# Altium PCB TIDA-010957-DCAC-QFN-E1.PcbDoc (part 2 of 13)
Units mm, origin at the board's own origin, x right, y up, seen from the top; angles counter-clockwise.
Board outline 300 x 300 mm, 4 copper layers (Top Layer, Layer 1, Layer 2, Bottom Layer), stack 1.787 mm thick; 1286 components, 677 nets, 4169 pads, 3428 vias.

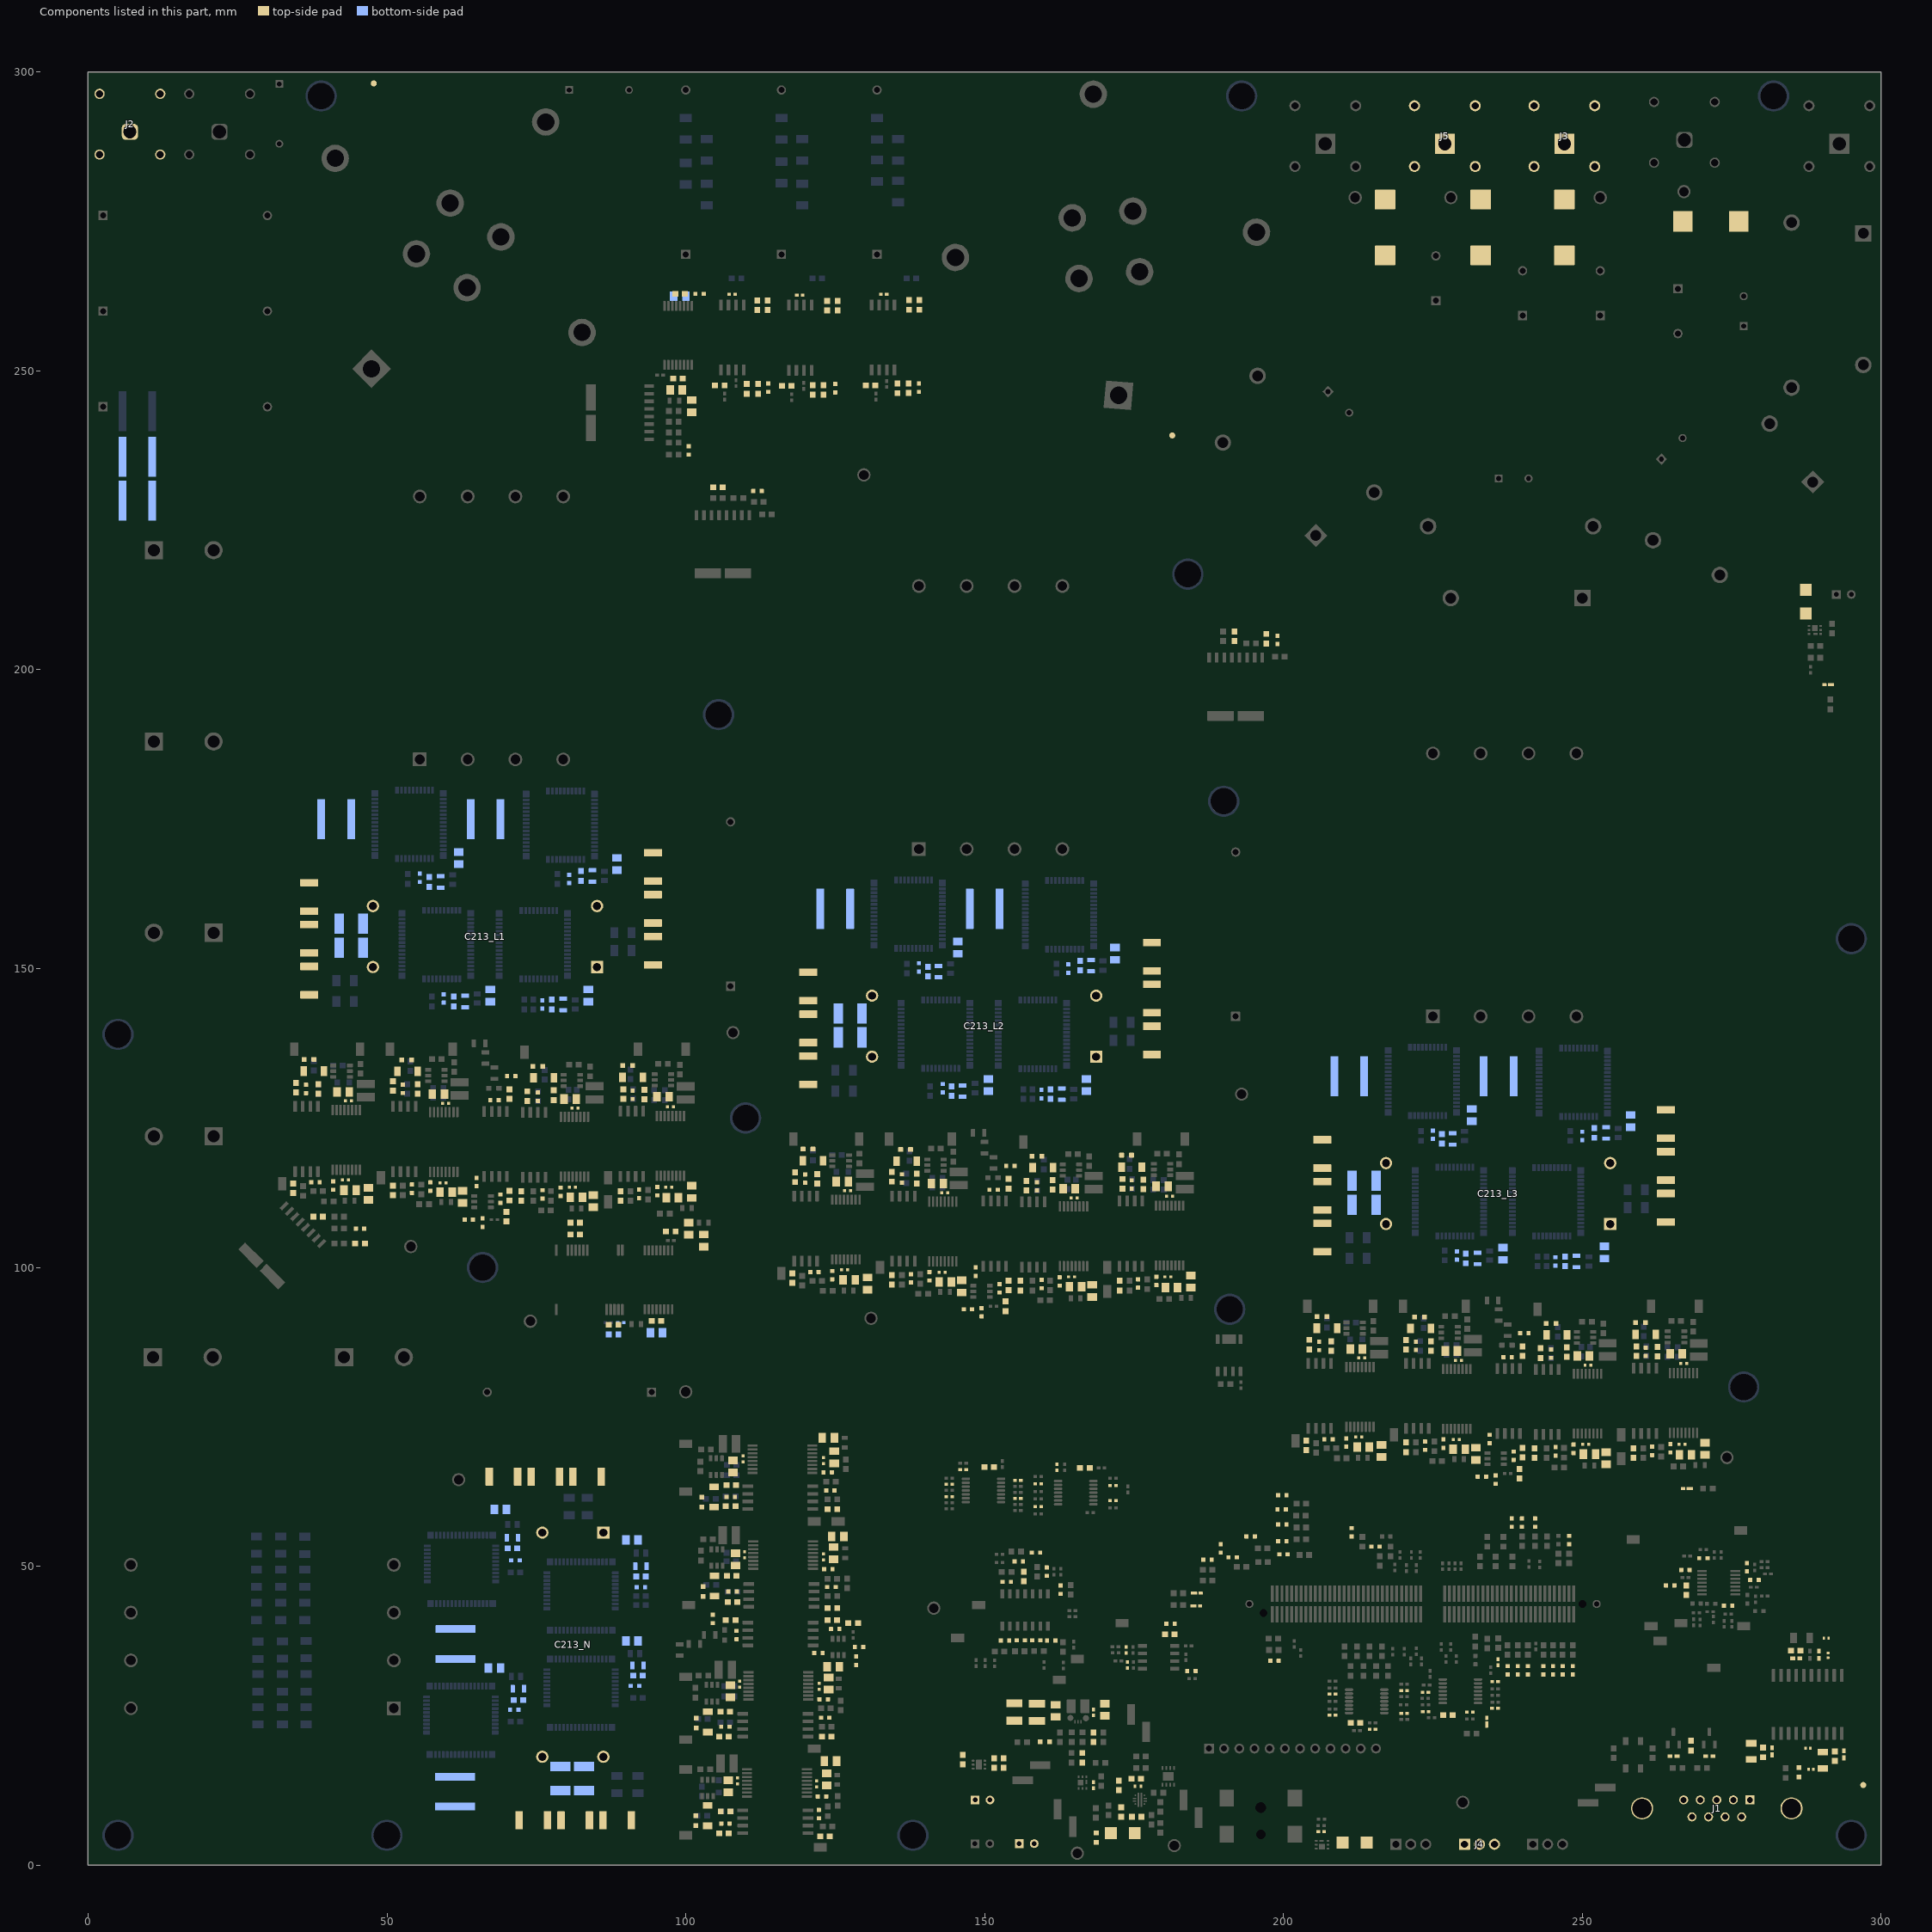
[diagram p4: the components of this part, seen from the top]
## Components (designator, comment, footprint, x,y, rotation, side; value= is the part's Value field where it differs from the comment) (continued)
C37 "CGA3E2C0G1H331J080AA" FP-CGA3E2C0G1H331J080AA_0603-MFG 240.9,32.6 r90 top value=330pF
C38 "CGA3E2C0G1H331J080AA" FP-CGA3E2C0G1H331J080AA_0603-MFG 274.389,43.409 r180 top value=330pF
C39 "CGA3E2C0G1H331J080AA" FP-CGA3E2C0G1H331J080AA_0603-MFG 215.4,53.3 r180 top value=330pF
C40 "06033C104JAT2A" 0603 105.4,230.5 r180 top value=0.1uF
C41 "CGA3E2C0G1H331J080AA" FP-CGA3E2C0G1H331J080AA_0603-MFG 278.8,47.719 r0 top value=330pF
C42 "06033C104JAT2A" 0603 197.1,205.2 r90 top value=0.1uF
C43 "CGA3E2C0G1H331J080AA" FP-CGA3E2C0G1H331J080AA_0603-MFG 247.8,54.4 r270 top value=330pF
C44 "CGA3E2C0G1H331J080AA" FP-CGA3E2C0G1H331J080AA_0603-MFG 277.537,49.85 r270 top value=330pF
C45 "CGA3E2C0G1H331J080AA" FP-CGA3E2C0G1H331J080AA_0603-MFG 211.4,55.7 r90 top value=330pF
C46 "06033C104JAT2A" 0603 191.8,205.6 r90 top value=0.1uF
C47 "06033C104JAT2A" 0603 267.4,46 r90 top value=0.1uF
C48 "CGA3E2C0G1H331J080AA" FP-CGA3E2C0G1H331J080AA_0603-MFG 267.25,49.4 r180 top value=330pF
C49 "06033C104JAT2A" 0603 45.5,104 r0 top value=0.1uF
C50 "CGA3E2C0G1H331J080AA" FP-CGA3E2C0G1H331J080AA_0603-MFG 242.1,57.3 r270 top value=330pF
C51 "CGA3E2C0G1H331J080AA" FP-CGA3E2C0G1H331J080AA_0603-MFG 270.25,51.346 r0 top value=330pF
C52 "CGA3E2C0G1H331J080AA" FP-CGA3E2C0G1H331J080AA_0603-MFG 187.3,51.1 r0 top value=330pF
C53 "06033C104JAT2A" 0603 38.5,108.5 r180 top value=0.1uF
C54 "EMK107BB7225KA-T" 0603 125.4,260.9 r270 top value=2.2uF
C55 "06033C104JAT2A" 0603 123.65,260.9 r90 top value=0.1uF
C56 "06033C104JAT2A" 0603 135.394,247.079 r90 top value=0.1uF
C57 "EMK107BB7225KA-T" 0603 137.3,247.1 r270 top value=2.2uF
C58 "CGA2B2C0G1H102J050BA" 0402L 133.12,262.85 r180 top value=1000pF
C59 "CGA3E2C0G1H331J080AA" FP-CGA3E2C0G1H331J080AA_0603-MFG 243.5,32.6 r90 top value=330pF
C60 "06033C104JAT2A" 0603 130.9,247.6 r180 top value=0.1uF
C61 "EMK107BB7225KA-T" 0603 113.7,261 r270 top value=2.2uF
C62 "06033C104JAT2A" 0603 111.95,261 r90 top value=0.1uF
C63 "06033C104JAT2A" 0603 121.221,246.802 r90 top value=0.1uF
C64 "EMK107BB7225KA-T" 0603 123.02,246.802 r270 top value=2.2uF
C65 "CGA2B2C0G1H102J050BA" 0402L 119.07,262.699 r180 top value=1000pF
C66 "CGA3E2C0G1H331J080AA" FP-CGA3E2C0G1H331J080AA_0603-MFG 238.2,57.3 r270 top value=330pF
C67 "06033C104JAT2A" 0603 116.9,247.5 r180 top value=0.1uF
C68 "EMK107BB7225KA-T" 0603 139.089,261.03 r270 top value=2.2uF
C69 "06033C104JAT2A" 0603 137.339,261.03 r90 top value=0.1uF
C70 "06033C104JAT2A" 0603 110.2,247 r90 top value=0.1uF
C71 "EMK107BB7225KA-T" 0603 112.1,247 r270 top value=2.2uF
C72 "CGA2B2C0G1H102J050BA" 0402L 107.77,262.799 r180 top value=1000pF
C73 "CGA3E2C0G1H331J080AA" FP-CGA3E2C0G1H331J080AA_0603-MFG 239.2,32.6 r90 top value=330pF
C74 "06033C104JAT2A" 0603 105.7,247.6 r180 top value=0.1uF
C75 "GRM21BZ71A226ME15L" 0805_HV 99,262.5 r180 bottom value=22uF
C76 "06033C104JAT2A" 0603 99.058,262.896 r180 top value=0.1uF
C77 "06033C104JAT2A" 0603 98.7,248.7 r0 top value=0.1uF
C78 "GRM21BZ71A226ME15L" 0805_HV 98.4,246.8 r0 top value=22uF
C79 "GRM21BZ71A226ME15L" 0805_HV 101,244.1 r270 top value=22uF
C80 "EMK107BB7225KA-T" 0603 81.5,107.5 r180 top value=2.2uF
C81 "06033C104JAT2A" 0603 81.5,105.5 r0 top value=0.1uF
C82 "06033C104JAT2A" 0603 181,38.6 r180 top value=0.1uF
C83 "CGA2B2C0G1H102J050BA" 0402L 173.9,33.5 r90 top value=1000pF
C84 "CGA3E2C0G1H331J080AA" FP-CGA3E2C0G1H331J080AA_0603-MFG 237.5,32.6 r270 top value=330pF
C85 "GRM155R71H102KA01D" 0402L 89.129,90.768 r180 bottom value=1000pF
C86 "CGA2B2C0G1H102J050BA" 0402L 173.705,36.013 r90 top value=1000pF
C87 "EMK107BB7225KA-T" 0603 87.929,88.798 r0 bottom value=2.2uF
C88 "06033C104JAT2A" 0603 87.929,90.418 r180 top value=0.1uF
C89 "GRM21BZ71A226ME15L" 0805_HV 95.1,89.1 r0 bottom value=22uF
C90 "06033C104JAT2A" 0603 95.113,91.033 r0 top value=0.1uF
C91 "06033C104JAT2A" 0603 97.5,106 r0 top value=0.1uF
C92 "GRM21BZ71A226ME15L" 0805_HV 100.5,106.5 r270 top value=22uF
C93 "GRM21BZ71A226ME15L" 0805_HV 103,104.5 r270 top value=22uF
C94 "06033C104JAT2A" 0603 156.535,48.304 r90 top value=0.1uF
C95 "CGA3E2C0G1H331J080AA" FP-CGA3E2C0G1H331J080AA_0603-MFG 160.384,49.1 r270 top value=330pF
C96 "CGA3E2C0G1H331J080AA" FP-CGA3E2C0G1H331J080AA_0603-MFG 239.9,57.3 r90 top value=330pF
C97 "CGA3E2C0G1H331J080AA" FP-CGA3E2C0G1H331J080AA_0603-MFG 162.703,46.084 r270 top value=330pF
C98 "CGA3E2C0G1H331J080AA" FP-CGA3E2C0G1H331J080AA_0603-MFG 155.716,50.829 r180 top value=330pF
C99 "CGA3E2C0G1H331J080AA" FP-CGA3E2C0G1H331J080AA_0603-MFG 248.4,32.6 r270 top value=330pF
C100 "CGA3E2C0G1H331J080AA" FP-CGA3E2C0G1H331J080AA_0603-MFG 153.699,47.401 r180 top value=330pF
C101 "CGA3E2C0G1H331J080AA" FP-CGA3E2C0G1H331J080AA_0603-MFG 156.06,37.625 r180 top value=330pF
C102 "CGA3E2C0G1H331J080AA" FP-CGA3E2C0G1H331J080AA_0603-MFG 245.1,32.6 r270 top value=330pF
C103 "CGA3E2C0G1H331J080AA" FP-CGA3E2C0G1H331J080AA_0603-MFG 153.404,37.583 r180 top value=330pF
C104 "CGA3E2C0G1H331J080AA" FP-CGA3E2C0G1H331J080AA_0603-MFG 158.641,37.625 r0 top value=330pF
C105 "CGA3E2C0G1H331J080AA" FP-CGA3E2C0G1H331J080AA_0603-MFG 246.7,32.6 r270 top value=330pF
C106 "CGA3E2C0G1H331J080AA" FP-CGA3E2C0G1H331J080AA_0603-MFG 161.145,37.583 r0 top value=330pF
C107 "06033C104JAT2A" 0603 166.768,66.466 r180 top value=0.1uF
C108 "GRM1555C1H101JA01D" 0402L 162.068,66.566 r90 top value=100pF
C109 "GRM1555C1H101JA01D" 0402L 158.968,63.766 r180 top value=100pF
C110 "GRM1555C1H101JA01D" 0402L 158.968,60.016 r180 top value=100pF
C111 "GRM1555C1H101JA01D" 0402L 171.468,61.016 r0 top value=100pF
C112 "GRM1555C1H101JA01D" 0402L 171.468,63.516 r0 top value=100pF
C113 "06033C104JAT2A" 0603 150.763,66.612 r180 top value=0.1uF
C114 "06033C104JAT2A" 0603 212.066,23.781 r0 top value=0.1uF
C115 "GRM1555C1H101JA01D" 0402L 146.411,66.187 r180 top value=100pF
C116 "GRM1555C1H101JA01D" 0402L 144.063,63.712 r180 top value=100pF
C117 "GRM1555C1H101JA01D" 0402L 144.063,61.612 r180 top value=100pF
C118 "GRM1555C1H101JA01D" 0402L 155.563,61.362 r0 top value=100pF
C119 "GRM1555C1H101JA01D" 0402L 155.563,64.362 r0 top value=100pF
C120 "GRM1555C1H101JA01D" 0402L 214.9,22.7 r180 top value=100pF
C121 "GRM1555C1H101JA01D" 0402L 220.2,25.4 r0 top value=100pF
C122 "GRM1555C1H101JA01D" 0402L 220.2,29.2 r0 top value=100pF
C123 "GRM1555C1H101JA01D" 0402L 208.2,28.6 r180 top value=100pF
C124 "GRM1555C1H101JA01D" 0402L 208.2,25.1 r180 top value=100pF
C125 "06033C104JAT2A" 0603 227.5,25.1 r0 top value=0.1uF
C126 "GRM1555C1H101JA01D" 0402L 231.2,25.6 r180 top value=100pF
C127 "GRM1555C1H101JA01D" 0402L 235.393,26.25 r0 top value=100pF
C128 "GRM1555C1H101JA01D" 0402L 235.4,30.7 r0 top value=100pF
C129 "GRM1555C1H101JA01D" 0402L 223.75,28.9 r180 top value=100pF
C130 "GRM1555C1H101JA01D" 0402L 223.8,25.7 r180 top value=100pF
C131 "C1608X7R1V105K080AC" 0603 175.379,14.45 r180 top value=1uF
C132 "GCM155R71H104KE02D" 0402S 175.651,13.186 r180 top value=0.1uF
C133 "C1608X7R1V105K080AC" 0603 175.427,8.094 r180 top value=1uF
C134 "GRM188R72A272KA01D" 0603 172.851,8.9 r270 top value=2700pF
C135 "C0603X332K5RACTU" 0603 172.479,13.325 r90 top value=3300pF
C136 "GRM155R71E104KE14D" 0402L 168.232,13.384 r90 top value=0.1uF
C137 "GRM1885C2A220JA01D" 0603 168.207,21.396 r90 top value=22pF
C138 "06033C104JAT2A" 0603 153.2,17.1 r270 top value=0.1uF
C139 "GRM32ER71A476KE15L" 1210_270 158.733,25.569 r270 top value=47uF
C140 "GRM32ER71A476KE15L" 1210_270 154.983,25.615 r270 top value=47uF
C141 "EMK212BB7106KG-T" 0805_HV 170.133,25.994 r90 top value=10uF
C142 "GCM155R71H104KE02D" 0402L 168.207,25.544 r270 top value=0.1uF
C143 "GRM21BZ71A226ME15L" 0805_HV 161.883,25.819 r270 top value=22uF
C144 "EMK107BB7225KA-T" 0603 151.6,17.1 r270 top value=2.2uF
C145 "EMK107BB7225KA-T" 0603 146.35,17.677 r270 top value=2.2uF
C146 "C0603C103K4RACTU" 0603 166.32,17.971 r90 top value=0.01uF
C147 "GCM188R71C105KA64J" 0603 285.7,35.9 r180 top value=1uF
C148 "GRM155R71H103KA88D" 0402 285.8,34.6 r180 top value=0.01uF
C149 "GRM155R71E104KE14D" 0402 293.75,18.55 r270 top value=0.1uF
C150 "GCM188R71C105KA64J" 0603 292.25,18.25 r270 top value=1uF
C151 "CL31B106KBHNNNE" 1206_180L 290.25,17.55 r270 top value=10uF
C152 "GRM155R71E104KE14D" 0402 289.6,35.2 r90 top value=0.1uF
C153 "GRM155R71H103KA88D" 0402 281.75,19.05 r90 top value=0.01uF
C154 "GCM188R71C105KA64J" 0603 280.243,18.855 r90 top value=1uF
C155 "CL31B106KBHNNNE" 1206_180L 278.25,19.05 r90 top value=10uF
C156 "C1005C0G1H680J050BA" 0402 265.25,18.25 r0 top value=68pF
C157 "C0603X472K5RACTU" 0603 268.2,20 r270 top value=4700pF
C158 "C1005C0G1H680J050BA" 0402 271.25,18.25 r180 top value=68pF
C159 "CGA3E2C0G1H331J080AA" FP-CGA3E2C0G1H331J080AA_0603-MFG 199.8,61.9 r0 top value=330pF
C160 "CGA3E2C0G1H331J080AA" FP-CGA3E2C0G1H331J080AA_0603-MFG 199.7,59.5 r0 top value=330pF
C161 "CGA3E2C0G1H331J080AA" FP-CGA3E2C0G1H331J080AA_0603-MFG 199.8,57 r0 top value=330pF
C162 "CGA3E2C0G1H331J080AA" FP-CGA3E2C0G1H331J080AA_0603-MFG 199.8,54.2 r0 top value=330pF
C163_L1 "GRM21BR61H106ME43L" FP-GRM21BR61H106ME43L_0805-MFG 59,164.5 r90 bottom value=10µF (schematic designator C163)
C163_L2 "GRM21BR61H106ME43L" FP-GRM21BR61H106ME43L_0805-MFG 142.3,149.5 r90 bottom value=10µF (schematic designator C163)
C163_L3 "GRM21BR61H106ME43L" FP-GRM21BR61H106ME43L_0805-MFG 228.3,121.5 r90 bottom value=10µF (schematic designator C163)
C163_N "GRM21BR61H106ME43L" FP-GRM21BR61H106ME43L_0805-MFG 72,29.5 r180 bottom value=10µF (schematic designator C163)
C164_L1 "GRM21BR71E225KA73L" 0805_HV 62,168.5 r270 bottom value=2.2uF (schematic designator C164)
C164_L2 "GRM21BR71E225KA73L" 0805_HV 145.5,153.5 r270 bottom value=2.2uF (schematic designator C164)
C164_L3 "GRM21BR71E225KA73L" 0805_HV 231.5,125.5 r270 bottom value=2.2uF (schematic designator C164)
C164_N "GRM21BR71E225KA73L" 0805_HV 68,33 r0 bottom value=2.2uF (schematic designator C164)
C165_L1 "GRM21BR61H106ME43L" FP-GRM21BR61H106ME43L_0805-MFG 63.1,144.5 r90 bottom value=10µF (schematic designator C165)
C165_L2 "GRM21BR61H106ME43L" FP-GRM21BR61H106ME43L_0805-MFG 146.3,129.5 r90 bottom value=10µF (schematic designator C165)
C165_L3 "GRM21BR61H106ME43L" FP-GRM21BR61H106ME43L_0805-MFG 232.5,101.5 r90 bottom value=10µF (schematic designator C165)
C165_N "GRM21BR61H106ME43L" FP-GRM21BR61H106ME43L_0805-MFG 92,33.4 r180 bottom value=10µF (schematic designator C165)
C166_L1 "GRM21BR71E225KA73L" 0805_HV 67.3,145.5 r270 bottom value=2.2uF (schematic designator C166)
C166_L2 "GRM21BR71E225KA73L" 0805_HV 150.6,130.5 r270 bottom value=2.2uF (schematic designator C166)
C166_L3 "GRM21BR71E225KA73L" 0805_HV 236.7,102.3 r270 bottom value=2.2uF (schematic designator C166)
C166_N "GRM21BR71E225KA73L" 0805_HV 91,37.5 r0 bottom value=2.2uF (schematic designator C166)
C167_L1 "GRM21BR71E225KA73L" 0805_HV 83.7,145.5 r270 bottom value=2.2uF (schematic designator C167)
C167_L2 "GRM21BR71E225KA73L" 0805_HV 167,130.5 r270 bottom value=2.2uF (schematic designator C167)
C167_L3 "GRM21BR71E225KA73L" 0805_HV 253.7,102.5 r270 bottom value=2.2uF (schematic designator C167)
C167_N "GRM21BR71E225KA73L" 0805_HV 91,54.4 r0 bottom value=2.2uF (schematic designator C167)
C168_L1 "06033C104JAT2A" 0603 77.6,144 r270 bottom value=0.1uF (schematic designator C168)
C168_L2 "06033C104JAT2A" 0603 161,129 r270 bottom value=0.1uF (schematic designator C168)
C168_L3 "06033C104JAT2A" 0603 247.1,101 r270 bottom value=0.1uF (schematic designator C168)
C168_N "06033C104JAT2A" 0603 92.5,48.3 r0 bottom value=0.1uF (schematic designator C168)
C169_L1 "GRM21BR61H106ME43L" FP-GRM21BR61H106ME43L_0805-MFG 79.5,144 r90 bottom value=10µF (schematic designator C169)
C169_L2 "GRM21BR61H106ME43L" FP-GRM21BR61H106ME43L_0805-MFG 162.9,129 r90 bottom value=10µF (schematic designator C169)
C169_L3 "GRM21BR61H106ME43L" FP-GRM21BR61H106ME43L_0805-MFG 249,101 r90 bottom value=10µF (schematic designator C169)
C169_N "GRM21BR61H106ME43L" FP-GRM21BR61H106ME43L_0805-MFG 92.5,50 r180 bottom value=10µF (schematic designator C169)
C170_L1 "GRM21BR71E225KA73L" 0805_HV 88.5,167.5 r270 bottom value=2.2uF (schematic designator C170)
C170_L2 "GRM21BR71E225KA73L" 0805_HV 171.8,152.5 r270 bottom value=2.2uF (schematic designator C170)
C170_L3 "GRM21BR71E225KA73L" 0805_HV 258.1,124.5 r270 bottom value=2.2uF (schematic designator C170)
C170_N "GRM21BR71E225KA73L" 0805_HV 69,59.5 r0 bottom value=2.2uF (schematic designator C170)
C171_L1 "GRM21BR61H106ME43L" FP-GRM21BR61H106ME43L_0805-MFG 84.4,165.5 r90 bottom value=10µF (schematic designator C171)
C171_L2 "GRM21BR61H106ME43L" FP-GRM21BR61H106ME43L_0805-MFG 167.8,150.5 r90 bottom value=10µF (schematic designator C171)
C171_L3 "GRM21BR61H106ME43L" FP-GRM21BR61H106ME43L_0805-MFG 254,122.5 r90 bottom value=10µF (schematic designator C171)
C171_N "GRM21BR61H106ME43L" FP-GRM21BR61H106ME43L_0805-MFG 71,54.8 r180 bottom value=10µF (schematic designator C171)
C172_L1 "C1812X104KBRACTU" 1812_254 44,157.5 r180 bottom value=0.1uF (schematic designator C172)
C172_L2 "C1812X104KBRACTU" 1812_254 127.5,142.5 r180 bottom value=0.1uF (schematic designator C172)
C172_L3 "C1812X104KBRACTU" 1812_254 213.5,114.5 r180 bottom value=0.1uF (schematic designator C172)
C172_N "C1812X104KBRACTU" 1812_254 79,14.5 r270 bottom value=0.1uF (schematic designator C172)
C173 "CGA3E2C0G1H331J080AA" FP-CGA3E2C0G1H331J080AA_0603-MFG 194.5,55 r0 top value=330pF
C174 "CGA3E2C0G1H331J080AA" FP-CGA3E2C0G1H331J080AA_0603-MFG 200,52 r0 top value=330pF
C175 "CGA3E2C0G1H331J080AA" FP-CGA3E2C0G1H331J080AA_0603-MFG 191.5,51.5 r0 top value=330pF
C176 "CGA3E2C0G1H331J080AA" FP-CGA3E2C0G1H331J080AA_0603-MFG 189.5,53 r270 top value=330pF
C186_L1 "06033C104JAT2A" 0603 34.325,113.23 r270 top value=0.1uF (schematic designator C186)
C186_L2 "06033C104JAT2A" 0603 117.825,98.23 r270 top value=0.1uF (schematic designator C186)
C186_L3 "06033C104JAT2A" 0603 203.825,70.23 r270 top value=0.1uF (schematic designator C186)
C186_N "06033C104JAT2A" 0603 123.27,4.825 r0 top value=0.1uF (schematic designator C186)
C187_L1 "06033C104JAT2A" 0603 34.8,130.094 r90 top value=0.1uF (schematic designator C187)
C187_L2 "06033C104JAT2A" 0603 118.3,115.094 r90 top value=0.1uF (schematic designator C187)
C187_L3 "06033C104JAT2A" 0603 204.3,87.094 r90 top value=0.1uF (schematic designator C187)
C187_N "06033C104JAT2A" 0603 106.406,5.3 r180 top value=0.1uF (schematic designator C187)
C188_L1 "CGA3E2C0G1H331J080AA" FP-CGA3E2C0G1H331J080AA_0603-MFG 55.5,165.2 r90 bottom value=330pF (schematic designator C188)
C188_L2 "CGA3E2C0G1H331J080AA" FP-CGA3E2C0G1H331J080AA_0603-MFG 139,150.2 r90 bottom value=330pF (schematic designator C188)
C188_L3 "CGA3E2C0G1H331J080AA" FP-CGA3E2C0G1H331J080AA_0603-MFG 225,122.2 r90 bottom value=330pF (schematic designator C188)
C188_N "CGA3E2C0G1H331J080AA" FP-CGA3E2C0G1H331J080AA_0603-MFG 71.3,26 r180 bottom value=330pF (schematic designator C188)
C189_L1 "CGA3E2C0G1H331J080AA" FP-CGA3E2C0G1H331J080AA_0603-MFG 36.467,129.866 r270 top value=330pF (schematic designator C189)
C189_L2 "CGA3E2C0G1H331J080AA" FP-CGA3E2C0G1H331J080AA_0603-MFG 119.967,114.866 r270 top value=330pF (schematic designator C189)
C189_L3 "CGA3E2C0G1H331J080AA" FP-CGA3E2C0G1H331J080AA_0603-MFG 205.967,86.866 r270 top value=330pF (schematic designator C189)
C189_N "CGA3E2C0G1H331J080AA" FP-CGA3E2C0G1H331J080AA_0603-MFG 106.634,6.967 r0 top value=330pF (schematic designator C189)
C190_L1 "06033C104JAT2A" 0603 57.1,164.5 r270 bottom value=0.1uF (schematic designator C190)
C190_L2 "06033C104JAT2A" 0603 140.5,149.5 r270 bottom value=0.1uF (schematic designator C190)
C190_L3 "06033C104JAT2A" 0603 226.5,121.5 r270 bottom value=0.1uF (schematic designator C190)
C190_N "06033C104JAT2A" 0603 72,27.6 r0 bottom value=0.1uF (schematic designator C190)
C191_L1 "CGA3E2C0G1H331J080AA" FP-CGA3E2C0G1H331J080AA_0603-MFG 38.038,114.238 r180 top value=330pF (schematic designator C191)
C191_L2 "CGA3E2C0G1H331J080AA" FP-CGA3E2C0G1H331J080AA_0603-MFG 121.538,99.238 r180 top value=330pF (schematic designator C191)
C191_L3 "CGA3E2C0G1H331J080AA" FP-CGA3E2C0G1H331J080AA_0603-MFG 207.538,71.238 r180 top value=330pF (schematic designator C191)
C191_N "CGA3E2C0G1H331J080AA" FP-CGA3E2C0G1H331J080AA_0603-MFG 122.262,8.538 r270 top value=330pF (schematic designator C191)
C192_L1 "GRT31CR61H106KE01L" 1206_180 37.775,132.845 r180 top value=10uF (schematic designator C192)
C192_L2 "GRT31CR61H106KE01L" 1206_180 121.275,117.845 r180 top value=10uF (schematic designator C192)
C192_L3 "GRT31CR61H106KE01L" 1206_180 207.275,89.845 r180 top value=10uF (schematic designator C192)
C192_N "GRT31CR61H106KE01L" 1206_180 103.655,8.275 r270 top value=10uF (schematic designator C192)
C193_L1 "885012205063" WCAP-CSGP_0402_L1W0.5H0.5 43.588,127.867 r0 top (schematic designator C193)
C193_L2 "885012205063" WCAP-CSGP_0402_L1W0.5H0.5 127.088,112.867 r0 top (schematic designator C193)
C193_L3 "885012205063" WCAP-CSGP_0402_L1W0.5H0.5 213.088,84.867 r0 top (schematic designator C193)
C193_N "885012205063" WCAP-CSGP_0402_L1W0.5H0.5 108.633,14.088 r90 top (schematic designator C193)
C194_L1 "GRM21BZ71A226ME15L" 0805_HV 42.688,129.369 r180 top value=22uF (schematic designator C194)
C194_L2 "GRM21BZ71A226ME15L" 0805_HV 126.188,114.369 r180 top value=22uF (schematic designator C194)
C194_L3 "GRM21BZ71A226ME15L" 0805_HV 212.188,86.369 r180 top value=22uF (schematic designator C194)
C194_N "GRM21BZ71A226ME15L" 0805_HV 107.131,13.188 r270 top value=22uF (schematic designator C194)
C195_L1 "06033C104JAT2A" 0603 38.5,129.848 r270 top value=0.1uF (schematic designator C195)
C195_L2 "06033C104JAT2A" 0603 122,114.848 r270 top value=0.1uF (schematic designator C195)
C195_L3 "06033C104JAT2A" 0603 208,86.848 r270 top value=0.1uF (schematic designator C195)
C195_N "06033C104JAT2A" 0603 106.652,9 r0 top value=0.1uF (schematic designator C195)
C196_L1 "CGA3E2C0G1H331J080AA" FP-CGA3E2C0G1H331J080AA_0603-MFG 40.997,113.705 r90 top value=330pF (schematic designator C196)
C196_L2 "CGA3E2C0G1H331J080AA" FP-CGA3E2C0G1H331J080AA_0603-MFG 124.497,98.705 r90 top value=330pF (schematic designator C196)
C196_L3 "CGA3E2C0G1H331J080AA" FP-CGA3E2C0G1H331J080AA_0603-MFG 210.497,70.705 r90 top value=330pF (schematic designator C196)
C196_N "CGA3E2C0G1H331J080AA" FP-CGA3E2C0G1H331J080AA_0603-MFG 122.795,11.497 r180 top value=330pF (schematic designator C196)
C197_L1 "GRM21BZ71A226ME15L" 0805_HV 46.9,112.3 r90 top value=22uF (schematic designator C197)
C197_L2 "GRM21BZ71A226ME15L" 0805_HV 130.4,97.3 r90 top value=22uF (schematic designator C197)
C197_L3 "GRM21BZ71A226ME15L" 0805_HV 216.4,69.3 r90 top value=22uF (schematic designator C197)
C197_N "GRM21BZ71A226ME15L" 0805_HV 124.2,17.4 r180 top value=22uF (schematic designator C197)
C198_L1 "GRM21BZ71A226ME15L" 0805_HV 43.838,112.93 r0 top value=22uF (schematic designator C198)
C198_L2 "GRM21BZ71A226ME15L" 0805_HV 127.338,97.93 r0 top value=22uF (schematic designator C198)
C198_L3 "GRM21BZ71A226ME15L" 0805_HV 213.338,69.93 r0 top value=22uF (schematic designator C198)
C198_N "GRM21BZ71A226ME15L" 0805_HV 123.57,14.338 r90 top value=22uF (schematic designator C198)
C199_L1 "885012205051" WCAP-CSGP_0402_L1W0.5H0.5 43.088,114.63 r180 top (schematic designator C199)
C199_L2 "885012205051" WCAP-CSGP_0402_L1W0.5H0.5 126.588,99.63 r180 top (schematic designator C199)
C199_L3 "885012205051" WCAP-CSGP_0402_L1W0.5H0.5 212.588,71.63 r180 top (schematic designator C199)
C199_N "885012205051" WCAP-CSGP_0402_L1W0.5H0.5 121.87,13.588 r270 top (schematic designator C199)
C200_L1 "06033C104JAT2A" 0603 51.005,112.908 r270 top value=0.1uF (schematic designator C200)
C200_L2 "06033C104JAT2A" 0603 134.505,97.908 r270 top value=0.1uF (schematic designator C200)
C200_L3 "06033C104JAT2A" 0603 220.505,69.908 r270 top value=0.1uF (schematic designator C200)
C200_N "06033C104JAT2A" 0603 123.592,21.505 r0 top value=0.1uF (schematic designator C200)
C201_L1 "06033C104JAT2A" 0603 51.005,130.366 r90 top value=0.1uF (schematic designator C201)
C201_L2 "06033C104JAT2A" 0603 134.505,115.166 r90 top value=0.1uF (schematic designator C201)
C201_L3 "06033C104JAT2A" 0603 220.505,87.066 r90 top value=0.1uF (schematic designator C201)
C201_N "06033C104JAT2A" 0603 106.4,21.5 r180 top value=0.1uF (schematic designator C201)
C202_L1 "CGA3E2C0G1H331J080AA" FP-CGA3E2C0G1H331J080AA_0603-MFG 59.5,145 r90 bottom value=330pF (schematic designator C202)
C202_L2 "CGA3E2C0G1H331J080AA" FP-CGA3E2C0G1H331J080AA_0603-MFG 143,130 r90 bottom value=330pF (schematic designator C202)
C202_L3 "CGA3E2C0G1H331J080AA" FP-CGA3E2C0G1H331J080AA_0603-MFG 229,102 r90 bottom value=330pF (schematic designator C202)
C202_N "CGA3E2C0G1H331J080AA" FP-CGA3E2C0G1H331J080AA_0603-MFG 91.5,30 r180 bottom value=330pF (schematic designator C202)
C203_L1 "CGA3E2C0G1H331J080AA" FP-CGA3E2C0G1H331J080AA_0603-MFG 52.66,129.882 r270 top value=330pF (schematic designator C203)
C203_L2 "CGA3E2C0G1H331J080AA" FP-CGA3E2C0G1H331J080AA_0603-MFG 136.16,114.882 r270 top value=330pF (schematic designator C203)
C203_L3 "CGA3E2C0G1H331J080AA" FP-CGA3E2C0G1H331J080AA_0603-MFG 222.16,86.882 r270 top value=330pF (schematic designator C203)
C203_N "CGA3E2C0G1H331J080AA" FP-CGA3E2C0G1H331J080AA_0603-MFG 106.618,23.16 r0 top value=330pF (schematic designator C203)
C204_L1 "06033C104JAT2A" 0603 61.2,144.5 r270 bottom value=0.1uF (schematic designator C204)
C204_L2 "06033C104JAT2A" 0603 144.5,129.5 r270 bottom value=0.1uF (schematic designator C204)
C204_L3 "06033C104JAT2A" 0603 230.5,101.5 r270 bottom value=0.1uF (schematic designator C204)
C204_N "06033C104JAT2A" 0603 92,31.7 r0 bottom value=0.1uF (schematic designator C204)
C205_L1 "CGA3E2C0G1H331J080AA" FP-CGA3E2C0G1H331J080AA_0603-MFG 54.18,113.18 r90 top value=330pF (schematic designator C205)
C205_L2 "CGA3E2C0G1H331J080AA" FP-CGA3E2C0G1H331J080AA_0603-MFG 137.68,98.18 r90 top value=330pF (schematic designator C205)
C205_L3 "CGA3E2C0G1H331J080AA" FP-CGA3E2C0G1H331J080AA_0603-MFG 223.68,70.18 r90 top value=330pF (schematic designator C205)
C205_N "CGA3E2C0G1H331J080AA" FP-CGA3E2C0G1H331J080AA_0603-MFG 123.32,24.68 r180 top value=330pF (schematic designator C205)
C206_L1 "CGA3E2C0G1H331J080AA" FP-CGA3E2C0G1H331J080AA_0603-MFG 66,107.5 r90 top value=330pF (schematic designator C206)
C206_L2 "CGA3E2C0G1H331J080AA" FP-CGA3E2C0G1H331J080AA_0603-MFG 149.5,92.5 r90 top value=330pF (schematic designator C206)
C206_L3 "CGA3E2C0G1H331J080AA" FP-CGA3E2C0G1H331J080AA_0603-MFG 235.5,64.5 r90 top value=330pF (schematic designator C206)
C206_N "CGA3E2C0G1H331J080AA" FP-CGA3E2C0G1H331J080AA_0603-MFG 129,36.5 r180 top value=330pF (schematic designator C206)
C207_L1 "CGA3E2C0G1H331J080AA" FP-CGA3E2C0G1H331J080AA_0603-MFG 63.7,108 r0 top value=330pF (schematic designator C207)
C207_L2 "CGA3E2C0G1H331J080AA" FP-CGA3E2C0G1H331J080AA_0603-MFG 147.2,93 r0 top value=330pF (schematic designator C207)
C207_L3 "CGA3E2C0G1H331J080AA" FP-CGA3E2C0G1H331J080AA_0603-MFG 233.2,65 r0 top value=330pF (schematic designator C207)
C207_N "CGA3E2C0G1H331J080AA" FP-CGA3E2C0G1H331J080AA_0603-MFG 128.5,34.2 r90 top value=330pF (schematic designator C207)
C208_L1 "GRT31CR61H106KE01L" 1206_180 53.455,132.8 r180 top value=10uF (schematic designator C208)
C208_L2 "GRT31CR61H106KE01L" 1206_180 136.955,117.8 r180 top value=10uF (schematic designator C208)
C208_L3 "GRT31CR61H106KE01L" 1206_180 222.955,89.8 r180 top value=10uF (schematic designator C208)
C208_N "GRT31CR61H106KE01L" 1206_180 103.7,23.955 r270 top value=10uF (schematic designator C208)
C209_L1 "CGA3E2C0G1H331J080AA" FP-CGA3E2C0G1H331J080AA_0603-MFG 65,114.3 r270 top value=330pF (schematic designator C209)
C209_L2 "CGA3E2C0G1H331J080AA" FP-CGA3E2C0G1H331J080AA_0603-MFG 148.5,99.3 r270 top value=330pF (schematic designator C209)
C209_L3 "CGA3E2C0G1H331J080AA" FP-CGA3E2C0G1H331J080AA_0603-MFG 234.5,71.3 r270 top value=330pF (schematic designator C209)
C209_N "CGA3E2C0G1H331J080AA" FP-CGA3E2C0G1H331J080AA_0603-MFG 122.2,35.5 r0 top value=330pF (schematic designator C209)
C210_L1 "885012205063" WCAP-CSGP_0402_L1W0.5H0.5 59.794,127.467 r0 top (schematic designator C210)
C210_L2 "885012205063" WCAP-CSGP_0402_L1W0.5H0.5 143.294,112.467 r0 top (schematic designator C210)
C210_L3 "885012205063" WCAP-CSGP_0402_L1W0.5H0.5 229.294,84.467 r0 top (schematic designator C210)
C210_N "885012205063" WCAP-CSGP_0402_L1W0.5H0.5 109.033,30.294 r90 top (schematic designator C210)
C211_L1 "GRM21BZ71A226ME15L" 0805_HV 58.6,129.023 r180 top value=22uF (schematic designator C211)
C211_L2 "GRM21BZ71A226ME15L" 0805_HV 142.1,114.023 r180 top value=22uF (schematic designator C211)
C211_L3 "GRM21BZ71A226ME15L" 0805_HV 228.1,86.023 r180 top value=22uF (schematic designator C211)
C211_N "GRM21BZ71A226ME15L" 0805_HV 107.477,29.1 r270 top value=22uF (schematic designator C211)
C212_L1 "06033C104JAT2A" 0603 55.155,129.871 r270 top value=0.1uF (schematic designator C212)
C212_L2 "06033C104JAT2A" 0603 138.655,114.871 r270 top value=0.1uF (schematic designator C212)
C212_L3 "06033C104JAT2A" 0603 224.655,86.871 r270 top value=0.1uF (schematic designator C212)
C212_N "06033C104JAT2A" 0603 106.629,25.655 r0 top value=0.1uF (schematic designator C212)
C213_L1 "B32676G6126K000" FP-B32676G6126K000_RADIAL-MFG 66.411,155.366 r180 top value=12µF (schematic designator C213)
C213_L2 "B32676G6126K000" FP-B32676G6126K000_RADIAL-MFG 149.911,140.366 r180 top value=12µF (schematic designator C213)
C213_L3 "B32676G6126K000" FP-B32676G6126K000_RADIAL-MFG 235.911,112.366 r180 top value=12µF (schematic designator C213)
C213_N "B32676G6126K000" FP-B32676G6126K000_RADIAL-MFG 81.109,36.886 r270 top locked value=12µF (schematic designator C213)
C215_L1 "C1812X104KBRACTU" 1812_254 44,153.5 r180 bottom value=0.1uF (schematic designator C215)
C215_L2 "C1812X104KBRACTU" 1812_254 127.5,138.5 r180 bottom value=0.1uF (schematic designator C215)
C215_L3 "C1812X104KBRACTU" 1812_254 213.5,110.5 r180 bottom value=0.1uF (schematic designator C215)
C215_N "C1812X104KBRACTU" 1812_254 83,14.5 r270 bottom value=0.1uF (schematic designator C215)
C216_L1 "C2225C224KBRACTU" FP-C2225C224KBRACTU_2225-MFG 66.5,175 r0 bottom value=220nF (schematic designator C216)
C216_L2 "C2225C224KBRACTU" FP-C2225C224KBRACTU_2225-MFG 150,160 r0 bottom value=220nF (schematic designator C216)
C216_L3 "C2225C224KBRACTU" FP-C2225C224KBRACTU_2225-MFG 236,132 r0 bottom value=220nF (schematic designator C216)
C216_N "C2225C224KBRACTU" FP-C2225C224KBRACTU_2225-MFG 61.5,37 r90 bottom value=220nF (schematic designator C216)
C217_L1 "C2225C563KFRACTU" FP-C2225C563KFRACTU_2225-MFG 41.5,175 r0 bottom value=56nF (schematic designator C217)
C217_L2 "C2225C563KFRACTU" FP-C2225C563KFRACTU_2225-MFG 125,160 r0 bottom value=56nF (schematic designator C217)
C217_L3 "C2225C563KFRACTU" FP-C2225C563KFRACTU_2225-MFG 211,132 r0 bottom value=56nF (schematic designator C217)
C217_N "C2225C563KFRACTU" FP-C2225C563KFRACTU_2225-MFG 61.4,12.3 r90 bottom value=56nF (schematic designator C217)
C219_L1 "CGA3E2C0G1H331J080AA" FP-CGA3E2C0G1H331J080AA_0603-MFG 57.25,113.53 r90 top value=330pF (schematic designator C219)
C219_L2 "CGA3E2C0G1H331J080AA" FP-CGA3E2C0G1H331J080AA_0603-MFG 140.75,98.53 r90 top value=330pF (schematic designator C219)
C219_L3 "CGA3E2C0G1H331J080AA" FP-CGA3E2C0G1H331J080AA_0603-MFG 226.75,70.53 r90 top value=330pF (schematic designator C219)
C219_N "CGA3E2C0G1H331J080AA" FP-CGA3E2C0G1H331J080AA_0603-MFG 123.07,27.75 r180 top value=330pF (schematic designator C219)
C220_L1 "GRM21BZ71A226ME15L" 0805_HV 62.675,111.817 r90 top value=22uF (schematic designator C220)
C220_L2 "GRM21BZ71A226ME15L" 0805_HV 146.175,96.817 r90 top value=22uF (schematic designator C220)
C220_L3 "GRM21BZ71A226ME15L" 0805_HV 232.175,68.817 r90 top value=22uF (schematic designator C220)
C220_N "GRM21BZ71A226ME15L" 0805_HV 124.683,33.175 r180 top value=22uF (schematic designator C220)
C221_L1 "GRM21BZ71A226ME15L" 0805_HV 59.9,112.588 r0 top value=22uF (schematic designator C221)
C221_L2 "GRM21BZ71A226ME15L" 0805_HV 143.4,97.588 r0 top value=22uF (schematic designator C221)
C221_L3 "GRM21BZ71A226ME15L" 0805_HV 229.4,69.588 r0 top value=22uF (schematic designator C221)
C221_N "GRM21BZ71A226ME15L" 0805_HV 123.912,30.4 r90 top value=22uF (schematic designator C221)
C222_L1 "885012205051" WCAP-CSGP_0402_L1W0.5H0.5 59.394,114.182 r180 top (schematic designator C222)
C222_L2 "885012205051" WCAP-CSGP_0402_L1W0.5H0.5 142.894,99.182 r180 top (schematic designator C222)
C222_L3 "885012205051" WCAP-CSGP_0402_L1W0.5H0.5 228.894,71.182 r180 top (schematic designator C222)
C222_N "885012205051" WCAP-CSGP_0402_L1W0.5H0.5 122.318,29.894 r270 top (schematic designator C222)
C223_L1 "06033C104JAT2A" 0603 70,108.5 r270 top value=0.1uF (schematic designator C223)
C223_L2 "06033C104JAT2A" 0603 153.5,93.5 r270 top value=0.1uF (schematic designator C223)
C223_L3 "06033C104JAT2A" 0603 239.5,65.5 r270 top value=0.1uF (schematic designator C223)
C223_N "06033C104JAT2A" 0603 128,40.5 r0 top value=0.1uF (schematic designator C223)
C224_L1 "06033C104JAT2A" 0603 72.5,111.955 r270 top value=0.1uF (schematic designator C224)
C224_L2 "06033C104JAT2A" 0603 156,96.955 r270 top value=0.1uF (schematic designator C224)
C224_L3 "06033C104JAT2A" 0603 242,68.955 r270 top value=0.1uF (schematic designator C224)
C224_N "06033C104JAT2A" 0603 124.545,43 r0 top value=0.1uF (schematic designator C224)
C225_L1 "06033C104JAT2A" 0603 73.508,128.666 r90 top value=0.1uF (schematic designator C225)
C225_L2 "06033C104JAT2A" 0603 157.008,113.666 r90 top value=0.1uF (schematic designator C225)
C225_L3 "06033C104JAT2A" 0603 243.008,85.666 r90 top value=0.1uF (schematic designator C225)
C225_N "06033C104JAT2A" 0603 107.834,44.008 r180 top value=0.1uF (schematic designator C225)
C226_L1 "CGA3E2C0G1H331J080AA" FP-CGA3E2C0G1H331J080AA_0603-MFG 76,144 r90 bottom value=330pF (schematic designator C226)
C226_L2 "CGA3E2C0G1H331J080AA" FP-CGA3E2C0G1H331J080AA_0603-MFG 159.5,129 r90 bottom value=330pF (schematic designator C226)
C226_L3 "CGA3E2C0G1H331J080AA" FP-CGA3E2C0G1H331J080AA_0603-MFG 245.5,101 r90 bottom value=330pF (schematic designator C226)
C226_N "CGA3E2C0G1H331J080AA" FP-CGA3E2C0G1H331J080AA_0603-MFG 92.5,46.5 r180 bottom value=330pF (schematic designator C226)
C227_L1 "CGA3E2C0G1H331J080AA" FP-CGA3E2C0G1H331J080AA_0603-MFG 75.264,128.566 r270 top value=330pF (schematic designator C227)
C227_L2 "CGA3E2C0G1H331J080AA" FP-CGA3E2C0G1H331J080AA_0603-MFG 158.764,113.566 r270 top value=330pF (schematic designator C227)
C227_L3 "CGA3E2C0G1H331J080AA" FP-CGA3E2C0G1H331J080AA_0603-MFG 244.764,85.566 r270 top value=330pF (schematic designator C227)
C227_N "CGA3E2C0G1H331J080AA" FP-CGA3E2C0G1H331J080AA_0603-MFG 107.834,45.764 r0 top value=330pF (schematic designator C227)
C231_L1 "CGA3E2C0G1H331J080AA" FP-CGA3E2C0G1H331J080AA_0603-MFG 76.028,112.234 r90 top value=330pF (schematic designator C231)
C231_L2 "CGA3E2C0G1H331J080AA" FP-CGA3E2C0G1H331J080AA_0603-MFG 159.528,97.234 r90 top value=330pF (schematic designator C231)
C231_L3 "CGA3E2C0G1H331J080AA" FP-CGA3E2C0G1H331J080AA_0603-MFG 245.528,69.234 r90 top value=330pF (schematic designator C231)
C231_N "CGA3E2C0G1H331J080AA" FP-CGA3E2C0G1H331J080AA_0603-MFG 124.366,46.528 r180 top value=330pF (schematic designator C231)
C232_L1 "GRT31CR61H106KE01L" 1206_180 76.229,131.708 r180 top value=10uF (schematic designator C232)
C232_L2 "GRT31CR61H106KE01L" 1206_180 159.729,116.708 r180 top value=10uF (schematic designator C232)
C232_L3 "GRT31CR61H106KE01L" 1206_180 245.729,88.708 r180 top value=10uF (schematic designator C232)
C232_N "GRT31CR61H106KE01L" 1206_180 104.792,46.729 r270 top value=10uF (schematic designator C232)
C233_L1 "885012205063" WCAP-CSGP_0402_L1W0.5H0.5 81.458,126.657 r0 top (schematic designator C233)
C233_L2 "885012205063" WCAP-CSGP_0402_L1W0.5H0.5 164.958,111.657 r0 top (schematic designator C233)
C233_L3 "885012205063" WCAP-CSGP_0402_L1W0.5H0.5 250.958,83.657 r0 top (schematic designator C233)
C233_N "885012205063" WCAP-CSGP_0402_L1W0.5H0.5 109.843,51.958 r90 top (schematic designator C233)
C234_L1 "GRM21BZ71A226ME15L" 0805_HV 80.658,128.182 r180 top value=22uF (schematic designator C234)
C234_L2 "GRM21BZ71A226ME15L" 0805_HV 164.158,113.182 r180 top value=22uF (schematic designator C234)
C234_L3 "GRM21BZ71A226ME15L" 0805_HV 250.158,85.182 r180 top value=22uF (schematic designator C234)
C234_N "GRM21BZ71A226ME15L" 0805_HV 108.318,51.158 r270 top value=22uF (schematic designator C234)
C235_L1 "06033C104JAT2A" 0603 77.904,128.823 r270 top value=0.1uF (schematic designator C235)
C235_L2 "06033C104JAT2A" 0603 161.404,113.823 r270 top value=0.1uF (schematic designator C235)
C235_L3 "06033C104JAT2A" 0603 247.404,85.823 r270 top value=0.1uF (schematic designator C235)
C235_N "06033C104JAT2A" 0603 107.677,48.404 r0 top value=0.1uF (schematic designator C235)
C236_L1 "CGA3E2C0G1H331J080AA" FP-CGA3E2C0G1H331J080AA_0603-MFG 79.041,112.655 r90 top value=330pF (schematic designator C236)
C236_L2 "CGA3E2C0G1H331J080AA" FP-CGA3E2C0G1H331J080AA_0603-MFG 162.541,97.655 r90 top value=330pF (schematic designator C236)
C236_L3 "CGA3E2C0G1H331J080AA" FP-CGA3E2C0G1H331J080AA_0603-MFG 248.541,69.655 r90 top value=330pF (schematic designator C236)
C236_N "CGA3E2C0G1H331J080AA" FP-CGA3E2C0G1H331J080AA_0603-MFG 123.845,49.541 r180 top value=330pF (schematic designator C236)
C237_L1 "GRM21BZ71A226ME15L" 0805_HV 84.5,111.08 r90 top value=22uF (schematic designator C237)
C237_L2 "GRM21BZ71A226ME15L" 0805_HV 168,96.08 r90 top value=22uF (schematic designator C237)
C237_L3 "GRM21BZ71A226ME15L" 0805_HV 254,68.08 r90 top value=22uF (schematic designator C237)
C237_N "GRM21BZ71A226ME15L" 0805_HV 125.42,55 r180 top value=22uF (schematic designator C237)
C238_L1 "GRM21BZ71A226ME15L" 0805_HV 81.698,111.755 r0 top value=22uF (schematic designator C238)
C238_L2 "GRM21BZ71A226ME15L" 0805_HV 165.198,96.755 r0 top value=22uF (schematic designator C238)
C238_L3 "GRM21BZ71A226ME15L" 0805_HV 251.198,68.755 r0 top value=22uF (schematic designator C238)
C238_N "GRM21BZ71A226ME15L" 0805_HV 124.745,52.198 r90 top value=22uF (schematic designator C238)
C239_L1 "885012205051" WCAP-CSGP_0402_L1W0.5H0.5 81.06,113.432 r180 top (schematic designator C239)
C239_L2 "885012205051" WCAP-CSGP_0402_L1W0.5H0.5 164.56,98.432 r180 top (schematic designator C239)
C239_L3 "885012205051" WCAP-CSGP_0402_L1W0.5H0.5 250.56,70.432 r180 top (schematic designator C239)
C239_N "885012205051" WCAP-CSGP_0402_L1W0.5H0.5 123.068,51.56 r270 top (schematic designator C239)
C240_L1 "06033C104JAT2A" 0603 70.5,112 r270 top value=0.1uF (schematic designator C240)
C240_L2 "06033C104JAT2A" 0603 154,97 r270 top value=0.1uF (schematic designator C240)
C240_L3 "06033C104JAT2A" 0603 240,69 r270 top value=0.1uF (schematic designator C240)
C240_N "06033C104JAT2A" 0603 124.5,41 r0 top value=0.1uF (schematic designator C240)
C241_L1 "06033C104JAT2A" 0603 70.5,129 r90 top value=0.1uF (schematic designator C241)
C241_L2 "06033C104JAT2A" 0603 154,114 r90 top value=0.1uF (schematic designator C241)
C241_L3 "06033C104JAT2A" 0603 240,86 r90 top value=0.1uF (schematic designator C241)
C241_N "06033C104JAT2A" 0603 107.5,41 r180 top value=0.1uF (schematic designator C241)
C242_L1 "CGA3E2C0G1H331J080AA" FP-CGA3E2C0G1H331J080AA_0603-MFG 68,128 r0 top value=330pF (schematic designator C242)
C242_L2 "CGA3E2C0G1H331J080AA" FP-CGA3E2C0G1H331J080AA_0603-MFG 151.5,113 r0 top value=330pF (schematic designator C242)
C242_L3 "CGA3E2C0G1H331J080AA" FP-CGA3E2C0G1H331J080AA_0603-MFG 237.5,85 r0 top value=330pF (schematic designator C242)
C242_N "CGA3E2C0G1H331J080AA" FP-CGA3E2C0G1H331J080AA_0603-MFG 108.5,38.5 r90 top value=330pF (schematic designator C242)
C243_L1 "06033C104JAT2A" 0603 89.073,111.955 r270 top value=0.1uF (schematic designator C243)
C243_L2 "06033C104JAT2A" 0603 172.573,96.955 r270 top value=0.1uF (schematic designator C243)
C243_L3 "06033C104JAT2A" 0603 258.573,68.955 r270 top value=0.1uF (schematic designator C243)
C243_N "06033C104JAT2A" 0603 124.545,59.573 r0 top value=0.1uF (schematic designator C243)
C244_L1 "06033C104JAT2A" 0603 93.076,128.907 r270 top value=0.1uF (schematic designator C244)
C244_L2 "06033C104JAT2A" 0603 176.576,113.907 r270 top value=0.1uF (schematic designator C244)
C244_L3 "06033C104JAT2A" 0603 262.576,85.907 r270 top value=0.1uF (schematic designator C244)
C244_N "06033C104JAT2A" 0603 107.593,63.576 r0 top value=0.1uF (schematic designator C244)
C245_L1 "CGA3E2C0G1H331J080AA" FP-CGA3E2C0G1H331J080AA_0603-MFG 80.5,165 r90 bottom value=330pF (schematic designator C245)
C245_L2 "CGA3E2C0G1H331J080AA" FP-CGA3E2C0G1H331J080AA_0603-MFG 164,150 r90 bottom value=330pF (schematic designator C245)
C245_L3 "CGA3E2C0G1H331J080AA" FP-CGA3E2C0G1H331J080AA_0603-MFG 250,122 r90 bottom value=330pF (schematic designator C245)
C245_N "CGA3E2C0G1H331J080AA" FP-CGA3E2C0G1H331J080AA_0603-MFG 71.5,51 r180 bottom value=330pF (schematic designator C245)
C246_L1 "CGA3E2C0G1H331J080AA" FP-CGA3E2C0G1H331J080AA_0603-MFG 91.111,128.882 r270 top value=330pF (schematic designator C246)
C246_L2 "CGA3E2C0G1H331J080AA" FP-CGA3E2C0G1H331J080AA_0603-MFG 174.611,113.882 r270 top value=330pF (schematic designator C246)
C246_L3 "CGA3E2C0G1H331J080AA" FP-CGA3E2C0G1H331J080AA_0603-MFG 260.611,85.882 r270 top value=330pF (schematic designator C246)
C246_N "CGA3E2C0G1H331J080AA" FP-CGA3E2C0G1H331J080AA_0603-MFG 107.518,61.611 r0 top value=330pF (schematic designator C246)
C247_L1 "06033C104JAT2A" 0603 82.5,165.5 r270 bottom value=0.1uF (schematic designator C247)
C247_L2 "06033C104JAT2A" 0603 166,150.5 r270 bottom value=0.1uF (schematic designator C247)
C247_L3 "06033C104JAT2A" 0603 252,122.5 r270 bottom value=0.1uF (schematic designator C247)
C247_N "06033C104JAT2A" 0603 71,53 r0 bottom value=0.1uF (schematic designator C247)
C248_L1 "CGA3E2C0G1H331J080AA" FP-CGA3E2C0G1H331J080AA_0603-MFG 92.175,112.309 r90 top value=330pF (schematic designator C248)
C248_L2 "CGA3E2C0G1H331J080AA" FP-CGA3E2C0G1H331J080AA_0603-MFG 175.675,97.309 r90 top value=330pF (schematic designator C248)
C248_L3 "CGA3E2C0G1H331J080AA" FP-CGA3E2C0G1H331J080AA_0603-MFG 261.675,69.309 r90 top value=330pF (schematic designator C248)
C248_N "CGA3E2C0G1H331J080AA" FP-CGA3E2C0G1H331J080AA_0603-MFG 124.191,62.675 r180 top value=330pF (schematic designator C248)
C249_L1 "GRT31CR61H106KE01L" 1206_180 91.111,131.783 r180 top value=10uF (schematic designator C249)
C249_L2 "GRT31CR61H106KE01L" 1206_180 174.611,116.783 r180 top value=10uF (schematic designator C249)
C249_L3 "GRT31CR61H106KE01L" 1206_180 260.611,88.783 r180 top value=10uF (schematic designator C249)
C249_N "GRT31CR61H106KE01L" 1206_180 104.717,61.611 r270 top value=10uF (schematic designator C249)
C250_L1 "885012205063" WCAP-CSGP_0402_L1W0.5H0.5 97.456,126.907 r0 top (schematic designator C250)
C250_L2 "885012205063" WCAP-CSGP_0402_L1W0.5H0.5 180.956,111.907 r0 top (schematic designator C250)
C250_L3 "885012205063" WCAP-CSGP_0402_L1W0.5H0.5 266.956,83.907 r0 top (schematic designator C250)
C250_N "885012205063" WCAP-CSGP_0402_L1W0.5H0.5 109.593,67.956 r90 top (schematic designator C250)
C251_L1 "GRM21BZ71A226ME15L" 0805_HV 96.203,128.573 r180 top value=22uF (schematic designator C251)
C251_L2 "GRM21BZ71A226ME15L" 0805_HV 179.703,113.573 r180 top value=22uF (schematic designator C251)
C251_L3 "GRM21BZ71A226ME15L" 0805_HV 265.703,85.573 r180 top value=22uF (schematic designator C251)
C251_N "GRM21BZ71A226ME15L" 0805_HV 107.927,66.703 r270 top value=22uF (schematic designator C251)
C252_L1 "06033C104JAT2A" 0603 89.561,128.998 r90 top value=0.1uF (schematic designator C252)
C252_L2 "06033C104JAT2A" 0603 173.061,113.998 r90 top value=0.1uF (schematic designator C252)
C252_L3 "06033C104JAT2A" 0603 259.061,85.998 r90 top value=0.1uF (schematic designator C252)
C252_N "06033C104JAT2A" 0603 107.502,60.061 r180 top value=0.1uF (schematic designator C252)
C253_L1 "CGA3E2C0G1H331J080AA" FP-CGA3E2C0G1H331J080AA_0603-MFG 95.228,112.755 r90 top value=330pF (schematic designator C253)
C253_L2 "CGA3E2C0G1H331J080AA" FP-CGA3E2C0G1H331J080AA_0603-MFG 178.728,97.755 r90 top value=330pF (schematic designator C253)
C253_L3 "CGA3E2C0G1H331J080AA" FP-CGA3E2C0G1H331J080AA_0603-MFG 264.728,69.755 r90 top value=330pF (schematic designator C253)
C253_N "CGA3E2C0G1H331J080AA" FP-CGA3E2C0G1H331J080AA_0603-MFG 123.745,65.728 r180 top value=330pF (schematic designator C253)
C254_L1 "GRM21BZ71A226ME15L" 0805_HV 101,112.655 r90 top value=22uF (schematic designator C254)
C254_L2 "GRM21BZ71A226ME15L" 0805_HV 184.5,97.655 r90 top value=22uF (schematic designator C254)
C254_L3 "GRM21BZ71A226ME15L" 0805_HV 270.5,69.655 r90 top value=22uF (schematic designator C254)
C254_N "GRM21BZ71A226ME15L" 0805_HV 123.845,71.5 r180 top value=22uF (schematic designator C254)
C255_L1 "GRM21BZ71A226ME15L" 0805_HV 97.754,111.659 r0 top value=22uF (schematic designator C255)
C255_L2 "GRM21BZ71A226ME15L" 0805_HV 181.254,96.659 r0 top value=22uF (schematic designator C255)
C255_L3 "GRM21BZ71A226ME15L" 0805_HV 267.254,68.659 r0 top value=22uF (schematic designator C255)
C255_N "GRM21BZ71A226ME15L" 0805_HV 124.841,68.254 r90 top value=22uF (schematic designator C255)
C256_L1 "885012205051" WCAP-CSGP_0402_L1W0.5H0.5 97.153,113.432 r180 top (schematic designator C256)
C256_L2 "885012205051" WCAP-CSGP_0402_L1W0.5H0.5 180.653,98.432 r180 top (schematic designator C256)
C256_L3 "885012205051" WCAP-CSGP_0402_L1W0.5H0.5 266.653,70.432 r180 top (schematic designator C256)
C256_N "885012205051" WCAP-CSGP_0402_L1W0.5H0.5 123.068,67.653 r270 top (schematic designator C256)
C257 "C2225C224KBRACTU" FP-C2225C224KBRACTU_2225-MFG 8.246,235.641 r0 bottom value=220nF
C258 "C2225C224KBRACTU" FP-C2225C224KBRACTU_2225-MFG 8.25,228.271 r0 bottom value=220nF
C259 "EEU-FM1E101" FM_630x1120 149.65,10.9 r0 top value=100uF
C260 "EEU-FM1E101" FM_630x1120 157.05,3.6 r0 top value=100uF
C261 "GRM155R71E104KE14D" 0402L 206.321,5.628 r180 top value=0.1uF
C262 "CGA3E2C0G1H331J080AA" FP-CGA3E2C0G1H331J080AA_0603-MFG 184.6,32.5 r0 top value=330pF
C263 "CGA2B2C0G1H102J050BA" 0402L 235.925,33.95 r90 top value=1000pF
D1 "KG DELLS1.22-JGKH-24" "FP-KG DELLS1.22-JGKH-24_0603-MFG" 185.5,45.5 r0 top
D2 "KG DELLS1.22-JGKH-24" "FP-KG DELLS1.22-JGKH-24_0603-MFG" 185.4,43.4 r0 top
D3 "B160-13-F" SMA 287.4,211.4 r270 top value=60V
D4 "150060VS75000" WL-SMCW_GREEN 168.682,4.596 r270 top value=Green
D5 "B330A-13-F" SMA 173.119,5.34 r180 top value=30V
D6 "150060VS75000" WL-SMCW_GREEN 160.083,20.625 r0 top value=Green
D7_L1 "ZGL41-180A-E3/96" FP-ZGL41-180A-E3/96_GL41-MFG 37,162 r270 top (schematic designator D7)
D7_L2 "ZGL41-180A-E3/96" FP-ZGL41-180A-E3/96_GL41-MFG 120.5,147 r270 top (schematic designator D7)
D7_L3 "ZGL41-180A-E3/96" FP-ZGL41-180A-E3/96_GL41-MFG 206.5,119 r270 top (schematic designator D7)
D7_N "ZGL41-180A-E3/96" FP-ZGL41-180A-E3/96_GL41-MFG 74.5,7.5 r0 top (schematic designator D7)
D8_L1 "ZGL41-180A-E3/96" FP-ZGL41-180A-E3/96_GL41-MFG 37,148 r270 top (schematic designator D8)
D8_L2 "ZGL41-180A-E3/96" FP-ZGL41-180A-E3/96_GL41-MFG 120.5,133 r270 top (schematic designator D8)
D8_L3 "ZGL41-180A-E3/96" FP-ZGL41-180A-E3/96_GL41-MFG 206.5,105 r270 top (schematic designator D8)
D8_N "ZGL41-180A-E3/96" FP-ZGL41-180A-E3/96_GL41-MFG 88.5,7.5 r0 top (schematic designator D8)
D9_L1 "ZGL41-180A-E3/96" FP-ZGL41-180A-E3/96_GL41-MFG 37,155 r270 top (schematic designator D9)
D9_L2 "ZGL41-180A-E3/96" FP-ZGL41-180A-E3/96_GL41-MFG 120.5,140 r270 top (schematic designator D9)
D9_L3 "ZGL41-180A-E3/96" FP-ZGL41-180A-E3/96_GL41-MFG 206.5,112 r270 top (schematic designator D9)
D9_N "ZGL41-180A-E3/96" FP-ZGL41-180A-E3/96_GL41-MFG 81.5,7.5 r0 top (schematic designator D9)
D10_L1 "APG1608SURKC/T" FP-APG1608SURKC_T_0603-MFG 36.95,134.803 r0 top (schematic designator D10)
D10_L2 "APG1608SURKC/T" FP-APG1608SURKC_T_0603-MFG 120.45,119.803 r0 top (schematic designator D10)
D10_L3 "APG1608SURKC/T" FP-APG1608SURKC_T_0603-MFG 206.45,91.803 r0 top (schematic designator D10)
D10_N "APG1608SURKC/T" FP-APG1608SURKC_T_0603-MFG 101.697,7.45 r90 top (schematic designator D10)
D11_L1 "APG1608SURKC/T" FP-APG1608SURKC_T_0603-MFG 53.28,134.732 r0 top (schematic designator D11)
D11_L2 "APG1608SURKC/T" FP-APG1608SURKC_T_0603-MFG 136.78,119.732 r0 top (schematic designator D11)
D11_L3 "APG1608SURKC/T" FP-APG1608SURKC_T_0603-MFG 222.78,91.732 r0 top (schematic designator D11)
D11_N "APG1608SURKC/T" FP-APG1608SURKC_T_0603-MFG 101.768,23.78 r90 top (schematic designator D11)
D12_L1 "APG1608SURKC/T" FP-APG1608SURKC_T_0603-MFG 75.264,133.624 r0 top (schematic designator D12)
D12_L2 "APG1608SURKC/T" FP-APG1608SURKC_T_0603-MFG 158.764,118.624 r0 top (schematic designator D12)
D12_L3 "APG1608SURKC/T" FP-APG1608SURKC_T_0603-MFG 244.764,90.624 r0 top (schematic designator D12)
D12_N "APG1608SURKC/T" FP-APG1608SURKC_T_0603-MFG 102.876,45.764 r90 top (schematic designator D12)
D13_L1 "ZGL41-180A-E3/96" FP-ZGL41-180A-E3/96_GL41-MFG 94.5,153 r90 top (schematic designator D13)
D13_L2 "ZGL41-180A-E3/96" FP-ZGL41-180A-E3/96_GL41-MFG 178,138 r90 top (schematic designator D13)
D13_L3 "ZGL41-180A-E3/96" FP-ZGL41-180A-E3/96_GL41-MFG 264,110 r90 top (schematic designator D13)
D13_N "ZGL41-180A-E3/96" FP-ZGL41-180A-E3/96_GL41-MFG 83.5,65 r180 top (schematic designator D13)
D14_L1 "ZGL41-180A-E3/96" FP-ZGL41-180A-E3/96_GL41-MFG 94.5,167 r90 top (schematic designator D14)
D14_L2 "ZGL41-180A-E3/96" FP-ZGL41-180A-E3/96_GL41-MFG 178,152 r90 top (schematic designator D14)
D14_L3 "ZGL41-180A-E3/96" FP-ZGL41-180A-E3/96_GL41-MFG 264,124 r90 top (schematic designator D14)
D14_N "ZGL41-180A-E3/96" FP-ZGL41-180A-E3/96_GL41-MFG 69.5,65 r180 top (schematic designator D14)
D15_L1 "ZGL41-180A-E3/96" FP-ZGL41-180A-E3/96_GL41-MFG 94.5,160 r90 top (schematic designator D15)
D15_L2 "ZGL41-180A-E3/96" FP-ZGL41-180A-E3/96_GL41-MFG 178,145 r90 top (schematic designator D15)
D15_L3 "ZGL41-180A-E3/96" FP-ZGL41-180A-E3/96_GL41-MFG 264,117 r90 top (schematic designator D15)
D15_N "ZGL41-180A-E3/96" FP-ZGL41-180A-E3/96_GL41-MFG 76.5,65 r180 top (schematic designator D15)
D16_L1 "APG1608SURKC/T" FP-APG1608SURKC_T_0603-MFG 90.25,133.784 r0 top (schematic designator D16)
D16_L2 "APG1608SURKC/T" FP-APG1608SURKC_T_0603-MFG 173.75,118.784 r0 top (schematic designator D16)
D16_L3 "APG1608SURKC/T" FP-APG1608SURKC_T_0603-MFG 259.75,90.784 r0 top (schematic designator D16)
D16_N "APG1608SURKC/T" FP-APG1608SURKC_T_0603-MFG 102.716,60.75 r90 top (schematic designator D16)
D17 "B160-13-F" SMA 211.9,3.8 r180 top value=60V
D18 "150060VS75000" WL-SMCW_GREEN 286.25,15.55 r90 top value=Green
D19 "KG DELLS1.22-JGKH-24" "FP-KG DELLS1.22-JGKH-24_0603-MFG" 267.5,63 r180 top
D20 "KG DELLS1.22-JGKH-24" "FP-KG DELLS1.22-JGKH-24_0603-MFG" 291.145,197.5 r180 top
D21 "KG DELLS1.22-JGKH-24" "FP-KG DELLS1.22-JGKH-24_0603-MFG" 234,24 r90 top
F1 "SF-3812F2500T-2" FP-SF-3812F2500T-2_SMD2-MFG 247,274 r90 top
F2 "SF-3812F2500T-2" FP-SF-3812F2500T-2_SMD2-MFG 233,274 r90 top
F3 "SF-3812F2500T-2" FP-SF-3812F2500T-2_SMD2-MFG 217,274 r90 top
F4 "SF-3812F2500T-2" FP-SF-3812F2500T-2_SMD2-MFG 271.5,275 r180 top
FB1 "MH1608-601Y" FP-MH1608-601Y_0603-MFG 198.5,34.2 r0 top
FB2 "MH1608-601Y" FP-MH1608-601Y_0603-MFG 100.5,236.7 r270 top
FB3 "MH1608-601Y" FP-MH1608-601Y_0603-MFG 112,229.9 r180 top
FB4 "MH1608-601Y" FP-MH1608-601Y_0603-MFG 199,205 r270 top
FB5 "MH1608-601Y" FP-MH1608-601Y_0603-MFG 264.7,46.8 r0 top
FB6 "MH1608-601Y" FP-MH1608-601Y_0603-MFG 45.5,106.5 r180 top
FB7 "MH1608-601Y" FP-MH1608-601Y_0603-MFG 139,247.2 r270 top
FB8 "MH1608-601Y" FP-MH1608-601Y_0603-MFG 125,247.1 r270 top
FB9 "MH1608-601Y" FP-MH1608-601Y_0603-MFG 113.8,247.2 r270 top
FB10 "MH1608-601Y" FP-MH1608-601Y_0603-MFG 102.3,262.896 r180 top
FB11 "MH1608-601Y" FP-MH1608-601Y_0603-MFG 158.584,52.3 r180 top
FB12 "BLM15EX331SN1D" FP-BLM15EX331SN1D_0402-MFG 290.8,38 r180 top
FB13 "BLM15EX331SN1D" FP-BLM15EX331SN1D_0402-MFG 291.1,35.1 r270 top
FB14_L1 "MH1608-601Y" FP-MH1608-601Y_0603-MFG 69,111.5 r90 top (schematic designator FB14)
FB14_L2 "MH1608-601Y" FP-MH1608-601Y_0603-MFG 152.5,96.5 r90 top (schematic designator FB14)
FB14_L3 "MH1608-601Y" FP-MH1608-601Y_0603-MFG 238.5,68.5 r90 top (schematic designator FB14)
FB14_N "MH1608-601Y" FP-MH1608-601Y_0603-MFG 125,39.5 r180 top (schematic designator FB14)
FB15_L1 "MH1608-601Y" FP-MH1608-601Y_0603-MFG 70.8,132 r0 top (schematic designator FB15)
FB15_L2 "MH1608-601Y" FP-MH1608-601Y_0603-MFG 154.3,117 r0 top (schematic designator FB15)
FB15_L3 "MH1608-601Y" FP-MH1608-601Y_0603-MFG 240.3,89 r0 top (schematic designator FB15)
FB15_N "MH1608-601Y" FP-MH1608-601Y_0603-MFG 104.5,41.2 r90 top (schematic designator FB15)
FB16 "MH1608-601Y" FP-MH1608-601Y_0603-MFG 181.1,40.4 r180 top
FB17 "BLM15EX331SN1D" FP-BLM15EX331SN1D_0402-MFG 287.75,19.55 r0 top
FB18 "BLM15EX331SN1D" FP-BLM15EX331SN1D_0402-MFG 288.25,16.05 r0 top
FID1 "Fiducial" Fiducial10-20 297,13.4 r0 top
FID2 "Fiducial" Fiducial10-20 47.8,298.1 r0 top
FID3 "Fiducial" Fiducial10-20 181.4,239.2 r0 top
J1 "618009231121" Wurth_618009231121 272.5,0 r270 top
J2 "FCR7350R" Cliff_FCR7350R 7,290 r180 top
J3 "FCR7350N" FP-FCR7350N_CONN_BANANA_JACK-MFG 247,299 r270 top
J4 "0022111031" FP-0022111031_HDR3-MFG 232.8,3.8 r180 top
J5 "FCR7350N" FP-FCR7350N_CONN_BANANA_JACK-MFG 227,299 r270 top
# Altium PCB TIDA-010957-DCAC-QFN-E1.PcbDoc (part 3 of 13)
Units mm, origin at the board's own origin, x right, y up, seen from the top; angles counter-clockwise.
Board outline 300 x 300 mm, 4 copper layers (Top Layer, Layer 1, Layer 2, Bottom Layer), stack 1.787 mm thick; 1286 components, 677 nets, 4169 pads, 3428 vias.

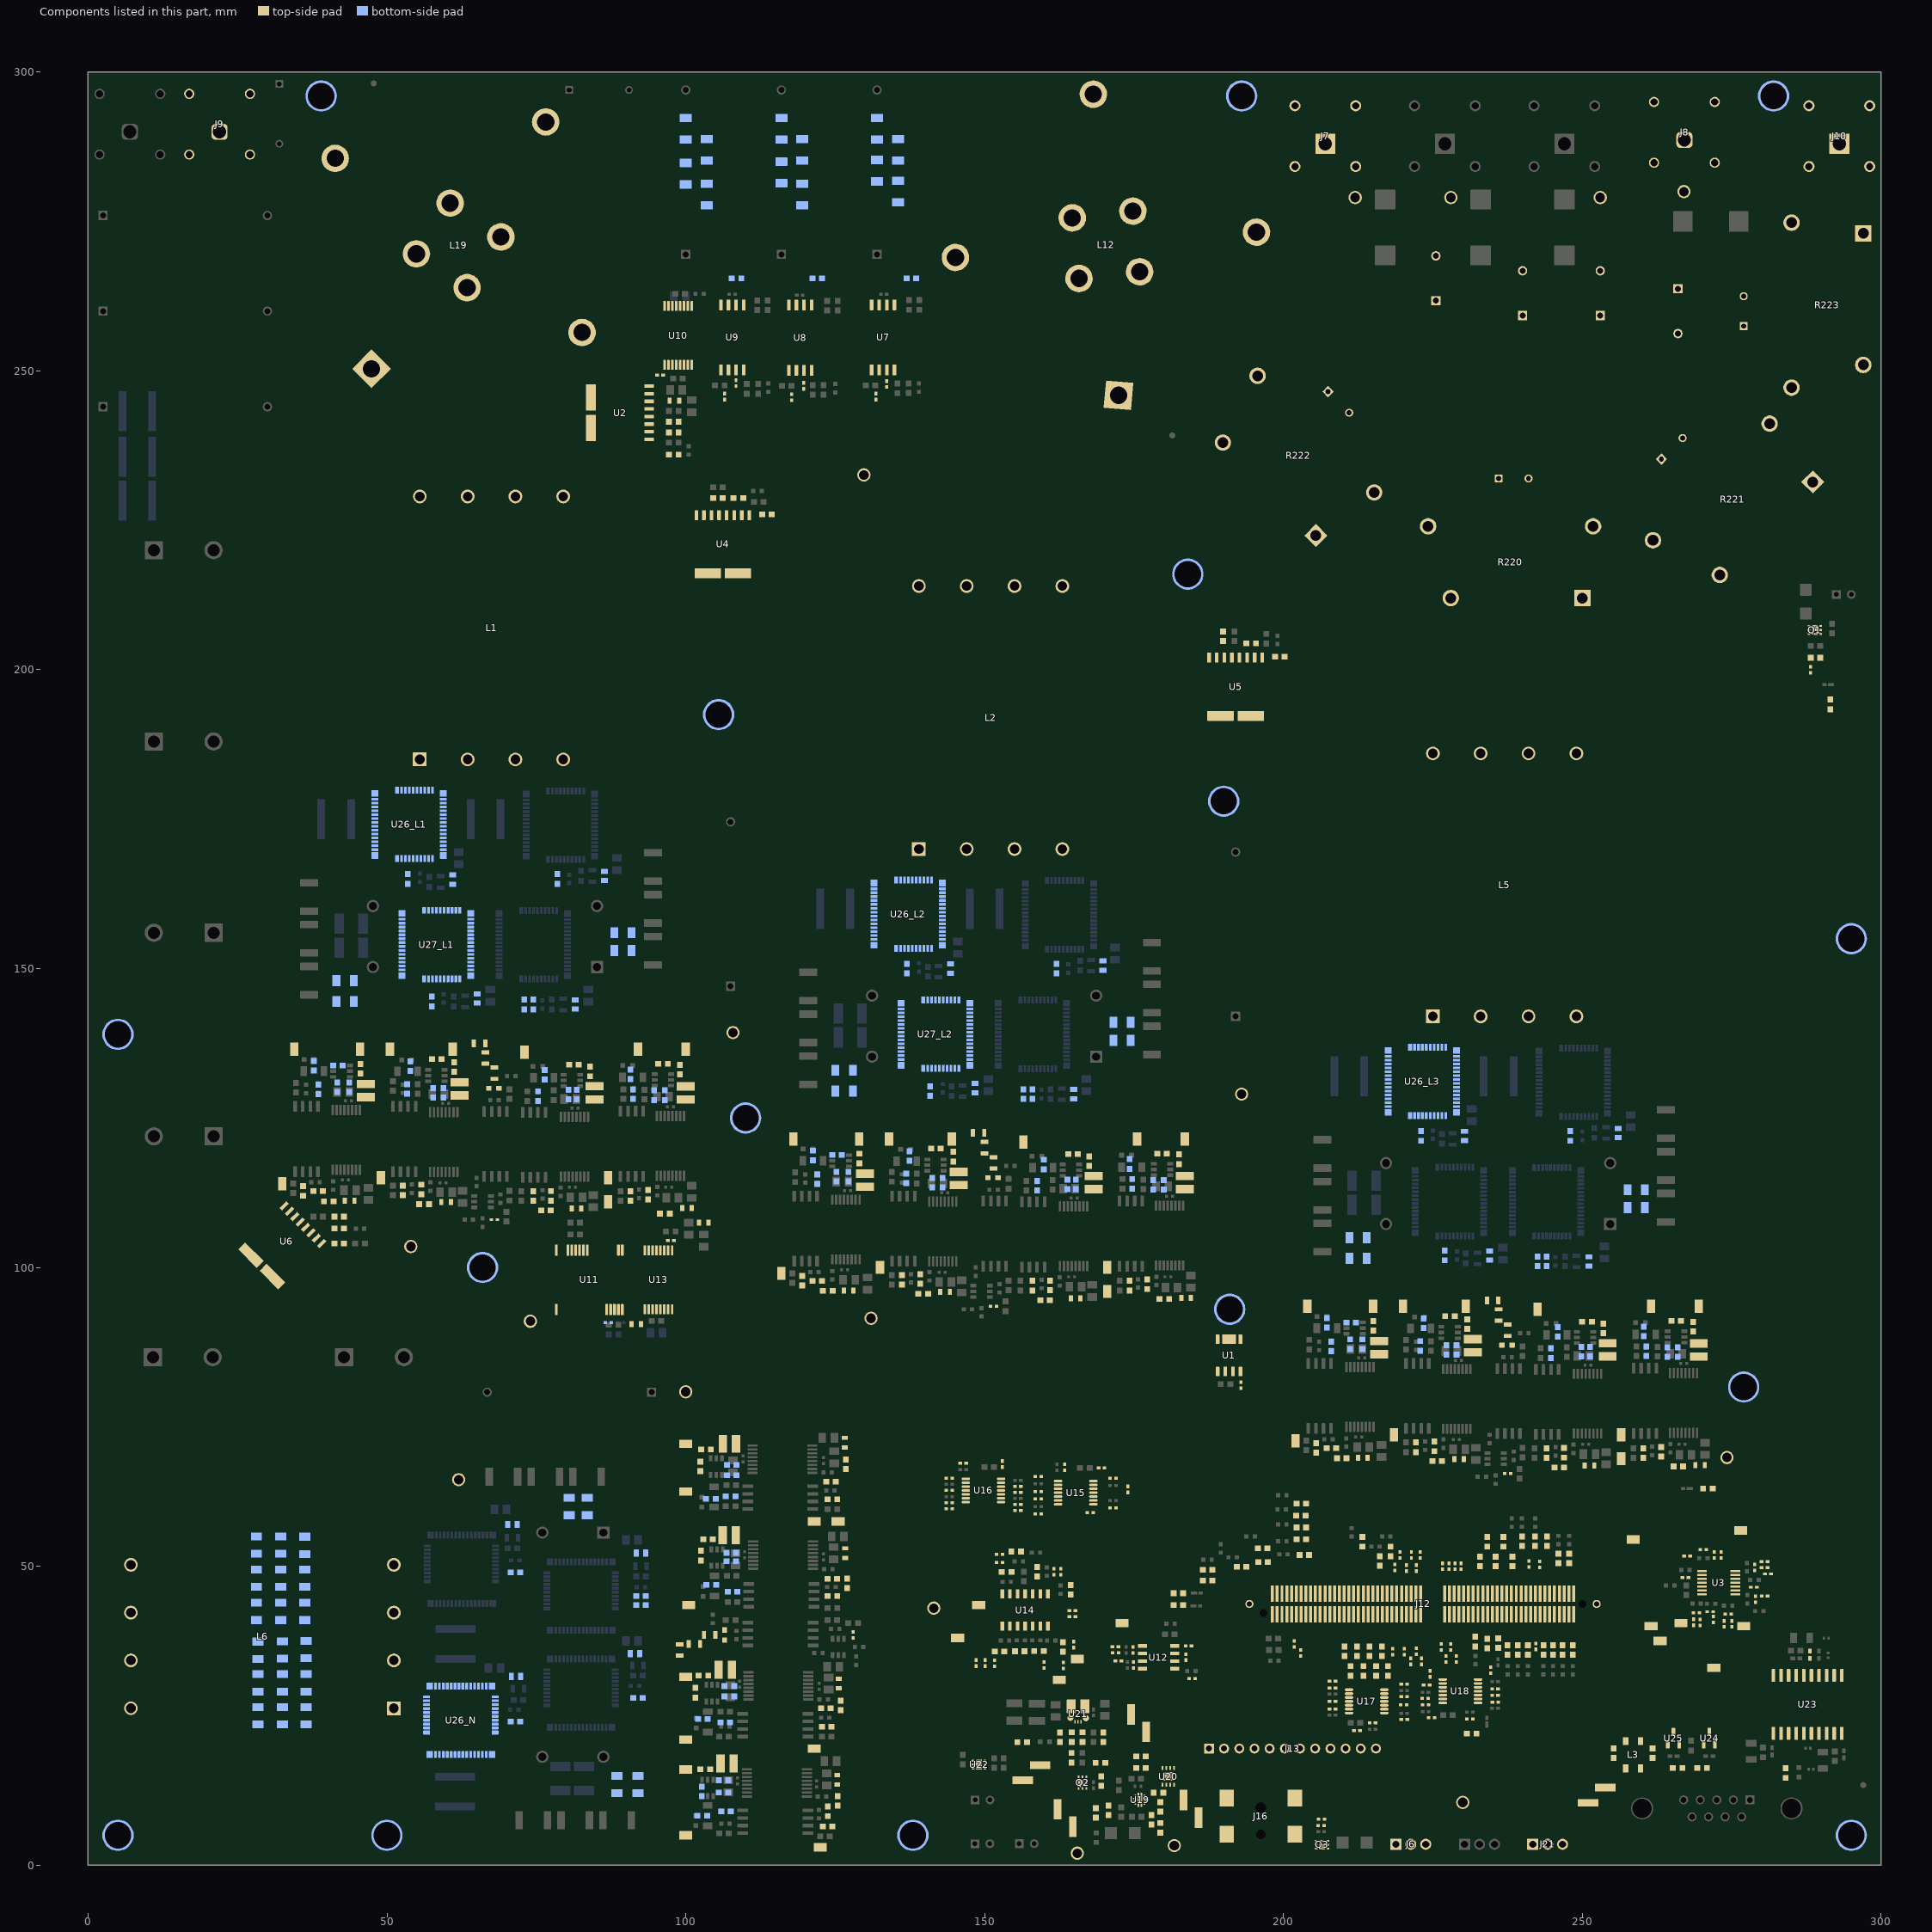
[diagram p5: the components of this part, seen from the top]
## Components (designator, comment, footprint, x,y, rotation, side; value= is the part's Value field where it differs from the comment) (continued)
J6 "0022111031" FP-0022111031_HDR3-MFG 221.3,3.8 r180 top
J7 "FCR7350N" FP-FCR7350N_CONN_BANANA_JACK-MFG 207,299 r270 top
J8 "FCR7350B" Cliff_FCR7350B 267.08,288.64 r180 top
J9 "FCR7350B" Cliff_FCR7350B 22,290 r180 top
J10 "FCR7350G" FP-FCR7350G_CONN_BANANA_JACK-MFG 293,299 r270 top
J11 "TSM-102-01-T-SV-P-TR" Samtec_TSM-102-01-T-SV-P-TR 252.4,11.7 r270 top
J12 "HSEC8-160-01-L-DV-A-BL" controlCARD-120HSEC 225.193,43.722 r180 top
J13 "TSW-112-07-G-S" TSW-112-07-G-S 201.5,19.5 r0 top
J14 "TSM-102-01-T-SV-P-TR" Samtec_TSM-102-01-T-SV-P-TR 184.538,9.425 r180 top
J15 "TSM-102-01-T-SV-P-TR" Samtec_TSM-102-01-T-SV-P-TR 163.479,7.898 r180 top
J16 "PJ-002AH-SMT-TR" CUI_PJ-002AH-SMT 196.2,8.2 r90 top
J17 "TSM-102-01-T-SV-P-TR" Samtec_TSM-102-01-T-SV-P-TR 175.751,23.754 r180 top
J18 "TSM-102-01-T-SV-P-TR" Samtec_TSM-102-01-T-SV-P-TR 157.833,15.475 r270 top
J21 "0022111031" FP-0022111031_HDR3-MFG 244.2,3.8 r180 top
L1 "MAG-3002584" FP-MAG-3002584_PTH8-MFG 67.5,207 r90 top value=87uH
L2 "MAG-3002584" FP-MAG-3002584_PTH8-MFG 151,192 r90 top value=87uH
L3 "ACT45B-101-2P-TL003" FP-ACT45B-101-2P-TL003_SMT_4MM5_3MM2-MFG 258.5,18.475 r270 top
L4_L1 "74404020100" WE-LQS_2010 61,164.9 r90 bottom value=10uH (schematic designator L4)
L4_L2 "74404020100" WE-LQS_2010 144.3,150 r90 bottom value=10uH (schematic designator L4)
L4_L3 "74404020100" WE-LQS_2010 230.3,122 r90 bottom value=10uH (schematic designator L4)
L4_N "74404020100" WE-LQS_2010 71.6,31.6 r180 bottom value=10uH (schematic designator L4)
L5 "MAG-3002584" FP-MAG-3002584_PTH8-MFG 237,164 r90 top value=87uH
L6 "MAG-3002584" FP-MAG-3002584_PTH8-MFG 29.165,38.25 r180 top value=87uH
L7 "74479763222" WE-PMI_0603_L1.6W0.8H0.8 98.1,245 r0 top
L8 "74479763222" WE-PMI_0603_L1.6W0.8H0.8 91.7,90.5 r180 top
L9 "74479763222" WE-PMI_0603_L1.6W0.8H0.8 103,107.5 r0 top
L10_L1 "SDR0302-150ML" SDR0302 46.5,129.582 r270 top value=15uH (schematic designator L10)
L10_L2 "SDR0302-150ML" SDR0302 130,114.582 r270 top value=15uH (schematic designator L10)
L10_L3 "SDR0302-150ML" SDR0302 216,86.582 r270 top value=15uH (schematic designator L10)
L10_N "SDR0302-150ML" SDR0302 106.918,17 r0 top value=15uH (schematic designator L10)
L11_L1 "74479763222" WE-PMI_0603_L1.6W0.8H0.8 43.763,111.158 r0 top (schematic designator L11)
L11_L2 "74479763222" WE-PMI_0603_L1.6W0.8H0.8 127.263,96.158 r0 top (schematic designator L11)
L11_L3 "74479763222" WE-PMI_0603_L1.6W0.8H0.8 213.263,68.158 r0 top (schematic designator L11)
L11_N "74479763222" WE-PMI_0603_L1.6W0.8H0.8 125.342,14.263 r90 top (schematic designator L11)
L12 "MAG-3002585" FP-MAG-3002585_PTH8-MFG 170.3,271.1 r175 top
L12_L1 "SDR0302-150ML" SDR0302 62.173,129.898 r270 top value=15uH (schematic designator L12)
L12_L2 "SDR0302-150ML" SDR0302 145.673,114.898 r270 top value=15uH (schematic designator L12)
L12_L3 "SDR0302-150ML" SDR0302 231.673,86.898 r270 top value=15uH (schematic designator L12)
L12_N "SDR0302-150ML" SDR0302 106.602,32.673 r0 top value=15uH (schematic designator L12)
L13_L1 "74479763222" WE-PMI_0603_L1.6W0.8H0.8 59.894,110.934 r0 top (schematic designator L13)
L13_L2 "74479763222" WE-PMI_0603_L1.6W0.8H0.8 143.394,95.934 r0 top (schematic designator L13)
L13_L3 "74479763222" WE-PMI_0603_L1.6W0.8H0.8 229.394,67.934 r0 top (schematic designator L13)
L13_N "74479763222" WE-PMI_0603_L1.6W0.8H0.8 125.566,30.394 r90 top (schematic designator L13)
L14_L1 "SDR0302-150ML" SDR0302 84.725,129.216 r270 top value=15uH (schematic designator L14)
L14_L2 "SDR0302-150ML" SDR0302 168.225,114.216 r270 top value=15uH (schematic designator L14)
L14_L3 "SDR0302-150ML" SDR0302 254.225,86.216 r270 top value=15uH (schematic designator L14)
L14_N "SDR0302-150ML" SDR0302 107.284,55.225 r0 top value=15uH (schematic designator L14)
L15_L1 "74479763222" WE-PMI_0603_L1.6W0.8H0.8 81.71,109.842 r0 top (schematic designator L15)
L15_L2 "74479763222" WE-PMI_0603_L1.6W0.8H0.8 165.21,94.842 r0 top (schematic designator L15)
L15_L3 "74479763222" WE-PMI_0603_L1.6W0.8H0.8 251.21,66.842 r0 top (schematic designator L15)
L15_N "74479763222" WE-PMI_0603_L1.6W0.8H0.8 126.658,52.21 r90 top (schematic designator L15)
L16_L1 "SDR0302-150ML" SDR0302 99.994,129.191 r270 top value=15uH (schematic designator L16)
L16_L2 "SDR0302-150ML" SDR0302 183.494,114.191 r270 top value=15uH (schematic designator L16)
L16_L3 "SDR0302-150ML" SDR0302 269.494,86.191 r270 top value=15uH (schematic designator L16)
L16_N "SDR0302-150ML" SDR0302 107.309,70.494 r0 top value=15uH (schematic designator L16)
L17_L1 "74479763222" WE-PMI_0603_L1.6W0.8H0.8 100.2,109.917 r0 top (schematic designator L17)
L17_L2 "74479763222" WE-PMI_0603_L1.6W0.8H0.8 183.7,94.917 r0 top (schematic designator L17)
L17_L3 "74479763222" WE-PMI_0603_L1.6W0.8H0.8 269.7,66.917 r0 top (schematic designator L17)
L17_N "74479763222" WE-PMI_0603_L1.6W0.8H0.8 126.583,70.7 r90 top (schematic designator L17)
L18_L1 "74404020100" WE-LQS_2010 65.1,145 r90 bottom value=10uH (schematic designator L18)
L18_L2 "74404020100" WE-LQS_2010 148.4,130 r90 bottom value=10uH (schematic designator L18)
L18_L3 "74404020100" WE-LQS_2010 234.5,102 r90 bottom value=10uH (schematic designator L18)
L18_N "74404020100" WE-LQS_2010 91.5,35.4 r180 bottom value=10uH (schematic designator L18)
L19 "MAG-3002585" FP-MAG-3002585_PTH8-MFG 62,271 r135 top
L20_L1 "74404020100" WE-LQS_2010 81.5,144 r90 bottom value=10uH (schematic designator L20)
L20_L2 "74404020100" WE-LQS_2010 164.9,129 r90 bottom value=10uH (schematic designator L20)
L20_L3 "74404020100" WE-LQS_2010 251.1,101 r90 bottom value=10uH (schematic designator L20)
L20_N "74404020100" WE-LQS_2010 92.5,52.2 r180 bottom value=10uH (schematic designator L20)
L21_L1 "74404020100" WE-LQS_2010 86.4,165.5 r90 bottom value=10uH (schematic designator L21)
L21_L2 "74404020100" WE-LQS_2010 169.8,150.5 r90 bottom value=10uH (schematic designator L21)
L21_L3 "74404020100" WE-LQS_2010 256,122.5 r90 bottom value=10uH (schematic designator L21)
L21_N "74404020100" WE-LQS_2010 71,57 r180 bottom value=10uH (schematic designator L21)
LBL1 "THT-14-423-10" Label_650x200 171.7,231.2 r0 top
Logo1 "CE Mark" CE_Mark_5mm 151.8,231.3 r0 top
Logo3 "FCC disclaimer" FCC_disclaimer 386.4,170.1 r180 top
Logo4 "WEEE logo" WEEE_Minimum 142.7,231.7 r0 top
LOGO5 "CAUTION HOT SURFACE" IEC_HotSurface_Small 270,197.8 r0 top
LOGO6 "DANGER HIGH VOLTAGE" IEC_HighVoltage_Small 262.6,197.7 r0 top
MP1 "9774025960R" FP-9774025960R_STAND_OFF-MFG 277,80 r180 bottom locked
MP2 "9774025960R" FP-9774025960R_STAND_OFF-MFG 105.5,192.5 r180 bottom
MP3 "9774025960R" FP-9774025960R_STAND_OFF-MFG 110,125 r180 bottom locked
MP4 "9774025960R" FP-9774025960R_STAND_OFF-MFG 39,296 r180 bottom
MP5 "9774025960R" FP-9774025960R_STAND_OFF-MFG 66,100 r180 bottom locked
MP6 "9774025960R" FP-9774025960R_STAND_OFF-MFG 282,296 r180 bottom
MP7 "9774025960R" FP-9774025960R_STAND_OFF-MFG 295,155 r180 bottom
MP8 "9774025960R" FP-9774025960R_STAND_OFF-MFG 50,5 r270 bottom locked
MP9 "9774025960R" FP-9774025960R_STAND_OFF-MFG 5,5 r180 bottom locked
MP10 "9774025960R" FP-9774025960R_STAND_OFF-MFG 295,5 r180 bottom
MP10 "9774025960R" FP-9774025960R_STAND_OFF-MFG 193,296 r180 bottom
MP11 "9774025960R" FP-9774025960R_STAND_OFF-MFG 190,178 r180 bottom
MP12 "9774025960R" FP-9774025960R_STAND_OFF-MFG 191,93 r90 bottom locked
MP13 "9774025960R" FP-9774025960R_STAND_OFF-MFG 184,216 r180 bottom
MP14 "9774025960R" FP-9774025960R_STAND_OFF-MFG 5,139 r180 bottom
MP15 "9774025960R" FP-9774025960R_STAND_OFF-MFG 138,5 r180 bottom locked
Q1 "CSD17571Q2" DQK0006C 288.905,206.65 r0 top value=30V
Q2 "CSD17571Q2" DQK0006C 166.382,13.809 r90 top value=30V
Q3 "CSD17571Q2" DQK0006C 206.45,3.443 r180 top value=30V
R1 "CRCW1206510KJNEA" 1206 28.426,25 r270 bottom value=510k
R2 "CRCW1206510KJNEA" 1206 32.5,25 r270 bottom value=510k
R3 "CRCW1206510KJNEA" 1206 36.5,25 r270 bottom value=510k
R4 "CRCW1206510KJNEA" 1206 28.426,30.504 r270 bottom value=510k
R5 "CRCW1206510KJNEA" 1206 32.5,30.504 r270 bottom value=510k
R6 "CRCW1206510KJNEA" 1206 36.5,30.504 r270 bottom value=510k
R7 "CRCW1206510KJNEA" 1206 28.426,35.95 r270 bottom value=510k
R8 "CRCW1206510KJNEA" 1206 32.5,36 r270 bottom value=510k
R9 "CRCW1206510KJNEA" 1206 36.5,36.05 r270 bottom value=510k
R10 "CRCW1206510KJNEA" 1206 28.177,42.45 r270 bottom value=510k
R11 "CRCW1206510KJNEA" 1206 32.252,42.45 r270 bottom value=510k
R12 "CRCW1206510KJNEA" 1206 36.252,42.45 r270 bottom value=510k
R13 "CRCW1206510KJNEA" 1206 28.177,48.004 r270 bottom value=510k
R14 "CRCW1206510KJNEA" 1206 32.252,48.004 r270 bottom value=510k
R15 "CRCW1206510KJNEA" 1206 36.252,48.004 r270 bottom value=510k
R16 "CRCW1206510KJNEA" 1206 28.177,53.554 r270 bottom value=510k
R17 "CRCW1206510KJNEA" 1206 32.252,53.554 r270 bottom value=510k
R18 "CRCW1206510KJNEA" 1206 36.252,53.5 r270 bottom value=510k
R19 "ERJ-2RKF33R0X" 0402L 192.9,80.3 r90 top value=33.0
R20 "RCS06030000Z0EA" 0603 247.8,51.3 r90 top value=0
R21 "RCS06030000Z0EA" 0603 246,51.3 r90 top value=0
R22 "RCS06030000Z0EA" 0603 248.4,36 r270 top value=0
R23 "RCS06030000Z0EA" 0603 244.1,54.2 r90 top value=0
R24 "RCS06030000Z0EA" 0603 246.7,36 r270 top value=0
R25 "ERJ-2RKF33R0X" 0402L 242.9,50.3 r270 top value=33.0
R26 "RCS06030000Z0EA" 0603 242.1,54.2 r90 top value=0
R27 "RCS06030000Z0EA" 0603 245.1,36 r270 top value=0
R28 "RCS06030000Z0EA" 0603 243.5,36 r270 top value=0
R29 "ERJ-2RKF33R0X" 0402L 241.1,50.4 r270 top value=33.0
R30 "ERJ-2RKF33R0X" 0402L 242.2,36.6 r270 top value=33.0
R31 "RCS06030000Z0EA" 0603 239.9,54.2 r90 top value=0
R32 "RCS06030000Z0EA" 0603 240.9,36 r90 top value=0
R33 "RCS06030000Z0EA" 0603 238.3,50.8 r90 top value=0
R34 "RCS06030000Z0EA" 0603 239.2,36 r90 top value=0
R35 "RCS06030000Z0EA" 0603 237.5,36 r90 top value=0
R36 "RCS06030000Z0EA" 0603 236.8,54.1 r90 top value=0
R37 "RCS06030000Z0EA" 0603 235.5,50.8 r90 top value=0
R38 "RCS06030000Z0EA" 0603 235.925,37.15 r90 top value=0
R39 "RCS06030000Z0EA" 0603 234.1,54.1 r90 top value=0
R40 "RCS06030000Z0EA" 0603 232.9,50.8 r90 top value=0
R41 "RCS06030000Z0EA" 0603 234.1,37.1 r90 top value=0
R42 "RCS06030000Z0EA" 0603 232.1,37.4 r90 top value=0
R43 "ERJ-2RKF33R0X" 0402L 229.7,50 r270 top value=33.0
R44 "ERJ-2RKF33R0X" 0402L 228.9,34.5 r90 top value=33.0
R45 "ERJ-2RKF33R0X" 0402L 228.7,50 r270 top value=33.0
R46 "ERJ-2RKF33R0X" 0402L 228,36.5 r90 top value=33.0
R47 "ERJ-2RKF33R0X" 0402L 227.7,50 r270 top value=33.0
R48 "ERJ-2RKF33R0X" 0402L 227.2,34.5 r90 top value=33.0
R49 "ERJ-2RKF33R0X" 0402L 226.6,50 r270 top value=33.0
R50 "ERJ-2RKF33R0X" 0402L 226.4,36.5 r90 top value=33.0
R51 "ERJ-2RKF33R0X" 0402L 222.9,51.9 r270 top value=33.0
R52 "ERJ-2RKF33R0X" 0402L 223.1,34.1 r90 top value=33.0
R53 "ERJ-2RKF33R0X" 0402L 222.2,49.7 r270 top value=33.0
R54 "ERJ-2RKF33R0X" 0402L 222.2,35.8 r90 top value=33.0
R55 "ERJ-2RKF33R0X" 0402L 221.4,51.9 r270 top value=33.0
R56 "ERJ-2RKF33R0X" 0402L 221.3,34.1 r90 top value=33.0
R57 "ERJ-2RKF33R0X" 0402L 220.6,49.7 r270 top value=33.0
R58 "ERJ-2RKF33R0X" 0402L 220.2,35.7 r90 top value=33.0
R59 "ERJ-2RKF33R0X" 0402L 219.5,51.9 r270 top value=33.0
R60 "ERJ-2RKF33R0X" 0402L 218.6,49.8 r270 top value=33.0
R61 "ERJ-2RKF33R0X" 0402L 218.3,35.7 r90 top value=33.0
R62 "RCS06030000Z0EA" 0603 217.9,52.5 r90 top value=0
R63 "RCS06030000Z0EA" 0603 217.5,32.5 r90 top value=0
R64 "RCS06030000Z0EA" 0603 216.1,50.9 r90 top value=0
R65 "RCS06030000Z0EA" 0603 216.5,35.8 r90 top value=0
R66 "RCS06030000Z0EA" 0603 213.2,54.1 r90 top value=0
R67 "RCS06030000Z0EA" 0603 215.5,32.5 r90 top value=0
R68 "RCS06030000Z0EA" 0603 203,60.5 r180 top value=0
R69 "RCS06030000Z0EA" 0603 214.4,35.8 r90 top value=0
R70 "RCS06030000Z0EA" 0603 202.936,58.464 r180 top value=0
R71 "RCS06030000Z0EA" 0603 213.4,32.5 r90 top value=0
R72 "RCS06030000Z0EA" 0603 203,56.5 r180 top value=0
R73 "RCS06030000Z0EA" 0603 203,54.5 r180 top value=0
R74 "RCS06030000Z0EA" 0603 196.5,53 r180 top value=0
R75 "RCS06030000Z0EA" 0603 203.5,51.9 r180 top value=0
R76 "RCS06030000Z0EA" 0603 196.6,50.7 r180 top value=0
R77 "RCS06030000Z0EA" 0603 193,49.9 r180 top value=0
R78 "RCS06030000Z0EA" 0603 187.3,49.4 r180 top value=0
R79 "ERJ-2RKF33R0X" 0402L 202.9,35.5 r90 top value=33.0
R80 "ERJ-2RKF33R0X" 0402L 201.8,37 r90 top value=33.0
R81 "RC0603JR-07680RL" 0603 182.4,45.5 r0 top value=680
R82 "RC0603JR-07680RL" 0603 182.4,43.5 r0 top value=680
R83 "PTCEL13R600LBE" FP-PTCEL13R600LBE_RADIAL-MFG 238.5,232 r0 top value=60Ω
R84 "RCS06030000Z0EA" 0603 212.3,35.8 r90 top value=0
R85 "PTCEL13R600LBE" FP-PTCEL13R600LBE_RADIAL-MFG 265,237 r45 top value=60Ω
R86 "RCS06030000Z0EA" 0603 211.2,32.5 r90 top value=0
R87 "PTCEL13R600LBE" FP-PTCEL13R600LBE_RADIAL-MFG 209.232,244.768 r315 top value=60Ω
R88 "RCS06030000Z0EA" 0603 210.2,35.8 r90 top value=0
R89 "IsoM5-275-B-L2" FP-IsoM5-275-B-L2_RADIAL-MFG 253,263 r90 top
R90 "IsoM5-275-B-L2" FP-IsoM5-275-B-L2_RADIAL-MFG 240,263 r90 top
R91 "IsoM5-275-B-L2" FP-IsoM5-275-B-L2_RADIAL-MFG 225.5,265.5 r90 top
R92 "PTCEL13R600LBE" FP-PTCEL13R600LBE_RADIAL-MFG 277,260 r90 top value=60Ω
R93 "CRCW0603499RFKEAC" 0603 284,15.4 r90 top value=499
R94 "IsoM5-275-B-L2" FP-IsoM5-275-B-L2_RADIAL-MFG 266,260 r270 top
R95_L1 "RC0603FR-0733KL" 0603 53.5,165 r270 bottom value=33.0k (schematic designator R95)
R95_L2 "RC0603FR-0733KL" 0603 137,150 r270 bottom value=33.0k (schematic designator R95)
R95_L3 "RC0603FR-0733KL" 0603 223,122 r270 bottom value=33.0k (schematic designator R95)
R95_N "RC0603FR-0733KL" 0603 71.5,24 r0 bottom value=33.0k (schematic designator R95)
R96 "ERJ-2RKF1000X" 0402L 288.2,200 r90 top value=100
R97 "CRCW060310K0FKEA" 0603 289,202 r180 top value=10.0k
R98 "MCS0402MD1002BE100" 0402L 271.4,42.4 r180 top value=10.0k
R99 "CRCW060310K0FKEA" 0603 98,236 r0 top value=10.0k
R100 "MCS0402MD1002BE100" 0402L 271.9,41.1 r270 top value=10.0k
R101 "CRCW0402309RFKED" 0402L 269.7,40.6 r270 top value=309
R102 "MCS0402MD1002BE100" 0402L 268.6,40.645 r270 top value=10.0k
R103 "MCS0402MD1002BE100" 0402L 269.1,42.2 r180 top value=10.0k
R104 "RC0603FR-0743K2L" 0603 98,239.7 r180 top value=43.2k
R105 "CRCW060310K0FKEA" 0603 98,241.5 r0 top value=10.0k
R106 "MCS0402MD1002BE100" 0402L 278.996,44.485 r270 top value=10.0k
R107 "MCS0402MD1002BE100" 0402L 280.5,45 r0 top value=10.0k
R108 "CRCW0402309RFKED" 0402L 275.05,40.363 r270 top value=309
R109 "CRCW060310K0FKEA" 0603 113.6,226 r0 top value=10.0k
R110 "MCS0402MD1002BE100" 0402L 273.75,40.363 r270 top value=10.0k
R111 "MCS0402MD1002BE100" 0402L 274.4,42 r180 top value=10.0k
R112 "RC0603FR-0743K2L" 0603 108.8,228.7 r0 top value=43.2k
R113 "CRCW060310K0FKEA" 0603 105.4,228.7 r0 top value=10.0k
R114 "MCS0402MD1002BE100" 0402L 278.685,46.5 r0 top value=10.0k
R115 "MCS0402MD1002BE100" 0402L 281.067,48.732 r0 top value=10.0k
R116 "CRCW0402309RFKED" 0402L 280.493,50.8 r0 top value=309
R117 "CRCW060310K0FKEA" 0603 199.4,202.2 r0 top value=10.0k
R118 "MCS0402MD1002BE100" 0402L 280.493,49.75 r0 top value=10.0k
R119 "MCS0402MD1002BE100" 0402L 278.8,49.8 r270 top value=10.0k
R120 "RC0603FR-0743K2L" 0603 194.6,204.4 r0 top value=43.2k
R121 "CRCW060310K0FKEA" 0603 189.9,205.6 r270 top value=10.0k
R122 "MCS0402MD1002BE100" 0402L 267.25,48.119 r180 top value=10.0k
R123 "CRCW060310K0FKEA" 0603 42,104 r0 top value=10.0k
R124 "MCS0402MD1002BE100" 0402L 273.2,51.9 r90 top value=10.0k
R125 "CRCW0402309RFKED" 0402L 267.55,51.684 r180 top value=309
R126 "MCS0402MD1002BE100" 0402L 272.1,51.9 r90 top value=10.0k
R127 "MCS0402MD1002BE100" 0402L 270.25,52.807 r0 top value=10.0k
R128 "RC0603FR-0743K2L" 0603 42,106.5 r0 top value=43.2k
R129 "CRCW060310K0FKEA" 0603 42,108.5 r180 top value=10.0k
R130 "ERJ-2RKF1000X" 0402L 133.6,247.8 r270 top value=100
R131 "ERJ-2RKF1000X" 0402L 131.8,245.7 r270 top value=100
R132 "ERJ-2RKF1000X" 0402L 119.705,247.494 r270 top value=100
R133 "ERJ-2RKF1000X" 0402L 117.7,245.6 r270 top value=100
R134 "ERJ-2RKF1000X" 0402L 108.405,247.945 r270 top value=100
R135 "ERJ-2RKF1000X" 0402L 106.5,245.7 r270 top value=100
R136 "CRCW040230K0FKED" 0402L 95.7,249.3 r0 top value=30.0k
R137 "ERA-2AEB153X" 0402L 174.9,33.5 r270 top value=15.0k
R138 "RC0402JR-070RL" 0402L 87.029,90.768 r180 bottom value=0
R139 "MCS0402MD1002BE100" 0402L 172.383,34.14 r180 top value=10.0k
R140 "CRCW0402309RFKED" 0402L 171.883,36.513 r180 top value=309
R141 "MCS0402MD1002BE100" 0402L 171.9,35.5 r180 top value=10.0k
R142 "ERA-2AEB153X" 0402L 174.85,36.013 r90 top value=15.0k
R143 "CRCW040230K0FKED" 0402L 97.5,104.5 r0 top value=30.0k
R144 "RT0603BRD0715K6L" 0603 158.784,49.1 r90 top value=15.6k
R145 "MCS0402MD1002BE100" 0402L 161.611,49.104 r90 top value=10.0k
R146 "ERJ-2RKF33R0X" 0402L 150.084,33.8 r270 top value=33.0
R147 "MCS0402MD1002BE100" 0402L 162.774,49.109 r90 top value=10.0k
R148 "RT0603BRD0715K6L" 0603 164.392,46.084 r90 top value=15.6k
R149 "RT0603BRD0715K6L" 0603 155.275,52.475 r0 top value=15.6k
R150 "MCS0402MD1002BE100" 0402L 152.504,52 r180 top value=10.0k
R151 "ERJ-2RKF33R0X" 0402L 148.584,33.8 r270 top value=33.0
R152 "MCS0402MD1002BE100" 0402L 152.504,50.663 r180 top value=10.0k
R153 "RT0603BRD0715K6L" 0603 153.679,49.051 r0 top value=15.6k
R154 "RT0603BRD0715K6L" 0603 155.857,35.784 r0 top value=15.6k
R155 "MCS0402MD1002BE100" 0402L 164.684,41.6 r0 top value=10.0k
R156 "ERJ-2RKF33R0X" 0402L 151.64,33.775 r270 top value=33.0
R157 "MCS0402MD1002BE100" 0402L 164.684,42.6 r0 top value=10.0k
R158 "RT0603BRD0715K6L" 0603 152.504,35.741 r0 top value=15.6k
R159 "RT0603BRD0715K6L" 0603 159.084,35.8 r180 top value=15.6k
R160 "MCS0402MD1002BE100" 0402L 159.949,33.475 r270 top value=10.0k
R161 "ERJ-2RKF33R0X" 0402L 164.884,36.9 r270 top value=33.0
R162 "MCS0402MD1002BE100" 0402L 163.184,33.4 r270 top value=10.0k
R163 "RT0603BRD0715K6L" 0603 163.124,36.509 r270 top value=15.6k
R164 "CRCW040210R0JNED" 0402L 169.568,66.466 r0 top value=10
R165 "ERJ-2RKF33R0X" 0402L 158.968,62.516 r180 top value=33.0
R166 "ERJ-2RKF33R0X" 0402L 158.968,58.766 r180 top value=33.0
R167 "ERJ-2RKF33R0X" 0402L 167.668,58.966 r180 top value=33.0
R168 "ERJ-2RKF33R0X" 0402L 173.968,62.866 r90 top value=33.0
R169 "CRCW040210K0FKED" 0402L 163.368,66.566 r270 top value=10.0k
R170 "CRCW040210K0FKED" 0402L 158.968,65.016 r0 top value=10.0k
R171 "CRCW040210K0FKED" 0402L 158.968,61.266 r0 top value=10.0k
R172 "CRCW040210K0FKED" 0402L 171.468,59.766 r180 top value=10.0k
R173 "CRCW040210K0FKED" 0402L 171.468,64.766 r180 top value=10.0k
R174 "CRCW040210R0JNED" 0402L 152.963,67.112 r90 top value=10
R175 "CRCW040210R0JNED" 0402L 212.3,22.5 r0 top value=10
R176 "ERJ-2RKF33R0X" 0402L 144.063,62.712 r180 top value=33.0
R177 "ERJ-2RKF33R0X" 0402L 220.1,26.8 r0 top value=33.0
R178 "ERJ-2RKF33R0X" 0402L 144.063,59.612 r180 top value=33.0
R179 "ERJ-2RKF33R0X" 0402L 220.2,30.3 r0 top value=33.0
R180 "ERJ-2RKF33R0X" 0402L 155.563,59.362 r0 top value=33.0
R181 "ERJ-2RKF33R0X" 0402L 208.2,30.8 r180 top value=33.0
R182 "ERJ-2RKF33R0X" 0402L 155.563,62.362 r0 top value=33.0
R183 "ERJ-2RKF33R0X" 0402L 208.2,27.4 r180 top value=33.0
R184 "CRCW040210K0FKED" 0402L 146.411,67.221 r0 top value=10.0k
R185 "CRCW040210K0FKED" 0402L 144.063,64.712 r0 top value=10.0k
R186 "CRCW040210K0FKED" 0402L 144.063,60.612 r0 top value=10.0k
R187 "CRCW040210K0FKED" 0402L 155.563,60.362 r180 top value=10.0k
R188 "CRCW040210K0FKED" 0402L 155.563,63.362 r180 top value=10.0k
R189 "CRCW040210K0FKED" 0402L 214.9,23.8 r0 top value=10.0k
R190 "CRCW040210K0FKED" 0402L 220.216,24.369 r180 top value=10.0k
R191 "CRCW040210K0FKED" 0402L 220.2,28.2 r180 top value=10.0k
R192 "CRCW040210K0FKED" 0402L 208.2,29.6 r0 top value=10.0k
R193 "CRCW040210K0FKED" 0402L 208.2,26.1 r0 top value=10.0k
R194 "CRCW040210R0JNED" 0402L 224.8,24.7 r180 top value=10
R195 "ERJ-2RKF33R0X" 0402L 235.4,28.4 r0 top value=33.0
R196 "ERJ-2RKF33R0X" 0402L 234.7,32.6 r90 top value=33.0
R197 "ERJ-2RKF33R0X" 0402L 224.5,32 r90 top value=33.0
R198 "ERJ-2RKF33R0X" 0402L 223.7,27.9 r180 top value=33.0
R199 "CRCW040210K0FKED" 0402L 231.183,24.472 r0 top value=10.0k
R200 "CRCW040210K0FKED" 0402L 235.45,27.25 r180 top value=10.0k
R201 "CRCW040210K0FKED" 0402L 235.4,29.5 r180 top value=10.0k
R202 "CRCW040210K0FKED" 0402L 223.95,30.15 r0 top value=10.0k
R203 "CRCW040210K0FKED" 0402L 223.794,26.83 r0 top value=10.0k
R204 "RC0603FR-07470KL" 0603 179.391,6.246 r270 top value=470k
R205 "RC0603FR-0747KL" 0603 176.139,18.175 r180 top value=47.0k
R206 "RC0603FR-071K1L" 0603 170.729,9.175 r90 top value=1.10k
R207 "RC0603FR-075K6L" 0603 176.179,16.25 r0 top value=5.60k
R208 "RC0603FR-0711KL" 0603 179.391,9.725 r270 top value=11.0k
R209 "RC0603FR-0747KL" 0603 179.079,12.125 r0 top value=47.0k
R210 "RC0603FR-072KL" 0603 168.612,8.761 r270 top value=2.00k
R211 "RC0603FR-0747KL" 0603 177.9,7.6 r90 top value=47.0k
R212 "RC0603FR-0715KL" 0603 169.482,14.05 r270 top value=15.0k
R213 "RC0603FR-0754K9L" 0603 169.371,17.096 r0 top value=54.9k
R214 "RC0603FR-07220KL" 0603 169.858,21.396 r270 top value=220k
R215 "RC0603FR-0730KL" 0603 166.383,21.425 r90 top value=30.0k
R216 "RG1608P-103-B-T5" 0603 164.538,17.971 r90 top value=10.0k
R217 "CRCW0603499RFKEAC" 0603 156.283,20.55 r0 top value=499
R218 "RC0603FR-0730KL" 0603 162.608,21.396 r270 top value=30.0k
R219 "RC0603FR-0747KL" 0603 164.583,21.425 r90 top value=47.0k
R220 "FTR-K3AB012W-WG" FP-FTR-K3AB012W-WG_PTH_RELAY_30MM1_15MM7-MFG 238,217.75 r180 top
R221 "FTR-K3AB012W-WG" FP-FTR-K3AB012W-WG_PTH_RELAY_30MM1_15MM7-MFG 276,227 r225 top
R222 "FTR-K3AB012W-WG" FP-FTR-K3AB012W-WG_PTH_RELAY_30MM1_15MM7-MFG 201,235 r135 top
R223 "FTR-K3AB012W-WG" FP-FTR-K3AB012W-WG_PTH_RELAY_30MM1_15MM7-MFG 291.25,261 r270 top
R224 "CRCW040210K0FKED" 0402 288.1,35.2 r90 top value=10.0k
R225 "RCS06030000Z0EA" 0603 261.75,18.75 r90 top value=0
R226 "RT0603DRE0759R7L" 0603 265.95,16.25 r180 top value=59.7
R227 "RT0603DRE0759R7L" 0603 270.05,16.25 r180 top value=59.7
R228 "RCS06030000Z0EA" 0603 255.25,18.75 r90 top value=0
R229_L1 "RC0603FR-0733KL" 0603 57.5,144.5 r270 bottom value=33.0k (schematic designator R229)
R229_L2 "RC0603FR-0733KL" 0603 140.9,129.5 r270 bottom value=33.0k (schematic designator R229)
R229_L3 "RC0603FR-0733KL" 0603 227,102 r270 bottom value=33.0k (schematic designator R229)
R229_N "RC0603FR-0733KL" 0603 92,28 r0 bottom value=33.0k (schematic designator R229)
R230_L1 "RC0603FR-0733KL" 0603 73,144 r270 bottom value=33.0k (schematic designator R230)
R230_L2 "RC0603FR-0733KL" 0603 156.5,129 r270 bottom value=33.0k (schematic designator R230)
R230_L3 "RC0603FR-0733KL" 0603 242.5,101 r270 bottom value=33.0k (schematic designator R230)
R230_N "RC0603FR-0733KL" 0603 92.5,43.5 r0 bottom value=33.0k (schematic designator R230)
R231_L1 "RC0603FR-0733KL" 0603 78.5,165 r270 bottom value=33.0k (schematic designator R231)
R231_L2 "RC0603FR-0733KL" 0603 162,150 r270 bottom value=33.0k (schematic designator R231)
R231_L3 "RC0603FR-0733KL" 0603 248,122 r270 bottom value=33.0k (schematic designator R231)
R231_N "RC0603FR-0733KL" 0603 71.5,49 r0 bottom value=33.0k (schematic designator R231)
R232_L1 "CRCW060333R0JNEA" 0603 74.5,144 r90 bottom value=33 (schematic designator R232)
R232_L2 "CRCW060333R0JNEA" 0603 158,129 r90 bottom value=33 (schematic designator R232)
R232_L3 "CRCW060333R0JNEA" 0603 244,101 r90 bottom value=33 (schematic designator R232)
R232_N "CRCW060333R0JNEA" 0603 92.5,45 r180 bottom value=33 (schematic designator R232)
R233 "RC0603JR-07680RL" 0603 271,63 r180 top value=680
R234 "RC0603JR-07680RL" 0603 291.5,194.2 r90 top value=680
R235 "RC0603JR-07680RL" 0603 231.5,22 r0 top value=680
R236 "RGV3216P-1004-B-T1" FP-RGV3216P-1004-B-T1_1206-MFG 132,290.5 r90 bottom value=1M
R237 "RGV3216P-1004-B-T1" FP-RGV3216P-1004-B-T1_1206-MFG 135.5,287 r90 bottom value=1M
R238 "RGV3216P-1004-B-T1" FP-RGV3216P-1004-B-T1_1206-MFG 132,283.5 r90 bottom value=1M
R239 "RGV3216P-1004-B-T1" FP-RGV3216P-1004-B-T1_1206-MFG 135.5,280 r90 bottom value=1M
R240 "RG1608P-103-B-T5" 0603 137.74,265.5 r180 bottom value=10.0k
R241 "RGV3216P-1004-B-T1" FP-RGV3216P-1004-B-T1_1206-MFG 116,290.5 r90 bottom value=1M
R242 "RGV3216P-1004-B-T1" FP-RGV3216P-1004-B-T1_1206-MFG 119.5,287 r90 bottom value=1M
R243 "RGV3216P-1004-B-T1" FP-RGV3216P-1004-B-T1_1206-MFG 116,283.2 r90 bottom value=1M
R244 "RGV3216P-1004-B-T1" FP-RGV3216P-1004-B-T1_1206-MFG 119.5,279.5 r90 bottom value=1M
R245 "RG1608P-103-B-T5" 0603 122,265.5 r0 bottom value=10.0k
R246 "RGV3216P-1004-B-T1" FP-RGV3216P-1004-B-T1_1206-MFG 100,290.5 r90 bottom value=1M
R247 "RGV3216P-1004-B-T1" FP-RGV3216P-1004-B-T1_1206-MFG 103.5,287 r90 bottom value=1M
R248 "RGV3216P-1004-B-T1" FP-RGV3216P-1004-B-T1_1206-MFG 100,283 r90 bottom value=1M
R249 "RGV3216P-1004-B-T1" FP-RGV3216P-1004-B-T1_1206-MFG 103.5,279.5 r90 bottom value=1M
R250 "RG1608P-103-B-T5" 0603 108.5,265.5 r0 bottom value=10.0k
R278_L1 "CRCW060333R0JNEA" 0603 35.98,112.792 r90 top value=33 (schematic designator R278)
R278_L2 "CRCW060333R0JNEA" 0603 119.48,97.792 r90 top value=33 (schematic designator R278)
R278_L3 "CRCW060333R0JNEA" 0603 205.48,69.792 r90 top value=33 (schematic designator R278)
R278_N "CRCW060333R0JNEA" 0603 123.708,6.48 r180 top value=33 (schematic designator R278)
R279_L1 "CRCW060333R0JNEA" 0603 38.5,129.773 r90 bottom value=33 (schematic designator R279)
R279_L2 "CRCW060333R0JNEA" 0603 122,114.773 r90 bottom value=33 (schematic designator R279)
R279_L3 "CRCW060333R0JNEA" 0603 208,86.773 r90 bottom value=33 (schematic designator R279)
R279_N "CRCW060333R0JNEA" 0603 106.727,9 r180 bottom value=33 (schematic designator R279)
R281_L1 "CRCW1206100RFKEAHP" 1206 43,148 r180 bottom value=100 (schematic designator R281)
R281_L2 "CRCW1206100RFKEAHP" 1206 126.5,133 r180 bottom value=100 (schematic designator R281)
R281_L3 "CRCW1206100RFKEAHP" 1206 212.5,105 r180 bottom value=100 (schematic designator R281)
R281_N "CRCW1206100RFKEAHP" 1206 88.5,13.5 r270 bottom value=100 (schematic designator R281)
R282_L1 "CRCW1206100RFKEAHP" 1206 43,144.5 r180 bottom value=100 (schematic designator R282)
R282_L2 "CRCW1206100RFKEAHP" 1206 126.5,129.5 r180 bottom value=100 (schematic designator R282)
R282_L3 "CRCW1206100RFKEAHP" 1206 212.5,101.5 r180 bottom value=100 (schematic designator R282)
R282_N "CRCW1206100RFKEAHP" 1206 92,13.5 r270 bottom value=100 (schematic designator R282)
R284_L1 "CRCW060310K0FKEA" 0603 38.5,112.755 r180 top value=10.0k (schematic designator R284)
R284_L2 "CRCW060310K0FKEA" 0603 122,97.755 r180 top value=10.0k (schematic designator R284)
R284_L3 "CRCW060310K0FKEA" 0603 208,69.755 r180 top value=10.0k (schematic designator R284)
R284_N "CRCW060310K0FKEA" 0603 123.745,9 r270 top value=10.0k (schematic designator R284)
R285_L1 "RC0603FR-0710KL" 0603 37.775,133.74 r270 bottom value=10.0k (schematic designator R285)
R285_L2 "RC0603FR-0710KL" 0603 121.275,118.74 r270 bottom value=10.0k (schematic designator R285)
R285_L3 "RC0603FR-0710KL" 0603 207.275,90.74 r270 bottom value=10.0k (schematic designator R285)
R285_N "RC0603FR-0710KL" 0603 102.76,8.275 r0 bottom value=10.0k (schematic designator R285)
R286_L1 "CRCW06032K70JNEA" 0603 43.704,130.169 r270 bottom value=2.7k (schematic designator R286)
R286_L2 "CRCW06032K70JNEA" 0603 127.204,115.169 r270 bottom value=2.7k (schematic designator R286)
R286_L3 "CRCW06032K70JNEA" 0603 213.204,87.169 r270 bottom value=2.7k (schematic designator R286)
R286_N "CRCW06032K70JNEA" 0603 106.331,14.204 r0 bottom value=2.7k (schematic designator R286)
R287_L1 "CRCW060310K0FKEA" 0603 40.263,111.083 r180 top value=10.0k (schematic designator R287)
R287_L2 "CRCW060310K0FKEA" 0603 123.763,96.083 r180 top value=10.0k (schematic designator R287)
R287_L3 "CRCW060310K0FKEA" 0603 209.763,68.083 r180 top value=10.0k (schematic designator R287)
R287_N "CRCW060310K0FKEA" 0603 125.417,10.763 r270 top value=10.0k (schematic designator R287)
R288_L1 "RT0603DRE071KL" 0603 41.672,130.169 r90 bottom value=1.00k (schematic designator R288)
R288_L2 "RT0603DRE071KL" 0603 125.172,115.169 r90 bottom value=1.00k (schematic designator R288)
R288_L3 "RT0603DRE071KL" 0603 211.172,87.169 r90 bottom value=1.00k (schematic designator R288)
R288_N "RT0603DRE071KL" 0603 106.331,12.172 r180 bottom value=1.00k (schematic designator R288)
R289_L1 "RC0603JR-078K2L" 0603 41.813,133.795 r180 bottom value=8.2k (schematic designator R289)
R289_L2 "RC0603JR-078K2L" 0603 125.313,118.795 r180 bottom value=8.2k (schematic designator R289)
R289_L3 "RC0603JR-078K2L" 0603 211.313,90.795 r180 bottom value=8.2k (schematic designator R289)
R289_N "RC0603JR-078K2L" 0603 102.705,12.313 r270 bottom value=8.2k (schematic designator R289)
R290_L1 "RC0603JR-07560RL" 0603 45.547,133.24 r90 top value=560 (schematic designator R290)
R290_L2 "RC0603JR-07560RL" 0603 129.047,118.24 r90 top value=560 (schematic designator R290)
R290_L3 "RC0603JR-07560RL" 0603 215.047,90.24 r90 top value=560 (schematic designator R290)
R290_N "RC0603JR-07560RL" 0603 103.26,16.047 r180 top value=560 (schematic designator R290)
R291_L1 "CRCW060333R0JNEA" 0603 52.66,112.911 r90 top value=33 (schematic designator R291)
R291_L2 "CRCW060333R0JNEA" 0603 136.16,97.911 r90 top value=33 (schematic designator R291)
R291_L3 "CRCW060333R0JNEA" 0603 222.16,69.911 r90 top value=33 (schematic designator R291)
R291_N "CRCW060333R0JNEA" 0603 123.589,23.16 r180 top value=33 (schematic designator R291)
R292_L1 "CRCW060333R0JNEA" 0603 53.385,129.882 r90 bottom value=33 (schematic designator R292)
R292_L2 "CRCW060333R0JNEA" 0603 136.885,114.882 r90 bottom value=33 (schematic designator R292)
R292_L3 "CRCW060333R0JNEA" 0603 222.885,86.882 r90 bottom value=33 (schematic designator R292)
R292_N "CRCW060333R0JNEA" 0603 106.618,23.885 r180 bottom value=33 (schematic designator R292)
R293_L1 "ERJ-2RKF33R0X" 0402L 68,108 r180 top value=33.0 (schematic designator R293)
R293_L2 "ERJ-2RKF33R0X" 0402L 151.5,93.5 r180 top value=33.0 (schematic designator R293)
R293_L3 "ERJ-2RKF33R0X" 0402L 237.5,65.5 r180 top value=33.0 (schematic designator R293)
R293_N "ERJ-2RKF33R0X" 0402L 128,38.5 r270 top value=33.0 (schematic designator R293)
R295_L1 "CRCW060310K0FKEA" 0603 55.75,113.063 r90 top value=10.0k (schematic designator R295)
R295_L2 "CRCW060310K0FKEA" 0603 139.25,98.063 r90 top value=10.0k (schematic designator R295)
R295_L3 "CRCW060310K0FKEA" 0603 225.25,70.063 r90 top value=10.0k (schematic designator R295)
R295_N "CRCW060310K0FKEA" 0603 123.437,26.25 r180 top value=10.0k (schematic designator R295)
R296_L1 "RC0603FR-0710KL" 0603 53.93,133.657 r270 bottom value=10.0k (schematic designator R296)
R296_L2 "RC0603FR-0710KL" 0603 137.43,118.657 r270 bottom value=10.0k (schematic designator R296)
R296_L3 "RC0603FR-0710KL" 0603 223.43,90.657 r270 bottom value=10.0k (schematic designator R296)
R296_N "RC0603FR-0710KL" 0603 102.843,24.43 r0 bottom value=10.0k (schematic designator R296)
R297_L1 "CRCW06032K70JNEA" 0603 59.456,129.207 r270 bottom value=2.7k (schematic designator R297)
R297_L2 "CRCW06032K70JNEA" 0603 142.956,114.207 r270 bottom value=2.7k (schematic designator R297)
R297_L3 "CRCW06032K70JNEA" 0603 228.956,86.207 r270 bottom value=2.7k (schematic designator R297)
R297_N "CRCW06032K70JNEA" 0603 107.293,29.956 r0 bottom value=2.7k (schematic designator R297)
R298_L1 "CRCW060310K0FKEA" 0603 56.225,110.583 r180 top value=10.0k (schematic designator R298)
R298_L2 "CRCW060310K0FKEA" 0603 139.725,95.583 r180 top value=10.0k (schematic designator R298)
R298_L3 "CRCW060310K0FKEA" 0603 225.725,67.583 r180 top value=10.0k (schematic designator R298)
R298_N "CRCW060310K0FKEA" 0603 125.917,26.725 r270 top value=10.0k (schematic designator R298)
R299_L1 "RT0603DRE071KL" 0603 57.736,129.207 r90 bottom value=1.00k (schematic designator R299)
R299_L2 "RT0603DRE071KL" 0603 141.236,114.207 r90 bottom value=1.00k (schematic designator R299)
R299_L3 "RT0603DRE071KL" 0603 227.236,86.207 r90 bottom value=1.00k (schematic designator R299)
R299_N "RT0603DRE071KL" 0603 107.293,28.236 r180 bottom value=1.00k (schematic designator R299)
R300_L1 "RC0603JR-078K2L" 0603 58.344,134.875 r180 top value=8.2k (schematic designator R300)
R300_L2 "RC0603JR-078K2L" 0603 141.844,119.875 r180 top value=8.2k (schematic designator R300)
R300_L3 "RC0603JR-078K2L" 0603 227.844,91.875 r180 top value=8.2k (schematic designator R300)
R300_N "RC0603JR-078K2L" 0603 101.625,28.844 r270 top value=8.2k (schematic designator R300)
R301_L1 "RC0603JR-07560RL" 0603 61.244,133.534 r90 top value=560 (schematic designator R301)
R301_L2 "RC0603JR-07560RL" 0603 144.744,118.534 r90 top value=560 (schematic designator R301)
R301_L3 "RC0603JR-07560RL" 0603 230.744,90.534 r90 top value=560 (schematic designator R301)
R301_N "RC0603JR-07560RL" 0603 102.966,31.744 r180 top value=560 (schematic designator R301)
R302_L1 "CRCW060333R0JNEA" 0603 74.5,111.955 r90 top value=33 (schematic designator R302)
R302_L2 "CRCW060333R0JNEA" 0603 158,96.955 r90 top value=33 (schematic designator R302)
R302_L3 "CRCW060333R0JNEA" 0603 244,68.955 r90 top value=33 (schematic designator R302)
R302_N "CRCW060333R0JNEA" 0603 124.545,45 r180 top value=33 (schematic designator R302)
R303_L1 "CRCW060333R0JNEA" 0603 75.264,128.666 r90 bottom value=33 (schematic designator R303)
R303_L2 "CRCW060333R0JNEA" 0603 158.764,113.666 r90 bottom value=33 (schematic designator R303)
R303_L3 "CRCW060333R0JNEA" 0603 244.764,85.666 r90 bottom value=33 (schematic designator R303)
R303_N "CRCW060333R0JNEA" 0603 107.834,45.764 r180 bottom value=33 (schematic designator R303)
R305_L1 "CRCW060310K0FKEA" 0603 77.429,111.984 r90 top value=10.0k (schematic designator R305)
R305_L2 "CRCW060310K0FKEA" 0603 160.929,96.984 r90 top value=10.0k (schematic designator R305)
R305_L3 "CRCW060310K0FKEA" 0603 246.929,68.984 r90 top value=10.0k (schematic designator R305)
R305_N "CRCW060310K0FKEA" 0603 124.516,47.929 r180 top value=10.0k (schematic designator R305)
R306_L1 "RC0603FR-0710KL" 0603 76.397,132.233 r270 bottom value=10.0k (schematic designator R306)
R306_L2 "RC0603FR-0710KL" 0603 159.897,117.233 r270 bottom value=10.0k (schematic designator R306)
R306_L3 "RC0603FR-0710KL" 0603 245.897,89.233 r270 bottom value=10.0k (schematic designator R306)
R306_N "RC0603FR-0710KL" 0603 104.267,46.897 r0 bottom value=10.0k (schematic designator R306)
R307_L1 "CRCW06032K70JNEA" 0603 81.758,128.907 r270 bottom value=2.7k (schematic designator R307)
R307_L2 "CRCW06032K70JNEA" 0603 165.258,113.907 r270 bottom value=2.7k (schematic designator R307)
R307_L3 "CRCW06032K70JNEA" 0603 251.258,85.907 r270 bottom value=2.7k (schematic designator R307)
R307_N "CRCW06032K70JNEA" 0603 107.593,52.258 r0 bottom value=2.7k (schematic designator R307)
R308_L1 "CRCW060310K0FKEA" 0603 76.63,109.517 r180 top value=10.0k (schematic designator R308)
R308_L2 "CRCW060310K0FKEA" 0603 160.13,94.517 r180 top value=10.0k (schematic designator R308)
R308_L3 "CRCW060310K0FKEA" 0603 246.13,66.517 r180 top value=10.0k (schematic designator R308)
R308_N "CRCW060310K0FKEA" 0603 126.983,47.13 r270 top value=10.0k (schematic designator R308)
R309_L1 "RT0603DRE071KL" 0603 80.36,128.907 r90 bottom value=1.00k (schematic designator R309)
R309_L2 "RT0603DRE071KL" 0603 163.86,113.907 r90 bottom value=1.00k (schematic designator R309)
R309_L3 "RT0603DRE071KL" 0603 249.86,85.907 r90 bottom value=1.00k (schematic designator R309)
R309_N "RT0603DRE071KL" 0603 107.593,50.86 r180 bottom value=1.00k (schematic designator R309)
R310_L1 "RC0603JR-078K2L" 0603 81.283,133.942 r180 top value=8.2k (schematic designator R310)
R310_L2 "RC0603JR-078K2L" 0603 164.783,118.942 r180 top value=8.2k (schematic designator R310)
R310_L3 "RC0603JR-078K2L" 0603 250.783,90.942 r180 top value=8.2k (schematic designator R310)
R310_N "RC0603JR-078K2L" 0603 102.558,51.783 r270 top value=8.2k (schematic designator R310)
R311_L1 "RC0603JR-07560RL" 0603 84,132.784 r90 top value=560 (schematic designator R311)
R311_L2 "RC0603JR-07560RL" 0603 167.5,117.784 r90 top value=560 (schematic designator R311)
R311_L3 "RC0603JR-07560RL" 0603 253.5,89.784 r90 top value=560 (schematic designator R311)
R311_N "RC0603JR-07560RL" 0603 103.716,54.5 r180 top value=560 (schematic designator R311)
R312_L1 "TNPV0805680KBEEA" FP-TNPV0805680KBEEA_0805-MFG 68,132.5 r90 top value=680k (schematic designator R312)
R312_L2 "TNPV0805680KBEEA" FP-TNPV0805680KBEEA_0805-MFG 151.5,117.5 r90 top value=680k (schematic designator R312)
R312_L3 "TNPV0805680KBEEA" FP-TNPV0805680KBEEA_0805-MFG 237.5,89.5 r90 top value=680k (schematic designator R312)
R312_N "TNPV0805680KBEEA" FP-TNPV0805680KBEEA_0805-MFG 104,38.5 r180 top value=680k (schematic designator R312)
R313_L1 "TNPV0805680KBEEA" FP-TNPV0805680KBEEA_0805-MFG 66.5,135.05 r90 top value=680k (schematic designator R313)
R313_L2 "TNPV0805680KBEEA" FP-TNPV0805680KBEEA_0805-MFG 150,120.05 r90 top value=680k (schematic designator R313)
R313_L3 "TNPV0805680KBEEA" FP-TNPV0805680KBEEA_0805-MFG 236,92.05 r90 top value=680k (schematic designator R313)
R313_N "TNPV0805680KBEEA" FP-TNPV0805680KBEEA_0805-MFG 101.45,37 r180 top value=680k (schematic designator R313)
R314_L1 "TNPV0805680KBEEA" FP-TNPV0805680KBEEA_0805-MFG 65.5,137.5 r180 top value=680k (schematic designator R314)
R314_L2 "TNPV0805680KBEEA" FP-TNPV0805680KBEEA_0805-MFG 149,122.5 r180 top value=680k (schematic designator R314)
R314_L3 "TNPV0805680KBEEA" FP-TNPV0805680KBEEA_0805-MFG 235,94.5 r180 top value=680k (schematic designator R314)
R314_N "TNPV0805680KBEEA" FP-TNPV0805680KBEEA_0805-MFG 99,36 r270 top value=680k (schematic designator R314)
R315_L1 "RT0603BRE078KL" FP-RT0603BRE078KL_0603-MFG 67.9,130 r0 top value=8k (schematic designator R315)
R315_L2 "RT0603BRE078KL" FP-RT0603BRE078KL_0603-MFG 151.4,115 r0 top value=8k (schematic designator R315)
R315_L3 "RT0603BRE078KL" FP-RT0603BRE078KL_0603-MFG 237.4,87 r0 top value=8k (schematic designator R315)
R315_N "RT0603BRE078KL" FP-RT0603BRE078KL_0603-MFG 106.5,38.5 r90 top value=8k (schematic designator R315)
R316_L1 "CRCW060333R0JNEA" 0603 90.725,111.955 r90 top value=33 (schematic designator R316)
R316_L2 "CRCW060333R0JNEA" 0603 174.225,96.955 r90 top value=33 (schematic designator R316)
R316_L3 "CRCW060333R0JNEA" 0603 260.225,68.955 r90 top value=33 (schematic designator R316)
R316_N "CRCW060333R0JNEA" 0603 124.545,61.225 r180 top value=33 (schematic designator R316)
R317_L1 "CRCW060333R0JNEA" 0603 91.2,128.998 r90 bottom value=33 (schematic designator R317)
R317_L2 "CRCW060333R0JNEA" 0603 174.7,113.998 r90 bottom value=33 (schematic designator R317)
R317_L3 "CRCW060333R0JNEA" 0603 260.7,85.998 r90 bottom value=33 (schematic designator R317)
R317_N "CRCW060333R0JNEA" 0603 107.502,61.7 r180 bottom value=33 (schematic designator R317)
R319_L1 "CRCW1206100RFKEAHP" 1206 89.5,156 r180 bottom value=100 (schematic designator R319)
R319_L2 "CRCW1206100RFKEAHP" 1206 173,141 r180 bottom value=100 (schematic designator R319)
R319_L3 "CRCW1206100RFKEAHP" 1206 259,113 r180 bottom value=100 (schematic designator R319)
R319_N "CRCW1206100RFKEAHP" 1206 80.5,60 r270 bottom value=100 (schematic designator R319)
R320_L1 "CRCW1206100RFKEAHP" 1206 89.5,153 r180 bottom value=100 (schematic designator R320)
R320_L2 "CRCW1206100RFKEAHP" 1206 173,138 r180 bottom value=100 (schematic designator R320)
R320_L3 "CRCW1206100RFKEAHP" 1206 259,110 r180 bottom value=100 (schematic designator R320)
R320_N "CRCW1206100RFKEAHP" 1206 83.5,60 r270 bottom value=100 (schematic designator R320)
R322_L1 "CRCW060310K0FKEA" 0603 93.685,112.18 r90 top value=10.0k (schematic designator R322)
R322_L2 "CRCW060310K0FKEA" 0603 177.185,97.18 r90 top value=10.0k (schematic designator R322)
R322_L3 "CRCW060310K0FKEA" 0603 263.185,69.18 r90 top value=10.0k (schematic designator R322)
R322_N "CRCW060310K0FKEA" 0603 124.32,64.185 r180 top value=10.0k (schematic designator R322)
R323_L1 "RC0603FR-0710KL" 0603 90.768,132.309 r270 bottom value=10.0k (schematic designator R323)
R323_L2 "RC0603FR-0710KL" 0603 174.268,117.309 r270 bottom value=10.0k (schematic designator R323)
R323_L3 "RC0603FR-0710KL" 0603 260.268,89.309 r270 bottom value=10.0k (schematic designator R323)
R323_N "RC0603FR-0710KL" 0603 104.191,61.268 r0 bottom value=10.0k (schematic designator R323)
R324_L1 "CRCW06032K70JNEA" 0603 96.476,128.823 r270 bottom value=2.7k (schematic designator R324)
R324_L2 "CRCW06032K70JNEA" 0603 179.976,113.823 r270 bottom value=2.7k (schematic designator R324)
R324_L3 "CRCW06032K70JNEA" 0603 265.976,85.823 r270 bottom value=2.7k (schematic designator R324)
R324_N "CRCW06032K70JNEA" 0603 107.677,66.976 r0 bottom value=2.7k (schematic designator R324)
R325_L1 "CRCW060310K0FKEA" 0603 96.5,109 r0 top value=10.0k (schematic designator R325)
R325_L2 "CRCW060310K0FKEA" 0603 180.069,94.709 r0 top value=10.0k (schematic designator R325)
R325_L3 "CRCW060310K0FKEA" 0603 266.069,66.709 r0 top value=10.0k (schematic designator R325)
R325_N "CRCW060310K0FKEA" 0603 126.791,67.069 r90 top value=10.0k (schematic designator R325)
R326_L1 "RT0603DRE071KL" 0603 94.726,128.823 r90 bottom value=1.00k (schematic designator R326)
R326_L2 "RT0603DRE071KL" 0603 178.226,113.823 r90 bottom value=1.00k (schematic designator R326)
R326_L3 "RT0603DRE071KL" 0603 264.226,85.823 r90 bottom value=1.00k (schematic designator R326)
R326_N "RT0603DRE071KL" 0603 107.677,65.226 r180 bottom value=1.00k (schematic designator R326)
R327_L1 "RC0603JR-078K2L" 0603 96.203,134.059 r180 top value=8.2k (schematic designator R327)
R327_L2 "RC0603JR-078K2L" 0603 179.703,119.059 r180 top value=8.2k (schematic designator R327)
R327_L3 "RC0603JR-078K2L" 0603 265.703,91.059 r180 top value=8.2k (schematic designator R327)
R327_N "RC0603JR-078K2L" 0603 102.441,66.703 r270 top value=8.2k (schematic designator R327)
R328_L1 "RC0603JR-07560RL" 0603 99.044,133.108 r90 top value=560 (schematic designator R328)
R328_L2 "RC0603JR-07560RL" 0603 182.544,118.108 r90 top value=560 (schematic designator R328)
R328_L3 "RC0603JR-07560RL" 0603 268.544,90.108 r90 top value=560 (schematic designator R328)
R328_N "RC0603JR-07560RL" 0603 103.392,69.544 r180 top value=560 (schematic designator R328)
R329 "CRCW0402200RJNED" 0402L 206.35,7.681 r0 top value=200
R330 "CRCW040210K0FKED" 0402L 206.304,6.626 r0 top value=10.0k
R331 "MCS0402MD1002BE100" 0402L 184.121,36.68 r0 top value=10.0k
R332 "CRCW040210R0JNED" 0402L 183.7,34.8 r90 top value=10
R333 "MCS0402MD1002BE100" 0402L 184.7,31.2 r0 top value=10.0k
R334 "RCS06030000Z0EA" 0603 187.3,47.6 r180 top value=0
TP1 "5011" Keystone5011 131,91.5 r90 top
TP2 "5011" Keystone5011 253,279 r0 top
TP3 "5011" Keystone5011 228,279 r0 top
TP4 "5011" Keystone5011 212,279 r0 top
TP5 "5010" Keystone5010 181.729,3.275 r180 top
TP6 "5011" Keystone5011 165.5,2 r180 top
TP7 "5011" Keystone5011 267,280 r0 top
TP8 "5011" Keystone5011 193,129 r0 top
TP9 "5011" Keystone5011 107.9,139.3 r0 top
TP10 "5011" Keystone5011 62,64.5 r180 top
TP11 "5011" Keystone5011 274.2,68.2 r0 top
TP12 "5011" Keystone5011 129.8,232.6 r0 top
TP13 "5011" Keystone5011 54,103.5 r0 top
TP14_L1 "S2751-46R" Harwin_S2751-46R 34.5,136.5 r90 top (schematic designator TP14)
TP14_L2 "S2751-46R" Harwin_S2751-46R 118,121.5 r90 top (schematic designator TP14)
TP14_L3 "S2751-46R" Harwin_S2751-46R 204,93.5 r90 top (schematic designator TP14)
TP14_N "S2751-46R" Harwin_S2751-46R 100,5 r180 top (schematic designator TP14)
TP15_L1 "S2751-46R" Harwin_S2751-46R 45.5,136.5 r90 top (schematic designator TP15)
TP15_L2 "S2751-46R" Harwin_S2751-46R 129,121.5 r90 top (schematic designator TP15)
TP15_L3 "S2751-46R" Harwin_S2751-46R 215,93.5 r90 top (schematic designator TP15)
TP15_N "S2751-46R" Harwin_S2751-46R 100,16 r180 top (schematic designator TP15)
TP16_L1 "S2751-46R" Harwin_S2751-46R 50.5,136.5 r90 top (schematic designator TP16)
TP16_L2 "S2751-46R" Harwin_S2751-46R 134,121.5 r90 top (schematic designator TP16)
TP16_L3 "S2751-46R" Harwin_S2751-46R 220,93.5 r90 top (schematic designator TP16)
TP16_N "S2751-46R" Harwin_S2751-46R 100,21 r180 top (schematic designator TP16)
TP17_L1 "S2751-46R" Harwin_S2751-46R 61,136.5 r90 top (schematic designator TP17)
TP17_L2 "S2751-46R" Harwin_S2751-46R 144.5,121.5 r90 top (schematic designator TP17)
TP17_L3 "S2751-46R" Harwin_S2751-46R 230.5,93.5 r90 top (schematic designator TP17)
TP17_N "S2751-46R" Harwin_S2751-46R 100,31.5 r180 top (schematic designator TP17)
TP18_L1 "S2751-46R" Harwin_S2751-46R 73,136 r90 top (schematic designator TP18)
TP18_L2 "S2751-46R" Harwin_S2751-46R 156.5,121 r90 top (schematic designator TP18)
TP18_L3 "S2751-46R" Harwin_S2751-46R 242.5,93 r90 top (schematic designator TP18)
TP18_N "S2751-46R" Harwin_S2751-46R 100.5,43.5 r180 top (schematic designator TP18)
TP19_L1 "S2751-46R" Harwin_S2751-46R 100,136.5 r90 top (schematic designator TP19)
TP19_L2 "S2751-46R" Harwin_S2751-46R 183.5,121.5 r90 top (schematic designator TP19)
TP19_L3 "S2751-46R" Harwin_S2751-46R 269.5,93.5 r90 top (schematic designator TP19)
TP19_N "S2751-46R" Harwin_S2751-46R 100,70.5 r180 top (schematic designator TP19)
TP20_L1 "S2751-46R" Harwin_S2751-46R 92,136.5 r90 top (schematic designator TP20)
TP20_L2 "S2751-46R" Harwin_S2751-46R 175.5,121.5 r90 top (schematic designator TP20)
TP20_L3 "S2751-46R" Harwin_S2751-46R 261.5,93.5 r90 top (schematic designator TP20)
TP20_N "S2751-46R" Harwin_S2751-46R 100,62.5 r180 top (schematic designator TP20)
TP21_L1 "S2751-46R" Harwin_S2751-46R 32.5,114 r90 top (schematic designator TP21)
TP21_L2 "S2751-46R" Harwin_S2751-46R 116,99 r90 top (schematic designator TP21)
TP21_L3 "S2751-46R" Harwin_S2751-46R 202,71 r90 top (schematic designator TP21)
TP21_N "S2751-46R" Harwin_S2751-46R 122.5,3 r180 top (schematic designator TP21)
TP22_L1 "S2751-46R" Harwin_S2751-46R 49,115 r90 top (schematic designator TP22)
TP22_L2 "S2751-46R" Harwin_S2751-46R 132.5,100 r90 top (schematic designator TP22)
TP22_L3 "S2751-46R" Harwin_S2751-46R 218.5,72 r90 top (schematic designator TP22)
TP22_N "S2751-46R" Harwin_S2751-46R 121.5,19.5 r180 top (schematic designator TP22)
TP23_L1 "S2751-46R" Harwin_S2751-46R 87,115 r90 top (schematic designator TP23)
TP23_L2 "S2751-46R" Harwin_S2751-46R 170.5,100 r90 top (schematic designator TP23)
TP23_L3 "S2751-46R" Harwin_S2751-46R 256.5,72 r90 top (schematic designator TP23)
TP23_N "S2751-46R" Harwin_S2751-46R 121.5,57.5 r180 top (schematic designator TP23)
TP24_L1 "S2751-46R" Harwin_S2751-46R 87,111 r90 top (schematic designator TP24)
TP24_L2 "S2751-46R" Harwin_S2751-46R 170.5,96 r90 top (schematic designator TP24)
TP24_L3 "S2751-46R" Harwin_S2751-46R 256.5,68 r90 top (schematic designator TP24)
TP24_N "S2751-46R" Harwin_S2751-46R 125.5,57.5 r180 top (schematic designator TP24)
TP25 "5011" Keystone5011 141.5,43 r0 top
TP26 "5011" Keystone5011 230,10.5 r0 top
TP27 "S2751-46R" Harwin_S2751-46R 266.5,40.5 r0 top
TP28 "S2751-46R" Harwin_S2751-46R 277,40 r0 top
TP29 "S2751-46R" Harwin_S2751-46R 276.5,56 r0 top
TP30 "S2751-46R" Harwin_S2751-46R 258.5,54.5 r0 top
TP31 "S2751-46R" Harwin_S2751-46R 173,40.5 r0 top
TP32 "S2751-46R" Harwin_S2751-46R 149,43.5 r180 top
TP33 "S2751-46R" Harwin_S2751-46R 145.5,38 r0 top
TP34 "S2751-46R" Harwin_S2751-46R 162.5,31 r180 top
TP35 "S2751-46R" Harwin_S2751-46R 165.5,34.5 r0 top
TP36 "S2751-46R" Harwin_S2751-46R 272,33 r180 top
TP37 "S2751-46R" Harwin_S2751-46R 261.5,40 r180 top
TP38 "S2751-46R" Harwin_S2751-46R 263,37.5 r180 top
TP39 "5010" Keystone5010 74,91 r0 top
TP40 "5011" Keystone5011 100,79.2 r0 top
U1 "ISOTMP35BEDFQRQ1" DFQ0007A-MFG 190.9,85.3 r90 top
U2 "TMCS1126B9AQDVGR" DVG0010A-MFG 89,243 r0 top
U3 "OPA4388IPWR" PW0014A-MFG 272.8,47.25 r0 top
U4 "TMCS1126B9AQDVGR" DVG0010A-MFG 106.209,221 r90 top
U5 "TMCS1126B9AQDVGR" DVG0010A-MFG 192,197.165 r90 top
U6 "TMCS1126B9AQDVGR" DVG0010A-MFG 32.5,103.706 r45 top
U7 "AMC0330RDWVR" DWV0008A-MFG 133.005,255.6 r270 top
U8 "AMC0330RDWVR" DWV0008A-MFG 119.135,255.55 r270 top
U9 "AMC0330RDWVR" DWV0008A-MFG 107.77,255.6 r270 top
U10 "UCC33421DHAR" DHA0016A-MFG 98.725,255.925 r90 top
U11 "AMC0381D" DFX0015A-MFG 83.854,97.929 r90 top
U12 "OPA2392DR" D0008A-MFG 179.1,34.775 r0 top
U13 "UCC33421DHAR" DHA0016A-MFG 95.438,97.929 r270 top
U14 "OPA4388IDR" D0014A-MFG 156.77,42.684 r270 top
U15 "SN74LVC126APWR" PW0014A_N 165.239,62.318 r0 top
U16 "SN74LVC126APWR" PW0014A_N 149.811,62.687 r0 top
U17 "SN74LVC126APWR" PW0014A_N 213.916,27.402 r180 top
U18 "SN74LVC126APWR" PW0014A_N 229.6,29.1 r180 top
U19 "TPS259474LRPWT" RPW0010A-MFG 175.979,10.925 r180 top
U20 "TVS1401DRBR" DRB0008A 180.729,14.85 r90 top
U21 "TPSM863252RDXR" RDX0007A-MFG 165.633,25.904 r180 top
U22 "TLV75533PDRVR" DRV0006A 149.05,16.826 r0 top
U23 "ISOW1044DFM" DFM0020A-MFG 287.695,26.9 r270 top
U24 "TSM24CADBZR" DBZ0003A-MFG 271.25,21.25 r90 top
U25 "TSM24CADBZR" DBZ0003A-MFG 265.25,21.25 r90 top
U26_L1 "LMG3522R030-Q1" RQS0052C-C01-MFG 53.725,174.125 r0 bottom (schematic designator U26)
U26_L2 "LMG3522R030-Q1" RQS0052C-C01-MFG 137.225,159.125 r0 bottom (schematic designator U26)
U26_L3 "LMG3522R030-Q1" RQS0052C-C01-MFG 223.225,131.125 r0 bottom (schematic designator U26)
U26_N "LMG3522R030-Q1" RQS0052C-C01-MFG 62.375,24.225 r90 bottom (schematic designator U26)
U27_L1 "LMG3522R030-Q1" RQS0052C-C01-MFG 58.275,154.025 r0 bottom (schematic designator U27)
U27_L2 "LMG3522R030-Q1" RQS0052C-C01-MFG 141.775,139.025 r0 bottom (schematic designator U27)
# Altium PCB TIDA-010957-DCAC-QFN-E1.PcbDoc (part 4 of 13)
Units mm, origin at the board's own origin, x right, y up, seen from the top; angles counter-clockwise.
Board outline 300 x 300 mm, 4 copper layers (Top Layer, Layer 1, Layer 2, Bottom Layer), stack 1.787 mm thick; 1286 components, 677 nets, 4169 pads, 3428 vias.

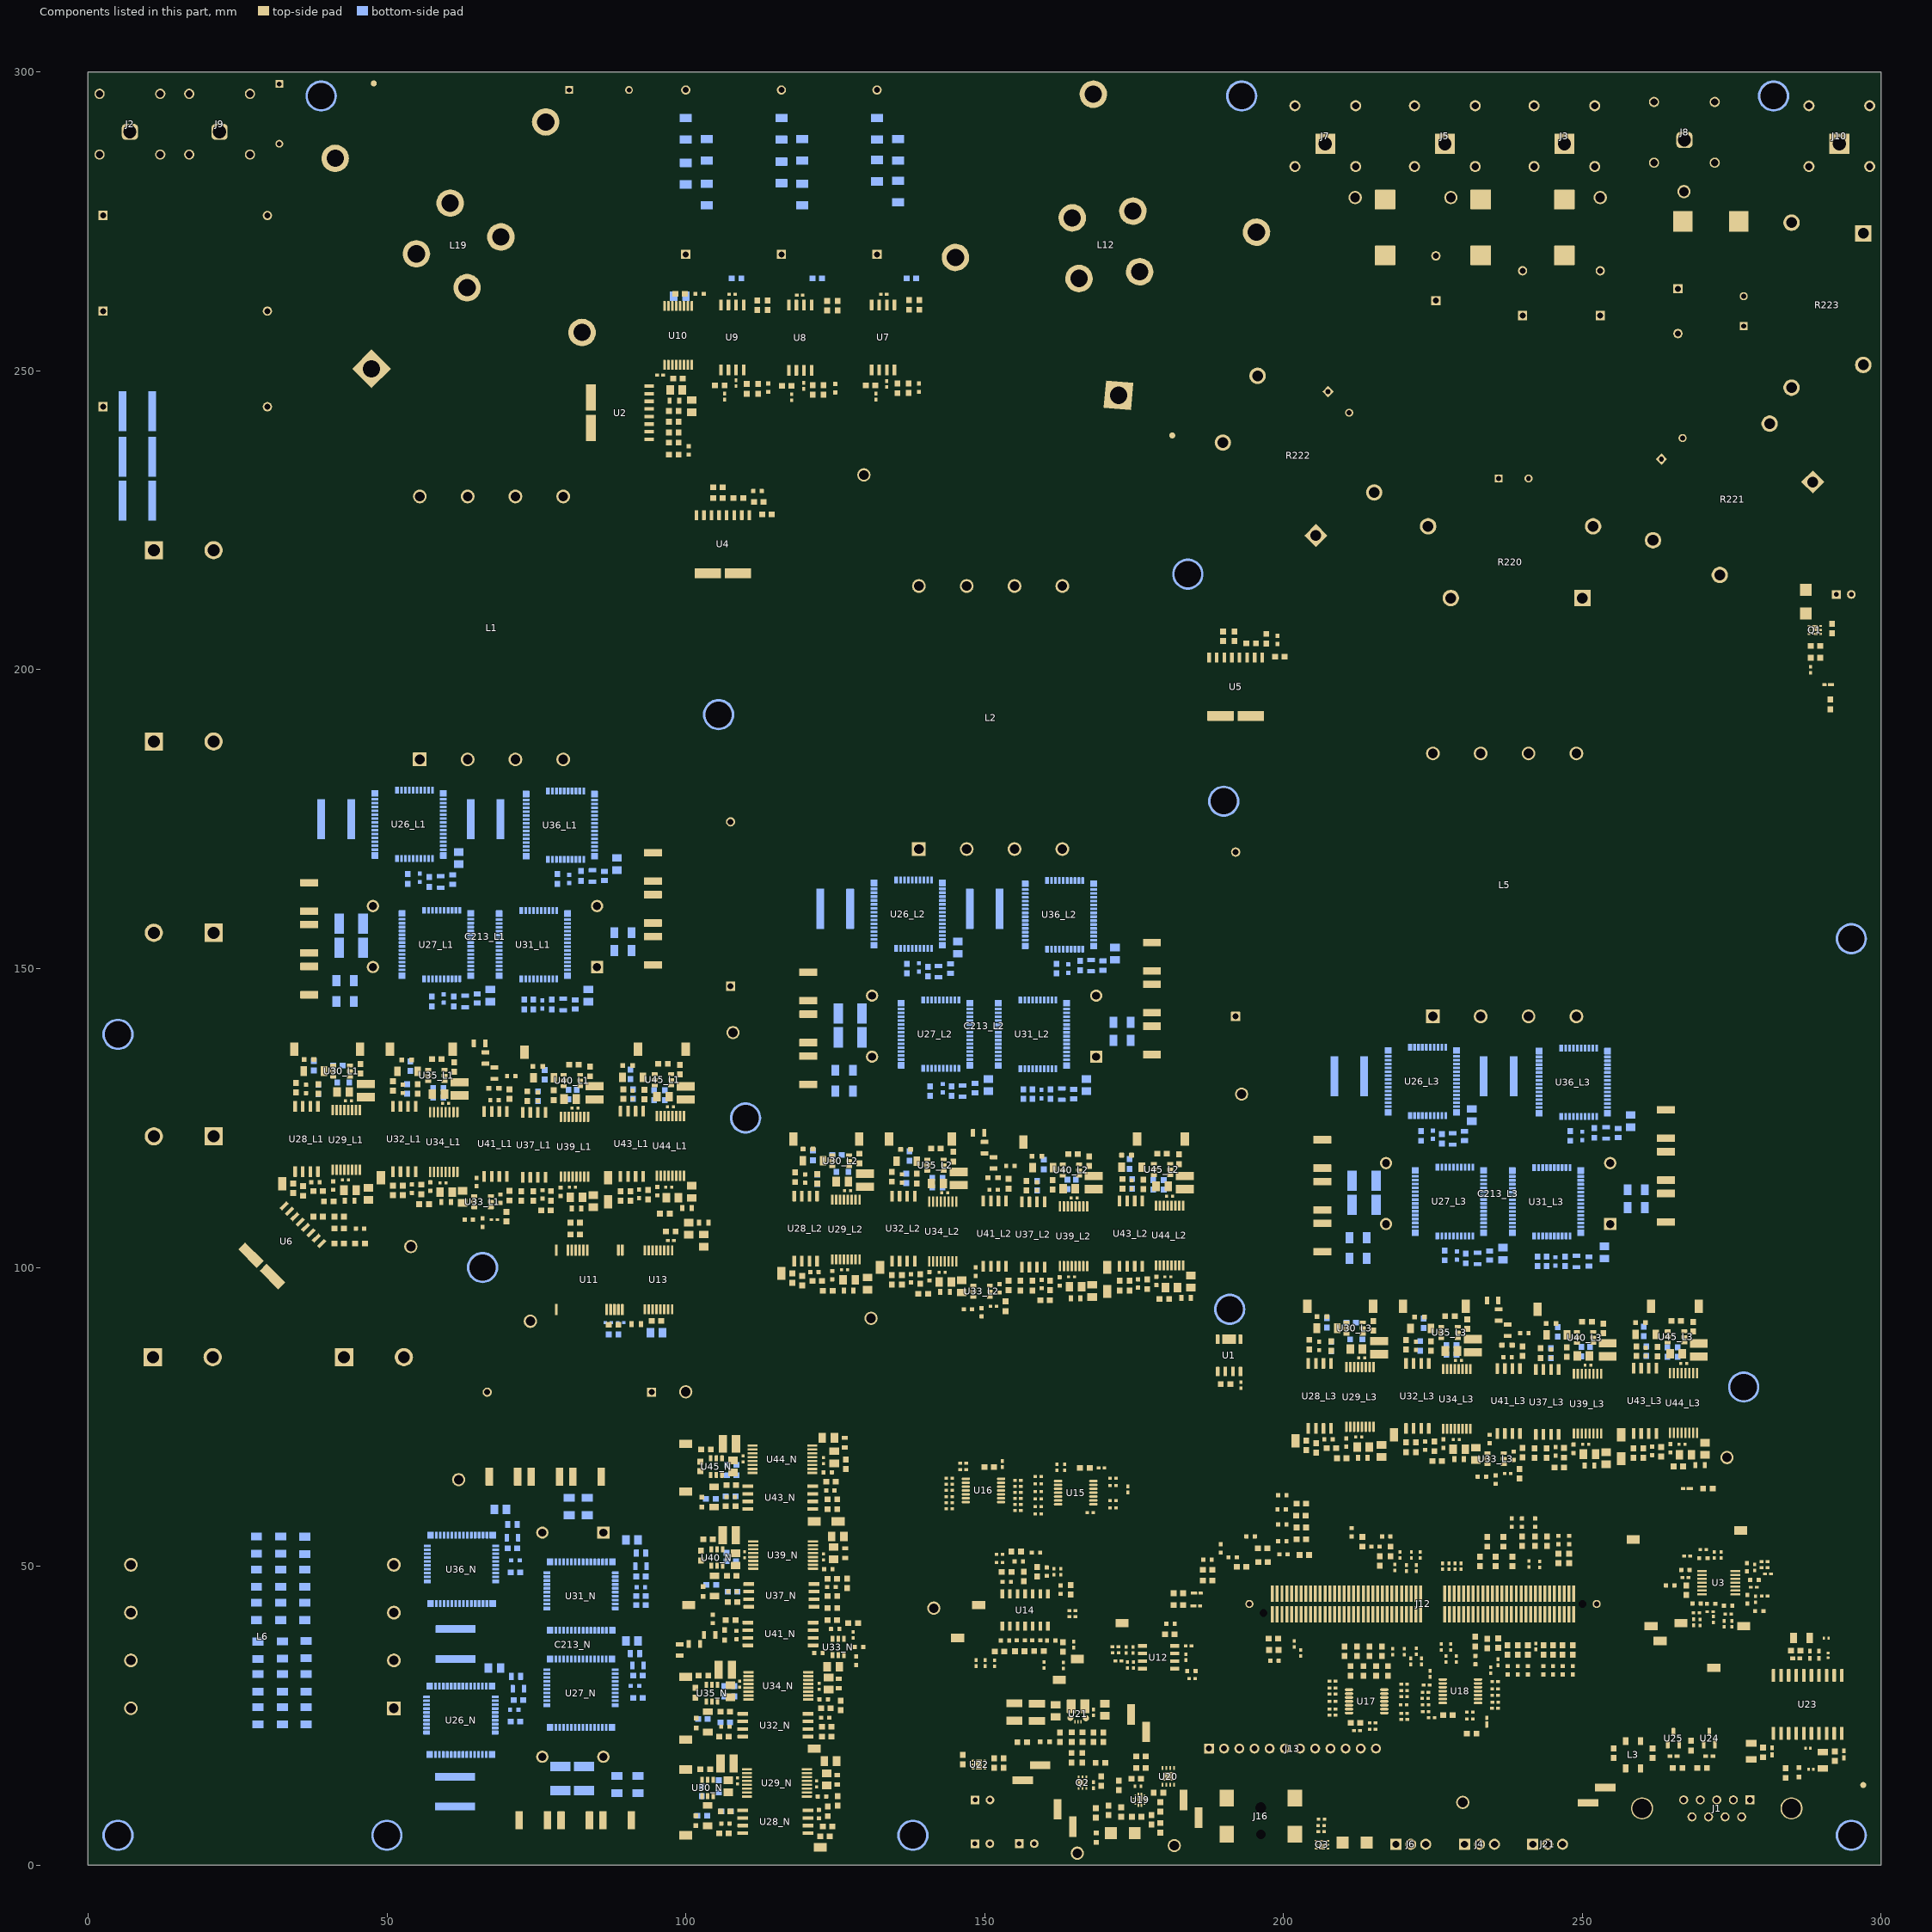
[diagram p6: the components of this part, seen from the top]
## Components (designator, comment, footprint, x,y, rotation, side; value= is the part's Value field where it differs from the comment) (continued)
U27_L3 "LMG3522R030-Q1" RQS0052C-C01-MFG 227.775,111.025 r0 bottom (schematic designator U27)
U27_N "LMG3522R030-Q1" RQS0052C-C01-MFG 82.475,28.775 r90 bottom (schematic designator U27)
U28_L1 "ISO7721FDWV" DWV0008A 36.55,121.5 r90 top (schematic designator U28)
U28_L2 "ISO7721FDWV" DWV0008A 120.05,106.5 r90 top (schematic designator U28)
U28_L3 "ISO7721FDWV" DWV0008A 206.05,78.5 r90 top (schematic designator U28)
U28_N "ISO7721FDWV" DWV0008A 115,7.25 r180 top (schematic designator U28)
U29_L1 "UCC33421-Q1" DWX0016A-MFG 43.197,121.35 r90 top (schematic designator U29)
U29_L2 "UCC33421-Q1" DWX0016A-MFG 126.797,106.35 r90 top (schematic designator U29)
U29_L3 "UCC33421-Q1" DWX0016A-MFG 212.797,78.35 r90 top (schematic designator U29)
U29_N "UCC33421-Q1" DWX0016A-MFG 115.25,13.772 r180 top (schematic designator U29)
U30_L1 "TLV61046ADBVR" DBV0006A_N 42.413,132.845 r180 top (schematic designator U30)
U30_L2 "TLV61046ADBVR" DBV0006A_N 125.913,117.845 r180 top (schematic designator U30)
U30_L3 "TLV61046ADBVR" DBV0006A_N 211.913,89.845 r180 top (schematic designator U30)
U30_N "TLV61046ADBVR" DBV0006A_N 103.655,12.913 r270 top (schematic designator U30)
U31_L1 "LMG3522R030-Q1" RQS0052C-C01-MFG 74.5,154 r0 bottom (schematic designator U31)
U31_L2 "LMG3522R030-Q1" RQS0052C-C01-MFG 158,139 r0 bottom (schematic designator U31)
U31_L3 "LMG3522R030-Q1" RQS0052C-C01-MFG 244,111 r0 bottom (schematic designator U31)
U31_N "LMG3522R030-Q1" RQS0052C-C01-MFG 82.5,45 r90 bottom (schematic designator U31)
U32_L1 "ISO7721FDWV" DWV0008A 52.91,121.5 r90 top (schematic designator U32)
U32_L2 "ISO7721FDWV" DWV0008A 136.41,106.5 r90 top (schematic designator U32)
U32_L3 "ISO7721FDWV" DWV0008A 222.41,78.5 r90 top (schematic designator U32)
U32_N "ISO7721FDWV" DWV0008A 115,23.41 r180 top (schematic designator U32)
U33_L1 "SN74LVC1G11DBVR" DBV0006A_N 66,111 r0 top (schematic designator U33)
U33_L2 "SN74LVC1G11DBVR" DBV0006A_N 149.5,96 r0 top (schematic designator U33)
U33_L3 "SN74LVC1G11DBVR" DBV0006A_N 235.5,68 r0 top (schematic designator U33)
U33_N "SN74LVC1G11DBVR" DBV0006A_N 125.5,36.5 r90 top (schematic designator U33)
U34_L1 "UCC33421-Q1" DWX0016A-MFG 59.5,121 r90 top (schematic designator U34)
U34_L2 "UCC33421-Q1" DWX0016A-MFG 143,106 r90 top (schematic designator U34)
U34_L3 "UCC33421-Q1" DWX0016A-MFG 229,78 r90 top (schematic designator U34)
U34_N "UCC33421-Q1" DWX0016A-MFG 115.5,30 r180 top (schematic designator U34)
U35_L1 "TLV61046ADBVR" DBV0006A_N 58.275,132.116 r180 top (schematic designator U35)
U35_L2 "TLV61046ADBVR" DBV0006A_N 141.775,117.116 r180 top (schematic designator U35)
U35_L3 "TLV61046ADBVR" DBV0006A_N 227.775,89.116 r180 top (schematic designator U35)
U35_N "TLV61046ADBVR" DBV0006A_N 104.384,28.775 r270 top (schematic designator U35)
U36_L1 "LMG3522R030-Q1" RQS0052C-C01-MFG 79,174 r0 bottom (schematic designator U36)
U36_L2 "LMG3522R030-Q1" RQS0052C-C01-MFG 162.5,159 r0 bottom (schematic designator U36)
U36_L3 "LMG3522R030-Q1" RQS0052C-C01-MFG 248.5,131 r0 bottom (schematic designator U36)
U36_N "LMG3522R030-Q1" RQS0052C-C01-MFG 62.5,49.5 r90 bottom (schematic designator U36)
U37_L1 "ISO7721FDWV" DWV0008A 74.629,120.5 r90 top (schematic designator U37)
U37_L2 "ISO7721FDWV" DWV0008A 158.129,105.5 r90 top (schematic designator U37)
U37_L3 "ISO7721FDWV" DWV0008A 244.129,77.5 r90 top (schematic designator U37)
U37_N "ISO7721FDWV" DWV0008A 116,45.129 r180 top (schematic designator U37)
U39_L1 "UCC33421-Q1" DWX0016A-MFG 81.385,120.208 r90 top (schematic designator U39)
U39_L2 "UCC33421-Q1" DWX0016A-MFG 164.885,105.208 r90 top (schematic designator U39)
U39_L3 "UCC33421-Q1" DWX0016A-MFG 250.885,77.208 r90 top (schematic designator U39)
U39_N "UCC33421-Q1" DWX0016A-MFG 116.292,51.885 r180 top (schematic designator U39)
U40_L1 "TLV61046ADBVR" DBV0006A_N 80.958,131.283 r180 top (schematic designator U40)
U40_L2 "TLV61046ADBVR" DBV0006A_N 164.458,116.283 r180 top (schematic designator U40)
U40_L3 "TLV61046ADBVR" DBV0006A_N 250.458,88.283 r180 top (schematic designator U40)
U40_N "TLV61046ADBVR" DBV0006A_N 105.217,51.458 r270 top (schematic designator U40)
U41_L1 "AMC0311DDWV" DWV0008A-MFG 68.169,120.658 r270 top (schematic designator U41)
U41_L2 "AMC0311DDWV" DWV0008A-MFG 151.669,105.658 r270 top (schematic designator U41)
U41_L3 "AMC0311DDWV" DWV0008A-MFG 237.669,77.658 r270 top (schematic designator U41)
U41_N "AMC0311DDWV" DWV0008A-MFG 115.842,38.669 r0 top (schematic designator U41)
U43_L1 "ISO7721FDWV" DWV0008A 90.978,120.676 r90 top (schematic designator U43)
U43_L2 "ISO7721FDWV" DWV0008A 174.478,105.676 r90 top (schematic designator U43)
U43_L3 "ISO7721FDWV" DWV0008A 260.478,77.676 r90 top (schematic designator U43)
U43_N "ISO7721FDWV" DWV0008A 115.824,61.478 r180 top (schematic designator U43)
U44_L1 "UCC33421-Q1" DWX0016A-MFG 97.429,120.338 r90 top (schematic designator U44)
U44_L2 "UCC33421-Q1" DWX0016A-MFG 180.929,105.338 r90 top (schematic designator U44)
U44_L3 "UCC33421-Q1" DWX0016A-MFG 266.929,77.338 r90 top (schematic designator U44)
U44_N "UCC33421-Q1" DWX0016A-MFG 116.162,67.929 r180 top (schematic designator U44)
U45_L1 "TLV61046ADBVR" DBV0006A_N 96.176,131.384 r180 top (schematic designator U45)
U45_L2 "TLV61046ADBVR" DBV0006A_N 179.676,116.384 r180 top (schematic designator U45)
U45_L3 "TLV61046ADBVR" DBV0006A_N 265.676,88.384 r180 top (schematic designator U45)
U45_N "TLV61046ADBVR" DBV0006A_N 105.116,66.676 r270 top (schematic designator U45)
ZZ1 "This Assembly Note is for PCB labels only" AssemblyNoteLabel 333.37,4.996 r90 top
ZZ2 "These assemblies are ESD sensitive, ESD precautions shall be observed." AssemblyNote 296.6,44.8 r90 top
ZZ3 "These assemblies must be clean and free from flux and all contaminants. Use of no clean flux is not acceptable." AssemblyNote 296.7,43.8 r90 top
ZZ4 "These assemblies must comply with workmanship standards IPC-A-610 Class 2, unless otherwise specified." AssemblyNote 322.12,36.496 r90 top

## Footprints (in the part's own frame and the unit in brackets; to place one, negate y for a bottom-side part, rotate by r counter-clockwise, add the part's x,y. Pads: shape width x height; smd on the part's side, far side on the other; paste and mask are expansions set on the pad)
0402 [mm] "0402 from SM-752 data"
  rect 0.8x0.6 smd: 1(-0.6,0) 2(0.6,0)
  silkscreen extent -1.22,-0.52 1.22,0.52, body extent -0.55,-0.3 0.55,0.3, height 0.6
0402L [mm] "0402 from SM-752 data"
  rect 0.6x0.5 smd: 1(-0.5,0) 2(0.5,0)
  body extent -0.55,-0.3 0.55,0.3, height 0.6
0402S [mil] "Based on C0402S footprint from PADS legacy"
  rect 15x24 smd: 1(-20,0) 2(20,0)
  body extent -22,-12 22,12, height 24
0603 [mm] "0603 from SM-752 data"
  rect 1x0.95 smd: 1(-0.8,0) 2(0.8,0)
  silkscreen extent -1.52,-0.69 1.52,0.69, body extent -0.87,-0.47 0.87,0.47, height 1
0805_HV [mil] "0805 with 30mil clearance between pads"
  rect 50x63 smd: 1(-40,0) 2(40,0)
  silkscreen extent -74,-40 74,40, body extent -43,-29 43,29, height 57
1206 [mm] "1206 from SM-752 data"
  rect 1.3x1.85 smd: 1(-1.45,0) 2(1.45,0)
  silkscreen extent -2.4,-1.21 2.4,1.21, body extent -1.7,-0.9 1.7,0.9, height 1.35
1206_180 [mm] "1206_180"
  rect 1.1x1.6 smd: 1(-1.7,0) 2(1.7,0)
  silkscreen extent -0.9,-1 0.9,1, body extent -1.75,-0.95 1.75,0.95, height 1.8
1206_180L [mm] "1206_180"
  rect 1.1x1.75 smd: 1(-1.35,0) 2(1.35,0)
  silkscreen extent -0.4,-0.77 0.4,0.77, body extent -1.75,-0.95 1.75,0.95, height 1.8
1210_270 [mm] "1210"
  rect 1.3x2.7 smd: 1(-1.45,0) 2(1.45,0)
  silkscreen extent -2.32,-1.57 2.32,1.57, body extent -1.7,-1.35 1.7,1.35, height 2.7
1812_254 [mm] "SMD, 2-Leads, Body 4.8x3.4mm"
  rect 1.6x3.4 smd: 1(-2,0) 2(2,0)
  silkscreen extent -0.8,-1.7 0.8,1.7, body extent -2.4,-1.7 2.4,1.7, height 2.54
AssemblyNote [mm] "Assembly Note"
AssemblyNoteLabel [mm] "Assembly Note for PCB Labels"
CE_Mark_5mm [mm] "Minimum text height for CE Mark"
  silkscreen extent -3.5,-2.5 3.5,2.5
Cliff_FCR7350B [mm] "Panel Socket, R/A, TH"
  rrect50% 2.7x2.7 hole 2.2: 1(0,0)
  round 1.7 hole 1.2: 2(-5.08,3.8) 3(5.08,3.8) 4(5.08,-6.36) 5(-5.08,-6.36)
  silkscreen extent -6.01,-13.5 6.01,5.5, body extent -6,-27.5 6,5.5, height 12.3
Cliff_FCR7350R [mm] "Panel Socket, R/A, TH"
  rrect50% 2.7x2.7 hole 2.2: 1(0,0)
  round 1.7 hole 1.2: 2(-5.08,3.8) 3(5.08,3.8) 4(5.08,-6.36) 5(-5.08,-6.36)
  silkscreen extent -6.01,-13.5 6.01,5.5, body extent -6,-27.5 6,5.5, height 12.3
controlCARD-120HSEC [mm] "Pads are not numbered according to Samtec datasheet."
  rect 0.5x2.724 smd: 1(-23.357,-1.678) 2(-23.357,1.722) 3(-22.557,-1.678) 4(-22.557,1.722) 5(-21.757,-1.678) 6(-21.757,1.722) 7(-20.957,-1.678) 8(-20.957,1.722) 9(-20.157,-1.678) 10(-20.157,1.722) 11(-19.357,-1.678) 12(-19.357,1.722) 13(-18.557,-1.678) 14(-18.557,1.722) 15(-17.757,-1.678) 16(-17.757,1.722) 17(-16.957,-1.678) 18(-16.957,1.722) 19(-16.157,-1.678) 20(-16.157,1.722) 21(-15.357,-1.678) 22(-15.357,1.722) 23(-14.557,-1.678) 24(-14.557,1.722) 25(-13.757,-1.678) 26(-13.757,1.722) 27(-12.957,-1.678) 28(-12.957,1.722) 29(-12.157,-1.678) 30(-12.157,1.722) 31(-11.357,-1.678) 32(-11.357,1.722) 33(-10.557,-1.678) 34(-10.557,1.722) 35(-9.757,-1.678) 36(-9.757,1.722) 37(-8.957,-1.678) 38(-8.957,1.722) 39(-8.157,-1.678) 40(-8.157,1.722) 41(-7.357,-1.678) 42(-7.357,1.722) 43(-6.557,-1.678) 44(-6.557,1.722) 45(-5.757,-1.678) 46(-5.757,1.722) 47(-4.957,-1.678) 48(-4.957,1.722) 49(-4.157,-1.678) 50(-4.157,1.722) 51(-3.357,-1.678) 52(-3.357,1.722) 53(-2.557,-1.678) 54(-2.557,1.722) 55(-1.757,-1.678) 56(-1.757,1.722) 57(2.243,-1.678) 58(2.243,1.722) 59(3.043,-1.678) 60(3.043,1.722) 61(3.843,-1.678) 62(3.843,1.722) 63(4.643,-1.678) 64(4.643,1.722) 65(5.443,-1.678) 66(5.443,1.722) 67(6.243,-1.678) 68(6.243,1.722) 69(7.043,-1.678) 70(7.043,1.722) 71(7.843,-1.678) 72(7.843,1.722) 73(8.643,-1.678) 74(8.643,1.722) 75(9.443,-1.678) 76(9.443,1.722) 77(10.243,-1.678) 78(10.243,1.722) 79(11.043,-1.678) 80(11.043,1.722) 81(11.843,-1.678) 82(11.843,1.722) 83(12.643,-1.678) 84(12.643,1.722) 85(13.443,-1.678) 86(13.443,1.722) 87(14.243,-1.678) 88(14.243,1.722) 89(15.043,-1.678) 90(15.043,1.722) 91(15.843,-1.678) 92(15.843,1.722) 93(16.643,-1.678) 94(16.643,1.722) 95(17.443,-1.678) 96(17.443,1.722) 97(18.243,-1.678) 98(18.243,1.722) 99(19.043,-1.678) 100(19.043,1.722) 101(19.843,-1.678) 102(19.843,1.722) 103(20.643,-1.678) 104(20.643,1.722) 105(21.443,-1.678) 106(21.443,1.722) 107(22.243,-1.678) 108(22.243,1.722) 109(23.043,-1.678) 110(23.043,1.722) 111(23.843,-1.678) 112(23.843,1.722) 113(24.643,-1.678) 114(24.643,1.722) 115(25.443,-1.678) 116(25.443,1.722) 117(26.243,-1.678) 118(26.243,1.722) 119(27.043,-1.678) 120(27.043,1.722)
  round 0.025 hole 1.27 unplated mask+0.876: 181(-24.857,0.022) 182(28.543,1.522)
  round 1.348 hole 0.84: 185(-27.207,0.022) 186(30.893,0.022)
  silkscreen extent -32.11,-3.86 35.8,3.9, body extent -31.75,-3.48 35.3,3.52, height 12.35
CUI_PJ-002AH-SMT [mm] "CUI"
  rect 2.8x2.4 smd: 1(-3.05,5.7) 1A(3.05,5.7) 2(-3.05,-5.7) 3(3.05,-5.7)
  round 1 hole 1.6 unplated: MH1(-3.05,0)
  round 1.524 hole 1.8 unplated: MH2(1.45,0)
  silkscreen extent -8.05,-4.5 6.75,5.45, body extent -8.05,-6.3 6.75,6.3, height 11.2
D0008A-MFG [mm]
  rrect17% 1.55x0.6 smd paste+0 mask+0: 1(-2.7,1.905) 2(-2.7,0.635) 3(-2.7,-0.635) 4(-2.7,-1.905) 5(2.7,-1.905) 6(2.7,-0.635) 7(2.7,0.635) 8(2.7,1.905)
  silkscreen extent -4.17,-2.5 1.5,2.5, body extent -3.57,-2.75 3.57,2.75, height 0.25
D0014A-MFG [mm]
  rrect17% 1.55x0.6 smd paste-1000 mask+0: 1(-2.7,3.81) 2(-2.7,2.54) 3(-2.7,1.27) 4(-2.7,0) 5(-2.7,-1.27) 6(-2.7,-2.54) 7(-2.7,-3.81) 8(2.7,-3.81) 9(2.7,-2.54) 10(2.7,-1.27) 11(2.7,0) 12(2.7,1.27) 13(2.7,2.54) 14(2.7,3.81)
  silkscreen extent -4.15,-4.38 1.55,4.38, body extent -3.57,-4.62 3.57,4.62, height 0.25
DBV0006A_N [mm] "SOT23, 6-Leads, Body 2.9x1.6mm, Pitch 0.95mm, Lead Span 2.8mm, IPC Medium Density"
  rrect17% 1x0.6 smd: 1(-1.375,0.95) 2(-1.375,0) 3(-1.375,-0.95) 4(1.375,-0.95) 5(1.375,0) 6(1.375,0.95)
  silkscreen extent -1.68,-1.55 0.5,1.55, body extent -1.42,-1.46 1.42,1.46, height 1.12
DBZ0003A-MFG [mm]
  rrect17% 1.3x0.6 smd paste+0 mask+0: 1(-1.05,0.95) 2(-1.05,-0.95) 3(1.05,0)
  silkscreen extent -0.7,-1.52 0.7,1.52, body extent -1.8,-1.62 1.8,1.62, height 0.25
DFM0020A-MFG [mm]
  rrect17% 2.1x0.6 smd paste+0 mask+0: 1(-4.85,5.715) 2(-4.85,4.445) 3(-4.85,3.175) 4(-4.85,1.905) 5(-4.85,0.635) 6(-4.85,-0.635) 7(-4.85,-1.905) 8(-4.85,-3.175) 9(-4.85,-4.445) 10(-4.85,-5.715) 11(4.85,-5.715) 12(4.85,-4.445) 13(4.85,-3.175) 14(4.85,-1.905) 15(4.85,-0.635) 16(4.85,0.635) 17(4.85,1.905) 18(4.85,3.175) 19(4.85,4.445) 20(4.85,5.715)
  silkscreen extent -6.57,-6.47 3.4,6.47, body extent -6,-6.72 6,6.72, height 0.25
DFQ0007A-MFG [mm]
  rrect17% 1.55x0.6 smd paste+0 mask+0: 1(-2.7,1.905) 2(-2.7,0.635) 3(-2.7,-0.635) 4(-2.7,-1.905) 5(2.7,-1.905) 7(2.7,1.905)
  rrect6% 1.55x2.36 smd paste+0 mask+0: 6(2.7,0)
  silkscreen extent -4.14,-2.5 1.55,2.5, body extent -3.57,-2.75 3.57,2.75, height 0.25
DFX0015A-MFG [mm]
  rrect22% 1.85x0.45 smd paste+0 mask+0: 1(-4.975,5.525) 2(-4.975,-2.925) 3(-4.975,-3.575) 4(-4.975,-4.225) 5(-4.975,-4.875) 6(-4.975,-5.525) 7(4.975,-5.525) 8(4.975,-4.875) 9(4.975,0.325) 10(4.975,0.975) 11(4.975,1.625) 12(4.975,2.275) 13(4.975,2.925) 14(4.975,3.575) 15(4.975,5.525)
  silkscreen extent -6.57,-6.47 3.5,6.47, body extent -6,-6.72 6,6.72, height 0.25
DHA0016A-MFG [mm]
  rrect24% 1.65x0.41 smd paste+0 mask+0: 1(-4.925,2.275) 2(-4.925,1.625) 3(-4.925,0.975) 4(-4.925,0.325) 5(-4.925,-0.325) 6(-4.925,-0.975) 7(-4.925,-1.625) 8(-4.925,-2.275) 9(4.925,-2.275) 10(4.925,-1.625) 11(4.925,-0.975) 12(4.925,-0.325) 13(4.925,0.325) 14(4.925,0.975) 15(4.925,1.625) 16(4.925,2.275)
  silkscreen extent -6.42,-2.98 3.5,2.98, body extent -5.85,-3.22 5.85,3.22, height 0.25
DQK0006C [mm] "WSON"
  rrect12% 0.9x0.86 on Top Paste: 0(0,0.325)
  rrect34% 0.7x0.29 on Top Paste: 0(0.095,-0.65)
  rrect33% 0.45x0.3 smd: 1(-0.975,0.65) 2(-0.975,0) 3(-0.975,-0.65) 4(0.975,-0.65) 5(0.975,0) 6(0.975,0.65)
  rrect33% 0.75x0.3 smd paste-0.15: 7(0.095,-0.65)
  rrect11% 1x0.95 smd paste-0.5: 8(0,0.325)
  silkscreen extent -1.15,-1.15 1.15,1.15, body extent -1,-1 1,1, height 0.82
DRB0008A [mm] "VSON-8"
  rrect32% 0.6x0.31 smd: 1(-1.4,0.975) 2(-1.4,0.325) 3(-1.4,-0.325) 4(-1.4,-0.975) 5(1.4,-0.975) 6(1.4,-0.325) 7(1.4,0.325) 8(1.4,0.975)
  rrect7% 1.5x1.75 smd paste-0.75: 9(0,0)
  Top Layer region: -0.7,-0.875 -0.49,-0.875 -0.471,-0.879 -0.455,-0.89 -0.444,-0.906 -0.44,-0.925 -0.44,-0.925 -0.44,-1.65 -0.436,-1.669 -0.425,-1.685 -0.409,-1.696 -0.39,-1.7 -0.39,-1.7 -0.26,-1.7 -0.241,-1.696 -0.225,-1.685 -0.214,-1.669 -0.21,-1.65 -0.21,-1.65 -0.21,-0.925 -0.206,-0.906 -0.195,-0.89 -0.179,-0.879 -0.16,-0.875 -0.16,-0.875 0.16,-0.875 0.179,-0.879 0.195,-0.89 0.206,-0.906 0.21,-0.925 0.21,-0.925 0.21,-1.65 0.21,-1.65 0.214,-1.669 0.225,-1.685 0.241,-1.696 0.26,-1.7 0.26,-1.7 0.39,-1.7 0.409,-1.696 0.425,-1.685 0.436,-1.669 0.44,-1.65 0.44,-1.65 0.44,-0.925 0.444,-0.906 0.455,-0.89 0.471,-0.879 0.49,-0.875 0.49,-0.875 0.7,-0.875 0.719,-0.871 0.735,-0.86 0.746,-0.844 0.75,-0.825 0.75,-0.825 0.75,0.825 0.746,0.844 0.735,0.86 0.719,0.871 0.7,0.875 0.7,0.875 0.49,0.875 0.471,0.879 0.455,0.89 0.444,0.906 0.44,0.925 0.44,0.925 0.44,1.65 0.436,1.669 0.425,1.685 0.409,1.696 0.39,1.7 0.39,1.7 0.26,1.7 0.241,1.696 0.225,1.685 0.214,1.669 0.21,1.65 0.21,1.65 0.21,1.65 0.21,0.925 0.206,0.906 0.195,0.89 0.179,0.879 0.16,0.875 0.16,0.875 -0.16,0.875 -0.179,0.879 -0.195,0.89 -0.206,0.906 -0.21,0.925 -0.21,0.925 -0.21,1.65 -0.214,1.669 -0.225,1.685 -0.241,1.696 -0.26,1.7 -0.26,1.7 -0.39,1.7 -0.409,1.696 -0.425,1.685 -0.436,1.669 -0.44,1.65 -0.44,1.65 -0.44,0.925 -0.444,0.906 -0.455,0.89 -0.471,0.879 -0.49,0.875 -0.49,0.875 -0.7,0.875 -0.719,0.871 -0.735,0.86 -0.746,0.844 -0.75,0.825 -0.75,0.825 -0.75,-0.825 -0.746,-0.844 -0.735,-0.86 -0.719,-0.871 -0.7,-0.875
  silkscreen extent -1.73,-1.73 1.73,1.73, body extent -1.5,-1.5 1.5,1.5, height 0.77
DRV0006A [mm] "SON, 6-Leads, Body 2x2mm, Pitch 0.65mm, Thermal Pad 1.6x1mm, TI Recommended"
  rrect33% 0.45x0.3 smd: 1(-0.975,0.65) 2(-0.975,0) 3(-0.975,-0.65) 4(0.975,-0.65) 5(0.975,0) 6(0.975,0.65)
  rrect14% 1x0.7 on Top Paste: 7(0,-0.45) 7(0,0.45)
  rrect10% 1x1.6 smd paste-0.5: 7(0,0)
  silkscreen extent -1.05,-1.2 1.05,1.2, body extent -1.05,-1.05 1.05,1.05, height 0.81
DVG0010A-MFG [mm] "Recommended Land Pattern"
  rrect6% 1.65x4.41 smd paste+0 mask+0: 1(-4.875,2.54) 2(-4.875,-2.54)
  rrect17% 1.65x0.6 smd paste+0 mask+0: 3(4.875,-4.445) 4(4.875,-3.175) 5(4.875,-1.905) 6(4.875,-0.635) 7(4.875,0.635) 8(4.875,1.905) 9(4.875,3.175) 10(4.875,4.445)
  silkscreen extent -6.37,-5.25 3.67,5.25, body extent -5.15,-5.15 5.15,5.15, height 2.65
DWV0008A [mm] "SOIC, 8-Leads, Body 5.95x7.6mm (max), Pitch 1.27mm"
  rrect17% 1.8x0.6 smd: 1(-5.45,1.905) 2(-5.45,0.635) 3(-5.45,-0.635) 4(-5.45,-1.905) 5(5.45,-1.905) 6(5.45,-0.635) 7(5.45,0.635) 8(5.45,1.905)
  silkscreen extent -6.25,-2.95 2.98,2.95, body extent -5.77,-2.92 5.77,2.93, height 2.67
DWV0008A-MFG [mm]
  rrect17% 1.8x0.6 smd paste+0 mask+0: 1(-5.45,1.905) 2(-5.45,0.635) 3(-5.45,-0.635) 4(-5.45,-1.905) 5(5.45,-1.905) 6(5.45,-0.635) 7(5.45,0.635) 8(5.45,1.905)
  silkscreen extent -7.1,-2.98 3.8,2.98, body extent -6.45,-3.22 6.45,3.22, height 0.25
DWX0016A-MFG [mm]
  rrect24% 1.7x0.41 smd paste+0 mask+0: 1(-5,2.275) 2(-5,1.625) 3(-5,0.975) 4(-5,0.325) 5(-5,-0.325) 6(-5,-0.975) 7(-5,-1.625) 8(-5,-2.275) 9(5,-2.275) 10(5,-1.625) 11(5,-0.975) 12(5,-0.325) 13(5,0.325) 14(5,0.975) 15(5,1.625) 16(5,2.275)
  silkscreen extent -6.52,-2.98 3.8,2.98, body extent -5.16,-2.93 5.16,2.93, height 2.6
FCC_disclaimer [mm]
Fiducial10-20 [mm]
  round 1 smd mask+0.5: 1(0,0)
  Top Layer keep-out circle w1.178: c0,0 r0.5
FM_630x1120 [mm] "PANASONIC"
  rect 1.45x1.45 hole 0.787: 1(-1.25,0)
  round 1.45 hole 0.787: 2(1.25,0)
  silkscreen extent -3.4,-3.4 3.4,3.4, body extent -3.37,-3.39 3.4,3.39, height 12.71
FP-0022111031_HDR3-MFG [mm]
  rrect5% 1.85x1.85 hole 1.2 paste-2539.97 mask+0: 1(2.5,0.3)
  round 1.85 hole 1.2 paste-2539.97 mask+0: 2(0,0.3) 3(-2.5,0.3)
  silkscreen extent -4.1,-3.1 4.7,3.1, body extent -4.2,-3.2 4.2,3.2, height 0.25
FP-9774025960R_STAND_OFF-MFG [mm] "Recommended Land Pattern"
  round 5.245 smd paste-1000 mask-1000: 1(0,0)
  round 4.4 hole 4.4 unplated paste-2539.97 mask+0: ""(0,0)
  Top Layer circle w1.5: c0,0 r2.95
  silkscreen extent -4.15,-4.15 4.15,4.15, body extent -3,-3 3,3, height 2.6
FP-ACT45B-101-2P-TL003_SMT_4MM5_3MM2-MFG [mm]
  rrect11% 1.35x0.9 smd paste+0 mask+0: 1(-2.275,1.25) 2(-2.275,-1.25) 3(2.275,-1.25) 4(2.275,1.25)
  silkscreen extent -3.62,-1.7 2.35,1.7, body extent -3.05,-1.8 3.05,1.8, height 0.25
FP-ALA7DA301CF550_RADIAL-MFG [mm] "Recommended Land Pattern"
  rrect3% 3.05x3.05 hole 2 paste-2539.97 mask+0: 1(-5,0)
  round 3.05 hole 2 paste-2539.97 mask+0: 2(5,0)
  silkscreen extent -15.5,-15.5 15.5,15.5, body extent -15.6,-15.6 15.6,15.6, height 0.25
FP-APG1608SURKC_T_0603-MFG [mm]
  rrect13% 0.8x0.8 smd paste-1000 mask+0: 1(-0.825,0) 2(0.825,0)
  silkscreen extent -1.92,-0.8 0.85,0.8, body extent -1.33,-0.55 1.33,0.55, height 0.25
FP-B32676G6126K000_RADIAL-MFG [mm] "Recommended Land Pattern"
  round 2.05 hole 1.35 paste-2539.97 mask+0: 1(-18.75,-5.1) 2(18.75,-5.1) 2(18.75,5.1)
  rrect5% 2.05x2.05 hole 1.35 paste-2539.97 mask+0: 1(-18.75,5.1)
  silkscreen extent -21,-14 21,14, body extent -21.1,-14.1 21.1,14.1, height 0.25
FP-B32774X1305K000_RADIAL-MFG [mm] "Recommended Land Pattern"
  rrect6% 1.55x1.55 hole 1 paste-2539.97 mask+0: 1(-13.75,0)
  round 1.55 hole 1 paste-2539.97 mask+0: 2(13.75,0)
  silkscreen extent -15.75,-9 15.75,9, body extent -15.85,-9.1 15.85,9.1, height 0.25
FP-BLM15EX331SN1D_0402-MFG [mm]
  rrect25% 0.4x0.5 smd paste+0 mask+0: 1(-0.4,0) 2(0.4,0)
  silkscreen extent -0.53,-0.63 0.52,0.63, body extent -0.7,-0.38 0.7,0.38, height 0.25
FP-C2225C224KBRACTU_2225-MFG [mm] "Recommended Land Pattern"
  rrect8% 1.3x6.7 smd paste+0 mask+0: 1(-2.5,0) 2(2.5,0)
  silkscreen extent -1.48,-3.4 1.48,3.4, body extent -2.8,-3.2 2.8,3.2, height 1.8
FP-C2225C563KFRACTU_2225-MFG [mm] "Recommended Land Pattern"
  rrect8% 1.3x6.7 smd paste+0 mask+0: 1(-2.5,0) 2(2.5,0)
  silkscreen extent -1.48,-3.4 1.48,3.4, body extent -2.8,-3.2 2.8,3.2, height 1.8
FP-CGA3E2C0G1H331J080AA_0603-MFG [mm]
  rrect14% 0.7x0.7 smd paste+0 mask+0: 1(-0.7,0) 2(0.7,0)
  silkscreen extent -0.95,-0.72 0.95,0.72, body extent -1.15,-0.65 1.15,0.65, height 0.25
FP-FCR7350G_CONN_BANANA_JACK-MFG [mm]
  rrect3% 3.35x3.35 hole 2.2 paste-2539.97 mask+0: 1(11,0)
  round 1.85 hole 1.2 paste-2539.97 mask+0: 2(4.64,5.08) 3(14.8,5.08) 4(4.64,-5.08) 5(14.8,-5.08)
  silkscreen extent -1.83,-6.05 17.2,6.05, body extent -16.7,-6.15 16.7,6.15, height 0.25
FP-FCR7350N_CONN_BANANA_JACK-MFG [mm]
  rrect3% 3.35x3.35 hole 2.2 paste-2539.97 mask+0: 1(11,0)
  round 1.85 hole 1.2 paste-2539.97 mask+0: 2(4.64,5.08) 3(14.8,5.08) 4(4.64,-5.08) 5(14.8,-5.08)
  silkscreen extent -1.83,-6.05 17.2,6.05, body extent -16.7,-6.15 16.7,6.15, height 0.25
FP-FTR-K3AB012W-WG_PTH_RELAY_30MM1_15MM7-MFG [mm] "Recommended Land Pattern"
  rrect4% 2.75x2.75 hole 1.8 paste-2539.97 mask+0: 1(-12,5.75)
  round 2.75 hole 1.8 paste-2539.97 mask+0: 2(10,5.75) 3(13.8,-6.25) 4(-13.8,-6.25)
  silkscreen extent -15.88,-8 15.2,8, body extent -15.3,-8.1 15.3,8.1, height 0.25
FP-GRM21BR61H106ME43L_0805-MFG [mm]
  rrect14% 0.7x1.3 smd paste+0 mask+0: 1(-0.95,0) 2(0.95,0)
  silkscreen extent -0.23,-0.72 0.23,0.72, body extent -1,-0.63 1,0.63, height 1.45
FP-IsoM5-275-B-L2_RADIAL-MFG [mm]
  rrect6% 1.55x1.55 hole 1 paste-2539.97 mask+0: 1(-3.75,0)
  round 1.55 hole 1 paste-2539.97 mask+0: 2(3.75,0)
  silkscreen extent -8.5,-3.15 8.5,3.15, body extent -8.6,-3.25 8.6,3.25, height 0.25
"FP-KG DELLS1.22-JGKH-24_0603-MFG" [mm]
  rrect20% 1.05x0.5 smd paste-1000 mask+0: 1(-0.47,0)
  rrect20% 0.7x0.5 smd paste-1000 mask+0: 2(0.645,0)
  silkscreen extent -1.67,-0.63 0.75,0.63, body extent -1.09,-0.55 1.09,0.55, height 0.25
FP-MAG-3002584_PTH8-MFG [mm] "Recommended Land Pattern"
  rrect4% 2.3x2.3 hole 1.6 paste-2539.97 mask+0: 1(-22,12)
  round 2.3 hole 1.6 paste-2539.97 mask+0: 2(-22,4) 3(-22,-4) 4(-22,-12) 5(22,-12) 6(22,-4) 7(22,4) 8(22,12)
  silkscreen extent -29.17,-29.75 28.45,29.75, body extent -28.2,-29.5 28.2,29.5, height 49.5
FP-MAG-3002585_PTH8-MFG [mm] "Recommended Land Pattern"
  rrect2% 4.6x4.6 hole 2.9 paste-2539.97 mask+0: 1(-4.3,24.9)
  round 4.6 hole 2.9 paste-2539.97 mask+0: 2(-6,4) 3(-24.9,-4.3) 4(-4,-6) 5(4.3,-24.9) 6(6,-4) 7(24.9,4.3) 8(4,6)
  silkscreen extent -28.37,-28.37 28.37,28.37, body extent -28,-28.06 28,27.94, height 30.27
FP-MH1608-601Y_0603-MFG [mm]
  rrect14% 0.7x0.7 smd paste+0 mask+0: 1(-0.7,0) 2(0.7,0)
  silkscreen extent -0.87,-0.8 0.87,0.8, body extent -0.8,-0.4 0.8,0.4, height 1
FP-PTCEL13R600LBE_RADIAL-MFG [mm]
  rrect7% 1.35x1.35 hole 0.85 paste-2539.97 mask+0: 1(-2.5,0)
  round 1.35 hole 0.85 paste-2539.97 mask+0: 2(2.5,0)
  silkscreen extent -6.75,-3.5 6.75,3.5, body extent -6.85,-3.6 6.85,3.6, height 0.25
FP-R413F147050T1K_RADIAL-MFG [mm]
  rrect8% 1.3x1.3 hole 0.8 paste-2539.97 mask+0: 1(-5,0)
  round 1.3 hole 0.8 paste-2539.97 mask+0: 2(5,0)
  silkscreen extent -6.65,-2.6 6.65,2.6, body extent -6.75,-2.7 6.75,2.7, height 0.25
FP-R523R447050P1M_RADIAL-MFG [mm]
  rrect6% 1.55x1.55 hole 1 paste-2539.97 mask+0: 1(-13.75,0)
  round 1.55 hole 1 paste-2539.97 mask+0: 2(13.75,0)
  silkscreen extent -16.15,-7.1 16.15,7.1, body extent -16.25,-7.2 16.25,7.2, height 0.25
FP-RGV3216P-1004-B-T1_1206-MFG [mm]
  rrect7% 1.4x2 smd paste+0 mask+0: 1(-1.8,0) 2(1.8,0)
  silkscreen extent -0.72,-0.92 0.72,0.92, body extent -1.6,-0.8 1.6,0.8, height 0.55
FP-RT0603BRE078KL_0603-MFG [mm]
  rrect13% 0.9x0.8 smd paste+0 mask+0: 1(-0.85,0) 2(0.85,0)
  silkscreen extent -0.85,-0.81 0.86,0.8, body extent -0.8,-0.4 0.8,0.4, height 0.55
FP-SF-3812F2500T-2_SMD2-MFG [mm]
  rrect3% 3.25x3.43 smd paste+0 mask+0: 1(-4.675,0) 2(4.675,0)
  silkscreen extent -2.68,-1.65 2.68,1.65, body extent -6.4,-1.82 6.4,1.82, height 0.25
FP-TNPV0805680KBEEA_0805-MFG [mm] "Recommended Land Pattern"
  rrect14% 0.7x1.3 smd paste+0 mask+0: 1(-0.95,0) 2(0.95,0)
  silkscreen extent -0.23,-0.7 0.23,0.7, body extent -1,-0.63 1,0.63, height 0.55
FP-ZGL41-180A-E3/96_GL41-MFG [mm]
  rrect8% 1.25x3 smd paste+0 mask+0: 1(-2.375,0) 2(2.375,0)
  silkscreen extent -3.67,-1.34 1.38,1.34, body extent -3.1,-1.6 3.1,1.6, height 0.25
Harwin_S2751-46R [mm] "Test Point, SMT"
  rect 2.2x1.4 smd: 1(0,0)
  body extent -1,-0.6 1,0.6, height 1.4
IEC_HighVoltage_Small [mm]
  silkscreen extent -2.72,-2.24 2.72,2.47
IEC_HotSurface_Small [mm]
  silkscreen extent -2.72,-2.36 2.72,2.35
Keystone5010 [mil] "Keystone Multipurpose loops"
  round 87 hole 63: 1(0,0)
  silkscreen extent -70,-70 70,70, body extent -63,-63 63,62, height 319
Keystone5011 [mil] "Keystone Multipurpose loops"
  round 87 hole 63: 1(0,0)
  silkscreen extent -70,-70 70,70, body extent -63,-63 63,62, height 319
Label_650x200 [mil] "Thermal Transfer Label"
  round 1 on Mech13: 0(0,0)
  silkscreen extent -325,-100 325,100, body extent -325,-100 325,100, height 1
PW0014A-MFG [mm]
  rrect29% 1.6x0.35 smd paste-1000 mask+0: 1(-2.8,1.95) 2(-2.8,1.3) 3(-2.8,0.65) 4(-2.8,0) 5(-2.8,-0.65) 6(-2.8,-1.3) 7(-2.8,-1.95) 8(2.8,-1.95) 9(2.8,-1.3) 10(2.8,-0.65) 11(2.8,0) 12(2.8,0.65) 13(2.8,1.3) 14(2.8,1.95)
  silkscreen extent -4.32,-2.55 2.25,2.55, body extent -3.7,-2.8 3.7,2.8, height 0.25
PW0014A_N [mm] "TSOP, 14-Leads, Body 5x4.4mm, Pitch 0.65mm, IPC Medium Density"
  oval 1.4x0.45 smd: 1(-2.95,1.95) 2(-2.95,1.3) 3(-2.95,0.65) 4(-2.95,0) 5(-2.95,-0.65) 6(-2.95,-1.3) 7(-2.95,-1.95) 8(2.95,-1.95) 9(2.95,-1.3) 10(2.95,-0.65) 11(2.95,0) 12(2.95,0.65) 13(2.95,1.3) 14(2.95,1.95)
  silkscreen extent -3.4,-2.55 1.85,2.55, body extent -3.21,-2.5 3.21,2.5, height 1
RDX0007A-MFG [mm]
  round 1.025 smd paste-1000 mask-1000: 1(-1.312,1.312)
  rrect13% 1.5x2.3 smd paste-1000 mask-1000: 2(-1.15,-0.675) 3(1.15,-0.675)
  round 0.991 smd paste-1000 mask-1000: 4(1.281,1.276)
  rrect45% 0.22x0.6 smd paste+0 mask-1000: 5(0.5,1.9) 6(0,1.9) 7(-0.5,1.9)
  Top Layer region: 1.9,1.8 1.892,1.838 1.871,1.871 1.838,1.892 1.8,1.9 1.8,1.9 0.925,1.9 0.887,1.892 0.854,1.871 0.833,1.838 0.825,1.8 0.825,1.8 0.825,1.634 0.818,1.596 0.796,1.563 0.796,1.563 0.507,1.274 0.474,1.252 0.436,1.245 0.436,1.245 0.39,1.245 0.352,1.237 0.319,1.216 0.298,1.183 0.29,1.145 0.29,1.145 0.29,0.825 0.298,0.787 0.319,0.754 0.352,0.733 0.39,0.725 0.39,0.725 1.8,0.725 1.838,0.733 1.871,0.754 1.892,0.787 1.9,0.825 1.9,0.825
  Top Layer region: -1.9,1.8 -1.887,1.85 -1.85,1.887 -1.8,1.9 -1.8,1.9 -0.925,1.9 -0.887,1.892 -0.854,1.871 -0.833,1.838 -0.825,1.8 -0.825,1.8 -0.825,1.634 -0.818,1.596 -0.796,1.563 -0.796,1.563 -0.507,1.274 -0.474,1.252 -0.436,1.245 -0.436,1.245 -0.39,1.245 -0.34,1.232 -0.303,1.195 -0.29,1.145 -0.29,1.145 -0.29,0.825 -0.298,0.787 -0.319,0.754 -0.352,0.733 -0.39,0.725 -0.39,0.725 -1.8,0.725 -1.838,0.733 -1.871,0.754 -1.892,0.787 -1.9,0.825 -1.9,0.825
  Top Layer keep-out region: -0.2,0.675 0.2,0.675 0.2,1.295 -0.2,1.295
  silkscreen extent -2.53,-2.17 2.07,2.37, body extent -2,-2.1 2,2.3, height 0.25
RPW0010A-MFG [mm]
  round 0.27 smd paste-1000 mask+0: 1(-0.75,0.7) 10(0.75,0.7)
  rrect40% 0.6x0.25 smd paste+0 mask+0: 2(-0.9,0.225) 3(-0.9,-0.225) 8(0.9,-0.225) 9(0.9,0.225)
  round 0.255 smd paste-1000 mask+0: 4(-0.75,-0.75) 7(0.75,-0.75)
  rrect33% 0.3x2.4 smd paste-1000 mask+0: 5(-0.25,0) 6(0.25,0)
  Top Layer region: 0.85,0.85 0.85,1.15 0.846,1.169 0.835,1.185 0.819,1.196 0.8,1.2 0.8,1.2 0.65,1.2 0.631,1.196 0.615,1.185 0.604,1.169 0.6,1.15 0.6,1.15 0.6,0.6 0.604,0.581 0.615,0.565 0.631,0.554 0.65,0.55 0.65,0.55 1.15,0.55 1.169,0.554 1.185,0.565 1.196,0.581 1.2,0.6 1.2,0.6 1.2,0.8 1.196,0.819 1.185,0.835 1.169,0.846 1.15,0.85 1.15,0.85
  Top Layer region: 0.85,-0.85 0.85,-1.15 0.846,-1.169 0.835,-1.185 0.819,-1.196 0.8,-1.2 0.8,-1.2 0.65,-1.2 0.631,-1.196 0.615,-1.185 0.604,-1.169 0.6,-1.15 0.6,-1.15 0.6,-0.6 0.604,-0.581 0.615,-0.565 0.631,-0.554 0.65,-0.55 0.65,-0.55 1.15,-0.55 1.169,-0.554 1.185,-0.565 1.196,-0.581 1.2,-0.6 1.2,-0.6 1.2,-0.8 1.196,-0.819 1.185,-0.835 1.169,-0.846 1.15,-0.85 1.15,-0.85
  Top Layer region: -0.85,-0.85 -0.85,-1.15 -0.846,-1.169 -0.835,-1.185 -0.819,-1.196 -0.8,-1.2 -0.8,-1.2 -0.65,-1.2 -0.631,-1.196 -0.615,-1.185 -0.604,-1.169 -0.6,-1.15 -0.6,-1.15 -0.6,-0.6 -0.604,-0.581 -0.615,-0.565 -0.631,-0.554 -0.65,-0.55 -0.65,-0.55 -1.15,-0.55 -1.169,-0.554 -1.185,-0.565 -1.196,-0.581 -1.2,-0.6 -1.2,-0.6 -1.2,-0.8 -1.196,-0.819 -1.185,-0.835 -1.169,-0.846 -1.15,-0.85 -1.15,-0.85
  Top Layer region: -0.85,0.85 -0.85,1.15 -0.843,1.175 -0.825,1.193 -0.8,1.2 -0.8,1.2 -0.65,1.2 -0.631,1.196 -0.615,1.185 -0.604,1.169 -0.6,1.15 -0.6,1.15 -0.6,0.6 -0.604,0.581 -0.615,0.565 -0.631,0.554 -0.65,0.55 -0.65,0.55 -1.15,0.55 -1.169,0.554 -1.185,0.565 -1.196,0.581 -1.2,0.6 -1.2,0.6 -1.2,0.8 -1.193,0.825 -1.175,0.843 -1.15,0.85 -1.15,0.85
  silkscreen extent -1.88,-1.58 1.05,1.58, body extent -1.3,-1.3 1.3,1.3, height 0.25
RQS0052C-C01-MFG [mm]
  rrect9% 1.15x1.1 smd paste+0 mask+0.05: 1(-5.725,5.2) 16(-5.725,-5.2) 27(5.725,-5.2) 42(5.725,5.2)
  rrect22% 1.15x0.45 smd paste+0 mask+0.05: 2(-5.725,4.225) 3(-5.725,3.575) 4(-5.725,2.925) 5(-5.725,2.275) 6(-5.725,1.625) 7(-5.725,0.975) 8(-5.725,0.325) 9(-5.725,-0.325) 10(-5.725,-0.975) 11(-5.725,-1.625) 12(-5.725,-2.275) 13(-5.725,-2.925) 14(-5.725,-3.575) 15(-5.725,-4.225) 28(5.725,-4.225) 29(5.725,-3.575) 30(5.725,-2.925) 31(5.725,-2.275) 32(5.725,-1.625) 33(5.725,-0.975) 34(5.725,-0.325) 35(5.725,0.325) 36(5.725,0.975) 37(5.725,1.625) 38(5.725,2.275) 39(5.725,2.925) 40(5.725,3.575) 41(5.725,4.225)
  rrect15% 0.665x1.15 smd paste+0 mask+0.05: 17(-2.043,-5.725) 52(-2.043,5.725)
  rrect22% 0.45x1.15 smd paste+0 mask+0.05: 18(-1.285,-5.725) 19(-0.635,-5.725) 20(0.015,-5.725) 21(0.665,-5.725) 22(1.315,-5.725) 23(1.965,-5.725) 24(2.615,-5.725) 25(3.265,-5.725) 26(3.915,-5.725) 43(3.915,5.725) 44(3.265,5.725) 45(2.615,5.725) 46(1.965,5.725) 47(1.315,5.725) 48(0.665,5.725) 49(0.015,5.725) 50(-0.635,5.725) 51(-1.285,5.725)
  silkscreen extent -7.02,-6.05 4.77,6.05, body extent -6,-6 6,6, height 1
Samtec_TSM-102-01-T-SV-P-TR [mil] "SMD, 2-Leads, Body 200x100mil"
  rect 50x135 smd: 1(-50,57.5) 2(50,-57.5)
  silkscreen extent -100,-50 100,92, body extent -100,-96 100,96, height 380
SDR0302 [mm] "BOURNS"
  rect 1.4x3 smd: 1(-1.1,0) 2(1.1,0)
  body extent -1.65,-1.65 1.65,1.65, height 2.8
SMA [mm] "Molded Diode, 2-Leads, Body 4.3x2.6mm, IPC Medium Density, based on OnSemi component dimensions and land pattern"
  rect 2x2 smd: 1(-2,0) 2(2,0)
  silkscreen extent -3.66,-1.57 2.79,1.57, body extent -2.6,-1.3 2.6,1.3, height 2.42
TSW-112-07-G-S [mm] "Samtec 100mil, 1x12, 230 mil above insulator"
  rrect6% 1.65x1.65 hole 1.016 mask+0: 1(-13.97,0)
  round 1.65 hole 1.016 mask+0: 2(-11.43,0) 3(-8.89,0) 4(-6.35,0) 5(-3.81,0) 6(-1.27,0) 7(1.27,0) 8(3.81,0) 9(6.35,0) 10(8.89,0) 11(11.43,0) 12(13.97,0)
  silkscreen extent -15.24,-1.27 15.24,1.65, body extent -15.24,-1.27 15.24,1.27, height 8.38
WCAP-CSGP_0402_L1W0.5H0.5 [mm] "Ceramic Capacitors, body 1x0.5mm"
  rect 0.5x0.5 smd: 1(-0.5,0) 2(0.5,0)
  body extent -0.5,-0.25 0.5,0.25, height 0.5
WE-LQS_2010 [mm] "SMD, 2-Leads, Body 2x1.6mm"
  rrect12% 0.85x1.2 smd: 1(-0.775,0) 2(0.775,0)
  body extent -1,-0.82 1,0.8, height 0.98
WE-PMI_0603_L1.6W0.8H0.8 [mm] "Power Multilayer Inductor, body 1.6x0.8mm"
  rect 0.7x1 smd: 1(-0.8,0) 2(0.8,0)
  body extent -0.8,-0.4 0.8,0.4, height 0.8
WEEE_Minimum [mm] "WEEElie bin"
  silkscreen extent -2.42,-4.38 2.52,2.65
WL-SMCW_GREEN [mm] "WURTH"
  rect 0.8x0.8 smd: 1(-0.8,0) 2(0.8,0)
  silkscreen extent -1.9,-0.8 1.2,0.8, body extent -0.85,-0.45 0.85,0.45, height 0.8
Wurth_618009231121 [mm] "Receptacle, D-Sub, 9 Position, R/A, TH"
  rect 1.5x1.5 hole 1: 1(-10.92,5.54)
  round 1.5 hole 1: 2(-10.92,2.77) 3(-10.92,0) 4(-10.92,-2.77) 5(-10.92,-5.54) 6(-8.08,4.155) 7(-8.08,1.385) 8(-8.08,-1.385) 9(-8.08,-4.155)
  round 3.7 hole 3.2: 10(-9.5,12.5) 11(-9.5,-12.5)
  silkscreen extent -12.78,-15.4 -0.53,15.4, body extent -12.5,-15.4 6,15.4, height 12.5

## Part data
C1 C2 C3 C7 C8 C9: library part CMP-0124364-1, "300 µF 550 V Aluminum Electrolytic Capacitors Radial, Can - Snap-In 567mOhm @ 100Hz 13000 Hrs @ 85°C", Digikey Part Number=399-ALA7DA301CF550-ND, Leakage Current=990uA, Manufacturer=KEMET, Mouser Part Number=80-ALA7DA301CF550, Operating Temperature Range="-40°C to +85°C", Tolerance_%=20%, ValueDisplayed=300uF
C4 C26 C259 C260: library part CMP-0010339-1, "CAP, AL, 100 uF, 25 V, +/- 20%, 0.13 ohm, TH", Cap_Case=6.3x11.2, Manufacturer=Panasonic, Supplier Part Number 1=P12924-ND, Tolerance_%=20%, Value1="0.13 ohm", Value2=25V, ValueDisplayed=100uF
C5 C14 C29 C31 C32 C33 C35 C37 C38 C39 C41 C43 C44 C45 C48 C50 C51 C52 C59 C66 C73 C84 C95 C96 C97 C98 C99 C100 C101 C102 C103 C104 C105 C106 C159 C160 C161 C162 C173 C174 C175 C176 C188_L1 C188_L2 C188_L3 C188_N C189_L1 C189_L2 C189_L3 C189_N C191_L1 C191_L2 C191_L3 C191_N C196_L1 C196_L2 C196_L3 C196_N C202_L1 C202_L2 C202_L3 C202_N C203_L1 C203_L2 C203_L3 C203_N C205_L1 C205_L2 C205_L3 C205_N C206_L1 C206_L2 C206_L3 C206_N C207_L1 C207_L2 C207_L3 C207_N C209_L1 C209_L2 C209_L3 C209_N C219_L1 C219_L2 C219_L3 C219_N C226_L1 C226_L2 C226_L3 C226_N C227_L1 C227_L2 C227_L3 C227_N C231_L1 C231_L2 C231_L3 C231_N C236_L1 C236_L2 C236_L3 C236_N C242_L1 C242_L2 C242_L3 C242_N C245_L1 C245_L2 C245_L3 C245_N C246_L1 C246_L2 C246_L3 C246_N C248_L1 C248_L2 C248_L3 C248_N C253_L1 C253_L2 C253_L3 C253_N C262: library part CMP-0095085-1, "Cap Ceramic 330pF 50V C0G 5% Pad SMD 0603 +125°C Automotive T/R", Manufacturer=TDK, Operating Temperature Range="-55°C to +125°C", TempCo=30ppm/°C, Temperature Characteristic=C0G, Tolerance_%=0.05%, ValueDisplayed=330pF
C6 C151 C155: library part CMP-0008802-2, "CAP, CERM, 10 uF, 50 V, +/- 10%, X7R, 1206", Cap_Case=1206, Manufacturer=Samsung, Supplier Part Number 1=1276-6767-1-ND, TempCo=X7R, Tolerance_%=10%, Value1=Unknown, Value2=50V, ValueDisplayed=10uF
C10 C11 C12: library part CMP-0124365-1, "3 µF Film Capacitor 1200V (1.2kV) Polypropylene (PP), Metallized Radial", Digikey Part Number=495-B32774X1305K000-ND, Manufacturer=TDK, Mouser Part Number=871-B32774X1305K000, Operating Temperature Range="-40°C to +105°C", Tolerance_%=10%, ValueDisplayed=3uF
C13 C16 C27 C28 C30 C34 C36 C40 C42 C46 C47 C49 C53 C55 C56 C60 C62 C63 C67 C69 C70 C74 C76 C77 C81 C82 C88 C90 C91 C94 C107 C113 C114 C125 C138 C168_L1 C168_L2 C168_L3 C168_N C186_L1 C186_L2 C186_L3 C186_N C187_L1 C187_L2 C187_L3 C187_N C190_L1 C190_L2 C190_L3 C190_N C195_L1 C195_L2 C195_L3 C195_N C200_L1 C200_L2 C200_L3 C200_N C201_L1 C201_L2 C201_L3 C201_N C204_L1 C204_L2 C204_L3 C204_N C212_L1 C212_L2 C212_L3 C212_N C223_L1 C223_L2 C223_L3 C223_N C224_L1 C224_L2 C224_L3 C224_N C225_L1 C225_L2 C225_L3 C225_N C235_L1 C235_L2 C235_L3 C235_N C240_L1 C240_L2 C240_L3 C240_N C241_L1 C241_L2 C241_L3 C241_N C243_L1 C243_L2 C243_L3 C243_N C244_L1 C244_L2 C244_L3 C244_N C247_L1 C247_L2 C247_L3 C247_N C252_L1 C252_L2 C252_L3 C252_N: library part CMP-0006752-5, "CAP, CERM, 0.1 uF, 25 V, +/- 5%, X7R, 0603", Cap_Case=0603, Manufacturer=AVX, Supplier Part Number 1=478-3713-1-ND, TempCo=X7R, Tolerance_%=5%, Value1="0.05 ohm", Value2=25V, ValueDisplayed=0.1uF
C15: library part CMP-0086152-1, "CAP, CERM, 1 µF, 25 V,+/- 10%, X5R, 0603", Cap_Case=0603, Manufacturer="Taiyo Yuden", TempCo=X5R, Tolerance_%=10%, Value2=25V, ValueDisplayed=1µF
C17 C18 C19 C20 C21 C22: library part CMP-0098409-1, "4.7 µF Film Capacitor 310V 630V Polypropylene (PP), Metallized Radial", Digikey Part Number=399-R523R447050P1M-ND, Manufacturer=KEMET, Mouser Part Number=80-R523R447050P1M, Operating Temperature Range="-40°C to +110°C", Tolerance_%=20%, ValueDisplayed=4.7uF, Voltage Ac Rating X=310V
C23 C216_L1 C216_L2 C216_L3 C216_N C257 C258: library part CMP-0126491-1, "Ceramic Capacitor, Multilayer, Ceramic, 630V, 10% +Tol, 10% -Tol, X7R, 15% TC, 0.22uF, Surface Mount, 2225", Digikey Part Number=399-C2225C224KBRACTUCT-ND, Manufacturer=KEMET, Mouser Part Number=80-C2225C224KBR, Operating Temperature Range="-55°C to +125°C", TempCo=15%, Temperature Characteristic=X7R, Tolerance_%=10%, ValueDisplayed=0.22uF
C24 C25: library part CMP-0098408-1, "Cap Film 0.0047uF 1500V PP 10% Dipped 10mm 125°C Bulk", Digikey Part Number=399-R413F147050T1K-ND, Manufacturer=KEMET, Mouser Part Number=80-R413F147050T1K, Operating Temperature Range="-40°C to +125°C", Tolerance_%=10%, ValueDisplayed=4700pF, Voltage Ac Rating Y=300V
C54 C57 C61 C64 C68 C71 C80 C87 C144 C145: library part CMP-0007121-4, "CAP, CERM, 2.2 uF, 16 V, +/- 10%, X7R, 0603", Cap_Case=0603, Manufacturer="Taiyo Yuden", Supplier Part Number 1=EMK107BB7225KA-T-ND, TempCo=X7R, Tolerance_%=10%, Value1=Unknown, Value2=16V, ValueDisplayed=2.2uF
C58 C65 C72 C83 C86 C263: library part CMP-0006309-2, "CAP, CERM, 1000 pF, 50 V, +/- 5%, C0G/NP0, AEC-Q200 Grade 1, 0402", Cap_Case=0402, Manufacturer=TDK, Supplier Part Number 1=445-6885-1-ND, TempCo=C0G/NP0, Tolerance_%=5%, Value1=Unknown, Value2=50V, ValueDisplayed=1000pF
C75 C78 C79 C89 C92 C93 C143 C194_L1 C194_L2 C194_L3 C194_N C197_L1 C197_L2 C197_L3 C197_N C198_L1 C198_L2 C198_L3 C198_N C211_L1 C211_L2 C211_L3 C211_N C220_L1 C220_L2 C220_L3 C220_N C221_L1 C221_L2 C221_L3 C221_N C234_L1 C234_L2 C234_L3 C234_N C237_L1 C237_L2 C237_L3 C237_N C238_L1 C238_L2 C238_L3 C238_N C251_L1 C251_L2 C251_L3 C251_N C254_L1 C254_L2 C254_L3 C254_N C255_L1 C255_L2 C255_L3 C255_N: library part CMP-0008377-2, "CAP, CERM, 22 uF, 10 V, +/- 20%, X7R, 0805", Cap_Case=0805, Manufacturer=MuRata, Supplier Part Number 1=81-GRM21BZ71A226ME5L, TempCo=X7R, Tolerance_%=20%, Value1=Unknown, Value2=10V, ValueDisplayed=22uF
C85: library part CMP-0006673-2, "CAP, CERM, 1000 pF, 50 V, +/- 10%, X7R, 0402", Cap_Case=0402, Manufacturer=MuRata, Supplier Part Number 1=490-1303-1-ND, TempCo=X7R, Tolerance_%=10%, Value1=Unknown, Value2=50V, ValueDisplayed=1000pF
C108 C109 C110 C111 C112 C115 C116 C117 C118 C119 C120 C121 C122 C123 C124 C126 C127 C128 C129 C130: library part CMP-0006410-2, "CAP, CERM, 100 pF, 50 V, +/- 5%, C0G/NP0, 0402", Cap_Case=0402, Manufacturer=MuRata, Supplier Part Number 1=81-GRM1555C1H101JA1D, TempCo=C0G/NP0, Tolerance_%=5%, Value1=Unknown, Value2=50V, ValueDisplayed=100pF
C131 C133: library part CMP-0007052-4, "CAP, CERM, 1 uF, 35 V, +/- 10%, X7R, 0603", Cap_Case=0603, Manufacturer=TDK, Supplier Part Number 1=445-7414-1-ND, TempCo=X7R, Tolerance_%=10%, Value1=Unknown, Value2=35V, ValueDisplayed=1uF
C132 C142: library part CMP-0006356-2, "CAP, CERM, 0.1 uF, 50 V, +/- 10%, X7R, AEC-Q200 Grade 1, 0402", Cap_Case=0402, Manufacturer=MuRata, Supplier Part Number 1=490-10672-1-ND, TempCo=X7R, Tolerance_%=10%, Value1=Unknown, Value2=50V, ValueDisplayed=0.1uF
C134: library part CMP-0007477-4, "CAP, CERM, 2700 pF, 100 V, +/- 10%, X7R, 0603", Cap_Case=0603, Manufacturer=MuRata, Supplier Part Number 1=490-1480-1-ND, TempCo=X7R, Tolerance_%=10%, Value1=Unknown, Value2=100V, ValueDisplayed=2700pF
C135: library part CMP-0006985-4, "CAP, CERM, 3300 pF, 50 V, +/- 10%, X7R, 0603", Cap_Case=0603, Manufacturer=Kemet, Supplier Part Number 1=399-5339-1-ND, TempCo=X7R, Tolerance_%=10%, Value1=Unknown, Value2=50V, ValueDisplayed=3300pF
C136 C149 C152 C261: library part CMP-0006659-2, "CAP, CERM, 0.1 uF, 25 V, +/- 10%, X7R, 0402", Cap_Case=0402, Manufacturer=MuRata, Supplier Part Number 1=490-10698-1-ND, TempCo=X7R, Tolerance_%=10%, Value1=Unknown, Value2=25V, ValueDisplayed=0.1uF
C137: library part CMP-0007255-4, "CAP, CERM, 22 pF, 100 V, +/- 5%, C0G/NP0, 0603", Cap_Case=0603, Manufacturer=MuRata, Supplier Part Number 1=490-1335-1-ND, TempCo=C0G/NP0, Tolerance_%=5%, Value1=Unknown, Value2=100V, ValueDisplayed=22pF
C139 C140: library part CMP-0009220-2, "CAP, CERM, 47 uF, 10 V, +/- 10%, X7R, 1210", Cap_Case=1210, Manufacturer=MuRata, Supplier Part Number 1=490-5312-1-ND, TempCo=X7R, Tolerance_%=10%, Value1=Unknown, Value2=10V, ValueDisplayed=47uF
C141: library part CMP-0085283-1, "CAP, CERM, 10 µF, 16 V,+/- 10%, X7R, 0805", Cap_Case=0805, Manufacturer="Taiyo Yuden", TempCo=X7R, Tolerance_%=10%, Value2=16V, ValueDisplayed=10µF
C146: library part CMP-0006853-4, "CAP, CERM, 0.01 uF, 16 V, +/- 10%, X7R, 0603", Cap_Case=0603, Manufacturer=Kemet, Supplier Part Number 1=399-7841-1-ND, TempCo=X7R, Tolerance_%=10%, Value1=Unknown, Value2=16V, ValueDisplayed=0.01uF
C147 C150 C154: library part CMP-0079154-1, "CAP, CERM, 1 µF, 16 V,+/- 10%, X7R, AEC-Q200 Grade 1, 0603", Cap_Case=0603, Manufacturer=MuRata, Supplier Part Number 1=490-12657-1-ND, TempCo=X7R, Tolerance_%=10%, Value2=16V, ValueDisplayed=1µF
C148 C153: library part CMP-0006674-2, "CAP, CERM, 0.01 uF, 50 V, +/- 10%, X7R, 0402", Cap_Case=0402, Manufacturer=MuRata, Supplier Part Number 1=490-4516-1-ND, TempCo=X7R, Tolerance_%=10%, Value1=Unknown, Value2=50V, ValueDisplayed=0.01uF
C156 C158: library part CMP-0006251-2, "CAP, CERM, 68 pF, 50 V, +/- 5%, C0G/NP0, 0402", Cap_Case=0402, Manufacturer=TDK, Supplier Part Number 1=445-1245-1-ND, TempCo=C0G/NP0, Tolerance_%=5%, Value1=Unknown, Value2=50V, ValueDisplayed=68pF
C157: library part CMP-0006987-4, "CAP, CERM, 4700 pF, 50 V, +/- 10%, X7R, 0603", Cap_Case=0603, Manufacturer=Kemet, Supplier Part Number 1=399-5337-1-ND, TempCo=X7R, Tolerance_%=10%, Value1=Unknown, Value2=50V, ValueDisplayed=4700pF
C163_L1 C163_L2 C163_L3 C163_N C165_L1 C165_L2 C165_L3 C165_N C169_L1 C169_L2 C169_L3 C169_N C171_L1 C171_L2 C171_L3 C171_N: library part CMP-0095280-1, "Chip Multilayer Ceramic Capacitors for General Purpose, 0805, 10uF, X5R, 15%, 20%, 50V", Manufacturer=Murata, Operating Temperature Range="-55°C to +85°C", TempCo=15%, Temperature Characteristic=X5R, Tolerance_%=20%, ValueDisplayed=10uF
C164_L1 C164_L2 C164_L3 C164_N C166_L1 C166_L2 C166_L3 C166_N C167_L1 C167_L2 C167_L3 C167_N C170_L1 C170_L2 C170_L3 C170_N: library part CMP-0008342-2, "CAP, CERM, 2.2 uF, 25 V, +/- 10%, X7R, 0805", Alternate Manufacturer=Murata, Alternate PartNumber=GRM219R61E225KA12D, Cap_Case=0805, Manufacturer=MuRata, Supplier Part Number 1=490-3331-1-ND, TempCo=X7R, Tolerance_%=10%, Value1="0.005 ohm", Value2=25V, ValueDisplayed=2.2uF
C172_L1 C172_L2 C172_L3 C172_N C215_L1 C215_L2 C215_L3 C215_N: library part CMP-0009327-2, "CAP, CERM, 0.1 uF, 630 V, +/- 10%, X7R, 1812", Cap_Case=1812, Manufacturer=Kemet, Supplier Part Number 1=399-6781-1-ND, TempCo=X7R, Tolerance_%=10%, Value1=Unknown, Value2=630V, ValueDisplayed=0.1uF
C192_L1 C192_L2 C192_L3 C192_N C208_L1 C208_L2 C208_L3 C208_N C232_L1 C232_L2 C232_L3 C232_N C249_L1 C249_L2 C249_L3 C249_N: library part CMP-0009015-2, "CAP, CERM, 10 uF, 50 V, +/- 10%, X5R, AEC-Q200 Grade 1, 1206", Cap_Case=1206, Manufacturer=MuRata, Supplier Part Number 1=490-12456-1-ND, TempCo=X5R, Tolerance_%=10%, Value1=Unknown, Value2=50V, ValueDisplayed=10uF
C193_L1 C193_L2 C193_L3 C193_N C210_L1 C210_L2 C210_L3 C210_N C233_L1 C233_L2 C233_L3 C233_N C250_L1 C250_L2 C250_L3 C250_N: library part CMP-0119293-1, "WCAP-CSGP Multilayer Ceramic Chip Capacitor, General Purpose, size 0402, X7R, 2.2nF, 50VDC", Capacitance Tolerance=+/-10%, Case/Size Code=0402, Insulation Resistance=10GOhm, Manufacturer="Wurth Elektronik", Operating Temperature Max=125°C, Operating Temperature Min=-55°C, Rated Voltage (DC)=50V
C199_L1 C199_L2 C199_L3 C199_N C222_L1 C222_L2 C222_L3 C222_N C239_L1 C239_L2 C239_L3 C239_N C256_L1 C256_L2 C256_L3 C256_N: library part CMP-0115362-1, "WCAP-CSGP Multilayer Ceramic Chip Capacitor, General Purpose, size 0402, X7R, 15nF, 25VDC", Capacitance Tolerance=+/-10%, Case/Size Code=0402, Insulation Resistance=10GOhm, Manufacturer="Wurth Elektronik", Operating Temperature Max=125°C, Operating Temperature Min=-55°C, Rated Voltage (DC)=25V
C213_L1 C213_L2 C213_L3 C213_N: library part CMP-0124359-1, "Cap Film 12uF 630V PP 10% (42 X 28 X 42.5mm) Radial 0.0055 Ohm 100°C Bulk", Digikey Part Number=495-B32676G6126K000-ND, Manufacturer=TDK, Mouser Part Number=871-B32676G6126K, Operating Temperature Range="-40°C to +105°C", Tolerance_%=10%, ValueDisplayed=12uF
C217_L1 C217_L2 C217_L3 C217_N: library part CMP-0126492-1, "0.056 µF ±10% 1500V (1.5kV) Ceramic Capacitor X7R 2225 (5763 Metric)", Digikey Part Number=399-C2225C563KFRACTUTR-ND, Manufacturer=KEMET, Mouser Part Number=80-C2225C563KFRACTU, Operating Temperature Range="-55°C to +125°C", TempCo=15%, Temperature Characteristic=X7R, Tolerance_%=10%, ValueDisplayed=0.056uF
D1 D2 D19 D20 D21: library part CMP-0093310-1, "Standard LEDs - SMD Green TOPLED E 1608", Color=Green, Forward Current=2mA, Manufacturer="Osram Opto", Mouser Part Number=720-KGDELLS122A4849, Operating Temperature Range="-40°C to +110°C"
D3 D17: library part CMP-0028389-2, "Diode, Schottky, 60 V, 1 A, SMA", Manufacturer="Diodes Inc.", Value1=1A, Value2=0.7V
D4 D6 D18: library part CMP-0002894-2, "LED, Green, SMD", Color=green, Manufacturer="Wurth Elektronik", Value1=W, Value2=2V
D5: library part CMP-0028350-2, "Diode, Schottky, 30 V, 3 A, SMA", Manufacturer="Diodes Inc.", Value1=3A, Value2=0.5V
D7_L1 D7_L2 D7_L3 D7_N D8_L1 D8_L2 D8_L3 D8_N D9_L1 D9_L2 D9_L3 D9_N D13_L1 D13_L2 D13_L3 D13_N D14_L1 D14_L2 D14_L3 D14_N D15_L1 D15_L2 D15_L3 D15_N: library part CMP-0122312-1, "Zener Diode 180 V 1 W ±5% Surface Mount DO-213AB (GL41)", Digikey Part Number=ZGL41-180A-E3/96GICT-ND, Manufacturer=Vishay, Max Reverse Leakage Current=1uA, Mouser Part Number=625-ZGL41-180A-E3, Operating Temperature Range="-55°C to +150°C", Power_W=1000mW
D10_L1 D10_L2 D10_L3 D10_N D11_L1 D11_L2 D11_L3 D11_N D12_L1 D12_L2 D12_L3 D12_N D16_L1 D16_L2 D16_L3 D16_N: library part CMP-0091305-2, "Red 630nm LED Indication - Discrete 2V 0603 (1608 Metric)", Color=Red, Digikey Part Number=754-1359-1-ND, Forward Current=20mA, Manufacturer=Kingbright, Mouser Part Number=604-APG1608SURKC/T, Operating Temperature Range="-40°C to +85°C", Power_TotalModule=75mW
F1 F2 F3 F4: library part CMP-0122960-1, "25 A 250 V AC 80 V DC Fuse Board Mount (Cartridge Style Excluded) Surface Mount 2-SMD, Square End Block", Digikey Part Number=SF-3812F2500T-2CT-ND, Fuse Current=25A, Fuse Interrupt Dc Current=130A, Manufacturer=Bourns, Mouser Part Number=652-SF-3812F2500T-2, Operating Temperature Range="-55°C to +125°C"
FB1 FB2 FB3 FB4 FB5 FB6 FB7 FB8 FB9 FB10 FB11 FB14_L1 FB14_L2 FB14_L3 FB14_N FB15_L1 FB15_L2 FB15_L3 FB15_N FB16: library part CMP-0037505-1, "600 Ohms @ 100 MHz 1 Power, Signal Line Ferrite Bead 0603 (1608 Metric) 1A 200mOhm", Digikey Part Number=MH1608-601YCT-ND, Impedance At Frequency="600Ω @ 100MHz", Manufacturer=Bourns, Mouser Part Number=652-MH1608-601Y, Operating Temperature Range="-55°C to +125°C", Test Frequency=100MHz, Tolerance_%=25%
FB12 FB13 FB17 FB18: library part CMP-0041881-1, "Chip Ferrite Bead, 0402, 330Ω @ 100MHz, 0.205Ω, 25%, 1.1A", Impedance At Frequency="330Ω @ 100MHz", Manufacturer=Murata, Operating Temperature Range="-55°C to +125°C", Test Frequency=100MHz, Tolerance_%=25%
FID1 FID2 FID3: library part CMP-0077181-1, "Fiducial mark.  There is nothing to buy or mount.", Manufacturer=N/A
J1: library part CMP-0054820-2, "Receptacle, D-Sub, 9 Position, R/A, TH", Color=Black, Current_A=3A, Manufacturer="Wurth Elektronik", Supplier Part Number 1=16T0655, Voltage_V=125V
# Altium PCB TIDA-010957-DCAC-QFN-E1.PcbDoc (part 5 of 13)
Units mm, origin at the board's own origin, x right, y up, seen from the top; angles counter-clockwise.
Board outline 300 x 300 mm, 4 copper layers (Top Layer, Layer 1, Layer 2, Bottom Layer), stack 1.787 mm thick; 1286 components, 677 nets, 4169 pads, 3428 vias.

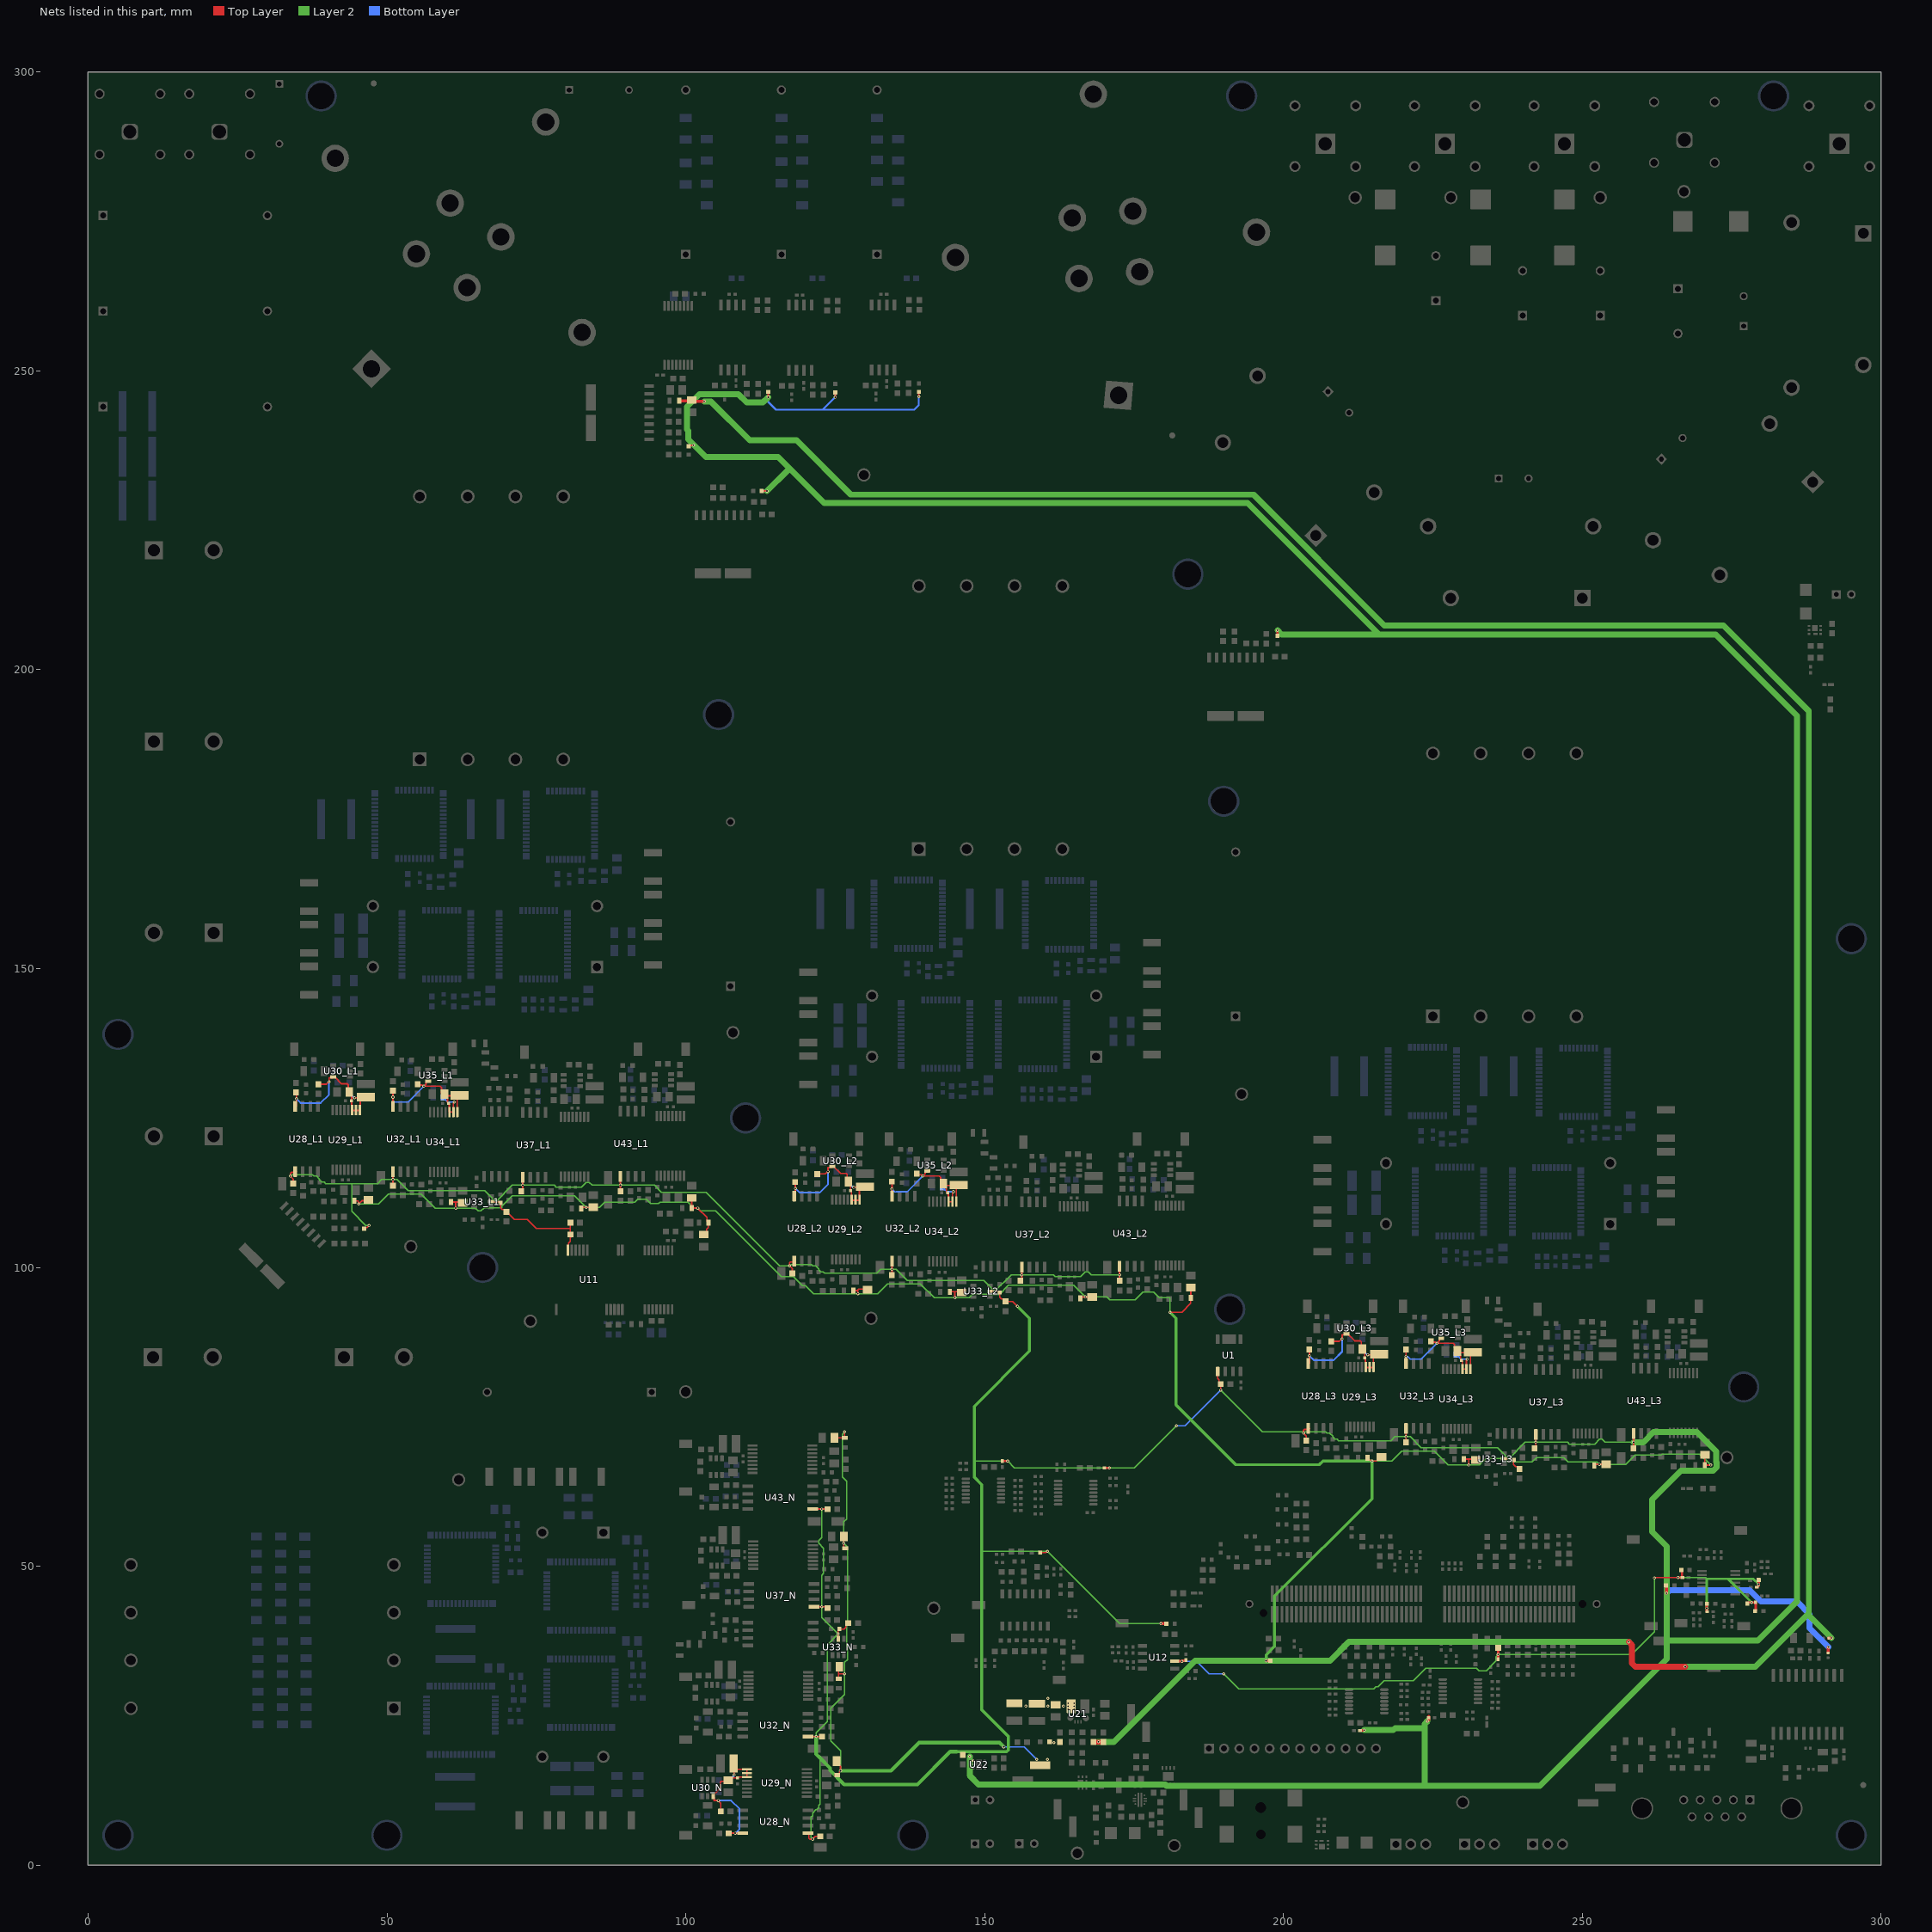
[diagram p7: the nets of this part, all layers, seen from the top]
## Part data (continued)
J2: library part CMP-0055799-1, "Panel Socket, 24A, R/A, Gold, TH", Color=Red, Current_A=24A, Manufacturer="Cliff Electronic Components", Supplier Part Number 1=20T2058, Voltage_V=1kV
J3 J5 J7: library part CMP-0098296-2, "Banana Test Connector, Socket, PCB Mount, 24 A, 1 kV, Gold Plated Contacts, Brown", Current_A=24A, Digikey Part Number=4654-FCR7350N-ND, Manufacturer="CLIFF Electronic Components", Operating Temperature Range="-40°C to +80°C", Voltage_V=1kV
J4 J6 J21: library part CMP-0122568-1, "Mini-Latch™ Wire-to-Board Header, Vertical, with Friction Ramp, 3 Circuits, Gold (Au) Plating", Current_A=3A, Digikey Part Number=23-0022111031-ND, Manufacturer=Molex, Mouser Part Number=538-22-11-1031, Operating Temperature Range="-40°C to +105°C", Voltage_V=250V
J8 J9: library part CMP-0055798-1, "Panel Socket, 24A, R/A, Gold, TH", Color=Black, Current_A=24A, Manufacturer="Cliff Electronic Components", Supplier Part Number 1=20T2055, Voltage_V=1kV
J10: library part CMP-0098294-2, "Banana Test Connector, Socket, PCB Mount, 24 A, 1 kV, Gold Plated Contacts, Green", Current_A=24A, Digikey Part Number=4654-FCR7350G-ND, Manufacturer="CLIFF Electronic Components", Operating Temperature Range="-40°C to +80°C", Voltage_V=1kV
J11 J14 J15 J17 J18: library part CMP-0075491-1, "Header, 100mil, 2x1, Tin, SMD", Color=Black, Current_A=5.4A, Manufacturer=Samtec, Supplier Part Number 1=77P4673, Voltage_V=475V
J12: library part CMP-0003814-2, "C2000 controlCARD-120HSEC connector, SMT", Manufacturer=Samtec
J13: library part CMP-0075424-1, "Header, 100mil, 12x1, Gold, TH", Color=Black, Current_A=6.3A, Manufacturer=Samtec, Supplier Part Number 1=SAM1029-12-ND, Voltage_V=550V
J16: library part CMP-0075012-1, "Power Jack, SMT", Manufacturer="CUI Inc.", Supplier Part Number 1=CP-002AHPJDKR-ND
L1 L2 L5 L6: library part CMP-0127626-1, "Boost Inductor TIDA-010957", Manufacturer=Bourns, Operating Temperature Range="-40°C to +125°C", Test Frequency=100kHz, Tolerance_%=10%
L3: library part CMP-0084086-1, "100µH @ 100kHz 2 Line Common Mode Choke Surface Mount 5.8 kOhms @ 10MHz 150mA DCR 2Ohm", Digikey Part Number=445-3959-1-ND, Impedance At Frequency="5800Ω @ 10MHz", Manufacturer=TDK, Mouser Part Number=810-ACT45B1012PTL003, Operating Temperature Range="-40°C to +150°C", Test Frequency=100kHz, Tolerance_%=+50/-30%
L4_L1 L4_L2 L4_L3 L4_N L18_L1 L18_L2 L18_L3 L18_N L20_L1 L20_L2 L20_L3 L20_N L21_L1 L21_L2 L21_L3 L21_N: library part CMP-0063789-1, "Inductor, 10 uH, 0.5 A, 0.85 ohm, SMD", Manufacturer="Wurth Elektronik", Value1="0.85 ohm", Value2=0.5A, ValueDisplayed=10uH
L7 L8 L9 L11_L1 L11_L2 L11_L3 L11_N L13_L1 L13_L2 L13_L3 L13_N L15_L1 L15_L2 L15_L3 L15_N L17_L1 L17_L2 L17_L3 L17_N: library part CMP-0100992-1, "WE-PMI SMT Power Multilayer Inductor, size 0603, 2.2uH, 0.8A, 375mOhm", Case/Size Code=0603, DC Resistance=375mOhm, Inductance=2.2uH, Inductance Tolerance=20%, Manufacturer="Wurth Elektronik", Operating Temperature Max=125°C, Operating Temperature Min=-40°C, Rated Current=0.8A, Saturation Current=0.28A, Self Resonant Frequency=80MHz
L10_L1 L10_L2 L10_L3 L10_N L12_L1 L12_L2 L12_L3 L12_N L14_L1 L14_L2 L14_L3 L14_N L16_L1 L16_L2 L16_L3 L16_N: library part CMP-0057419-2, "Inductor, Drum Core, Ferrite, 15 uH, 0.65 A, 0.4 ohm, SMD", Manufacturer=Bourns, Supplier Part Number 1=SDR0302-150MLCT-ND, Value1="0.4 ohm", Value2=0.65A, ValueDisplayed=15uH
L12 L19: library part CMP-0127627-2, "4-Phase CMC", Manufacturer=Bourns, Operating Temperature Range="-40°C to +125°C", Test Frequency=100kHz, Tolerance_%=+50/-35%
LBL1: library part CMP-0003625-1, "Thermal Transfer Printable Labels, 0.650\" W x 0.200\" H - 10,000 per roll", Manufacturer=Brady, Supplier Part Number 1=97C5133
Logo1: library part CMP-0074844-1
Logo3: library part CMP-0074847-1, "FCC_disclaimer"
Logo4: library part CMP-0074769-1
LOGO5: library part CMP-0074837-1, "IEC 61010-1 Hot Surface Warning"
LOGO6: library part CMP-0074835-1, "IEC 61010-1 High Voltage Warning"
MP1 MP2 MP3 MP4 MP5 MP6 MP7 MP8 MP9 MP10 MP10 MP11 MP12 MP13 MP14 MP15: library part CMP-0126499-1, "WA-SMST SMT Steel Spacer, Ø3.3 Internal non Stop", Digikey Part Number=732-7081-1-ND, Manufacturer=Wurth, Mouser Part Number=710-9774025960R, Operating Temperature Range="-55°C to +150°C"
Q1 Q2 Q3: library part CMP-0000585-1, "MOSFET, N-CH, 30 V, 22 A, DQK0006C (WSON-6)", Alternate Manufacturer=None, Manufacturer="Texas Instruments", Supplier Part Number 1=296-37193-1-ND, Value1=0.02, Value2="2.4 nC"
R1 R2 R3 R4 R5 R6 R7 R8 R9 R10 R11 R12 R13 R14 R15 R16 R17 R18: library part CMP-0018695-3, "RES, 510 k, 5%, 0.25 W, AEC-Q200 Grade 0, 1206", Manufacturer=Vishay-Dale, Power_W=250mW, Supplier Part Number 1=541-510KECT-ND, TempCo="200 ppm/C", Tolerance_%=5%, Value2=0.25W, Value_Code=510k
R19 R25 R29 R30 R43 R44 R45 R46 R47 R48 R49 R50 R51 R52 R53 R54 R55 R56 R57 R58 R59 R60 R61 R79 R80 R146 R151 R156 R161 R165 R166 R167 R168 R176 R177 R178 R179 R180 R181 R182 R183 R195 R196 R197 R198 R293_L1 R293_L2 R293_L3 R293_N: library part CMP-0026696-1, "RES, 33.0, 1%, 0.1 W, 0402", Manufacturer=Panasonic, Power_W=100mW, Supplier Part Number 1=P33.0LCT-ND, TempCo="100 ppm/C", Tolerance_%=1%, Value2=0.1W, Value_Code=33R0, ValueDisplayed=33.0
R20 R21 R22 R23 R24 R26 R27 R28 R31 R32 R33 R34 R35 R36 R37 R38 R39 R40 R41 R42 R62 R63 R64 R65 R66 R67 R68 R69 R70 R71 R72 R73 R74 R75 R76 R77 R78 R84 R86 R88 R225 R228 R334: library part CMP-0081973-1, "RES, 0, 0%, 0.25 W, AEC-Q200 Grade 0, 0603", Manufacturer=Vishay-Dale, Power_W=250mW, Supplier Part Number 1=541-2779-1-ND, Tolerance_%=0%, Value2=0.25W, Value_Code=0
R81 R82 R233 R234 R235: library part CMP-0025936-5, "RES, 680, 5%, 0.1 W, 0603", Manufacturer=Yageo, Power_W=100mW, Supplier Part Number 1=311-680GRCT-ND, TempCo="100 ppm/C", Tolerance_%=5%, Value2=0.1W, Value_Code=680R, ValueDisplayed=680
R83 R85 R87 R92: library part CMP-0097004-1, "PTCEL Series 500 V 60 Ohm ±30 % Radial Inrush Current Limiter PTC Thermistor", Digikey Part Number=BC3317-ND, Hold Current=120mA, Manufacturer="Vishay Bccomponents", Mouser Part Number=594-PTCEL13R600LBE, Operating Temperature Range="-40°C to +105°C", Tolerance_%=30%
R89 R90 R91 R94: library part CMP-0096768-1, "5 kA Varistor 1 Circuit Through Hole Disc 17mm", Clamping Voltage=730V, Digikey Part Number=118-ISOM5-275-B-L2-ND, Manufacturer=Bourns, Mouser Part Number=652-ISOM5-275-B-L2, Operating Temperature Range="-40°C to +125°C", ValueDisplayed=40pF
R93 R217: library part CMP-0082532-1, "RES, 499, 1%, 0.1 W, 0603", Manufacturer=Vishay-Dale, Power_W=100mW, Supplier Part Number 1=541-3986-1-ND, TempCo="100 ppm/C", Tolerance_%=1%, Value2=0.1W, Value_Code=499R, ValueDisplayed=499
R95_L1 R95_L2 R95_L3 R95_N R229_L1 R229_L2 R229_L3 R229_N R230_L1 R230_L2 R230_L3 R230_N R231_L1 R231_L2 R231_L3 R231_N: library part CMP-0023037-5, "RES, 33.0 k, 1%, 0.1 W, 0603", Manufacturer=Yageo, Power_W=100mW, Supplier Part Number 1=311-33.0KHRCT-ND, TempCo="100 ppm/C", Tolerance_%=1%, Value2=0.1W, Value_Code=33k0, ValueDisplayed=33.0k
R96 R130 R131 R132 R133 R134 R135: library part CMP-0026656-1, "RES, 100, 1%, 0.1 W, 0402", Manufacturer=Panasonic, Power_W=100mW, Supplier Part Number 1=P100LCT-ND, TempCo="100 ppm/C", Tolerance_%=1%, Value2=0.1W, Value_Code=100R, ValueDisplayed=100
R97 R99 R105 R109 R113 R117 R121 R123 R129 R284_L1 R284_L2 R284_L3 R284_N R287_L1 R287_L2 R287_L3 R287_N R295_L1 R295_L2 R295_L3 R295_N R298_L1 R298_L2 R298_L3 R298_N R305_L1 R305_L2 R305_L3 R305_N R308_L1 R308_L2 R308_L3 R308_N R322_L1 R322_L2 R322_L3 R322_N R325_L1 R325_L2 R325_L3 R325_N: library part CMP-0021998-4, "RES, 10.0 k, 1%, 0.1 W, AEC-Q200 Grade 0, 0603", Manufacturer=Vishay-Dale, Power_W=100mW, Supplier Part Number 1=541-10.0KHCT-ND, TempCo="100 ppm/C", Tolerance_%=1%, Value2=0.1W, Value_Code=10k0, ValueDisplayed=10.0k
R98 R100 R102 R103 R106 R107 R110 R111 R114 R115 R118 R119 R122 R124 R126 R127 R139 R141 R145 R147 R150 R152 R155 R157 R160 R162 R331 R333: library part CMP-0077124-1, "RES, 10.0 k, 0.1%, 0.1 W, AEC-Q200 Grade 0, 0402", Manufacturer=Vishay/Beyschlag, Power_W=100mW, Supplier Part Number 1=MCS0402-10.0K-MBCT-ND, TempCo="25 ppm/C", Tolerance_%=0.1%, Value2=0.1W, Value_Code=10k0, ValueDisplayed=10.0k
R101 R108 R116 R125 R140: library part CMP-0026283-2, "RES, 309, 1%, 0.063 W, AEC-Q200 Grade 0, 0402", Manufacturer=Vishay-Dale, Power_W=63mW, Supplier Part Number 1=541-309LCT-ND, TempCo="100 ppm/C", Tolerance_%=1%, Value2=0.063W, Value_Code=309R, ValueDisplayed=309
R104 R112 R120 R128: library part CMP-0023112-5, "RES, 43.2 k, 1%, 0.1 W, 0603", Manufacturer=Yageo, Power_W=100mW, Supplier Part Number 1=311-43.2KHRCT-ND, TempCo="100 ppm/C", Tolerance_%=1%, Value2=0.1W, Value_Code=43k2, ValueDisplayed=43.2k
R136 R143: library part CMP-0078244-2, "RES, 30.0 k, 1%, 0.063 W, AEC-Q200 Grade 0, 0402", Manufacturer=Vishay-Dale, Power_W=63mW, Supplier Part Number 1=541-30.0KLCT-ND, TempCo="100 ppm/C", Tolerance_%=1%, Value2=0.063W, Value_Code=30k0, ValueDisplayed=30.0k
R137 R142: library part CMP-0065359-1, "RES, 15.0 k, .1%, .063 W, AEC-Q200 Grade 0, 0402", Manufacturer=Panasonic, Power_W=63mW, Supplier Part Number 1=P15KDCCT-ND, TempCo="25 ppm/C", Tolerance_%=0.1%, Value1=.1%, Value2=.063W, Value_Code=15k0, ValueDisplayed=15.0k
R138: library part CMP-0027004-2, "RES, 0, 5%, 0.063 W, 0402", Manufacturer="Yageo America", Power_W=63mW, Supplier Part Number 1=311-0.0JRCT-ND, TempCo="200 ppm/C", Tolerance_%=5%, Value2=0.063W, Value_Code=0000, ValueDisplayed=0
R144 R148 R149 R153 R154 R158 R159 R163: library part CMP-0023778-2, "RES, 15.6 k, 0.1%, 0.1 W, 0603", Manufacturer="Yageo America", Power_W=100mW, TempCo="25 ppm/C", Tolerance_%=0.1%, Value2=0.1W, Value_Code=15k6, ValueDisplayed=15.6k
R164 R174 R175 R194 R332: library part CMP-0026827-3, "RES, 10, 5%, 0.063 W, AEC-Q200 Grade 0, 0402", Manufacturer=Vishay-Dale, Power_W=63mW, Supplier Part Number 1=541-10JCT-ND, TempCo="200 ppm/C", Tolerance_%=5%, Value2=0.063W, Value_Code=10R0, ValueDisplayed=10
R169 R170 R171 R172 R173 R184 R185 R186 R187 R188 R189 R190 R191 R192 R193 R199 R200 R201 R202 R203 R224 R330: library part CMP-0025958-3, "RES, 10.0 k, 1%, 0.063 W, AEC-Q200 Grade 0, 0402", Manufacturer=Vishay-Dale, Power_W=63mW, Supplier Part Number 1=541-10.0KLCT-ND, TempCo="100 ppm/C", Tolerance_%=1%, Value2=0.063W, Value_Code=10k0, ValueDisplayed=10.0k
R204: library part CMP-0023128-4, "RES, 470 k, 1%, 0.1 W, 0603", Manufacturer=Yageo, Power_W=100mW, Supplier Part Number 1=311-470KHRCT-ND, TempCo="100 ppm/C", Tolerance_%=1%, Value2=0.1W, Value_Code=470k
R205 R209 R211 R219: library part CMP-0023133-5, "RES, 47.0 k, 1%, 0.1 W, 0603", Manufacturer=Yageo, Power_W=100mW, Supplier Part Number 1=311-47.0KHRCT-ND, TempCo="100 ppm/C", Tolerance_%=1%, Value2=0.1W, Value_Code=47k0, ValueDisplayed=47.0k
R206: library part CMP-0022870-5, "RES, 1.10 k, 1%, 0.1 W, 0603", Manufacturer=Yageo, Power_W=100mW, Supplier Part Number 1=311-1.10KHRCT-ND, TempCo="100 ppm/C", Tolerance_%=1%, Value2=0.1W, Value_Code=1k10, ValueDisplayed=1.10k
R207: library part CMP-0023203-5, "RES, 5.60 k, 1%, 0.1 W, 0603", Manufacturer=Yageo, Power_W=100mW, Supplier Part Number 1=311-5.60KHRCT-ND, TempCo="100 ppm/C", Tolerance_%=1%, Value2=0.1W, Value_Code=5k60, ValueDisplayed=5.60k
R208: library part CMP-0022763-5, "RES, 11.0 k, 1%, 0.1 W, 0603", Manufacturer=Yageo, Power_W=100mW, Supplier Part Number 1=311-11.0KHRCT-ND, TempCo="100 ppm/C", Tolerance_%=1%, Value2=0.1W, Value_Code=11k0, ValueDisplayed=11.0k
R210: library part CMP-0023000-5, "RES, 2.00 k, 1%, 0.1 W, 0603", Manufacturer=Yageo, Power_W=100mW, Supplier Part Number 1=311-2.00KHRCT-ND, TempCo="100 ppm/C", Tolerance_%=1%, Value2=0.1W, Value_Code=2k00, ValueDisplayed=2.00k
R212: library part CMP-0022816-5, "RES, 15.0 k, 1%, 0.1 W, 0603", Manufacturer=Yageo, Power_W=100mW, Supplier Part Number 1=311-15.0KHRCT-ND, TempCo="100 ppm/C", Tolerance_%=1%, Value2=0.1W, Value_Code=15k0, ValueDisplayed=15.0k
R213: library part CMP-0023180-5, "RES, 54.9 k, 1%, 0.1 W, 0603", Manufacturer=Yageo, Power_W=100mW, Supplier Part Number 1=311-54.9KHRCT-ND, TempCo="100 ppm/C", Tolerance_%=1%, Value2=0.1W, Value_Code=54k9, ValueDisplayed=54.9k
R214: library part CMP-0022917-4, "RES, 220 k, 1%, 0.1 W, 0603", Manufacturer=Yageo, Power_W=100mW, Supplier Part Number 1=311-220KHRCT-ND, TempCo="100 ppm/C", Tolerance_%=1%, Value2=0.1W, Value_Code=220k
R215 R218: library part CMP-0023020-5, "RES, 30.0 k, 1%, 0.1 W, 0603", Manufacturer=Yageo, Power_W=100mW, Supplier Part Number 1=311-30.0KHRCT-ND, TempCo="100 ppm/C", Tolerance_%=1%, Value2=0.1W, Value_Code=30k0, ValueDisplayed=30.0k
R216 R240 R245 R250: library part CMP-0023404-3, "RES, 10.0 k, 0.1%, 0.1 W, 0603", Manufacturer="Susumu Co Ltd", Power_W=100mW, Supplier Part Number 1=RG16P10.0KBCT-ND, TempCo="25 ppm/C", Tolerance_%=0.1%, Value2=0.1W, Value_Code=10k0, ValueDisplayed=10.0k
R220 R221 R222 R223: library part CMP-0124381-1, "Power Relay 12VDC 25A SPST-NO(30.1x15.7x23.3)mm THT", Coil Power_W=780mW, Coil Resistance=185Ω, Coil Voltage_VDC=12V, Contact Rating_A=25A, Manufacturer="FCL Components", Mouser Part Number=817-FTR-K3AB012W-WG, Operating Temperature Range="-40°C to +85°C"
R226 R227: library part CMP-0025431-3, "RES, 59.7, 0.5%, 0.1 W, 0603", Manufacturer="Yageo America", Power_W=100mW, TempCo="50 ppm/C", Tolerance_%=0.5%, Value2=0.1W, Value_Code=59R7, ValueDisplayed=59.7
R232_L1 R232_L2 R232_L3 R232_N R278_L1 R278_L2 R278_L3 R278_N R279_L1 R279_L2 R279_L3 R279_N R291_L1 R291_L2 R291_L3 R291_N R292_L1 R292_L2 R292_L3 R292_N R302_L1 R302_L2 R302_L3 R302_N R303_L1 R303_L2 R303_L3 R303_N R316_L1 R316_L2 R316_L3 R316_N R317_L1 R317_L2 R317_L3 R317_N: library part CMP-0025787-4, "RES, 33, 5%, 0.1 W, AEC-Q200 Grade 0, 0603", Manufacturer=Vishay-Dale, Power_W=100mW, Supplier Part Number 1=541-33GCT-ND, TempCo="200 ppm/C", Tolerance_%=5%, Value2=0.1W, Value_Code=33R0, ValueDisplayed=33
R236 R237 R238 R239 R241 R242 R243 R244 R246 R247 R248 R249: library part CMP-0097198-1, "1 MOhms ±0.1% 0.25W, 1/4W Chip Resistor 1206 (3216 Metric) Anti-Sulfur, Automotive AEC-Q200, High Voltage Thin Film", Digikey Part Number=408-RGV3216P-1004-B-T1CT-ND, Manufacturer=Susumu, Mouser Part Number=754-RGV3216P-1004BT1, Operating Temperature Range="-55°C to +155°C", Power_W=250mW, TempCo=25ppm/°C, Tolerance_%=0.1%
R281_L1 R281_L2 R281_L3 R281_N R282_L1 R282_L2 R282_L3 R282_N R319_L1 R319_L2 R319_L3 R319_N R320_L1 R320_L2 R320_L3 R320_N: library part CMP-0016570-3, "RES, 100, 1%, 0.5 W, AEC-Q200 Grade 0, 1206", Manufacturer=Vishay-Dale, Power_W=500mW, Supplier Part Number 1=541-100UCT-ND, TempCo="100 ppm/C", Tolerance_%=1%, Value2=0.5W, Value_Code=100R, ValueDisplayed=100
R285_L1 R285_L2 R285_L3 R285_N R296_L1 R296_L2 R296_L3 R296_N R306_L1 R306_L2 R306_L3 R306_N R323_L1 R323_L2 R323_L3 R323_N: library part CMP-0022746-5, "RES, 10.0 k, 1%, 0.1 W, 0603", Manufacturer=Yageo, Power_W=100mW, Supplier Part Number 1=311-10.0KHRCT-ND, TempCo="100 ppm/C", Tolerance_%=1%, Value2=0.1W, Value_Code=10k0, ValueDisplayed=10.0k
R286_L1 R286_L2 R286_L3 R286_N R297_L1 R297_L2 R297_L3 R297_N R307_L1 R307_L2 R307_L3 R307_N R324_L1 R324_L2 R324_L3 R324_N: library part CMP-0025771-4, "RES, 2.7 k, 5%, 0.1 W, AEC-Q200 Grade 0, 0603", Manufacturer=Vishay-Dale, Power_W=100mW, Supplier Part Number 1=541-2.7KGCT-ND, TempCo="200 ppm/C", Tolerance_%=5%, Value2=0.1W, Value_Code=2k70, ValueDisplayed=2.7k
R288_L1 R288_L2 R288_L3 R288_N R299_L1 R299_L2 R299_L3 R299_N R309_L1 R309_L2 R309_L3 R309_N R326_L1 R326_L2 R326_L3 R326_N: library part CMP-0024852-2, "RES, 1.00 k, 0.5%, 0.1 W, 0603", Manufacturer="Yageo America", Power_W=100mW, TempCo="50 ppm/C", Tolerance_%=0.5%, Value2=0.1W, Value_Code=1k00, ValueDisplayed=1.00k
R289_L1 R289_L2 R289_L3 R289_N R300_L1 R300_L2 R300_L3 R300_N R310_L1 R310_L2 R310_L3 R310_N R327_L1 R327_L2 R327_L3 R327_N: library part CMP-0025942-5, "RES, 8.2 k, 5%, 0.1 W, 0603", Manufacturer=Yageo, Power_W=100mW, Supplier Part Number 1=311-8.2KGRCT-ND, TempCo="100 ppm/C", Tolerance_%=5%, Value2=0.1W, Value_Code=8k20, ValueDisplayed=8.2k
R290_L1 R290_L2 R290_L3 R290_N R301_L1 R301_L2 R301_L3 R301_N R311_L1 R311_L2 R311_L3 R311_N R328_L1 R328_L2 R328_L3 R328_N: library part CMP-0025930-5, "RES, 560, 5%, 0.1 W, 0603", Manufacturer=Yageo, Power_W=100mW, Supplier Part Number 1=311-560GRCT-ND, TempCo="100 ppm/C", Tolerance_%=5%, Value2=0.1W, Value_Code=560R, ValueDisplayed=560
R312_L1 R312_L2 R312_L3 R312_N R313_L1 R313_L2 R313_L3 R313_N R314_L1 R314_L2 R314_L3 R314_N: library part CMP-0124370-1, "680 kOhms ±0.1% 0.2W, 1/5W Chip Resistor 0805 (2012 Metric) Anti-Sulfur, Automotive AEC-Q200, High Voltage, Moisture Resistant Thin Film", Digikey Part Number=541-TNPV0805680KBEEACT-ND, Manufacturer=Vishay, Mouser Part Number=71-TNPV0805680KBEEA, Operating Temperature Range="-55°C to +125°C", Power_W=200mW, TempCo=25ppm/°C, Tolerance_%=0.1%
R315_L1 R315_L2 R315_L3 R315_N: library part CMP-0122747-1, "8 kOhms ±0.1% 0.1W, 1/10W Chip Resistor 0603 (1608 Metric) Thin Film", Digikey Part Number=13-RT0603BRE078KLCT-ND, Manufacturer=Yageo, Mouser Part Number=603-RT0603BRE078KL, Operating Temperature Range="-55°C to +155°C", Power_W=100mW, TempCo=50ppm/°C, Tolerance_%=0.1%
R329: library part CMP-0026874-3, "RES, 200, 5%, 0.063 W, AEC-Q200 Grade 0, 0402", Manufacturer=Vishay-Dale, Power_W=63mW, Supplier Part Number 1=541-200JCT-ND, TempCo="200 ppm/C", Tolerance_%=5%, Value2=0.063W, Value_Code=200R, ValueDisplayed=200
TP1 TP2 TP3 TP4 TP6 TP7 TP8 TP9 TP10 TP11 TP12 TP13 TP25 TP26 TP40: library part CMP-0055148-2, "Test Point, Multipurpose, Black, TH", Color=Black, Manufacturer="Keystone Electronics", Supplier Part Number 1=36-5011-ND
TP5 TP39: library part CMP-0055147-2, "Test Point, Multipurpose, Red, TH", Color=Red, Manufacturer="Keystone Electronics", Supplier Part Number 1=36-5010-ND
TP14_L1 TP14_L2 TP14_L3 TP14_N TP15_L1 TP15_L2 TP15_L3 TP15_N TP16_L1 TP16_L2 TP16_L3 TP16_N TP17_L1 TP17_L2 TP17_L3 TP17_N TP18_L1 TP18_L2 TP18_L3 TP18_N TP19_L1 TP19_L2 TP19_L3 TP19_N TP20_L1 TP20_L2 TP20_L3 TP20_N TP21_L1 TP21_L2 TP21_L3 TP21_N TP22_L1 TP22_L2 TP22_L3 TP22_N TP23_L1 TP23_L2 TP23_L3 TP23_N TP24_L1 TP24_L2 TP24_L3 TP24_N TP27 TP28 TP29 TP30 TP31 TP32 TP33 TP34 TP35 TP36 TP37 TP38: library part CMP-0003968-1, "Test Point, SMT", Manufacturer=Harwin, Supplier Part Number 1=952-2664-1-ND
U1: library part CMP-0122473-1, "Automotive ±1.5°C, 3-kVRMS Isolated Temperature Sensor With Analog Output With < 2 Seconds Response Time and 500VRMS Working Voltage", Manufacturer="Texas Instruments", Max Supply Voltage=5.5V, Min Supply Voltage=2.3V, Operating Supply Current=10uA, Operating Temperature Range="-40°C to +150°C"
U2 U4 U5 U6: library part CMP-0127485-1, "80ARMS 500kHz Hall-effect current sensor with AFR, reference and ALERT 10-SOIC -40 to 125", Coil Resistance=0.7mΩ, Current Sensitivity=33mV/A, Digikey Part Number=296-TMCS1126B9AQDVGRTR-ND, Manufacturer="Texas Instruments", Max Sensing Current=98.5A, Max Supply Voltage=5.5V, Min Supply Voltage=3V, Mouser Part Number=595-TMCS1126B9AQDVGR, Operating Supply Current=11mA, Operating Temperature Range="-40°C to +125°C"
U3: library part CMP-0121217-1, "Zero-Drift Amplifier 4 Circuit Rail-to-Rail 14-TSSOP", Digikey Part Number=296-OPA4388IPWRCT-ND, Input Bias Current=0.00003uA, Input Offset Voltage=0.00225mV, Manufacturer="Texas Instruments", Max Dual Supply Voltage=2.75V, Max Supply Voltage=5.5V, Min Dual Supply Voltage=1.25V, Min Supply Voltage=2.5V, Mouser Part Number=595-OPA4388IPWR, Nominal Supply Current=1.7-1.9mA, Operating Temperature Range="-40°C to +125°C", Output Current Per Channel=60mA, Voltage Gain=126dB
U7 U8 U9: library part CMP-0122725-1, "Automotive, Precision, ±1V Input Isolated Amplifiers With Single-Ended, Ratiometric Output", Input Bias Current=0.0035uA, Input Offset Voltage=0.4mV, Manufacturer="Texas Instruments", Max Supply Voltage=5.5V, Min Supply Voltage=3V, Operating Temperature Range="-40°C to +125°C", Output Current Per Channel=14mA
U10 U13: library part CMP-0123146-1, "Ultra-Small, 1.5W, 5.0V, 5kVRMS Isolation, Industrial DC/DC Module", Manufacturer="Texas Instruments", Max Supply Voltage=5.5V, Min Supply Voltage=4.5V, Nominal Supply Current=7-545mA, Operating Temperature Range="-40°C to +125°C", Output Voltage=5/5.5V, Switching Frequency=76MHz
U11: library part CMP-0044881-2, Manufacturer="Texas Instruments", Operating Temperature Range=to
U12: library part CMP-0121707-1, "Precision, Low-Offset-Voltage, Low-Noise, Low-Input-Bias-Current, Rail-to-Rail I/O, e-trim™ Operational Amplifiers", Digikey Part Number=296-OPA2392DRCT-ND, Input Bias Current=0.00000001uA, Input Offset Voltage=0.001mV, Manufacturer="Texas Instruments", Max Dual Supply Voltage=2.75V, Max Supply Voltage=5.5V, Min Dual Supply Voltage=850mV, Min Supply Voltage=1.7V, Mouser Part Number=595-OPA2392DR, Nominal Supply Current=1.22mA, Operating Temperature Range="-40°C to +125°C", Output Current Per Channel=65mA, Voltage Gain=132dB
U14: library part CMP-0097120-1, "Op Amp Quad Zero Drift Amplifier R-R I/O ±2.75V/5.5V 14-Pin SOIC T/R", Digikey Part Number=296-53511-1-ND, Input Bias Current=0.00003uA, Input Offset Voltage=0.00225mV, Manufacturer="Texas Instruments", Max Dual Supply Voltage=2.75V, Max Supply Voltage=5.5V, Min Dual Supply Voltage=1.25V, Min Supply Voltage=2.5V, Mouser Part Number=595-OPA4388IDR, Nominal Supply Current=1.7-1.9mA, Operating Temperature Range="-40°C to +125°C", Output Current Per Channel=60mA, Voltage Gain=148dB
U15 U16 U17 U18: library part CMP-0066280-1, "Quadruple Bus Buffer Gate with 3-State Outputs, PW0014A (TSSOP-14)", Alternate Manufacturer="Texas Instruments", Alternate PartNumber=SN74LVC126APW
U19: library part CMP-0088329-1, "2.7- 23V, 5.5 A, 28 mΩ Reverse Current Blocking eFuse with Input Reverse Polarity Protection", Manufacturer="Texas Instruments", Max Supply Voltage=23V, Min Supply Voltage=2.7V, Nominal Supply Current=0.5-6A, Operating Temperature Range="-40°C to +125°C", Output Voltage=42V, Threshold Voltage=1.2/1.1V
U20: library part CMP-0083940-3, "14 V Bidirectional Flat-Clamp Surge Protection Device, DRB0008A (VSON-8)", Alternate Manufacturer="Texas Instruments", Alternate PartNumber=TVS1401DRBT, Operating Temperature Range="-40 to 125 C"
U21: library part CMP-0034908-2, "3V to 16 V Input, 3-A Synchronous Step-Down Voltage Regulator Module, QFN-FCMOD7", Manufacturer="Texas Instruments", Max Supply Voltage=17V, Min Supply Voltage=3V, Nominal Supply Current=100-400uA, Operating Temperature Range="-40°C to +125°C", Output Voltage=0.6-10V, Switching Frequency=1.2MHz
U22: library part CMP-0013427-7, "500mA LDO, DRV0006A (WSON-6)", Alternate Manufacturer="Texas Instruments"
U23: library part CMP-0092023-2, "Reinforced 5-kVRMS Isolated CAN Transceiver with Integrated lowemissions DC-DC Converter", Manufacturer="Texas Instruments", Max Supply Voltage=5.5V, Min Supply Voltage=1.71V, Nominal Supply Current=0.3-124mA, Operating Temperature Range="-40°C to +105°C"
U24 U25: library part CMP-0120116-1, "±24 V Low Capacitance Surge Diode for Industrial Networks in SOT-23 Package", Breakdown Voltage=25.5V, Clamping Voltage=35V, Digikey Part Number=296-TSM24CADBZRCT-ND, Manufacturer="Texas Instruments", Mouser Part Number=595-TSM24CADBZR, Operating Temperature Range="-55°C to +150°C", ValueDisplayed=14pF
U26_L1 U26_L2 U26_L3 U26_N U27_L1 U27_L2 U27_L3 U27_N U31_L1 U31_L2 U31_L3 U31_N U36_L1 U36_L2 U36_L3 U36_N: library part CMP-0094891-2, "650-V 30-mΩ GaN FET with Integrated Driver, Protection, and Temperature Reporting", Manufacturer="Texas Instruments", Max Supply Voltage=18V, Min Supply Voltage=7.5V, Nominal Supply Current=16mA, Operating Temperature Range="-40°C to +150°C", Output Voltage=520V
U28_L1 U28_L2 U28_L3 U28_N U32_L1 U32_L2 U32_L3 U32_N U37_L1 U37_L2 U37_L3 U37_N U43_L1 U43_L2 U43_L3 U43_N: library part CMP-0085676-1, "High Speed, Robust EMC Reinforced Dual-Channel Digital Isolator, DWV0008A (SOIC-8)", Alternate Manufacturer="Texas Instruments", Alternate PartNumber=ISO7721FDWVR, Operating Temperature Range="-55 to 125 C", Rating=Catalog
U29_L1 U29_L2 U29_L3 U29_N U34_L1 U34_L2 U34_L3 U34_N U39_L1 U39_L2 U39_L3 U39_N U44_L1 U44_L2 U44_L3 U44_N: library part CMP-0120108-2, "1.5W, High-Density, >5 kVRMS Isolated DC-DC Converter", Manufacturer="Texas Instruments", Max Supply Voltage=5.5V, Min Supply Voltage=4.5V, Operating Temperature Range="-40°C to +125°C", Output Voltage=5/5.5V
U30_L1 U30_L2 U30_L3 U30_N U35_L1 U35_L2 U35_L3 U35_N U40_L1 U40_L2 U40_L3 U40_N U45_L1 U45_L2 U45_L3 U45_N: library part CMP-0013231-2, "28-V Output Voltage Boost Converter with Power Diode and Isolation Switch, DBV0006A (SOT-6)", Alternate Manufacturer="Texas Instruments", Alternate PartNumber=TLV61046ADBVT
U33_L1 U33_L2 U33_L3 U33_N: library part CMP-0051219-1, "Single 3-Input Positive-AND Gate, DBV0006A, LARGE T&R", F @ Nom Voltage(Max)(Mhz)=150, Generic Part Number=SN74LVC1G11, ICC @ Nom Voltage(Max)(mA)=0.01, Manufacturer="Texas Instruments", Operating Temperature Range(C)="-40 to 125,-40 to 85", Rating=Catalog, tpd @ Nom Voltage(Max)(ns)=20,7.8,6.2,4.6, Voltage(Nom)(V)=1.8,2.5,3.3,5
U41_L1 U41_L2 U41_L3 U41_N: library part CMP-0124047-1, "Precision, 2V Input, Basic and Reinforced Isolated Amplifiers With Fixed-Gain Differential Output", Input Bias Current=3.5nA, Input Offset Voltage=0.2mV, Manufacturer="Texas Instruments", Max Supply Voltage=5.5V, Min Supply Voltage=3V, Operating Temperature Range="-40°C to +125°C", Output Current Per Channel=11mA, Voltage Gain=1V/V
ZZ1: library part CMP-0003616-3
ZZ2: library part CMP-0077236-1
ZZ3: library part CMP-0077237-1
ZZ4: library part CMP-0077238-1

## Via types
v1: diameter 0.508, hole 0.254, Top Layer to Bottom Layer, tented both sides, 3428 vias

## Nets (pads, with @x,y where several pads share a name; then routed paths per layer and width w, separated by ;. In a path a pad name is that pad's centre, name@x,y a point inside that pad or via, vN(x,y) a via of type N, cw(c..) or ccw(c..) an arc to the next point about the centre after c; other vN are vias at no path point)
1V65: C5.1 C29.2 C35.2 C41.2 C48.2 C263.2 R38.1 R98.2 R106.2 R114.2 R122.2 R332.1 U12.6 | length 135.1
  Top Layer w0.2: v1@262,48 v1(262.055,48.055) 262.11,48.11 v1(266.01,48.11) ; R106.2@278.996,43.935 R106.2@278.996,43.985
  Top Layer w0.4: U12.6@181.8,34.14 v1@183,34.14 ; v1(183,34.1) 183.029,34.1 183.137,34.208 183.65,34.208 183.7,34.258 R332.1@183.7,34.3 ; C263.2@235.925,34.45 v1(235.925,35.25) R38.1@235.925,36.35 ; v1@266,48.1 v1(266.01,48.11) 266.019,48.119 266.725,48.119 266.675,48.169 266.675,49.275 C48.2@266.55,49.4 ; C29.2@270.849,43.726 270.826,43.576 270.826,42.45 270.876,42.4 R98.2@270.9,42.4 ; C35.2@277.617,43.782 277.767,43.932 277.998,43.932 278.001,43.935 v1(278.342,43.935) R106.2@278.996,43.935 ; C5.1@278.9,42.5 278.996,42.596 R106.2@278.996,43.985 ; R114.2@279.185,46.5 279.235,46.5 279.5,46.765 v1(279.5,46.994) C41.2@279.5,47.719
  Layer 2 w0.2: v1(190,32) 192.5,29.5 215.117,29.5 215.471,29.854 215.837,29.854 216.849,30.866 221.694,30.866 223.782,32.954 232.329,32.954 232.737,32.546 233.929,32.546 235.554,34.171 235.554,34.838 235.925,35.209 v1(235.925,35.25) 258.25,35.25 262.055,39.055 v1(262.055,48.055) ; v1(266.01,48.11) 270.626,48.11 270.826,47.91
  Layer 2 w0.4: v1(270.826,42.962) 270.826,47.91 274.367,47.91 ; v1(278.342,43.935) 274.367,47.91 ; v1(279.5,46.994) 278.584,47.91 274.367,47.91
  Bottom Layer w0.2: v1(183,34.1) 185.45,34.1 187.55,32 v1(190,32)
  Bottom Layer w0.4: v1(235.925,35.25) 235.925,35.279 v1@235.992,35.346
3V3: C13.1 C80.2 C81.1 C145.1 C186_L1.1 C186_L2.1 C186_L3.1 C186_N.1 C200_L1.1 C200_L2.1 C200_L3.1 C200_N.1 C223_L1.1 C223_L2.1 C223_L3.1 C223_N.1 C224_L1.1 C224_L2.1 C224_L3.1 C224_N.1 C243_L1.1 C243_L2.1 C243_L3.1 C243_N.1 FB2.1 FB3.1 FB4.1 FB5.1 FB6.1 FB7.2 FB8.2 FB9.2 FB11.1 FB13.1 FB14_L1.1 FB14_L2.1 FB14_L3.1 FB14_N.1 FB16.2 R164.2 R174.2 R175.2 R194.2 U1.1 U11.14 U22.1 U28_L1.1 U28_L2.1 U28_L3.1 U28_N.1 U32_L1.1 U32_L2.1 U32_L3.1 U32_N.1 U33_L1.5 U33_L2.5 U33_L3.5 U33_N.5 U37_L1.1 U37_L2.1 U37_L3.1 U37_N.1 U43_L1.1 U43_L2.1 U43_L3.1 U43_N.1 | length 1284.1
  Top Layer w0.2: FB6.1@46.2,106.5 46.383,106.683 46.683,106.683 v1(47,107) ; U33_L1.5@67.375,111 v1(68.2,111) 68.8,111 FB14_L1.1@69,110.8 69,110.003 69.309,109.694 69.625,109.694 70,109.319 C223_L1.1@70,109.3 71.3,108 73.5,108 75,106.5 80.633,106.5 80.7,106.433 ; U11.14@80.279,102.904 80.404,103.029 80.404,104.052 80.686,104.334 80.686,104.961 80.75,105.025 80.75,105.5 80.7,105.55 80.7,106.433 ; C80.2@80.7,107.5 80.7,106.433 ; U33_N.5@125.5,37.875 v1(125.5,38.7) 125.5,39.3 FB14_N.1@125.7,39.5 126.497,39.5 126.806,39.809 126.806,40.125 127.181,40.5 C223_N.1@127.2,40.5 ; C145.1@146.35,18.477 C145.1@146.464,18.363 ; U33_L2.5@150.875,96 v1(151.7,96) 152.3,96 FB14_L2.1@152.5,95.8 152.5,95.003 152.809,94.694 153.125,94.694 153.5,94.319 C223_L2.1@153.5,94.3 154.7,94.3 v1(155.5,93.5) ; FB11.1@159.284,52.3 160.217,52.3 160.417,52.5 v1(160.5,52.5) ; U1.1@188.995,82.6 188.995,81.405 189.2,81.2 189.2,80.8 C13.1@189.5,80.5 v1(189.5,79.5) ; R175.2@212.8,22.5 R175.2@212.85,22.55 ; v1@213.45,22.55 v1(213.5,22.6) ; U33_L3.5@236.875,68 v1(237.7,68) 238.3,68 FB14_L3.1@238.5,67.8 238.5,67.003 238.809,66.694 239.125,66.694 239.5,66.319 C223_L3.1@239.5,66.3 ; FB5.1@264,46.8 FB5.1@264.1,46.7 ; FB13.1@291.1,35.5 FB13.1@291.15,35.55 ; v1@291.15,36.45 v1(291.2,36.5)
  Top Layer w0.254: C186_L1.1@34.325,114.03 34.325,114.807 v1(33.85,115.282) 33.85,115.752 33.999,115.901 34.672,115.901 34.821,116.05 U28_L1.1@34.845,116.05 ; C200_L1.1@51.005,113.708 v1(51.005,114.692) U32_L1.1@51.005,116.05 ; C224_L1.1@72.5,112.755 72.724,112.979 v1(72.724,113.755) U37_L1.1@72.724,115.05 ; C243_L1.1@89.073,112.755 v1(89.073,113.755) U43_L1.1@89.073,115.226 ; C186_L2.1@117.825,99.03 117.825,99.807 v1(117.35,100.282) 117.35,100.752 117.499,100.901 118.172,100.901 118.321,101.05 U28_L2.1@118.345,101.05 ; U28_N.1@120.45,5.345 120.45,5.321 120.599,5.172 120.599,4.499 120.748,4.35 v1(121.218,4.35) 121.693,4.825 C186_N.1@122.47,4.825 ; U32_N.1@120.45,21.505 v1(121.808,21.505) C200_N.1@122.792,21.505 ; U43_N.1@121.274,59.573 v1(122.745,59.573) C243_N.1@123.745,59.573 ; U37_N.1@121.45,43.224 v1(122.745,43.224) 123.521,43.224 C224_N.1@123.745,43 ; C200_L2.1@134.505,98.708 v1(134.505,99.692) U32_L2.1@134.505,101.05 ; C224_L2.1@156,97.755 156.224,97.979 v1(156.224,98.755) U37_L2.1@156.224,100.05 ; C243_L2.1@172.573,97.755 v1(172.573,98.755) U43_L2.1@172.573,100.226 ; C186_L3.1@203.825,71.03 203.825,71.807 v1(203.35,72.282) 203.35,72.752 203.499,72.901 204.172,72.901 204.321,73.05 U28_L3.1@204.345,73.05 ; C200_L3.1@220.505,70.708 v1(220.505,71.692) U32_L3.1@220.505,73.05 ; C224_L3.1@242,69.755 242.224,69.979 v1(242.224,70.755) U37_L3.1@242.224,72.05 ; C243_L3.1@258.573,69.755 v1(258.573,70.755) U43_L3.1@258.573,72.226
  Top Layer w0.3: FB2.1@100.5,237.4 100.635,237.535 101.26,237.535 v1(101.3,237.575) ; FB3.1@112.7,229.9 v1(113.6,229.9) ; v1@113.7,245.6 113.8,245.7 FB9.2@113.8,246.5 ; FB8.2@125,246.4 v1(125,245.6) v1@125.1,245.5 ; v1(139,245.7) 139,246.4 FB7.2@139.1,246.5 ; FB4.1@199,205.7 v1(199,206.6)
  Top Layer w0.4: R174.2@152.963,67.612 v1(153.863,67.612) ; R164.2@170.168,66.466 v1(170.868,66.466)
  Top Layer w0.5: v1(179.5,40.4) FB16.2@180.4,40.4 ; R175.2@212.85,22.55 v1@213.45,22.55 ; v1(224.1,24.1) 224.1,24.102 224.292,24.294 224.292,24.9 R194.2@224.3,24.9 ; v1(264.1,45.5) FB5.1@264.1,46.7 ; FB13.1@291.15,35.55 v1@291.15,36.45
  Layer 2 w0.2: v1(33.85,115.282) 33.886,115.282 34.121,115.517 37.542,115.517 37.778,115.282 38.218,115.282 38.746,114.754 38.746,114.609 39.071,114.284 39.216,114.284 39.241,114.259 39.502,114.259 39.743,114.019 44.101,114.019 ; v1(47,107) 46.946,107.054 46.446,107.054 44.101,109.399 44.101,114.019 ; v1(121.218,4.35) 121.218,4.386 120.983,4.621 120.983,8.042 121.218,8.278 121.218,8.718 121.746,9.246 121.891,9.246 122.216,9.571 122.216,9.716 122.241,9.741 122.241,10.002 122.481,10.243 122.481,17.912 ; v1(121.808,21.505) 121.808,22.189 123.654,24.035 123.654,36.854 v1(125.5,38.7) 122.745,41.455 v1(122.745,43.224) 122.745,48.514 123.054,48.823 123.054,53.046 122.246,53.854 122.246,54.329 122.745,54.829 v1(122.745,59.573) ; 148.259,67.5 148.371,67.612 v1(153.863,67.612) 155.009,66.466 v1(170.868,66.466) 175.066,66.466 v1(182.1,73.5) ; 149.5,52.5 v1(160.5,52.5) 172.6,40.4 v1(179.5,40.4) ; v1(172.573,98.755) 167.829,98.755 167.329,99.254 166.854,99.254 166.046,98.446 161.823,98.446 161.514,98.755 v1(156.224,98.755) 154.455,98.755 v1(151.7,96) 149.854,97.846 137.035,97.846 135.189,99.692 v1(134.505,99.692) 132.633,99.692 131.96,99.019 123.243,99.019 123.002,99.259 122.741,99.259 122.716,99.284 122.571,99.284 122.246,99.609 122.246,99.754 121.718,100.282 121.278,100.282 121.042,100.517 117.621,100.517 117.386,100.282 v1(117.35,100.282) 115.718,100.282 103.414,112.586 95.934,112.586 94.765,113.755 84.329,113.755 83.829,114.254 83.354,114.254 82.546,113.446 78.323,113.446 78.014,113.755 v1(72.724,113.755) 70.955,113.755 v1(68.2,111) 66.354,112.846 53.535,112.846 51.689,114.692 v1(51.005,114.692) 49.133,114.692 48.46,114.019 44.101,114.019 ; v1(189.5,79.5) 196.5,72.5 203.079,72.5 203.297,72.282 203.386,72.282 203.621,72.517 207.042,72.517 207.278,72.282 207.718,72.282 208.246,71.754 208.246,71.609 208.571,71.284 208.716,71.284 208.741,71.259 209.002,71.259 209.243,71.019 217.96,71.019 218.633,71.692 v1(220.505,71.692) 221.189,71.692 223.035,69.846 235.854,69.846 v1(237.7,68) 240.455,70.755 v1(242.224,70.755) 247.514,70.755 247.823,70.446 252.046,70.446 252.854,71.254 253.329,71.254 253.829,70.755 v1(258.573,70.755)
  Layer 2 w0.5: 145.3,19 153.707,19 154,19.293 154,21.5 149.5,26 149.5,52.5 149.5,63.671 148.259,64.912 148.259,67.5 148.259,76.759 157.5,86 157.5,91.5 v1(155.5,93.5)
  Layer 2 w0.6: v1(121.808,21.505) 121.808,18.585 122.481,17.912 124.154,16.24 124.154,15.846 126.5,13.5 138.766,13.5 144.266,19 145.3,19
  Layer 2 w1: v1(113.6,229.9) 117.035,233.335 ; v1(113.8,245.6) 112.9,244.7 110.2,244.7 108.8,246.1 102.3,246.1 100.216,244.016 100.216,240.17 100.413,239.973 100.413,238.558 103.394,235.577 115.473,235.577 123.123,227.926 193.974,227.926 216,205.9 ; v1(147.5,18.2) 147.5,15 149,13.5 180.229,13.5 180.429,13.3 223.6,13.3 ; v1(199,206.6) 199.7,205.9 216,205.9 ; v1(213.5,22.6) 218.4,22.6 218.7,22.9 223.6,22.9 ; v1(224.1,24.1) 223.6,23.6 223.6,22.9 ; v1(258.573,70.755) 260.227,70.755 261.926,72.454 269.188,72.454 272.395,69.247 272.395,67.452 272.454,67.393 272.454,66.539 271.895,65.98 266.48,65.98 261.664,61.164 261.664,55.799 264.1,53.363 v1(264.1,45.5) 264.1,37.6 ; 216,205.9 272.3,205.9 285.9,192.3 285.9,44.1 279.4,37.6 264.1,37.6 ; 223.6,13.3 242.9,13.3 264.1,34.5 264.1,37.6 ; 223.6,13.3 223.6,22.9
  Bottom Layer w0.2: v1(182.1,73.5) 183.5,73.5 v1(189.5,79.5)
  Bottom Layer w0.3: v1(113.8,245.6) 113.8,244.8 115.1,243.5 122.9,243.5 ; v1(125,245.6) 122.9,243.5 ; v1(139,245.7) 139,244.3 138.2,243.5 122.9,243.5
  Bottom Layer w1: v1(264.1,45.5) 264.6,46 278,46 279.9,44.1 285.9,44.1 288.009,41.991 288.009,39.691 v1(291.2,36.5)
5V: C79.1 C93.1 C137.1 C139.1 C140.1 C143.1 C197_L1.1 C197_L2.1 C197_L3.1 C197_N.1 C220_L1.1 C220_L2.1 C220_L3.1 C220_N.1 C237_L1.1 C237_L2.1 C237_L3.1 C237_N.1 C254_L1.1 C254_L2.1 C254_L3.1 C254_N.1 D6.2 FB1.1 FB12.1 J18.1 L7.2 L9.2 L11_L1.2 L11_L2.2 L11_L3.2 L11_N.2 L13_L1.2 L13_L2.2 L13_L3.2 L13_N.2 L15_L1.2 L15_L2.2 L15_L3.2 L15_N.2 L17_L1.2 L17_L2.2 L17_L3.2 L17_N.2 R214.2 R218.2 U21.3 | length 959.8
  Top Layer w0.2: L11_L1.2@44.563,111.158 45.113,111.158 45.244,111.028 45.244,110.667 v1(45.302,110.608) ; v1(102,109.934) 103.55,108.384 103.55,107.75 L9.2@103.8,107.5 103.8,106.672 103.508,106.38 103.508,106.024 C93.1@103,105.516 ; L11_L2.2@128.063,96.158 128.613,96.158 128.744,96.028 ; v1(181,92.5) 183,92.5 184.5,94 L17_L2.2@184.5,94.917 ; 214.421,67.785 214.542,67.785 214.719,67.608 v1(214.802,67.608)
  Top Layer w0.254: v1(45.302,110.608) 45.868,111.174 46.913,111.174 C197_L1.1@46.94,111.2 ; L13_L1.2@60.694,110.934 61.531,110.934 ; v1(61.517,109.934) 61.517,110.919 61.531,110.934 ; C220_L1.1@62.675,110.801 62.542,110.934 61.531,110.934 ; L15_L1.2@82.51,110.142 82.588,110.064 v1(83.341,110.064) C237_L1.1@84.5,110.064 ; C254_L1.1@101,111.639 L17_L1.2@101,109.917 101.017,109.934 v1(102,109.934) ; C254_N.1@124.861,71.5 L17_N.2@126.583,71.5 126.566,71.517 v1(126.566,72.5) ; L11_N.2@124.942,15.063 124.974,15.095 125.524,15.095 125.715,15.286 125.715,15.557 125.892,15.734 v1(125.892,15.802) 125.892,16.563 125.743,16.712 C197_N.1@125.116,16.712 ; L13_N.2@125.566,31.194 125.566,32.031 ; C220_N.1@125.699,33.175 125.566,33.042 125.566,32.031 ; L15_N.2@126.358,53.01 126.436,53.088 v1(126.436,53.841) C237_N.1@126.436,55 ; v1(126.566,32.017) 125.581,32.017 125.566,32.031 ; v1(128.802,95.608) 128.802,96.236 128.951,96.384 C197_L2.1@129.712,96.384 ; L13_L2.2@144.194,95.934 145.031,95.934 ; v1(145.017,94.934) 145.017,95.919 145.031,95.934 ; C220_L2.1@146.175,95.801 146.042,95.934 145.031,95.934 ; L15_L2.2@166.01,95.142 166.088,95.064 v1(166.841,95.064) C237_L2.1@168,95.064 ; L17_L2.2@184.5,94.917 C254_L2.1@184.5,96.639 ; L11_L3.2@214.063,68.558 214.095,68.526 214.095,67.976 214.286,67.785 214.421,67.785 ; v1(214.802,67.608) 215.563,67.608 215.712,67.757 C197_L3.1@215.712,68.384 ; L13_L3.2@230.194,67.934 231.031,67.934 ; v1(231.017,66.934) 231.017,67.919 231.031,67.934 ; C220_L3.1@232.175,67.801 232.042,67.934 231.031,67.934 ; L15_L3.2@252.01,67.142 252.088,67.064 v1(252.841,67.064) C237_L3.1@254,67.064 ; C254_L3.1@270.5,68.639 L17_L3.2@270.5,66.917 270.517,66.934 v1(271.5,66.934)
  Top Layer w0.4: v1(197.1,34.2) FB1.1@197.8,34.2
  Top Layer w0.5: L7.2@98.9,245 C79.1@101,245 ; C79.1@101,245.116 101.216,244.9 v1(103.1,244.9) ; FB12.1@291.2,38 v1(291.7,38)
  Top Layer w0.8: C137.1@168.207,20.596 R214.2@169.858,20.596
  Top Layer w1: v1(257.772,37.357) 258.3,36.83 258.3,33.786 258.886,33.2 v1(267.2,33.2)
  Layer 2 w0.2: v1(45.302,110.608) 48.608,110.608 50.256,112.256 55.744,112.256 58.066,109.934 v1(61.517,109.934) 64.783,109.934 65.271,109.446 65.729,109.446 66.283,110 69.275,110 69.275,110.275 71,112 81.405,112 v1(83.341,110.064) 85.564,110.064 86.434,110.934 91.484,110.934 91.946,111.396 93.404,111.396 94.125,110.676 95.43,110.676 95.688,110.934 100.359,110.934 101.358,109.934 v1(102,109.934) 102.434,109.5 104.217,109.5 104.271,109.446 104.729,109.446 104.783,109.5 105,109.5 116,98.5 118,98.5 119.512,96.988 120.034,96.988 121.413,95.608 v1(128.802,95.608) 132.108,95.608 133.756,97.256 139.244,97.256 141.566,94.934 v1(145.017,94.934) 147.434,94.934 148,95.5 148.717,95.5 148.771,95.554 150.296,95.554 150.404,95.446 152.425,95.446 153.979,97 164.905,97 v1(166.841,95.064) 170.448,95.064 170.923,94.588 175.205,94.588 176.488,95.871 178.276,95.871 179.213,94.934 180.944,94.934 181,94.878 v1(181,92.5) ; v1(125.892,15.802) 125.892,19.108 124.244,20.756 124.244,26.244 126.566,28.566 v1(126.566,32.017) 126.566,33.921 127.054,34.409 127.054,36.663 126.946,36.771 126.946,40.496 127.054,40.604 127.054,53.223 v1(126.436,53.841) 126.436,57.448 126.912,57.923 126.912,64.254 126.237,64.929 126.237,72.088 126.566,72.417 v1(126.566,72.5) ; v1(214.802,67.608) 218.108,67.608 219.756,69.256 225.244,69.256 227.566,66.934 v1(231.017,66.934) 232.817,66.934 233.942,68.058 236.858,68.058 237.471,67.446 241.599,67.446 242.349,68.196 246.933,68.196 247.65,67.479 252.425,67.479 v1(252.841,67.064) 257.271,67.064 258.837,68.63 263.185,68.63 263.339,68.784 269.65,68.784 v1(271.5,66.934)
  Layer 2 w0.5: v1(181,92.5) 182,91.5 182,77 192,67 206,67 206.608,67.608 v1(214.802,67.608) 214.802,61.302 198.5,45 198.5,36.592 197.1,35.192 v1(197.1,34.2)
  Layer 2 w0.6: v1(125.892,15.802) 134.335,15.802 139.033,20.5 152.5,20.5 v1(153.2,19.8)
  Layer 2 w1: v1(103.1,244.9) 104.2,244.9 110.7,238.4 118.521,238.4 127.622,229.299 195.001,229.299 216.9,207.4 273.6,207.4 287.9,193.1 287.9,41.857 ; v1@168.932,20.596 171.596,20.596 185.2,34.2 v1(197.1,34.2) 207.775,34.2 210.932,37.357 v1(257.772,37.357) ; v1(267.2,33.2) 278.94,33.2 287.72,41.98 v1(291.7,38)
  Bottom Layer w0.2: v1(153.2,19.8) 156.6,19.8 v1(158.7,17.7)
  other v1: 160.5,17.7 161.6,20.5 169.047,20.633 163.983,26.069 164.983,26.069 163.983,26.569 164.983,26.569 156.9,26.6 160.6,26.6 163.2,26.6 163.983,27.069 164.983,27.069 160.6,27.9
5V_S1_GaN_L1: C187_L1.1 C193_L1.2 C194_L1.1 C195_L1.1 L10_L1.2 R286_L1.2 U28_L1.8 U29_L1.9 U29_L1.10 U29_L1.11 U30_L1.6 | length 28.7
  Top Layer w0.2: v1(44.6,128.4) 46.038,128.4 46.418,128.4 L10_L1.2@46.5,128.482
  Top Layer w0.254: C187_L1.1@34.8,129.294 34.845,129.249 v1(34.845,128.222) U28_L1.8@34.845,126.95 ; C195_L1.1@38.5,130.648 39.848,130.648 40.244,131.045 v1(40.313,131.045) 40.313,131.746 40.889,131.746 U30_L1.6@41.038,131.895 41.238,131.895 42.414,130.719 43.363,130.719 43.512,130.57 43.512,129.561 C194_L1.1@43.704,129.369 44.088,128.985 44.088,127.079 44.172,126.995 U29_L1.11@44.172,126.35 ; U29_L1.11@44.247,126.25 44.897,126.25 45.547,126.25 45.547,127.909 L10_L1.2@46.038,128.4
  Bottom Layer w0.3: v1(34.845,128.222) 35.567,127.5 38.9,127.5 40.313,128.913 v1(40.313,131.045) ; R286_L1.2@43.6,129.3 43.748,129.3 44.029,129.019 44.029,128.871 v1@44.437,128.463
5V_S1_GaN_L2: C187_L2.1 C193_L2.2 C194_L2.1 C195_L2.1 L10_L2.2 R286_L2.2 U28_L2.8 U29_L2.9 U29_L2.10 U29_L2.11 U30_L2.6 | length 28.7
  Top Layer w0.2: v1(128.1,113.4) 129.538,113.4 129.918,113.4 L10_L2.2@130,113.482
  Top Layer w0.254: C187_L2.1@118.3,114.294 118.345,114.249 v1(118.345,113.222) U28_L2.8@118.345,111.95 ; C195_L2.1@122,115.648 123.348,115.648 123.744,116.045 v1(123.813,116.045) 123.813,116.746 124.389,116.746 U30_L2.6@124.538,116.895 124.738,116.895 125.914,115.719 126.863,115.719 127.012,115.57 127.012,114.561 C194_L2.1@127.204,114.369 127.588,113.985 C193_L2.2@127.588,112.867 127.711,112.744 127.711,111.411 U29_L2.11@127.772,111.35 ; U29_L2.11@127.747,111.25 128.397,111.25 129.047,111.25 129.047,112.909 L10_L2.2@129.538,113.4
  Bottom Layer w0.3: v1(118.345,113.222) 119.067,112.5 122.4,112.5 123.813,113.913 v1(123.813,116.045) ; R286_L2.2@127.1,114.3 127.248,114.3 127.529,114.019 127.529,113.871 v1@127.937,113.463
5V_S1_GaN_L3: C187_L3.1 C193_L3.2 C194_L3.1 C195_L3.1 L10_L3.2 R286_L3.2 U28_L3.8 U29_L3.9 U29_L3.10 U29_L3.11 U30_L3.6 | length 28.7
  Top Layer w0.2: v1(214.1,85.4) 215.538,85.4 215.918,85.4 L10_L3.2@216,85.482
  Top Layer w0.254: C187_L3.1@204.3,86.294 204.345,86.249 v1(204.345,85.222) U28_L3.8@204.345,83.95 ; C195_L3.1@208,87.648 209.348,87.648 209.744,88.045 v1(209.813,88.045) 209.813,88.746 210.389,88.746 U30_L3.6@210.538,88.895 210.738,88.895 211.914,87.719 212.863,87.719 213.012,87.57 213.012,86.561 C194_L3.1@213.204,86.369 213.588,85.985 C193_L3.2@213.588,84.867 213.711,84.744 213.711,83.411 U29_L3.11@213.772,83.35 ; U29_L3.11@213.747,83.25 214.397,83.25 215.047,83.25 215.047,84.909 L10_L3.2@215.538,85.4
  Bottom Layer w0.3: v1(204.345,85.222) 205.067,84.5 208.4,84.5 209.813,85.913 v1(209.813,88.045) ; R286_L3.2@213.1,86.3 213.248,86.3 213.529,86.019 213.529,85.871 v1@213.937,85.463
5V_S1_GaN_N: C187_N.1 C193_N.2 C194_N.1 C195_N.1 L10_N.2 R286_N.2 U28_N.8 U29_N.9 U29_N.10 U29_N.11 U30_N.6 | length 28.8
  Top Layer w0.2: L10_N.2@108.018,17 108.1,16.918 108.1,16.538 v1(108.1,15.1)
  Top Layer w0.254: C195_N.1@105.852,9 105.852,10.348 105.455,10.744 v1(105.455,10.813) 104.754,10.813 104.754,11.389 U30_N.6@104.605,11.538 104.605,11.738 105.781,12.914 105.781,13.863 105.93,14.012 106.939,14.012 C194_N.1@107.131,14.204 107.515,14.588 C193_N.2@108.633,14.588 108.756,14.711 108.869,14.711 108.905,14.747 U29_N.11@110.25,14.747 U29_N.10@110.25,15.397 U29_N.9@110.25,16.047 108.591,16.047 L10_N.2@108.1,16.538 ; C187_N.1@107.206,5.3 107.251,5.345 v1(108.278,5.345) U28_N.8@109.55,5.345
  Bottom Layer w0.3: v1(105.455,10.813) 107.587,10.813 109,9.4 109,6.067 v1(108.278,5.345) ; R286_N.2@107.2,14.1 107.2,14.248 107.481,14.529 107.629,14.529 v1@108.037,14.937
5V_S2_GaN_L1: C201_L1.1 C210_L1.2 C211_L1.1 C212_L1.1 L12_L1.2 R297_L1.2 U32_L1.8 U34_L1.9 U34_L1.10 U34_L1.11 U35_L1.6 | length 29.6
  Top Layer w0.254: U32_L1.8@51.005,126.95 C201_L1.1@51.005,129.566 ; C212_L1.1@55.155,130.671 55.326,130.5 55.922,130.5 56.106,130.316 v1(56.175,130.316) ; 56.559,130.7 v1(56.175,130.316) ; 56.562,130.703 56.562,130.993 56.735,131.166 U35_L1.6@56.9,131.166 ; v1(61.244,127.672) 61.244,127.603 61.125,127.484 U34_L1.10@61.125,126 U34_L1.11@60.475,126 60.434,126.041 60.434,127.326 60.124,127.637 60.124,128.215 C211_L1.1@59.616,128.723 ; U34_L1.9@61.775,126 61.775,128.4 L12_L1.2@62.098,128.723 ; L12_L1.2@62.173,128.798 L12_L1.2@62.098,128.723 ; v1(56.175,130.316) 58.909,130.316 59.144,130.082 59.144,129.196 C211_L1.1@59.616,128.723 ; C211_L1.1@59.616,128.723 L12_L1.2@62.098,128.723
  Bottom Layer w0.254: v1@51,128.5 v1(51.004,128.496) 51.004,127.909 51.242,127.672 53.546,127.672 56.175,130.301 v1(56.175,130.316) ; R297_L1.2@59.456,128.407 59.456,128.382 59.804,128.034 59.829,128.034 60.191,127.672 v1(61.244,127.672)
5V_S2_GaN_L2: C201_L2.1 C210_L2.2 C211_L2.1 C212_L2.1 L12_L2.2 R297_L2.2 U32_L2.8 U34_L2.9 U34_L2.10 U34_L2.11 U35_L2.6 | length 28.4
  Top Layer w0.254: U32_L2.8@134.505,111.95 v1(134.505,113.116) C201_L2.1@134.505,113.866 ; C212_L2.1@138.655,115.671 138.826,115.5 139.422,115.5 139.606,115.316 v1(139.675,115.316) ; 140.059,115.7 v1(139.675,115.316) ; 140.062,115.703 140.062,115.993 140.235,116.166 U35_L2.6@140.4,116.166 ; v1(144.744,112.672) 144.744,112.603 144.625,112.484 U34_L2.10@144.625,111 U34_L2.11@143.975,111 143.934,111.041 143.934,112.326 143.624,112.637 143.624,113.215 C211_L2.1@143.116,113.723 ; U34_L2.9@145.275,111 145.275,113.4 L12_L2.2@145.598,113.723 ; L12_L2.2@145.673,113.798 L12_L2.2@145.598,113.723 ; v1(139.675,115.316) 142.409,115.316 142.644,115.082 142.644,114.196 C211_L2.1@143.116,113.723 ; C211_L2.1@143.116,113.723 L12_L2.2@145.598,113.723
  Bottom Layer w0.2: v1(134.505,113.116) 134.95,112.672 135.2,112.672
  Bottom Layer w0.254: 135.2,112.672 137.046,112.672 139.675,115.301 v1(139.675,115.316) ; R297_L2.2@142.956,113.407 142.956,113.382 143.304,113.034 143.329,113.034 143.691,112.672 v1(144.744,112.672)
5V_S2_GaN_L3: C201_L3.1 C210_L3.2 C211_L3.1 C212_L3.1 L12_L3.2 R297_L3.2 U32_L3.8 U34_L3.9 U34_L3.10 U34_L3.11 U35_L3.6 | length 28.4
  Top Layer w0.254: U32_L3.8@220.505,83.95 v1(220.505,85.116) C201_L3.1@220.505,85.866 ; C212_L3.1@224.655,87.671 224.826,87.5 225.422,87.5 225.606,87.316 v1(225.675,87.316) ; 226.059,87.7 v1(225.675,87.316) ; 226.062,87.703 226.062,87.993 226.235,88.166 U35_L3.6@226.4,88.166 ; v1(230.744,84.672) 230.744,84.603 230.625,84.484 U34_L3.10@230.625,83 U34_L3.11@229.975,83 229.934,83.041 229.934,84.326 229.894,84.367 229.624,84.637 229.624,85.215 C211_L3.1@229.116,85.723 ; U34_L3.9@231.275,83 231.275,85.4 L12_L3.2@231.598,85.723 ; L12_L3.2@231.673,85.798 L12_L3.2@231.598,85.723 ; v1(225.675,87.316) 228.409,87.316 228.644,87.082 228.644,86.196 C211_L3.1@229.116,85.723 ; C211_L3.1@229.116,85.723 L12_L3.2@231.598,85.723
  Bottom Layer w0.254: v1(220.505,85.116) 220.554,85.068 220.832,85.068 221.228,84.672 223.046,84.672 225.675,87.301 v1(225.675,87.316) ; R297_L3.2@228.956,85.407 228.956,85.382 229.304,85.034 229.329,85.034 229.691,84.672 v1(230.744,84.672)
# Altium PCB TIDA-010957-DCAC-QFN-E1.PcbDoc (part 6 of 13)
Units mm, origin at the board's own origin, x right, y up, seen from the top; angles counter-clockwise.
Board outline 300 x 300 mm, 4 copper layers (Top Layer, Layer 1, Layer 2, Bottom Layer), stack 1.787 mm thick; 1286 components, 677 nets, 4169 pads, 3428 vias.

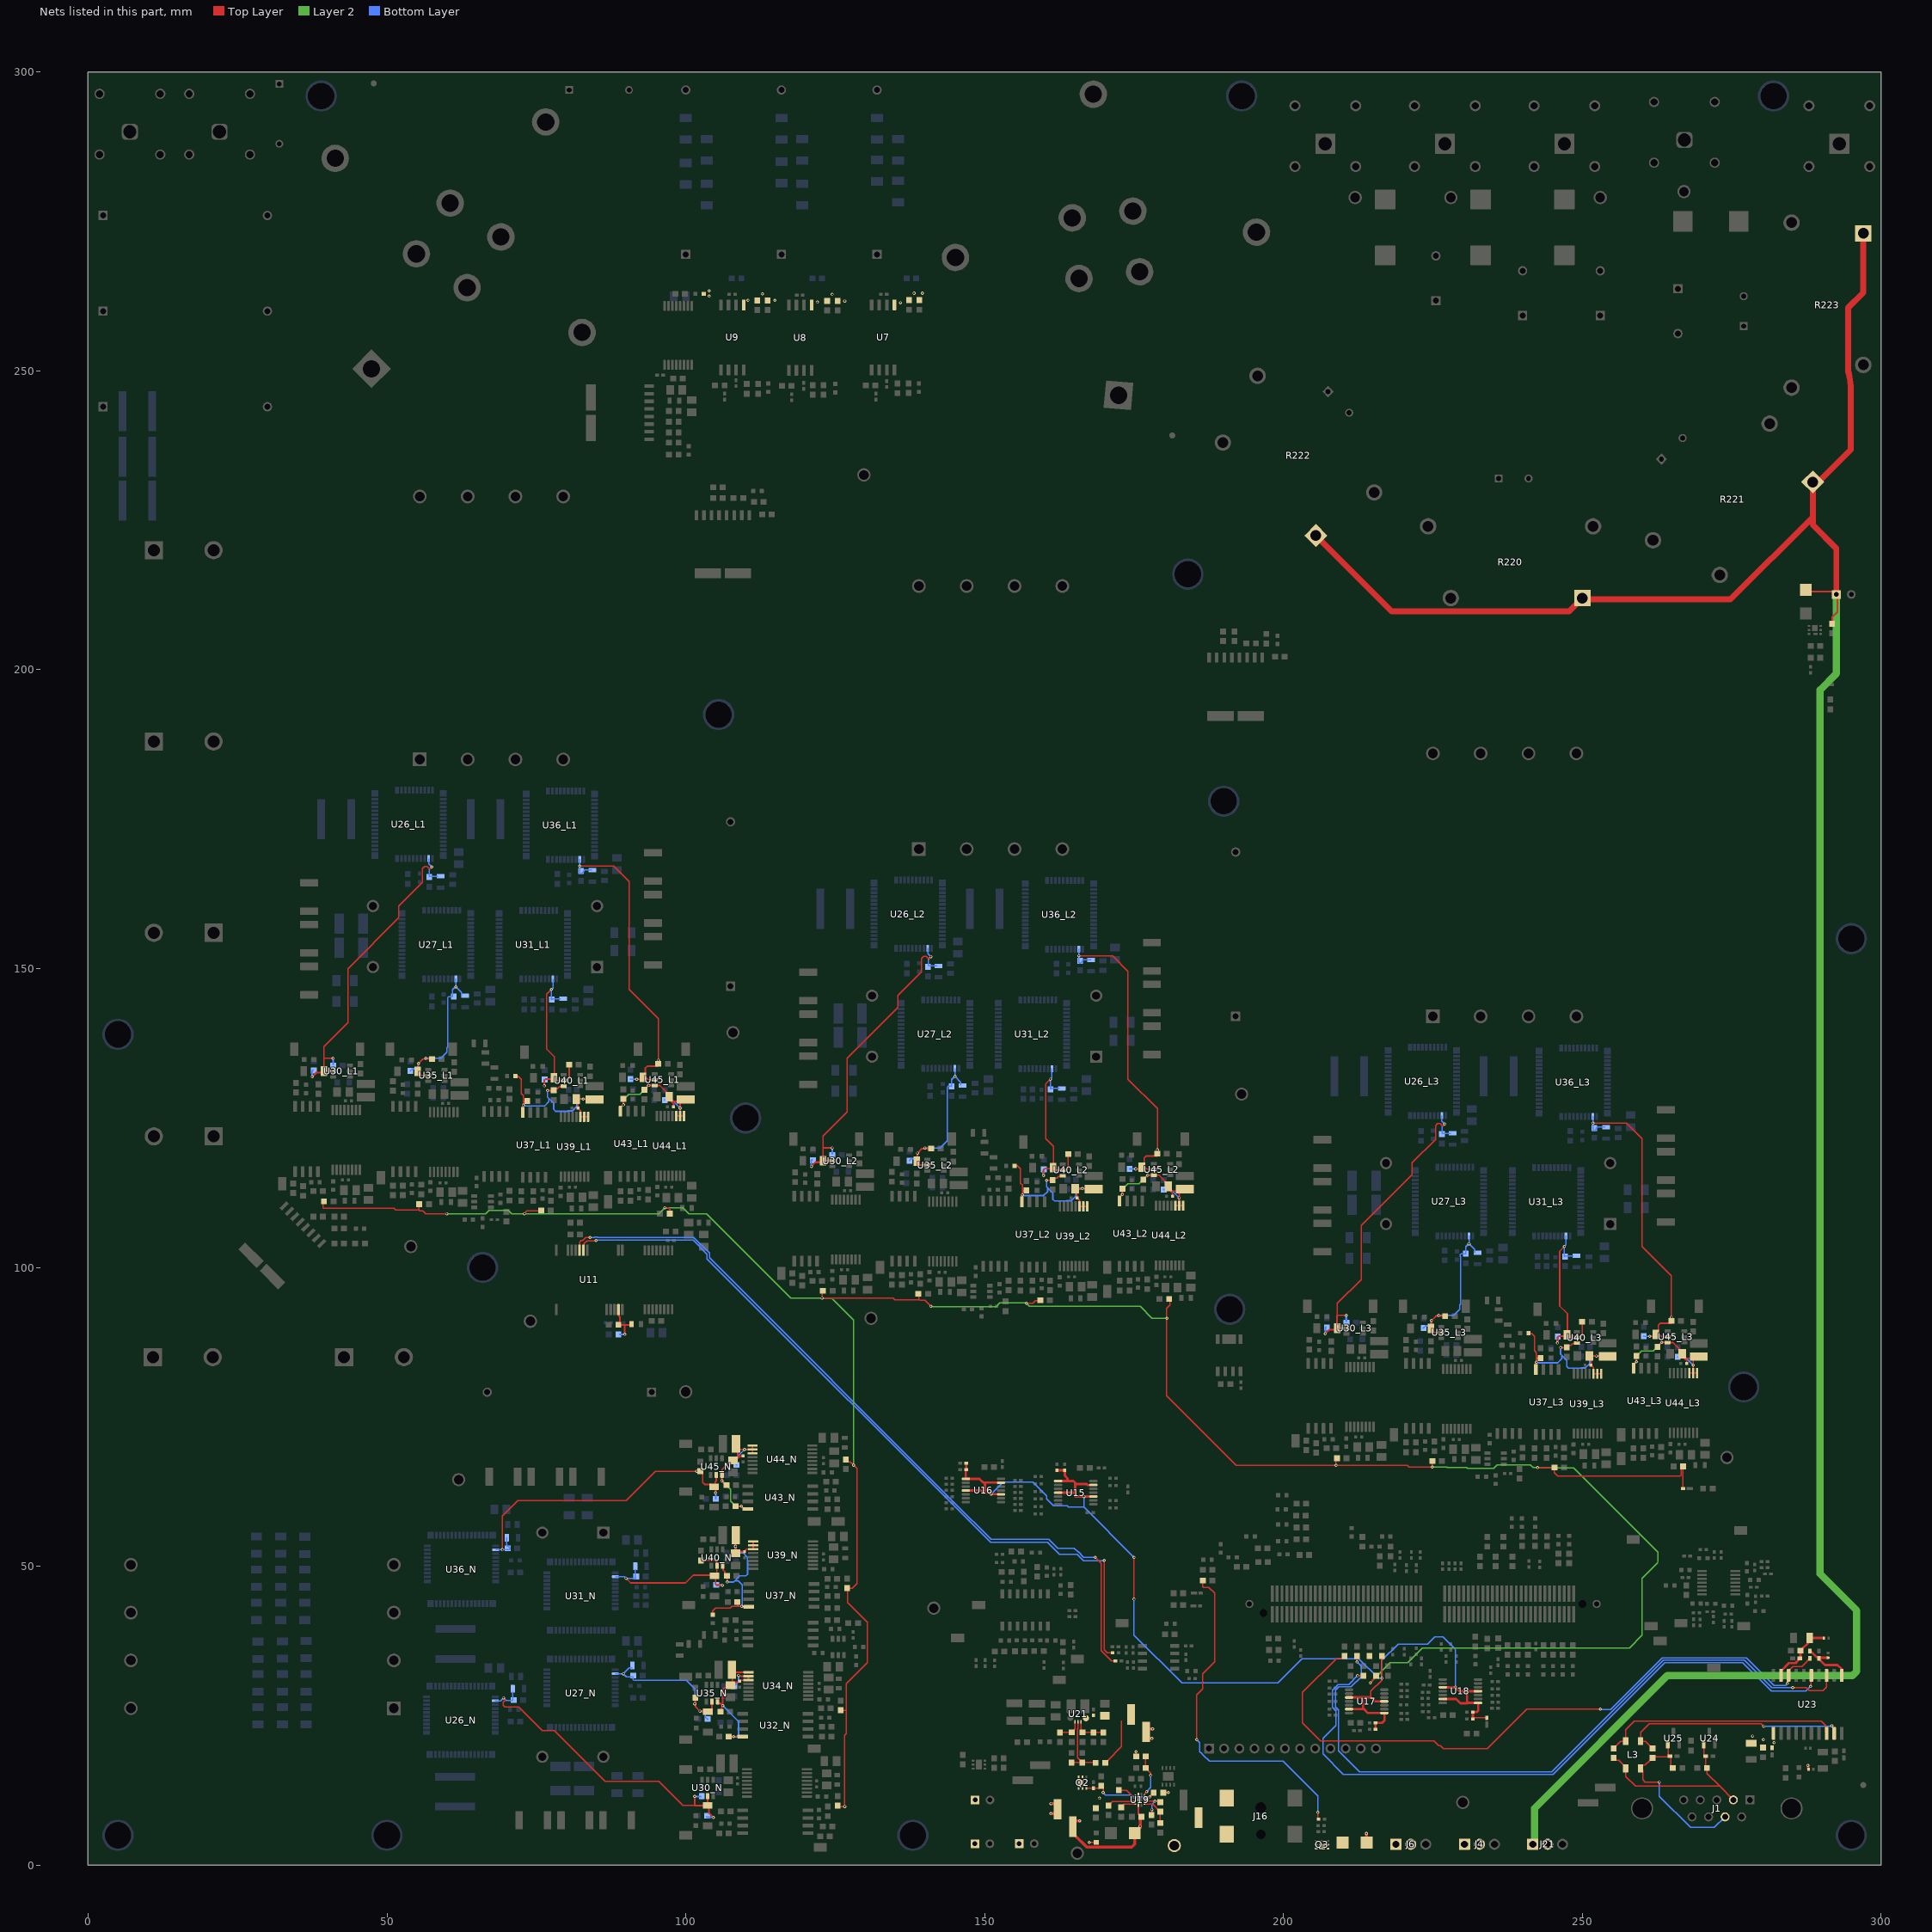
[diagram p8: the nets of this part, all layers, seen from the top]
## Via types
v1: diameter 0.508, hole 0.254, Top Layer to Bottom Layer, tented both sides, 3428 vias

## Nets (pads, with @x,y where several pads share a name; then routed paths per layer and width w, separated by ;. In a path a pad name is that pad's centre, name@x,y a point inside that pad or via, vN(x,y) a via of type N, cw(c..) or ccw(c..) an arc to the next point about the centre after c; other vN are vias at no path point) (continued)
5V_S2_GaN_N: C201_N.1 C210_N.2 C211_N.1 C212_N.1 L12_N.2 R297_N.2 U32_N.8 U34_N.9 U34_N.10 U34_N.11 U35_N.6 | length 28.9
  Top Layer w0.254: U35_N.6@105.334,27.4 105.334,27.235 105.507,27.062 105.797,27.062 ; 105.8,27.059 v1(106.184,26.675) ; C212_N.1@105.829,25.655 106,25.826 106,26.422 106.184,26.606 v1(106.184,26.675) ; C201_N.1@107.634,21.505 v1(108.009,21.505) U32_N.8@109.55,21.505 ; L12_N.2@107.702,32.673 L12_N.2@107.777,32.598 ; v1(108.828,31.744) 108.897,31.744 109.016,31.625 U34_N.10@110.5,31.625 U34_N.11@110.5,30.975 110.459,30.934 109.174,30.934 108.863,30.624 108.285,30.624 C211_N.1@107.777,30.116 ; U34_N.9@110.5,32.275 108.1,32.275 L12_N.2@107.777,32.598 ; v1(106.184,26.675) 106.184,29.409 106.418,29.644 107.304,29.644 C211_N.1@107.777,30.116 ; C211_N.1@107.777,30.116 L12_N.2@107.777,32.598
  Bottom Layer w0.254: v1(106.184,26.675) 106.199,26.675 108.828,24.046 108.828,21.84 108.446,21.457 108.056,21.457 v1(108.009,21.505) ; R297_N.2@108.093,29.956 108.118,29.956 108.466,30.304 108.466,30.329 108.828,30.691 v1(108.828,31.744)
5V_S3_GaN_L1: C225_L1.1 C233_L1.2 C234_L1.1 C235_L1.1 FB15_L1.2 L14_L1.2 R307_L1.2 U37_L1.8 U39_L1.9 U39_L1.10 U39_L1.11 U40_L1.6 | length 33.3
  Top Layer w0.2: FB15_L1.2@71.4,132 72,132 72.5,131.5 72.5,129.075 72.815,128.76 72.815,127.715 v1(72.815,127.143)
  Top Layer w0.254: v1(76.872,129.582) 77.863,129.582 C235_L1.1@77.904,129.623 78.229,129.948 78.585,129.948 78.876,130.238 79.489,130.238 U40_L1.6@79.583,130.333 ; U39_L1.9@83.66,125.208 U39_L1.10@83.01,125.208 U39_L1.11@82.36,125.208 82.36,126.254 C233_L1.2@81.958,126.657 81.958,127.898 C234_L1.1@81.674,128.182 v1(82.833,128.182) 84.659,128.182 L14_L1.2@84.725,128.116
  Top Layer w0.3: U37_L1.8@72.724,125.95 v1@72.724,127.143 ; 72.9,127.8 C225_L1.1@73.3,127.8
  Bottom Layer w0.254: v1@72.783,127.047 72.83,127.094 73.036,127.094 73.091,127.039 76.39,127.039 77.067,127.716 77.067,128.197 ; v1(76.872,129.582) 76.872,128.493 77.904,127.46 77.904,126.439 78.201,126.142 80.248,126.142 80.288,126.182 81.016,126.182 81.758,126.924 R307_L1.2@81.758,128.107 81.833,128.182 v1(82.833,128.182)
5V_S3_GaN_L2: C225_L2.1 C233_L2.2 C234_L2.1 C235_L2.1 FB15_L2.2 L14_L2.2 R307_L2.2 U37_L2.8 U39_L2.9 U39_L2.10 U39_L2.11 U40_L2.6 | length 33.3
  Top Layer w0.2: FB15_L2.2@154.9,117 155.5,117 156,116.5 156,114.075 156.315,113.76 156.315,112.715 v1(156.315,112.143)
  Top Layer w0.254: v1(160.372,114.582) 161.363,114.582 C235_L2.1@161.404,114.623 161.729,114.948 162.085,114.948 162.376,115.238 162.989,115.238 U40_L2.6@163.083,115.333 ; U39_L2.9@167.16,110.208 U39_L2.10@166.51,110.208 U39_L2.11@165.86,110.208 165.86,111.254 C233_L2.2@165.458,111.657 165.458,112.898 C234_L2.1@165.174,113.182 v1(166.333,113.182) 168.159,113.182 L14_L2.2@168.225,113.116
  Top Layer w0.3: U37_L2.8@156.224,110.95 v1@156.224,112.143 ; 156.4,112.8 C225_L2.1@156.8,112.8
  Bottom Layer w0.254: v1@156.283,112.047 156.33,112.094 156.536,112.094 156.591,112.039 159.89,112.039 160.567,112.716 160.567,113.197 ; v1(160.372,114.582) 160.372,113.493 161.404,112.46 161.404,111.439 161.701,111.142 163.748,111.142 163.788,111.182 164.516,111.182 165.258,111.924 R307_L2.2@165.258,113.107 165.333,113.182 v1(166.333,113.182)
5V_S3_GaN_L3: C225_L3.1 C233_L3.2 C234_L3.1 C235_L3.1 FB15_L3.2 L14_L3.2 R307_L3.2 U37_L3.8 U39_L3.9 U39_L3.10 U39_L3.11 U40_L3.6 | length 33.3
  Top Layer w0.2: FB15_L3.2@240.9,89 241.5,89 242,88.5 242,86.075 242.315,85.76 242.315,84.715 v1(242.315,84.143)
  Top Layer w0.254: v1(246.372,86.582) 247.363,86.582 C235_L3.1@247.404,86.623 247.729,86.948 248.085,86.948 248.376,87.238 248.989,87.238 U40_L3.6@249.083,87.333 ; U39_L3.9@253.16,82.208 U39_L3.10@252.51,82.208 U39_L3.11@251.86,82.208 251.86,83.254 C233_L3.2@251.458,83.657 251.458,84.898 C234_L3.1@251.174,85.182 v1(252.333,85.182) 254.159,85.182 L14_L3.2@254.225,85.116
  Top Layer w0.3: U37_L3.8@242.224,82.95 v1@242.224,84.143 ; 242.4,84.8 C225_L3.1@242.8,84.8
  Bottom Layer w0.254: v1@242.283,84.047 242.33,84.094 242.536,84.094 242.591,84.039 245.89,84.039 246.567,84.716 246.567,85.197 ; v1(246.372,86.582) 246.372,85.493 247.404,84.46 247.404,83.439 247.701,83.142 249.748,83.142 249.788,83.182 250.516,83.182 251.258,83.924 R307_L3.2@251.258,85.107 251.333,85.182 v1(252.333,85.182)
5V_S3_GaN_N: C225_N.1 C233_N.2 C234_N.1 C235_N.1 FB15_N.2 L14_N.2 R307_N.2 U37_N.8 U39_N.9 U39_N.10 U39_N.11 U40_N.6 | length 33.4
  Top Layer w0.2: FB15_N.2@104.5,41.9 104.5,42.5 105,43 107.425,43 107.74,43.315 108.785,43.315 v1(109.357,43.315)
  Top Layer w0.254: U40_N.6@106.167,50.083 106.262,49.989 106.262,49.376 106.552,49.085 106.552,48.729 C235_N.1@106.877,48.404 106.918,48.363 v1(106.918,47.372) ; L14_N.2@108.384,55.225 108.318,55.159 v1(108.318,53.333) C234_N.1@108.318,52.174 108.602,52.458 C233_N.2@109.843,52.458 109.966,52.581 109.966,52.686 110.14,52.86 U39_N.11@111.292,52.86 U39_N.10@111.292,53.51 U39_N.9@111.292,54.16
  Top Layer w0.3: 108.7,43.4 C225_N.1@108.7,43.8 ; v1@109.357,43.224 U37_N.8@110.55,43.224
  Bottom Layer w0.254: v1(106.918,47.372) 108.007,47.372 109.04,48.404 110.061,48.404 110.358,48.701 110.358,50.748 110.318,50.788 110.318,51.516 109.576,52.258 R307_N.2@108.393,52.258 108.318,52.333 v1(108.318,53.333) ; 108.303,47.567 108.784,47.567 109.461,46.89 109.461,43.591 109.406,43.536 109.406,43.33 v1@109.453,43.283
5V_S4_GaN_L1: C244_L1.1 C250_L1.2 C251_L1.1 C252_L1.1 L16_L1.2 R324_L1.2 U43_L1.8 U44_L1.9 U44_L1.10 U44_L1.11 U45_L1.6 | length 25.3
  Top Layer w0.2: U44_L1.11@98.404,125.338 U44_L1.10@99.054,125.338 U44_L1.9@99.704,125.338
  Top Layer w0.254: U43_L1.8@89.073,126.126 89.073,126.726 v1(89.561,127.214) C252_L1.1@89.561,128.198 C252_L1.1@89.513,128.246 ; C244_L1.1@93.076,129.707 93.424,130.055 93.424,130.182 93.651,130.409 93.752,130.409 v1(93.801,130.457) 94.377,130.457 94.462,130.373 U45_L1.6@94.726,130.373 ; U45_L1.6@94.801,130.434 95.677,130.434 96.738,129.373 96.738,128.755 C251_L1.1@97.219,128.273 ; C250_L1.2@97.956,126.907 97.956,127.451 97.807,127.6 97.727,127.6 97.219,128.108 C251_L1.1@97.219,128.273 ; U44_L1.10@99.054,125.338 99.054,127.572 99.273,127.791 99.343,127.791 97.701,127.791 C251_L1.1@97.219,128.273
  Layer 2 w0.2: v1(89.561,127.214) 89.561,128.123 90.438,129 92.343,129 v1(93.801,130.457)
  Bottom Layer w0.254: R324_L1.2@96.476,128.023 97.688,128.023 v1(99.054,126.657)
5V_S4_GaN_L2: C244_L2.1 C250_L2.2 C251_L2.1 C252_L2.1 L16_L2.2 R324_L2.2 U43_L2.8 U44_L2.9 U44_L2.10 U44_L2.11 U45_L2.6 | length 25.3
  Top Layer w0.2: U44_L2.11@181.904,110.338 U44_L2.10@182.554,110.338 U44_L2.9@183.204,110.338
  Top Layer w0.254: U43_L2.8@172.573,111.126 172.573,111.726 v1(173.061,112.214) C252_L2.1@173.061,113.198 C252_L2.1@173.013,113.246 ; C244_L2.1@176.576,114.707 176.924,115.055 176.924,115.182 177.151,115.409 177.252,115.409 v1(177.301,115.457) 177.877,115.457 177.962,115.373 U45_L2.6@178.226,115.373 ; U45_L2.6@178.301,115.434 179.177,115.434 180.238,114.373 180.238,113.755 C251_L2.1@180.719,113.273 ; C250_L2.2@181.456,111.907 181.456,112.451 181.307,112.6 181.227,112.6 180.719,113.108 C251_L2.1@180.719,113.273 ; U44_L2.10@182.554,110.338 182.554,112.518 182.827,112.791 182.843,112.791 181.201,112.791 C251_L2.1@180.719,113.273
  Layer 2 w0.2: v1(173.061,112.214) 173.061,113.123 173.938,114 175.843,114 v1(177.301,115.457)
  Bottom Layer w0.254: R324_L2.2@179.976,113.023 181.188,113.023 v1(182.554,111.657)
5V_S4_GaN_L3: C244_L3.1 C250_L3.2 C251_L3.1 C252_L3.1 L16_L3.2 R324_L3.2 U43_L3.8 U44_L3.9 U44_L3.10 U44_L3.11 U45_L3.6 | length 25.3
  Top Layer w0.2: U44_L3.11@267.904,82.338 U44_L3.10@268.554,82.338 U44_L3.9@269.204,82.338
  Top Layer w0.254: U43_L3.8@258.573,83.126 258.573,83.726 v1(259.061,84.214) C252_L3.1@259.061,85.198 C252_L3.1@259.013,85.246 ; C244_L3.1@262.576,86.707 262.924,87.055 262.924,87.182 263.151,87.409 263.252,87.409 v1(263.301,87.457) 263.877,87.457 263.962,87.373 U45_L3.6@264.226,87.373 ; U45_L3.6@264.301,87.434 265.177,87.434 266.238,86.373 266.238,85.755 C251_L3.1@266.719,85.273 ; C250_L3.2@267.456,83.907 267.456,84.451 267.307,84.6 267.227,84.6 266.719,85.108 C251_L3.1@266.719,85.273 ; U44_L3.10@268.554,82.338 268.554,84.518 268.827,84.791 268.843,84.791 267.201,84.791 C251_L3.1@266.719,85.273
  Layer 2 w0.2: v1(259.061,84.214) 259.061,85.123 259.938,86 261.843,86 v1(263.301,87.457)
  Bottom Layer w0.254: R324_L3.2@265.976,85.023 267.188,85.023 v1(268.554,83.657)
5V_S4_GaN_N: C244_N.1 C250_N.2 C251_N.1 C252_N.1 L16_N.2 R324_N.2 U43_N.8 U44_N.9 U44_N.10 U44_N.11 U45_N.6 | length 25.3
  Top Layer w0.2: U44_N.11@111.162,68.904 U44_N.10@111.162,69.554 U44_N.9@111.162,70.204
  Top Layer w0.254: U45_N.6@106.066,65.301 106.066,66.177 107.127,67.238 107.745,67.238 C251_N.1@108.227,67.719 ; U45_N.6@106.127,65.226 106.127,64.962 106.043,64.877 v1(106.043,64.301) 106.091,64.252 106.091,64.151 106.318,63.924 106.445,63.924 C244_N.1@106.793,63.576 ; C252_N.1@108.254,60.013 C252_N.1@108.302,60.061 v1(109.286,60.061) 109.774,59.573 U43_N.8@110.374,59.573 ; C250_N.2@109.593,68.456 109.049,68.456 108.9,68.307 108.9,68.227 108.392,67.719 C251_N.1@108.227,67.719 ; U44_N.10@111.162,69.554 108.982,69.554 108.709,69.827 108.709,69.843 108.709,68.201 C251_N.1@108.227,67.719
  Layer 2 w0.2: v1(106.043,64.301) 107.5,62.843 107.5,60.938 108.377,60.061 v1(109.286,60.061)
  Bottom Layer w0.254: R324_N.2@108.477,66.976 108.477,68.188 v1(109.843,69.554)
10V_S1_GaN_L1: C163_L1.2 C190_L1.1 C192_L1.1 R285_L1.2 R289_L1.2 U26_L1.44 U30_L1.5 | length 55
  Top Layer w0.2: 39.475,135 39.475,136.975 43.5,141 43.5,150 52,158.5 52,160.5 55.946,164.446 55.946,166.729 56.271,167.054 56.729,167.054 57.059,166.725 57.225,166.725 v1(57.5,167)
  Top Layer w0.25: 39.475,135 v1(41,135)
  Top Layer w0.254: 39.475,135 C192_L1.1@39.475,132.845 U30_L1.5@41.038,132.845
  Top Layer w0.3: v1(37.5,131.9) 38.2,132.6 39.4,132.6 C192_L1.1@39.5,132.5
  Bottom Layer w0.2: U26_L1.44@56.99,168.4 56.99,167.51 v1(57.5,167) 57.074,166.574 57.074,165.45 C163_L1.2@58.5,165.45
  Bottom Layer w0.3: v1(37.5,131.9) 37.5,132.9 R285_L1.2@37.6,133 ; R289_L1.2@41,134 v1(41,135)
10V_S1_GaN_L2: C163_L2.2 C190_L2.1 C192_L2.1 R285_L2.2 R289_L2.2 U26_L2.44 U30_L2.5 | length 55
  Top Layer w0.2: 122.975,120 122.975,121.975 127,126 127,135 135.5,143.5 135.5,145.5 139.446,149.446 139.446,151.729 139.771,152.054 140.229,152.054 140.559,151.725 140.725,151.725 v1(141,152)
  Top Layer w0.25: 122.975,120 v1(124.5,120)
  Top Layer w0.254: 122.975,120 C192_L2.1@122.975,117.845 U30_L2.5@124.538,117.845
  Top Layer w0.3: v1(121,116.9) 121.7,117.6 122.9,117.6 C192_L2.1@123,117.5
  Bottom Layer w0.2: U26_L2.44@140.49,153.4 140.49,152.51 v1(141,152) 140.574,151.574 140.574,150.45 C163_L2.2@142,150.45
  Bottom Layer w0.3: v1(121,116.9) 121,117.9 R285_L2.2@121.1,118 ; R289_L2.2@124.5,119 v1(124.5,120)
10V_S1_GaN_L3: C163_L3.2 C190_L3.1 C192_L3.1 R285_L3.2 R289_L3.2 U26_L3.44 U30_L3.5 | length 55
  Top Layer w0.2: 208.975,92 208.975,93.975 213,98 213,107 221.5,115.5 221.5,117.5 225.446,121.446 225.446,123.729 225.771,124.054 226.229,124.054 226.559,123.725 226.725,123.725 v1(227,124)
  Top Layer w0.25: 208.975,92 v1(210.5,92)
  Top Layer w0.254: 208.975,92 C192_L3.1@208.975,89.845 U30_L3.5@210.538,89.845
  Top Layer w0.3: v1(207,88.9) 207.7,89.6 208.9,89.6 C192_L3.1@209,89.5
  Bottom Layer w0.2: U26_L3.44@226.49,125.4 226.49,124.51 v1(227,124) 226.574,123.574 226.574,122.45 C163_L3.2@228,122.45
  Bottom Layer w0.3: v1(207,88.9) 207,89.9 R285_L3.2@207.1,90 ; R289_L3.2@210.5,91 v1(210.5,92)
10V_S1_GaN_N: C163_N.2 C190_N.1 C192_N.1 R285_N.2 R289_N.2 U26_N.44 U30_N.5 | length 55
  Top Layer w0.2: v1(69.5,28) 69.775,27.725 69.775,27.559 69.446,27.229 69.446,26.771 69.771,26.446 72.054,26.446 76,22.5 78,22.5 86.5,14 95.5,14 99.525,9.975 101.5,9.975
  Top Layer w0.25: 101.5,9.975 v1(101.5,11.5)
  Top Layer w0.254: 101.5,9.975 C192_N.1@103.655,9.975 U30_N.5@103.655,11.538
  Top Layer w0.3: C192_N.1@104,10 103.9,9.9 103.9,8.7 v1(104.6,8)
  Bottom Layer w0.2: U26_N.44@68.1,27.49 68.99,27.49 v1(69.5,28) 69.926,27.574 71.05,27.574 C163_N.2@71.05,29
  Bottom Layer w0.3: v1(101.5,11.5) R289_N.2@102.5,11.5 ; R285_N.2@103.5,8.1 103.6,8 v1(104.6,8)
10V_S2_GaN_L1: C165_L1.2 C204_L1.1 C208_L1.1 R296_L1.2 R300_L1.2 U27_L1.44 U35_L1.5 | length 28.2
  Top Layer w0.254: U35_L1.5@56.9,132.116 55.59,132.116 55.155,132.55 C208_L1.1@55.155,132.8 55.275,132.92 v1(55.275,134.132) 56.018,134.875 R300_L1.2@57.544,134.875
  Bottom Layer w0.2: v1(56.5,135) 59,135 60,136 60,136.717 60.15,136.867 60.15,145.183 60.267,145.3 61,145.3 61,146.42 v1(61.54,146.96) 62.5,146 C165_L1.2@62.5,145.45 ; 61,146.5 61.54,147.04 U27_L1.44@61.54,148.3
  Bottom Layer w0.254: R296_L1.2@53.93,132.857 53.93,132.882 54.278,133.23 54.875,133.23 55.226,133.581 55.226,134.084 v1(55.275,134.132)
10V_S2_GaN_L2: C165_L2.2 C204_L2.1 C208_L2.1 R296_L2.2 R300_L2.2 U27_L2.44 U35_L2.5 | length 28.1
  Top Layer w0.254: U35_L2.5@140.4,117.116 139.09,117.116 138.655,117.55 C208_L2.1@138.655,117.8 138.775,117.92 v1(138.775,119.132) 139.518,119.875 R300_L2.2@141.044,119.875
  Bottom Layer w0.2: v1(140,120) 142.5,120 143.725,121.225 143.725,130.183 143.842,130.3 C204_L2.1@144.5,130.3 144.5,131.42 v1(145.04,131.96) 146,131 C165_L2.2@146,130.45 ; 144.5,131.5 145.04,132.04 U27_L2.44@145.04,133.3
  Bottom Layer w0.254: R296_L2.2@137.43,117.857 137.43,117.882 137.778,118.23 138.375,118.23 138.726,118.581 138.726,119.084 v1(138.775,119.132)
10V_S2_GaN_L3: C165_L3.2 C204_L3.1 C208_L3.1 R296_L3.2 R300_L3.2 U27_L3.44 U35_L3.5 | length 28.3
  Top Layer w0.254: U35_L3.5@226.4,89.116 225.09,89.116 224.655,89.55 C208_L3.1@224.655,89.8 224.775,89.92 v1(224.775,91.132) 225.518,91.875 R300_L3.2@227.044,91.875
  Bottom Layer w0.2: v1(226,92) 228.5,92 229.5,93 229.5,93.717 229.65,93.867 229.65,101.746 229.578,101.817 229.578,102.183 229.696,102.3 C204_L3.1@230.5,102.3 230.5,103.42 v1(231.04,103.96) 232,103 C165_L3.2@232,102.45 ; 230.5,103.5 231.04,104.04 U27_L3.44@231.04,105.3
  Bottom Layer w0.254: R296_L3.2@223.43,89.857 223.43,89.882 223.778,90.23 224.375,90.23 224.726,90.581 224.726,91.084 v1(224.775,91.132)
10V_S2_GaN_N: C165_N.2 C204_N.1 C208_N.1 R296_N.2 R300_N.2 U27_N.44 U35_N.5 | length 28
  Top Layer w0.254: R300_N.2@101.625,28.044 101.625,26.518 v1(102.368,25.775) 103.58,25.775 C208_N.1@103.7,25.655 103.95,25.655 104.384,26.09 U35_N.5@104.384,27.4
  Bottom Layer w0.2: U27_N.44@88.2,32.04 89.46,32.04 90,31.5 ; C165_N.2@91.05,33 90.5,33 v1(89.54,32.04) 90.08,31.5 91.2,31.5 91.2,31.017 91.317,30.9 100.1,30.9 101.5,29.5 v1(101.5,27)
  Bottom Layer w0.254: v1(102.368,25.775) 102.416,25.726 102.919,25.726 103.27,25.375 103.27,24.778 103.618,24.43 R296_N.2@103.643,24.43
10V_S3_GaN_L1: C168_L1.1 C169_L1.2 C232_L1.1 R306_L1.2 R310_L1.2 U31_L1.44 U40_L1.5 | length 29.7
  Top Layer w0.254: v1(76.342,130.373) 76.342,131.303 76.547,131.508 C232_L1.1@77.929,131.508 ; v1(77.5,146.5) 76.722,145.722 76.722,136.546 78.01,135.257 78.01,131.427 78.154,131.283 U40_L1.5@79.583,131.283 79.603,131.303 80.11,131.303 80.483,131.676 R310_L1.2@80.483,133.942
  Bottom Layer w0.2: U31_L1.44@77.765,148.275 77.765,146.765 v1(77.5,146.5) 77.5,144.8 77.65,144.95 C169_L1.2@79,144.95
  Bottom Layer w0.254: v1(76.342,130.373) 76.342,131.378 R306_L1.2@76.397,131.433
10V_S3_GaN_L2: C168_L2.1 C169_L2.2 C232_L2.1 R306_L2.2 R310_L2.2 U31_L2.44 U40_L2.5 | length 29.7
  Top Layer w0.254: v1(159.842,115.373) 159.842,116.303 160.047,116.508 C232_L2.1@161.429,116.508 ; v1(161,131.5) 160.222,130.722 160.222,121.546 161.51,120.257 161.51,116.427 161.654,116.283 U40_L2.5@163.083,116.283 163.103,116.303 163.61,116.303 163.983,116.676 R310_L2.2@163.983,118.942
  Bottom Layer w0.2: U31_L2.44@161.265,133.275 161.265,131.765 v1(161,131.5) C168_L2.1@161,129.8 161.15,129.95 C169_L2.2@162.5,129.95
  Bottom Layer w0.254: v1(159.842,115.373) 159.842,116.378 R306_L2.2@159.897,116.433
10V_S3_GaN_L3: C168_L3.1 C169_L3.2 C232_L3.1 R306_L3.2 R310_L3.2 U31_L3.44 U40_L3.5 | length 29.7
  Top Layer w0.254: v1(245.842,87.373) 245.842,88.303 246.047,88.508 C232_L3.1@247.429,88.508 ; v1(247,103.5) 246.222,102.722 246.222,93.546 247.51,92.257 247.51,88.427 247.654,88.283 U40_L3.5@249.083,88.283 249.103,88.303 249.61,88.303 249.983,88.676 R310_L3.2@249.983,90.942
  Bottom Layer w0.2: U31_L3.44@247.265,105.275 247.265,103.765 v1(247,103.5) 247,101.8 247.15,101.95 C169_L3.2@248.5,101.95
  Bottom Layer w0.254: v1(245.842,87.373) 245.842,88.378 R306_L3.2@245.897,88.433
10V_S3_GaN_N: C168_N.1 C169_N.2 C232_N.1 R306_N.2 R310_N.2 U31_N.44 U40_N.5 | length 29.7
  Top Layer w0.254: v1(90,48) 90.778,47.222 99.954,47.222 101.243,48.51 105.073,48.51 105.217,48.654 U40_N.5@105.217,50.083 105.197,50.103 105.197,50.61 104.824,50.983 R310_N.2@102.558,50.983 ; C232_N.1@104.992,48.429 104.992,47.047 105.197,46.842 v1(106.127,46.842)
  Bottom Layer w0.2: U31_N.44@88.225,48.265 89.735,48.265 v1(90,48) 91.7,48 91.55,48.15 C169_N.2@91.55,49.5
  Bottom Layer w0.254: R306_N.2@105.067,46.897 105.122,46.842 v1(106.127,46.842)
10V_S4_GaN_L1: C171_L1.2 C247_L1.1 C249_L1.1 R323_L1.2 R327_L1.2 U36_L1.44 U45_L1.5 | length 55.3
  Top Layer w0.2: v1(82.265,167.155) 87.913,167.155 90.5,164.568 90.5,146.5 95.403,141.597 v1(95.403,134.667)
  Top Layer w0.254: v1(91.786,131.484) 92.513,131.484 C249_L1.1@92.811,131.783 ; U45_L1.5@94.783,131.4 93.783,131.4 93.594,131.59 93.004,131.59 C249_L1.1@92.811,131.783 ; v1(95.403,134.667) R327_L1.2@95.403,134.059 95.403,133.659 93.535,133.659 93.21,133.334 93.21,132.181 C249_L1.1@92.811,131.783
  Bottom Layer w0.2: U36_L1.44@82.265,168.275 v1(82.265,167.155) 82.265,166.035 82.425,165.875 82.55,165.875 82.875,166.2 82.875,166.325 83.05,166.5 C171_L1.2@84.282,166.5
  Bottom Layer w0.254: R323_L1.2@90.768,131.509 90.793,131.484 v1(91.786,131.484)
10V_S4_GaN_L2: C171_L2.2 C247_L2.1 C249_L2.1 R323_L2.2 R327_L2.2 U36_L2.44 U45_L2.5 | length 55.3
  Top Layer w0.2: v1(165.765,152.155) 171.413,152.155 174,149.568 174,131.5 178.903,126.597 v1(178.903,119.667)
  Top Layer w0.254: v1(175.286,116.484) 176.013,116.484 C249_L2.1@176.311,116.783 ; U45_L2.5@178.283,116.4 177.283,116.4 177.094,116.59 176.504,116.59 C249_L2.1@176.311,116.783 ; v1(178.903,119.667) R327_L2.2@178.903,119.059 178.903,118.659 177.035,118.659 176.71,118.334 176.71,117.181 C249_L2.1@176.311,116.783
  Bottom Layer w0.2: U36_L2.44@165.765,153.275 v1(165.765,152.155) 165.765,151.035 165.925,150.875 166.05,150.875 166.375,151.2 166.375,151.325 166.55,151.5 C171_L2.2@167.782,151.5
  Bottom Layer w0.254: R323_L2.2@174.268,116.509 174.293,116.484 v1(175.286,116.484)
10V_S4_GaN_L3: C171_L3.2 C247_L3.1 C249_L3.1 R323_L3.2 R327_L3.2 U36_L3.44 U45_L3.5 | length 55.3
  Top Layer w0.2: v1(251.765,124.155) 257.413,124.155 260,121.568 260,103.5 264.903,98.597 v1(264.903,91.667)
  Top Layer w0.254: v1(261.286,88.484) 262.013,88.484 C249_L3.1@262.311,88.783 ; U45_L3.5@264.283,88.4 263.283,88.4 263.094,88.59 262.504,88.59 C249_L3.1@262.311,88.783 ; v1(264.903,91.667) R327_L3.2@264.903,91.059 264.903,90.659 263.035,90.659 262.71,90.334 262.71,89.181 C249_L3.1@262.311,88.783
  Bottom Layer w0.2: U36_L3.44@251.765,125.275 v1(251.765,124.155) 251.765,123.035 251.925,122.875 252.05,122.875 252.375,123.2 252.375,123.325 252.55,123.5 C171_L3.2@253.782,123.5
  Bottom Layer w0.254: R323_L3.2@260.268,88.509 260.293,88.484 v1(261.286,88.484)
10V_S4_GaN_N: C171_N.2 C247_N.1 C249_N.1 R323_N.2 R327_N.2 U36_N.44 U45_N.5 | length 55.3
  Top Layer w0.2: v1(69.345,52.765) 69.345,58.413 71.932,61 90,61 94.903,65.903 v1(101.833,65.903)
  Top Layer w0.254: v1(101.833,65.903) R327_N.2@102.441,65.903 102.841,65.903 102.841,64.035 103.166,63.71 104.319,63.71 C249_N.1@104.717,63.311 ; v1(105.016,62.286) 105.016,63.013 C249_N.1@104.717,63.311 ; U45_N.5@105.1,65.283 105.1,64.283 104.91,64.094 104.91,63.504 C249_N.1@104.717,63.311
  Bottom Layer w0.2: U36_N.44@68.225,52.765 v1(69.345,52.765) 70.465,52.765 70.625,52.925 70.625,53.05 70.3,53.375 70.175,53.375 70,53.55 C171_N.2@70,54.782
  Bottom Layer w0.254: R323_N.2@104.991,61.268 105.016,61.293 v1(105.016,62.286)
12V: C4.1 C26.1 C27.1 C259.1 C260.1 D3.1 D17.1 J4.1 J6.1 J15.2 J21.1 R220.1 R221.1 R222.1 R223.1 | length 429.7
  Top Layer w0.2: J15.2@161.674,8.6 162.209,9.135 J15.2@162.209,9.358 162.209,9.765 J15.2@161.674,10.3
  Top Layer w0.3: D3.1@287.3,213.1 292,213.1 C26.1@292.5,212.6 ; C27.1@292,207.5 C27.1@291.8,207.7 291.8,208.8 292.7,209.7 C26.1@292.7,212.5
  Top Layer w0.5: v1(161.102,8.611) v1(161.102,8.611) 161.664,8.609 J15.2@161.674,8.6 ; v1(161.113,10.308) 161.115,10.306 161.667,10.306 J15.2@161.674,10.3 ; D17.1@213.9,3.8 v1(213.9,5.286) v1@213.9,5.312
  Top Layer w1: R222.1@205.668,222.2 218.068,209.8 247.8,209.8 R220.1@250,212 ; R220.1@250.214,211.786 274.786,211.786 288.551,225.551 ; C26.1@292.5,212.6 292.5,220.3 288.551,224.249 288.551,225.551 ; R223.1@297,273 297,263.1 294.492,260.592 294.492,249.922 cw(c284.326,247.007) 294.902,247.007 294.902,236.802 289.519,231.419 R221.1@288.551,231.419 288.551,225.551
  Layer 2 w1.2: J21.1@241.7,3.5 242.025,3.825 242.025,9.525 264.218,31.718 295.197,31.718 295.9,32.42 295.9,42.6 289.777,48.723 289.777,48.8 289.777,196.641 292.5,199.364 C26.1@292.5,212.6
12V_FET_DRAIN: Q2.1 Q2.2 Q2.5 Q2.6 Q2.8 R210.1
+5VISO_DC-: C87.2 C88.1 L8.2 U11.5 | length 7.2
  Top Layer w0.3: C88.1@88.729,90.418 89,90.689 89,91.717 88.804,91.913 88.804,92.879 U11.5@88.729,92.954 ; C88.1@88.8,90.4 89.8,90.4 ; v1(89.8,88.8) 89.8,90.4 ; L8.2@90.853,90.4 89.8,90.4
  Bottom Layer w0.3: C87.2@89,88.8 v1(89.8,88.8)
+5VISO_PCC: C54.1 C55.2 C61.1 C62.2 C68.1 C69.2 FB10.1 U7.1 U8.1 U9.1
  other v1: 135.9,261.4 122,261.5 126.6,261.7 110.4,261.8 114.9,261.8 103.9,262.5 124.5,262.8 112.8,262.9 138.2,263 139.6,263 103.9,263.4
+12V_OUT: C133.1 D4.2 D5.1 J15.1 J17.1 R205.2 R209.2 TP5.1 U19.6 | length 28.4
  Top Layer w0.2: J15.1@164.749,6.437 164.749,6.865 J15.1@165.284,7.4 ; v1(167.5,3.8) 167.504,3.796 D4.2@168.682,3.796 ; D5.1@175.1,5.321 D5.1@175.119,5.34 ; v1(175.334,18.976) 175.334,18.18 R205.2@175.339,18.175 ; C133.1@175.841,8.469 C133.1@176.216,8.094 ; J17.1@177.527,22.8 J17.1@177.021,22.294 177.021,21.735 J17.1@177.556,21.2 ; R209.2@179.879,12.125 179.913,12.16 v1(180.72,12.16)
  Top Layer w0.3: U19.6@175.729,10.925 175.729,8.581 C133.1@175.841,8.469
  Top Layer w0.5: J15.1@164.749,6.437 165.134,6.052 165.134,4.964 167.102,2.995 174.595,2.995 175.1,3.5 D5.1@175.1,5.321 ; J15.1@165.284,7.4 v1(165.9,7.4) ; D5.1@175.119,5.34 176.027,6.248 176.027,7.894 C133.1@176.227,8.094 ; J17.1@177.527,22.8 v1(178.1,22.8) ; J17.1@177.556,21.2 v1(178,21.2)
  other v1: 176,6.5 169.2,11.2
AUX_IN_PWR: J14.1 J16.1 J16.1A
BUFF_EN: C108.1 C115.1 C120.1 C126.1 D21.2 R65.1 R169.2 R184.2 R189.2 R199.2 U15.1 U15.4 U15.10 U15.13 U16.1 U16.4 U16.10 U16.13 U17.1 U17.4 U17.10 U17.13 U18.1 U18.4 U18.10 U18.13 | length 195.9
  Top Layer w0.2: v1(175,44.5) v1(175,51.5) ; 214.623,28.077 214.623,29.123 216.458,30.958 216.458,31.258 v1(216.5,31.3) R65.1@216.5,35 ; R199.2@231.683,24.472 231.733,24.472 231.906,24.645 D21.2@234,24.645
  Top Layer w0.4: U16.4@146.861,62.687 149.388,62.687 149.763,62.312 150.063,62.312 ; C115.1@146.863,66.112 146.863,64.639 U16.1@146.861,64.637 149.138,64.637 149.763,64.012 150.063,64.012 ; R184.2@146.863,67.212 146.869,67.212 146.911,67.171 C115.1@146.911,66.187 ; U16.10@152.163,62.062 v1(151.088,62.062) 150.838,62.312 150.063,62.312 ; U16.13@152.663,64.012 150.063,64.012 ; C108.1@162.068,66.066 R169.2@163.368,66.066 163.418,66.016 163.418,65.166 163.868,64.716 163.868,64.308 ; U15.4@162.289,62.318 165.166,62.318 ; U15.1@162.289,64.268 163.433,64.268 ; 163.473,64.268 164.863,64.268 165.166,63.965 ; U15.13@167.568,63.593 167.238,63.593 167.065,63.766 165.368,63.766 165.166,63.968 165.166,63.965 ; U15.10@168.066,61.668 v1(166.616,61.668) 165.166,61.668 165.166,62.318 ; U17.10@210.8,28.077 213.3,28.077 ; U17.13@210.966,26.102 213.3,26.102 ; 213.3,28.1 213.3,28.077 ; C120.1@215.4,22.7 R189.2@215.4,23.8 216.5,23.8 216.9,24.2 U17.1@216.9,25.4 ; U17.1@216.866,25.452 214.148,25.452 213.498,26.102 213.3,26.102 ; U17.4@216.866,27.402 215.298,27.402 214.623,28.077 213.3,28.077 ; U18.13@226.65,27.8 228.9,27.8 229.6,27.1 230.7,27.1 230.7,27.15 ; U18.10@226.65,29.75 226.658,29.758 228.766,29.758 v1(228.773,29.765) 229.438,29.1 230.7,29.1 ; R199.2@231.7,24.689 C126.1@231.7,25.6 232.3,25.6 232.6,25.9 U18.1@232.6,27.1 ; U18.1@232.55,27.15 230.7,27.15 ; U18.4@232.6,29.1 U18.4@232.55,29.1 230.7,29.1 ; 150.063,62.312 150.063,64.012 ; 165.166,62.318 165.166,63.965 ; 213.3,26.102 213.3,28.077 ; 230.7,27.15 230.7,29.1
  Bottom Layer w0.2: v1(151.088,62.062) 151.088,62.088 153.116,64.116 158.068,64.116 160.368,61.816 160.368,61.266 161.514,60.12 163.813,60.12 164.05,59.884 166.616,59.884 ; v1(166.616,61.668) 166.616,59.884 ; v1(175,44.5) 175,38.5 183,30.5 199.031,30.5 203.085,34.554 212.617,34.554 215.871,31.3 v1(216.5,31.3) 216.5,34.3 219.2,37 224.1,37 225.3,38.2 226.7,38.2 228.773,36.127 v1(228.773,29.765) ; v1(175,51.5) 166.616,59.884
CAN_EN: R88.1 R224.1 U23.8 | length 112.6
  Top Layer w0.2: R88.1@210.2,35 210.2,34.975 209.825,34.6 208.907,34.6 203.2,28.893 203.2,23.8 206.2,20.8 225.2,20.8 226,20 226.279,20 226.779,19.5 234.1,19.5 240.7,26.1 v1(253,26.1) ; v1(284.3,30.4) 284.378,30.478 284.378,31.608 U23.8@284.52,31.75 284.52,32.5 285.248,33.228 286.728,33.228 287.6,34.1 287.6,34.15 R224.1@288.1,34.65
  Bottom Layer w0.2: v1(253,26.1) 253.056,26.044 254.744,26.044 263.4,34.7 277.5,34.7 282.1,30.1 284,30.1 v1(284.3,30.4)
CAN_GND2: C153.2 C154.2 C155.2 FB18.1 U23.11 | length 0.8
  Top Layer w0.2: v1(287.725,16.675) v1@287.787,16.612 ; FB18.1@287.787,16.113 FB18.1@287.85,16.05
  Top Layer w0.4: FB18.1@287.787,16.113 v1@287.787,16.612
  Bottom Layer w0.2: v1(287.725,16.675) v1@287.725,16.775
  other v1: 282.1,20.5 280.3,21 278.5,21.6
CAN_RX: R71.1 U23.5 | length 113
  Top Layer w0.2: v1(212.4,31.7) R71.1@213.4,31.7 ; v1(288.2,29.9) 288.265,29.965 288.265,31.685 U23.5@288.33,31.75
  Bottom Layer w0.2: v1(212.4,31.7) 210.922,30.222 209.122,30.222 208.2,29.3 208.2,26.419 208.8,25.819 208.8,23.383 206.6,21.183 206.6,18.6 210,15.2 245.066,15.2 263.766,33.9 276.8,33.9 281.605,29.095 287.395,29.095 v1(288.2,29.9)
CAN_TX: R84.1 U23.3 | length 114.5
  Top Layer w0.2: v1(212.3,34) R84.1@212.3,35 ; v1(285.2,29.7) 287.5,29.7 288,29.2 290.3,29.2 290.87,29.77 U23.3@290.87,31.75
  Bottom Layer w0.2: v1(212.3,34) 213,33.3 213,31.5 211.322,29.822 209.288,29.822 208.733,29.267 208.733,26.451 209.2,25.984 209.2,19.099 212.699,15.6 244.9,15.6 263.6,34.3 277.1,34.3 281.7,29.7 v1(285.2,29.7)
CAN_VDD: C6.1 C147.1 C148.1 FB12.2 U23.9 | length 11.2
  Top Layer w0.2: C148.1@286.4,34.6 C148.1@286.5,34.7
  Top Layer w0.4: U23.9@283.25,31.75 283.25,32.5 284.55,33.8 285.666,33.8 286.2,34.334 286.2,34.5 C148.1@286.267,34.567 ; C148.1@286.5,34.7 C147.1@286.5,35.9 286.525,35.9 286.8,36.175 286.8,36.2 287.7,37.1 287.7,37.666 288.05,38.016 FB12.2@290.4,38.016
CAN_VIO: C152.1 FB13.2 R224.2 U23.1 | length 9.2
  Top Layer w0.2: C152.1@289.6,34.5 C152.1@289.6,34.6
  Top Layer w0.4: R224.2@288.1,35.734 288.266,35.734 289.2,34.8 289.5,34.8 289.6,34.7 C152.1@289.6,34.6 289.7,34.7 FB13.2@291.1,34.7 ; C152.1@289.6,34.5 290.6,33.5 292.7,33.5 293.31,32.89 293.31,31.85 U23.1@293.41,31.75
CANH: L3.1 R225.2 U23.19 | length 38.2
  Top Layer w0.2: R225.2@261.75,19.55 261.75,19.575 260.575,20.75 L3.1@259.75,20.75 259.75,22.25 261.2,23.7 279.899,23.7 280.347,23.252 v1(280.377,23.252) ; v1(291.746,23.3) 291.805,23.241 291.805,23.135 292.14,22.8 U23.19@292.14,22.05
  Bottom Layer w0.2: v1(280.377,23.252) 291.698,23.252 v1(291.746,23.3)
CANHI: C156.1 J1.7 L3.4 R225.1 R226.2 U25.1 | length 31.4
  Top Layer w0.2: v1(262.9,13.9) 260.5,13.9 260.1,14.3 260.1,15.85 L3.4@259.75,16.2 259.75,16.375 260.1,16.725 260.526,16.725 261.35,17.55 261.375,17.55 261.75,17.925 R225.1@261.75,17.95 261.9,18.1 264.4,18.1 C156.1@264.55,18.25 ; U25.1@264.3,20.2 264.37,20.13 264.37,18.43 C156.1@264.55,18.25 ; R226.2@265.15,16.25 264.808,16.592 264.808,18.092 C156.1@264.65,18.25 C156.1@264.55,18.25
  Bottom Layer w0.2: v1(262.9,13.9) 262.9,11.528 268.128,6.3 272.105,6.3 J1.7@273.885,8.08
CANL: L3.2 R228.2 U23.18 | length 40.2
  Top Layer w0.2: R228.2@255.25,19.55 255.25,19.575 256.425,20.75 L3.2@257.25,20.75 257.25,22.65 258.7,24.1 290,24.1 290.7,23.4 290.7,22.22 U23.18@290.87,22.05
CANLO: C158.2 J1.2 L3.3 R227.1 R228.1 U24.1 | length 32
  Top Layer w0.2: R228.1@255.25,17.95 255.25,17.925 255.625,17.55 256.125,17.55 257.25,16.425 L3.3@257.25,16.2 257.25,14.85 258.9,13.2 272.99,13.2 ; U24.1@270.3,20.2 270.369,20.131 270.369,18.45 270.569,18.25 C158.2@270.65,18.25 270.65,16.45 R227.1@270.85,16.25 270.85,15.34 272.99,13.2 ; J1.2@275.27,10.92 272.99,13.2
DC_VSEN+: R139.2 U11.11 | length 129.7
  Top Layer w0.2: U11.11@82.229,102.904 82.229,104.229 82.5,104.5 82.775,104.5 83.275,105 v1(84,105) ; v1(168.5,51.5) 169.5,50.5 169.5,35.881 171.241,34.14 R139.2@171.883,34.14
  Bottom Layer w0.2: v1(84,105) 84.717,105 84.771,105.054 85.229,105.054 85.283,105 101.349,105 103.954,102.395 103.954,101.612 144.999,60.566 151.066,54.5 160.717,54.5 162.217,53 165,53 165.6,52.4 165.666,52.4 166.566,51.5 v1(168.5,51.5)
DC_VSEN-: R141.2 U11.10 | length 127.6
  Top Layer w0.2: U11.10@82.879,102.904 83.004,103.029 83.004,104.004 83.446,104.446 84.946,104.446 v1(85,104.5) ; v1(170,51) 170,36 170.5,35.5 R141.2@171.35,35.5
  Bottom Layer w0.2: v1(85,104.5) 85.054,104.554 101.229,104.554 103.554,102.229 103.554,101.446 151,54 160.5,54 162.5,52 165.5,52 166.554,50.946 169.946,50.946 v1(170,51)
DCDC_EN: C146.1 R213.1 R216.1 U21.6 | length 11.3
  Top Layer w0.2: R216.1@164.538,17.171 C146.1@166.32,17.171 ; U21.6@165.633,24.004 165.633,22.874 165.545,22.786 165.545,17.971 166.32,17.196 C146.1@166.32,17.171 ; R213.1@168.571,17.096 168.496,17.171 C146.1@166.32,17.171
DCDC_FB: C137.2 R214.1 R215.2 U21.7 | length 5.4
  Top Layer w0.2: U21.7@166.133,24.004 166.133,22.475 R215.2@166.383,22.225 168.177,22.225 C137.2@168.207,22.196 R214.1@169.858,22.196
DCDC_PG: R218.1 R219.2 U21.5 | length 4
  Top Layer w0.2: R218.1@162.608,22.196 164.554,22.196 R219.2@164.583,22.225 164.583,22.25 165.133,22.8 U21.5@165.133,24.004
DCDC_VIN: C141.1 C142.2 J17.2 R213.2 U21.1 | length 8.2
  Top Layer w0.2: R213.2@170.171,17.096 170.196,17.096 170.571,17.471 170.571,17.496 172.9,19.825 172.9,24.2
EF_dVdt: C135.1 U19.7 | length 2.8
  Top Layer w0.2: C135.1@172.479,12.525 173.775,12.525 174.708,11.592 174.912,11.592 174.929,11.575
EF_EN: R204.1 R208.2 U19.1 | length 5.1
  Top Layer w0.2: U19.1@176.729,10.225 178.116,10.225 179.391,8.95 R208.2@179.391,8.925 R204.1@179.391,7.046
EF_ILIM: R206.2 U19.9 | length 4.7
  Top Layer w0.2: R206.2@170.729,9.975 170.729,10 171.386,10.658 172.85,10.658 172.874,10.634 174.338,10.634 174.404,10.7 U19.9@175.079,10.7
EF_ITIMER: C134.1 U19.10 | length 2.6
  Top Layer w0.2: C134.1@172.851,9.7 172.851,9.725 173.351,10.225 U19.10@175.229,10.225
EF_OVLO: R208.1 R211.2 U19.2 | length 5.1
  Top Layer w0.2: U19.2@176.879,10.7 179.216,10.7 R208.1@179.391,10.525 ; R211.2@177.9,8.4 177.965,8.465 v1(177.965,9.298)
  Bottom Layer w0.2: v1(177.965,9.298) 177.965,10.165 v1(178.5,10.7)
EF_PG: C136.1 Q2.3 R209.1 R212.2 U19.3 | length 13.8
  Top Layer w0.2: Q2.3@167.032,12.834 167.082,12.884 169.115,12.884 R212.2@169.482,13.25 169.831,12.901 v1(169.831,12.16) ; U19.3@176.879,11.15 176.904,11.175 177.294,11.175 177.539,11.42 v1(177.622,11.42) ; v1@177.555,11.434 177.563,11.434 178.254,12.125 R209.1@178.279,12.125
  Bottom Layer w0.2: v1(169.831,12.16) 170.249,11.742 174.338,11.742 174.614,11.466 177.576,11.466 v1(177.622,11.42)
EF_PGTH: R205.1 R207.2 U19.4 | length 7.1
  Top Layer w0.2: 176.7,11.9 v1(177.1,12.3) ; R205.1@176.939,18.175 176.939,16.29 R207.2@176.979,16.25 177.004,16.25 177.379,15.875 177.379,15.85 177.8,15.429 v1(177.8,15)
  Bottom Layer w0.2: v1(177.1,12.3) 177.8,13 v1(177.8,15)
EN_AUX_ISO_DCAC: D19.2 R67.1 R287_L1.2 R287_L2.2 R287_L3.2 R287_N.2 R298_L1.2 R298_L2.2 R298_L3.2 R298_N.2 R308_L1.2 R308_L2.2 R308_L3.2 R308_N.2 R325_L1.2 R325_L2.2 R325_L3.2 R325_N.2 | length 468
  Top Layer w0.2: R287_L1.2@39.463,111.083 39.3,110.92 39.3,109.9 51.2,109.9 51.483,109.617 55.383,109.617 ; R298_L1.2@55.425,110.583 55.383,110.541 55.383,109.617 ; v1(60,109) 56.5,109 56,109.5 55.5,109.5 55.383,109.617 ; v1(73,109) 73.442,109.442 R308_L1.2@75.755,109.442 ; v1(96.5,110) 97.056,110 97.364,109.693 97.364,108.936 R325_L1.2@97.609,108.691 ; R287_L2.2@122.963,96.083 122.8,95.92 v1(122.8,94.9) 134.7,94.9 134.983,94.617 139,94.617 ; R287_N.2@125.417,9.963 125.58,9.8 v1(126.6,9.8) 126.6,21.7 126.883,21.983 126.883,25.883 ; R298_N.2@125.917,25.925 126.675,25.925 126.717,25.883 126.883,25.883 ; R308_N.2@126.983,46.33 127.83,46.33 128.643,47.143 128.643,66.357 v1(128.071,66.929) 127.5,67.5 127.16,67.5 R325_N.2@126.791,67.869 R325_N.2@127.1,68.178 ; R308_N.2@127.058,46.255 127.058,43.942 130.35,40.65 130.35,33.85 126.883,30.383 126.883,25.883 ; R298_L2.2@138.925,95.583 139,95.508 139,94.617 ; v1(141,93.5) 140,94.5 139.117,94.5 139,94.617 ; v1(157,94) 158.058,94 158.5,94.442 R308_L2.2@159.255,94.442 ; R325_L2.2@180.5,94.34 R325_L2.2@180.869,94.709 181,94.578 181,93.689 180.446,93.135 180.446,91.5 180.446,78.554 192.1,66.9 v1(208.8,66.9) ; R287_L3.2@208.963,68.083 208.8,67.92 v1(208.8,66.9) ; v1(214.5,30.5) 215.125,31.125 215.125,31.325 R67.1@215.5,31.7 ; R298_L3.2@224.925,67.583 224.883,67.541 v1(224.883,66.617) 220.983,66.617 220.7,66.9 v1(208.8,66.9) ; v1(242.5,66.5) 242.558,66.442 R308_L3.2@245.255,66.442 ; R308_L3.2@245.33,66.517 245.33,65.67 245.917,65.083 266.383,65.083 266.5,65.2 266.5,66.34 266.855,66.695 D19.2@266.855,63
  Layer 2 w0.2: v1(60,109) 66.5,109 67.054,109.554 70.317,109.554 70.871,109 v1(73,109) 95.5,109 v1(96.5,110) 99.542,110 100.542,109 103.5,109 117.6,94.9 v1(122.8,94.9) 124.383,94.9 128.071,91.212 v1(128.071,66.929) ; v1(141,93.5) 141.054,93.446 151.946,93.446 152.554,94.054 156.946,94.054 v1(157,94) 157.529,93.471 176.029,93.471 178,91.5 v1(180.5,91.5) ; v1(214.5,30.5) 217.846,33.846 220.763,33.846 223.271,36.354 257.9,36.354 260,38.454 260,48 262.55,50.55 262.55,50.667 262.654,50.771 262.654,52.346 248.558,66.442 242.558,66.442 v1(242.5,66.5) 242.49,66.51 241.771,66.51 241.28,67 235.783,67 235.163,66.38 230.787,66.38 230.667,66.5 227.434,66.5 227.317,66.617 v1(224.883,66.617)
EN_BUFF_PWM_DCDC: R69.1
FAN_CTRL: R329.1 R334.2 | length 58.2
  Top Layer w0.2: v1(185.5,21) 185.5,28.5 186.5,29.5 186.5,32.017 188.5,34.017 188.5,45.5 187.5,46.5 186.617,46.5 186.5,46.617 R334.2@186.5,47.6 ; v1(205.752,8.822) 205.752,7.779 R329.1@205.85,7.681
  Bottom Layer w0.2: v1(185.5,21) 186,20.5 186,19 186.405,18.595 186.405,18.58 186.61,18.375 186.625,18.375 187.6,17.4 199.9,17.4 205.752,11.548 v1(205.752,8.822)
FAN_SN: D17.2 J4.2 J6.2 J21.2 Q3.1 Q3.2 Q3.5 Q3.6 Q3.8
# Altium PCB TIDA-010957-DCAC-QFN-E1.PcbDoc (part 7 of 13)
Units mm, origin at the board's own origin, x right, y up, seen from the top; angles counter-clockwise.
Board outline 300 x 300 mm, 4 copper layers (Top Layer, Layer 1, Layer 2, Bottom Layer), stack 1.787 mm thick; 1286 components, 677 nets, 4169 pads, 3428 vias.

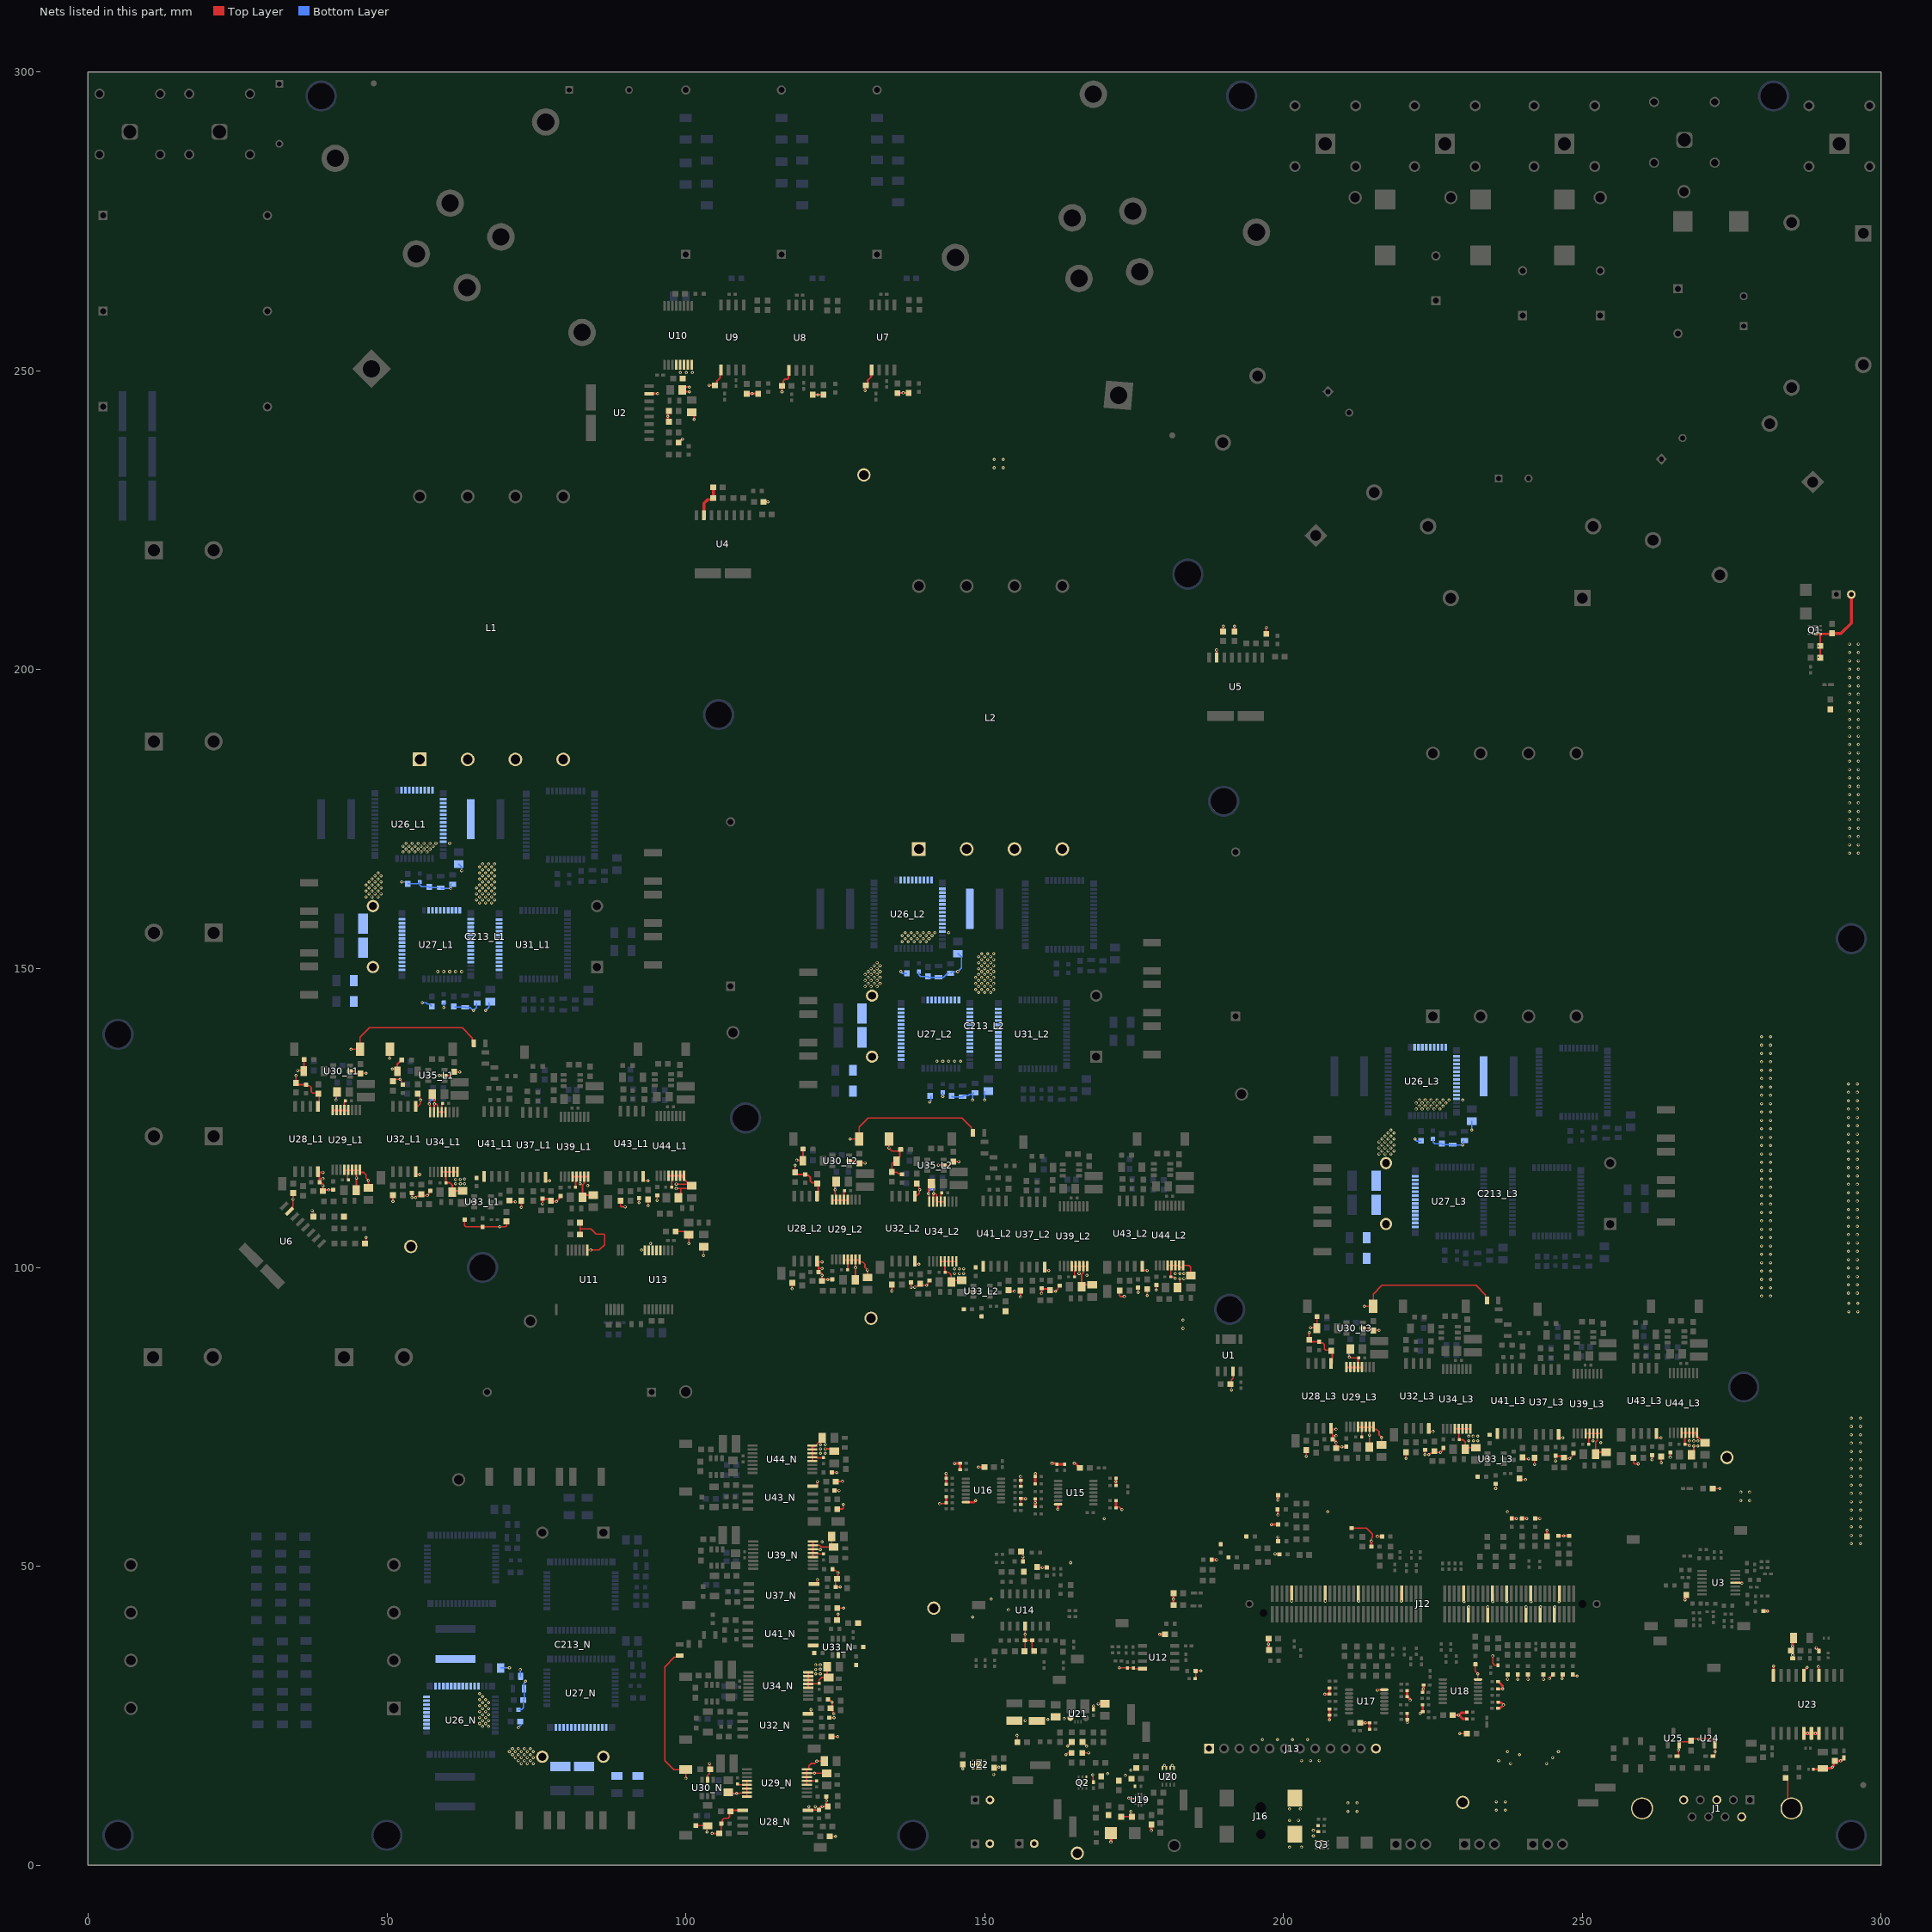
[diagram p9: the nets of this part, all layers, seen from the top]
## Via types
v1: diameter 0.508, hole 0.254, Top Layer to Bottom Layer, tented both sides, 3428 vias

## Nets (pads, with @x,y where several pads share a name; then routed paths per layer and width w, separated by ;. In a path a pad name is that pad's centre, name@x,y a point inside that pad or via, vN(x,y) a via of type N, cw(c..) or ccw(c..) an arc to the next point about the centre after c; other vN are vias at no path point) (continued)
GND: C4.2 C5.2 C6.2 C13.2 C14.2 C15.1 C16.2 C26.2 C27.2 C28.2 C30.2 C31.1 C33.2 C34.2 C36.2 C37.1 C39.2 C40.2 C42.2 C43.1 C45.2 C46.2 C47.1 C49.2 C50.1 C52.2 C53.2 C56.1 C57.2 C59.1 C60.2 C63.1 C64.2 C66.1 C67.2 C70.1 C71.2 C73.1 C74.2 C77.2 C78.2 C79.2 C80.1 C81.2 C82.2 C83.1 C84.2 C91.2 C92.2 C93.2 C95.1 C96.2 C98.1 C99.2 C101.1 C102.2 C104.1 C105.2 C107.2 C108.2 C109.2 C110.2 C111.2 C112.2 C113.2 C114.2 C115.2 C116.2 C117.2 C118.2 C119.2 C120.2 C121.2 C122.2 C123.2 C124.2 C125.2 C126.2 C127.2 C128.2 C129.2 C130.2 C131.2 C132.2 C133.2 C134.2 C135.2 C136.2 C138.2 C139.2 C140.2 C141.2 C142.1 C143.2 C144.2 C145.2 C146.2 C147.2 C148.2 C152.2 C159.1 C160.1 C161.1 C162.1 C173.1 C174.1 C175.1 C176.1 C186_L1.2 C186_L2.2 C186_L3.2 C186_N.2 C191_L1.1 C191_L2.1 C191_L3.1 C191_N.1 C196_L1.1 C196_L2.1 C196_L3.1 C196_N.1 C197_L1.2 C197_L2.2 C197_L3.2 C197_N.2 C198_L1.2 C198_L2.2 C198_L3.2 C198_N.2 C199_L1.1 C199_L2.1 C199_L3.1 C199_N.1 C200_L1.2 C200_L2.2 C200_L3.2 C200_N.2 C205_L1.1 C205_L2.1 C205_L3.1 C205_N.1 C206_L1.1 C206_L2.1 C206_L3.1 C206_N.1 C207_L1.1 C207_L2.1 C207_L3.1 C207_N.1 C209_L1.1 C209_L2.1 C209_L3.1 C209_N.1 C219_L1.1 C219_L2.1 C219_L3.1 C219_N.1 C220_L1.2 C220_L2.2 C220_L3.2 C220_N.2 C221_L1.2 C221_L2.2 C221_L3.2 C221_N.2 C222_L1.1 C222_L2.1 C222_L3.1 C222_N.1 C223_L1.2 C223_L2.2 C223_L3.2 C223_N.2 C224_L1.2 C224_L2.2 C224_L3.2 C224_N.2 C231_L1.1 C231_L2.1 C231_L3.1 C231_N.1 C236_L1.1 C236_L2.1 C236_L3.1 C236_N.1 C237_L1.2 C237_L2.2 C237_L3.2 C237_N.2 C238_L1.2 C238_L2.2 C238_L3.2 C238_N.2 C239_L1.1 C239_L2.1 C239_L3.1 C239_N.1 C240_L1.2 C240_L2.2 C240_L3.2 C240_N.2 C243_L1.2 C243_L2.2 C243_L3.2 C243_N.2 C248_L1.1 C248_L2.1 C248_L3.1 C248_N.1 C253_L1.1 C253_L2.1 C253_L3.1 C253_N.1 C254_L1.2 C254_L2.2 C254_L3.2 C254_N.2 C255_L1.2 C255_L2.2 C255_L3.2 C255_N.2 C256_L1.1 C256_L2.1 C256_L3.1 C256_N.1 C259.2 C260.2 C261.2 C262.2 C263.1 D5.2 J12.7 J12.10 J12.16 J12.19 J12.22 J12.29 J12.35 J12.38 J12.46 J12.47 J12.65 J12.83 J12.97 J12.111 J13.1 J13.12 J16.2 J16.3 Q1.4 Q1.7 Q2.4 Q2.7 Q3.4 Q3.7 R23.2 R81.1 R82.1 R97.1 R105.1 R113.1 R121.1 R129.1 R137.2 R144.2 R149.2 R154.2 R159.2 R169.1 R170.1 R171.1 R172.1 R173.1 R184.1 R185.1 R186.1 R187.1 R188.1 R189.1 R190.1 R191.1 R192.1 R193.1 R199.1 R200.1 R201.1 R202.1 R203.1 R206.1 R207.1 R211.1 R212.1 R215.1 R216.2 R217.1 R219.1 R233.1 R234.1 R235.1 R284_L1.1 R284_L2.1 R284_L3.1 R284_N.1 R295_L1.1 R295_L2.1 R295_L3.1 R295_N.1 R305_L1.1 R305_L2.1 R305_L3.1 R305_N.1 R322_L1.1 R322_L2.1 R322_L3.1 R322_N.1 R330.1 R333.2 TP1.1 TP6.1 TP11.1 TP12.1 TP13.1 TP25.1 TP26.1 U1.3 U2.9 U3.11 U4.9 U5.9 U6.9 U7.5 U8.5 U9.5 U10.4 U10.5 U10.6 U10.7 U10.8 U11.9 U12.4 U13.4 U13.5 U13.6 U13.7 U13.8 U14.11 U15.7 U16.7 U17.7 U18.7 U19.8 U20.5 U20.6 U20.7 U20.8 U21.4 U22.2 U22.3 U22.5 U22.7@149.05,16.826 U23.4 U23.6 U23.10 U28_L1.4 U28_L2.4 U28_L3.4 U28_N.4 U29_L1.4 U29_L1.5 U29_L1.6 U29_L1.7 U29_L1.8 U29_L2.4 U29_L2.5 U29_L2.6 U29_L2.7 U29_L2.8 U29_L3.4 U29_L3.5 U29_L3.6 U29_L3.7 U29_L3.8 U29_N.4 U29_N.5 U29_N.6 U29_N.7 U29_N.8 U32_L1.4 U32_L2.4 U32_L3.4 U32_N.4 U33_L1.2 U33_L2.2 U33_L3.2 U33_N.2 U34_L1.4 U34_L1.5 U34_L1.6 U34_L1.7 U34_L1.8 U34_L2.4 U34_L2.5 U34_L2.6 U34_L2.7 U34_L2.8 U34_L3.4 U34_L3.5 U34_L3.6 U34_L3.7 U34_L3.8 U34_N.4 U34_N.5 U34_N.6 U34_N.7 U34_N.8 U37_L1.4 U37_L2.4 U37_L3.4 U37_N.4 U39_L1.4 U39_L1.5 U39_L1.6 U39_L1.7 U39_L1.8 U39_L2.4 U39_L2.5 U39_L2.6 U39_L2.7 U39_L2.8 U39_L3.4 U39_L3.5 U39_L3.6 U39_L3.7 U39_L3.8 U39_N.4 U39_N.5 U39_N.6 U39_N.7 U39_N.8 U41_L1.5 U41_L2.5 U41_L3.5 U41_N.5 U43_L1.4 U43_L2.4 U43_L3.4 U43_N.4 U44_L1.4 U44_L1.5 U44_L1.6 U44_L1.7 U44_L1.8 U44_L2.4 U44_L2.5 U44_L2.6 U44_L2.7 U44_L2.8 U44_L3.4 U44_L3.5 U44_L3.6 U44_L3.7 U44_L3.8 U44_N.4 U44_N.5 U44_N.6 U44_N.7 U44_N.8 | length 497.4
  Top Layer w0.2: U6.9@33.702,109.399 33.702,109.589 34.303,110.19 v1(34.303,111.434) ; v1(37.5,109.5) 37.5,109.441 37.7,109.241 C53.2@37.7,108.5 ; C49.2@46.3,104 46.5,104.2 v1(46.5,105) ; C207_L1.1@63,108 63,107 63.2,106.8 69.883,106.8 70,106.917 C223_L1.2@70,107.7 ; C240_L1.2@70.5,111.2 70.7,111 v1(71.5,111) ; C80.1@82.3,107.5 82.325,107.5 82.35,107.475 82.35,106.488 ; C81.2@82.35,105.5 82.35,106.488 ; U11.9@83.529,102.904 v1(84.104,102.904) 85.504,102.904 86.4,103.8 86.4,105.483 86.283,105.6 85,105.6 84.112,106.488 82.35,106.488 ; C91.2@98.3,106 99.984,106 C92.2@100.5,105.484 v1(100.5,104) ; v1(98.406,113.182) 100.511,113.182 C254_L1.2@101,113.671 100.712,113.959 100.547,113.959 v1(98.406,113.959) ; v1(103,102) C93.2@103,103.484 ; C36.2@113,228.1 C36.2@113.026,228.074 ; C240_N.2@125.3,41 125.5,41.2 v1(125.5,42) ; v1@142.488,60.488 R186.1@143.563,60.488 ; C240_L2.2@154,96.2 154.2,96 v1(155,96) ; v1(155.4,21.7) 155.483,21.617 R217.1@155.483,20.55 ; v1(156,65) 156,64.425 C119.2@156.063,64.362 R188.1@156.063,63.362 ; R187.1@156.063,60.362 C118.2@156.063,61.362 ; v1@156.063,64.937 v1@156.125,65 ; R149.2@156.075,52.475 156.384,52.166 v1(156.384,51.6) 156.384,50.861 C98.1@156.416,50.829 ; R154.2@156.657,35.784 156.76,35.886 C101.1@156.76,37.625 ; U14.11@156.77,39.984 156.777,39.977 156.777,38.607 v1(156.784,38.6) 156.784,37.649 C101.1@156.76,37.625 ; R159.2@158.284,35.8 157.941,36.143 C104.1@157.941,37.625 C101.1@156.76,37.625 ; C109.2@158.443,63.741 C109.2@158.468,63.766 ; R144.2@158.784,49.9 158.884,49.8 v1(159.684,49.8) C95.1@160.384,49.8 ; v1(163.6,18.5) 163.871,18.771 R216.2@164.538,18.771 ; v1@163.858,19.875 v1(163.89,19.907) 164.583,20.6 R219.1@164.583,20.625 ; C146.2@166.32,18.771 167.371,18.771 v1(167.4,18.8) ; R215.1@166.383,20.625 166.383,20.6 167.074,19.909 v1(167.074,19.901) ; v1(168.1,15.1) 168.159,15.041 168.159,13.956 C136.2@168.232,13.884 ; C141.2@170.126,27.003 C141.2@170.133,27.01 ; D5.2@171.119,5.34 D5.2@171.126,5.334 ; R172.1@171.968,59.766 172.098,59.896 172.562,59.896 v1(172.988,59.471) ; v1(172.5,33) R137.2@174.9,33 175.03,32.87 U12.4@176.4,32.87 ; C134.2@172.851,8.1 172.856,8.094 C133.2@174.627,8.094 174.5,8.221 v1(174.5,9) ; C256_L2.1@181.153,98.432 181.603,98.432 181.854,98.182 v1(181.906,98.182) ; R333.2@185.2,31.2 185.25,31.2 185.3,31.25 C262.2@185.3,32.5 v1(186.2,32.5) ; v1(191.3,79.5) 191.3,80.3 C13.2@191.1,80.5 191.3,80.7 191.3,81.2 191.6,81.5 191.6,82.535 U1.3@191.535,82.6 ; v1(198.6,52.1) 199.2,52.1 C174.1@199.3,52 ; C162.1@199.1,54.2 v1(199.1,54.9) ; C45.2@211.4,56.4 213.9,56.4 214.9,55.4 214.9,54.942 214.712,54.754 214.712,54.212 v1(214.7,54.2) ; v1(229.5,22) R235.1@230.7,22 ; C14.2@232.1,33.6 232.1,32.455 232.5,32.055 v1(232.5,32) 232.5,31.1 U18.7@232.55,31.05 ; v1(235,35) 235.006,34.994 235.006,33.794 235.35,33.45 C263.1@235.925,33.45 ; v1(235.5,63) C206_L3.1@235.5,63.8 ; v1(237.5,31.1) C84.2@237.5,31.9 ; v1(239.2,31.1) C73.1@239.2,31.9 ; C223_L3.2@239.5,64.7 239.7,64.5 v1(240.5,64.5) ; C240_L3.2@240,68.2 240.2,68 v1(241,68) ; v1(240.9,31.1) C37.1@240.9,31.9 ; v1(243.5,31.1) C59.1@243.5,31.9 ; v1(244.5,31.183) 244.559,31.242 244.559,31.359 C102.2@245.1,31.9 ; v1(246.6,31.2) 246.7,31.3 C105.2@246.7,31.9 ; C99.2@248.4,31.9 248.65,31.65 v1(249.125,31.65) ; C256_L3.1@267.153,70.432 267.603,70.432 267.854,70.182 v1(267.906,70.182) ; R233.1@271.8,63 v1(273,63) ; U23.10@281.98,31.75 U23.10@281.99,31.76 ; v1@281.99,33.29 v1(282,33.3) ; C147.2@284.786,36.014 C147.2@284.9,35.9 C147.2@285.2,35.6 ; U23.6@287.06,31.75 U23.6@287.06,32.5 ; v1@287.6,33.04 v1(287.6,33.1) ; v1(289.5,33.2) v1@289.55,33.15 ; U23.4@289.55,31.8 U23.4@289.6,31.75 ; C152.2@289.6,35.8 C152.2@289.6,35.9
  Top Layer w0.25: v1(174.109,11.188) 174.146,11.15 U19.8@175.079,11.15
  Top Layer w0.254: v1(34.303,111.434) 34.303,112.408 C186_L1.2@34.325,112.43 ; v1(39.3,114.838) 38.697,114.838 ; v1(39.3,115.901) 38.804,115.901 38.697,116.008 38.697,114.838 ; C196_L1.1@40.997,113.005 40.985,112.992 40.276,112.992 v1(40.263,112.98) 39.525,112.98 R284_L1.1@39.3,112.755 v1(39.3,113.678) 39.3,113.964 39.151,114.113 38.863,114.113 C191_L1.1@38.738,114.238 38.697,114.28 38.697,114.838 ; U29_L1.4@42.947,116.25 U29_L1.5@43.422,116.25 ; C199_L1.1@43.588,114.63 43.465,114.753 43.465,114.859 43.422,114.902 U29_L1.5@43.422,116.25 ; C198_L1.2@44.854,113.23 44.897,113.273 v1(44.897,114.961) U29_L1.7@44.897,116.25 ; C197_L1.2@46.9,113.316 v1(46.9,114.573) 46.5,114.973 46.5,115.521 46.12,115.901 45.625,115.901 45.547,115.979 45.547,116.25 U29_L1.7@44.897,116.25 ; v1(51.005,111.058) C200_L1.2@51.005,112.108 ; v1(54.18,111.698) C205_L1.1@54.18,112.48 ; v1(54.815,111.702) 54.877,111.702 55.091,111.917 55.403,111.917 R295_L1.1@55.75,112.263 55.98,112.033 v1(56.775,112.033) 56.844,112.033 57.027,112.217 57.027,112.507 C219_L1.1@57.25,112.73 ; U32_L1.4@54.815,116.05 54.815,115.723 54.988,115.55 v1(55.503,115.55) ; U34_L1.4@59.175,116 U34_L1.5@59.825,116 ; U34_L1.8@61.775,116 U34_L1.7@61.125,116 U34_L1.6@60.475,116 U34_L1.5@59.825,116 ; C220_L1.2@62.675,112.833 61.063,112.833 60.916,112.98 60.916,113.774 60.508,114.182 C222_L1.1@59.894,114.182 59.859,114.216 59.859,115.966 U34_L1.5@59.825,116 ; v1(72.5,110.064) C224_L1.2@72.5,111.155 ; v1(76.028,110.642) C231_L1.1@76.028,111.184 ; C231_L1.1@76.028,111.434 77.179,111.434 R305_L1.1@77.429,111.184 77.58,111.033 v1(78.379,111.033) 78.828,111.482 78.828,111.742 C236_L1.1@79.041,111.955 ; U37_L1.4@76.534,115.05 76.534,114.673 76.707,114.5 v1(77.233,114.5) ; U39_L1.4@81.06,115.208 U39_L1.5@81.71,115.208 ; C239_L1.1@81.56,113.432 81.56,114.413 81.71,114.563 U39_L1.5@81.71,115.208 ; U39_L1.8@83.66,115.208 U39_L1.7@83.01,115.208 ; C237_L1.2@84.5,112.096 82.855,112.096 82.714,111.955 82.714,113.791 83.01,114.087 U39_L1.7@83.01,115.208 ; C243_L1.2@89.073,111.155 89.075,111.153 89.075,110.291 89.224,110.142 v1(89.855,110.142) ; v1(92.175,110.842) C248_L1.1@92.175,111.609 ; U43_L1.4@92.883,115.226 92.883,114.675 93.056,114.502 93.683,114.502 v1(93.685,114.5) ; R322_L1.1@93.685,111.38 93.7,111.365 v1(93.7,110.317) ; v1(95.201,111.23) 95.215,111.244 95.215,112.041 C253_L1.1@95.228,112.055 ; U44_L1.4@97.104,115.338 U44_L1.5@97.754,115.338 ; C256_L1.1@97.653,113.432 97.653,114.592 97.754,114.693 U44_L1.5@97.754,115.338 ; C255_L1.2@98.77,111.659 99.155,112.044 99.155,113.14 ; 99.497,115.5 99.497,115.338 ; C254_L1.2@100.547,113.959 99.497,115.009 99.497,115.338 ; v1(117.803,96.434) 117.803,97.408 C186_L2.2@117.825,97.43 ; U29_N.4@120.25,13.447 U29_N.5@120.25,14.097 ; U32_N.4@120.45,25.315 120.777,25.315 120.95,25.488 v1(120.95,26.003) ; U34_N.4@120.5,29.675 U34_N.5@120.5,30.325 ; U34_N.8@120.5,32.275 U34_N.7@120.5,31.625 U34_N.6@120.5,30.975 U34_N.5@120.5,30.325 ; v1(120.599,9.8) 120.599,9.304 120.492,9.197 121.662,9.197 ; 121,69.997 121.162,69.997 ; U44_N.4@121.162,67.604 U44_N.5@121.162,68.254 ; U43_N.4@121.274,63.383 121.825,63.383 121.998,63.556 121.998,64.183 v1(122,64.185) ; U39_N.4@121.292,51.56 U39_N.5@121.292,52.21 ; U39_N.8@121.292,54.16 U39_N.7@121.292,53.51 ; U37_N.4@121.45,47.034 121.827,47.034 122,47.207 v1(122,47.733) ; v1(121.662,9.8) 121.662,9.197 ; C199_N.1@121.87,14.088 121.866,14.093 120.255,14.093 U29_N.5@120.25,14.097 ; v1(122.8,99.838) 122.197,99.838 ; v1(122.8,100.901) 122.304,100.901 122.197,101.008 122.197,99.838 ; C254_N.2@122.829,71.5 122.829,71.335 121.491,69.997 121.162,69.997 ; C239_N.1@123.068,52.06 122.087,52.06 121.937,52.21 U39_N.5@121.292,52.21 ; C256_N.1@123.068,68.153 121.908,68.153 121.807,68.254 U44_N.5@121.162,68.254 ; C197_N.2@123.184,17.4 v1(121.927,17.4) 121.527,17 120.979,17 120.599,16.62 120.599,16.125 120.521,16.047 U29_N.8@120.25,16.047 U29_N.7@120.25,15.397 ; C198_N.2@123.27,15.354 123.227,15.397 v1(121.539,15.397) U29_N.7@120.25,15.397 ; v1(123.36,69.655) 124.456,69.655 C255_N.2@124.841,69.27 ; C196_N.1@123.495,11.497 123.508,11.485 123.508,10.776 v1(123.52,10.763) 123.52,10.025 R284_N.1@123.745,9.8 v1(122.822,9.8) 122.536,9.8 122.387,9.651 122.387,9.363 C191_N.1@122.262,9.238 122.22,9.197 121.662,9.197 ; C220_N.2@123.667,33.175 123.667,31.563 123.52,31.416 122.726,31.416 122.318,31.008 C222_N.1@122.318,30.394 122.284,30.359 120.534,30.359 U34_N.5@120.5,30.325 ; C219_N.1@123.77,27.75 123.993,27.527 124.283,27.527 124.467,27.344 v1(124.467,27.275) 124.467,26.48 R295_N.1@124.237,26.25 124.583,25.903 124.583,25.591 124.798,25.377 v1(124.798,25.315) ; C205_N.1@124.02,24.68 v1(124.802,24.68) ; C186_N.2@124.07,4.825 124.092,4.803 v1(125.066,4.803) ; C200_N.2@124.392,21.505 v1(125.442,21.505) ; C237_N.2@124.404,55 124.404,53.355 124.545,53.214 122.709,53.214 122.413,53.51 U39_N.7@121.292,53.51 ; C253_N.1@124.445,65.728 124.459,65.715 125.256,65.715 v1(125.27,65.701) ; C196_L2.1@124.497,98.005 124.485,97.992 123.776,97.992 v1(123.763,97.98) 123.025,97.98 R284_L2.1@122.8,97.755 v1(122.8,98.678) 122.8,98.964 122.651,99.113 122.363,99.113 C191_L2.1@122.238,99.238 122.197,99.28 122.197,99.838 ; C236_N.1@124.545,49.541 124.758,49.328 125.018,49.328 v1(125.467,48.879) 125.467,48.08 R305_N.1@125.316,47.929 125.066,47.679 C231_N.1@125.066,46.528 ; C248_N.1@124.891,62.675 v1(125.658,62.675) ; R322_N.1@125.12,64.185 125.135,64.2 v1(126.183,64.2) ; C231_N.1@125.316,46.528 v1(125.858,46.528) ; C224_N.2@125.345,43 v1(126.436,43) ; C243_N.2@125.345,59.573 125.347,59.575 126.209,59.575 126.358,59.724 v1(126.358,60.355) ; U29_L2.4@126.447,101.25 U29_L2.5@127.097,101.25 ; C199_L2.1@127.088,99.63 127.093,99.634 127.093,101.245 U29_L2.5@127.097,101.25 ; C198_L2.2@128.354,98.23 128.397,98.273 v1(128.397,99.961) U29_L2.7@128.397,101.25 ; C197_L2.2@130.4,98.316 v1(130.4,99.573) 130,99.973 130,100.521 129.62,100.901 129.125,100.901 129.047,100.979 129.047,101.25 U29_L2.7@128.397,101.25 ; v1(134.505,96.058) C200_L2.2@134.505,97.108 ; v1(137.68,96.698) C205_L2.1@137.68,97.48 ; v1(138.315,96.702) 138.377,96.702 138.591,96.917 138.903,96.917 R295_L2.1@139.25,97.263 139.48,97.033 v1(140.275,97.033) 140.344,97.033 140.527,97.217 140.527,97.507 C219_L2.1@140.75,97.73 ; U32_L2.4@138.315,101.05 138.315,100.723 138.488,100.55 v1(139.003,100.55) ; U34_L2.4@142.675,101 U34_L2.5@143.325,101 ; U34_L2.8@145.275,101 U34_L2.7@144.625,101 U34_L2.6@143.975,101 U34_L2.5@143.325,101 ; C220_L2.2@146.175,97.833 144.563,97.833 144.416,97.98 144.416,98.774 144.008,99.182 C222_L2.1@143.394,99.182 143.359,99.216 143.359,100.966 U34_L2.5@143.325,101 ; v1(156,95.064) C224_L2.2@156,96.155 ; v1(159.528,95.642) C231_L2.1@159.528,96.184 ; C231_L2.1@159.528,96.434 160.679,96.434 R305_L2.1@160.929,96.184 161.08,96.033 v1(161.879,96.033) 162.328,96.482 162.328,96.742 C236_L2.1@162.541,96.955 ; U37_L2.4@160.034,100.05 160.034,99.673 160.207,99.5 v1(160.733,99.5) ; U39_L2.4@164.56,100.208 U39_L2.5@165.21,100.208 ; C239_L2.1@165.06,98.432 165.06,99.413 165.21,99.563 U39_L2.5@165.21,100.208 ; U39_L2.8@167.16,100.208 U39_L2.7@166.51,100.208 ; C237_L2.2@168,97.096 166.355,97.096 166.214,96.955 166.214,98.791 166.51,99.087 U39_L2.7@166.51,100.208 ; C243_L2.2@172.573,96.155 172.575,96.153 172.575,95.291 172.724,95.142 v1(173.355,95.142) ; v1(175.675,95.842) C248_L2.1@175.675,96.609 ; U43_L2.4@176.383,100.226 176.383,99.675 176.556,99.502 v1(177.185,99.5) v1(177.185,99.5) ; R322_L2.1@177.185,96.38 177.2,96.365 v1(177.2,95.317) ; v1(178.701,96.23) 178.715,96.244 178.715,97.041 C253_L2.1@178.728,97.055 ; U44_L2.4@180.604,100.338 U44_L2.5@181.254,100.338 ; C256_L2.1@181.153,98.432 181.153,99.592 181.254,99.693 U44_L2.5@181.254,100.338 ; C255_L2.2@182.27,96.659 182.655,97.044 v1(182.655,98.14) ; U44_L2.8@183.204,99.967 U44_L2.8@183.204,100.338 184.162,100.338 184.462,100.038 184.462,98.709 C254_L2.2@184.5,98.671 ; U44_L2.8@183.228,99.884 183.098,100.015 182.632,100.015 182.554,100.093 U44_L2.7@182.554,100.338 U44_L2.6@181.904,100.338 U44_L2.5@181.254,100.338 ; v1(203.803,68.434) 203.803,69.408 C186_L3.2@203.825,69.43 ; v1(208.8,71.838) 208.197,71.838 ; v1(208.8,72.901) 208.304,72.901 208.197,73.008 208.197,71.838 ; C196_L3.1@210.497,70.005 210.485,69.992 209.776,69.992 v1(209.763,69.98) 209.025,69.98 R284_L3.1@208.8,69.755 v1(208.8,70.678) 208.8,70.964 208.651,71.113 208.363,71.113 C191_L3.1@208.238,71.238 208.197,71.28 208.197,71.838 ; U29_L3.4@212.447,73.25 U29_L3.5@213.097,73.25 ; C199_L3.1@213.088,71.63 213.093,71.634 213.093,73.245 U29_L3.5@213.097,73.25 ; C198_L3.2@214.354,70.23 214.397,70.273 v1(214.397,71.961) U29_L3.7@214.397,73.25 ; C197_L3.2@216.4,70.316 v1(216.4,71.573) 216,71.973 216,72.521 215.62,72.901 215.125,72.901 215.047,72.979 215.047,73.25 U29_L3.7@214.397,73.25 ; v1(220.505,68.058) C200_L3.2@220.505,69.108 ; v1(223.68,68.698) C205_L3.1@223.68,69.48 ; v1(224.315,68.702) 224.377,68.702 224.591,68.917 224.903,68.917 R295_L3.1@225.25,69.263 225.48,69.033 v1(226.275,69.033) 226.344,69.033 226.527,69.217 226.527,69.507 C219_L3.1@226.75,69.73 ; U32_L3.4@224.315,73.05 224.315,72.723 224.488,72.55 v1(225.003,72.55) ; U34_L3.4@228.675,73 U34_L3.5@229.325,73 ; U34_L3.8@231.275,73 U34_L3.7@230.625,73 U34_L3.6@229.975,73 U34_L3.5@229.325,73 ; C220_L3.2@232.175,69.833 230.563,69.833 230.416,69.98 230.416,70.774 230.008,71.182 C222_L3.1@229.394,71.182 229.359,71.216 229.359,72.966 U34_L3.5@229.325,73 ; v1(242,67.064) C224_L3.2@242,68.155 ; v1(245.528,67.642) C231_L3.1@245.528,68.184 ; C231_L3.1@245.528,68.434 246.679,68.434 R305_L3.1@246.929,68.184 247.08,68.033 v1(247.879,68.033) 248.328,68.482 248.328,68.742 C236_L3.1@248.541,68.955 ; U37_L3.4@246.034,72.05 246.034,71.673 246.207,71.5 v1(246.733,71.5) ; U39_L3.4@250.56,72.208 U39_L3.5@251.21,72.208 ; C239_L3.1@251.06,70.432 251.06,71.413 251.21,71.563 U39_L3.5@251.21,72.208 ; U39_L3.8@253.16,72.208 U39_L3.7@252.51,72.208 ; C237_L3.2@254,69.096 252.355,69.096 252.214,68.955 252.214,70.791 252.51,71.087 U39_L3.7@252.51,72.208 ; C243_L3.2@258.573,68.155 258.575,68.153 258.575,67.291 258.724,67.142 v1(259.355,67.142) ; v1(261.675,67.842) C248_L3.1@261.675,68.609 ; U43_L3.4@262.383,72.226 262.383,71.675 262.556,71.502 263.183,71.502 v1(263.185,71.5) ; R322_L3.1@263.185,68.38 263.2,68.365 v1(263.2,67.317) ; v1(264.701,68.23) 264.715,68.244 264.715,69.041 C253_L3.1@264.728,69.055 ; U44_L3.4@266.604,72.338 U44_L3.5@267.254,72.338 ; C256_L3.1@267.153,70.432 267.153,71.592 267.254,71.693 U44_L3.5@267.254,72.338 ; C255_L3.2@268.27,68.659 268.655,69.044 v1(268.655,70.14) ; 268.997,72.5 268.997,72.338 ; C254_L3.2@270.5,70.671 270.335,70.671 268.997,72.009 268.997,72.338 ; U29_L1.5@43.422,116.25 U29_L1.7@44.897,116.25 ; U39_L1.5@81.71,115.208 U39_L1.6@82.36,115.208 U39_L1.7@83.01,115.208 ; U44_L1.5@97.754,115.338 U44_L1.6@98.404,115.338 U44_L1.7@99.054,115.338 99.497,115.338 ; U29_N.5@120.25,14.097 U29_N.6@120.25,14.747 U29_N.7@120.25,15.397 ; U44_N.5@121.162,68.254 U44_N.6@121.162,68.904 U44_N.7@121.162,69.554 121.162,69.997 ; U39_N.5@121.292,52.21 U39_N.6@121.292,52.86 U39_N.7@121.292,53.51 ; U29_L2.5@127.097,101.25 U29_L2.7@128.397,101.25 ; U39_L2.5@165.21,100.208 U39_L2.6@165.86,100.208 U39_L2.7@166.51,100.208 ; U29_L3.5@213.097,73.25 U29_L3.7@214.397,73.25 ; U39_L3.5@251.21,72.208 U39_L3.6@251.86,72.208 U39_L3.7@252.51,72.208 ; U44_L3.5@267.254,72.338 U44_L3.6@267.904,72.338 U44_L3.7@268.554,72.338 268.997,72.338
  Top Layer w0.3: U2.9@94.6,246.2 v1(95.3,246.2) ; C34.2@97,243.4 v1(97,242.4) 97,241.7 R105.1@97.2,241.5 ; C30.2@98.8,238 C30.2@98.825,238 ; C78.2@99.2,247.3 v1(100.6,247.3) ; v1@99.43,238.605 v1(99.459,238.605) ; C78.2@99.7,246.5 v1(100.6,246.5) ; C79.2@100.5,243 C79.2@100.6,242.9 ; v1(101.4,241.9) C79.2@101.4,242.9 ; v1(103.9,247.6) C74.2@104.8,247.6 ; C40.2@104.5,230.4 C40.2@104.6,230.5 ; C74.2@104.9,247.6 105.206,247.906 105.206,248.306 105.715,248.815 105.715,249.4 105.915,249.6 U9.5@106,249.6 ; C70.1@110.4,246.2 v1(111.1,246.2) C71.2@112.1,246.2 ; v1(116.1,246.5) C67.2@116.1,247.5 116.3,247.7 116.3,248.3 116.6,248.6 117.024,248.6 117.2,248.776 U8.5@117.2,249.5 ; C63.1@121.3,246 v1(122.1,246) C64.2@123.1,246 ; v1(130,246.7) 130,247.4 C60.2@130.1,247.5 ; C60.2@130.113,247.587 130.45,247.925 130.45,248.45 131.022,249.022 131.022,250.072 U7.5@131.1,250.15 ; C56.1@135.3,246.3 135.321,246.321 v1(136.385,246.321) 137.079,246.321 C57.2@137.1,246.3 ; v1(188.8,203.3) 188.813,203.288 188.813,202.387 U5.9@188.9,202.3 ; R121.1@189.9,206.4 v1(189.9,207.3) ; C46.2@191.7,206.5 191.8,206.6 v1(191.8,207.3) ; C42.2@197.1,206 v1(197.1,207.1) ; Q1.7@289,206 289.8,206 C28.2@289.8,204 R97.1@289.8,202 ; Q1.4@289.88,206 C27.2@291.8,206
  Top Layer w0.35: U3.11@275.6,47.25 276.65,47.25 v1(276.7,47.2)
  Top Layer w0.4: C30.2@98.825,238 v1@99.43,238.605 ; C36.2@113.026,228.074 v1(113.733,228.074) ; R186.1@143.563,60.488 C117.2@143.563,61.612 ; C116.2@143.563,63.712 R185.1@143.563,64.712 ; R185.1@143.563,64.812 v1(143.563,65.512) ; v1(144.963,67.212) 144.967,67.217 145.858,67.217 R184.1@145.863,67.212 ; C115.2@145.849,66.126 C115.2@145.863,66.112 ; R184.1@145.863,67.112 145.863,66.236 C115.2@145.911,66.187 ; U16.7@146.861,60.737 U16.7@147.322,60.737 ; U16.7@147.054,60.712 148.183,60.712 148.471,61 v1(148.5,61) ; v1(148.963,66.612) C113.2@149.963,66.612 C113.2@150.163,66.612 ; C118.2@156.063,61.362 156.088,61.337 156.838,61.337 v1(156.863,61.312) ; R170.1@158.368,65.066 158.479,65.178 158.479,65.479 v1(158.5,65.5) ; C110.2@158.468,60.016 R171.1@158.468,61.266 ; C109.2@158.468,63.766 R170.1@158.468,65.016 ; v1(161.268,67.22) 161.289,67.2 161.835,67.2 C108.2@161.968,67.066 ; C108.2@162.068,67.066 R169.1@163.368,67.066 ; v1(162.268,59.566) 162.279,59.577 162.279,60.345 162.3,60.366 U15.7@162.368,60.366 ; v1(164.968,67.22) 164.989,67.2 165.21,67.2 165.668,66.741 165.668,66.566 C107.2@165.868,66.366 ; C142.1@168.207,26.044 v1@168.207,26.637 ; v1(169.027,27.003) C141.2@170.126,27.003 ; R172.1@171.968,59.766 171.968,60.966 C111.2@171.993,60.991 ; C112.2@171.968,63.516 R173.1@171.968,64.866 ; v1(177.9,5.8) R211.1@177.9,6.8 ; R82.1@181.5,43.5 181.6,43.6 v1(181.6,44.5) R81.1@181.6,45.5 ; C52.2@188,51.1 v1(188.8,51.1) ; C15.1@197.4,38.1 197.5,38 C15.1@197.5,37.9 v1(197.5,37) 197.54,36.96 197.54,35.94 C16.2@197.5,35.9 ; v1(198,57) C161.1@199.1,57 ; v1(199.1,58.6) 199.06,58.64 199.06,59.46 C160.1@199.1,59.5 ; v1(199.1,61.1) C159.1@199.1,61.8 ; J12.111@201.3,46 201.4,45.9 v1(201.4,44.2) ; v1(206.9,28.6) C123.2@207.7,28.6 ; v1(207,44.2) 206.975,44.225 206.975,45.775 J12.97@207,45.8 ; v1(207.7,24.3) C124.2@207.7,25.1 R193.1@207.7,26 ; C123.2@207.7,28.7 R192.1@207.7,29.6 ; v1(212.6,44.2) 212.575,44.225 212.575,45.775 J12.83@212.6,45.8 ; C114.2@212.9,23.7 212.991,23.791 213.691,23.791 v1(213.7,23.8) R189.1@214.4,23.8 C120.2@214.4,22.7 ; C39.2@214.7,53.4 v1(214.7,54.2) ; v1(215.7,29.3) 215.757,29.3 215.799,29.343 216.857,29.343 U17.7@216.866,29.352 ; v1(215.7,55) C33.2@216.5,55 ; v1(219.7,44.2) J12.65@219.7,45.8 ; v1(220.7,23.854) 220.708,23.862 220.708,24.361 R190.1@220.716,24.369 220.708,24.377 220.708,25.392 C121.2@220.7,25.4 ; C122.2@220.8,29.2 220.75,29.2 220.7,29.15 R191.1@220.7,28.2 220.75,28.2 221.16,27.79 221.16,27.64 v1(221.2,27.6) ; v1(222.845,25.401) 222.874,25.401 223.123,25.65 223.25,25.65 C130.2@223.3,25.7 ; C129.2@223.25,28.9 223.3,28.9 223.35,28.95 223.35,29.393 223.4,29.443 v1(223.4,29.5) ; C130.2@223.294,25.906 R203.1@223.294,26.83 ; v1@223.45,29.5 R202.1@223.45,30.15 R202.1@223.5,30.2 ; C125.2@228.3,25.1 v1(229.3,25.1) v1@229.357,25.1 ; v1(230.2,44.1) 230.175,44.125 230.175,45.875 J12.47@230.2,45.9 ; R199.1@230.683,24.472 229.985,24.472 v1@229.357,25.1 ; C126.2@230.8,25.5 229.757,25.5 v1@229.357,25.1 ; J12.46@231,42 230.975,42.025 230.975,43.175 v1(231,43.2) ; J12.38@234.2,42.1 234.175,42.125 234.175,43.175 v1(234.2,43.2) ; v1(235,44.1) 234.975,44.125 234.975,45.275 J12.35@235,45.3 ; R200.1@235.8,27.3 235.9,27.2 236.4,27.2 v1(236.8,26.8) 236.3,26.3 236.21,26.3 C127.2@235.9,26.3 ; C128.2@235.9,30.7 235.95,30.65 236,30.65 236.66,29.99 236.66,29.54 v1(236.7,29.5) R201.1@236.1,29.5 ; v1(237.4,44.1) 237.375,44.125 237.375,45.375 J12.29@237.4,45.4 ; C66.1@238.4,58 v1(239,58) ; C96.2@239.9,58 v1(240.7,58) ; J12.22@240.5,41.8 240.6,41.9 v1(240.6,43.2) ; v1(241.4,44.1) 241.375,44.125 241.375,45.475 J12.19@241.4,45.5 ; C50.1@242.2,58 v1(242.9,58) ; J12.16@243,42 v1(243,43.2) ; R23.2@244,55 244.1,55.1 v1(244.1,56) ; J12.10@245.4,42 245.375,42.025 245.375,43.175 v1(245.4,43.2) ; C31.1@246,55.1 v1(246.9,55.1) 247.7,55.1 C43.1@247.8,55 ; v1(246.1,44.1) J12.7@246.1,45.7 ; U23.10@281.99,31.76 v1@281.99,33.29 ; U23.6@287.06,32.5 v1@287.6,33.04 ; U23.4@289.55,31.8 v1@289.55,33.15
  Top Layer w0.5: U2.9@93.875,246.175 U2.9@94.4,246.175 ; U4.9@103.034,225.875 103.072,225.913 103.072,227.872 103.675,228.475 104.475,228.475 104.6,228.6 C40.2@104.6,230.5 ; v1(171.126,3.854) D5.2@171.126,5.334 ; v1(179.298,38.593) 179.299,38.594 180.194,38.594 C82.2@180.2,38.6 ; v1(267.189,44.407) 267.19,44.408 267.19,44.99 C47.1@267.4,45.2 ; C5.2@280.3,42.5 v1(281,42.5) ; C147.2@284.786,36.014 285.024,36.014 285.135,36.125 285.135,36.595 285.172,36.631 v1(285.172,36.634) 285.173,36.635 285.173,38.081 C6.2@285.4,38.308 ; C148.2@285.2,34.6 v1(285.2,35.15) C147.2@285.2,35.6 ; v1(289.152,36.347) C152.2@289.6,35.9 ; C27.2@291.9,206 292,206.1 293.3,206.1 295,207.8 C26.2@295,212.6
  other v1: 201,3 203,3 205,4.9 205,5.8 201,7.5 202.5,7.5 210.8,9 212.3,9 235.6,9.2 237.1,9.2 201,9.4 202.8,9.4 210.8,10.4 212.3,10.4 235.6,10.6 237.1,10.6 173.5,15 151.5,15.2 170.6,15.3 174.5,15.9 146.35,16.127 149.05,16.276 152.4,16.4 180.1,16.7 181.4,16.7 238,17 244,17 149.05,17.376 203,17.5 204.5,17.5 206,17.5 236,17.5 245,18 239.5,18.5 237.5,19 246,19 196.5,21 199,21 201.5,21 204,21 156.8,24.2 160.6,24.4 163.3,24.5 168.207,26.638 121.75,32 122.5,32 121.75,32.75 122.5,32.8 121.718,33.5 122.499,33.5 148,41.5 154,42.7 151.1,44.5 164.4,50.6 122.5,52.8 295,53.8 296.5,53.8 122.8,54.1 295,55.2 296.5,55.2 295,56.6 296.5,56.6 170,58 295,58 296.5,58 207.4,59.1 237.5,59.1 295,59.4 296.5,59.4 142.488,60.471 158.468,60.641 295,60.8 296.5,60.8 276.5,61 278,61 295,62.2 296.5,62.2 276.5,62.4 278,62.4 295,63.6 296.5,63.6 171.956,64.162 295,65 296.5,65 295,66.4 296.5,66.4 295,67.8 296.5,67.8 122.541,68.906 123.318,68.906 295,69.2 296.5,69.2 122.541,69.655 269.334,70.14 122.541,70.334 123.36,70.334 295,70.6 296.5,70.6 253.1,70.7 267.906,70.959 268.655,70.959 269.334,70.959 231,71 231.8,71 232.5,71.001 251.8,71 231,71.75 231.75,71.75 232.5,71.782 295,72 296.5,72 295,73.4 296.5,73.4 295,74.8 296.5,74.8 183.2,89.8 183.2,91.2 294.6,92.6 296.1,92.6 294.6,94 296.1,94 280,95.2 281.5,95.2 294.5,95.7 296,95.7 280,96.6 281.5,96.6 294.5,97.1 296,97.1 280,98 281.5,98 183.334,98.14 294.5,98.5 296,98.5 167.1,98.7 181.906,98.959 182.655,98.959 183.334,98.959 145,99 145.8,99 146.5,99.001 165.8,99 280,99.4 281.5,99.4 145,99.75 145.75,99.75 146.5,99.782 294.5,99.9 296,99.9 280,100.8 281.5,100.8 294.5,101.3 296,101.3 280,102.2 281.5,102.2 294.5,102.7 296,102.7 92.6,102.9 280,103.6 281.5,103.6 94.1,104 294.5,104.1 296,104.1 280,105 281.5,105 294.5,105.5 296,105.5 280,106.4 281.5,106.4 68.9,106.8 294.5,106.9 296,106.9 280,107.8 281.5,107.8 294.5,108.3 296,108.3 280,109.2 281.5,109.2 294.5,109.7 296,109.7 280,110.6 281.5,110.6 294.5,111.1 296,111.1 280,112 281.5,112 294.5,112.5 296,112.5 280,113.4 281.5,113.4 83.6,113.7 294.5,113.9 296,113.9 61.5,114 62.3,114 63,114.001 82.3,114 61.5,114.75 62.25,114.75 63,114.782 280,114.8 281.5,114.8 294.5,115.3 296,115.3 280,116.2 281.5,116.2 294.5,116.7 296,116.7 280,117.6 281.5,117.6 294.5,118.1 296,118.1 280,119 281.5,119 294.5,119.5 296,119.5 280,120.4 281.5,120.4 294.5,120.9 296,120.9 280,121.8 281.5,121.8 294.5,122.3 296,122.3 280,123.2 281.5,123.2 294.5,123.7 296,123.7 280,124.6 281.5,124.6 294.5,125.1 296,125.1 280,126 281.5,126 294.5,126.5 296,126.5 280,127.4 281.5,127.4 294.5,127.9 296,127.9 280,128.8 281.5,128.8 294.5,129.3 296,129.3 280,130.2 281.5,130.2 294.5,130.7 296,130.7 280,131.6 281.5,131.6 280,133 281.5,133 280,134.4 281.5,134.4 280,135.8 281.5,135.8 280,137.2 281.5,137.2 280,138.6 281.5,138.6 294.7,169.3 296.2,169.3 294.7,170.7 296.2,170.7 294.7,172.1 296.2,172.1 294.7,173.5 296.2,173.5 294.7,174.9 296.2,174.9 294.7,176.3 296.2,176.3 294.7,177.7 296.2,177.7 294.7,179.1 296.2,179.1 294.7,180.5 296.2,180.5 294.7,181.9 296.2,181.9 294.7,183.3 296.2,183.3 294.7,184.7 296.2,184.7 294.7,186.1 296.2,186.1 294.7,187.5 296.2,187.5 294.7,188.9 296.2,188.9 294.7,190.3 296.2,190.3 294.7,191.7 296.2,191.7 294.7,193.1 296.2,193.1 294.7,194.5 296.2,194.5 294.7,195.9 296.2,195.9 294.7,197.3 296.2,197.3 294.7,198.7 296.2,198.7 294.7,200.1 296.2,200.1 294.7,201.5 296.2,201.5 289.446,202.1 294.7,202.9 296.2,202.9 289.446,204 294.7,204.3 296.2,204.3 151.6,233.8 153.1,233.8 151.6,235.2 153.1,235.2 99.1,249.7 100.1,249.7 101.1,249.7
GND_HVN: C94.2
GND_ISO_CAN: C149.2 C150.2 C151.2 C156.2 C157.1 C158.1 FB18.2 J1.3 J1.5 J1.6 J1.10 J1.11 R93.1 U23.15 U23.16 U23.17 U24.2 U25.2 | length 25.8
  Top Layer w0.2: C156.2@265.85,18.25 265.873,18.25 266.073,18.45 v1(266.073,19.262) 266.073,20.073 U25.2@266.2,20.2 266.2,20.479 266.4,20.679 268.079,20.679 C157.1@268.2,20.8 268.55,21.15 271.6,21.15 272.2,20.55 U24.2@272.2,20.2 272.2,18.5 271.95,18.25 C158.1@271.85,18.25 ; R93.1@284,14.6 284.375,14.225 284.375,10.125 J1.10@285,9.5 ; C151.2@290.1,16.05 C151.2@290.25,16.2 ; C149.2@293.75,17.85 C149.2@293.75,17.95
  Top Layer w0.4: FB18.2@288.65,16.05 C151.2@290.1,16.05 ; C151.2@290.25,16.2 291.634,16.2 292.055,16.621 292.055,17.255 C150.2@292.25,17.45 293.35,17.45 C149.2@293.75,17.85
  Top Layer w0.55: U23.15@287.06,22.05 U23.16@288.33,22.05 U23.17@289.6,22.05
  other v1: 291.845,16.411 293.229,17.45 272.2,19 269.5,21.1 287.695,22.05 288.965,22.05
GND_S1_GaN_L1: C163_L1.1 C164_L1.2 C172_L1.1 C187_L1.2 C188_L1.1 C189_L1.1 C190_L1.2 C192_L1.2 C193_L1.1 C194_L1.2 C195_L1.2 C213_L1.2 C215_L1.1 C216_L1.1 D10_L1.1 L4_L1.1 R95_L1.2 R281_L1.1 R282_L1.1 R288_L1.1 R290_L1.1 R314_L1.2 TP15_L1.1 U26_L1.18 U26_L1.19 U26_L1.20 U26_L1.21 U26_L1.22 U26_L1.23 U26_L1.24 U26_L1.25 U26_L1.26 U26_L1.28 U26_L1.29 U26_L1.30 U26_L1.31 U26_L1.32 U26_L1.33 U26_L1.34 U26_L1.35 U26_L1.36 U26_L1.37 U26_L1.38 U26_L1.39 U27_L1.2 U27_L1.3 U27_L1.4 U27_L1.5 U27_L1.6 U27_L1.7 U27_L1.8 U27_L1.9 U27_L1.10 U27_L1.11 U27_L1.12 U27_L1.13 U27_L1.14 U27_L1.15 U28_L1.5 U29_L1.12 U29_L1.13 U29_L1.14 U29_L1.15 U29_L1.16 U30_L1.2 | length 56.7
  Top Layer w0.2: v1(41.5,128) 41.5,129.197 C194_L1.2@41.672,129.369 ; v1(44,136.5) TP15_L1.1@45.5,136.5 45.5,138.5 47.1,140.1 62.594,140.1 64.3,138.394 64.3,137.75 R314_L1.2@64.55,137.5
  Top Layer w0.254: v1(34.8,132.103) C187_L1.2@34.8,130.894 35.127,130.566 C189_L1.1@36.467,130.566 36.636,130.398 37.05,130.398 37.338,130.11 37.338,129.407 37.562,129.184 38.365,129.184 C195_L1.2@38.5,129.048 38.655,128.893 U28_L1.5@38.655,126.95 ; v1(35.05,132.94) 35.98,132.94 C192_L1.2@36.075,132.845 36.125,132.895 D10_L1.1@36.125,134.803 ; U29_L1.16@40.997,126.25 41.572,126.25 42.222,126.25 42.947,126.25 U29_L1.12@43.597,126.25 ; C194_L1.2@41.164,128.696 C194_L1.2@41.164,129.069 ; U29_L1.13@42.872,126.35 42.872,127.651 C193_L1.1@43.088,127.867 ; U30_L1.2@43.788,132.845 44.513,132.845 44.822,132.536 44.822,132.514 45.473,132.514 R290_L1.1@45.547,132.44 45.596,132.489 v1(46.5,132.489)
  Bottom Layer w0.2: v1(52.5,164.5) 53,164.5 ; R95_L1.2@53.5,164.2 55.2,164.2 C188_L1.1@55.5,164.5 55.533,164.467 55.533,163.967 55.8,163.7 57,163.7 57.15,163.55 58.5,163.55 C163_L1.1@58.55,163.5 ; C163_L1.1@59,163.55 59.15,163.4 v1(60.7,163.4) 60.7,164.125 L4_L1.1@60.8,164.225 ; C164_L1.2@62,167.484 62.5,166.984 v1(62.5,166.4)
  Bottom Layer w0.3: v1(41.5,128) 41.5,129.2 R288_L1.1@41.7,129.4
  other v1: 46.5,162 47.5,162 48.5,162 47,162.5 48,162.5 49,162.5 46.5,163 47.5,163 48.5,163 47,163.5 48,163.5 49,163.5 46.5,164 47.5,164 48.5,164 47,164.5 48,164.5 49,164.5 47.5,165 48.5,165 48,165.5 49,165.5 48.5,166 52.7,169.5 53.7,169.5 54.7,169.5 55.7,169.5 56.7,169.5 53.2,170 54.2,170 55.2,170 56.2,170 57.2,170 52.7,170.5 53.7,170.5 54.7,170.5 55.7,170.5 56.7,170.5 57.7,170.5 53.2,171 54.2,171 55.2,171 56.2,171 57.2,171 58.2,171 60.5,171
GND_S1_GaN_L2: C163_L2.1 C164_L2.2 C172_L2.1 C187_L2.2 C188_L2.1 C189_L2.1 C190_L2.2 C192_L2.2 C193_L2.1 C194_L2.2 C195_L2.2 C213_L2.2 C215_L2.1 C216_L2.1 D10_L2.1 L4_L2.1 R95_L2.2 R281_L2.1 R282_L2.1 R288_L2.1 R290_L2.1 R314_L2.2 TP15_L2.1 U26_L2.18 U26_L2.19 U26_L2.20 U26_L2.21 U26_L2.22 U26_L2.23 U26_L2.24 U26_L2.25 U26_L2.26 U26_L2.28 U26_L2.29 U26_L2.30 U26_L2.31 U26_L2.32 U26_L2.33 U26_L2.34 U26_L2.35 U26_L2.36 U26_L2.37 U26_L2.38 U26_L2.39 U27_L2.2 U27_L2.3 U27_L2.4 U27_L2.5 U27_L2.6 U27_L2.7 U27_L2.8 U27_L2.9 U27_L2.10 U27_L2.11 U27_L2.12 U27_L2.13 U27_L2.14 U27_L2.15 U28_L2.5 U29_L2.12 U29_L2.13 U29_L2.14 U29_L2.15 U29_L2.16 U30_L2.2 | length 59.8
  Top Layer w0.2: U29_L2.15@125.172,111.35 125.067,111.455 125.067,112.379 125,112.446 v1(125,113) 125,114.197 C194_L2.2@125.172,114.369 ; v1(127.5,121.5) TP15_L2.1@129,121.5 129,123.5 130.5,125 146.194,125 147.8,123.394 147.8,122.75 R314_L2.2@148.05,122.5
  Top Layer w0.254: v1(118.3,117.103) C187_L2.2@118.3,115.894 118.627,115.566 C189_L2.1@119.967,115.566 120.136,115.398 120.55,115.398 120.838,115.11 120.838,114.407 121.062,114.184 121.865,114.184 C195_L2.2@122,114.048 122.155,113.893 U28_L2.5@122.155,111.95 ; v1(118.55,117.94) 119.48,117.94 C192_L2.2@119.575,117.845 119.625,117.895 D10_L2.1@119.625,119.803 ; U29_L2.16@124.497,111.25 U29_L2.12@127.097,111.25 ; C194_L2.2@124.664,113.696 C194_L2.2@124.664,114.069 ; U29_L2.13@126.472,111.35 126.472,112.751 C193_L2.1@126.588,112.867 ; U30_L2.2@127.288,117.845 128.013,117.845 128.322,117.536 128.322,117.514 128.973,117.514 R290_L2.1@129.047,117.44 129.096,117.489 v1(130,117.489)
  Bottom Layer w0.2: v1(136,149.5) 136,149.444 136.244,149.2 R95_L2.2@137,149.2 ; C188_L2.1@139,149.5 139.033,149.467 139.033,148.967 139.3,148.7 C190_L2.2@140.5,148.7 140.65,148.55 142,148.55 142.05,148.5 143.1,148.5 143.825,149.225 L4_L2.1@144,149.225 ; L4_L2.1@144.3,149.225 144.574,149.499 v1@145.3,149.499 ; v1(145.5,149.5) 146.1,150.1 146.1,151.949 145.565,152.484 C164_L2.2@145.5,152.484
  Bottom Layer w0.3: v1(125,113) 125,114.2 R288_L2.1@125.2,114.4
  other v1: 130,147 131,147 132,147 130.5,147.5 131.5,147.5 132.5,147.5 130,148 131,148 132,148 130.5,148.5 131.5,148.5 132.5,148.5 130,149 131,149 132,149 130.5,149.5 131.5,149.5 132.5,149.5 131,150 132,150 131.5,150.5 132.5,150.5 132,151 136.2,154.5 137.2,154.5 138.2,154.5 139.2,154.5 140.2,154.5 136.7,155 137.7,155 138.7,155 139.7,155 140.7,155 136.2,155.5 137.2,155.5 138.2,155.5 139.2,155.5 140.2,155.5 141.2,155.5 136.7,156 137.7,156 138.7,156 139.7,156 140.7,156 141.7,156 144,156
GND_S1_GaN_L3: C163_L3.1 C164_L3.2 C172_L3.1 C187_L3.2 C188_L3.1 C189_L3.1 C190_L3.2 C192_L3.2 C193_L3.1 C194_L3.2 C195_L3.2 C213_L3.2 C215_L3.1 C216_L3.1 D10_L3.1 L4_L3.1 R95_L3.2 R281_L3.1 R282_L3.1 R288_L3.1 R290_L3.1 R314_L3.2 TP15_L3.1 U26_L3.18 U26_L3.19 U26_L3.20 U26_L3.21 U26_L3.22 U26_L3.23 U26_L3.24 U26_L3.25 U26_L3.26 U26_L3.28 U26_L3.29 U26_L3.30 U26_L3.31 U26_L3.32 U26_L3.33 U26_L3.34 U26_L3.35 U26_L3.36 U26_L3.37 U26_L3.38 U26_L3.39 U27_L3.2 U27_L3.3 U27_L3.4 U27_L3.5 U27_L3.6 U27_L3.7 U27_L3.8 U27_L3.9 U27_L3.10 U27_L3.11 U27_L3.12 U27_L3.13 U27_L3.14 U27_L3.15 U28_L3.5 U29_L3.12 U29_L3.13 U29_L3.14 U29_L3.15 U29_L3.16 U30_L3.2 | length 57.1
  Top Layer w0.2: C194_L3.2@211.172,86.369 211,86.197 v1(211,85) 211.083,85 211.216,84.867 C193_L3.1@212.588,84.867 ; v1(213.5,93.5) TP15_L3.1@215,93.5 215,95.5 216.5,97 232.194,97 233.8,95.394 233.8,94.75 R314_L3.2@234.05,94.5
  Top Layer w0.254: v1(204.3,89.103) C187_L3.2@204.3,87.894 204.627,87.566 C189_L3.1@205.967,87.566 206.136,87.398 206.55,87.398 206.838,87.11 206.838,86.407 207.062,86.184 207.865,86.184 C195_L3.2@208,86.048 208.155,85.893 U28_L3.5@208.155,83.95 ; v1(204.55,89.94) 205.48,89.94 C192_L3.2@205.575,89.845 205.625,89.895 D10_L3.1@205.625,91.803 ; U29_L3.16@210.497,83.25 U29_L3.12@213.097,83.25 ; C194_L3.2@210.664,85.696 C194_L3.2@210.664,86.069 ; U29_L3.13@212.472,83.35 212.472,84.751 C193_L3.1@212.588,84.867 ; U30_L3.2@213.288,89.845 214.013,89.845 214.322,89.536 214.322,89.514 214.973,89.514 R290_L3.1@215.047,89.44 215.096,89.489 v1(216,89.489)
  Bottom Layer w0.2: v1(222,121.5) 222,121.444 222.307,121.136 222.936,121.136 R95_L3.2@223,121.2 ; C188_L3.1@225,121.5 225.033,121.467 225.033,120.967 225.3,120.7 C190_L3.2@226.5,120.7 226.65,120.55 228,120.55 228.05,120.5 v1(230,120.5) 230,121.025 L4_L3.1@230.2,121.225 ; v1(231.5,123) C164_L3.2@231.5,124.484
  Bottom Layer w0.3: v1(211,85) 211,86.2 R288_L3.1@211.2,86.4
  other v1: 216,119 217,119 218,119 216.5,119.5 217.5,119.5 218.5,119.5 216,120 217,120 218,120 216.5,120.5 217.5,120.5 218.5,120.5 216,121 217,121 218,121 216.5,121.5 217.5,121.5 218.5,121.5 217,122 218,122 217.5,122.5 218.5,122.5 218,123 222.2,126.5 223.2,126.5 224.2,126.5 225.2,126.5 226.2,126.5 222.7,127 223.7,127 224.7,127 225.7,127 226.7,127 222.2,127.5 223.2,127.5 224.2,127.5 225.2,127.5 226.2,127.5 227.2,127.5 222.7,128 223.7,128 224.7,128 225.7,128 226.7,128 227.7,128 230,128
GND_S1_GaN_N: C163_N.1 C164_N.2 C172_N.1 C187_N.2 C188_N.1 C189_N.1 C190_N.2 C192_N.2 C193_N.1 C194_N.2 C195_N.2 C213_N.2 C215_N.1 C216_N.1 D10_N.1 L4_N.1 R95_N.2 R281_N.1 R282_N.1 R288_N.1 R290_N.1 R314_N.2 TP15_N.1 U26_N.18 U26_N.19 U26_N.20 U26_N.21 U26_N.22 U26_N.23 U26_N.24 U26_N.25 U26_N.26 U26_N.28 U26_N.29 U26_N.30 U26_N.31 U26_N.32 U26_N.33 U26_N.34 U26_N.35 U26_N.36 U26_N.37 U26_N.38 U26_N.39 U27_N.2 U27_N.3 U27_N.4 U27_N.5 U27_N.6 U27_N.7 U27_N.8 U27_N.9 U27_N.10 U27_N.11 U27_N.12 U27_N.13 U27_N.14 U27_N.15 U28_N.5 U29_N.12 U29_N.13 U29_N.14 U29_N.15 U29_N.16 U30_N.2 | length 57.1
  Top Layer w0.2: R314_N.2@99,35.05 98.75,34.8 98.106,34.8 96.5,33.194 96.5,17.5 98,16 TP15_N.1@100,16 v1(100,14.5) ; C194_N.2@107.131,12.172 107.303,12 109,12 109.1,12.1 110.203,12.1 U29_N.15@110.25,12.147
  Top Layer w0.254: D10_N.1@101.697,6.625 103.605,6.625 C192_N.2@103.655,6.575 103.56,6.48 v1(103.56,5.55) ; U30_N.2@103.655,14.288 103.655,15.013 103.964,15.322 103.986,15.322 103.986,15.973 R290_N.1@104.06,16.047 104.011,16.096 v1(104.011,17) ; v1(104.397,5.3) C187_N.2@105.606,5.3 105.934,5.627 C189_N.1@105.934,6.967 106.102,7.136 106.102,7.55 106.39,7.838 107.093,7.838 107.316,8.062 107.316,8.865 C195_N.2@107.452,9 107.607,9.155 U28_N.5@109.55,9.155 ; C194_N.2@107.431,11.664 C194_N.2@107.804,11.664 ; C193_N.1@108.633,13.588 108.756,13.465 108.887,13.465 108.905,13.447 U29_N.13@110.25,13.447 ; U29_N.16@110.25,11.497 U29_N.15@110.25,12.147 U29_N.14@110.25,12.797 U29_N.13@110.25,13.447 ; U29_N.12@110.25,14.097 U29_N.13@110.25,13.447
  Bottom Layer w0.2: C164_N.2@69.016,33 v1(70.5,33) ; v1(72,23) 72.5,23.5 R95_N.2@72.5,23.586 ; C188_N.1@72,26 72.033,26.033 72.533,26.033 72.8,26.3 C190_N.2@72.8,27.5 ; v1(72.3,32.7) 72.3,31.675 L4_N.1@72.375,31.6 ; C190_N.2@72.8,27.6 72.95,27.75 C163_N.1@72.95,29.5 72.9,29.55 72.9,30.417 73.2,30.717 v1(73.2,30.8)
  Bottom Layer w0.3: R288_N.1@107.1,12.2 107.3,12 v1(108.5,12)
  other v1: 72.5,17 73.5,17 74.5,17 72,17.5 73,17.5 74,17.5 71.5,18 72.5,18 73.5,18 74.5,18 71,18.5 72,18.5 73,18.5 74,18.5 70.5,19 71.5,19 72.5,19 73.5,19 74.5,19 71,19.5 72,19.5 73,19.5 74,19.5 66,23.2 67,23.2 65.5,23.7 66.5,23.7 66,24.2 67,24.2 65.5,24.7 66.5,24.7 66,25.2 67,25.2 65.5,25.7 66.5,25.7 66,26.2 67,26.2 65.5,26.7 66.5,26.7 66,27.2 67,27.2 65.5,27.7 66.5,27.7 66,28.2 65.5,28.7
GND_S2_GaN_L1: C165_L1.1 C166_L1.2 C201_L1.2 C202_L1.1 C203_L1.1 C204_L1.2 C208_L1.2 C210_L1.1 C211_L1.2 C212_L1.2 D11_L1.1 L1.1 L1.2 L1.3 L1.4 L18_L1.1 R229_L1.2 R299_L1.1 R301_L1.1 TP16_L1.1 U27_L1.18 U27_L1.19 U27_L1.20 U27_L1.21 U27_L1.22 U27_L1.23 U27_L1.24 U27_L1.25 U27_L1.26 U27_L1.28 U27_L1.29 U27_L1.30 U27_L1.31 U27_L1.32 U27_L1.33 U27_L1.34 U27_L1.35 U27_L1.36 U27_L1.37 U27_L1.38 U27_L1.39 U31_L1.2 U31_L1.3 U31_L1.4 U31_L1.5 U31_L1.6 U31_L1.7 U31_L1.8 U31_L1.9 U31_L1.10 U31_L1.11 U31_L1.12 U31_L1.13 U31_L1.14 U31_L1.15 U32_L1.5 U34_L1.12 U34_L1.13 U34_L1.14 U34_L1.15 U34_L1.16 U35_L1.2 | length 34
  Top Layer w0.2: v1(50.5,135) TP16_L1.1@50.5,136.5 ; v1(50.9,133.2) 51.356,133.2 C208_L1.2@51.755,132.8 ; C201_L1.2@51.005,131.166 51.315,131.476 v1(52.185,131.476)
  Top Layer w0.254: v1(52.185,131.476) 52.185,131.407 52.484,131.108 52.484,130.758 C203_L1.1@52.66,130.582 ; U32_L1.5@54.815,126.95 54.853,126.988 55.174,126.988 55.581,127.396 55.581,127.95 v1(55.63,127.998) 55.63,128.067 55.503,128.194 C212_L1.2@55.503,128.723 ; U34_L1.16@57.225,126 57.225,127.155 57.1,127.28 v1(57.1,127.349) 57.1,128.239 57.584,128.723 57.95,128.357 v1(57.95,127.349) ; U34_L1.15@57.875,126 57.913,126.038 57.913,127.312 v1(57.95,127.349) ; v1(58.775,132.116) U35_L1.2@59.65,132.116 59.681,132.085 60.62,132.085 61.244,132.709 R301_L1.1@61.244,132.734 61.288,132.69 v1(62.173,132.69) ; C210_L1.1@59.394,127.367 59.175,127.148 U34_L1.13@59.175,126 ; U34_L1.12@59.825,126 U34_L1.13@59.175,126 ; v1(57.95,127.349) 58.284,127.349 58.461,127.172 58.461,126.064 U34_L1.14@58.525,126 U34_L1.13@59.175,126
  Top Layer w0.3: C208_L1.2@51.755,132.8 51.755,134.032 D11_L1.1@52.455,134.732
  Bottom Layer w0.2: v1(55.9,144.3) 56.6,144.3 56.8,144.1 57.125,144.1 57.5,143.725 R229_L1.2@57.5,143.7 ; v1(59.5,143.5) C202_L1.1@59.5,144.3 ; C204_L1.2@61.35,143.55 C165_L1.1@63.1,143.55 63.166,143.484 63.933,143.484 64.417,143 v1(64.5,143) 65,143.5 L18_L1.1@65,144.23 ; v1(66.5,143) 67.1,143.6 C166_L1.2@67.1,144.357
  Bottom Layer w0.254: v1(57.1,127.349) 57.149,127.398 57.149,127.795 57.736,128.382 R299_L1.1@57.736,128.407
  other v1: 58.5,149.5 59.5,149.5 60.5,149.5 61.5,149.5 62.5,149.5 65.5,161 66.5,161 67.5,161 65,161.5 66,161.5 67,161.5 68,161.5 65.5,162 66.5,162 67.5,162 65,162.5 66,162.5 67,162.5 68,162.5 65.5,163 66.5,163 67.5,163 65,163.5 66,163.5 67,163.5 68,163.5 65.5,164 66.5,164 67.5,164 66,164.5 67,164.5 68,164.5 65.5,165 66.5,165 67.5,165 66,165.5 67,165.5 68,165.5 65.5,166 66.5,166 67.5,166 66,166.5 67,166.5 68,166.5 65.5,167 66.5,167 67.5,167 66,167.5 67,167.5 68,167.5
GND_S2_GaN_L2: C165_L2.1 C166_L2.2 C201_L2.2 C202_L2.1 C203_L2.1 C204_L2.2 C208_L2.2 C210_L2.1 C211_L2.2 C212_L2.2 D11_L2.1 L2.1 L2.2 L2.3 L2.4 L18_L2.1 R229_L2.2 R299_L2.1 R301_L2.1 TP16_L2.1 U27_L2.18 U27_L2.19 U27_L2.20 U27_L2.21 U27_L2.22 U27_L2.23 U27_L2.24 U27_L2.25 U27_L2.26 U27_L2.28 U27_L2.29 U27_L2.30 U27_L2.31 U27_L2.32 U27_L2.33 U27_L2.34 U27_L2.35 U27_L2.36 U27_L2.37 U27_L2.38 U27_L2.39 U31_L2.2 U31_L2.3 U31_L2.4 U31_L2.5 U31_L2.6 U31_L2.7 U31_L2.8 U31_L2.9 U31_L2.10 U31_L2.11 U31_L2.12 U31_L2.13 U31_L2.14 U31_L2.15 U32_L2.5 U34_L2.12 U34_L2.13 U34_L2.14 U34_L2.15 U34_L2.16 U35_L2.2 | length 36.3
  Top Layer w0.2: TP16_L2.1@134,121.5 v1(134,120) 134.5,119.5 135.723,119.5 135.8,119.577 D11_L2.1@135.955,119.732 ; C208_L2.2@135.255,117.8 134.955,117.5 134.617,117.5 134.5,117.383 134.5,117 134.505,116.995 C201_L2.2@134.505,115.966 135.301,115.966 135.627,115.64 136.102,115.64 C203_L2.1@136.16,115.582
  Top Layer w0.254: U32_L2.5@138.315,111.95 138.353,111.988 138.674,111.988 139.081,112.396 139.081,112.95 v1(139.13,112.998) 139.13,113.067 139.003,113.194 C212_L2.2@139.003,113.723 ; U34_L2.16@140.725,111 140.725,112.155 140.6,112.28 v1(140.6,112.349) 140.6,113.239 141.084,113.723 141.45,113.357 v1(141.45,112.349) ; U34_L2.15@141.375,111 141.413,111.038 141.413,112.312 v1(141.45,112.349) ; v1(142.275,117.116) U35_L2.2@143.15,117.116 143.181,117.085 144.12,117.085 144.744,117.709 R301_L2.1@144.744,117.734 144.788,117.69 v1(145.673,117.69) ; C210_L2.1@142.894,112.367 142.675,112.148 U34_L2.13@142.675,111 ; U34_L2.12@143.325,111 U34_L2.13@142.675,111 ; v1(141.45,112.349) 141.784,112.349 141.961,112.172 141.961,111.064 U34_L2.14@142.025,111 U34_L2.13@142.675,111
  Top Layer w0.3: C208_L2.2@135.255,117.8 135.255,118.05 135.8,118.595 D11_L2.1@135.8,119.577 ; D11_L2.1@135.8,119.732 D11_L2.1@135.8,119.8
  Bottom Layer w0.2: v1(140.8,127.7) 141,127.9 R229_L2.2@141,128.7 ; v1(143,128.6) C202_L2.1@143,129.3 ; C204_L2.2@144.5,128.7 144.65,128.55 C165_L2.1@146.3,128.55 146.501,128.751 147.251,128.751 147.5,129 147.975,129 L18_L2.1@148,129.025 ; v1(148,128) L18_L2.1@148,129.025 ; L18_L2.1@148,129.225 L18_L2.1@148,129.025 ; L18_L2.1@148.2,129.225 L18_L2.1@148,129.025 ; v1(150,128) C166_L2.2@150,129.484
  Bottom Layer w0.254: v1(140.6,112.349) 140.649,112.398 140.649,112.795 141.236,113.382 R299_L2.1@141.236,113.407
  other v1: 142,134.5 143,134.5 144,134.5 145,134.5 146,134.5 149,146 150,146 151,146 148.5,146.5 149.5,146.5 150.5,146.5 151.5,146.5 149,147 150,147 151,147 148.5,147.5 149.5,147.5 150.5,147.5 151.5,147.5 149,148 150,148 151,148 148.5,148.5 149.5,148.5 150.5,148.5 151.5,148.5 149,149 150,149 151,149 149.5,149.5 150.5,149.5 151.5,149.5 149,150 150,150 151,150 149.5,150.5 150.5,150.5 151.5,150.5 149,151 150,151 151,151 149.5,151.5 150.5,151.5 151.5,151.5 149,152 150,152 151,152 149.5,152.5 150.5,152.5 151.5,152.5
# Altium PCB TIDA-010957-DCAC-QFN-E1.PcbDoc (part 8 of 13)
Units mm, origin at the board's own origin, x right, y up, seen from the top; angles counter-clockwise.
Board outline 300 x 300 mm, 4 copper layers (Top Layer, Layer 1, Layer 2, Bottom Layer), stack 1.787 mm thick; 1286 components, 677 nets, 4169 pads, 3428 vias.

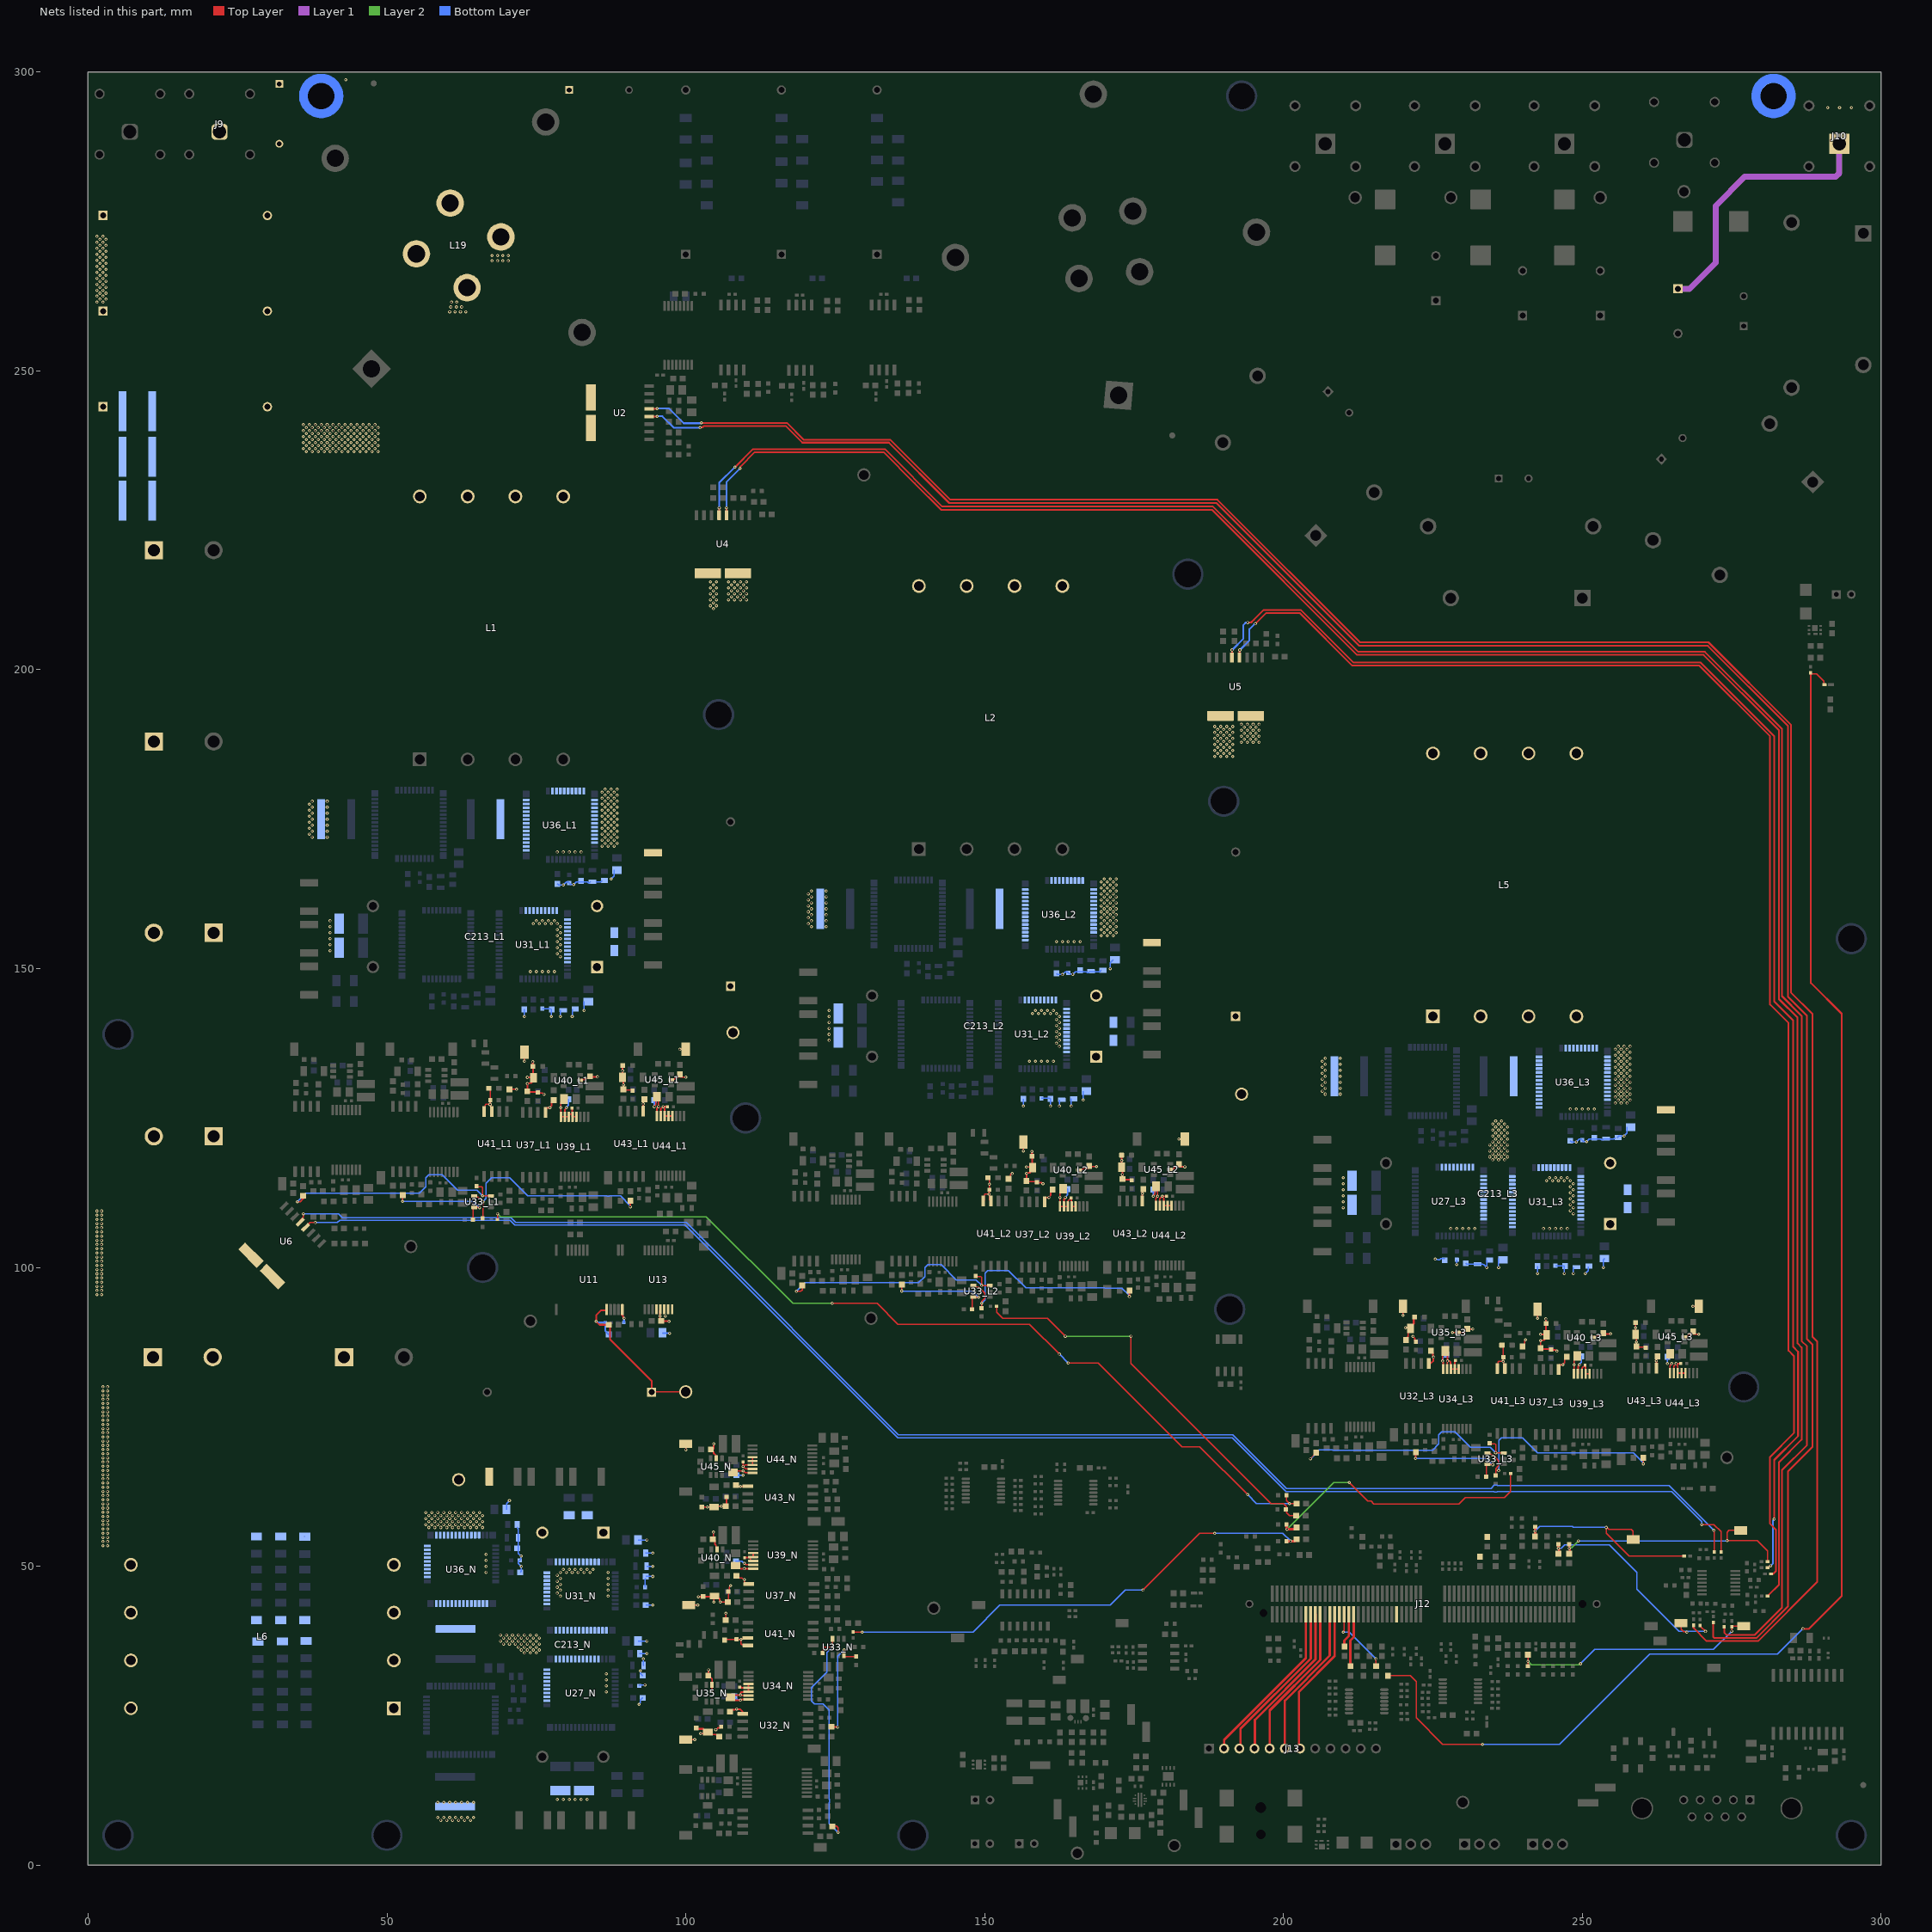
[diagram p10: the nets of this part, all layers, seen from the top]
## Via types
v1: diameter 0.508, hole 0.254, Top Layer to Bottom Layer, tented both sides, 3428 vias

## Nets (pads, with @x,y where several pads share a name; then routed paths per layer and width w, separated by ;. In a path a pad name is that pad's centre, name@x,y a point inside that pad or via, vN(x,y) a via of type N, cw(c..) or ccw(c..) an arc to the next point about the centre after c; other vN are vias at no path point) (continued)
GND_S2_GaN_L3: C165_L3.1 C166_L3.2 C201_L3.2 C202_L3.1 C203_L3.1 C204_L3.2 C208_L3.2 C210_L3.1 C211_L3.2 C212_L3.2 D11_L3.1 L5.1 L5.2 L5.3 L5.4 L18_L3.1 R229_L3.2 R299_L3.1 R301_L3.1 TP16_L3.1 U27_L3.18 U27_L3.19 U27_L3.20 U27_L3.21 U27_L3.22 U27_L3.23 U27_L3.24 U27_L3.25 U27_L3.26 U27_L3.28 U27_L3.29 U27_L3.30 U27_L3.31 U27_L3.32 U27_L3.33 U27_L3.34 U27_L3.35 U27_L3.36 U27_L3.37 U27_L3.38 U27_L3.39 U31_L3.2 U31_L3.3 U31_L3.4 U31_L3.5 U31_L3.6 U31_L3.7 U31_L3.8 U31_L3.9 U31_L3.10 U31_L3.11 U31_L3.12 U31_L3.13 U31_L3.14 U31_L3.15 U32_L3.5 U34_L3.12 U34_L3.13 U34_L3.14 U34_L3.15 U34_L3.16 U35_L3.2 | length 35.2
  Top Layer w0.2: v1(220,92) TP16_L3.1@220,93.5 ; v1(220.4,89.9) 221.156,89.9 C208_L3.2@221.255,89.8
  Top Layer w0.254: C201_L3.2@220.505,87.466 220.57,87.531 220.57,88.199 220.847,88.476 220.847,89.393 C208_L3.2@221.255,89.8 ; v1(221.685,88.476) 221.685,88.407 221.984,88.108 221.984,87.758 C203_L3.1@222.16,87.582 ; U32_L3.5@224.315,83.95 224.353,83.988 224.674,83.988 225.081,84.396 225.081,84.95 v1(225.13,84.998) 225.13,85.067 225.003,85.194 C212_L3.2@225.003,85.723 ; U34_L3.16@226.725,83 226.725,84.155 226.6,84.28 v1(226.6,84.349) 226.6,85.239 227.084,85.723 227.45,85.357 v1(227.45,84.349) ; U34_L3.15@227.375,83 227.413,83.038 227.413,84.312 v1(227.45,84.349) ; v1(228.275,89.116) U35_L3.2@229.15,89.116 229.181,89.085 230.12,89.085 230.744,89.709 R301_L3.1@230.744,89.734 230.788,89.69 v1(231.673,89.69) ; C210_L3.1@228.894,84.367 228.675,84.148 U34_L3.13@228.675,83 ; U34_L3.12@229.325,83 U34_L3.13@228.675,83 ; v1(227.45,84.349) 227.784,84.349 227.961,84.172 227.961,83.064 U34_L3.14@228.025,83 U34_L3.13@228.675,83
  Top Layer w0.3: C208_L3.2@221.255,89.8 221.255,90.05 221.8,90.595 D11_L3.1@221.8,91.8
  Bottom Layer w0.2: v1(225.4,101.4) 225.459,101.341 225.859,101.341 225.917,101.283 226.083,101.283 226.3,101.5 226.883,101.5 R229_L3.2@227,101.383 ; v1(229,100.5) C202_L3.1@229,101.3 ; C204_L3.2@230.5,100.7 230.65,100.55 C165_L3.1@232.5,100.55 233.35,100.55 233.4,100.5 233.5,100.5 v1(234,100) L18_L3.1@234,101.225 ; v1(236,100) C166_L3.2@236,101.484
  Bottom Layer w0.254: v1(226.6,84.349) 226.649,84.398 226.649,84.795 227.236,85.382 R299_L3.1@227.236,85.407
  other v1: 228,106.5 229,106.5 230,106.5 231,106.5 232,106.5 235,118 236,118 237,118 234.5,118.5 235.5,118.5 236.5,118.5 237.5,118.5 235,119 236,119 237,119 234.5,119.5 235.5,119.5 236.5,119.5 237.5,119.5 235,120 236,120 237,120 234.5,120.5 235.5,120.5 236.5,120.5 237.5,120.5 235,121 236,121 237,121 235.5,121.5 236.5,121.5 237.5,121.5 235,122 236,122 237,122 235.5,122.5 236.5,122.5 237.5,122.5 235,123 236,123 237,123 235.5,123.5 236.5,123.5 237.5,123.5 235,124 236,124 237,124 235.5,124.5 236.5,124.5
GND_S2_GaN_N: C165_N.1 C166_N.2 C201_N.2 C202_N.1 C203_N.1 C204_N.2 C208_N.2 C210_N.1 C211_N.2 C212_N.2 D11_N.1 L6.1 L6.2 L6.3 L6.4 L18_N.1 R229_N.2 R299_N.1 R301_N.1 TP16_N.1 U27_N.18 U27_N.19 U27_N.20 U27_N.21 U27_N.22 U27_N.23 U27_N.24 U27_N.25 U27_N.26 U27_N.28 U27_N.29 U27_N.30 U27_N.31 U27_N.32 U27_N.33 U27_N.34 U27_N.35 U27_N.36 U27_N.37 U27_N.38 U27_N.39 U31_N.2 U31_N.3 U31_N.4 U31_N.5 U31_N.6 U31_N.7 U31_N.8 U31_N.9 U31_N.10 U31_N.11 U31_N.12 U31_N.13 U31_N.14 U31_N.15 U32_N.5 U34_N.12 U34_N.13 U34_N.14 U34_N.15 U34_N.16 U35_N.2 | length 33.7
  Top Layer w0.2: TP16_N.1@100,21 v1(101.5,21) ; v1(102.5,22) 103.444,22 C208_N.2@103.7,22.255
  Top Layer w0.254: C208_N.2@103.7,22.255 104.078,21.876 104.995,21.876 105.024,21.847 105.024,21.836 105.29,21.57 C201_N.2@105.969,21.57 ; v1(103.81,32.673) 103.81,31.788 R301_N.1@103.766,31.744 103.791,31.744 104.415,31.12 104.415,30.181 U35_N.2@104.384,30.15 v1(104.384,29.275) ; v1(105.024,22.685) 105.093,22.685 105.392,22.984 105.742,22.984 C203_N.1@105.918,23.16 ; C212_N.2@107.777,26.003 108.306,26.003 108.433,26.13 v1(108.502,26.13) 108.55,26.081 109.104,26.081 109.512,25.674 109.512,25.353 U32_N.5@109.55,25.315 ; C210_N.1@109.133,29.894 109.352,29.675 U34_N.13@110.5,29.675 ; U34_N.16@110.5,27.725 109.345,27.725 109.22,27.6 v1(109.151,27.6) 108.261,27.6 107.777,28.084 108.143,28.45 v1(109.151,28.45) ; U34_N.15@110.5,28.375 110.462,28.413 109.188,28.413 v1(109.151,28.45) ; U34_N.12@110.5,30.325 U34_N.13@110.5,29.675 ; v1(109.151,28.45) 109.151,28.784 109.328,28.961 110.436,28.961 U34_N.14@110.5,29.025 U34_N.13@110.5,29.675
  Top Layer w0.3: D11_N.1@101.7,22.8 102.905,22.8 103.45,22.255 C208_N.2@103.7,22.255
  Bottom Layer w0.2: C166_N.2@92.016,37.5 v1(93.5,37.5) ; v1(92.2,26.9) 92.2,26.983 92.4,27.183 92.4,27.625 92.775,28 R229_N.2@92.8,28 ; C202_N.1@92.2,30 92.359,30.159 v1(93.159,30.159) v1@93.2,30.2 ; L18_N.1@92.275,35.4 v1(93.5,35.4) ; v1(92.4,32.5) 92.4,32.075 92.775,31.7 C204_N.2@92.8,31.7 ; v1(92.9,34.5) 92.9,33.45 C165_N.1@92.95,33.4
  Bottom Layer w0.254: R299_N.1@108.093,28.236 108.118,28.236 108.705,27.649 109.102,27.649 v1(109.151,27.6)
  other v1: 86.7,29 86.7,30 86.7,31 86.7,32 73,35.5 74,35.5 75,35.5 72.5,36 73.5,36 74.5,36 75.5,36 72,36.5 73,36.5 74,36.5 75,36.5 69.5,37 70.5,37 71.5,37 72.5,37 73.5,37 74.5,37 75.5,37 69,37.5 70,37.5 71,37.5 72,37.5 73,37.5 74,37.5 75,37.5 69.5,38 70.5,38 71.5,38 72.5,38 73.5,38 74.5,38 75.5,38 69,38.5 70,38.5 71,38.5 72,38.5 73,38.5 74,38.5 75,38.5
GND_S3_GaN_L1: C167_L1.2 C168_L1.2 C169_L1.1 C172_L1.2 C213_L1.1 C215_L1.2 C216_L1.2 C225_L1.2 C226_L1.1 C227_L1.1 C232_L1.2 C233_L1.1 C234_L1.2 C235_L1.2 C241_L1.2 C242_L1.1 D12_L1.1 L20_L1.1 R230_L1.2 R309_L1.1 R311_L1.1 R315_L1.1 R319_L1.2 R320_L1.2 TP18_L1.1 U31_L1.18 U31_L1.19 U31_L1.20 U31_L1.21 U31_L1.22 U31_L1.23 U31_L1.24 U31_L1.25 U31_L1.26 U31_L1.28 U31_L1.29 U31_L1.30 U31_L1.31 U31_L1.32 U31_L1.33 U31_L1.34 U31_L1.35 U31_L1.36 U31_L1.37 U31_L1.38 U31_L1.39 U36_L1.2 U36_L1.3 U36_L1.4 U36_L1.5 U36_L1.6 U36_L1.7 U36_L1.8 U36_L1.9 U36_L1.10 U36_L1.11 U36_L1.12 U36_L1.13 U36_L1.14 U36_L1.15 U37_L1.5 U39_L1.12 U39_L1.13 U39_L1.14 U39_L1.15 U39_L1.16 U40_L1.2 U41_L1.3 U41_L1.4 | length 42.4
  Top Layer w0.2: U41_L1.4@66.264,126.108 66.409,126.253 66.409,127.158 66.526,127.275 v1(67.264,127.275) 67.264,127.192 67.334,127.121 67.334,126.308 U41_L1.3@67.534,126.108 ; R315_L1.1@67.15,130 67.274,129.877 67.274,127.974 C242_L1.1@67.264,127.964 ; C241_L1.2@70.5,129.8 v1(71.7,129.8) ; v1(73,134.5) TP18_L1.1@73,136 ; U39_L1.16@79.11,125.208 U39_L1.15@79.76,125.208 U39_L1.14@80.41,125.208
  Top Layer w0.254: v1(67.264,127.275) C242_L1.1@67.264,127.964 ; U41_L1.3@67.534,126.108 U41_L1.3@67.57,126.145 ; v1(73.508,131.807) C232_L1.2@74.4,131.807 ; C232_L1.2@74.529,131.508 74.529,131.258 74.106,130.835 73.856,130.835 73.815,130.794 73.556,130.794 v1(73.508,130.745) C225_L1.2@73.508,129.466 73.608,129.366 75.264,129.366 75.435,129.195 75.995,129.195 76.192,128.998 v1(76.261,128.998) ; U37_L1.5@76.534,125.95 76.534,126.526 76.707,126.699 77.233,126.699 v1(77.261,126.726) 77.261,126.795 77.556,127.09 77.556,127.675 C235_L1.2@77.904,128.023 ; U39_L1.16@79.11,125.208 v1(79.11,126.723) 79.11,127.358 79.134,127.382 79.134,127.674 C234_L1.2@79.642,128.182 ; U39_L1.15@79.76,125.208 79.793,125.241 79.793,126.439 80.008,126.654 v1(80.008,126.723) ; U39_L1.14@80.41,125.208 80.41,125.567 80.488,125.645 80.847,125.645 U39_L1.13@80.958,125.756 ; C233_L1.1@80.958,126.657 81.016,126.599 81.016,125.253 U39_L1.13@81.06,125.208 U39_L1.12@81.71,125.208 ; U40_L1.2@82.333,131.283 82.506,131.456 83.004,131.456 83.16,131.611 83.83,131.611 84.101,131.883 v1(85.225,131.883)
  Top Layer w0.3: C232_L1.2@74.4,132 74.439,132.039 D12_L1.1@74.439,133.624 ; v1(74.4,134.4) 74.419,134.381 D12_L1.1@74.419,133.624
  Bottom Layer w0.2: v1(73,142) R230_L1.2@73,143.2 ; C226_L1.1@76,143.3 77.4,143.3 77.5,143.2 v1(77.5,142) ; v1(79,142) C169_L1.1@79,143.05 ; v1(81,142) L20_L1.1@81,143.225 ; v1(83,143) C167_L1.2@83,144.484
  Bottom Layer w0.254: v1(80.008,126.723) 80.008,126.792 80.36,127.144 R309_L1.1@80.36,128.107
  other v1: 74,149.5 75,149.5 76,149.5 77,149.5 78,149.5 79,152 78.5,152.5 40.5,153 79,153 78.5,153.5 40.5,154 79,154 78.5,154.5 40.5,155 79,155 78.5,155.5 40.5,156 79,156 78.5,156.5 40.5,157 79,157 74.5,157.5 75.5,157.5 76.5,157.5 77.5,157.5 78.5,157.5 40.5,158 75,158 76,158 77,158 78,158
GND_S3_GaN_L2: C167_L2.2 C168_L2.2 C169_L2.1 C172_L2.2 C213_L2.1 C215_L2.2 C216_L2.2 C225_L2.2 C226_L2.1 C227_L2.1 C232_L2.2 C233_L2.1 C234_L2.2 C235_L2.2 C241_L2.2 C242_L2.1 D12_L2.1 L20_L2.1 R230_L2.2 R309_L2.1 R311_L2.1 R315_L2.1 R319_L2.2 R320_L2.2 TP18_L2.1 U31_L2.18 U31_L2.19 U31_L2.20 U31_L2.21 U31_L2.22 U31_L2.23 U31_L2.24 U31_L2.25 U31_L2.26 U31_L2.28 U31_L2.29 U31_L2.30 U31_L2.31 U31_L2.32 U31_L2.33 U31_L2.34 U31_L2.35 U31_L2.36 U31_L2.37 U31_L2.38 U31_L2.39 U36_L2.2 U36_L2.3 U36_L2.4 U36_L2.5 U36_L2.6 U36_L2.7 U36_L2.8 U36_L2.9 U36_L2.10 U36_L2.11 U36_L2.12 U36_L2.13 U36_L2.14 U36_L2.15 U37_L2.5 U39_L2.12 U39_L2.13 U39_L2.14 U39_L2.15 U39_L2.16 U40_L2.2 U41_L2.3 U41_L2.4 | length 43.1
  Top Layer w0.2: U41_L2.4@149.764,111.108 149.909,111.253 149.909,112.158 150.026,112.275 v1(150.764,112.275) 150.764,112.192 150.834,112.121 150.834,111.308 U41_L2.3@151.034,111.108 ; R315_L2.1@150.65,115 150.774,114.877 150.774,112.974 C242_L2.1@150.764,112.964 ; C241_L2.2@154,114.8 154.317,115.117 154.317,115.5 154.517,115.7 v1(154.6,115.7) ; v1(156.5,119.5) TP18_L2.1@156.5,121 ; U39_L2.16@162.61,110.208 U39_L2.15@163.26,110.208 U39_L2.14@163.91,110.208
  Top Layer w0.254: v1(150.764,112.275) C242_L2.1@150.764,112.964 ; U41_L2.3@151.034,111.108 U41_L2.3@151.07,111.145 ; v1(157.008,116.807) C232_L2.2@157.9,116.807 ; C232_L2.2@158.029,116.508 158.029,116.258 157.606,115.835 157.356,115.835 157.315,115.794 157.056,115.794 v1(157.008,115.745) C225_L2.2@157.008,114.466 157.108,114.366 158.764,114.366 158.935,114.195 159.495,114.195 159.692,113.998 v1(159.761,113.998) ; U37_L2.5@160.034,110.95 160.034,111.526 160.207,111.699 160.733,111.699 v1(160.761,111.726) 160.761,111.795 161.056,112.09 161.056,112.675 C235_L2.2@161.404,113.023 ; U39_L2.16@162.61,110.208 v1(162.61,111.723) 162.61,112.358 162.634,112.382 162.634,112.674 C234_L2.2@163.142,113.182 ; U39_L2.15@163.26,110.208 163.293,110.241 163.293,111.439 163.508,111.654 v1(163.508,111.723) ; U39_L2.14@163.91,110.208 163.974,110.272 163.974,111.148 164.008,111.182 164.008,111.207 C233_L2.1@164.458,111.657 164.516,111.599 164.516,110.253 U39_L2.13@164.56,110.208 U39_L2.12@165.21,110.208 ; U40_L2.2@165.833,116.283 166.006,116.456 166.504,116.456 166.66,116.611 167.33,116.611 167.601,116.883 v1(168.725,116.883)
  Top Layer w0.3: C232_L2.2@157.9,117 157.939,117.039 D12_L2.1@157.939,118.624 ; v1(157.9,119.4) 157.919,119.381 D12_L2.1@157.919,118.624
  Bottom Layer w0.2: v1(156.5,127) R230_L2.2@156.5,128.2 ; C226_L2.1@159.5,128.3 160.9,128.3 C168_L2.2@161,128.2 v1(161,127) ; v1(162.5,127) C169_L2.1@162.5,128.05 ; v1(164.5,127) L20_L2.1@164.5,128.225 ; v1(166.5,128) C167_L2.2@166.5,129.484
  Bottom Layer w0.254: v1(163.508,111.723) 163.508,111.792 163.86,112.144 R309_L2.1@163.86,113.107
  other v1: 150.774,113.925 157.5,134.5 158.5,134.5 159.5,134.5 160.5,134.5 161.5,134.5 162.5,137 162,137.5 124,138 162.5,138 162,138.5 124,139 162.5,139 162,139.5 124,140 162.5,140 162,140.5 124,141 162.5,141 162,141.5 124,142 162.5,142 158,142.5 159,142.5 160,142.5 161,142.5 162,142.5 124,143 158.5,143 159.5,143 160.5,143 161.5,143
GND_S3_GaN_L3: C167_L3.2 C168_L3.2 C169_L3.1 C172_L3.2 C213_L3.1 C215_L3.2 C216_L3.2 C225_L3.2 C226_L3.1 C227_L3.1 C232_L3.2 C233_L3.1 C234_L3.2 C235_L3.2 C241_L3.2 C242_L3.1 D12_L3.1 L20_L3.1 R230_L3.2 R309_L3.1 R311_L3.1 R315_L3.1 R319_L3.2 R320_L3.2 TP18_L3.1 U31_L3.18 U31_L3.19 U31_L3.20 U31_L3.21 U31_L3.22 U31_L3.23 U31_L3.24 U31_L3.25 U31_L3.26 U31_L3.28 U31_L3.29 U31_L3.30 U31_L3.31 U31_L3.32 U31_L3.33 U31_L3.34 U31_L3.35 U31_L3.36 U31_L3.37 U31_L3.38 U31_L3.39 U36_L3.2 U36_L3.3 U36_L3.4 U36_L3.5 U36_L3.6 U36_L3.7 U36_L3.8 U36_L3.9 U36_L3.10 U36_L3.11 U36_L3.12 U36_L3.13 U36_L3.14 U36_L3.15 U37_L3.5 U39_L3.12 U39_L3.13 U39_L3.14 U39_L3.15 U39_L3.16 U40_L3.2 U41_L3.3 U41_L3.4 | length 42.1
  Top Layer w0.2: U41_L3.4@235.764,83.108 235.909,83.253 235.909,84.158 236.026,84.275 v1(236.764,84.275) 236.764,84.192 236.834,84.121 236.834,83.308 U41_L3.3@237.034,83.108 ; R315_L3.1@236.65,87 236.774,86.877 236.774,84.974 C242_L3.1@236.764,84.964 ; C241_L3.2@240,86.8 240.375,87.175 240.375,87.692 240.5,87.817 v1(240.5,87.9) ; v1(242.5,91.5) TP18_L3.1@242.5,93
  Top Layer w0.254: v1(236.764,84.275) C242_L3.1@236.764,84.964 ; U41_L3.3@237.034,83.108 U41_L3.3@237.07,83.145 ; v1(243.008,88.807) C232_L3.2@243.9,88.807 ; C232_L3.2@244.029,88.508 244.029,88.258 243.606,87.835 243.356,87.835 243.315,87.794 243.056,87.794 v1(243.008,87.745) C225_L3.2@243.008,86.466 243.108,86.366 244.764,86.366 244.935,86.195 245.495,86.195 245.692,85.998 v1(245.761,85.998) ; U37_L3.5@246.034,82.95 246.034,83.526 246.207,83.699 246.733,83.699 v1(246.761,83.726) 246.761,83.795 247.056,84.09 247.056,84.675 C235_L3.2@247.404,85.023 ; U39_L3.16@248.61,82.208 v1(248.61,83.723) 248.61,84.358 248.634,84.382 248.634,84.674 C234_L3.2@249.142,85.182 ; U39_L3.15@249.26,82.208 249.293,82.241 249.293,83.439 249.508,83.654 v1(249.508,83.723) ; U39_L3.14@249.91,82.208 249.974,82.272 249.974,83.148 250.008,83.182 250.008,83.207 C233_L3.1@250.458,83.657 250.516,83.599 250.516,82.253 U39_L3.13@250.56,82.208 U39_L3.12@251.21,82.208 ; U40_L3.2@251.833,88.283 252.006,88.456 252.504,88.456 252.66,88.611 253.33,88.611 253.601,88.883 v1(254.725,88.883)
  Top Layer w0.3: C232_L3.2@243.9,89 243.939,89.039 D12_L3.1@243.939,90.624 ; v1(243.9,91.4) 243.919,91.381 D12_L3.1@243.919,90.624
  Bottom Layer w0.2: v1(242.5,99) R230_L3.2@242.5,100.2 ; C226_L3.1@245.5,100.3 246.9,100.3 247,100.2 v1(247,99) ; v1(248.5,99) C169_L3.1@248.5,100.05 ; v1(250.5,99) 251,99.5 L20_L3.1@251,100.158 ; v1(253.5,100) 253.5,101.284 C167_L3.2@253.7,101.484 ; C167_L3.2@253.695,101.489 C167_L3.2@253.7,101.494
  Bottom Layer w0.254: v1(249.508,83.723) 249.508,83.792 249.86,84.144 R309_L3.1@249.86,85.107
  other v1: 243.5,106.5 244.5,106.5 245.5,106.5 246.5,106.5 247.5,106.5 248.5,109 248,109.5 210,110 248.5,110 248,110.5 210,111 248.5,111 248,111.5 210,112 248.5,112 248,112.5 210,113 248.5,113 248,113.5 210,114 248.5,114 244,114.5 245,114.5 246,114.5 247,114.5 248,114.5 210,115 244.5,115 245.5,115 246.5,115 247.5,115
GND_S3_GaN_N: C167_N.2 C168_N.2 C169_N.1 C172_N.2 C213_N.1 C215_N.2 C216_N.2 C225_N.2 C226_N.1 C227_N.1 C232_N.2 C233_N.1 C234_N.2 C235_N.2 C241_N.2 C242_N.1 D12_N.1 L20_N.1 R230_N.2 R309_N.1 R311_N.1 R315_N.1 R319_N.2 R320_N.2 TP18_N.1 U31_N.18 U31_N.19 U31_N.20 U31_N.21 U31_N.22 U31_N.23 U31_N.24 U31_N.25 U31_N.26 U31_N.28 U31_N.29 U31_N.30 U31_N.31 U31_N.32 U31_N.33 U31_N.34 U31_N.35 U31_N.36 U31_N.37 U31_N.38 U31_N.39 U36_N.2 U36_N.3 U36_N.4 U36_N.5 U36_N.6 U36_N.7 U36_N.8 U36_N.9 U36_N.10 U36_N.11 U36_N.12 U36_N.13 U36_N.14 U36_N.15 U37_N.5 U39_N.12 U39_N.13 U39_N.14 U39_N.15 U39_N.16 U40_N.2 U41_N.3 U41_N.4 | length 41.6
  Top Layer w0.2: TP18_N.1@100.5,43.5 v1(102,43.5) ; R315_N.1@106.5,37.65 106.623,37.774 108.526,37.774 C242_N.1@108.536,37.764 ; U41_N.4@110.392,36.764 110.247,36.909 109.342,36.909 109.225,37.026 v1(109.225,37.764) 109.308,37.764 109.379,37.834 110.192,37.834 U41_N.3@110.392,38.034
  Top Layer w0.254: v1(104.617,55.725) 104.617,54.601 104.889,54.33 104.889,53.66 105.044,53.504 105.044,53.006 U40_N.2@105.217,52.833 ; v1(104.693,44.008) C232_N.2@104.693,44.9 ; C232_N.2@104.992,45.029 105.242,45.029 105.665,44.606 105.665,44.356 105.706,44.315 105.706,44.056 v1(105.755,44.008) C225_N.2@107.034,44.008 107.134,44.108 C227_N.1@107.134,45.764 107.305,45.935 107.305,46.495 107.502,46.692 v1(107.502,46.761) ; C241_N.2@106.7,41 v1(106.7,42.118) ; C234_N.2@108.318,50.142 108.826,49.634 109.118,49.634 109.142,49.61 v1(109.777,49.61) U39_N.16@111.292,49.61 ; C235_N.2@108.477,48.404 108.825,48.056 109.41,48.056 109.705,47.761 v1(109.774,47.761) 109.801,47.733 109.801,47.207 109.974,47.034 U37_N.5@110.55,47.034 ; C242_N.1@108.536,37.764 v1(109.225,37.764) ; v1(109.777,50.508) 109.846,50.508 110.061,50.293 111.259,50.293 U39_N.15@111.292,50.26 ; C233_N.1@109.843,51.458 110.83,51.458 110.83,51.482 110.908,51.56 U39_N.13@111.292,51.56 ; U41_N.3@110.355,38.07 U41_N.3@110.392,38.034 ; U39_N.13@110.719,51.458 110.83,51.347 110.83,50.988 110.892,50.926 U39_N.14@111.276,50.926 ; U39_N.13@110.719,51.516 111.247,51.516 U39_N.13@111.292,51.56 ; U39_N.12@111.292,52.21 U39_N.13@111.292,51.56
  Top Layer w0.3: v1(102.1,44.9) 102.119,44.919 D12_N.1@102.876,44.919 ; D12_N.1@102.876,44.939 104.461,44.939 C232_N.2@104.5,44.9
  Bottom Layer w0.2: C167_N.2@92.016,54.4 v1(93.5,54.4) ; C226_N.1@93.2,46.5 93.2,47.9 C168_N.2@93.3,48 ; L20_N.1@93.275,52.2 v1(94.5,52.2) ; R230_N.2@93.3,43.5 v1(94.5,43.5) ; C168_N.2@93.3,48.3 v1(94.5,48.3) ; C169_N.1@93.45,50 v1(94.5,50)
  Bottom Layer w0.254: R309_N.1@108.393,50.86 109.356,50.86 109.708,50.508 v1(109.777,50.508)
  other v1: 78.5,11 79.5,11 80.5,11 81.5,11 82.5,11 83.5,11 79,45 87,45 78.5,45.5 79,46 87,46 78.5,46.5 79,47 87,47 78.5,47.5 79,48 87,48 78.5,48.5 79,49 80,49 81,49 82,49 83,49 84,49 87,49 79.5,49.5 80.5,49.5 81.5,49.5 82.5,49.5 83.5,49.5 84.5,49.5
GND_S4_GaN_L1: C7.1 C8.1 C9.1 C10.1 C11.1 C12.1 C85.1 C87.1 C88.2 C89.2 C90.2 C170_L1.2 C170_L2.2 C170_L3.2 C170_N.2 C171_L1.1 C171_L2.1 C171_L3.1 C171_N.1 C217_L1.1 C217_L2.1 C217_L3.1 C217_N.1 C244_L1.2 C244_L2.2 C244_L3.2 C244_N.2 C245_L1.1 C245_L2.1 C245_L3.1 C245_N.1 C246_L1.1 C246_L2.1 C246_L3.1 C246_N.1 C247_L1.2 C247_L2.2 C247_L3.2 C247_N.2 C249_L1.2 C249_L2.2 C249_L3.2 C249_N.2 C250_L1.1 C250_L2.1 C250_L3.1 C250_N.1 C251_L1.2 C251_L2.2 C251_L3.2 C251_N.2 C252_L1.2 C252_L2.2 C252_L3.2 C252_N.2 D14_L1.2 D14_L2.2 D14_L3.2 D14_N.2 D16_L1.1 D16_L2.1 D16_L3.1 D16_N.1 J9.1 L21_L1.1 L21_L2.1 L21_L3.1 L21_N.1 R16.1 R17.1 R18.1 R138.2 R231_L1.2 R231_L2.2 R231_L3.2 R231_N.2 R326_L1.1 R326_L2.1 R326_L3.1 R326_N.1 R328_L1.1 R328_L2.1 R328_L3.1 R328_N.1 TP8.1 TP9.1 TP10.1 TP19_L1.1 TP19_L2.1 TP19_L3.1 TP19_N.1 TP40.1 U11.2 U11.6 U13.12 U13.13 U13.14 U13.15 U13.16 U36_L1.18 U36_L1.19 U36_L1.20 U36_L1.21 U36_L1.22 U36_L1.23 U36_L1.24 U36_L1.25 U36_L1.26 U36_L1.28 U36_L1.29 U36_L1.30 U36_L1.31 U36_L1.32 U36_L1.33 U36_L1.34 U36_L1.35 U36_L1.36 U36_L1.37 U36_L1.38 U36_L1.39 U36_L2.18 U36_L2.19 U36_L2.20 U36_L2.21 U36_L2.22 U36_L2.23 U36_L2.24 U36_L2.25 U36_L2.26 U36_L2.28 U36_L2.29 U36_L2.30 U36_L2.31 U36_L2.32 U36_L2.33 U36_L2.34 U36_L2.35 U36_L2.36 U36_L2.37 U36_L2.38 U36_L2.39 U36_L3.18 U36_L3.19 U36_L3.20 U36_L3.21 U36_L3.22 U36_L3.23 U36_L3.24 U36_L3.25 U36_L3.26 U36_L3.28 U36_L3.29 U36_L3.30 U36_L3.31 U36_L3.32 U36_L3.33 U36_L3.34 U36_L3.35 U36_L3.36 U36_L3.37 U36_L3.38 U36_L3.39 U36_N.18 U36_N.19 U36_N.20 U36_N.21 U36_N.22 U36_N.23 U36_N.24 U36_N.25 U36_N.26 U36_N.28 U36_N.29 U36_N.30 U36_N.31 U36_N.32 U36_N.33 U36_N.34 U36_N.35 U36_N.36 U36_N.37 U36_N.38 U36_N.39 U43_L1.5 U43_L2.5 U43_L3.5 U43_N.5 U44_L1.12 U44_L1.13 U44_L1.14 U44_L1.15 U44_L1.16 U44_L2.12 U44_L2.13 U44_L2.14 U44_L2.15 U44_L2.16 U44_L3.12 U44_L3.13 U44_L3.14 U44_L3.15 U44_L3.16 U44_N.12 U44_N.13 U44_N.14 U44_N.15 U44_N.16 U45_L1.2 U45_L2.2 U45_L3.2 U45_N.2 | length 161.9
  Top Layer w0.2: C10.1@94.279,79.135 94.344,79.2 TP40.1@100,79.2 ; v1(94.726,126.907) 94.726,126.99 95,127.264 95,128.386 C251_L1.2@95.187,128.573 95.451,128.31 v1(95.451,126.907) ; v1(99,136.5) TP19_L1.1@100,136.5 ; v1(100,69.5) TP19_N.1@100,70.5 ; C251_N.2@107.927,65.687 108.19,65.951 v1(109.593,65.951) ; v1(178.226,111.907) 178.226,111.99 178.5,112.264 178.5,113.386 C251_L2.2@178.687,113.573 178.951,113.31 v1(178.951,111.907) ; v1(182.5,121.5) TP19_L2.1@183.5,121.5 ; v1(268.5,93.5) TP19_L3.1@269.5,93.5
  Top Layer w0.254: D16_L1.1@89.425,133.584 89.425,131.768 89.561,131.633 C252_L1.2@89.561,129.798 89.677,129.682 C246_L1.1@91.111,129.682 ; U43_L1.5@92.883,126.126 92.883,127.915 C244_L1.2@93.076,128.107 ; U44_L1.16@95.154,125.338 95.154,126.569 95.451,126.866 v1(95.451,126.907) ; U44_L1.15@95.804,125.338 95.804,126.507 v1(96.203,126.907) ; C250_L1.1@96.956,126.907 v1(96.203,126.907) ; U44_L1.12@97.754,125.338 U44_L1.13@97.104,125.338 U44_L1.14@96.454,125.338 96.454,126.588 96.203,126.838 v1(96.203,126.907) ; R328_L1.1@99.044,131.908 99.117,131.834 v1(99.994,131.834) ; D16_N.1@102.916,59.925 104.732,59.925 104.867,60.061 C252_N.2@106.702,60.061 106.818,60.177 C246_N.1@106.818,61.611 ; R328_N.1@104.592,69.544 104.666,69.617 v1(104.666,70.494) ; C244_N.2@108.393,63.576 108.585,63.383 U43_N.5@110.374,63.383 ; v1(109.593,65.951) 109.634,65.951 109.931,65.654 U44_N.16@111.162,65.654 ; C250_N.1@109.593,67.456 v1@109.593,66.703 ; U44_N.15@111.162,66.304 109.993,66.304 v1(109.593,66.703) ; U44_N.12@111.162,68.254 U44_N.13@111.162,67.604 U44_N.14@111.162,66.954 109.912,66.954 109.662,66.703 v1(109.593,66.703) ; D16_L2.1@172.925,118.584 172.925,116.768 173.061,116.633 C252_L2.2@173.061,114.798 173.177,114.682 C246_L2.1@174.611,114.682 ; U43_L2.5@176.383,111.126 176.383,112.915 C244_L2.2@176.576,113.107 ; U44_L2.16@178.654,110.338 178.654,111.569 178.951,111.866 v1(178.951,111.907) ; U44_L2.15@179.304,110.338 179.304,111.507 v1(179.703,111.907) ; C250_L2.1@180.456,111.907 v1(179.703,111.907) ; U44_L2.12@181.254,110.338 U44_L2.13@180.604,110.338 U44_L2.14@179.954,110.338 179.954,111.588 179.703,111.838 v1(179.703,111.907) ; R328_L2.1@182.544,116.908 182.617,116.834 v1(183.494,116.834) ; D16_L3.1@258.925,90.584 258.925,88.768 259.061,88.633 C252_L3.2@259.061,86.798 259.177,86.682 C246_L3.1@260.611,86.682 ; U43_L3.5@262.383,83.126 262.383,84.915 C244_L3.2@262.576,85.107 ; U44_L3.16@264.654,82.338 264.654,83.569 264.951,83.866 v1(264.951,83.907) ; U44_L3.15@265.304,82.338 265.304,83.507 v1(265.703,83.907) ; C250_L3.1@266.456,83.907 v1(265.703,83.907) ; U44_L3.12@267.254,82.338 U44_L3.13@266.604,82.338 U44_L3.14@265.954,82.338 265.954,83.588 265.703,83.838 v1(265.703,83.907) ; R328_L3.1@268.544,88.908 268.617,88.834 v1(269.494,88.834)
  Top Layer w0.3: U11.2@86.8,92.8 85.8,92.8 85,92 v1(85,91) 85.582,90.418 C88.2@87.129,90.418 ; C88.2@87.093,90.3 87.3,90.093 87.3,88 94.279,81.021 C10.1@94.279,79.135 ; U11.6@89.312,92.112 89.5,91.925 89.5,91.784 89.7,91.584 v1(89.7,91.5) ; U13.13@95.7,92.8 95.7,91.246 C90.2@95.913,91.033 ; C90.2@95.9,91 v1(97.2,91) ; U45_L1.2@97.551,131.384 97.667,131.5 98.1,131.5 98.4,131.8 98.4,131.824 98.586,131.824 98.761,132 R328_L1.1@98.9,132 ; R328_N.1@104.5,69.4 104.5,69.261 104.676,69.086 104.676,68.9 104.7,68.9 105,68.6 105,68.167 U45_N.2@105.116,68.051 ; U45_L2.2@181.051,116.384 181.167,116.5 181.6,116.5 181.9,116.8 181.9,116.824 182.086,116.824 182.261,117 R328_L2.1@182.4,117 ; U45_L3.2@267.051,88.384 267.167,88.5 267.6,88.5 267.9,88.8 267.9,88.824 268.086,88.824 268.261,89 R328_L3.1@268.4,89
  Bottom Layer w0.2: R18.1@36.198,55.004 R18.1@36.252,54.95 ; C170_N.2@70.016,59.5 70.016,60.516 v1(70.5,61) ; L21_N.1@71.775,56.5 72,56.275 C171_N.1@72,54.55 ; C171_N.1@72.079,54.429 72,54.35 72,52.175 v1(72.45,51.725) 72.426,51.701 72.426,51.226 C245_N.1@72.2,51 72,50.8 72,50.5 v1(72.5,50) 72.5,49.2 R231_N.2@72.3,49 ; R231_L1.2@78.5,164.2 78.7,164 v1(79.5,164) 80,164.5 80.3,164.5 C245_L1.1@80.5,164.3 80.726,164.074 81.201,164.074 v1(81.225,164.05) 81.675,164.5 83.55,164.5 83.708,164.342 C171_L1.1@84,164.342 ; C171_L1.1@84,164.55 C171_L1.1@84.05,164.5 ; C171_L1.1@85,164.5 85.775,164.5 L21_L1.1@86,164.725 ; v1(87.5,165) 88,165.5 C170_L1.2@88,166.484 ; R231_L2.2@162,149.2 162.2,149 v1(163,149) 163.5,149.5 163.8,149.5 C245_L2.1@164,149.3 164.226,149.074 164.701,149.074 v1(164.725,149.05) 165.175,149.5 167.05,149.5 167.208,149.342 C171_L2.1@167.5,149.342 ; C171_L2.1@167.5,149.55 167.55,149.5 169.275,149.5 L21_L2.1@169.5,149.725 ; v1(171,150) 171,150.984 C170_L2.2@171.5,151.484 ; R231_L3.2@248,121.2 248.2,121 v1(249,121) 249.5,121.5 249.8,121.5 C245_L3.1@250,121.3 250.225,121.075 250.7,121.075 v1(250.725,121.05) 251.175,121.5 253.05,121.5 253.208,121.342 C171_L3.1@253.5,121.342 ; C171_L3.1@253.5,121.55 253.55,121.5 255.275,121.5 L21_L3.1@255.5,121.725 ; L21_L3.1@255.8,121.725 256.074,122 v1@256.999,122 ; v1(257,122) 257.5,122.5 C170_L3.2@257.5,123.484
  Bottom Layer w0.254: v1(94.726,126.907) R326_L1.1@94.726,128.023 ; R326_N.1@108.477,65.226 v1(109.593,65.226) ; v1(178.226,111.907) R326_L2.1@178.226,113.023 ; v1(264.226,83.907) R326_L3.1@264.226,85.023
  Bottom Layer w0.3: v1(85,91) 85.084,91 85.315,90.768 R138.2@86.529,90.768 86.568,90.768 R138.2@86.6,90.8 ; R138.2@86.529,90.668 86.529,89.398 86.779,89.148 86.779,89.123 87.104,88.798 C87.1@87.129,88.798 ; C85.1@89.629,90.768 89.665,90.804 89.665,91.465 v1(89.7,91.5) ; C89.2@96.2,89 v1(97.3,89)
  other v1: 59,7.5 60,7.5 61,7.5 62,7.5 63,7.5 64,7.5 58.5,8 59.5,8 60.5,8 61.5,8 62.5,8 63.5,8 64.5,8 58.5,10.5 59.5,10.5 60.5,10.5 61.5,10.5 62.5,10.5 63.5,10.5 64.5,10.5 66.6,49 66.6,50 66.6,51 66.6,52 57,56.5 58,56.5 59,56.5 60,56.5 61,56.5 62,56.5 63,56.5 64,56.5 65,56.5 66,56.5 56.5,57 57.5,57 58.5,57 59.5,57 60.5,57 61.5,57 62.5,57 63.5,57 64.5,57 65.5,57 57,57.5 58,57.5 59,57.5 60,57.5 61,57.5 62,57.5 63,57.5 64,57.5 65,57.5 66,57.5 56.5,58 57.5,58 58.5,58 59.5,58 60.5,58 61.5,58 62.5,58 63.5,58 64.5,58 65.5,58 57,58.5 58,58.5 59,58.5 60,58.5 61,58.5 62,58.5 63,58.5 64,58.5 65,58.5 66,58.5 56.5,59 57.5,59 58.5,59 59.5,59 60.5,59 61.5,59 62.5,59 63.5,59 64.5,59 65.5,59 103.602,59.925 105.952,60.061 109.143,63.383 262.383,84.357 259.061,87.548 258.925,89.898 95.709,91.851 96.586,91.882 176.383,112.357 173.061,115.548 172.925,117.898 248,126.5 249,126.5 250,126.5 251,126.5 252,126.5 92.883,127.357 255.5,127.5 256.5,127.5 257.5,127.5 256,128 257,128 258,128 255.5,128.5 256.5,128.5 257.5,128.5 207,129 209.5,129 256,129 257,129 258,129 206.5,129.5 255.5,129.5 256.5,129.5 257.5,129.5 207,130 209.5,130 256,130 257,130 258,130 206.5,130.5 255.5,130.5 256.5,130.5 257.5,130.5 89.561,130.548 207,131 209.5,131 256,131 257,131 258,131 206.5,131.5 255.5,131.5 256.5,131.5 257.5,131.5 207,132 209.5,132 256,132 257,132 258,132 206.5,132.5 255.5,132.5 256.5,132.5 257.5,132.5 89.425,132.898 207,133 209.5,133 256,133 257,133 258,133 206.5,133.5 255.5,133.5 256.5,133.5 257.5,133.5 207,134 209.5,134 256,134 257,134 258,134 206.5,134.5 255.5,134.5 256.5,134.5 257.5,134.5 207,135 209.5,135 256,135 257,135 258,135 255.5,135.5 256.5,135.5 257.5,135.5 256,136 257,136 258,136 255.5,136.5 256.5,136.5 257.5,136.5 256,137 257,137 258,137 162,154.5 163,154.5 164,154.5 165,154.5 166,154.5 169.5,155.5 170.5,155.5 171.5,155.5 170,156 171,156 172,156 169.5,156.5 170.5,156.5 171.5,156.5 121,157 123.5,157 170,157 171,157 172,157 120.5,157.5 169.5,157.5 170.5,157.5 171.5,157.5 121,158 123.5,158 170,158 171,158 172,158 120.5,158.5 169.5,158.5 170.5,158.5 171.5,158.5 121,159 123.5,159 170,159 171,159 172,159 120.5,159.5 169.5,159.5 170.5,159.5 171.5,159.5 121,160 123.5,160 170,160 171,160 172,160 120.5,160.5 169.5,160.5 170.5,160.5 171.5,160.5 121,161 123.5,161 170,161 171,161 172,161 120.5,161.5 169.5,161.5 170.5,161.5 171.5,161.5 121,162 123.5,162 170,162 171,162 172,162 120.5,162.5 169.5,162.5 170.5,162.5 171.5,162.5 121,163 123.5,163 170,163 171,163 172,163 169.5,163.5 170.5,163.5 171.5,163.5 170,164 171,164 172,164 169.5,164.5 170.5,164.5 171.5,164.5 170,165 171,165 172,165 78.5,169.5 79.5,169.5 80.5,169.5 81.5,169.5 82.5,169.5 86,170.5 87,170.5 88,170.5 86.5,171 87.5,171 88.5,171 86,171.5 87,171.5 88,171.5 37.5,172 40,172 86.5,172 87.5,172 88.5,172 37,172.5 86,172.5 87,172.5 88,172.5 37.5,173 40,173 86.5,173 87.5,173 88.5,173 37,173.5 86,173.5 87,173.5 88,173.5 37.5,174 40,174 86.5,174 87.5,174 88.5,174 37,174.5 86,174.5 87,174.5 88,174.5 37.5,175 40,175 86.5,175 87.5,175 88.5,175 37,175.5 86,175.5 87,175.5 88,175.5 37.5,176 40,176 86.5,176 87.5,176 88.5,176 37,176.5 86,176.5 87,176.5 88,176.5 37.5,177 40,177 86.5,177 87.5,177 88.5,177 37,177.5 86,177.5 87,177.5 88,177.5 37.5,178 40,178 86.5,178 87.5,178 88.5,178 86,178.5 87,178.5 88,178.5 86.5,179 87.5,179 88.5,179 86,179.5 87,179.5 88,179.5 86.5,180 87.5,180 88.5,180
GPIO1: J12.86 R86.2 | length 8.9
  Top Layer w0.4: R86.2@211.2,33.3 211.2,37.6 211.75,38.15 J12.86@211.75,42
GPIO2: J12.88 R88.2 | length 5.7
  Top Layer w0.4: R88.2@210.2,36.6 210.2,37.6 210.95,38.35 J12.88@210.95,42
GPIO3: J12.90 R67.2 | length 11.6
  Top Layer w0.2: v1(210,39) 210,39.083 210.15,39.233 J12.90@210.15,42 ; R67.2@215.5,33.3 v1(215.5,34.5)
  Bottom Layer w0.2: v1(210,39) 211,39 v1(215.5,34.5)
GPIO4: J12.92
GPIOA: J12.94 J13.7 | length 24.9
  Top Layer w0.4: J13.7@202.7,19.6 202.6,19.7 202.6,29 208.55,34.95 J12.94@208.55,42
GPIOB: J12.96 J13.6 | length 25.6
  Top Layer w0.4: J13.6@200.23,19.53 200.23,27.53 207.75,35.05 J12.96@207.75,42
GPIOC: J12.100 J13.5 | length 26
  Top Layer w0.4: J13.5@197.7,19.5 197.7,25.9 206.15,34.35 J12.100@206.15,42
GPIOD: J12.102 J13.4 | length 26.7
  Top Layer w0.4: J13.4@195.2,19.5 195.2,24.3 205.35,34.45 J12.102@205.35,42
GPIOE: J12.104 J13.3 | length 27.4
  Top Layer w0.4: J13.3@192.61,19.5 192.813,19.703 192.813,22.813 204.55,34.55 J12.104@204.55,42
GPIOF: J12.106 J13.2 | length 28.2
  Top Layer w0.4: J13.2@190.07,19.5 190.07,20.97 203.75,34.65 J12.106@203.75,42
GPIOG: J12.68
GRID_GND: J10.1 MP6.1 R94.1 | length 45.5
  Layer 1 w1: R94.1@266,263.75 267.95,263.75 272.3,268.1 272.3,277.6 277.174,282.474 292.414,282.474 293,283.059 J10.1@293,288
  other v1: 291.04,294.036 293.04,294.036 295.04,294.036
GRID_GND_1: C24.1 C25.1 MP4.1
  other v1: 43.1,298.7
GRID_RELAYS: D20.2 R63.1 R96.1 | length 254.5
  Top Layer w0.2: R63.1@217.5,31.7 221.2,31.7 222.205,30.695 222.205,24.64 226.645,20.2 v1(233.3,20.2) ; R96.1@288.2,199.5 288.2,199.45 288.25,199.4 288.35,199.3 289.2,199.3 290.4,198.1 290.4,197.6 D20.2@290.5,197.5
  Top Layer w0.3: v1(286.92,39.538) 287.938,39.538 293.4,45 293.4,142.45 288.25,147.6 R96.1@288.25,199.4
  Bottom Layer w0.2: v1(233.3,20.2) 246.155,20.2 261.255,35.3 282.682,35.3 v1(286.92,39.538)
I_L1_VREF: R102.2 U2.7 | length 384.4
  Top Layer w0.3: U2.7@93.875,243.635 93.907,243.667 95.267,243.667 v1@95.3,243.7 ; v1(102.6,241.3) 116.9,241.3 119.7,238.5 134.2,238.5 144.247,228.453 188.947,228.453 212.8,204.6 271.1,204.6 284.9,190.8 284.9,146 288.5,142.4 288.5,88.4 289.3,87.6 289.3,47.4 279.4,37.5 270.8,37.5 268.6,39.7 R102.2@268.6,40.095
  Bottom Layer w0.3: v1(95.2,243.7) 97.2,243.7 99.655,241.245 102.545,241.245 v1(102.6,241.3)
I_L2_VREF: R110.2 U4.7 | length 368
  Top Layer w0.3: U4.7@105.5,226 105.587,226.087 105.587,227.087 v1(105.6,227.1) ; v1@108.263,233.91 111.253,236.9 133.3,236.9 142.886,227.314 188.186,227.314 212.5,203 270.5,203 283.4,190.1 283.4,145.4 286.7,142.1 286.7,87.7 287.6,86.8 287.6,70.3 283.4,66.1 283.4,43.1 278.8,38.5 274.176,38.5 273.75,38.926 R110.2@273.75,39.863
  Bottom Layer w0.3: v1(105.6,227.1) 105.6,231.3 108.21,233.91 v1(108.24,233.91)
I_L3_VREF: R118.2 U5.7 | length 247.7
  Top Layer w0.2: R118.2@280.993,49.75 R118.2@281.043,49.75 ; v1@281.375,50.082 v1(281.481,50.082)
  Top Layer w0.3: U5.7@191.4,202.2 191.383,202.218 191.383,203.282 v1(191.4,203.3) ; v1(194,207.9) 194.574,207.9 195.029,208.355 195.055,208.355 196.7,210 202.9,210 211.7,201.2 269.8,201.2 282.1,188.9 282.1,144.5 285.3,141.3 285.3,86.7 286.1,85.9 286.1,71.8 282.1,67.8 v1(282.1,57.9) ; R118.2@281.043,49.75 v1@281.375,50.082
  Bottom Layer w0.3: v1(191.4,203.3) 193.3,205.2 193.3,207.5 193.7,207.9 v1(194,207.9) ; v1(281.481,50.082) 281.9,50.5 281.9,57.616 282.1,57.816 v1(282.1,57.9)
I_N_VREF: R126.2 U6.7 | length 263.7
  Top Layer w0.2: U6.7@35.498,107.603 35.498,107.885 36,108.387 v1(36,109) ; v1(272,56) 272,55.917 272.1,55.817 R126.2@272.1,52.4
  Bottom Layer w0.2: v1(36,109) 36.054,108.946 41.904,108.946 42.55,108.3 70.766,108.3 71.566,107.5 100.066,107.5 135.566,72 191.5,72 200.5,63 234.717,63 235.271,63.554 235.729,63.554 235.783,63.5 264.5,63.5 v1(272,56)
I_PCC_L1+: C17.2 L19.2 U2.1
  other v1: 60.5,259.9 61.4,259.9 62.3,259.9 63.2,259.9 60.7,260.7 61.6,260.7 62.5,260.7 60.8,261.5 61.7,261.5
I_PCC_L1-: L1.5 L1.6 L1.7 L1.8 U2.2
I_PCC_L2+: C18.2 L19.4 U4.1
  other v1: 104.64,210.21 104.14,210.71 105.14,210.71 104.64,211.21 104.14,211.71 105.14,211.71 104.64,212.21 104.14,212.71 105.14,212.71 104.64,213.21 104.14,213.71 105.14,213.71 104.64,214.21 104.14,214.71 105.14,214.71 67.6,268.4 68.5,268.4 69.4,268.4 70.3,268.4 67.6,269.3 68.5,269.3 69.4,269.3 70.3,269.3
I_PCC_L2-: L2.5 L2.6 L2.7 L2.8 U4.2
  other v1: 107.14,211.71 108.14,211.71 109.14,211.71 110.14,211.71 107.64,212.21 108.64,212.21 109.64,212.21 107.14,212.71 108.14,212.71 109.14,212.71 110.14,212.71 107.64,213.21 108.64,213.21 109.64,213.21 107.14,213.71 108.14,213.71 109.14,213.71 110.14,213.71 107.64,214.21 108.64,214.21 109.64,214.21 107.14,214.71 108.14,214.71 109.14,214.71 110.14,214.71
I_PCC_L3+: C19.2 L19.6 U5.1
  other v1: 188.5,185.5 189.5,185.5 190.5,185.5 191.5,185.5 189,186 190,186 191,186 188.5,186.5 189.5,186.5 190.5,186.5 191.5,186.5 189,187 190,187 191,187 188.5,187.5 189.5,187.5 190.5,187.5 191.5,187.5 189,188 190,188 191,188 188.5,188.5 189.5,188.5 190.5,188.5 191.5,188.5 189,189 190,189 191,189 188.5,189.5 189.5,189.5 190.5,189.5 191.5,189.5 189,190 190,190 191,190 188.5,190.5 189.5,190.5 190.5,190.5 191.5,190.5 36.5,236.5 37.5,236.5 38.5,236.5 39.5,236.5 40.5,236.5 41.5,236.5 42.5,236.5 43.5,236.5 44.5,236.5 45.5,236.5 46.5,236.5 47.5,236.5 48.5,236.5 36,237 37,237 38,237 39,237 40,237 41,237 42,237 43,237 44,237 45,237 46,237 47,237 48,237 36.5,237.5 37.5,237.5 38.5,237.5 39.5,237.5 40.5,237.5 41.5,237.5 42.5,237.5 43.5,237.5 44.5,237.5 45.5,237.5 46.5,237.5 47.5,237.5 48.5,237.5 36,238 37,238 38,238 39,238 40,238 41,238 42,238 43,238 44,238 45,238 46,238 47,238 48,238 36.5,238.5 37.5,238.5 38.5,238.5 39.5,238.5 40.5,238.5 41.5,238.5 42.5,238.5 43.5,238.5 44.5,238.5 45.5,238.5 46.5,238.5 47.5,238.5 48.5,238.5 36,239 37,239 38,239 39,239 40,239 41,239 42,239 43,239 44,239 45,239 46,239 47,239 48,239 36.5,239.5 37.5,239.5 38.5,239.5 39.5,239.5 40.5,239.5 41.5,239.5 42.5,239.5 43.5,239.5 44.5,239.5 45.5,239.5 46.5,239.5 47.5,239.5 48.5,239.5 36,240 37,240 38,240 39,240 40,240 41,240 42,240 43,240 44,240 45,240 46,240 47,240 48,240 36.5,240.5 37.5,240.5 38.5,240.5 39.5,240.5 40.5,240.5 41.5,240.5 42.5,240.5 43.5,240.5 44.5,240.5 45.5,240.5 46.5,240.5 47.5,240.5 48.5,240.5 36,241 37,241 38,241 39,241 40,241 41,241 42,241 43,241 44,241 45,241 46,241 47,241 48,241
I_PCC_L3-: L5.5 L5.6 L5.7 L5.8 U5.2
  other v1: 192.931,187.875 193.931,187.875 194.931,187.875 195.931,187.875 193.431,188.375 194.431,188.375 195.431,188.375 192.931,188.875 193.931,188.875 194.931,188.875 195.931,188.875 193.431,189.375 194.431,189.375 195.431,189.375 192.931,189.875 193.931,189.875 194.931,189.875 195.931,189.875 193.431,190.375 194.431,190.375 195.431,190.375 192.931,190.875 193.931,190.875 194.931,190.875 195.931,190.875
I_PCC_N+: C17.1 C18.1 C19.1 C23.1 C24.2 C257.1 C258.1 L19.8 U6.1
  other v1: 1.5,95.437 2.25,95.437 1.5,96.137 2.25,96.137 1.5,96.837 2.25,96.837 1.5,97.537 2.25,97.537 1.5,98.237 2.25,98.237 1.5,98.937 2.25,98.937 1.5,99.637 2.25,99.637 1.5,100.337 2.25,100.337 1.5,101.037 2.25,101.037 1.5,101.738 2.25,101.738 1.5,102.438 2.25,102.438 1.5,103.138 2.25,103.138 1.5,103.838 2.25,103.838 1.5,104.538 2.25,104.538 1.5,105.238 2.25,105.238 1.5,105.938 2.25,105.938 1.5,106.638 2.25,106.638 1.5,107.338 2.25,107.338 1.5,108.038 2.25,108.038 1.5,108.738 2.25,108.738 1.5,109.438 2.25,109.438 1.5,261.5 2.5,261.5 2,262 3,262 1.5,262.5 2.5,262.5 2,263 3,263 1.5,263.5 2.5,263.5 2,264 3,264 1.5,264.5 2.5,264.5 2,265 3,265 1.5,265.5 2.5,265.5 2,266 3,266 1.5,266.5 2.5,266.5 2,267 3,267 1.5,267.5 2.5,267.5 2,268 3,268 1.5,268.5 2.5,268.5 2,269 3,269 1.5,269.5 2.5,269.5 2,270 3,270 1.5,270.5 2.5,270.5 2,271 3,271 1.5,271.5 2.5,271.5 2,272 3,272 1.5,272.5 2.5,272.5
I_PCC_N-: L6.5 L6.6 L6.7 L6.8 U6.2
  other v1: 2.5,53.437 3.25,53.437 2.5,54.137 3.25,54.137 2.5,54.837 3.25,54.837 2.5,55.537 3.25,55.537 2.5,56.237 3.25,56.237 2.5,56.937 3.25,56.937 2.5,57.637 3.25,57.637 2.5,58.337 3.25,58.337 2.5,59.037 3.25,59.037 2.5,59.738 3.25,59.738 2.5,60.438 3.25,60.438 2.5,61.138 3.25,61.138 2.5,61.838 3.25,61.838 2.5,62.538 3.25,62.538 2.5,63.238 3.25,63.238 2.5,63.938 3.25,63.938 2.5,64.638 3.25,64.638 2.5,65.338 3.25,65.338 2.5,66.038 3.25,66.038 2.5,66.738 3.25,66.738 2.5,67.438 3.25,67.438 2.5,68.137 3.25,68.137 2.5,68.837 3.25,68.837 2.5,69.537 3.25,69.537 2.5,70.237 3.25,70.237 2.5,70.937 3.25,70.937 2.5,71.637 3.25,71.637 2.5,72.337 3.25,72.337 2.5,73.037 3.25,73.037 2.5,73.738 3.25,73.738 2.5,74.438 3.25,74.438 2.5,75.138 3.25,75.138 2.5,75.838 3.25,75.838 2.5,76.538 3.25,76.538 2.5,77.238 3.25,77.238 2.5,77.938 3.25,77.938 2.5,78.638 3.25,78.638 2.5,79.338 3.25,79.338 2.5,80.038 3.25,80.038
I_SENSE_1: R39.2
I_SENSE_2: R40.2
I_SENSE_PCC_L1: C31.2 R21.2 R101.2 TP27.1 | length 37.7
  Top Layer w0.2: TP27.1@266.5,40.5 266.5,39.5 266.946,39.054 267.446,39.054 v1(267.5,39) ; R101.2@269.7,40.1 269.85,39.95 269.85,39.85 v1(270.6,39.1)
  Top Layer w0.4: R21.2@246,52.1 246.1,52.2 v1@246.1,53 ; v1@246,53 v1(246,53.005) C31.2@246,53.7
  Bottom Layer w0.2: v1(246,53.005) 246.039,53.044 246.444,53.044 247.01,53.61 254.49,53.61 259.1,49 259.1,46.2 266.2,39.1 v1(270.6,39.1)
I_SENSE_PCC_L2: C37.2 R32.1 R108.2 TP28.1 | length 41.3
  Top Layer w0.2: C37.2@240.9,33.3 v1(240.9,34.1) R32.1@240.9,35.2 ; v1(275,39.155) 275.025,39.18 275.025,39.838 R108.2@275.05,39.863 275.187,40 TP28.1@277,40
  Layer 2 w0.2: v1(240.9,34.1) 241.505,33.495 249.384,33.495 249.589,33.7 v1(249.7,33.7)
  Bottom Layer w0.2: v1(249.7,33.7) 252.1,36.1 271.945,36.1 v1(275,39.155)
I_SENSE_PCC_L3: C43.2 R20.2 R116.2 TP29.1 | length 41.6
  Top Layer w0.2: TP29.1@276.5,56 274.5,56 274.2,55.7 v1(274.2,54.3) 279.3,54.3 280.993,52.607 R116.2@280.993,50.8
  Top Layer w0.4: R20.2@247.8,52.1 247.9,52.2 v1@247.9,53 ; v1(247.8,53.005) 247.84,53.045 C43.2@247.84,53.54
  Layer 2 w0.2: v1(247.8,53.005) 247.878,53.083 248.183,53.083 v1(249.35,54.25)
  Bottom Layer w0.2: v1(249.35,54.25) 274.15,54.25 v1(274.2,54.3)
I_SENSE_PCC_N: C50.2 R26.2 R125.2 TP30.1 | length 35.6
  Top Layer w0.2: TP30.1@258.5,54.5 258.5,55.883 258.225,56.158 254.425,56.158 254.083,56.5 v1(254,56.5) 254,55.5 257.816,51.684 R125.2@267.05,51.684
  Top Layer w0.4: R26.2@242.1,55 v1(242.1,55.9) C50.2@242.1,56.5
  Bottom Layer w0.2: v1(242.1,55.9) 242.9,56.7 248.308,56.7 248.508,56.5 v1(254,56.5)
I_VOUT_L1: R100.2 U2.6 | length 380
  Top Layer w0.3: U2.6@93.875,242.365 93.892,242.382 95.182,242.382 v1(95.2,242.4) ; v1(102.4,240.5) 102.459,240.559 102.785,240.559 103.026,240.8 116.693,240.8 119.493,238 133.993,238 144.087,227.906 188.787,227.906 212.693,204 270.993,204 284.4,190.593 284.4,145.3 287.6,142.1 287.6,88 288.5,87.1 288.5,70 284.4,65.9 284.4,43.3 279.1,38 272.076,38 271.9,38.176 R100.2@271.9,40.6
  Bottom Layer w0.3: v1(95.2,242.4) 96.074,242.4 97.974,240.5 v1@102.3,240.5
I_VOUT_L2: R107.2 U4.6 | length 352.1
  Top Layer w0.3: U4.6@106.7,225.8 106.822,225.922 106.822,227.078 v1(106.8,227.1) ; v1(109.097,233.684) 109.136,233.724 109.136,233.983 111.553,236.4 133.093,236.4 138.3,231.193 142.748,226.744 188.048,226.744 212.293,202.5 270.293,202.5 282.9,189.893 282.9,144.9 286,141.8 286,87.3 286.7,86.6 286.7,71.2 282.9,67.4 282.9,46.9 281.15,45.15 281.15,45.1 281.05,45 R107.2@281,45
  Bottom Layer w0.3: v1(106.8,227.1) 106.8,231.388 v1(109.097,233.684)
I_VOUT_L3: R115.2 U5.6 | length 246.5
  Top Layer w0.3: U5.6@192.6,202.1 192.667,202.167 192.667,203.267 v1(192.7,203.3) ; v1(195.3,207.7) 197.1,209.5 202.693,209.5 211.493,200.7 269.593,200.7 281.4,188.893 281.4,144 284.5,140.9 284.5,86.1 285.4,85.2 285.4,72.3 281.4,68.3 281.4,57.121 282.4,56.121 282.4,49.2 281.932,48.732 R115.2@281.567,48.732
  Bottom Layer w0.3: v1(192.7,203.3) 194.3,204.9 194.3,206.8 195.1,207.6 v1@195.2,207.6
I_VOUT_N: R124.2 U6.6 | length 262.6
  Top Layer w0.2: U6.6@36.396,106.705 37.192,107.5 v1(38,107.5) ; v1(270,57) 272,57 273.2,55.8 R124.2@273.2,52.4
  Bottom Layer w0.2: v1(38,107.5) 41.725,107.5 42.125,107.9 70.6,107.9 71.4,107.1 99.9,107.1 135.5,71.5 191.434,71.5 200.434,62.5 235.217,62.5 235.271,62.446 235.729,62.446 235.783,62.5 264.934,62.5 270,57.434 v1(270,57)
Middle_Point: C1.1 C2.1 C3.1 C7.2 C8.2 C9.2 C23.2 C257.2 C258.2 R7.1 R8.1 R9.1 R10.2 R11.2 R12.2 | length 0.9
  Bottom Layer w0.5: C9.2@11,121.936 C9.2@11.436,121.936 ; C7.2@20.5,85 C7.2@20.846,84.654
MONITOR_GaN_ISO_L1: C159.2 R68.2 R293_L1.1 | length 156.4
  Top Layer w0.2: R293_L1.1@68.5,108 v1(68.5,109) ; v1(124.5,94) 132,94 135.5,90.5 157.5,90.5 v1(162.5,85.5) ; v1(164,84) 169,84 183,70 186,70 v1(194,62) ; C159.2@200.5,61.9 200.5,61 v1(201,60.5) R68.2@202.2,60.5
  Layer 2 w0.2: v1(68.5,109) 69,108.5 72.717,108.5 72.771,108.446 73.229,108.446 73.283,108.5 103.434,108.5 117.934,94 v1(124.5,94)
  Bottom Layer w0.2: v1(162.5,85.5) v1(164,84) ; v1(194,62) 195.5,60.5 v1(201,60.5)
MONITOR_GaN_ISO_L2: C160.2 R70.2 R293_L2.1 | length 68.6
  Top Layer w0.2: R293_L2.1@152,93.5 152,92.5 153,91.5 160.5,91.5 v1(163.5,88.5) ; v1(174.5,88.5) 174.5,83.934 197.934,60.5 200,60.5 200.5,60 200.5,59.6 C160.2@200.4,59.5 200.5,59.4 200.5,59 201.036,58.464 R70.2@202.136,58.464
  Layer 2 w0.2: v1(163.5,88.5) v1(174.5,88.5)
MONITOR_GaN_ISO_L3: C161.2 R72.2 R293_L3.1 | length 48.3
  Top Layer w0.2: v1(211,64) 214.1,60.9 214.666,60.9 215.12,60.446 229.358,60.446 230.412,61.5 237,61.5 238,62.5 R293_L3.1@238,65.5
  Top Layer w0.4: v1(200.6,56.2) 200.56,56.24 200.56,57.06 C161.2@200.6,57.1 ; v1@200.629,56.2 201.666,56.2 201.691,56.225 201.9,56.225 R72.2@201.9,56.4
  Layer 2 w0.2: v1(200.6,56.2) 208.4,64 v1(211,64)
MONITOR_GaN_ISO_N: C162.2 R73.2 R293_N.1 | length 82.2
  Top Layer w0.2: R293_N.1@128,39 v1(129.5,39) ; v1(176.5,46) 186,55.5 v1(188.5,55.5) ; C162.2@200.367,54.333 C162.2@200.5,54.2
  Top Layer w0.4: C162.2@200.5,54.2 v1(201.2,54.2) R73.2@201.9,54.2
  Bottom Layer w0.2: v1(129.5,39) 148.042,39 152.542,43.5 171,43.5 173.5,46 v1(176.5,46) ; v1(188.5,55.5) 188.554,55.554 199.846,55.554 v1(201.2,54.2)
MONITOR_S1_GaN_ISO_L1: C209_L1.2 R278_L1.1 U33_L1.6 | length 40.8
  Top Layer w0.2: v1(35,111) 35.5,111 R278_L1.1@36.037,111.537 ; C209_L1.2@65,113.6 65.1,113.5 65.883,113.5 66,113.383 v1(66,112) 66.025,111.975 67.35,111.975 U33_L1.6@67.375,111.95
  Top Layer w0.254: R278_L1.1@35.98,111.992 36.037,111.935 R278_L1.1@36.037,111.537
  Bottom Layer w0.2: v1(35,111) 36.426,112.426 55.426,112.426 56.5,113.5 56.5,115 57,115.5 59.217,115.5 61.802,112.915 65.085,112.915 v1(66,112)
MONITOR_S1_GaN_ISO_L2: C209_L2.2 R278_L2.1 U33_L2.6 | length 40.9
  Top Layer w0.2: v1(118.5,96) 119.238,96 119.48,96.242 R278_L2.1@119.48,96.992 ; C209_L2.2@148.5,98.6 148.6,98.5 149.383,98.5 149.5,98.383 v1(149.5,97) 149.525,96.975 150.85,96.975 U33_L2.6@150.875,96.95
  Bottom Layer w0.2: v1(118.5,96) 119.926,97.426 138.926,97.426 140,98.5 140,100 140.5,100.5 142.717,100.5 145.302,97.915 148.585,97.915 v1(149.5,97)
MONITOR_S1_GaN_ISO_L3: C209_L3.2 R278_L3.1 U33_L3.6 | length 40.8
  Top Layer w0.2: C209_L3.2@234.5,70.6 234.6,70.5 235.383,70.5 235.5,70.383 v1(235.5,69) 235.525,68.975 236.85,68.975 U33_L3.6@236.875,68.95
  Top Layer w0.254: v1(204.5,68) 205.537,69.037 205.537,68.935 205.486,68.986 R278_L3.1@205.48,68.992
  Bottom Layer w0.2: v1(204.5,68) 206,69.5 208.209,69.5 208.283,69.426 224.926,69.426 226,70.5 226,72 226.5,72.5 228.717,72.5 231.302,69.915 234.585,69.915 v1(235.5,69)
MONITOR_S1_GaN_ISO_N: C209_N.2 R278_N.1 U33_N.6 | length 41
  Top Layer w0.2: C209_N.2@122.9,35.5 123,35.6 123,36.383 123.117,36.5 v1(124.5,36.5) 124.525,36.525 124.525,37.85 U33_N.6@124.55,37.875 ; 125.231,6.537 125.5,6.269 v1(125.5,5.5)
  Top Layer w0.254: R278_N.1@124.508,6.48 124.565,6.537 125.231,6.537
  Bottom Layer w0.2: v1(124.5,36.5) 123.585,35.585 123.585,32.302 121,29.717 121,27.5 121.5,27 123,27 124,26 124,11.067 124.074,10.993 124.074,10.534 124,10.46 124,7 v1(125.5,5.5)
MONITOR_S2_GaN_ISO_L1: C207_L1.2 R291_L1.1 U33_L1.3 | length 17.4
  Top Layer w0.2: C207_L1.2@64.4,108 64.439,108.039 64.439,109.889 64.6,110.05 U33_L1.3@64.625,110.05 64.65,110.025 65.475,110.025 v1(65.5,110)
  Top Layer w0.254: v1(52.616,111.058) 52.616,112.066 R291_L1.1@52.66,112.111
  Bottom Layer w0.2: v1(52.616,111.058) 64.442,111.058 v1(65.5,110)
MONITOR_S2_GaN_ISO_L2: C207_L2.2 R291_L2.1 U33_L2.3 | length 17.4
  Top Layer w0.2: C207_L2.2@147.9,93 147.939,93.039 147.939,94.889 148.1,95.05 U33_L2.3@148.125,95.05 148.15,95.025 148.975,95.025 v1(149,95)
  Top Layer w0.254: v1(136.116,96.058) 136.116,97.066 R291_L2.1@136.16,97.111
  Bottom Layer w0.2: v1(136.116,96.058) 147.942,96.058 v1(149,95)
MONITOR_S2_GaN_ISO_L3: C207_L3.2 R291_L3.1 U33_L3.3 | length 17.4
  Top Layer w0.2: C207_L3.2@233.9,65 233.938,65.039 233.938,66.889 234.1,67.05 U33_L3.3@234.125,67.05 234.15,67.025 234.975,67.025 v1(235,67)
  Top Layer w0.254: v1(222.116,68.058) 222.116,69.066 R291_L3.1@222.16,69.111
  Bottom Layer w0.2: v1(222.116,68.058) 233.942,68.058 v1(235,67)
MONITOR_S2_GaN_ISO_N: C207_N.2 R291_N.1 U33_N.3 | length 17.4
  Top Layer w0.2: v1(126.5,36) 126.475,35.975 126.475,35.15 U33_N.3@126.45,35.125 126.45,35.1 126.65,34.9 C207_N.2@128.5,34.9
  Top Layer w0.254: R291_N.1@124.389,23.16 124.434,23.116 v1(125.442,23.116)
  Bottom Layer w0.2: v1(125.442,23.116) 125.442,34.942 v1(126.5,36)
MONITOR_S4_GaN_ISO_L1: C206_L1.2 R316_L1.1 U33_L1.1 | length 35.7
  Top Layer w0.2: U33_L1.1@64.625,111.95 64.81,111.765 65.235,111.765 65.5,111.5 65.717,111.5 66.054,111.163 v1(66.054,111) 66.054,108.254 C206_L1.2@66,108.2
  Top Layer w0.254: v1(90.718,110.142) 90.718,111.147 R316_L1.1@90.725,111.155
  Bottom Layer w0.2: v1(66.054,111) 66.609,111.555 66.609,114.109 67.5,115 70.5,115 73.545,111.955 86.762,111.955 86.771,111.946 87.229,111.946 87.238,111.955 89.073,111.955 90.659,110.37 90.659,110.201 v1(90.718,110.142)
MONITOR_S4_GaN_ISO_L2: C206_L2.2 R316_L2.1 U33_L2.1 | length 37.7
  Top Layer w0.2: U33_L2.1@148.125,96.95 148.31,96.765 148.951,96.765 150,95.717 150,94.813 149.5,94.313 v1(149.5,94) C206_L2.2@149.5,93.2
  Top Layer w0.254: v1(174.218,95.142) 174.218,96.147 R316_L2.1@174.225,96.155
  Bottom Layer w0.2: v1(149.5,94) 150.054,94.554 150.054,99.054 150.5,99.5 154,99.5 156.913,96.587 170.064,96.587 170.105,96.546 172.982,96.546 174.159,95.37 174.159,95.201 v1(174.218,95.142)
MONITOR_S4_GaN_ISO_L3: C206_L3.2 R316_L3.1 U33_L3.1 | length 38
  Top Layer w0.2: U33_L3.1@234.125,68.95 234.31,68.765 234.735,68.765 235,68.5 235.217,68.5 236,67.717 236,66.813 235.5,66.313 235.5,66 ; C206_L3.2@235.5,65.2 235.5,66 ; v1(236,66) 235.5,66
  Top Layer w0.254: v1(260.218,67.142) 260.218,68.147 R316_L3.1@260.225,68.155
  Bottom Layer w0.2: v1(236,66) 236.054,66.054 236.054,71.054 236.5,71.5 240,71.5 242.545,68.955 258.573,68.955 260.159,67.37 260.159,67.201 v1(260.218,67.142)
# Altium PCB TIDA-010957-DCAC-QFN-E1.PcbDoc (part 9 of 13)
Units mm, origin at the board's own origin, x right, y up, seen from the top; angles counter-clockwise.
Board outline 300 x 300 mm, 4 copper layers (Top Layer, Layer 1, Layer 2, Bottom Layer), stack 1.787 mm thick; 1286 components, 677 nets, 4169 pads, 3428 vias.

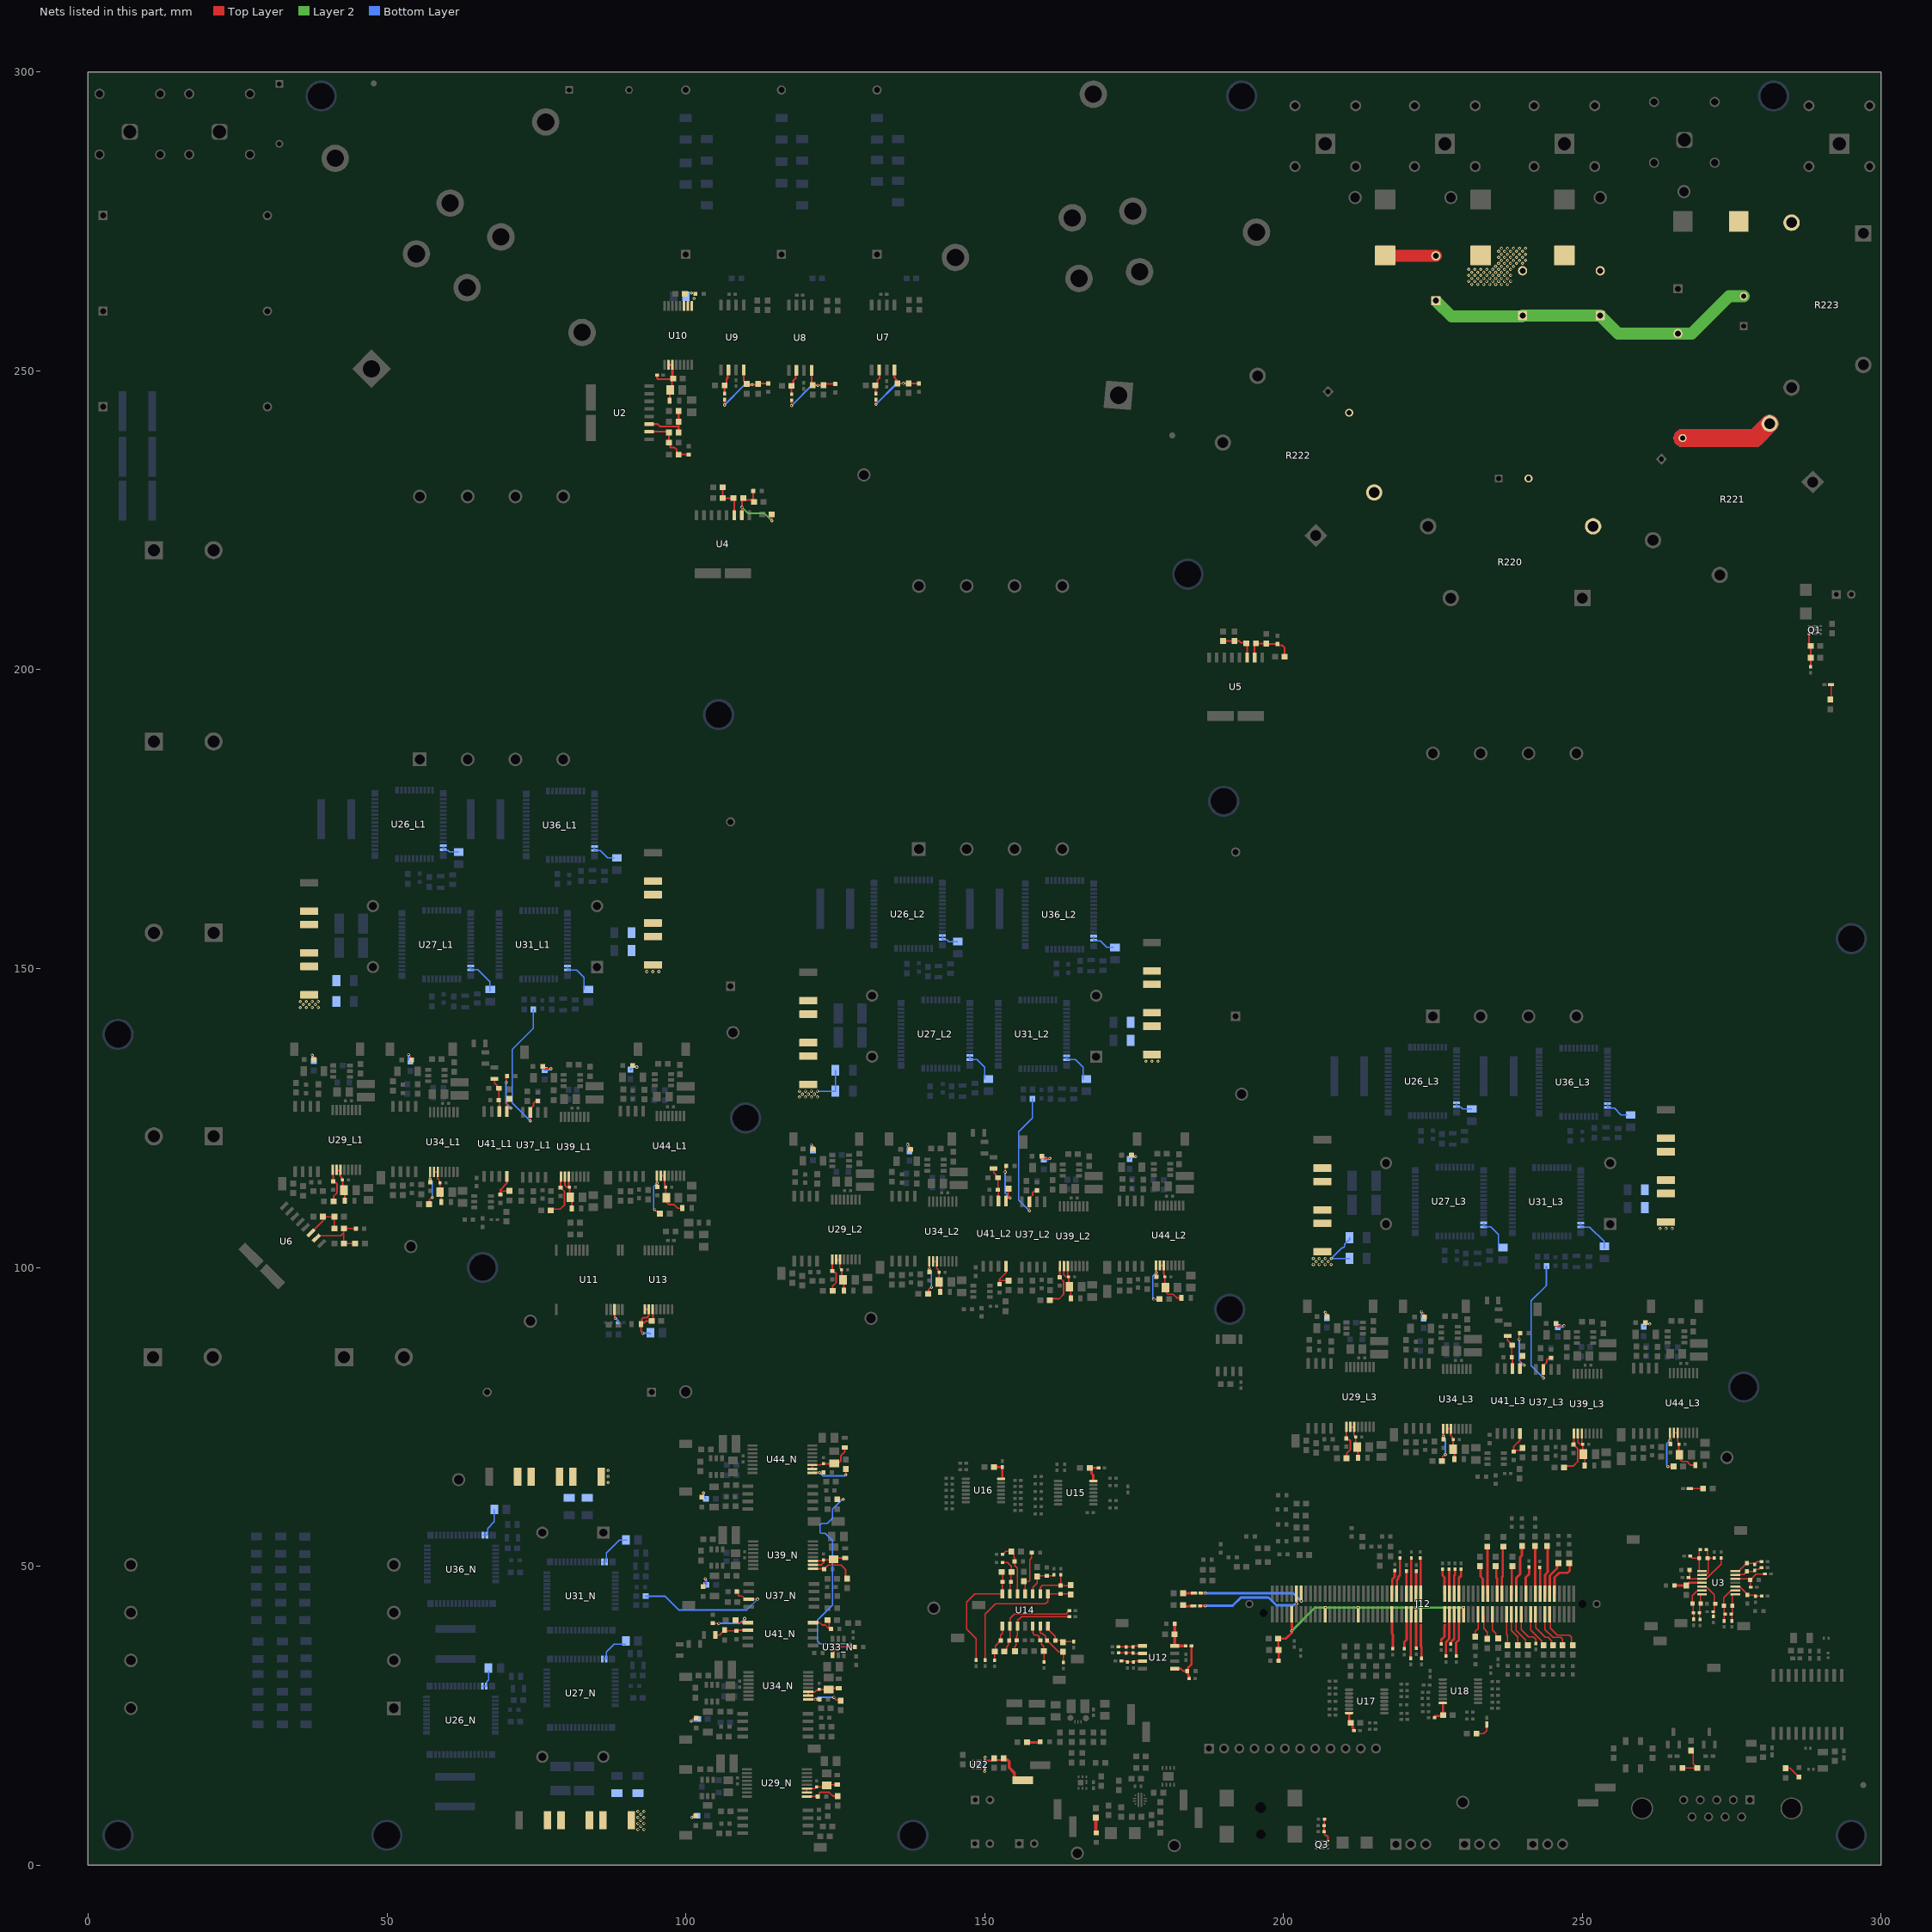
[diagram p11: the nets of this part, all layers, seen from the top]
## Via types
v1: diameter 0.508, hole 0.254, Top Layer to Bottom Layer, tented both sides, 3428 vias

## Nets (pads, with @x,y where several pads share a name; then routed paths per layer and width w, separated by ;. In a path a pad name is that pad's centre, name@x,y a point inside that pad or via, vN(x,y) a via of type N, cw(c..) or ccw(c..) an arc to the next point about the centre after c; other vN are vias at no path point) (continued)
MONITOR_S4_GaN_ISO_N: C206_N.2 R316_N.1 U33_N.1 | length 40.3
  Top Layer w0.2: U33_N.1@124.55,35.125 124.735,35.31 124.735,35.735 125,36 125,36.217 125.337,36.554 127.133,36.554 127.187,36.5 127.5,36.5 ; v1(127.5,37) 127.5,36.5 ; C206_N.2@128.3,36.5 127.5,36.5
  Top Layer w0.254: R316_N.1@125.345,61.225 125.353,61.218 v1(126.358,61.218)
  Bottom Layer w0.2: v1(126.358,61.218) 126.299,61.159 126.13,61.159 124.545,59.573 124.545,58 124.5,58 123.701,57.201 122.745,57.201 122.5,56.956 122.5,55.617 122.617,55.5 123.32,55.5 124.545,54.275 124.545,43.545 122,41 122,37.5 122.446,37.054 127.446,37.054 v1(127.5,37)
NetC15_2: C15.2 C16.1 FB1.2 J12.48 J12.84 J12.98 J12.112 | length 42.9
  Top Layer w0.4: C15.2@199.1,37.9 200.4,37.9 201.4,38.9 v1(201.4,39.2) 201.4,41.1 J12.112@201.3,41.2 ; C15.2@199.15,37.85 199.15,36.05 C16.1@199.2,36 ; FB1.2@199.2,34.2 199.2,35.9 C16.1@199.4,36.1 ; J12.98@206.9,42 207,42.1 v1(207,43.1) ; v1(212.5,43.1) 212.525,43.075 212.525,42.025 J12.84@212.55,42 ; J12.48@230.1,41.7 v1(230.1,43.1)
  Layer 2 w0.4: v1(201.4,39.2) 205.3,43.1 v1(212.5,43.1) v1(230.1,43.1)
NetC28_1: C28.1 Q1.3 R96.2 R97.2 | length 5.8
  Top Layer w0.3: C28.1@287.9,204 287.93,204.03 Q1.3@287.93,206 ; R96.2@288.2,200.5 R97.2@288.2,202 288.2,204.1 C28.1@288.3,204.2
NetC29_1: C29.1 R98.1 R100.1 U3.5 | length 6.6
  Top Layer w0.2: U3.5@270,46.6 270.075,46.525 270.795,46.525 272.1,45.22 C29.1@272.1,43.6 ; R100.1@271.9,41.6 R98.1@271.9,42.4 271.95,42.4 272.1,42.55 272.1,43.578 C29.1@272.249,43.726
NetC30_1: C30.1 FB2.2 R99.2 R104.2 U2.4 | length 10.1
  Top Layer w0.3: U2.4@93.875,239.825 97.175,239.825 R104.2@97.3,239.7 ; R104.2@97.1,239.8 R104.2@97.2,239.7 C30.1@97.2,238 97.376,237.824 97.376,237.2 98.1,237.2 98.5,236.8 98.5,236.3 R99.2@98.8,236 FB2.2@100.5,236
NetC32_1: C32.1 R101.1 R103.1 U3.7 | length 4.5
  Top Layer w0.2: R101.1@269.65,40.997 269.65,43.625 C32.1@269.816,43.791 ; C32.1@269.8,43.791 269.8,45.225 269.875,45.3 U3.7@270,45.3
NetC32_2: C32.2 R102.1 R103.2 U3.6 | length 5.9
  Top Layer w0.2: C32.2@268.4,43.791 268.4,45.07 269.205,45.875 269.925,45.875 U3.6@270,45.95 ; C32.2@268.416,43.791 268.55,43.657 268.55,42.25 R103.2@268.6,42.2 R102.1@268.6,41.195
NetC34_1: C34.1 R104.1 R105.2 U2.5 | length 8.5
  Top Layer w0.3: U2.5@94,241.1 95.3,241.1 95.7,240.7 96.53,240.7 96.555,240.675 97.845,240.675 97.87,240.7 98.8,240.7 ; R104.1@98.8,239.7 98.8,240.7 ; C34.1@98.8,243.2 R105.2@98.8,241.5 98.8,240.7
NetC35_1: C35.1 R106.1 R107.1 U3.10 | length 5.2
  Top Layer w0.2: U3.10@275.6,46.6 275.675,46.525 276.395,46.525 277.367,45.552 277.367,45.432 C35.1@277.617,45.182 278.846,45.182 278.996,45.032 R106.1@278.996,44.985 279.011,45 R107.1@280,45
NetC36_1: C36.1 FB3.2 R109.2 R112.2 U4.4 | length 13.3
  Top Layer w0.3: U4.4@109.384,225.875 109.392,225.883 109.392,227.192 v1(109.4,227.2) R112.2@109.4,228.4 ; R112.2@109.5,228.4 111.1,228.4 C36.1@111.3,228.2 ; C36.1@111.2,228.1 C36.1@111.3,228.2 ; FB3.2@111.3,229.9 C36.1@111.3,228.2 ; v1(114.4,224.9) R109.2@114.4,226
  Layer 2 w0.3: v1(109.4,227.2) 110.4,226.2 113.1,226.2 v1(114.4,224.9)
NetC38_1: C38.1 R108.1 R111.1 U3.8 | length 5.1
  Top Layer w0.2: R111.1@274.863,41.95 275.063,42.15 275.063,43.383 C38.1@275.089,43.409 275.089,45.225 275.164,45.3 U3.8@275.6,45.3 ; R111.1@274.9,42 275.05,41.85 R108.1@275.05,40.863
NetC38_2: C38.2 R110.1 R111.2 U3.9 | length 6.3
  Top Layer w0.2: R110.1@273.75,40.863 273.75,43.349 C38.2@273.689,43.409 273.689,44.759 274.805,45.875 275.525,45.875 U3.9@275.6,45.95
NetC40_1: C40.1 R112.1 R113.2 U4.5 | length 6.6
  Top Layer w0.3: C40.1@105.9,230.6 106.2,230.3 R113.2@106.2,228.7 R112.1@108,228.7 ; U4.5@108.114,225.875 R112.1@108.114,228.7
NetC41_1: C41.1 R114.1 R115.1 U3.12 | length 6.7
  Top Layer w0.2: U3.12@275.6,47.9 277.919,47.9 C41.1@278.1,47.719 ; R114.1@278.185,46.5 278.1,46.585 C41.1@278.1,47.719 ; R115.1@280.567,48.7 279.081,48.7 C41.1@278.1,47.719
NetC42_1: C42.1 FB4.2 R117.2 R120.2 U5.4 | length 9.2
  Top Layer w0.3: U5.4@195.175,202.04 195.175,204.575 R120.2@195.3,204.7 ; R120.2@195.5,204.3 195.6,204.4 C42.1@197.1,204.4 ; C42.1@197.1,204.3 FB4.2@199,204.3 199.2,204.1 199.8,204.1 200.2,203.7 R117.2@200.2,202.2
NetC44_1: C44.1 R116.1 R119.1 U3.14 | length 5.3
  Top Layer w0.2: U3.14@275.6,49.2 276.225,49.2 276.3,49.275 276.3,49.313 C44.1@277.537,50.55 277.587,50.5 278.65,50.5 R119.1@278.8,50.35 ; R119.1@278.8,50.3 R119.1@278.8,50.35 ; R116.1@279.993,50.8 279.25,50.8 R119.1@278.8,50.35
NetC44_2: C44.2 R118.1 R119.2 U3.13 | length 4.9
  Top Layer w0.2: U3.13@275.6,48.55 275.675,48.625 277.012,48.625 C44.2@277.537,49.15 278.65,49.15 R119.2@278.8,49.3 278.8,49.35 278.95,49.5 279.496,49.5 279.746,49.75 R118.1@279.993,49.75
NetC46_1: C46.1 R120.1 R121.2 U5.5 | length 6.4
  Top Layer w0.3: R121.2@189.9,204.8 C46.1@191.8,204.8 192.6,204.8 192.9,204.5 R120.1@193.7,204.5 ; R120.1@193.8,204.4 193.905,204.295 U5.5@193.905,202.04 193.905,202.005 U5.5@193.9,202
NetC47_2: C47.2 FB5.2 U3.4 | length 4.8
  Top Layer w0.4: FB5.2@265.4,46.8 C47.2@267.4,46.8 267.4,46.825 267.825,47.25 U3.4@270,47.25
NetC48_1: C48.1 R122.1 R124.1 U3.3 | length 8.9
  Top Layer w0.2: R122.1@267.75,48.119 R122.1@267.8,48.119 ; C48.1@267.95,49.4 267.95,48.269 R122.1@267.8,48.119 ; R124.1@273.2,51.4 273.2,50.38 270.795,47.975 270.075,47.975 U3.3@270,47.9 268.019,47.9 R122.1@267.8,48.119
NetC49_1: C49.1 FB6.2 R123.2 R128.2 U6.4 | length 11.5
  Top Layer w0.2: U6.4@38.308,104.908 U6.4@38.192,104.908 38.563,105.28 42.28,105.28 42.8,105.8 ; C49.1@44.7,104 R123.2@42.8,104 42.8,105.8 ; FB6.2@44.8,106.5 R128.2@42.8,106.5 42.8,105.8
NetC51_1: C51.1 R125.1 R127.1 U3.1 | length 5.8
  Top Layer w0.2: R125.1@268.05,51.684 268.1,51.684 268.438,51.346 C51.1@269.55,51.346 ; R127.1@269.75,52.807 269.7,52.807 269.55,52.657 269.55,52.607 C51.1@269.55,51.346 ; U3.1@270,49.2 269.625,49.2 269.55,49.275 C51.1@269.55,51.346
NetC51_2: C51.2 R126.1 R127.2 U3.2 | length 6.5
  Top Layer w0.2: U3.2@270,48.55 270.075,48.625 270.795,48.625 271.1,48.93 271.1,51.196 C51.2@270.95,51.346 ; R127.2@270.75,52.807 270.8,52.807 270.95,52.657 C51.2@270.95,51.346 ; R126.1@272.1,51.4 272.046,51.346 C51.2@270.95,51.346
NetC53_1: C53.1 R128.1 R129.2 U6.5 | length 7.4
  Top Layer w0.2: U6.5@37.294,105.807 39.3,107.812 C53.1@39.3,108.5 R129.2@41.2,108.5 R128.1@41.2,106.5
NetC56_2: C56.2 C57.1 FB7.1 R131.2 U7.8 | length 12.9
  Top Layer w0.3: v1(131.8,244.4) R131.2@131.8,245.2 ; U7.8@134.91,250.15 134.91,248.89 135.2,248.6 C56.2@135.2,247.87 ; C56.2@135.4,247.8 135.5,247.9 v1(136.4,247.9) 137,247.9 FB7.1@139,247.9
  Bottom Layer w0.3: v1(131.8,244.4) 135.3,247.9 v1(136.4,247.9)
NetC60_1: C60.1 R131.1 U7.6 | length 3.8
  Top Layer w0.3: R131.1@131.8,246.2 131.8,247.5 C60.1@131.9,247.6 ; C60.1@131.812,247.687 132.05,247.925 132.05,248.45 132.4,248.8 U7.6@132.4,249.8
NetC63_2: C63.2 C64.1 FB8.1 R133.2 U8.8 | length 12.3
  Top Layer w0.3: v1(117.7,244.2) R133.2@117.7,245.1 ; C63.2@121,247.8 121.04,247.84 U8.8@121.04,250.1 ; C63.2@121.5,247.6 v1(122.1,247.6) ; v1@122.2,247.6 123.017,247.6 C64.1@123.02,247.602 ; C64.1@123.1,247.8 FB8.1@125,247.8
  Bottom Layer w0.3: v1(117.7,244.2) 121.1,247.6 v1(122.1,247.6)
NetC67_1: C67.1 R133.1 U8.6 | length 4.2
  Top Layer w0.3: R133.1@117.7,246.1 C67.1@117.7,247.5 118,247.8 118,248.424 118.176,248.6 118.224,248.6 118.374,248.75 118.374,249.674 U8.6@118.6,249.9
NetC70_2: C70.2 C71.1 FB9.1 R135.2 U9.8 | length 12.6
  Top Layer w0.3: v1(106.5,244.3) 106.5,245.1 R135.2@106.6,245.2 ; U9.8@109.675,250.15 109.675,248.35 110.2,247.825 C70.2@110.2,247.8 ; C70.2@110.5,247.8 110.5,247.725 110.525,247.7 v1(111.1,247.7) C71.1@111.8,247.7 ; C71.1@112.4,247.7 112.4,247.875 112.425,247.9 FB9.1@113.8,247.9
  Bottom Layer w0.3: v1(106.5,244.3) 109.9,247.7 v1(111.1,247.7) v1@111.2,247.7
NetC74_1: C74.1 R135.1 U9.6 | length 3.9
  Top Layer w0.3: R135.1@106.5,246.2 106.5,247.4 C74.1@106.7,247.6 ; C74.1@106.612,247.688 106.85,247.925 106.85,248.65 106.999,248.799 106.999,249.799 U9.6@107.1,249.9
NetC75_1: C75.1 C76.1 FB10.2 U10.9 U10.10 U10.11
  other v1: 101.375,262.079 100.966,263.045
NetC77_1: C77.1 C78.1 L7.1 R136.1 U10.2 U10.3 | length 10
  Top Layer w0.2: C77.1@97.75,248.85 C77.1@97.9,248.7
  Top Layer w0.3: R136.1@95.1,249.3 95.2,249.2 95.2,248.776 95.376,248.6 C77.1@97.7,248.6 ; L7.1@97.3,245 C78.1@97.3,246.6 ; C78.1@97.384,246.8 97.7,247.116 C77.1@97.7,248.6 ; C77.1@97.7,248.7 C77.1@97.7,248.6 ; C77.1@97.9,248.7 97.8,248.6 C77.1@97.7,248.6
  Top Layer w0.4: U10.2@97.1,251 U10.3@97.75,251 C77.1@97.75,248.85
NetC82_1: C82.1 FB16.1 R331.1 U12.8 | length 5.5
  Top Layer w0.45: FB16.1@181.8,40.4 C82.1@181.8,38.6 U12.8@181.8,36.68 R331.1@183.621,36.68
NetC83_2: C83.2 R137.1 R139.1 U12.3 | length 3.6
  Top Layer w0.2: R139.1@172.883,34.14 173.76,34.14 C83.2@173.9,34 R137.1@174.9,34 175.04,34.14 U12.3@176.4,34.14
NetC85_2: C85.2 U11.4 | length 2
  Top Layer w0.3: U11.4@88.154,92.5 88.141,92.486 88.141,91.559 v1(88.2,91.5)
  Bottom Layer w0.3: v1(88.2,91.5) 88.284,91.5 88.684,91.1 88.684,90.816 C85.2@88.7,90.8
NetC86_1: C86.1 R141.1 R142.1 U12.2 | length 4.1
  Top Layer w0.2: R141.1@172.4,35.5 173.977,35.5 ; C86.1@173.905,35.513 R142.1@174.85,35.513 174.953,35.41 U12.2@176.4,35.41
NetC86_2: C86.2 R140.1 R142.2 U12.1 | length 4.2
  Top Layer w0.2: R140.1@172.383,36.513 173.99,36.513 ; C86.2@173.905,36.513 R142.2@174.85,36.513 ; R142.2@174.85,36.53 175,36.68 U12.1@176.4,36.68
NetC89_1: C89.1 C90.1 L8.1 U13.9 U13.10 U13.11 | length 10.5
  Top Layer w0.3: v1(92.8,89) 92.8,89.084 92.5,89.384 L8.1@92.5,90.5 92.632,90.632 L8.1@92.632,90.71 ; U13.9@93.163,93.004 93.796,93.004 U13.10@93.8,93 ; U13.10@93.8,92.6 93.8,91.9 93.5,91.6 92.884,91.6 92.632,91.348 L8.1@92.632,90.71 ; C90.1@94.3,91 93.33,91 93.108,90.778 92.7,90.778 L8.1@92.632,90.71 ; C90.1@94.313,91.033 94.5,91.22 U13.11@94.5,93.2
  Bottom Layer w0.3: v1(92.8,89) 93.9,89 C89.1@94,88.9
NetC94_1: C94.1 FB11.2 U14.4 | length 8
  Top Layer w0.2: U14.4@156.77,45.384 156.77,47.269 156.61,47.429 156.681,47.5 157.467,47.5 157.584,47.617 157.584,51.1 157.884,51.4 FB11.2@157.884,52.3
NetC95_2: C95.2 R144.1 R145.1 U14.3 | length 6.2
  Top Layer w0.2: U14.3@158.04,45.384 158.04,46.456 158.784,47.2 R144.1@158.784,48.3 158.884,48.4 C95.2@160.384,48.4 160.388,48.404 161.461,48.404 161.611,48.554 R145.1@161.611,48.604
NetC97_1: C97.1 R147.1 R148.2 U14.2 | length 8.2
  Top Layer w0.2: U14.2@159.31,45.384 159.31,46.426 159.684,46.8 162.687,46.8 C97.1@162.703,46.784 ; R147.1@162.774,48.609 162.774,46.854 C97.1@162.703,46.784 ; R148.2@164.392,46.884 164.292,46.784 C97.1@162.703,46.784
NetC97_2: C97.2 R146.1 R148.1 U14.1 | length 24.1
  Top Layer w0.2: R146.1@150.084,34.3 150.084,42 151.784,43.7 160.184,43.7 160.58,44.096 U14.1@160.58,45.384 C97.2@162.703,45.384 R148.1@164.292,45.384
NetC98_2: C98.2 R149.1 R150.1 U14.5 | length 9.2
  Top Layer w0.2: R150.1@153.004,52 153.054,52 153.529,52.475 R149.1@154.475,52.475 154.5,52.475 154.875,52.1 154.875,51.509 155.016,51.368 C98.2@155.016,50.829 155.016,50.168 155.5,49.684 U14.5@155.5,45.384
NetC100_1: C100.1 R152.1 R153.2 U14.6 | length 6.5
  Top Layer w0.2: R152.1@153.004,50.663 153.821,50.663 154.479,50.005 R153.2@154.479,49.051 154.399,48.971 C100.1@154.399,47.401 154.23,47.232 U14.6@154.23,45.384
NetC100_2: C100.2 R151.1 R153.1 U14.7 | length 20.6
  Top Layer w0.2: R151.1@148.584,34.3 148.584,37.916 147,39.5 147,44 148.384,45.384 U14.7@152.96,45.384 152.96,47.362 C100.2@152.999,47.401 152.999,48.931 R153.1@152.879,49.051
NetC101_2: C101.2 R154.1 R155.1 U14.10 | length 14.3
  Top Layer w0.2: R154.1@155.057,35.784 155.057,36.573 155.284,36.8 155.284,37.549 C101.2@155.36,37.625 155.36,38.276 155.5,38.416 U14.10@155.5,39.984 155.5,40.916 156.184,41.6 R155.1@164.184,41.6
NetC103_1: C103.1 R157.1 R158.2 U14.9 | length 16.4
  Top Layer w0.2: R158.2@153.304,35.741 153.309,35.741 153.684,36.116 153.684,36.5 153.984,36.8 153.984,37.462 C103.1@154.104,37.583 154.23,37.709 U14.9@154.23,39.984 154.284,40.037 154.284,41.3 154.984,42 163.584,42 R157.1@164.184,42.6
NetC103_2: C103.2 R156.1 R158.1 U14.8 | length 6.3
  Top Layer w0.2: R156.1@151.64,34.275 151.64,35.678 R158.1@151.704,35.741 151.784,35.821 151.784,36.662 C103.2@152.704,37.583 152.684,37.603 152.684,38.5 152.96,38.776 U14.8@152.96,39.984
NetC104_2: C104.2 R159.1 R160.1 U14.12 | length 7.1
  Top Layer w0.2: U14.12@158.04,39.984 158.04,38.844 158.384,38.5 158.884,38.5 159.184,38.2 159.184,37.782 C104.2@159.341,37.625 159.542,37.424 159.542,36.942 159.884,36.6 R159.1@159.884,35.8 159.949,35.735 R160.1@159.949,33.975
NetC106_1: C106.1 R162.1 R163.2 U14.13 | length 8.3
  Top Layer w0.2: U14.13@159.31,39.984 159.31,38.917 159.427,38.8 159.684,38.8 160.244,38.24 160.244,37.784 C106.1@160.445,37.583 162.379,35.648 163.184,35.648 R162.1@163.184,33.9
NetC106_2: C106.2 R161.1 R163.1 U14.14 | length 6.2
  Top Layer w0.2: U14.14@160.58,39.984 160.58,39.509 161.084,39.005 161.084,39 161.845,38.239 C106.2@161.845,37.583 ; C106.2@161.784,37.521 C106.2@161.845,37.583 ; R161.1@164.884,37.4 163.215,37.4 R163.1@163.124,37.309 162.85,37.583 C106.2@161.845,37.583
NetC107_1: C107.1 R164.1 U15.14 | length 3.9
  Top Layer w0.4: C107.1@167.568,66.466 C107.1@167.593,66.466 ; U15.14@168.189,64.268 168.189,65.245 167.868,65.566 167.868,66.191 C107.1@167.593,66.466 ; R164.1@169.068,66.466 C107.1@167.593,66.466
NetC113_1: C113.1 R174.1 U16.14 | length 3.2
  Top Layer w0.4: C113.1@151.563,66.612 R174.1@152.863,66.612 ; U16.14@152.963,64.712 R174.1@152.963,66.612
NetC114_1: C114.1 R175.1 U17.14 | length 3
  Top Layer w0.4: U17.14@211,25.3 211,24.048 C114.1@211.266,23.781 ; C114.1@211.4,23.7 211.566,23.534 211.566,23.034 211.7,22.9 211.7,22.55 211.75,22.5 R175.1@211.8,22.5
NetC125_1: C125.1 R194.1 U18.14 | length 3.4
  Top Layer w0.4: R194.1@225.3,24.9 225.35,24.95 C125.1@226.65,24.95 ; C125.1@226.7,25.1 U18.14@226.7,27.1
NetC138_1: C138.1 C144.1 J18.2 U22.4 U22.6 | length 12.9
  Top Layer w0.2: v1@149.975,15.626 v1(150,15.651) 150.025,15.676 U22.4@150.025,16.176 ; U22.6@150.025,17.476 150.025,17.951 v1(150.1,18.026) ; C144.1@151.287,17.562 151.6,17.875 C144.1@151.6,17.9 ; J18.2@155.293,14.205 J18.2@156.373,14.205
  Top Layer w0.3: U22.4@150.025,16.176 U22.4@150.1,16.176 ; U22.6@150.025,17.476 151.201,17.476 151.287,17.562 C138.1@152.862,17.562
  Top Layer w0.5: C138.1@153.2,17.9 153.2,17.875 153.425,17.65 153.832,17.65 154.125,17.357 154.125,16.3 155,15.425 155,14.498 J18.2@155.293,14.205
  Bottom Layer w0.2: v1(150,15.651) 150,17.842 150.1,17.942 v1(150.1,18.026)
NetC157_2: C157.2 R226.1 R227.2 | length 5.9
  Top Layer w0.2: R226.1@266.75,16.25 R227.2@269.225,16.25 ; C157.2@268.2,19.2 268.526,18.874 268.526,16.949 R227.2@269.225,16.25 ; R227.2@269.25,16.25 R227.2@269.225,16.25
NetC164_L1_1: C164_L1.1 U26_L1.40 U26_L1.41 | length 3.4
  Bottom Layer w0.2: U26_L1.40@59.45,170.55 U26_L1.41@59.45,169.9 59.575,169.775 60.225,169.775 60.5,169.5 61.984,169.5 C164_L1.1@62,169.516
NetC164_L2_1: C164_L2.1 U26_L2.40 U26_L2.41 | length 3.4
  Bottom Layer w0.2: U26_L2.40@142.95,155.55 U26_L2.41@142.95,154.9 143.075,154.775 143.725,154.775 144,154.5 145.484,154.5 C164_L2.1@145.5,154.516
NetC164_L3_1: C164_L3.1 U26_L3.40 U26_L3.41 | length 3.4
  Bottom Layer w0.2: U26_L3.40@228.95,127.55 U26_L3.41@228.95,126.9 229.075,126.775 229.725,126.775 230,126.5 231.484,126.5 C164_L3.1@231.5,126.516
NetC164_N_1: C164_N.1 U26_N.40 U26_N.41 | length 3.4
  Bottom Layer w0.2: U26_N.40@65.95,29.95 U26_N.41@66.6,29.95 66.725,30.075 66.725,30.725 67,31 67,32.484 C164_N.1@66.984,32.5
NetC166_L1_1: C166_L1.1 U27_L1.40 U27_L1.41 | length 6.3
  Bottom Layer w0.2: U27_L1.40@64,150.45 U27_L1.41@64,149.8 65.2,149.8 67.2,147.8 C166_L1.1@67.2,146.218
NetC166_L2_1: C166_L2.1 U27_L2.40 U27_L2.41 | length 5.7
  Bottom Layer w0.2: U27_L2.40@147.5,135.45 U27_L2.41@147.5,134.8 148.7,134.8 150,133.5 C166_L2.1@150,131.516
NetC166_L3_1: C166_L3.1 U27_L3.40 U27_L3.41 | length 5.7
  Bottom Layer w0.2: U27_L3.40@233.5,107.45 U27_L3.41@233.5,106.8 234.7,106.8 236,105.5 C166_L3.1@236,103.516
NetC166_N_1: C166_N.1 U27_N.40 U27_N.41 | length 5.7
  Bottom Layer w0.2: U27_N.40@86.05,34.5 U27_N.41@86.7,34.5 86.7,35.7 88,37 C166_N.1@89.984,37
NetC167_L1_1: C167_L1.1 U31_L1.40 U31_L1.41 | length 5.9
  Bottom Layer w0.2: U31_L1.40@80.225,150.425 U31_L1.41@80.225,149.775 81.725,149.775 83,148.5 C167_L1.1@83,146.516
NetC167_L2_1: C167_L2.1 U31_L2.40 U31_L2.41 | length 5.9
  Bottom Layer w0.2: U31_L2.40@163.725,135.425 U31_L2.41@163.725,134.775 165.225,134.775 166.5,133.5 C167_L2.1@166.5,131.516
NetC167_L3_1: C167_L3.1 U31_L3.40 U31_L3.41 | length 6.8
  Bottom Layer w0.2: U31_L3.40@249.725,107.425 U31_L3.41@249.725,106.775 251.225,106.775 253.666,104.334 253.666,103.222 C167_L3.1@253.7,103.188
NetC167_N_1: C167_N.1 U31_N.40 U31_N.41 | length 6.5
  Bottom Layer w0.2: U31_N.40@86.075,50.725 U31_N.41@86.725,50.725 86.725,52.225 88.9,54.4 C167_N.1@90.194,54.4
NetC170_L1_1: C170_L1.1 U36_L1.40 U36_L1.41 | length 4.4
  Bottom Layer w0.2: U36_L1.40@84.725,170.425 U36_L1.41@84.725,169.775 85.725,169.775 86.967,168.533 87.983,168.533 C170_L1.1@88,168.516
NetC170_L2_1: C170_L2.1 U36_L2.40 U36_L2.41 | length 4.4
  Bottom Layer w0.2: U36_L2.40@168.225,155.425 U36_L2.41@168.225,154.775 168.35,154.65 169.35,154.65 170.467,153.533 171.483,153.533 C170_L2.1@171.5,153.516
NetC170_L3_1: C170_L3.1 U36_L3.40 U36_L3.41 | length 4.4
  Bottom Layer w0.2: U36_L3.40@254.225,127.425 U36_L3.41@254.225,126.775 254.35,126.65 255.35,126.65 256.467,125.533 257.483,125.533 C170_L3.1@257.5,125.516
NetC170_N_1: C170_N.1 U36_N.40 U36_N.41 | length 5.4
  Bottom Layer w0.2: U36_N.40@66.075,55.225 U36_N.41@66.725,55.225 66.85,55.35 66.85,56.35 67.967,57.467 67.967,59.483 C170_N.1@67.984,59.5
NetC196_L1_2: C196_L1.2 R287_L1.1 U29_L1.1 | length 6
  Top Layer w0.254: U29_L1.1@40.922,116.35 40.997,116.275 C196_L1.2@40.997,114.405 41.22,114.182 41.511,114.182 41.674,114.019 41.674,112.495 41.063,111.883 R287_L1.1@41.063,111.083
NetC196_L2_2: C196_L2.2 R287_L2.1 U29_L2.1 | length 5.9
  Top Layer w0.254: U29_L2.1@124.497,101.25 C196_L2.2@124.497,99.405 124.72,99.182 125.011,99.182 125.174,99.019 125.174,97.495 124.563,96.883 R287_L2.1@124.563,96.083
NetC196_L3_2: C196_L3.2 R287_L3.1 U29_L3.1 | length 5.9
  Top Layer w0.254: U29_L3.1@210.497,73.25 C196_L3.2@210.497,71.405 210.72,71.182 211.011,71.182 211.174,71.019 211.174,69.495 210.563,68.883 R287_L3.1@210.563,68.083
NetC196_N_2: C196_N.2 R287_N.1 U29_N.1 | length 5.9
  Top Layer w0.254: U29_N.1@120.25,11.497 C196_N.2@122.095,11.497 122.318,11.72 122.318,12.011 122.481,12.174 124.005,12.174 124.617,11.563 R287_N.1@125.417,11.563
NetC198_L1_1: C198_L1.1 C199_L1.2 L11_L1.1 U29_L1.2 U29_L1.3 | length 5.5
  Top Layer w0.254: U29_L1.2@41.647,116.25 42.122,116.25 42.122,115.346 42.465,115.003 42.465,114.753 C199_L1.2@42.588,114.63 42.588,113.464 42.822,113.23 42.963,113.089 L11_L1.1@42.963,111.558
NetC198_L2_1: C198_L2.1 C199_L2.2 L11_L2.1 U29_L2.2 U29_L2.3 | length 5.6
  Top Layer w0.254: U29_L2.2@125.147,101.25 125.797,101.25 125.788,101.241 125.788,99.93 C199_L2.2@126.088,99.63 126.088,98.464 126.322,98.23 126.463,98.089 L11_L2.1@126.463,96.558
NetC198_L3_1: C198_L3.1 C199_L3.2 L11_L3.1 U29_L3.2 U29_L3.3 | length 5.6
  Top Layer w0.254: U29_L3.2@211.147,73.25 211.797,73.25 211.788,73.241 211.788,71.93 C199_L3.2@212.088,71.63 212.088,70.464 212.322,70.23 212.463,70.089 L11_L3.1@212.463,68.558
NetC198_N_1: C198_N.1 C199_N.2 L11_N.1 U29_N.2 U29_N.3 | length 5.6
  Top Layer w0.254: U29_N.2@120.25,12.147 U29_N.3@120.25,12.797 120.259,12.788 121.57,12.788 C199_N.2@121.87,13.088 123.036,13.088 123.27,13.322 123.411,13.463 L11_N.1@124.942,13.463
NetC219_L1_2: C219_L1.2 R298_L1.1 U34_L1.1 | length 6.5
  Top Layer w0.254: R298_L1.1@57.025,110.583 57.121,110.68 57.121,111.308 57.515,111.702 v1(57.584,111.702) ; U34_L1.1@57.225,116 57.238,115.988 v1(57.238,114.782) 57.238,114.142 C219_L1.2@57.25,114.13
  Bottom Layer w0.254: v1(57.238,114.782) 57.238,114.713 57.584,114.367 v1(57.584,111.702)
NetC219_L2_2: C219_L2.2 R298_L2.1 U34_L2.1 | length 6.5
  Top Layer w0.254: R298_L2.1@140.525,95.583 140.621,95.68 140.621,96.308 141.015,96.702 v1(141.084,96.702) ; U34_L2.1@140.725,101 140.738,100.988 v1(140.738,99.782) 140.738,99.142 C219_L2.2@140.75,99.13
  Bottom Layer w0.254: v1(140.738,99.782) 140.738,99.713 141.084,99.367 v1(141.084,96.702)
NetC219_L3_2: C219_L3.2 R298_L3.1 U34_L3.1 | length 6.5
  Top Layer w0.254: R298_L3.1@226.525,67.583 226.621,67.68 226.621,68.308 227.015,68.702 v1(227.084,68.702) ; U34_L3.1@226.725,73 226.738,72.988 v1(226.738,71.782) 226.738,71.142 C219_L3.2@226.75,71.13
  Bottom Layer w0.254: v1(226.738,71.782) 226.738,71.713 227.084,71.367 v1(227.084,68.702)
NetC219_N_2: C219_N.2 R298_N.1 U34_N.1 | length 6.5
  Top Layer w0.254: U34_N.1@120.5,27.725 120.512,27.738 v1(121.718,27.738) 122.358,27.738 C219_N.2@122.37,27.75 ; v1(124.798,28.084) 124.798,28.015 125.192,27.621 125.82,27.621 R298_N.1@125.917,27.525
  Bottom Layer w0.254: v1(121.718,27.738) 121.787,27.738 122.133,28.084 v1(124.798,28.084)
NetC221_L1_1: C221_L1.1 C222_L1.2 L13_L1.1 U34_L1.2 U34_L1.3 | length 6
  Top Layer w0.254: U34_L1.2@57.875,116 U34_L1.3@58.525,116 58.447,115.922 58.447,114.914 58.771,114.59 58.771,114.304 C222_L1.2@58.894,114.182 58.894,112.598 C221_L1.1@58.884,112.588 59.094,112.379 L13_L1.1@59.094,110.934
NetC221_L2_1: C221_L2.1 C222_L2.2 L13_L2.1 U34_L2.2 U34_L2.3 | length 6
  Top Layer w0.254: U34_L2.2@141.375,101 U34_L2.3@142.025,101 141.947,100.922 141.947,99.914 142.271,99.59 142.271,99.304 C222_L2.2@142.394,99.182 142.394,97.598 C221_L2.1@142.384,97.588 142.594,97.379 L13_L2.1@142.594,95.934
NetC221_L3_1: C221_L3.1 C222_L3.2 L13_L3.1 U34_L3.2 U34_L3.3 | length 6
  Top Layer w0.254: U34_L3.2@227.375,73 U34_L3.3@228.025,73 227.947,72.922 227.947,71.914 228.271,71.59 228.271,71.304 C222_L3.2@228.394,71.182 228.394,69.598 C221_L3.1@228.384,69.588 228.594,69.379 L13_L3.1@228.594,67.934
NetC221_N_1: C221_N.1 C222_N.2 L13_N.1 U34_N.2 U34_N.3 | length 6
  Top Layer w0.254: U34_N.2@120.5,28.375 U34_N.3@120.5,29.025 120.578,28.947 121.586,28.947 121.91,29.271 122.196,29.271 C222_N.2@122.318,29.394 123.902,29.394 C221_N.1@123.912,29.384 124.121,29.594 L13_N.1@125.566,29.594
NetC227_L1_2: C227_L1.2 R232_L1.1 U37_L1.7 | length 25.6
  Top Layer w0.25: v1(73.994,124.5) U37_L1.7@73.994,125.95 73.994,125.994 U37_L1.7@74,126
  Top Layer w0.254: U37_L1.7@73.994,126 73.994,126.55 74.539,127.095 74.539,127.541 74.763,127.765 75.063,127.765 C227_L1.2@75.264,127.966
  Bottom Layer w0.254: v1(73.994,124.5) 70.975,127.519 70.975,136.475 74.5,140 R232_L1.1@74.5,143.2
NetC227_L2_2: C227_L2.2 R232_L2.1 U37_L2.7 | length 24.6
  Top Layer w0.25: v1(157.494,109.5) U37_L2.7@157.494,110.95 157.494,110.994 U37_L2.7@157.5,111
  Top Layer w0.254: U37_L2.7@157.494,111 157.494,111.55 158.039,112.095 158.039,112.541 158.263,112.765 158.563,112.765 C227_L2.2@158.764,112.966
  Bottom Layer w0.254: v1(157.494,109.5) 155.7,111.294 155.7,122.7 158,125 R232_L2.1@158,128.2
NetC227_L3_2: C227_L3.2 R232_L3.1 U37_L3.7 | length 24.8
  Top Layer w0.25: v1(243.494,81.5) U37_L3.7@243.494,82.95 243.494,82.994 U37_L3.7@243.5,83
  Top Layer w0.254: U37_L3.7@243.494,83 243.494,83.55 244.039,84.095 244.039,84.541 244.263,84.765 244.563,84.765 C227_L3.2@244.764,84.966
  Bottom Layer w0.254: v1(243.494,81.5) 241.419,83.575 241.419,94.419 244,97 R232_L3.1@244,100.2
NetC227_N_2: C227_N.2 R232_N.1 U37_N.7 | length 24.6
  Top Layer w0.25: U37_N.7@110.5,44.5 110.506,44.494 U37_N.7@110.55,44.494 v1(112,44.494)
  Top Layer w0.254: C227_N.2@108.534,45.764 108.735,45.563 108.735,45.263 108.959,45.039 109.405,45.039 109.95,44.494 U37_N.7@110.5,44.494
  Bottom Layer w0.254: R232_N.1@93.3,45 96.5,45 98.8,42.7 110.206,42.7 v1(112,44.494)
NetC236_L1_2: C236_L1.2 R308_L1.1 U39_L1.1 | length 7.7
  Top Layer w0.254: R308_L1.1@77.504,109.417 77.852,109.765 78.985,109.765 79.718,110.498 79.718,112.678 C236_L1.2@79.041,113.355 79.075,113.39 79.075,114.011 79.075,115.174 U39_L1.1@79.11,115.208
NetC236_L2_2: C236_L2.2 R308_L2.1 U39_L2.1 | length 7.7
  Top Layer w0.254: R308_L2.1@161.004,94.417 161.352,94.765 162.485,94.765 163.218,95.498 163.218,97.678 C236_L2.2@162.541,98.355 162.575,98.39 162.575,99.011 162.575,100.174 U39_L2.1@162.61,100.208
NetC236_L3_2: C236_L3.2 R308_L3.1 U39_L3.1 | length 7.7
  Top Layer w0.254: R308_L3.1@247.004,66.417 247.352,66.765 248.485,66.765 249.218,67.498 249.218,69.678 C236_L3.2@248.541,70.355 248.575,70.39 248.575,71.011 248.575,72.174 U39_L3.1@248.61,72.208
NetC236_N_2: C236_N.2 R308_N.1 U39_N.1 | length 7.7
  Top Layer w0.254: U39_N.1@121.292,49.61 121.326,49.575 122.489,49.575 123.11,49.575 C236_N.2@123.145,49.541 123.822,50.218 126.002,50.218 126.735,49.485 126.735,48.352 R308_N.1@127.083,48.004
NetC238_L1_1: C238_L1.1 C239_L1.2 L15_L1.1 U39_L1.2 U39_L1.3 | length 7.6
  Top Layer w0.254: U39_L1.2@79.76,115.208 79.76,113.782 80.11,113.432 C239_L1.2@80.56,113.432 ; U39_L1.3@80.41,115.208 80.41,113.582 C239_L1.2@80.56,113.432 ; L15_L1.1@80.91,110.142 80.91,111.727 80.682,111.955 80.56,112.077 C239_L1.2@80.56,113.432
NetC238_L2_1: C238_L2.1 C239_L2.2 L15_L2.1 U39_L2.2 U39_L2.3 | length 7.6
  Top Layer w0.254: U39_L2.2@163.26,100.208 163.26,98.782 163.61,98.432 C239_L2.2@164.06,98.432 ; U39_L2.3@163.91,100.208 163.91,98.582 C239_L2.2@164.06,98.432 ; L15_L2.1@164.41,95.142 164.41,96.727 164.182,96.955 164.06,97.077 C239_L2.2@164.06,98.432
NetC238_L3_1: C238_L3.1 C239_L3.2 L15_L3.1 U39_L3.2 U39_L3.3 | length 7.6
  Top Layer w0.254: U39_L3.2@249.26,72.208 249.26,70.782 249.61,70.432 C239_L3.2@250.06,70.432 ; U39_L3.3@249.91,72.208 249.91,70.582 C239_L3.2@250.06,70.432 ; L15_L3.1@250.41,67.142 250.41,68.727 250.182,68.955 250.06,69.077 C239_L3.2@250.06,70.432
NetC238_N_1: C238_N.1 C239_N.2 L15_N.1 U39_N.2 U39_N.3 | length 7.6
  Top Layer w0.254: U39_N.2@121.292,50.26 122.718,50.26 123.068,50.61 C239_N.2@123.068,51.06 ; U39_N.3@121.292,50.91 122.918,50.91 C239_N.2@123.068,51.06 ; L15_N.1@126.358,51.41 124.773,51.41 124.545,51.182 124.423,51.06 C239_N.2@123.068,51.06
NetC240_L1_1: C240_L1.1 FB14_L1.2 U41_L1.8 | length 5.2
  Top Layer w0.2: FB14_L1.2@69,112.2 FB14_L1.2@69.07,112.27 ; FB14_L1.2@69,112.339 FB14_L1.2@69,112.5 ; 69,112.759 69.041,112.8 C240_L1.1@70.5,112.8
  Top Layer w0.254: FB14_L1.2@69,112.2 69,112.339 69,112.5 69,112.759 69,113.019 70.057,114.076 70.057,115.192 U41_L1.8@70.074,115.208
NetC240_L2_1: C240_L2.1 FB14_L2.2 U41_L2.8 | length 5.6
  Top Layer w0.2: FB14_L2.2@152.5,97.2 152.5,97.43 152.5,97.8 C240_L2.1@154,97.8
  Top Layer w0.254: FB14_L2.2@152.5,97.2 152.5,97.43 152.5,97.8 152.5,98.019 153.557,99.076 153.557,100.192 U41_L2.8@153.574,100.208
NetC240_L3_1: C240_L3.1 FB14_L3.2 U41_L3.8 | length 5.2
  Top Layer w0.2: FB14_L3.2@238.5,69.2 238.677,69.377 239.508,69.377 239.53,69.4 239.625,69.4 240,69.775 C240_L3.1@240,69.8
  Top Layer w0.254: FB14_L3.2@238.5,69.2 238.5,69.339 238.5,69.5 238.5,70.019 239.557,71.076 239.557,72.192 U41_L3.8@239.574,72.208
NetC240_N_1: C240_N.1 FB14_N.2 U41_N.8 | length 5.2
  Top Layer w0.2: C240_N.1@123.7,41 124,40.7 FB14_N.2@124,39.539 ; FB14_N.2@124.161,39.5 FB14_N.2@124.3,39.5
  Top Layer w0.254: U41_N.8@121.292,40.574 121.308,40.557 122.424,40.557 122.808,40.173 123.366,40.173 124,39.539 FB14_N.2@124.07,39.47 ; FB14_N.2@124.23,39.57 FB14_N.2@124.396,39.735
NetC241_L1_1: C241_L1.1 FB15_L1.1 U41_L1.1 | length 8.6
  Top Layer w0.2: v1(69.94,130.984) 69.94,131.94 FB15_L1.1@70,132
  Top Layer w0.254: U41_L1.1@70.074,126.108 U41_L1.1@70.074,126.484 ; C241_L1.1@70.425,128.116 70.422,128.116 70.074,127.768 U41_L1.1@70.074,126.484 ; v1(70.75,126.657) 70.247,126.657 U41_L1.1@70.074,126.484
  Bottom Layer w0.254: v1(69.94,130.984) 69.94,127.466 v1(70.75,126.657)
NetC241_L2_1: C241_L2.1 FB15_L2.1 U41_L2.1 | length 9.1
  Top Layer w0.2: v1(153.44,115.984) 153.44,116.94 FB15_L2.1@153.5,117
  Top Layer w0.254: C241_L2.1@153.925,113.116 153.925,111.657 ; v1(154.25,111.657) 153.925,111.657 ; U41_L2.1@153.574,111.484 U41_L2.1@153.574,111.108 U41_L2.1@153.574,111.484 ; U41_L2.1@153.574,111.484 U41_L2.1@153.747,111.657 ; U41_L2.1@153.574,111.484 U41_L2.1@153.747,111.657 ; U41_L2.1@153.747,111.657 153.925,111.657 ; U41_L2.1@153.747,111.657 153.925,111.657
  Bottom Layer w0.254: v1(153.44,115.984) 153.44,112.466 v1(154.25,111.657)
NetC241_L3_1: C241_L3.1 FB15_L3.1 U41_L3.1 | length 8.6
  Top Layer w0.2: v1(239.44,87.984) 239.44,88.94 FB15_L3.1@239.5,89
  Top Layer w0.254: U41_L3.1@239.574,83.108 U41_L3.1@239.574,83.484 ; C241_L3.1@239.925,85.116 239.922,85.116 239.574,84.768 U41_L3.1@239.574,83.484 ; v1(240.25,83.657) 239.747,83.657 U41_L3.1@239.574,83.484
  Bottom Layer w0.254: v1(239.44,87.984) 239.44,84.466 v1(240.25,83.657)
NetC241_N_1: C241_N.1 FB15_N.1 U41_N.1 | length 8.6
  Top Layer w0.2: FB15_N.1@104.5,40.5 104.56,40.44 v1(105.516,40.44)
  Top Layer w0.254: C241_N.1@108.384,40.925 108.384,40.922 108.732,40.574 U41_N.1@110.016,40.574 ; v1(109.843,41.25) 109.843,40.747 U41_N.1@110.016,40.574 ; U41_N.1@110.392,40.574 U41_N.1@110.016,40.574
  Bottom Layer w0.254: v1(105.516,40.44) 109.034,40.44 v1(109.843,41.25)
NetC242_L1_2: C242_L1.2 R312_L1.1 R315_L1.2 U41_L1.2 | length 5.9
  Top Layer w0.2: R312_L1.1@68,131.55 68,130.85 68.5,130.35 68.5,130.3 R315_L1.2@68.8,130 ; C242_L1.2@68.7,128 68.727,128.027 68.727,129.877 R315_L1.2@68.85,130
  Top Layer w0.254: U41_L1.2@68.804,126.108 C242_L1.2@68.804,128.058
NetC242_L2_2: C242_L2.2 R312_L2.1 R315_L2.2 U41_L2.2 | length 5.9
  Top Layer w0.2: R312_L2.1@151.5,116.55 151.5,115.85 152,115.35 152,115.3 R315_L2.2@152.3,115 ; C242_L2.2@152.2,113 152.227,113.027 152.227,114.877 R315_L2.2@152.35,115
  Top Layer w0.254: U41_L2.2@152.304,111.108 C242_L2.2@152.304,113.058
NetC242_L3_2: C242_L3.2 R312_L3.1 R315_L3.2 U41_L3.2 | length 5.9
  Top Layer w0.2: R312_L3.1@237.5,88.55 237.5,87.85 238,87.35 238,87.3 R315_L3.2@238.3,87 ; C242_L3.2@238.2,85 238.227,85.027 238.227,86.877 R315_L3.2@238.35,87
  Top Layer w0.254: U41_L3.2@238.304,83.108 C242_L3.2@238.304,85.058
NetC242_N_2: C242_N.2 R312_N.1 R315_N.2 U41_N.2 | length 5.9
  Top Layer w0.2: R312_N.1@104.95,38.5 105.65,38.5 106.15,39 106.2,39 R315_N.2@106.5,39.3 ; R315_N.2@106.5,39.35 106.623,39.227 108.473,39.227 C242_N.2@108.5,39.2
  Top Layer w0.254: C242_N.2@108.442,39.304 U41_N.2@110.392,39.304
NetC253_L1_2: C253_L1.2 R325_L1.1 U44_L1.1 | length 7.8
  Top Layer w0.254: v1(94.801,109.709) 94.801,109.696 95.149,109.348 95.352,109.348 R325_L1.1@95.7,109 ; U44_L1.1@95.154,115.338 95.191,115.301 v1(95.191,114.112) 95.191,113.492 C253_L1.2@95.228,113.455
  Bottom Layer w0.254: v1(94.801,109.709) 94.801,109.776 94.629,109.947 94.629,110.98 94.62,110.989 94.62,113.541 v1(95.191,114.112)
NetC253_L2_2: C253_L2.2 R325_L2.1 U44_L2.1 | length 7.6
  Top Layer w0.254: v1(178.301,94.709) R325_L2.1@179.269,94.709 ; U44_L2.1@178.654,100.338 178.691,100.301 v1(178.691,99.112) 178.691,98.492 C253_L2.2@178.728,98.455
  Bottom Layer w0.254: v1(178.301,94.709) 178.301,94.776 178.129,94.947 178.129,95.98 178.12,95.989 178.12,98.541 v1(178.691,99.112)
NetC253_L3_2: C253_L3.2 R325_L3.1 U44_L3.1 | length 7.6
  Top Layer w0.254: v1(264.301,66.709) R325_L3.1@265.269,66.709 ; U44_L3.1@264.654,72.338 264.691,72.301 v1(264.691,71.112) 264.691,70.492 C253_L3.2@264.728,70.455
  Bottom Layer w0.254: v1(264.301,66.709) 264.301,66.776 264.129,66.947 264.129,67.98 264.12,67.989 264.12,70.541 v1(264.691,71.112)
NetC253_N_2: C253_N.2 R325_N.1 U44_N.1 | length 7.6
  Top Layer w0.254: U44_N.1@121.162,65.654 121.199,65.691 v1(122.388,65.691) 123.008,65.691 C253_N.2@123.045,65.728 ; v1(126.791,65.301) R325_N.1@126.791,66.269
  Bottom Layer w0.254: v1(122.388,65.691) 122.959,65.12 125.511,65.12 125.52,65.129 126.553,65.129 126.724,65.301 v1(126.791,65.301)
NetC255_L1_1: C255_L1.1 C256_L1.2 L17_L1.1 U44_L1.2 U44_L1.3 | length 8.2
  Top Layer w0.254: U44_L1.2@95.804,115.338 U44_L1.3@96.454,115.338 96.454,113.959 96.53,113.882 96.53,113.555 C256_L1.2@96.653,113.432 96.653,111.743 C255_L1.1@96.738,111.659 96.753,111.643 96.753,110.934 97.156,110.532 98.022,110.532 98.636,109.917 L17_L1.1@99.4,109.917
NetC255_L2_1: C255_L2.1 C256_L2.2 L17_L2.1 U44_L2.2 U44_L2.3 | length 8.2
  Top Layer w0.254: U44_L2.2@179.304,100.338 U44_L2.3@179.954,100.338 179.954,98.959 180.03,98.882 180.03,98.555 C256_L2.2@180.153,98.432 180.153,96.743 C255_L2.1@180.238,96.659 180.253,96.643 180.253,95.934 180.656,95.532 181.522,95.532 182.136,94.917 L17_L2.1@182.9,94.917
NetC255_L3_1: C255_L3.1 C256_L3.2 L17_L3.1 U44_L3.2 U44_L3.3 | length 8.2
  Top Layer w0.254: U44_L3.2@265.304,72.338 U44_L3.3@265.954,72.338 265.954,70.959 266.03,70.882 266.03,70.555 C256_L3.2@266.153,70.432 266.153,68.743 C255_L3.1@266.238,68.659 266.253,68.643 266.253,67.934 266.656,67.532 267.522,67.532 268.136,66.917 L17_L3.1@268.9,66.917
NetC255_N_1: C255_N.1 C256_N.2 L17_N.1 U44_N.2 U44_N.3 | length 8.2
  Top Layer w0.254: U44_N.2@121.162,66.304 U44_N.3@121.162,66.954 122.541,66.954 122.618,67.03 122.945,67.03 C256_N.2@123.068,67.153 124.757,67.153 C255_N.1@124.841,67.238 124.857,67.253 125.566,67.253 125.968,67.656 125.968,68.522 126.583,69.136 L17_N.1@126.583,69.9
NetC261_1: C261.1 Q3.3 R329.2 R330.2 | length 3.9
  Top Layer w0.2: R330.2@206.804,6.626 206.85,6.672 R329.2@206.85,7.681
  Top Layer w0.3: C261.1@206.804,5.644 R330.2@206.804,6.626 ; C261.1@206.821,5.628 206.898,5.551 206.898,5.119 207.073,4.943 207.249,4.943 207.425,4.767 Q3.3@207.425,4.093
NetC262_1: C262.1 R331.2 R333.1 U12.5 | length 8.2
  Top Layer w0.2: C262.1@183.9,32.5 C262.1@184,32.4
  Top Layer w0.3: U12.5@181.8,32.87 182.83,32.87 183.2,32.5 C262.1@183.9,32.5
  Top Layer w0.4: C262.1@183.9,32.5 184.05,32.65 184.05,33.05 184.621,33.621 R331.2@184.621,36.68 ; C262.1@184,32.4 184,31.9 184.2,31.7 R333.1@184.2,31.2
NetD1_1: D1.1 R81.2 | length 1.7
  Top Layer w0.4: R81.2@183.3,45.5 D1.1@185.03,45.5
NetD1_2: D1.2 J12.107 | length 19
  Top Layer w0.4: D1.2@186.2,45.5 v1(186.9,45.5) ; v1(203,44.2) 202.975,44.225 202.975,45.775 J12.107@203,45.8
  Bottom Layer w0.4: v1(186.9,45.5) 201.6,45.5 v1@203,44.1
NetD2_1: D2.1 R82.2 | length 1.9
  Top Layer w0.4: R82.2@183.2,43.5 183.4,43.3 184.1,43.3 184.15,43.35 184.95,43.35 D2.1@185,43.4
NetD2_2: D2.2 J12.109 | length 19.4
  Top Layer w0.4: D2.2@186.045,43.4 v1(186.9,43.4) ; v1(202.2,43.7) 202.175,43.725 202.175,45.675 J12.109@202.2,45.7
  Bottom Layer w0.4: v1(186.9,43.4) 191.5,43.4 192.874,44.774 197.526,44.774 198.805,43.495 201.692,43.495 201.797,43.6 201.952,43.6 202.012,43.66 202.143,43.66 v1@202.2,43.603
NetD4_1: D4.1 R210.2 | length 2.6
  Top Layer w0.2: D4.1@168.612,5.466 D4.1@168.682,5.396
  Top Layer w0.6: D4.1@168.612,5.466 R210.2@168.612,7.961
NetD6_1: D6.1 R217.2 | length 2.2
  Top Layer w0.2: D6.1@159.208,20.55 D6.1@159.283,20.625
  Top Layer w0.4: R217.2@157.083,20.55 D6.1@159.208,20.55
NetD7_L1_2: D7_L1.2 D9_L1.1
NetD7_L2_2: D7_L2.2 D9_L2.1
NetD7_L3_2: D7_L3.2 D9_L3.1
NetD7_N_2: D7_N.2 D9_N.1
NetD8_L1_1: D8_L1.1 D9_L1.2
NetD8_L1_2: D8_L1.2 R281_L1.2 R282_L1.2
  other v1: 35.5,143.5 36.5,143.5 37.5,143.5 38.5,143.5 36,144 37,144 38,144 35.5,144.5 36.5,144.5 37.5,144.5 38.5,144.5
NetD8_L2_1: D8_L2.1 D9_L2.2
NetD8_L2_2: D8_L2.2 R281_L2.2 R282_L2.2 | length 6.5
  Bottom Layer w0.2: v1(122,129.5) R282_L2.2@125.05,129.5 R281_L2.2@125.05,133
  other v1: 119,128.5 120,128.5 121,128.5 122,128.5 119.5,129 120.5,129 121.5,129 119,129.5 120,129.5 121,129.5
NetD8_L3_1: D8_L3.1 D9_L3.2
NetD8_L3_2: D8_L3.2 R281_L3.2 R282_L3.2 | length 7.9
  Bottom Layer w0.2: R282_L3.2@211.05,101.5 v1(208,101.5) 209.8,103.3 210,103.3 210.217,103.517 210.217,103.892 211.05,104.725 R281_L3.2@211.05,105
  other v1: 205,100.5 206,100.5 207,100.5 208,100.5 205.5,101 206.5,101 207.5,101 205,101.5 206,101.5 207,101.5
NetD8_N_1: D8_N.1 D9_N.2
NetD8_N_2: D8_N.2 R281_N.2 R282_N.2
  other v1: 92,6 93,6 92.5,6.5 92,7 93,7 92.5,7.5 92,8 93,8 92.5,8.5 92,9 93,9
NetD10_L1_2: D10_L1.2 R285_L1.1 | length 2
  Top Layer w0.3: v1(37.5,135.5) 37.8,135.2 D10_L1.2@37.8,134.7
  Bottom Layer w0.3: v1(37.5,135.5) 37.5,134.815 R285_L1.1@37.775,134.54
NetD10_L2_2: D10_L2.2 R285_L2.1 | length 2
  Top Layer w0.3: v1(121,120.5) 121.3,120.2 D10_L2.2@121.3,119.7
  Bottom Layer w0.3: v1(121,120.5) 121,119.815 R285_L2.1@121.275,119.54
NetD10_L3_2: D10_L3.2 R285_L3.1 | length 2
  Top Layer w0.3: v1(207,92.5) 207.3,92.2 D10_L3.2@207.3,91.7
  Bottom Layer w0.3: v1(207,92.5) 207,91.815 R285_L3.1@207.275,91.54
NetD10_N_2: D10_N.2 R285_N.1 | length 2
  Top Layer w0.3: v1(101,8) 101.3,8.3 D10_N.2@101.8,8.3
  Bottom Layer w0.3: v1(101,8) 101.685,8 R285_N.1@101.96,8.275
NetD11_L1_2: D11_L1.2 R296_L1.1 | length 2.6
  Top Layer w0.254: v1(53.613,135.6) 54,135.213 D11_L1.2@54,134.457
  Bottom Layer w0.254: v1(53.613,135.6) 53.613,134.774 R296_L1.1@53.93,134.457
NetD11_L2_2: D11_L2.2 R296_L2.1 | length 2.6
  Top Layer w0.254: v1(137.113,120.6) 137.5,120.213 D11_L2.2@137.5,119.457
  Bottom Layer w0.254: v1(137.113,120.6) 137.113,119.774 R296_L2.1@137.43,119.457
NetD11_L3_2: D11_L3.2 R296_L3.1 | length 2.6
  Top Layer w0.254: v1(223.113,92.6) 223.5,92.213 D11_L3.2@223.5,91.457
  Bottom Layer w0.254: v1(223.113,92.6) 223.113,91.774 R296_L3.1@223.43,91.457
NetD11_N_2: D11_N.2 R296_N.1 | length 2.6
  Top Layer w0.254: v1(100.9,24.113) 101.287,24.5 D11_N.2@102.043,24.5
  Bottom Layer w0.254: v1(100.9,24.113) 101.726,24.113 R296_N.1@102.043,24.43
NetD12_L1_2: D12_L1.2 R306_L1.1 | length 2.5
  Top Layer w0.254: D12_L1.2@76.089,133.224 76.099,133.234 77.419,133.234 v1(77.429,133.244)
  Bottom Layer w0.254: R306_L1.1@76.397,133.033 77.163,133.033 77.375,133.244 v1(77.429,133.244)
NetD12_L2_2: D12_L2.2 R306_L2.1 | length 2.5
  Top Layer w0.254: D12_L2.2@159.589,118.224 159.599,118.234 160.919,118.234 v1(160.929,118.244)
  Bottom Layer w0.254: R306_L2.1@159.897,118.033 160.663,118.033 160.875,118.244 v1(160.929,118.244)
NetD12_L3_2: D12_L3.2 R306_L3.1 | length 2.5
  Top Layer w0.254: D12_L3.2@245.589,90.224 245.599,90.234 246.919,90.234 v1(246.929,90.244)
  Bottom Layer w0.254: R306_L3.1@245.897,90.033 246.663,90.033 246.875,90.244 v1(246.929,90.244)
NetD12_N_2: D12_N.2 R306_N.1 | length 2.5
  Top Layer w0.254: v1(103.256,47.929) 103.266,47.919 103.266,46.599 D12_N.2@103.276,46.589
  Bottom Layer w0.254: v1(103.256,47.929) 103.256,47.875 103.467,47.663 R306_N.1@103.467,46.897
NetD13_L1_1: D13_L1.1 R319_L1.1 R320_L1.1
  other v1: 93.5,149.5 94.5,149.5 95.5,149.5
NetD13_L1_2: D13_L1.2 D15_L1.1
NetD13_L2_1: D13_L2.1 R319_L2.1 R320_L2.1
  other v1: 177,134.5 178,134.5 179,134.5
NetD13_L2_2: D13_L2.2 D15_L2.1
NetD13_L3_1: D13_L3.1 R319_L3.1 R320_L3.1
  other v1: 263,106.5 264,106.5 265,106.5
NetD13_L3_2: D13_L3.2 D15_L3.1
NetD13_N_1: D13_N.1 R319_N.1 R320_N.1
  other v1: 87,64 87,65 87,66
NetD13_N_2: D13_N.2 D15_N.1
NetD14_L1_1: D14_L1.1 D15_L1.2
NetD14_L2_1: D14_L2.1 D15_L2.2
NetD14_L3_1: D14_L3.1 D15_L3.2
NetD14_N_1: D14_N.1 D15_N.2
NetD16_L1_2: D16_L1.2 R323_L1.1 | length 1.9
  Top Layer w0.254: D16_L1.2@91.075,133.584 91.101,133.558 91.761,133.558 v1(91.786,133.532)
  Bottom Layer w0.254: R323_L1.1@90.768,133.109 90.768,133.134 91.116,133.482 91.668,133.482 91.718,133.532 v1(91.786,133.532)
NetD16_L2_2: D16_L2.2 R323_L2.1 | length 1.9
  Top Layer w0.254: D16_L2.2@174.575,118.584 174.601,118.558 175.261,118.558 v1(175.286,118.532)
  Bottom Layer w0.254: R323_L2.1@174.268,118.109 174.268,118.134 174.616,118.482 175.168,118.482 175.218,118.532 v1(175.286,118.532)
NetD16_L3_2: D16_L3.2 R323_L3.1 | length 1.9
  Top Layer w0.254: D16_L3.2@260.575,90.584 260.601,90.558 261.261,90.558 v1(261.286,90.532)
  Bottom Layer w0.254: R323_L3.1@260.268,90.109 260.268,90.134 260.616,90.482 261.168,90.482 261.218,90.532 v1(261.286,90.532)
NetD16_N_2: D16_N.2 R323_N.1 | length 1.9
  Top Layer w0.254: D16_N.2@102.916,61.575 102.942,61.601 102.942,62.261 v1(102.968,62.286)
  Bottom Layer w0.254: v1(102.968,62.286) 102.968,62.218 103.018,62.168 103.018,61.616 103.366,61.268 R323_N.1@103.391,61.268
NetD18_1: D18.1 R93.2 | length 2.7
  Top Layer w0.2: R93.2@284.2,16.275 284.725,16.275 D18.1@286.25,14.75
NetD19_1: D19.1 R233.2 | length 2.2
  Top Layer w0.2: D19.1@267.97,63 R233.2@270.2,63
NetD20_1: D20.1 R234.2 | length 2.5
  Top Layer w0.2: R234.2@291.5,195 291.615,195.115 D20.1@291.615,197.5
NetD21_1: D21.1 R235.2 | length 2.9
  Top Layer w0.2: R235.2@232.3,22 233.5,22 234,22.5 D21.1@234,23.53
NetF1_1: F1.1 R83.2 R89.2 R220.4
NetF2_1: F2.1 R85.2 R90.2 R221.4 | length 31.4
  Top Layer w3: R85.2@266.768,238.768 278.929,238.768 R221.4@281.339,241.177
  Bottom Layer w0.5: R90.2@240,267 R90.2@240.201,266.799
  Bottom Layer w3: R85.2@266.768,238.768 278.929,238.768 R221.4@281.339,241.177
  other v1: 231.5,264.5 232.5,264.5 233.5,264.5 234.5,264.5 235.5,264.5 236.5,264.5 237.5,264.5 231,265 232,265 233,265 234,265 235,265 236,265 237,265 238,265 231.5,265.5 232.5,265.5 233.5,265.5 234.5,265.5 235.5,265.5 236.5,265.5 237.5,265.5 231,266 232,266 233,266 234,266 235,266 236,266 237,266 238,266 231.5,266.5 232.5,266.5 233.5,266.5 234.5,266.5 235.5,266.5 236.5,266.5 237.5,266.5 231,267 232,267 233,267 234,267 235,267 236,267 237,267 238,267 235.5,267.5 236.5,267.5 237.5,267.5 238.5,267.5 236,268 237,268 238,268 239,268 240,268 236.5,268.5 237.5,268.5 238.5,268.5 239.5,268.5 240.5,268.5 236,269 237,269 238,269 239,269 240,269 236.5,269.5 237.5,269.5 238.5,269.5 239.5,269.5 240.5,269.5 236,270 237,270 238,270 239,270 240,270 236.5,270.5 237.5,270.5 238.5,270.5 239.5,270.5 240.5,270.5
NetF3_1: F3.1 R87.2 R91.2 R222.4 | length 9.1
  Top Layer w0.3: F3.1@216.5,269 F3.1@216.75,269.25
  Top Layer w2: F3.1@216.75,269.25 R91.2@225.5,269.25
NetF4_1: F4.1 R89.1 R90.1 R91.1 R92.2 R94.2 R223.4 | length 56
  Top Layer w0.5: R223.4@284.8,275 R223.4@285,274.8
  Layer 2 w0.5: R91.1@225.5,261.5 R91.1@225.75,261.5
  Layer 2 w2: R91.1@225.75,261.5 228.125,259.125 R90.1@239.875,259.125 ; R90.1@240,259.25 R89.1@252.75,259.25 ; R89.1@253,259.25 256,256.25 R94.2@265.75,256.25 ; R94.2@266,256.25 268.286,256.25 274.536,262.5 R92.2@277,262.5
NetJ12_9: J12.9 R20.1 | length 6.9
  Top Layer w0.4: J12.9@245.35,45.4 245.35,48.15 246.1,48.9 247.5,48.9 247.9,49.3 247.9,50.3 R20.1@247.8,50.4
NetJ12_11: J12.11 R21.1 | length 5.6
  Top Layer w0.4: J12.11@244.55,45.4 244.55,48.45 245.788,49.688 245.788,50.2 245.988,50.4 R21.1@246,50.4
NetJ12_12: J12.12 R22.1 | length 8
  Top Layer w0.2: J12.12@244.55,42 244.7,41.85 244.7,39.6 245.8,38.5 247.8,38.5 248.2,38.1 248.2,37 R22.1@248.4,36.8
NetJ12_13: J12.13 R23.1 | length 7.9
  Top Layer w0.4: J12.13@243.75,45.4 243.75,48.55 244.2,49 R23.1@244.2,53.1
NetJ12_14: J12.14 R24.1 | length 7.2
  Top Layer w0.2: J12.14@243.75,42 243.75,39.45 245.1,38.1 246.4,38.1 246.7,37.8 R24.1@246.7,36.8
NetJ12_15: J12.15 R25.2 | length 4.4
  Top Layer w0.4: J12.15@242.95,45.4 R25.2@242.95,49.75
NetJ12_17: J12.17 R26.1 | length 8
  Top Layer w0.4: J12.17@242.15,45.4 242.125,45.425 242.125,53.325 R26.1@242.2,53.4
NetJ12_18: J12.18 R27.1 | length 6.7
  Top Layer w0.2: J12.18@242.15,42 242.207,41.943 242.207,39.693 243.8,38.1 244.3,38.1 244.917,37.483 244.917,36.983 R27.1@245.1,36.8
NetJ12_20: J12.20 R28.1 | length 6.1
  Top Layer w0.2: J12.20@241.35,42 241.35,39.35 243.217,37.483 243.217,37.083 R28.1@243.5,36.8
NetJ12_21: J12.21 R29.2 | length 4.7
  Top Layer w0.4: J12.21@240.55,45.4 240.55,48.15 241.1,48.7 R29.2@241.1,49.9
NetJ12_24: J12.24 R30.1 | length 6.4
  Top Layer w0.2: J12.24@239.75,42 239.75,39.45 241,38.2 241.8,38.2 242.2,37.8 R30.1@242.2,37.1
NetJ12_25: J12.25 R31.1 | length 8.4
  Top Layer w0.4: J12.25@238.95,45.4 238.95,48.05 239.6,48.7 239.6,51.5 239.9,51.8 R31.1@239.9,53.4
NetJ12_26: J12.26 R32.2 | length 6
  Top Layer w0.2: J12.26@238.95,42 238.95,39.25 240.525,37.675 240.525,37.175 R32.2@240.9,36.8
NetJ12_27: J12.27 R33.1 | length 4.7
  Top Layer w0.4: J12.27@238.15,45.4 238.2,45.45 R33.1@238.2,50.1
NetJ12_28: J12.28 R34.2 | length 5.6
  Top Layer w0.2: J12.28@238.15,42 238.15,39.25 239.2,38.2 R34.2@239.2,36.8
NetJ12_30: J12.30 R35.2 | length 5.3
  Top Layer w0.2: J12.30@237.35,42 237.3,41.95 237.3,38.6 237.5,38.4 R35.2@237.5,36.8
NetJ12_31: J12.31 R36.1 | length 7.9
  Top Layer w0.4: J12.31@236.55,45.4 236.55,48.15 236.699,48.299 236.699,53 R36.1@236.9,53.2
NetJ12_33: J12.33 R37.1 | length 4.7
  Top Layer w0.4: R37.1@235.7,50 235.6,49.9 235.6,48.1 235.75,47.95 J12.33@235.75,45.4
NetJ12_36: J12.36 R38.2 | length 4.5
  Top Layer w0.2: J12.36@234.95,42 234.95,39.35 235.55,38.75 235.55,38.325 R38.2@235.925,37.95
NetJ12_37: J12.37 R39.1 | length 8
  Top Layer w0.4: R39.1@234.1,53.4 234.125,53.375 234.125,45.425 J12.37@234.15,45.4
NetJ12_39: J12.39 R40.1 | length 4.9
  Top Layer w0.4: R40.1@233.1,50.1 233,50 233,48.3 233.35,47.95 J12.39@233.35,45.4
NetJ12_40: J12.40 R41.2 | length 4.4
  Top Layer w0.2: J12.40@233.35,42 233.5,41.85 233.5,39.6 234.1,39 R41.2@234.1,37.9
NetJ12_42: J12.42 R42.2 | length 4
  Top Layer w0.2: R42.2@232.1,38.2 232.1,39.1 232.55,39.55 J12.42@232.55,42
NetJ12_49: J12.49 R43.2 | length 4.1
  Top Layer w0.4: J12.49@229.35,45.4 229.35,48.05 229.7,48.4 R43.2@229.7,49.4
NetJ12_50: J12.50 R44.2 | length 5.7
  Top Layer w0.4: R44.2@228.9,35 228.9,37.2 229.35,37.65 229.35,40.45 229.4,40.5
NetJ12_51: J12.51 R45.2 | length 4.2
  Top Layer w0.4: J12.51@228.55,45.4 228.55,48.45 228.7,48.6 R45.2@228.7,49.5
NetJ12_52: J12.52 R46.2 | length 4.1
  Top Layer w0.4: R46.2@228,37 228.05,37.05 228.05,37.339 228.55,37.84 228.55,40.85 J12.52@228.6,40.9
NetJ12_53: J12.53 R47.2 | length 4.1
  Top Layer w0.4: J12.53@227.75,45.4 R47.2@227.75,49.45
NetJ12_54: J12.54 R48.2 | length 6.3
  Top Layer w0.4: R48.2@227.2,35 227.2,37.338 227.75,37.888 227.75,41.05 J12.54@227.8,41.1
NetJ12_55: J12.55 R49.2 | length 4.1
  Top Layer w0.4: R49.2@226.6,49.4 226.6,48.5 226.95,48.15 J12.55@226.95,45.4
NetJ12_56: J12.56 R50.2 | length 3.4
  Top Layer w0.4: R50.2@226.4,37 226.4,37.7 226.95,38.25 226.95,40.15 227,40.2
NetJ12_57: J12.57 R51.2 | length 6
  Top Layer w0.4: R51.2@222.9,51.4 222.9,51.35 222.95,51.3 J12.57@222.95,45.4
NetJ12_58: J12.58 R52.2 | length 5.6
  Top Layer w0.4: 223,40.2 223,36.6 223.1,36.5 R52.2@223.1,34.6
NetJ12_59: J12.59 R53.2 | length 3.8
  Top Layer w0.4: J12.59@222.15,45.4 222.175,45.425 222.175,49.175 R53.2@222.2,49.2
NetJ12_60: J12.60 R54.2 | length 4.3
  Top Layer w0.4: R54.2@222.2,36.3 222.175,36.325 222.175,40.575 222.2,40.6
NetJ12_61: J12.61 R55.2 | length 6.1
  Top Layer w0.4: J12.61@221.35,45.4 221.35,51.45 R55.2@221.4,51.5
NetJ12_62: J12.62 R56.2 | length 6
  Top Layer w0.4: R56.2@221.3,34.6 221.3,40.6
NetJ12_63: J12.63 R57.2 | length 3.8
  Top Layer w0.4: J12.63@220.55,45.4 220.575,45.425 220.575,49.175 R57.2@220.6,49.2
NetJ12_64: J12.64 R58.2 | length 4.5
  Top Layer w0.4: R58.2@220.2,36.2 220.2,37.3 220.6,37.7 220.6,40.5
NetJ12_67: J12.67 R59.2 | length 6.2
  Top Layer w0.4: J12.67@218.95,45.4 219,45.45 219,47.752 219.2,47.951 219.2,48.2 219.5,48.5 R59.2@219.5,51.4
NetJ12_69: J12.69 R60.2 | length 4.1
  Top Layer w0.4: J12.69@218.15,45.4 218.2,45.45 218.2,47.8 218.6,48.2 R60.2@218.6,49.3
NetJ12_70: J12.70 R61.2 | length 4.5
  Top Layer w0.4: 218.2,40.6 218.15,40.55 218.15,38.75 218.3,38.6 R61.2@218.3,36.2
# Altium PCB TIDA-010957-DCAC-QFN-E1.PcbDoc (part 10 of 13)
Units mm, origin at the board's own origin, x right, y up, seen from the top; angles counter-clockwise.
Board outline 300 x 300 mm, 4 copper layers (Top Layer, Layer 1, Layer 2, Bottom Layer), stack 1.787 mm thick; 1286 components, 677 nets, 4169 pads, 3428 vias.

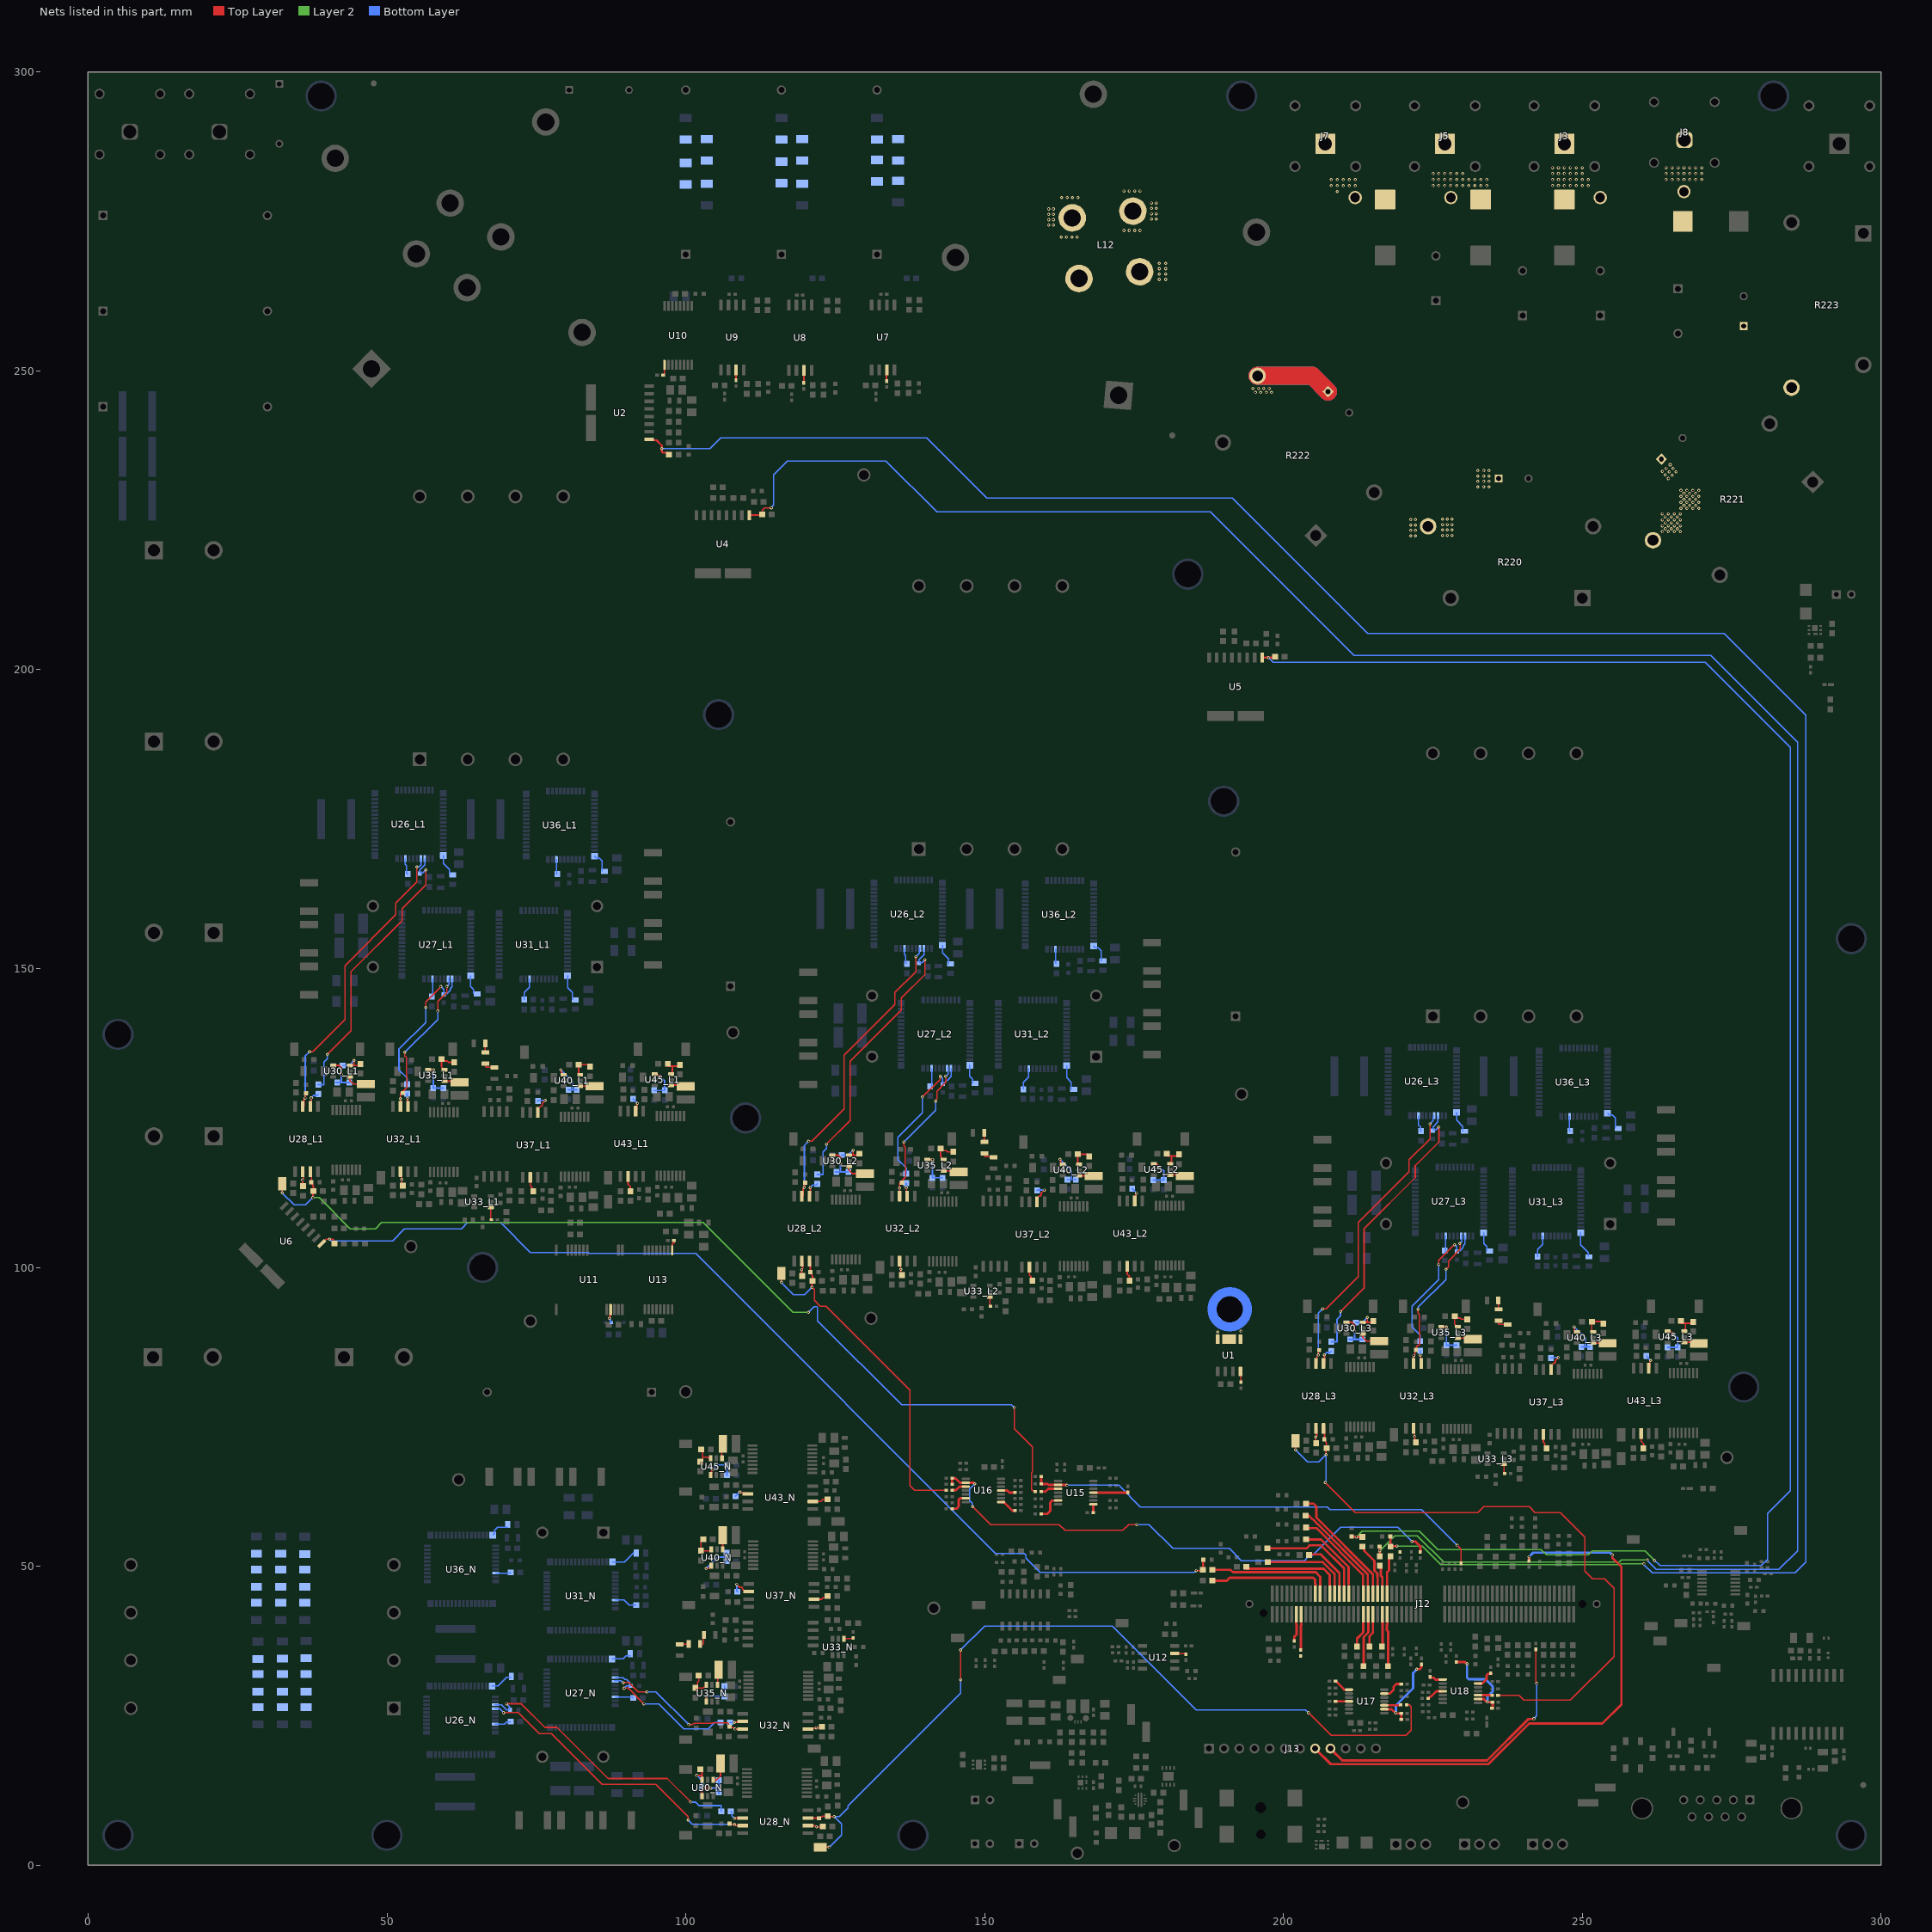
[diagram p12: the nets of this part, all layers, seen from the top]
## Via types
v1: diameter 0.508, hole 0.254, Top Layer to Bottom Layer, tented both sides, 3428 vias

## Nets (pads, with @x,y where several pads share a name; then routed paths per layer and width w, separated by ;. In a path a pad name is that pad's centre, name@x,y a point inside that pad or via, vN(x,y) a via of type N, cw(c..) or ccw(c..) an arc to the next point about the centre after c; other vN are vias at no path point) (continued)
NetJ12_71: J12.71 R62.1 | length 6.5
  Top Layer w0.4: J12.71@217.35,45.4 217.35,49.012 217.671,49.333 217.671,51.471 R62.1@217.9,51.7
NetJ12_72: J12.72 R63.2 | length 7.2
  Top Layer w0.4: 217.4,40.4 217.3,40.3 217.3,39.276 217.5,39.076 R63.2@217.5,33.3
NetJ12_73: J12.73 R64.1 | length 4.7
  Top Layer w0.4: R64.1@216.2,50 216.3,49.9 216.3,48.4 216.55,48.15 J12.73@216.55,45.4
NetJ12_74: J12.74 R65.2 | length 4.3
  Top Layer w0.4: R65.2@216.5,36.6 216.6,36.7 J12.74@216.6,40.9
NetJ12_75: J12.75 R66.1 | length 9
  Top Layer w0.4: R66.1@213.2,53.3 213.475,53.025 213.475,52.625 215.225,50.875 215.225,49.275 215.7,48.8 215.7,48.151 215.75,48.101 J12.75@215.75,45.4
NetJ12_77: J12.77 R68.1 | length 20.7
  Top Layer w0.4: R68.1@203.475,60.5 R68.1@203.8,60.5 205,60.5 205.5,60 205.5,58.151 214.95,48.701 J12.77@214.95,45.4
NetJ12_78: J12.78 R69.2 | length 5.6
  Top Layer w0.4: R69.2@214.4,36.6 214.4,38.3 214.95,38.85 J12.78@214.95,42
NetJ12_79: J12.79 R70.1 | length 16.4
  Top Layer w0.4: R70.1@203.5,58.7 R70.1@203.736,58.464 204.288,58.464 205.551,57.2 214.1,48.651 214.1,47
NetJ12_80: J12.80 R71.2 | length 7.6
  Top Layer w0.4: R71.2@213.4,33.3 213.4,38.149 214.2,38.949 214.2,40.6
NetJ12_81: J12.81 R72.1 | length 15.2
  Top Layer w0.4: R72.1@203.5,56.4 205.503,56.4 213.3,48.603 213.3,46.6 J12.81@213.4,46.5
NetJ12_82: J12.82 R84.2 | length 4.7
  Top Layer w0.4: R84.2@212.3,36.6 212.3,37.9 213.35,38.95 213.35,40.75 J12.82@213.4,40.8
NetJ12_87: J12.87 R73.1 | length 11.9
  Top Layer w0.4: R73.1@203.8,54.5 206.3,54.5 210.9,49.9 210.9,47
NetJ12_89: J12.89 R74.1 | length 18.9
  Top Layer w0.4: R74.1@197.3,53 203.841,53 204.341,53.5 206.3,53.5 210.15,49.65 J12.89@210.15,45.4
NetJ12_91: J12.91 R75.1 | length 8.5
  Top Layer w0.4: R75.1@204.3,51.9 204.4,52 206.2,52 209.35,48.85 209.35,46.85 209.4,46.8
NetJ12_93: J12.93 R76.1 | length 15.3
  Top Layer w0.4: R76.1@197.4,50.7 206.6,50.7 208.55,48.75 J12.93@208.55,45.4
NetJ12_95: J12.95 R77.1 | length 17.6
  Top Layer w0.4: R77.1@193.7,49.6 206.7,49.6 207.75,48.55 J12.95@207.75,45.4
NetJ12_99: J12.99 R78.1 | length 20.2
  Top Layer w0.4: R78.1@188.1,49.4 191.159,49.4 191.559,49 205.4,49 206.15,48.25 206.15,46.65 J12.99@206.2,46.6
NetJ12_101: J12.101 R334.1 | length 18.5
  Top Layer w0.4: R334.1@188.1,47.6 190.5,47.6 191,48.1 205,48.1 205.3,47.8 205.3,47 205.4,46.9
NetJ12_108: J12.108 R79.2 | length 4.4
  Top Layer w0.4: R79.2@202.9,36 202.9,40.076 203,40.176 203,40.4
NetJ12_110: J12.110 R80.2 | length 3.1
  Top Layer w0.4: R80.2@201.8,37.5 201.8,38.2 202.2,38.6 202.2,40.3 202.1,40.4
NetL4_L1_2: L4_L1.2 U26_L1.42 | length 3.6
  Bottom Layer w0.2: U26_L1.42@59.45,168.925 59.475,168.9 59.475,167.617 60.5,166.592 L4_L1.2@60.5,165.775
NetL4_L2_2: L4_L2.2 U26_L2.42 | length 3.6
  Bottom Layer w0.2: U26_L2.42@142.95,153.925 142.975,153.9 142.975,152.617 144,151.592 L4_L2.2@144,150.775
NetL4_L3_2: L4_L3.2 U26_L3.42 | length 3.6
  Bottom Layer w0.2: U26_L3.42@228.95,125.925 228.975,125.9 228.975,124.617 230,123.592 L4_L3.2@230,122.775
NetL4_N_2: L4_N.2 U26_N.42 | length 3.8
  Bottom Layer w0.2: U26_N.42@67.575,29.95 67.6,29.975 68.6,29.975 70.025,31.4 L4_N.2@70.725,31.4
NetL10_L1_1: L10_L1.1 U30_L1.1 | length 3.6
  Top Layer w0.254: U30_L1.1@43.788,131.895 43.788,131.295 44.401,130.682 L10_L1.1@46.5,130.682
NetL10_L2_1: L10_L2.1 U30_L2.1 | length 3.6
  Top Layer w0.254: U30_L2.1@127.288,116.895 127.288,116.295 127.901,115.682 L10_L2.1@130,115.682
NetL10_L3_1: L10_L3.1 U30_L3.1 | length 3.6
  Top Layer w0.254: U30_L3.1@213.288,88.895 213.288,88.295 213.901,87.682 L10_L3.1@216,87.682
NetL10_N_1: L10_N.1 U30_N.1 | length 3.6
  Top Layer w0.254: U30_N.1@104.605,14.288 105.205,14.288 105.818,14.901 L10_N.1@105.818,17
NetL12_2: L12.2 R83.1 R220.3
  other v1: 221.3,222.4 222.1,222.4 226.6,222.5 227.4,222.5 228.2,222.5 221.3,223.3 222.1,223.3 226.6,223.4 227.4,223.4 228.2,223.4 221.3,224.2 222.1,224.2 226.6,224.3 227.4,224.3 228.2,224.3 221.3,225.1 222.1,225.1 226.6,225.2 227.4,225.2 228.2,225.2 232.5,230.6 233.5,230.6 234.4,230.6 232.5,231.5 233.5,231.5 234.4,231.5 232.5,232.4 233.5,232.4 234.4,232.4 232.5,233.3 233.5,233.3 234.4,233.3 179.2,265.3 180.3,265.3 179.2,266.2 180.3,266.2 179.2,267.1 180.3,267.1 179.2,268 180.3,268
NetL12_4: L12.4 R85.1 R221.3 | length 0.7
  Bottom Layer w0.5: R221.3@261.823,221.661 262,221.484 R221.3@262,221
  other v1: 263.391,223.085 264.391,223.085 265.391,223.085 266.391,223.085 263.891,223.585 264.891,223.585 265.891,223.585 263.391,224.085 264.391,224.085 265.391,224.085 266.391,224.085 263.891,224.585 264.891,224.585 265.891,224.585 263.391,225.085 264.391,225.085 265.391,225.085 266.391,225.085 263.891,225.585 264.891,225.585 265.891,225.585 263.391,226.085 264.391,226.085 265.391,226.085 266.391,226.085 266.5,227 267.5,227 268.5,227 269.5,227 267,227.5 268,227.5 269,227.5 266.5,228 267.5,228 268.5,228 269.5,228 267,228.5 268,228.5 269,228.5 266.5,229 267.5,229 268.5,229 269.5,229 267,229.5 268,229.5 269,229.5 266.5,230 267.5,230 268.5,230 269.5,230 264.4,232 265.038,232.519 263.9,232.6 265.7,233.1 264.538,233.119 263.4,233.2 265.2,233.7 264.038,233.719 264.7,234.3 173.3,273.5 174.2,273.5 175.1,273.5 176,273.5 177.9,275.4 178.7,275.4 177.9,276.3 178.7,276.3 177.9,277.2 178.7,277.2 177.9,278.1 178.7,278.1 173.3,280.1 174.2,280.1 175.1,280.1 176,280.1
NetL12_6: L12.6 R87.1 R222.3 | length 25.8
  Top Layer w3: R222.3@195.661,249.177 204.823,249.177 R87.1@207.464,246.536
  Bottom Layer w3: R222.3@195.661,249.177 204.823,249.177 R87.1@207.464,246.536
  other v1: 195.3,246.4 196.2,246.4 197.1,246.4 198,246.4 194.9,247.1 195.8,247.1 196.7,247.1 197.6,247.1 162.8,272.4 163.7,272.4 164.6,272.4 165.5,272.4 160.7,274.4 161.5,274.4 160.7,275.3 161.5,275.3 160.7,276.2 161.5,276.2 160.7,277.1 161.5,277.1 162.9,279 163.8,279 164.7,279 165.6,279
NetL12_8: L12.8 R92.1 R223.3
NetL12_L1_1: L12_L1.1 U35_L1.1 | length 2.6
  Top Layer w0.254: U35_L1.1@59.65,131.166 62.005,131.166 L12_L1.1@62.173,130.998
NetL12_L2_1: L12_L2.1 U35_L2.1 | length 2.6
  Top Layer w0.254: U35_L2.1@143.15,116.166 145.505,116.166 L12_L2.1@145.673,115.998
NetL12_L3_1: L12_L3.1 U35_L3.1 | length 2.6
  Top Layer w0.254: U35_L3.1@229.15,88.166 231.505,88.166 L12_L3.1@231.673,87.998
NetL12_N_1: L12_N.1 U35_N.1 | length 2.6
  Top Layer w0.254: U35_N.1@105.334,30.15 105.334,32.505 L12_N.1@105.502,32.673
NetL14_L1_1: L14_L1.1 U40_L1.1 | length 2.4
  Top Layer w0.254: U40_L1.1@82.333,130.333 84.709,130.333 L14_L1.1@84.725,130.316
NetL14_L2_1: L14_L2.1 U40_L2.1 | length 2.4
  Top Layer w0.254: U40_L2.1@165.833,115.333 168.209,115.333 L14_L2.1@168.225,115.316
NetL14_L3_1: L14_L3.1 U40_L3.1 | length 2.4
  Top Layer w0.254: U40_L3.1@251.833,87.333 254.209,87.333 L14_L3.1@254.225,87.316
NetL14_N_1: L14_N.1 U40_N.1 | length 2.4
  Top Layer w0.254: U40_N.1@106.167,52.833 106.167,55.209 L14_N.1@106.184,55.225
NetL16_L1_1: L16_L1.1 U45_L1.1 | length 2.6
  Top Layer w0.254: U45_L1.1@97.507,130.5 99.785,130.5 L16_L1.1@99.994,130.291
NetL16_L2_1: L16_L2.1 U45_L2.1 | length 2.6
  Top Layer w0.254: U45_L2.1@181.007,115.5 183.285,115.5 L16_L2.1@183.494,115.291
NetL16_L3_1: L16_L3.1 U45_L3.1 | length 2.6
  Top Layer w0.254: U45_L3.1@267.007,87.5 269.285,87.5 L16_L3.1@269.494,87.291
NetL16_N_1: L16_N.1 U45_N.1 | length 2.6
  Top Layer w0.254: U45_N.1@106,68.007 106,70.285 L16_N.1@106.209,70.494
NetL18_L1_2: L18_L1.2 U27_L1.42 | length 3.3
  Bottom Layer w0.2: U27_L1.42@64,148.825 64,147 64.5,146.5 L18_L1.2@64.5,145.775
NetL18_L2_2: L18_L2.2 U27_L2.42 | length 3.3
  Bottom Layer w0.2: U27_L2.42@147.5,133.825 147.5,132 148,131.5 L18_L2.2@148,130.775
NetL18_L3_2: L18_L3.2 U27_L3.42 | length 3.3
  Bottom Layer w0.2: U27_L3.42@233.5,105.825 233.5,104 234,103.5 L18_L3.2@234,102.775
NetL18_N_2: L18_N.2 U27_N.42 | length 3.3
  Bottom Layer w0.2: U27_N.42@87.675,34.5 89.5,34.5 90,35 L18_N.2@90.725,35
NetL20_L1_2: L20_L1.2 U31_L1.42 | length 4.3
  Bottom Layer w0.2: U31_L1.42@80.225,148.8 80.225,146.775 81,146 L20_L1.2@81,144.775
NetL20_L2_2: L20_L2.2 U31_L2.42 | length 4.3
  Bottom Layer w0.2: U31_L2.42@163.725,133.8 163.725,131.775 164.5,131 L20_L2.2@164.5,129.775
NetL20_L3_2: L20_L3.2 U31_L3.42 | length 4.5
  Bottom Layer w0.2: U31_L3.42@249.725,105.8 249.725,103.775 251,102.5 L20_L3.2@251,101.847
NetL20_N_2: L20_N.2 U31_N.42 | length 4.3
  Bottom Layer w0.2: U31_N.42@87.7,50.725 89.725,50.725 91.3,52.3
NetL21_L1_2: L21_L1.2 U36_L1.42 | length 3.3
  Bottom Layer w0.2: U36_L1.42@84.725,168.8 85.025,168.5 85.5,168.5 86,168 L21_L1.2@86,166.275
NetL21_L2_2: L21_L2.2 U36_L2.42 | length 3.3
  Bottom Layer w0.2: U36_L2.42@168.225,153.8 168.525,153.5 169,153.5 169.5,153 L21_L2.2@169.5,151.275
NetL21_L3_2: L21_L3.2 U36_L3.42 | length 3.3
  Bottom Layer w0.2: U36_L3.42@254.225,125.8 254.525,125.5 255,125.5 255.5,125 L21_L3.2@255.5,123.275
NetL21_N_2: L21_N.2 U36_N.42 | length 3.3
  Bottom Layer w0.2: U36_N.42@67.7,55.225 68,55.525 68,56 68.5,56.5 L21_N.2@70.225,56.5
NetMP12_1: MP12.1 U1.5 U1.6 U1.7
  other v1: 189,89.2 192.9,89.3
NetR1_1: R1.1 R2.1 R3.1 R4.2 R5.2 R6.2
NetR4_1: R4.1 R5.1 R6.1 R7.2 R8.2 R9.2
NetR10_1: R10.1 R11.1 R12.1 R13.2 R14.2 R15.2
NetR13_1: R13.1 R14.1 R15.1 R16.2 R17.2 R18.2
NetR19_2: R19.2 U1.4 | length 1.8
  Top Layer w0.2: U1.4@192.805,82.6 192.853,82.553 192.853,80.848 R19.2@192.9,80.8
NetR95_L1_1: R95_L1.1 U26_L1.50 | length 2.8
  Bottom Layer w0.2: U26_L1.50@53.09,168.4 53.09,167.41 53.3,167.2 53.3,166 R95_L1.1@53.5,165.8
NetR95_L2_1: R95_L2.1 U26_L2.50 | length 2.8
  Bottom Layer w0.2: U26_L2.50@136.59,153.4 136.59,152.41 136.8,152.2 136.8,151 R95_L2.1@137,150.8
NetR95_L3_1: R95_L3.1 U26_L3.50 | length 2.8
  Bottom Layer w0.2: U26_L3.50@222.59,125.4 222.59,123.81 222.917,123.483 222.917,122.883 R95_L3.1@223,122.8
NetR95_N_1: R95_N.1 U26_N.50 | length 2.8
  Bottom Layer w0.2: U26_N.50@68.1,23.59 69.69,23.59 70.017,23.917 70.617,23.917 R95_N.1@70.7,24
NetR130_1: R130.1 U7.7 | length 1.7
  Top Layer w0.3: R130.1@133.6,248.3 133.6,249.7 U7.7@133.8,249.9
NetR132_1: R132.1 U8.7 | length 2.2
  Top Layer w0.3: R132.1@119.6,248 119.77,248.17 U8.7@119.77,250.1
NetR134_1: R134.1 U9.7 | length 1.4
  Top Layer w0.3: R134.1@108.405,248.445 108.405,249.705 U9.7@108.5,249.8
NetR136_2: R136.2 U10.1 | length 1.8
  Top Layer w0.2: R136.2@96.2,249.3 96.25,249.3 96.45,249.5 U10.1@96.45,251
NetR138_1: R138.1 U11.3 | length 1.7
  Top Layer w0.3: v1(87.2,91.5) 87.2,91.584 87.354,91.738 87.354,92.179 87.44,92.265 U11.3@87.465,92.265
  Bottom Layer w0.3: v1(87.2,91.5) 87.2,91.416 87.379,91.237 87.379,90.868 87.448,90.8 R138.1@87.5,90.8
NetR143_2: R143.2 U13.1 | length 1.8
  Top Layer w0.2: U13.1@97.713,102.854 97.713,103.863 98.05,104.2 98.05,104.45 R143.2@98,104.5
NetR165_1: R165.1 U15.3 | length 2.8
  Top Layer w0.4: R165.1@159.468,62.516 160.218,62.516 160.668,62.966 U15.3@162.068,62.966
NetR166_1: R166.1 U15.6 | length 4.6
  Top Layer w0.4: R166.1@159.468,58.766 160.468,58.766 160.968,59.266 160.968,60.666 161.31,61.009 162.28,61.009 U15.6@162.289,61.018
NetR167_1: R167.1 U15.8 | length 1.4
  Top Layer w0.4: R167.1@168.168,58.966 168.179,58.977 168.179,60.357 U15.8@168.189,60.368
NetR168_1: R168.1 U15.11 | length 5.9
  Top Layer w0.4: U15.11@168.189,62.318 173.918,62.318 173.968,62.368 R168.1@173.968,62.466
NetR176_1: R176.1 U16.3 | length 2.7
  Top Layer w0.4: R176.1@144.463,62.712 144.513,62.762 145.213,62.762 145.788,63.337 U16.3@146.861,63.337
NetR177_1: R177.1 U17.3 | length 2.8
  Top Layer w0.4: U17.3@216.866,26.752 219.552,26.752 R177.1@219.6,26.8
NetR178_1: R178.1 U16.6 | length 3.6
  Top Layer w0.4: R178.1@144.663,59.612 145.263,59.612 145.663,60.012 145.663,61.144 145.897,61.378 146.851,61.378 U16.6@146.861,61.387
NetR179_1: R179.1 U17.6 | length 3.8
  Top Layer w0.4: U17.6@216.866,28.702 216.876,28.712 217.812,28.712 218.4,29.3 218.4,29.8 218.9,30.3 R179.1@219.7,30.3
NetR180_1: R180.1 U16.8 | length 2.9
  Top Layer w0.4: U16.8@152.761,60.737 153.238,60.737 154.663,59.312 R180.1@155.063,59.312
NetR181_1: R181.1 U17.8 | length 2.7
  Top Layer w0.4: R181.1@208.8,30.75 210.188,29.362 210.957,29.362 U17.8@210.966,29.352
NetR182_1: R182.1 U16.11 | length 2.5
  Top Layer w0.4: U16.11@152.761,62.687 152.77,62.678 153.797,62.678 154.163,62.312 R182.1@155.063,62.312
NetR183_1: R183.1 U17.11 | length 2.3
  Top Layer w0.4: R183.1@208.7,27.4 R183.1@208.7,27.4 210.965,27.401 U17.11@210.966,27.402
NetR195_1: R195.1 U18.3 | length 2.5
  Top Layer w0.4: U18.3@232.55,28.45 232.56,28.44 234.96,28.44 R195.1@235,28.4
NetR196_1: R196.1 U18.6 | length 3.3
  Top Layer w0.4: U18.6@232.55,30.4 232.56,30.41 233.268,30.41 234,31.141 234,31.766 234.234,32 R196.1@234.8,32
NetR197_1: R197.1 U18.8 | length 2.3
  Top Layer w0.4: R197.1@224.5,31.4 224.55,31.35 225.15,31.35 225.45,31.05 U18.8@226.65,31.05
NetR198_1: R198.1 U18.11 | length 2.9
  Top Layer w0.4: R198.1@224.266,27.916 224.6,28.25 224.716,28.25 225.556,29.09 226.64,29.09 U18.11@226.65,29.1
NetR229_L1_1: R229_L1.1 U27_L1.50 | length 3.1
  Bottom Layer w0.2: R229_L1.1@57.5,145.3 57.64,145.44 U27_L1.50@57.64,148.3
NetR229_L2_1: R229_L2.1 U27_L2.50 | length 3.1
  Bottom Layer w0.2: R229_L2.1@141,130.3 141.14,130.44 U27_L2.50@141.14,133.3
NetR229_L3_1: R229_L3.1 U27_L3.50 | length 3.1
  Bottom Layer w0.2: R229_L3.1@227,102.3 227.14,102.44 U27_L3.50@227.14,105.3
NetR229_N_1: R229_N.1 U27_N.50 | length 3.1
  Bottom Layer w0.2: U27_N.50@88.2,28.14 91.06,28.14 R229_N.1@91.2,28
NetR230_L1_1: R230_L1.1 U31_L1.50 | length 3.8
  Bottom Layer w0.2: R230_L1.1@73,144.8 73,146 73.865,146.865 U31_L1.50@73.865,148.275
NetR230_L2_1: R230_L2.1 U31_L2.50 | length 3.8
  Bottom Layer w0.2: R230_L2.1@156.5,129.8 156.5,131 157.365,131.865 U31_L2.50@157.365,133.275
NetR230_L3_1: R230_L3.1 U31_L3.50 | length 3.8
  Bottom Layer w0.2: R230_L3.1@242.5,101.8 242.5,103 243.365,103.865 U31_L3.50@243.365,105.275
NetR230_N_1: R230_N.1 U31_N.50 | length 3.8
  Bottom Layer w0.2: U31_N.50@88.225,44.365 89.635,44.365 90.5,43.5 R230_N.1@91.7,43.5
NetR231_L1_1: R231_L1.1 U36_L1.50 | length 2.5
  Bottom Layer w0.2: U36_L1.50@78.365,168.275 78.365,165.935 R231_L1.1@78.5,165.8
NetR231_L2_1: R231_L2.1 U36_L2.50 | length 2.5
  Bottom Layer w0.2: U36_L2.50@161.865,153.275 161.865,150.935 R231_L2.1@162,150.8
NetR231_L3_1: R231_L3.1 U36_L3.50 | length 2.5
  Bottom Layer w0.2: U36_L3.50@247.865,125.275 247.865,122.935 R231_L3.1@248,122.8
NetR231_N_1: R231_N.1 U36_N.50 | length 2.5
  Bottom Layer w0.2: U36_N.50@68.225,48.865 70.565,48.865 R231_N.1@70.7,49
NetR236_1: R236.1 R237.2
NetR237_1: R237.1 R238.2
NetR238_1: R238.1 R239.2
NetR241_1: R241.1 R242.2
NetR242_1: R242.1 R243.2
NetR243_1: R243.1 R244.2
NetR246_1: R246.1 R247.2
NetR247_1: R247.1 R248.2
NetR248_1: R248.1 R249.2
NetR278_L1_2: R278_L1.2 U28_L1.2 | length 2.6
  Top Layer w0.254: R278_L1.2@35.98,113.592 35.894,113.678 v1(35.894,114.63) 35.894,114.699 36.075,114.879 36.075,116.01 U28_L1.2@36.115,116.05
NetR278_L2_2: R278_L2.2 U28_L2.2 | length 2.6
  Top Layer w0.254: R278_L2.2@119.48,98.592 119.394,98.678 v1(119.394,99.63) 119.394,99.699 119.575,99.879 119.575,101.01 U28_L2.2@119.615,101.05
NetR278_L3_2: R278_L3.2 U28_L3.2 | length 2.6
  Top Layer w0.254: R278_L3.2@205.48,70.592 205.394,70.678 v1(205.394,71.63) 205.394,71.699 205.575,71.879 205.575,73.01 U28_L3.2@205.615,73.05
NetR278_N_2: R278_N.2 U28_N.2 | length 2.6
  Top Layer w0.254: U28_N.2@120.45,6.615 120.49,6.575 121.621,6.575 121.801,6.394 v1(121.87,6.394) 122.822,6.394 R278_N.2@122.908,6.48
NetR279_L1_1: R279_L1.1 U28_L1.6 | length 2.9
  Top Layer w0.254: v1(37.338,128.371) 37.362,128.348 37.362,126.973 U28_L1.6@37.385,126.95
  Bottom Layer w0.254: v1(37.338,128.371) 37.753,128.786 38.313,128.786 R279_L1.1@38.5,128.973
NetR279_L2_1: R279_L2.1 U28_L2.6 | length 2.9
  Top Layer w0.254: v1(120.838,113.371) 120.862,113.348 120.862,111.973 U28_L2.6@120.885,111.95
  Bottom Layer w0.254: v1(120.838,113.371) 121.253,113.786 121.813,113.786 R279_L2.1@122,113.973
NetR279_L3_1: R279_L3.1 U28_L3.6 | length 2.9
  Top Layer w0.254: v1(206.838,85.371) 206.862,85.348 206.862,83.973 U28_L3.6@206.885,83.95
  Bottom Layer w0.254: v1(206.838,85.371) 207.253,85.786 207.813,85.786 R279_L3.1@208,85.973
NetR279_N_1: R279_N.1 U28_N.6 | length 2.9
  Top Layer w0.254: v1(108.129,7.838) 108.152,7.862 109.527,7.862 U28_N.6@109.55,7.885
  Bottom Layer w0.254: R279_N.1@107.527,9 107.714,8.813 107.714,8.253 v1(108.129,7.838)
NetR286_L1_1: R286_L1.1 R288_L1.2 U30_L1.4 | length 6.1
  Top Layer w0.3: U30_L1.4@41.038,133.795 42.005,133.795 42.4,133.4 v1(42.4,132.3)
  Bottom Layer w0.3: R288_L1.2@41.5,131 41.531,130.969 R288_L1.2@41.672,130.969 R286_L1.1@43.704,130.969 ; 42.4,131 v1(42.4,132.3)
NetR286_L2_1: R286_L2.1 R288_L2.2 U30_L2.4 | length 6.1
  Top Layer w0.3: U30_L2.4@124.538,118.795 125.505,118.795 125.9,118.4 v1(125.9,117.3)
  Bottom Layer w0.3: R288_L2.2@125,116 125.031,115.969 R288_L2.2@125.172,115.969 R286_L2.1@127.204,115.969 ; 125.9,116 v1(125.9,117.3)
NetR286_L3_1: R286_L3.1 R288_L3.2 U30_L3.4 | length 6.1
  Top Layer w0.3: U30_L3.4@210.538,90.795 211.505,90.795 211.9,90.4 v1(211.9,89.3)
  Bottom Layer w0.3: R288_L3.2@211,88 211.031,87.969 R288_L3.2@211.172,87.969 R286_L3.1@213.204,87.969 ; 211.9,88 v1(211.9,89.3)
NetR286_N_1: R286_N.1 R288_N.2 U30_N.4 | length 6.1
  Top Layer w0.3: U30_N.4@102.705,11.538 102.705,12.505 103.1,12.9 v1(104.2,12.9)
  Bottom Layer w0.3: v1(104.2,12.9) 105.5,12.9 ; R288_N.2@105.5,12 105.531,12.031 R288_N.2@105.531,12.172 R286_N.1@105.531,14.204
NetR289_L1_1: R289_L1.1 R290_L1.2 U30_L1.3 | length 5
  Top Layer w0.254: U30_L1.3@43.788,133.795 44.513,133.795 ; v1(44.513,134.645) 44.513,133.795 ; R290_L1.2@45.547,134.04 45.302,133.795 44.513,133.795
  Bottom Layer w0.254: R289_L1.1@42.613,133.795 43.663,133.795 v1(44.513,134.645)
NetR289_L2_1: R289_L2.1 R290_L2.2 U30_L2.3 | length 5
  Top Layer w0.254: U30_L2.3@127.288,118.795 128.013,118.795 ; v1(128.013,119.645) 128.013,118.795 ; R290_L2.2@129.047,119.04 128.802,118.795 128.013,118.795
  Bottom Layer w0.254: R289_L2.1@126.113,118.795 127.163,118.795 v1(128.013,119.645)
NetR289_L3_1: R289_L3.1 R290_L3.2 U30_L3.3 | length 5
  Top Layer w0.254: U30_L3.3@213.288,90.795 214.013,90.795 ; v1(214.013,91.645) 214.013,90.795 ; R290_L3.2@215.047,91.04 214.802,90.795 214.013,90.795
  Bottom Layer w0.254: R289_L3.1@212.113,90.795 213.163,90.795 v1(214.013,91.645)
NetR289_N_1: R289_N.1 R290_N.2 U30_N.3 | length 5
  Top Layer w0.254: v1(101.855,15.013) 102.705,15.013 ; R290_N.2@102.46,16.047 102.705,15.802 102.705,15.013 ; U30_N.3@102.705,14.288 102.705,15.013
  Bottom Layer w0.254: v1(101.855,15.013) 102.705,14.163 R289_N.1@102.705,13.113
NetR291_L1_2: R291_L1.2 U32_L1.2 | length 2.5
  Top Layer w0.254: U32_L1.2@52.275,116.05 52.424,115.901 52.424,114.74 v1(52.473,114.692) 52.473,113.898 R291_L1.2@52.66,113.711
NetR291_L2_2: R291_L2.2 U32_L2.2 | length 2.5
  Top Layer w0.254: U32_L2.2@135.775,101.05 135.924,100.901 135.924,99.74 v1(135.973,99.692) 135.973,98.898 R291_L2.2@136.16,98.711
NetR291_L3_2: R291_L3.2 U32_L3.2 | length 2.5
  Top Layer w0.254: U32_L3.2@221.775,73.05 221.924,72.901 221.924,71.74 v1(221.973,71.692) 221.973,70.898 R291_L3.2@222.16,70.711
NetR291_N_2: R291_N.2 U32_N.2 | length 2.5
  Top Layer w0.254: U32_N.2@120.45,22.775 120.599,22.924 121.76,22.924 v1(121.808,22.973) 122.602,22.973 R291_N.2@122.789,23.16
NetR292_L1_1: R292_L1.1 U32_L1.6 | length 2.2
  Top Layer w0.254: v1(53.385,128.332) 53.434,128.284 53.434,127.061 U32_L1.6@53.545,126.95
  Bottom Layer w0.254: v1(53.385,128.332) R292_L1.1@53.385,129.082
NetR292_L2_1: R292_L2.1 U32_L2.6 | length 2.2
  Top Layer w0.254: v1(136.885,113.332) 136.934,113.284 136.934,112.061 U32_L2.6@137.045,111.95
  Bottom Layer w0.254: v1(136.885,113.332) R292_L2.1@136.885,114.082
NetR292_L3_1: R292_L3.1 U32_L3.6 | length 2.2
  Top Layer w0.254: v1(222.885,85.332) 222.934,85.284 222.934,84.061 U32_L3.6@223.045,83.95
  Bottom Layer w0.254: v1(222.885,85.332) R292_L3.1@222.885,86.082
NetR292_N_1: R292_N.1 U32_N.6 | length 2.2
  Top Layer w0.254: v1(108.168,23.885) 108.216,23.934 109.439,23.934 U32_N.6@109.55,24.045
  Bottom Layer w0.254: R292_N.1@107.418,23.885 v1(108.168,23.885)
NetR293_L1_2: R293_L1.2 U33_L1.4 | length 2.1
  Top Layer w0.2: U33_L1.4@67.375,110.05 67.375,108.125 R293_L1.2@67.5,108
NetR293_L2_2: R293_L2.2 U33_L2.4 | length 1.6
  Top Layer w0.2: U33_L2.4@150.875,95.05 150.875,93.625 R293_L2.2@151,93.5
NetR293_L3_2: R293_L3.2 U33_L3.4 | length 1.6
  Top Layer w0.2: U33_L3.4@236.875,67.05 236.875,65.625 R293_L3.2@237,65.5
NetR293_N_2: R293_N.2 U33_N.4 | length 1.6
  Top Layer w0.2: U33_N.4@126.45,37.875 127.875,37.875 R293_N.2@128,38
NetR297_L1_1: R297_L1.1 R299_L1.2 U35_L1.4 | length 5.7
  Top Layer w0.254: U35_L1.4@56.9,133.066 56.903,133.062 57.772,133.062 v1(57.775,133.059)
  Bottom Layer w0.254: v1(57.775,133.059) 57.775,130.046 R299_L1.2@57.736,130.007 R297_L1.1@59.456,130.007
NetR297_L2_1: R297_L2.1 R299_L2.2 U35_L2.4 | length 5.7
  Top Layer w0.254: U35_L2.4@140.4,118.066 140.403,118.062 141.272,118.062 v1(141.275,118.059)
  Bottom Layer w0.254: v1(141.275,118.059) 141.275,115.046 R299_L2.2@141.236,115.007 R297_L2.1@142.956,115.007
NetR297_L3_1: R297_L3.1 R299_L3.2 U35_L3.4 | length 5.7
  Top Layer w0.254: U35_L3.4@226.4,90.066 226.403,90.062 227.272,90.062 v1(227.275,90.059)
  Bottom Layer w0.254: v1(227.275,90.059) 227.275,87.046 R299_L3.2@227.236,87.007 R297_L3.1@228.956,87.007
NetR297_N_1: R297_N.1 R299_N.2 U35_N.4 | length 5.7
  Top Layer w0.254: U35_N.4@103.434,27.4 103.438,27.403 103.438,28.272 v1(103.441,28.275)
  Bottom Layer w0.254: v1(103.441,28.275) 106.454,28.275 R299_N.2@106.493,28.236 R297_N.1@106.493,29.956
NetR300_L1_1: R300_L1.1 R301_L1.2 U35_L1.3 | length 4.5
  Top Layer w0.254: U35_L1.3@59.65,133.066 59.45,133.066 59.277,133.239 59.277,133.439 59.144,133.572 R300_L1.1@59.144,134.875 59.492,134.527 60.106,134.527 60.299,134.334 R301_L1.2@61.244,134.334
NetR300_L2_1: R300_L2.1 R301_L2.2 U35_L2.3 | length 4.5
  Top Layer w0.254: U35_L2.3@143.15,118.066 142.95,118.066 142.777,118.239 142.777,118.439 142.644,118.572 R300_L2.1@142.644,119.875 142.992,119.527 143.606,119.527 143.799,119.334 R301_L2.2@144.744,119.334
NetR300_L3_1: R300_L3.1 R301_L3.2 U35_L3.3 | length 4.5
  Top Layer w0.254: U35_L3.3@229.15,90.066 228.95,90.066 228.777,90.239 228.777,90.439 228.644,90.572 R300_L3.1@228.644,91.875 228.992,91.527 229.606,91.527 229.799,91.334 R301_L3.2@230.744,91.334
NetR300_N_1: R300_N.1 R301_N.2 U35_N.3 | length 4.5
  Top Layer w0.254: R301_N.2@102.166,31.744 102.166,30.799 101.973,30.606 101.973,29.992 R300_N.1@101.625,29.644 102.928,29.644 103.061,29.777 103.261,29.777 103.434,29.95 U35_N.3@103.434,30.15
NetR302_L1_2: R302_L1.2 U37_L1.2 | length 2.5
  Top Layer w0.254: U37_L1.2@73.994,115.05 73.994,113.744 74.233,113.505 74.233,113.022 R302_L1.2@74.5,112.755
NetR302_L2_2: R302_L2.2 U37_L2.2 | length 2.5
  Top Layer w0.254: U37_L2.2@157.494,100.05 157.494,98.744 157.733,98.505 157.733,98.022 R302_L2.2@158,97.755
NetR302_L3_2: R302_L3.2 U37_L3.2 | length 2.5
  Top Layer w0.254: U37_L3.2@243.494,72.05 243.494,70.744 243.733,70.505 243.733,70.022 R302_L3.2@244,69.755
NetR302_N_2: R302_N.2 U37_N.2 | length 2.5
  Top Layer w0.254: U37_N.2@121.45,44.494 122.756,44.494 122.995,44.733 123.478,44.733 R302_N.2@123.745,45
NetR303_L1_1: R303_L1.1 U37_L1.6 | length 3.9
  Top Layer w0.254: U37_L1.6@75.264,125.95 75.264,126.55 75.682,126.968 75.84,126.968 75.989,127.116 75.989,127.46 v1(76.486,127.956)
  Bottom Layer w0.254: R303_L1.1@75.264,127.866 75.354,127.956 v1(76.486,127.956)
NetR303_L2_1: R303_L2.1 U37_L2.6 | length 3.9
  Top Layer w0.254: U37_L2.6@158.764,110.95 158.764,111.55 159.182,111.968 159.34,111.968 159.489,112.116 159.489,112.46 v1(159.986,112.956)
  Bottom Layer w0.254: R303_L2.1@158.764,112.866 158.854,112.956 v1(159.986,112.956)
NetR303_L3_1: R303_L3.1 U37_L3.6 | length 3.9
  Top Layer w0.254: U37_L3.6@244.764,82.95 244.764,83.55 245.182,83.968 245.34,83.968 245.489,84.116 245.489,84.46 v1(245.986,84.956)
  Bottom Layer w0.254: R303_L3.1@244.764,84.866 244.854,84.956 v1(245.986,84.956)
NetR303_N_1: R303_N.1 U37_N.6 | length 3.9
  Top Layer w0.254: v1(108.544,46.986) 109.04,46.489 109.384,46.489 109.532,46.34 109.532,46.182 109.95,45.764 U37_N.6@110.55,45.764
  Bottom Layer w0.254: v1(108.544,46.986) 108.544,45.854 R303_N.1@108.634,45.764
NetR307_L1_1: R307_L1.1 R309_L1.2 U40_L1.4 | length 6.7
  Top Layer w0.254: v1(79.11,133.083) 79.11,133.014 79.21,132.914 79.21,132.406 79.383,132.233 U40_L1.4@79.583,132.233
  Bottom Layer w0.254: v1(79.11,133.083) 81.033,131.16 81.033,129.707 ; R309_L1.2@80.36,129.707 81.033,129.707 ; R307_L1.1@81.758,129.707 81.033,129.707
NetR307_L2_1: R307_L2.1 R309_L2.2 U40_L2.4 | length 6.7
  Top Layer w0.254: v1(162.61,118.083) 162.61,118.014 162.71,117.914 162.71,117.406 162.883,117.233 U40_L2.4@163.083,117.233
  Bottom Layer w0.254: v1(162.61,118.083) 164.533,116.16 164.533,114.707 ; R309_L2.2@163.86,114.707 164.533,114.707 ; R307_L2.1@165.258,114.707 164.533,114.707
NetR307_L3_1: R307_L3.1 R309_L3.2 U40_L3.4 | length 6.7
  Top Layer w0.254: v1(248.61,90.083) 248.61,90.014 248.71,89.914 248.71,89.406 248.883,89.233 U40_L3.4@249.083,89.233
  Bottom Layer w0.254: v1(248.61,90.083) 250.533,88.16 250.533,86.707 ; R309_L3.2@249.86,86.707 250.533,86.707 ; R307_L3.1@251.258,86.707 250.533,86.707
NetR307_N_1: R307_N.1 R309_N.2 U40_N.4 | length 6.7
  Top Layer w0.254: v1(103.417,49.61) 103.486,49.61 103.586,49.71 104.094,49.71 104.267,49.883 U40_N.4@104.267,50.083
  Bottom Layer w0.254: v1(103.417,49.61) 105.34,51.533 106.793,51.533 ; R309_N.2@106.793,50.86 106.793,51.533 ; R307_N.1@106.793,52.258 106.793,51.533
NetR310_L1_1: R310_L1.1 R311_L1.2 U40_L1.3 | length 3.9
  Top Layer w0.254: U40_L1.3@82.333,132.233 82.256,132.233 82.083,132.406 R310_L1.1@82.083,133.942 83.652,133.942 84,133.594 R311_L1.2@84,133.584
NetR310_L2_1: R310_L2.1 R311_L2.2 U40_L2.3 | length 3.9
  Top Layer w0.254: U40_L2.3@165.833,117.233 165.756,117.233 165.583,117.406 R310_L2.1@165.583,118.942 167.152,118.942 167.5,118.594 R311_L2.2@167.5,118.584
NetR310_L3_1: R310_L3.1 R311_L3.2 U40_L3.3 | length 3.9
  Top Layer w0.254: U40_L3.3@251.833,89.233 251.756,89.233 251.583,89.406 R310_L3.1@251.583,90.942 253.152,90.942 253.5,90.594 R311_L3.2@253.5,90.584
NetR310_N_1: R310_N.1 R311_N.2 U40_N.3 | length 3.9
  Top Layer w0.254: R311_N.2@102.916,54.5 102.906,54.5 102.558,54.152 R310_N.1@102.558,52.583 104.094,52.583 104.267,52.756 U40_N.3@104.267,52.833
NetR312_L1_2: R312_L1.2 R313_L1.1 | length 2.1
  Top Layer w0.2: R313_L1.1@66.5,134.1 66.5,133.617 66.617,133.5 67.95,133.5 R312_L1.2@68,133.45
NetR312_L2_2: R312_L2.2 R313_L2.1 | length 2.1
  Top Layer w0.2: R313_L2.1@150,119.1 150,118.617 150.117,118.5 151.45,118.5 R312_L2.2@151.5,118.45
NetR312_L3_2: R312_L3.2 R313_L3.1 | length 2.1
  Top Layer w0.2: R313_L3.1@236,91.1 236,90.617 236.117,90.5 237.45,90.5 R312_L3.2@237.5,90.45
NetR312_N_2: R312_N.2 R313_N.1 | length 2.1
  Top Layer w0.2: R313_N.1@102.4,37 102.883,37 103,37.117 103,38.45 R312_N.2@103.05,38.5
NetR313_L1_2: R313_L1.2 R314_L1.1 | length 1.5
  Top Layer w0.2: R314_L1.1@66.45,137.5 66.45,136.05 R313_L1.2@66.5,136
NetR313_L2_2: R313_L2.2 R314_L2.1 | length 1.5
  Top Layer w0.2: R314_L2.1@149.95,122.5 149.95,121.05 R313_L2.2@150,121
NetR313_L3_2: R313_L3.2 R314_L3.1 | length 1.5
  Top Layer w0.2: R314_L3.1@235.95,94.5 235.95,93.05 R313_L3.2@236,93
NetR313_N_2: R313_N.2 R314_N.1 | length 1.5
  Top Layer w0.2: R314_N.1@99,36.95 100.45,36.95 R313_N.2@100.5,37
NetR316_L1_2: R316_L1.2 U43_L1.2 | length 2.6
  Top Layer w0.254: U43_L1.2@90.343,115.226 90.343,113.907 90.725,113.525 R316_L1.2@90.725,112.755
NetR316_L2_2: R316_L2.2 U43_L2.2 | length 2.6
  Top Layer w0.254: U43_L2.2@173.843,100.226 173.843,98.907 174.225,98.525 R316_L2.2@174.225,97.755
NetR316_L3_2: R316_L3.2 U43_L3.2 | length 2.6
  Top Layer w0.254: U43_L3.2@259.843,72.226 259.843,70.907 260.225,70.525 R316_L3.2@260.225,69.755
NetR316_N_2: R316_N.2 U43_N.2 | length 2.6
  Top Layer w0.254: U43_N.2@121.274,60.843 122.593,60.843 122.975,61.225 R316_N.2@123.745,61.225
NetR317_L1_1: R317_L1.1 U43_L1.6 | length 2.5
  Top Layer w0.254: U43_L1.6@91.613,126.126 91.786,126.299 91.786,127.24 91.925,127.379 v1(91.925,127.448)
  Bottom Layer w0.254: R317_L1.1@91.2,128.198 91.548,127.85 91.548,127.825 v1(91.925,127.448)
NetR317_L2_1: R317_L2.1 U43_L2.6 | length 2.5
  Top Layer w0.254: U43_L2.6@175.113,111.126 175.286,111.299 175.286,112.24 175.425,112.379 v1(175.425,112.448)
  Bottom Layer w0.254: R317_L2.1@174.7,113.198 175.048,112.85 175.048,112.825 v1(175.425,112.448)
NetR317_L3_1: R317_L3.1 U43_L3.6 | length 2.5
  Top Layer w0.254: U43_L3.6@261.113,83.126 261.286,83.299 261.286,84.24 261.425,84.379 v1(261.425,84.448)
  Bottom Layer w0.254: R317_L3.1@260.7,85.198 261.048,84.85 261.048,84.825 v1(261.425,84.448)
NetR317_N_1: R317_N.1 U43_N.6 | length 2.5
  Top Layer w0.254: v1(109.052,62.425) 109.121,62.425 109.26,62.286 110.201,62.286 U43_N.6@110.374,62.113
  Bottom Layer w0.254: R317_N.1@108.302,61.7 108.65,62.048 108.675,62.048 v1(109.052,62.425)
NetR324_L1_1: R324_L1.1 R326_L1.2 U45_L1.4 | length 5.6
  Top Layer w0.254: U45_L1.4@94.733,132.4 94.938,132.195 95.463,132.195 v1(95.751,131.908)
  Bottom Layer w0.254: R326_L1.2@94.726,129.623 R324_L1.1@96.476,129.623 96.476,131.183 v1(95.751,131.908)
NetR324_L2_1: R324_L2.1 R326_L2.2 U45_L2.4 | length 5.6
  Top Layer w0.254: U45_L2.4@178.233,117.4 178.438,117.195 178.963,117.195 v1(179.251,116.908)
  Bottom Layer w0.254: R326_L2.2@178.226,114.623 R324_L2.1@179.976,114.623 179.976,116.183 v1(179.251,116.908)
NetR324_L3_1: R324_L3.1 R326_L3.2 U45_L3.4 | length 5.6
  Top Layer w0.254: U45_L3.4@264.233,89.4 264.438,89.195 264.963,89.195 v1(265.251,88.908)
  Bottom Layer w0.254: R326_L3.2@264.226,86.623 R324_L3.1@265.976,86.623 265.976,88.183 v1(265.251,88.908)
NetR324_N_1: R324_N.1 R326_N.2 U45_N.4 | length 5.6
  Top Layer w0.254: U45_N.4@104.1,65.233 104.305,65.438 104.305,65.963 v1(104.592,66.251)
  Bottom Layer w0.254: v1(104.592,66.251) 105.317,66.976 R324_N.1@106.877,66.976 R326_N.2@106.877,65.226
NetR327_L1_1: R327_L1.1 R328_L1.2 U45_L1.3 | length 3.3
  Top Layer w0.254: R327_L1.1@97.003,133.659 97.753,133.659 98.892,133.659 R328_L1.2@99.044,133.508 ; U45_L1.3@97.551,132.581 97.754,132.784 97.754,133.659
NetR327_L2_1: R327_L2.1 R328_L2.2 U45_L2.3 | length 3.3
  Top Layer w0.254: R327_L2.1@180.503,118.659 181.253,118.659 182.392,118.659 R328_L2.2@182.544,118.508 ; U45_L2.3@181.051,117.581 181.254,117.784 181.254,118.659
NetR327_L3_1: R327_L3.1 R328_L3.2 U45_L3.3 | length 3.3
  Top Layer w0.254: R327_L3.1@266.503,90.659 267.253,90.659 268.392,90.659 R328_L3.2@268.544,90.508 ; U45_L3.3@267.051,89.581 267.254,89.784 267.254,90.659
NetR327_N_1: R327_N.1 R328_N.2 U45_N.3 | length 3.3
  Top Layer w0.254: R327_N.1@102.841,67.503 102.841,68.253 102.841,69.392 R328_N.2@102.992,69.544 ; 102.841,68.254 103.716,68.254 U45_N.3@103.919,68.051
NetR332_2: R332.2 U12.7 | length 1.9
  Top Layer w0.2: U12.7@181.8,35.41 183.59,35.41 R332.2@183.7,35.3
OC_L1: C33.1 R62.2 R99.1 U2.3 | length 431.8
  Top Layer w0.3: U2.3@93.875,238.555 94.025,238.405 95.095,238.405 96,237.5 v1(96,236.988) 96,236.476 96.176,236.3 97,236.3 R99.1@97.2,236.1
  Top Layer w0.4: R62.2@217.9,53.4 C33.1@217.9,55 ; R62.2@218,53.4 218.04,53.36 218.96,53.36 v1(219,53.4)
  Layer 2 w0.2: v1(219,53.4) 223.2,53.4 226.305,50.295 256.334,50.295 256.439,50.4 v1(260.3,50.4)
  Bottom Layer w0.2: v1(96,236.988) 104.028,236.988 105.84,238.8 140.3,238.8 150.351,228.749 191.451,228.749 214.1,206.1 273.7,206.1 284.7,195.1 287.4,192.4 287.4,50.7 285.6,48.9 261.7,48.9 260.3,50.3 v1(260.3,50.4)
OC_L2: C39.1 R64.2 R109.1 U4.3 | length 413.8
  Top Layer w0.2: R109.1@112.8,226 112.8,226.7 113.2,227.1 v1(114.3,227.1)
  Top Layer w0.3: U4.3@110.6,226 110.725,225.875 112.675,225.875 R109.1@112.8,226
  Top Layer w0.4: R64.2@216.1,51.7 v1(216.1,52.6) C39.1@216.1,53.3
  Layer 2 w0.2: v1(216.1,52.6) 218.6,55.1 222.4,55.1 226.805,50.695 256.168,50.695 256.509,51.036 v1(260.829,51.036)
  Bottom Layer w0.2: v1(114.3,227.1) 114.3,227.146 114.705,227.551 114.705,228.195 114.7,228.2 114.7,232.6 117,234.9 133.5,234.9 142,226.4 187.8,226.4 211.794,202.406 271.477,202.406 286,187.883 286,52.6 282.861,49.461 262.339,49.461 260.829,50.971 v1(260.829,51.036)
OC_L3: C45.1 R66.2 R117.1 U5.3 | length 307.6
  Top Layer w0.3: U5.3@196.5,202.2 196.5,202.135 196.595,202.04 v1(197.518,202.04) 198.44,202.04 R117.1@198.6,202.2
  Top Layer w0.4: C45.1@211.4,55 211.46,54.94 212.16,54.94 v1(212.2,54.9) 213,54.9 R66.2@213.1,55
  Layer 2 w0.2: v1(212.2,54.9) 213.2,55.9 222.7,55.9 225.8,52.8 243.1,52.8 244,51.9 251,51.9 251.7,52.6 260.5,52.6 v1(262.1,51)
  Bottom Layer w0.2: v1(197.518,202.04) 198.296,201.263 270.537,201.263 284.8,187 284.8,62.679 280.993,58.871 280.993,51.15 279.943,50.1 263,50.1 v1(262.1,51)
OC_N: C52.1 R78.2 R123.1 U6.3 | length 176.9
  Top Layer w0.2: U6.3@39.09,104.01 39.805,104.725 v1(40.412,104.725) 41.019,104.725 41.019,104.181 R123.1@41.2,104 ; v1(185.4,49.3) 186.4,49.3 R78.2@186.55,49.45
  Top Layer w0.4: R78.2@186.55,49.45 186.55,51.05 C52.1@186.6,51.1
  Bottom Layer w0.2: v1(40.412,104.725) 40.691,104.446 50.946,104.446 52.946,106.446 62.446,106.446 63.5,107.5 69,107.5 74,102.5 83.725,102.5 83.875,102.35 92.366,102.35 92.371,102.346 101.654,102.346 151.846,52.154 156.613,52.154 156.938,51.829 156.938,51.362 159.3,49 185.1,49 v1(185.4,49.3)
PCC_L1: F1.2 J3.1 TP2.1
  other v1: 245,281 246,281 247,281 248,281 249,281 250,281 251,281 245,282 246,282 247,282 248,282 249,282 250,282 251,282 245,283 246,283 247,283 248,283 249,283 250,283 245,284 246,284 247,284 248,284 249,284 250,284
PCC_L2: F2.2 J5.1 TP3.1
  other v1: 225,281 226,281 227,281 228,281 229,281 230,281 231,281 232.013,281.006 233,281 234,281 225,282 226,282 227,282 228,282 229,282 230,282 231,282 232,282 233,282 234,282 225,283 226,283 227,283 228,283 229,283 230,283
PCC_L3: F3.2 J7.1 TP4.1
  other v1: 209,280 208,281 209,281 210,281 211,281 212,281 208,282 209,282 210,282 211,282 212,282
PCC_N: F4.2 J8.1 TP7.1
  other v1: 264,282 265,282 266,282 267,282 268,282 269,282 270,282 264,283 265,283 266,283 267,283 268,283 269,283 270,283 264,284 265,284 266,284 267,284 268,284 269,284 270,284
PWM_S1_DRIVER_GaN_L1: C188_L1.2 R279_L1.2 U26_L1.45 | length 47.8
  Top Layer w0.254: v1(40.05,135.651) 44,139.601 44,149.5 52.55,158.05 52.55,160.05 56.5,164 v1(56.5,166.5)
  Bottom Layer w0.2: U26_L1.45@56.34,168.4 56.34,167.34 55.5,166.5 55.5,166.2 55.7,166 56,166 v1(56.5,166.5)
  Bottom Layer w0.254: R279_L1.2@38.5,130.573 38.507,130.566 39.475,130.566 39.475,134.334 40.05,134.909 v1(40.05,135.651)
PWM_S1_DRIVER_GaN_L2: C188_L2.2 R279_L2.2 U26_L2.45 | length 47.8
  Top Layer w0.254: v1(123.55,120.651) 127.5,124.601 127.5,134.5 136.05,143.05 136.05,145.05 140,149 v1(140,151.5)
  Bottom Layer w0.2: U26_L2.45@139.84,153.4 139.84,152.34 139,151.5 139,151.2 139.2,151 139.5,151 v1(140,151.5)
  Bottom Layer w0.254: R279_L2.2@122,115.573 122.007,115.566 122.975,115.566 122.975,119.334 123.55,119.909 v1(123.55,120.651)
PWM_S1_DRIVER_GaN_L3: C188_L3.2 R279_L3.2 U26_L3.45 | length 47.8
  Top Layer w0.254: v1(209.55,92.651) 213.5,96.601 213.5,106.5 222.05,115.05 222.05,117.05 226,121 v1(226,123.5)
  Bottom Layer w0.2: U26_L3.45@225.84,125.4 225.84,124.34 225,123.5 225,123.2 225.2,123 225.5,123 v1(226,123.5)
  Bottom Layer w0.254: R279_L3.2@208,87.573 208.007,87.566 208.975,87.566 208.975,91.334 209.55,91.909 v1(209.55,92.651)
PWM_S1_DRIVER_GaN_N: C188_N.2 R279_N.2 U26_N.45 | length 47.8
  Top Layer w0.254: v1(70,27) 72.5,27 76.45,23.05 78.45,23.05 87,14.5 96.899,14.5 v1(100.849,10.55)
  Bottom Layer w0.2: U26_N.45@68.1,26.84 69.16,26.84 70,26 70.3,26 70.5,26.2 70.5,26.5 v1(70,27)
  Bottom Layer w0.254: v1(100.849,10.55) 101.591,10.55 102.166,9.975 105.934,9.975 105.934,9.007 R279_N.2@105.927,9
PWM_S1_FAULT_GaN_L1: C189_L1.2 U26_L1.46 U28_L1.7 | length 50.9
  Top Layer w0.2: v1(37.05,136.1) 37.6,136.1 43,141.5 43,150.5 51.5,159 51.5,161 55,164.5 v1(55,167)
  Top Layer w0.254: U28_L1.7@36.115,126.95 36.115,128.136 v1(36.325,128.346) 36.325,129.024 C189_L1.2@36.467,129.166
  Bottom Layer w0.2: v1(55,167) 55.042,167.042 55.342,167.042 55.69,167.39 U26_L1.46@55.69,168.4
  Bottom Layer w0.254: v1(36.325,128.346) 36.325,135.375 v1(37.05,136.1)
PWM_S1_FAULT_GaN_L2: C189_L2.2 U26_L2.46 U28_L2.7 | length 50.8
  Top Layer w0.2: v1(120.55,121.1) 121.1,121.1 126.5,126.5 126.5,135.5 135,144 135,146 138.5,149.5 v1(138.5,152)
  Top Layer w0.254: U28_L2.7@119.615,111.95 119.615,113.136 v1(119.825,113.346) 119.825,114.024 C189_L2.2@119.967,114.166
  Bottom Layer w0.2: v1(138.5,152) 139.065,152.565 139.065,153.275 U26_L2.46@139.19,153.4
  Bottom Layer w0.254: v1(119.825,113.346) 119.825,120.375 v1(120.55,121.1)
PWM_S1_FAULT_GaN_L3: C189_L3.2 U26_L3.46 U28_L3.7 | length 50.8
  Top Layer w0.2: v1(206.55,93.1) 207.1,93.1 212.5,98.5 212.5,107.5 221,116 221,118 224.5,121.5 v1(224.5,124)
  Top Layer w0.254: U28_L3.7@205.615,83.95 205.615,85.136 v1(205.825,85.346) 205.825,86.024 C189_L3.2@205.967,86.166
  Bottom Layer w0.2: v1(224.5,124) 225.065,124.565 225.065,125.275 U26_L3.46@225.19,125.4
  Bottom Layer w0.254: v1(205.825,85.346) 205.825,92.375 v1(206.55,93.1)
PWM_S1_FAULT_GaN_N: C189_N.2 U26_N.46 U28_N.7 | length 50.8
  Top Layer w0.2: v1(69.5,25.5) 72,25.5 75.5,22 77.5,22 86,13.5 95,13.5 100.4,8.1 v1(100.4,7.55)
  Top Layer w0.254: C189_N.2@107.334,6.967 107.476,6.825 v1(108.154,6.825) 108.364,6.615 U28_N.7@109.55,6.615
  Bottom Layer w0.2: U26_N.46@68.1,26.19 68.143,26.147 68.853,26.147 v1(69.5,25.5)
  Bottom Layer w0.254: v1(100.4,7.55) 101.125,6.825 v1(108.154,6.825)
PWM_S1_GaN_A: J13.8 R29.1 | length 97
  Top Layer w0.4: J13.8@205.31,19.5 207.91,16.9 234.297,16.9 241.097,23.7 253.349,23.7 256.547,26.899 256.547,49.901 255.014,51.434 255.014,51.886 v1(255,51.9) ; R29.1@241.1,50.9 v1@241.1,51.4
  Bottom Layer w0.4: v1(241.1,51.6) 241.795,52.295 242.598,52.295 242.608,52.305 243.192,52.305 243.197,52.3 254.6,52.3 v1(255,51.9)
PWM_S1_GaN_B: R59.1
PWM_S1_GaN_BUF_L1: C191_L1.2 R165.2 R284_L1.2 TP21_L1.1 U28_L1.3 | length 163.1
  Top Layer w0.2: v1(32.5,112.5) TP21_L1.1@32.5,114 ; v1(155,76.5) 155,73 157.984,70.016 157.984,65.767 157.868,65.652 157.868,62.899 158.101,62.666 158.318,62.666 R165.2@158.468,62.516
  Top Layer w0.254: U28_L1.3@37.385,116.05 37.362,116.027 37.362,114.262 C191_L1.2@37.338,114.238 37.561,114.015 37.561,113.75 37.7,113.611 R284_L1.2@37.7,112.755 37.625,112.68 v1(37.625,111.68)
  Layer 2 w0.2: v1(37.625,111.68) 38.642,111.68 43.876,106.446 48.063,106.446 49.117,107.5 102.934,107.5 117.934,92.5 v1(120.5,92.5)
  Bottom Layer w0.2: v1(32.5,112.5) 32.5,112.453 34.507,110.446 36.391,110.446 v1(37.625,111.68) ; v1(120.5,92.5) 121.434,93.434 121.949,93.434 122.066,93.317 122.066,91.066 136.131,77 154.5,77 v1(155,76.5)
PWM_S1_GaN_BUF_L2: C191_L2.2 R176.2 R284_L2.2 TP21_L2.1 U28_L2.3 | length 59.5
  Top Layer w0.2: v1(116,97.5) TP21_L2.1@116,99 ; v1(121.125,96.68) 121.5,96.305 121.5,94.5 122.5,93.5 123.5,93.5 137.5,79.5 137.5,63.5 138.288,62.712 R176.2@143.563,62.712
  Top Layer w0.254: U28_L2.3@120.885,101.05 120.862,101.027 120.862,99.262 C191_L2.2@120.838,99.238 121.061,99.015 121.061,98.75 121.2,98.611 R284_L2.2@121.2,97.755 121.125,97.68 v1(121.125,96.68)
  Bottom Layer w0.2: v1(116,97.5) 116,97.453 118.007,95.446 119.891,95.446 v1(121.125,96.68)
PWM_S1_GaN_BUF_L3: C191_L3.2 R195.2 R284_L3.2 TP21_L3.1 U28_L3.3 | length 111.2
  Top Layer w0.2: v1(202,69.5) TP21_L3.1@202,71 ; v1(207,64) 212,59 232.5,59 233.5,60 241.112,60 242.112,59 246.3,59 250.4,54.9 250.4,49.2 251.7,47.9 253.7,47.9 255.3,46.3 255.3,34.9 248,27.6 240.2,27.6 239.4,28.4 R195.2@235.9,28.4
  Top Layer w0.254: U28_L3.3@206.885,73.05 206.862,73.027 206.862,71.262 C191_L3.2@206.838,71.238 207.061,71.015 207.061,70.75 207.2,70.611 R284_L3.2@207.2,69.755 207.125,69.68 v1(207.125,68.68)
  Bottom Layer w0.2: v1(202,69.5) 202,69.453 204.007,67.446 205.891,67.446 v1@206.958,68.513 ; v1(207,64) 207,64.083 207.125,64.208 v1(207.125,68.68) ; v1@207,68.472 v1@207.125,68.597
PWM_S1_GaN_BUF_N: C191_N.2 R177.2 R284_N.2 TP21_N.1 U28_N.3 | length 139.7
  Top Layer w0.2: TP21_N.1@122.5,3 v1(124,3) ; v1(146,31) v1(146,36) ; v1(204.2,25.5) 208,21.7 220.5,21.7 221.4,22.6 221.4,26.5 221.1,26.8 R177.2@220.6,26.8
  Top Layer w0.254: U28_N.3@120.45,7.885 120.473,7.862 122.238,7.862 C191_N.2@122.262,7.838 122.485,8.061 122.75,8.061 122.889,8.2 R284_N.2@123.745,8.2 123.82,8.125 v1(124.82,8.125)
  Top Layer w0.4: R177.2@220.6,26.8 R177.2@220.65,26.75
  Bottom Layer w0.2: v1(124,3) 124.047,3 126.054,5.007 126.054,6.891 v1(124.82,8.125) 125.708,8.125 127.154,9.571 127.154,9.937 146,28.783 v1(146,31) ; v1(146,36) 150,40 171.4,40 185.4,26 203.7,26 v1(204.2,25.5)
PWM_S1_GaN_L1: C109.1 R43.1 R170.2 U15.2 | length 78.4
  Top Layer w0.2: v1(229.088,53.496) 229.7,52.883 R43.1@229.7,50.5
  Top Layer w0.4: R170.2@159.468,65.016 C109.1@159.468,63.766 160.568,63.766 160.716,63.618 U15.2@162.289,63.618 163.657,63.618 163.711,63.563 v1(163.768,63.563)
  Bottom Layer w0.2: v1(163.768,63.563) 172.437,63.563 176.054,59.946 207.337,59.946 207.783,59.5 223.083,59.5 v1(229.088,53.496)
PWM_S1_GaN_L2: C116.1 R51.1 R185.2 U16.2 | length 93.3
  Top Layer w0.2: v1(148,60) 151.033,56.967 162.467,56.967 163.434,56 173.131,56 174.131,57 v1(175.5,57)
  Top Layer w0.4: C116.1@144.563,63.712 R185.2@144.563,64.712 145.163,64.712 145.878,63.997 U16.2@146.851,63.997 ; U16.2@147.063,64.012 147.113,63.962 148.156,63.962 148.306,63.812 v1(148.363,63.812) ; v1(221.475,54.163) 221.478,54.16 222.04,54.16 222.9,53.3 R51.1@222.9,52.4
  Bottom Layer w0.2: v1(148,60) 147.946,60.054 147.946,60.554 147.5,61 147.5,62.95 v1(148.363,63.812) ; v1(175.5,57) 177.5,57 181.5,53 190.934,53 192.988,50.946 203.512,50.946 204.066,51.5 204.566,51.5 209.566,56.5 219.138,56.5 v1(221.475,54.163)
PWM_S1_GaN_L3: C127.1 R44.1 R200.2 U18.2 | length 15.8
  Top Layer w0.4: R44.1@228.9,34 230.343,34 230.643,33.7 v1(230.7,33.7) ; U18.2@232.55,27.8 232.56,27.79 233.51,27.79 234.05,27.25 R200.2@234.95,27.25 ; C127.1@234.893,26.25 234.943,26.25 234.993,26.3 234.993,26.527 235,26.534 R200.2@235,27.2
  Bottom Layer w0.4: v1(230.7,33.7) 230.7,31.4 231,31.1 233.8,31.1 235.034,29.866 235.034,29.091 234.14,28.197 234.14,27.34 v1(234.1,27.3)
PWM_S1_GaN_N: C121.1 R52.1 R190.2 U17.2 | length 14.1
  Top Layer w0.4: U17.2@217,26.1 217.007,26.093 218.107,26.093 218.8,25.4 C121.1@219.6,25.4 ; R190.2@219.708,24.361 R190.2@219.716,24.369 C121.1@219.716,25.384 ; v1(222.3,32.8) 222.833,32.8 223.067,33.034 223.067,33.567 R52.1@223.1,33.6
  Bottom Layer w0.4: v1(218.8,25.5) 218.8,26.7 221.694,29.594 221.694,32.137 222.3,32.743 v1(222.3,32.8)
PWM_S2_DRIVER_GaN_L1: C202_L1.2 R292_L1.2 U27_L1.45 | length 24.7
  Top Layer w0.2: v1(56.5,143.5) 56.5,144.42 59,146.92 v1(59,147)
  Bottom Layer w0.2: 52,136.5 56.5,141 v1(56.5,143.5) ; v1(59,147) 59.5,146.5 C202_L1.2@59.5,145.7 59.608,145.808 60.033,145.808 60.6,146.375 60.6,146.666 60.89,146.956 U27_L1.45@60.89,148.3
  Bottom Layer w0.254: 52,136.5 52,133.06 53.385,131.675 R292_L1.2@53.385,130.682
PWM_S2_DRIVER_GaN_L2: C202_L2.2 R292_L2.2 U27_L2.45 | length 24.6
  Top Layer w0.2: v1(139.6,128.5) 142.546,131.446 142.546,131.946 v1(142.6,132)
  Bottom Layer w0.2: 135.5,121.8 139.6,125.9 v1(139.6,128.5) ; v1(142.6,132) 143,131.6 C202_L2.2@143,130.7 143.25,130.95 143.424,130.95 144.1,131.626 144.1,131.666 144.39,131.956 U27_L2.45@144.39,133.3
  Bottom Layer w0.254: 135.5,121.8 135.5,118.061 136.885,116.675 R292_L2.2@136.885,115.682
PWM_S2_DRIVER_GaN_L3: C202_L3.2 R292_L3.2 U27_L3.45 | length 24.5
  Top Layer w0.2: v1(226,100.5) 226,101.2 v1@228.664,103.864
  Bottom Layer w0.2: 221.5,93.5 226,98 v1(226,100.5) ; v1(228.6,103.8) 228.683,103.8 229,103.483 C202_L3.2@229,102.7 229.108,102.808 229.533,102.808 230.1,103.375 230.1,103.666 230.39,103.956 U27_L3.45@230.39,105.3
  Bottom Layer w0.254: 221.5,93.5 221.5,90.061 222.885,88.675 R292_L3.2@222.885,87.682
PWM_S2_DRIVER_GaN_N: C202_N.2 R292_N.2 U27_N.45 | length 24.1
  Top Layer w0.2: v1(89.7,29.6) 90.4,29.6 v1(93,27)
  Bottom Layer w0.2: U27_N.45@88.2,31.39 89.544,31.39 89.834,31.1 90.125,31.1 90.692,30.533 90.692,30.108 C202_N.2@90.8,30 90.1,30 v1(89.7,29.6) ; v1(93,27) 95.5,27 99.7,22.8
  Bottom Layer w0.254: 99.7,22.8 103.74,22.8 104.825,23.885 R292_N.2@105.818,23.885
PWM_S2_FAULT_GaN_L1: C203_L1.2 U27_L1.46 U32_L1.7 | length 25.2
  Top Layer w0.2: v1(52.275,128.253) 52.275,129.102 53.31,130.137 53.31,132.061 53.237,132.134 53.237,135.144 53,135.381 v1(53,136) ; v1(58.5,142.9) 58.5,144.486 60,145.986 v1(60,147)
  Top Layer w0.254: U32_L1.7@52.275,126.95 v1(52.275,128.253)
  Bottom Layer w0.2: v1(53,136) 58.5,141.5 v1(58.5,142.9) ; v1(60,147) 60.365,147.365 U27_L1.46@60.365,148.5
PWM_S2_FAULT_GaN_L2: C203_L2.2 U27_L2.46 U32_L2.7 | length 25
  Top Layer w0.2: v1(135.775,113.253) 135.775,114.102 136.81,115.137 136.81,117.061 136.737,117.134 136.737,120.144 136.5,120.381 v1(136.5,121) ; v1@141.8,128.025 142,128.225 142,129.486 143.554,131.04 143.554,131.946 v1(143.5,132)
  Top Layer w0.254: U32_L2.7@135.775,111.95 v1(135.775,113.253)
  Bottom Layer w0.2: v1(136.5,121) 141.8,126.3 v1(141.8,127.8) ; v1(143.5,132) 143.865,132.365 U27_L2.46@143.865,133.5
PWM_S2_FAULT_GaN_L3: C203_L3.2 U27_L3.46 U32_L3.7 | length 25.4
  Top Layer w0.2: v1(221.775,85.253) 221.775,85.291 222.008,85.524 C203_L3.2@222.008,86.335 ; C203_L3.2@222.16,86.182 222.243,86.265 222.243,86.715 222.46,86.932 222.606,86.932 222.81,87.137 222.81,89.061 222.737,89.134 222.737,92.144 222.5,92.381 v1(222.5,93) ; v1(227.2,99.7) 227.6,100.1 227.6,101.086 229.554,103.04 229.554,103.946 v1(229.5,104)
  Top Layer w0.254: U32_L3.7@221.775,83.95 v1(221.775,85.253)
  Bottom Layer w0.2: v1(222.5,93) 222.542,93.042 222.542,93.342 227.2,98 v1(227.2,99.7) ; v1(229.5,104) 229.865,104.365 U27_L3.46@229.865,105.5
PWM_S2_FAULT_GaN_N: C203_N.2 U27_N.46 U32_N.7 | length 25.5
  Top Layer w0.2: v1(89.5,30.5) 89.554,30.554 90.46,30.554 92.014,29 v1(93.5,29) ; v1(100.5,23.5) 101.119,23.5 101.356,23.737 104.366,23.737 104.439,23.81 107.038,23.81 107.155,23.693 107.155,23.323 C203_N.2@107.318,23.16 ; C203_N.2@107.165,23.008 107.976,23.008 108.209,22.775 v1(108.247,22.775)
  Top Layer w0.254: v1(108.247,22.775) U32_N.7@109.55,22.775
  Bottom Layer w0.2: U27_N.46@88,30.865 89.135,30.865 v1(89.5,30.5) ; v1(93.5,29) 95,29 v1(100.5,23.5)
PWM_S2_GaN_A: J13.9 R30.2 | length 49.7
  Top Layer w0.2: R30.2@242.2,36.1 242.2,30.711 242.4,30.511 v1(242.4,30.4)
  Top Layer w0.4: J13.9@207.85,19.5 209.85,17.5 234.049,17.5 241.008,24.46 241.86,24.46 v1(241.9,24.5)
  Bottom Layer w0.2: v1(241.9,24.5) 241.9,24.512 242.4,25.012 v1(242.4,30.4)
PWM_S2_GaN_B: R79.1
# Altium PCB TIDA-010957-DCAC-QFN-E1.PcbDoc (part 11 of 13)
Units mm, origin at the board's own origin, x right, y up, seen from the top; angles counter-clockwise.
Board outline 300 x 300 mm, 4 copper layers (Top Layer, Layer 1, Layer 2, Bottom Layer), stack 1.787 mm thick; 1286 components, 677 nets, 4169 pads, 3428 vias.

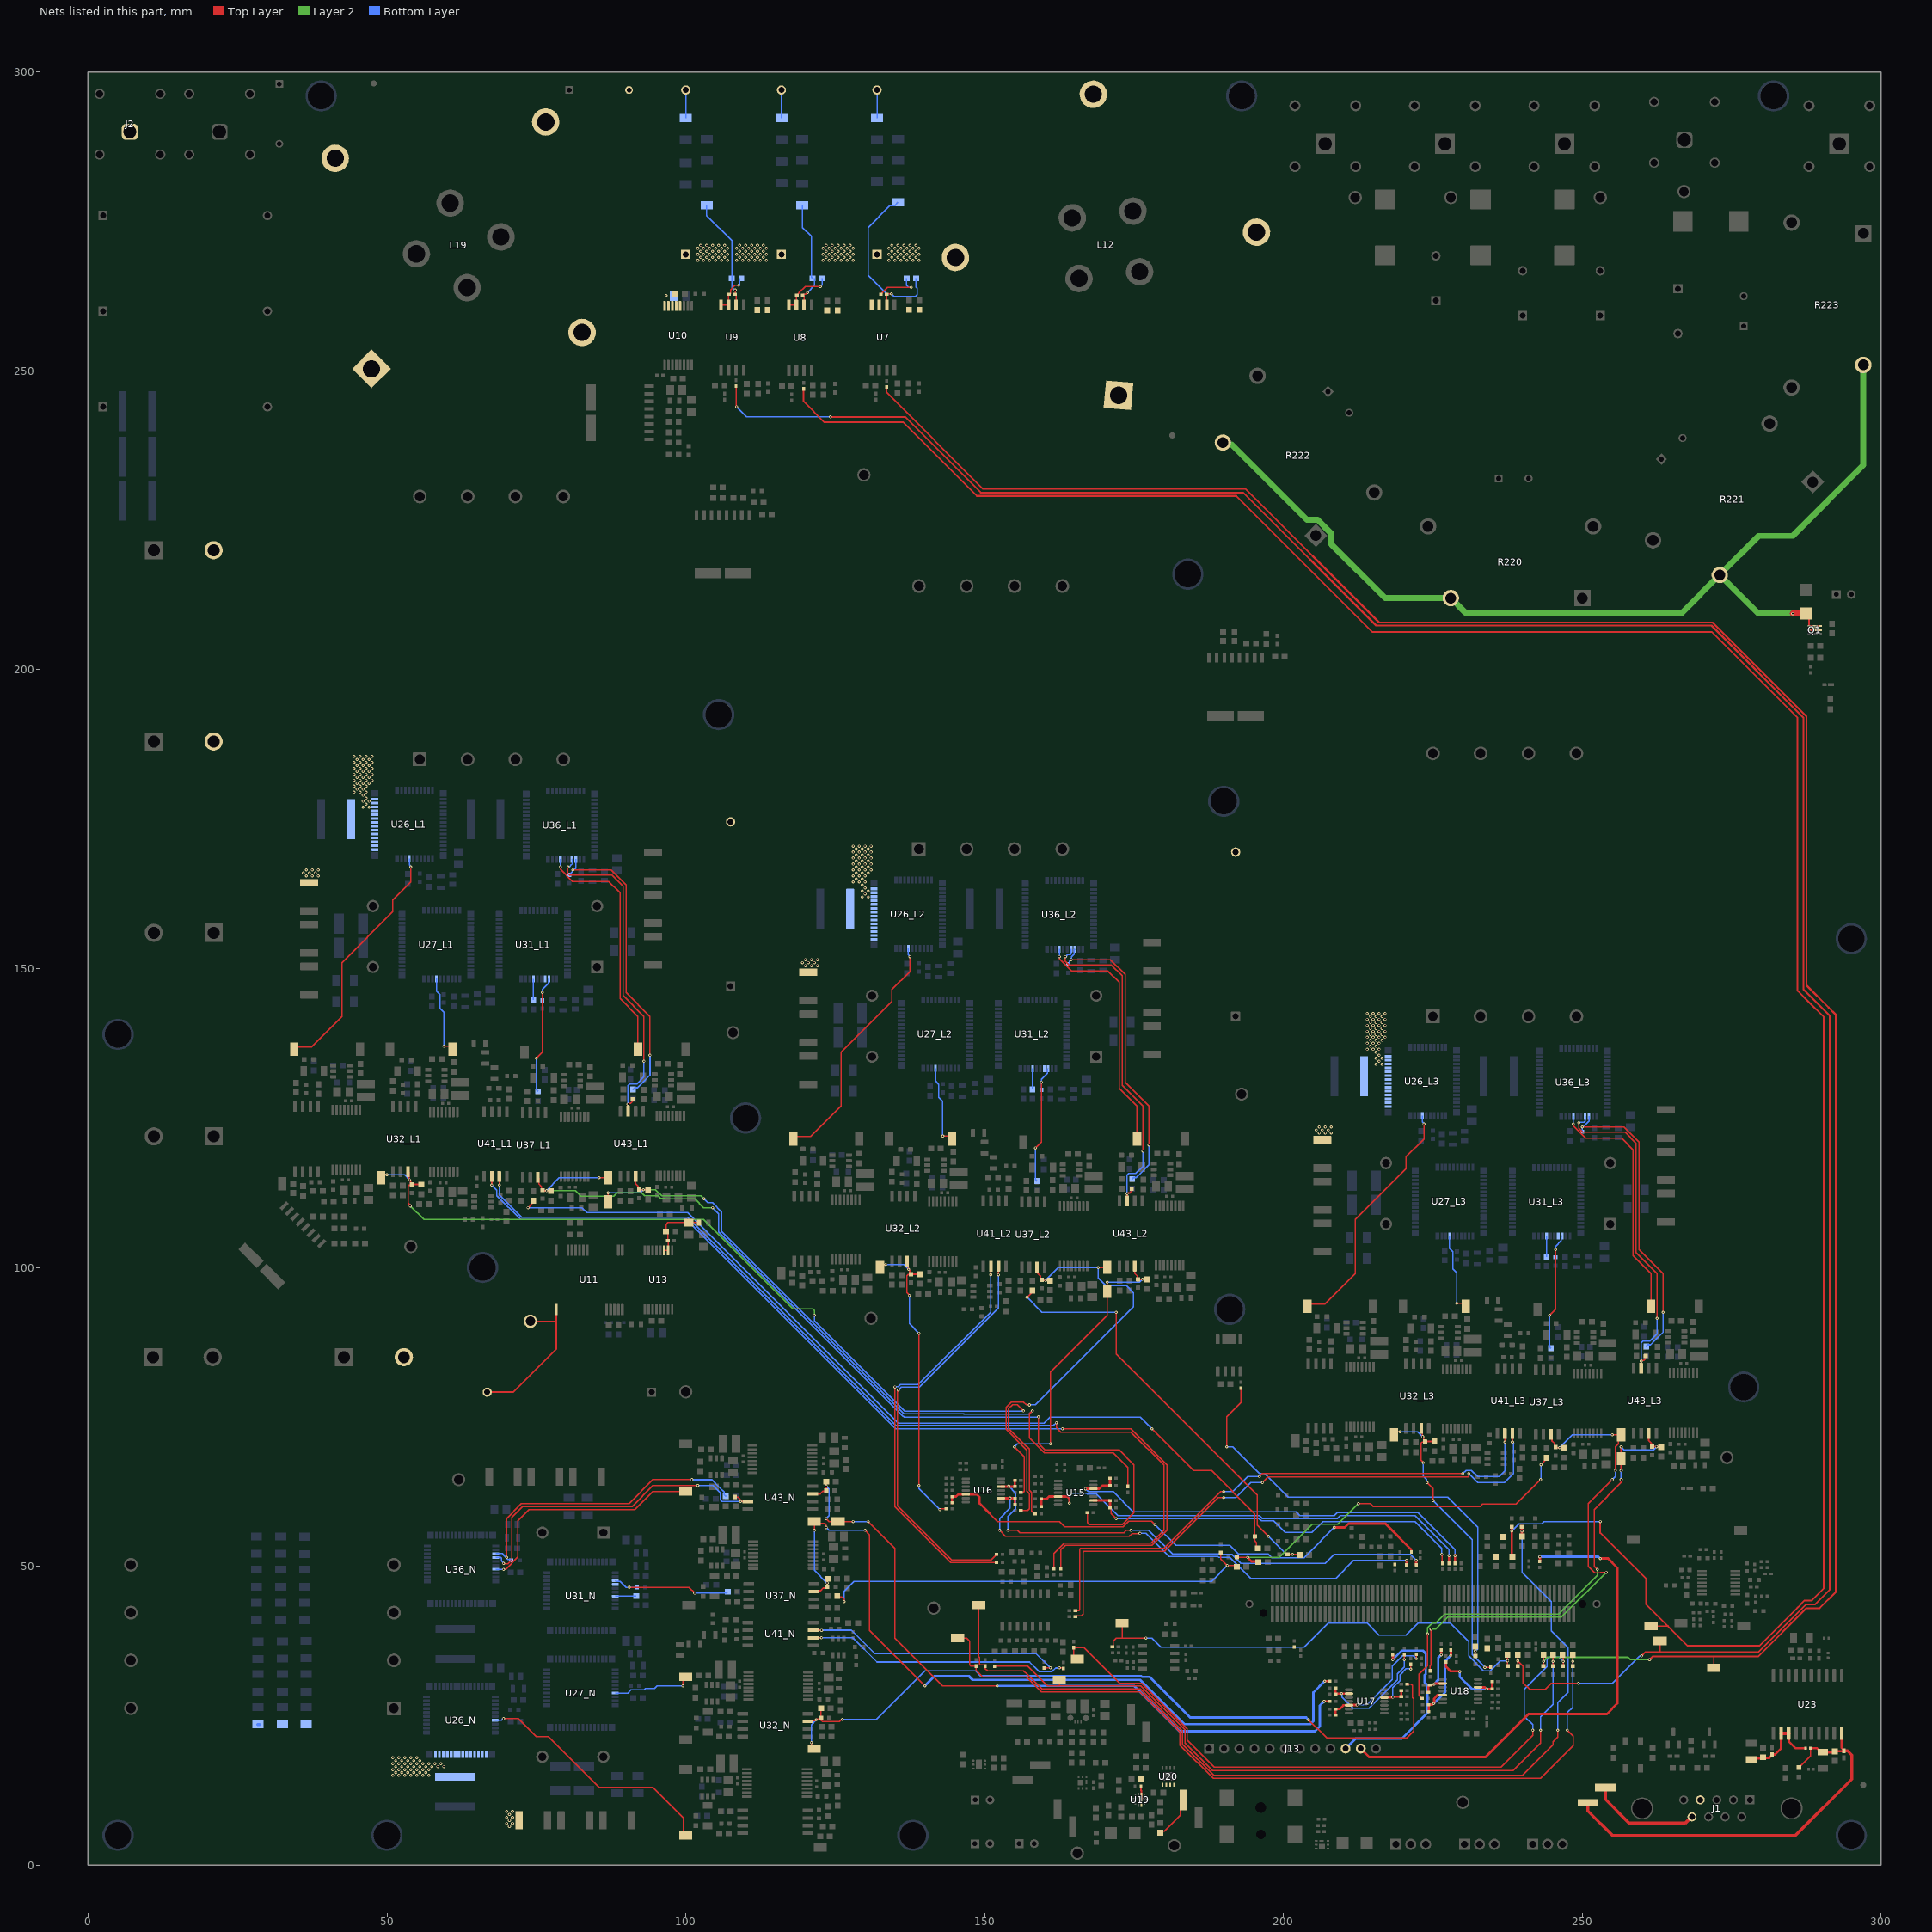
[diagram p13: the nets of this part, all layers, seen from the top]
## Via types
v1: diameter 0.508, hole 0.254, Top Layer to Bottom Layer, tented both sides, 3428 vias

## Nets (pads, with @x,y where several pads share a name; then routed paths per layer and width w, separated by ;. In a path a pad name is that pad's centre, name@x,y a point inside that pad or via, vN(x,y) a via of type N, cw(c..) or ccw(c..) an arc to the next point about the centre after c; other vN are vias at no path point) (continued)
PWM_S2_GaN_BUF_L1: C205_L1.2 R166.2 R295_L1.2 TP22_L1.1 U32_L1.3 | length 154.2
  Top Layer w0.2: TP22_L1.1@49,115 49.5,115.5 v1(50,115.5) ; v1(53.9,110.3) 53.9,110.411 53.53,110.781 53.53,113.63 53.7,113.8 54.1,113.8 C205_L1.2@54.18,113.88 ; v1(156.5,76) 155.446,77.054 154.671,77.054 154,76.383 154,73.066 156.666,70.4 157.468,69.598 157.468,62.725 157.868,62.325 157.868,59.233 158.185,58.916 158.318,58.916 R166.2@158.468,58.766
  Top Layer w0.254: U32_L1.3@53.545,116.05 53.718,115.877 53.718,114.794 53.957,114.555 53.957,114.103 C205_L1.2@54.18,113.88 55.733,113.88 R295_L1.2@55.75,113.863
  Layer 2 w0.2: v1(53.9,110.3) 56.2,108 103,108 117.946,93.054 121.229,93.054 121.5,92.783 v1(121.5,92)
  Bottom Layer w0.2: v1(50,115.5) 52.963,115.5 v1(53.789,114.674) ; v1(121.5,92) 121.5,91.066 136.62,75.946 156.446,75.946 v1(156.5,76)
PWM_S2_GaN_BUF_L2: C205_L2.2 R178.2 R295_L2.2 TP22_L2.1 U32_L2.3 | length 52.6
  Top Layer w0.2: TP22_L2.1@132.5,100 133,100.5 v1(133.5,100.5) ; v1(137.4,95.3) 137.4,95.411 137.03,95.781 137.03,98.63 137.2,98.8 137.6,98.8 C205_L2.2@137.68,98.88 ; v1(139,63.5) v1(139,89) ; v1(142.5,59.5) 142.583,59.5 142.696,59.612 R178.2@143.563,59.612
  Top Layer w0.254: U32_L2.3@137.045,101.05 137.218,100.877 137.218,99.794 137.457,99.555 137.457,99.103 C205_L2.2@137.68,98.88 139.233,98.88 R295_L2.2@139.25,98.863
  Bottom Layer w0.2: v1(133.5,100.5) 136.463,100.5 v1(137.289,99.674) ; v1(137.4,95.3) 137.4,90.6 v1(139,89) ; v1(139,63.5) 139,63 v1(142.5,59.5)
PWM_S2_GaN_BUF_L3: C205_L3.2 R196.2 R295_L3.2 TP22_L3.1 U32_L3.3 | length 53.1
  Top Layer w0.2: TP22_L3.1@218.5,72 219,72.5 v1(219.5,72.5) ; v1(223.4,67.3) 223.4,67.411 223.03,67.781 223.03,70.63 223.2,70.8 223.6,70.8 C205_L3.2@223.68,70.88 ; v1(224,64) 225,63 v1(225,61) ; v1(233.7,33.1) R196.2@234.7,33.1
  Top Layer w0.254: U32_L3.3@223.045,73.05 223.218,72.877 223.218,71.794 223.457,71.555 223.457,71.103 C205_L3.2@223.68,70.88 225.233,70.88 R295_L3.2@225.25,70.863
  Bottom Layer w0.2: v1(219.5,72.5) 222.463,72.5 v1(223.289,71.674) ; v1(223.4,67.3) 223.4,65.1 223.946,64.554 223.946,64.054 v1(224,64) ; v1(225,61) 231.554,54.446 231.554,36.037 231.546,36.029 231.546,35.571 231.554,35.563 231.554,35.246 v1(233.7,33.1)
PWM_S2_GaN_BUF_N: C205_N.2 R179.2 R295_N.2 TP22_N.1 U32_N.3 | length 126.6
  Top Layer w0.2: v1(121,20.5) 121,20 TP22_N.1@121.5,19.5 ; C205_N.2@122.62,24.68 122.7,24.6 122.7,24.2 122.87,24.03 125.719,24.03 126.089,24.4 v1(126.2,24.4) ; v1(204.2,24.3) 207.239,21.261 220.661,21.261 221.6,22.2 221.6,22.234 221.805,22.439 221.805,27.851 221.6,28.055 221.6,30.1 221.4,30.3 R179.2@220.7,30.3
  Top Layer w0.254: U32_N.3@120.45,24.045 120.623,24.218 121.706,24.218 121.945,24.457 122.397,24.457 C205_N.2@122.62,24.68 122.62,26.233 R295_N.2@122.637,26.25
  Top Layer w0.4: R179.2@220.7,30.3 220.75,30.25 R179.2@220.866,30.25
  Bottom Layer w0.2: v1(121,20.5) 121,23.463 v1(121.826,24.289) ; v1(126.2,24.4) 131.9,24.4 140,32.5 148.5,32.5 149.4,31.6 149.5,31.6
  Bottom Layer w0.4: 149.5,31.6 176.249,31.6 176.349,31.5 177.6,31.5 184.4,24.7 203.8,24.7 v1(204.2,24.3)
PWM_S2_GaN_L1: C110.1 R47.1 R171.2 U15.5 | length 78.3
  Top Layer w0.4: C110.1@159.468,60.016 159.468,61.216 159.518,61.266 160.368,61.266 160.768,61.666 U15.5@162.268,61.666 ; U15.5@162.47,61.668 163.832,61.668 164.168,61.332 v1(164.168,60.549) ; R47.1@227.7,50.5 v1@227.7,51.8
  Bottom Layer w0.2: v1(164.168,60.549) 164.168,61.668 164.722,62.222 167.047,62.222 167.169,62.1 168.683,62.1 172.229,58.554 172.283,58.5 196,58.5 196.5,58 209,58 209.5,58.5 222,58.5 227.688,52.812 v1(227.688,51.796)
  Bottom Layer w0.4: v1(227.688,51.796) v1@227.694,51.802
PWM_S2_GaN_L2: C117.1 R55.1 R186.2 U16.5 | length 87.3
  Top Layer w0.2: 150.763,58.912 152.175,57.5 162.5,57.5 163.4,56.6 173.166,56.6 174.12,57.554 177.946,57.554 v1(178.5,57)
  Top Layer w0.4: R186.2@144.563,60.612 C117.1@144.563,61.612 144.613,61.662 145.213,61.662 145.563,62.012 U16.5@146.363,62.012 ; U16.5@147.363,62.012 148.663,62.012 149.163,61.512 149.163,60.512 150.763,58.912 ; v1@208.518,56.5 210.263,56.5 210.913,57.15 217.05,57.15 221.35,52.85 221.35,52.45 R55.1@221.4,52.4
  Bottom Layer w0.2: v1(178.5,57) 182,53.5 191,53.5 192.446,52.054 197.446,52.054 198.054,51.446 203.446,51.446 204,52 v1(208.5,56.5)
PWM_S2_GaN_L3: C128.1 R48.1 R201.2 U18.5 | length 13.3
  Top Layer w0.4: R48.1@227.2,34 227.2,33.2 227.96,32.44 229.46,32.44 v1(229.5,32.4) ; U18.5@232.55,29.75 233.65,29.75 233.9,29.5 v1(234,29.5) R201.2@234.9,29.5 ; R201.2@234.9,29.6 C128.1@234.9,30.7
  Bottom Layer w0.4: v1(229.5,32.4) 229.505,32.395 229.505,31.495 231.5,29.5 v1@234.1,29.5
PWM_S2_GaN_N: C122.1 R56.1 R191.2 U17.5 | length 11.3
  Top Layer w0.2: v1(221.3,32.8) R56.1@221.3,33.6
  Top Layer w0.4: U17.5@216.866,28.052 218.252,28.052 218.4,28.2 R191.2@219.7,28.2 219.7,29.15 219.75,29.2 C122.1@219.8,29.2
  Bottom Layer w0.2: v1(218.3,28.1) 218.3,29.7 219.466,30.866 219.466,31.824 220.493,32.851 221.249,32.851 v1(221.3,32.8)
PWM_S3_DRIVER_GaN_L1: C226_L1.2 R303_L1.2 U31_L1.45 | length 21.1
  Top Layer w0.2: v1(75,135) 76,136 v1(76,146)
  Bottom Layer w0.2: v1(75,135) 75,129.73 R303_L1.2@75.264,129.466 ; C226_L1.2@76,144.7 v1(76,146) 76,146.5 76.99,147.49 76.99,148.15 U31_L1.45@77.115,148.275
PWM_S3_DRIVER_GaN_L2: C226_L2.2 R303_L2.2 U31_L2.45 | length 21.1
  Top Layer w0.2: v1(158.5,120) 159.5,121 v1(159.5,131)
  Bottom Layer w0.2: v1(158.5,120) 158.5,114.73 R303_L2.2@158.764,114.466 ; C226_L2.2@159.5,129.7 v1(159.5,131) 159.5,131.5 160.49,132.49 160.49,133.15 U31_L2.45@160.615,133.275
PWM_S3_DRIVER_GaN_L3: C226_L3.2 R303_L3.2 U31_L3.45 | length 21.1
  Top Layer w0.2: v1(244.5,92) 245.5,93 v1(245.5,103)
  Bottom Layer w0.2: v1(244.5,92) 244.5,86.73 R303_L3.2@244.764,86.466 ; C226_L3.2@245.5,101.7 v1(245.5,103) 245.5,103.5 246.49,104.49 246.49,105.15 U31_L3.45@246.615,105.275
PWM_S3_DRIVER_GaN_N: C226_N.2 R303_N.2 U31_N.45 | length 21.1
  Top Layer w0.2: v1(90.5,46.5) 100.5,46.5 v1(101.5,45.5)
  Bottom Layer w0.2: U31_N.45@88.225,47.615 88.35,47.49 89.01,47.49 90,46.5 v1(90.5,46.5) C226_N.2@91.8,46.5 ; v1(101.5,45.5) 106.77,45.5 R303_N.2@107.034,45.764
PWM_S3_FAULT_GaN_L1: U31_L1.46
PWM_S3_FAULT_GaN_L2: U31_L2.46
PWM_S3_FAULT_GaN_L3: U31_L3.46
PWM_S3_FAULT_GaN_N: U31_N.46
PWM_S3_GaN_A: J13.10 R61.1 | length 33.5
  Top Layer w0.4: v1(218.3,34.4) R61.1@218.3,35.2
  Bottom Layer w0.4: J13.10@210.39,19.5 212.09,21.2 219.8,21.2 224.105,25.505 224.105,30.095 223.6,30.6 223.6,31.744 223.805,31.948 223.805,35.395 223.3,35.9 219.8,35.9 v1(218.3,34.4)
PWM_S3_GaN_B: R80.1
PWM_S3_GaN_BUF_L1: C231_L1.2 R167.2 R305_L1.2 TP23_L1.1 U37_L1.3 | length 155.8
  Top Layer w0.2: v1(85.5,115) TP23_L1.1@87,115 ; v1(159,75) 159,70.566 160.066,69.5 172.5,69.5 175,67 175,59 173,57 167.5,57 167.168,57.332 R167.2@167.168,58.966
  Top Layer w0.254: U37_L1.3@75.264,115.05 75.413,114.901 75.413,113.969 75.861,113.521 75.861,113.001 76.028,112.834 v1(76.704,112.834) 77.379,112.834 R305_L1.2@77.429,112.784
  Layer 2 w0.2: v1(76.704,112.834) 81.565,112.834 82.452,111.946 87.946,111.946 88.5,112.5 92.641,112.5 93.141,112 95.389,112 95.814,111.575 96.379,111.575 96.454,111.5 101.5,111.5 103,110 v1(104.5,110)
  Bottom Layer w0.2: v1(76.704,112.834) 76.704,112.87 78.834,115 v1(85.5,115) ; v1(104.5,110) 105.5,109 105.5,105.934 136.334,75.1 136.4,75.1 136.554,74.946 158.946,74.946 v1(159,75)
PWM_S3_GaN_BUF_L2: C231_L2.2 R180.2 R305_L2.2 TP23_L2.1 U37_L2.3 | length 75
  Top Layer w0.2: R180.2@156.063,59.362 157.213,59.362 157.468,59.617 157.468,62.16 157.068,62.56 157.068,69.432 156.5,70 153.583,72.917 153.583,76.583 154.5,77.5 156.5,77.5 157,77 v1(157.5,77) ; v1(169,100) TP23_L2.1@170.5,100
  Top Layer w0.254: U37_L2.3@158.764,100.05 158.913,99.901 158.913,98.969 159.361,98.521 159.361,98.001 159.528,97.834 v1(160.204,97.834) 160.879,97.834 R305_L2.2@160.929,97.784
  Bottom Layer w0.2: v1(157.5,77) 158.5,77 174.916,93.416 174.916,95.761 173.732,96.946 170.271,96.946 169,98.217 v1(169,100) 162.334,100 160.204,97.87 v1(160.204,97.834)
PWM_S3_GaN_BUF_L3: C231_L3.2 R197.2 R305_L3.2 TP23_L3.1 U37_L3.3 | length 83.2
  Top Layer w0.2: R197.2@224.5,32.5 224.5,33.289 224.7,33.489 224.7,39.495 v1(224.705,39.5) ; v1(254,49) 253.091,49 253.037,48.946 252.054,48.946 251,50 251,60.5 v1(255,64.5) ; v1(255,72) TP23_L3.1@256.5,72 256,71.5 256,70.5 255.5,70 v1(255.5,66)
  Top Layer w0.254: U37_L3.3@244.764,72.05 244.913,71.901 244.913,70.969 245.361,70.521 245.361,70.001 245.528,69.834 v1(246.204,69.834) 246.879,69.834 R305_L3.2@246.929,69.784
  Layer 2 w0.2: v1(224.705,39.5) 225.5,39.5 227.5,41.5 246.5,41.5 v1(254,49)
  Bottom Layer w0.2: v1@224.7,39.505 v1(224.705,39.5) ; v1(246.204,69.834) 246.204,69.87 248.334,72 v1(255,72) ; v1(255,64.5) 255.5,65 v1(255.5,66)
PWM_S3_GaN_BUF_N: C231_N.2 R181.2 R305_N.2 TP23_N.1 U37_N.3 | length 132.2
  Top Layer w0.2: v1(121.5,56) TP23_N.1@121.5,57.5 121.799,57.201 123.223,57.201 123.441,56.983 123.441,56.559 v1(123.5,56.5) ; v1(130,56) 130.75,55.25 130.75,39.25 v1(140,30)
  Top Layer w0.254: U37_N.3@121.45,45.764 121.599,45.913 122.531,45.913 122.979,46.361 123.499,46.361 C231_N.2@123.666,46.528 v1(123.666,47.204) 123.666,47.879 R305_N.2@123.716,47.929
  Top Layer w0.4: v1(206.9,30.8) R181.2@207.7,30.8
  Bottom Layer w0.2: v1(121.5,56) 121.5,49.334 123.63,47.204 v1(123.666,47.204) ; v1(123.5,56.5) 124,56 v1(130,56)
  Bottom Layer w0.4: v1(140,30) 141.654,31.654 147.346,31.654 148,31 176,31 183.4,23.6 203.903,23.6 203.908,23.595 204.492,23.595 204.497,23.6 204.5,23.6 205,24.1 205,28.9 v1(206.9,30.8)
PWM_S3_GaN_L1: C111.1 R49.1 R172.2 U15.9 | length 66.8
  Top Layer w0.2: R172.2@171.018,59.766 171.168,59.616 171.168,58.832 v1(172,58) ; v1(226.5,52) 226.55,51.95 226.55,50.55 R49.1@226.6,50.5
  Top Layer w0.4: R172.2@170.968,59.816 C111.1@170.968,61.016 ; C111.1@170.968,61.017 U15.9@168.189,61.018 ; U15.9@168.189,61.018 U15.9@168.189,61.018
  Bottom Layer w0.2: v1(172,58) 195.934,58 196.334,57.6 198.366,57.6 200.32,55.646 204.749,55.646 206.603,57.5 222,57.5 226.5,53 v1(226.5,52)
PWM_S3_GaN_L2: C118.1 R57.1 R187.2 U16.9 | length 83.2
  Top Layer w0.2: v1(152.5,56) 153.5,55 174.208,55 174.654,55.446 175.946,55.446 v1(176,55.5)
  Top Layer w0.4: U16.9@152.761,61.387 C118.1@154.988,61.387 ; R187.2@155.063,60.412 C118.1@155.063,61.362 ; R57.1@220.6,50.2 v1(220.6,51)
  Bottom Layer w0.2: v1(152.5,56) 152.5,58 154.25,59.75 v1(154.25,61.408) ; v1(176,55.5) 177,55.5 180.846,51.654 189.029,51.654 189.183,51.5 191,51.5 194.5,48 208.758,48 211.758,51 v1(220.6,51)
  Bottom Layer w0.4: v1(220.6,51) v1@220.64,51.04
PWM_S3_GaN_L3: C129.1 R50.1 R202.2 U18.9 | length 10
  Top Layer w0.4: C129.1@224.25,28.9 224.25,29.866 224.35,29.966 224.35,30.1 224.4,30.15 R202.2@224.45,30.15 224.5,30.2 225.1,30.2 v1(225.2,30.3) 225.3,30.4 U18.9@226.65,30.4 U18.9@226.7,30.4 ; v1(226.4,35.2) R50.1@226.4,36.1
  Bottom Layer w0.4: v1(225.2,30.3) 225.9,31 225.9,34.7 v1(226.4,35.2)
PWM_S3_GaN_N: C123.1 R58.1 R192.2 U17.9 | length 20.6
  Top Layer w0.2: v1(220.2,34.4) R58.1@220.2,35.2
  Top Layer w0.4: C123.1@208.7,28.6 R192.2@208.7,29.6 ; C123.1@208.701,28.701 U17.9@210.966,28.702 U17.9@210.966,28.702
  Bottom Layer w0.2: v1(209.7,28.7) 209.754,28.646 209.754,28.146 211.654,26.246 214.28,26.246 219.066,31.032 219.066,31.99 220.2,33.124 v1(220.2,34.4)
PWM_S4_DRIVER_GaN_L1: C245_L1.2 R317_L1.2 U36_L1.45 | length 50.4
  Top Layer w0.2: v1(81.1,166.5) 87.5,166.5 90,164 90,146 94,142 v1(94,135.5)
  Bottom Layer w0.2: C245_L1.2@80.5,165.7 81.041,166.241 81.041,166.358 81.083,166.4 81.2,166.4 81.2,166.517 81.242,166.559 81.359,166.559 81.615,166.815 U36_L1.45@81.615,168.275
  Bottom Layer w0.254: R317_L1.2@91.2,129.798 91.468,130.066 91.908,130.066 92.601,130.759 94,132.158 v1(94,135.5)
PWM_S4_DRIVER_GaN_L2: C245_L2.2 R317_L2.2 U36_L2.45 | length 50.3
  Top Layer w0.2: v1(164.5,151.5) 171,151.5 173.5,149 173.5,131 177.5,127 v1(177.5,120.5)
  Bottom Layer w0.2: C245_L2.2@164,150.7 164.183,150.883 164.183,151.183 v1(164.5,151.5) 164.533,151.533 164.533,151.967 164.99,152.424 164.99,153.15 U36_L2.45@165.115,153.275
  Bottom Layer w0.254: R317_L2.2@174.7,114.798 174.968,115.066 175.408,115.066 176.101,115.759 177.5,117.158 v1(177.5,120.5)
PWM_S4_DRIVER_GaN_L3: C245_L3.2 R317_L3.2 U36_L3.45 | length 50.8
  Top Layer w0.2: v1(250,123.5) 257,123.5 259.5,121 259.5,103 263.5,99 v1(263.5,92.5)
  Bottom Layer w0.2: C245_L3.2@250,122.7 250,123.383 251.115,124.498 U36_L3.45@251.115,125.275
  Bottom Layer w0.254: R317_L3.2@260.7,86.798 260.968,87.066 261.408,87.066 262.101,87.759 263.5,89.158 v1(263.5,92.5)
PWM_S4_DRIVER_GaN_N: C245_N.2 R317_N.2 U36_N.45 | length 50.4
  Top Layer w0.2: v1(70,51.5) 70,58 72.5,60.5 90.5,60.5 94.5,64.5 v1(101,64.5)
  Bottom Layer w0.2: U36_N.45@68.225,52.115 69.285,52.115 69.758,51.642 69.775,51.642 69.95,51.467 69.95,51.45 69.988,51.45 70.271,51.167 70.633,51.167 C245_N.2@70.8,51
  Bottom Layer w0.254: v1(101,64.5) 104.342,64.5 105.741,63.101 106.434,62.408 106.434,61.968 R317_N.2@106.702,61.7
PWM_S4_FAULT_GaN_L1: C246_L1.2 U36_L1.46 U43_L1.7 | length 55.3
  Top Layer w0.2: v1(80.3,167) 80.271,166.971 80.271,165.945 80.596,165.62 87.663,165.62 89.5,163.783 89.5,145.5 93,142 v1(93,134.5)
  Top Layer w0.254: U43_L1.7@90.343,126.126 90.343,127.299 90.492,127.448 90.768,127.448 91.075,127.756 91.075,128.246 C246_L1.2@91.111,128.282
  Bottom Layer w0.2: v1@80.192,167.108 80.588,167.108 80.822,167.342 80.842,167.342 81,167.5 81,168.24 U36_L1.46@80.965,168.275 ; v1(90.343,127.334) 90.343,130.416 90.636,130.709 91.795,130.709 93,131.914 v1(93,134.5)
PWM_S4_FAULT_GaN_L2: C246_L2.2 U36_L2.46 U43_L2.7 | length 55.6
  Top Layer w0.2: v1(163.5,152) 163.446,151.946 163.446,151.271 164.096,150.62 171.163,150.62 173,148.783 173,130.5 176.5,127 v1(176.5,119.5)
  Top Layer w0.254: U43_L2.7@173.843,111.126 173.843,112.299 173.992,112.448 174.268,112.448 174.575,112.756 174.575,113.246 C246_L2.2@174.611,113.282
  Bottom Layer w0.2: v1(163.5,152) 163.583,152 163.925,152.342 164.342,152.342 164.5,152.5 164.5,153.24 U36_L2.46@164.465,153.275 ; v1(173.843,112.334) 173.843,115.416 174.136,115.709 175.295,115.709 176.5,116.914 v1(176.5,119.5)
PWM_S4_FAULT_GaN_L3: C246_L3.2 U36_L3.46 U43_L3.7 | length 55.5
  Top Layer w0.2: v1@249.446,124.031 249.446,123.271 250.096,122.62 257.163,122.62 259,120.783 259,102.5 262.5,99 v1(262.5,91.5)
  Top Layer w0.254: U43_L3.7@259.843,83.126 259.843,84.299 259.992,84.448 260.268,84.448 260.575,84.756 260.575,85.246 C246_L3.2@260.611,85.282
  Bottom Layer w0.2: v1@249.5,124.3 250.3,124.3 250.5,124.5 250.5,125.24 U36_L3.46@250.465,125.275 ; v1(259.843,84.334) 259.843,87.416 260.136,87.709 261.295,87.709 262.5,88.914 v1(262.5,91.5)
  other v1: 249.4,124.2
PWM_S4_FAULT_GaN_N: C246_N.2 U36_N.46 U43_N.7 | length 55.6
  Top Layer w0.2: v1(69.5,50.5) 69.554,50.446 70.229,50.446 70.88,51.096 70.88,58.163 72.717,60 91,60 94.5,63.5 v1(102,63.5)
  Top Layer w0.254: C246_N.2@108.218,61.611 108.254,61.575 108.744,61.575 109.052,61.268 109.052,60.992 109.201,60.843 U43_N.7@110.374,60.843
  Bottom Layer w0.2: U36_N.46@68.225,51.465 68.26,51.5 69,51.5 69.158,51.342 69.158,50.925 69.5,50.583 v1(69.5,50.5) ; v1(102,63.5) 104.586,63.5 105.791,62.295 105.791,61.136 106.084,60.843 v1(109.166,60.843)
PWM_S4_GaN_A: J13.11 R25.1 | length 84.5
  Top Layer w0.4: J13.11@212.93,19.5 214.33,18.1 233.8,18.1 241,25.3 254.1,25.3 255.86,27.06 255.86,49.74 254.3,51.3 v1(253,51.3) ; R25.1@242.9,50.8 v1(242.9,51.6)
  Bottom Layer w0.4: v1@242.803,51.6 252.661,51.6 252.961,51.3 v1(253,51.3)
PWM_S4_GaN_B: R60.1
PWM_S4_GaN_BUF_L1: C248_L1.2 R168.2 R322_L1.2 TP24_L1.1 U43_L1.3 | length 120.8
  Top Layer w0.2: TP24_L1.1@87,111 v1(87,112.5) ; v1(158,76) 157.5,75.5 157.5,71.5 160,69 171.5,69 174,66.5 174,63.398 R168.2@173.968,63.366
  Top Layer w0.254: U43_L1.3@91.613,115.226 91.613,114.011 92.045,113.58 92.045,113.14 C248_L1.2@92.175,113.009 v1(92.916,113.009) 93.656,113.009 R322_L1.2@93.685,112.98
  Layer 2 w0.2: v1(92.916,113.009) 94.945,113.009 95.979,111.975 102.525,111.975 v1(103.013,111.487)
  Bottom Layer w0.2: v1(87,112.5) 92.407,112.5 v1(92.916,113.009) ; v1(103.013,111.487) 103.671,110.829 104.454,110.829 106,109.283 106,106 136.5,75.5 146.492,75.5 146.546,75.446 157.446,75.446 v1(158,76)
PWM_S4_GaN_BUF_L2: C248_L2.2 R182.2 R322_L2.2 TP24_L2.1 U43_L2.3 | length 56
  Top Layer w0.2: v1(155,70) 156.663,68.337 156.663,62.562 156.463,62.362 R182.2@156.063,62.362 ; v1(161,70.5) 161,82.5 170.5,92 TP24_L2.1@170.5,96 v1(170.5,97.5)
  Top Layer w0.254: U43_L2.3@175.113,100.226 175.113,99.011 175.545,98.58 175.545,98.14 C248_L2.2@175.675,98.009 v1(176.416,98.009) 177.156,98.009 R322_L2.2@177.185,97.98
  Bottom Layer w0.2: v1(155,70) 155.5,70.5 v1(161,70.5) ; v1(170.5,97.5) 175.907,97.5 v1(176.416,98.009)
PWM_S4_GaN_BUF_L3: C248_L3.2 R198.2 R322_L3.2 TP24_L3.1 U43_L3.3 | length 78.6
  Top Layer w0.2: R198.2@223.2,27.9 223.15,27.9 222.65,28.4 222.65,31.91 224.095,33.355 v1(224.095,38.7) ; v1(252.5,49.5) 252,50 252,59.5 256.5,64 v1(256.5,64.5) ; v1(256.5,66) TP24_L3.1@256.5,68 v1(256.5,70)
  Top Layer w0.254: U43_L3.3@261.113,72.226 261.113,71.011 261.545,70.58 261.545,70.14 C248_L3.2@261.675,70.009 v1(262.416,70.009) 263.156,70.009 R322_L3.2@263.185,69.98
  Layer 2 w0.2: v1(224.095,38.7) 224.095,39.674 224.921,40.5 225.5,40.5 227,42 246,42 252.5,48.5 v1(252.5,49.5)
  Bottom Layer w0.2: v1(256.5,64.5) v1(256.5,66) ; v1(256.5,70) 257,69.5 261.907,69.5 v1(262.416,70.009)
PWM_S4_GaN_BUF_N: C248_N.2 R183.2 R322_N.2 TP24_N.1 U43_N.3 | length 121.7
  Top Layer w0.2: v1(123.5,58) 124,57.5 TP24_N.1@125.5,57.5 v1(128,57.5) ; v1(130.5,57.5) 135,53 135,38 143,30 v1(152.1,30)
  Top Layer w0.254: U43_N.3@121.274,62.113 122.489,62.113 122.92,62.545 123.36,62.545 C248_N.2@123.491,62.675 v1(123.491,63.416) 123.491,64.156 R322_N.2@123.52,64.185
  Top Layer w0.4: v1(206.8,27.4) R183.2@207.7,27.4
  Bottom Layer w0.2: v1(123.491,63.416) 124,62.907 124,58.5 v1(123.5,58) ; v1(128,57.5) v1(130.5,57.5)
  Bottom Layer w0.4: v1(152.1,30) 175,30 182.6,22.4 205.3,22.4 206.1,23.2 206.1,26.7 v1(206.8,27.4)
PWM_S4_GaN_L1: C112.1 R45.1 R173.2 U15.12 | length 74.4
  Top Layer w0.4: v1(166.868,62.966) 166.869,62.967 U15.12@168.189,62.968 ; U15.12@168.189,62.968 168.199,62.978 169.179,62.978 169.668,63.466 C112.1@170.968,63.466 ; C112.1@170.968,63.516 R173.2@170.968,64.766 ; R45.1@228.7,50.5 v1@228.7,51.9
  Bottom Layer w0.2: v1(166.868,62.966) 167.334,62.5 171.5,62.5 174.845,59.155 202.072,59.155 202.727,58.5 208.5,58.5 209,59 222.5,59 228.688,52.812 v1(228.688,51.796)
PWM_S4_GaN_L2: C119.1 R53.1 R188.2 U16.12 | length 84.6
  Top Layer w0.2: v1(153.875,56) 155.5,56 155.9,55.6 173.297,55.6 173.697,56 v1(174.5,56)
  Top Layer w0.4: U16.12@152.761,63.337 152.77,63.347 R188.2@154.997,63.347 ; C119.1@154.963,64.412 155.063,64.312 R188.2@155.063,63.362 ; R53.1@222.2,50.2 v1(222.2,51)
  Bottom Layer w0.2: v1(153.875,56) 153.875,58.324 155.213,59.662 155.213,62.246 v1(154.05,63.408) ; v1(174.5,56) 174.554,56.054 177.446,56.054 180.585,52.915 181.447,52.054 189.195,52.054 189.249,52 191.369,52 192.869,50.5 207,50.5 208.5,52 221.2,52 v1(222.2,51)
PWM_S4_GaN_L3: C130.1 R46.1 R203.2 U18.12 | length 14.6
  Top Layer w0.4: R203.2@224.294,26.83 224.344,26.88 224.944,26.88 v1@225.194,27.13 ; C130.1@224.3,25.9 R203.2@224.3,26.824 ; v1@225.2,27.1 225.2,27.886 225.755,28.44 226.64,28.44 U18.12@226.65,28.45 ; v1(228,35.1) R46.1@228,36
  Bottom Layer w0.4: v1@225.1,27 227,28.9 227,34.1 v1(228,35.1)
  other v1: 225.094,27.03
PWM_S4_GaN_N: C124.1 R54.1 R193.2 U17.12 | length 19.8
  Top Layer w0.2: v1(222.2,34.5) R54.1@222.2,35.3
  Top Layer w0.4: C124.1@208.7,25.2 R193.2@208.7,26.1 209.4,26.1 210.043,26.743 210.957,26.743 U17.12@210.966,26.752 ; U17.12@211.6,26.777 212.277,26.777 v1(212.3,26.8)
  Bottom Layer w0.2: v1(212.3,26.8) 213.983,26.8 218.225,31.042 218.225,33.325 219.9,35 221.7,35 v1(222.2,34.5)
SN_Relays: D3.2 Q1.1 Q1.2 Q1.5 Q1.6 Q1.8 R220.2 R221.2 R222.2 R223.2 | length 169.1
  Top Layer w0.3: Q1.2@287.93,206.65 288.58,206.65 Q1.8@288.905,206.975 ; D3.2@287.93,208.7 Q1.1@287.93,207.3 288.58,207.3 Q1.8@288.905,206.975 ; Q1.8@289.15,206.65 Q1.5@289.88,206.65 ; Q1.6@289.8,207.3 289.23,207.3 Q1.8@288.905,206.975
  Top Layer w1: v1(285.2,209.4) D3.2@287.1,209.4
  Layer 2 w1: R222.2@189.863,238.005 190.198,237.67 191.33,237.67 203.929,225.071 205.732,225.071 208.041,222.762 208.041,220.959 217,212 R220.2@228,212 230.5,209.5 266.632,209.5 R221.2@272.995,215.863 ; v1(285.2,209.4) 279.458,209.4 R221.2@272.995,215.863 ; R223.2@296.9,250.9 297,250.8 297,234.2 285.2,222.4 279.532,222.4 R221.2@272.995,215.863
T_HEATSINK_DCAC: C14.1 R19.1 R42.1 | length 80.9
  Top Layer w0.2: v1(190.5,70) 190.5,75 192.9,77.4 R19.1@192.9,79.8 ; C14.1@232.1,35 v1(232.1,35.8) R42.1@232.1,36.6
  Bottom Layer w0.2: v1(190.5,70) 191.5,70 195.946,65.554 196.815,65.554 200.815,61.554 227.446,61.554 232.5,56.5 232.5,36.2 v1(232.1,35.8)
TEMP_S1_GaN_L1: TP14_L1.1 U26_L1.49 | length 41.5
  Top Layer w0.2: TP14_L1.1@34.5,136.5 34.9,136.9 37.4,136.9 42.5,142 42.5,151 51,159.5 51,161.5 54,164.5 v1(54,167)
  Bottom Layer w0.2: U26_L1.49@53.74,168.4 53.74,167.343 54,167.083 v1(54,167)
TEMP_S1_GaN_L2: TP14_L2.1 U26_L2.49 | length 41.5
  Top Layer w0.2: TP14_L2.1@118,121.5 118.4,121.9 120.9,121.9 126,127 126,136 134.5,144.5 134.5,146.5 137.5,149.5 v1(137.5,152)
  Bottom Layer w0.2: U26_L2.49@137.24,153.4 137.24,152.343 137.5,152.083 v1(137.5,152)
TEMP_S1_GaN_L3: TP14_L3.1 U26_L3.49 | length 41.5
  Top Layer w0.2: TP14_L3.1@204,93.5 204.4,93.9 206.9,93.9 212,99 212,108 220.5,116.5 220.5,118.5 223.5,121.5 v1(223.5,124)
  Bottom Layer w0.2: U26_L3.49@223.24,125.4 223.24,124.343 223.5,124.083 v1(223.5,124)
TEMP_S1_GaN_N: TP14_N.1 U26_N.49 | length 41.5
  Top Layer w0.2: v1(69.5,24.5) 72,24.5 75,21.5 77,21.5 85.5,13 94.5,13 99.6,7.9 99.6,5.4 TP14_N.1@100,5
  Bottom Layer w0.2: U26_N.49@68.1,24.24 69.157,24.24 69.417,24.5 v1(69.5,24.5)
TEMP_S2_GaN_L1: TP17_L1.1 U27_L1.49 | length 13.5
  Top Layer w0.2: v1(59.5,137) 60.5,137 TP17_L1.1@61,136.5
  Bottom Layer w0.2: U27_L1.49@58.29,148.3 58.29,146.21 58.85,145.65 58.85,143.367 59.5,142.717 v1(59.5,137)
TEMP_S2_GaN_L2: TP17_L2.1 U27_L2.49 | length 13.5
  Top Layer w0.2: v1(143,122) 144,122 TP17_L2.1@144.5,121.5
  Bottom Layer w0.2: U27_L2.49@141.79,133.3 141.79,131.21 142.35,130.65 142.35,128.433 143,127.783 v1(143,122)
TEMP_S2_GaN_L3: TP17_L3.1 U27_L3.49 | length 13.5
  Top Layer w0.2: v1(229,94) 230,94 TP17_L3.1@230.5,93.5
  Bottom Layer w0.2: U27_L3.49@227.79,105.3 227.79,103.21 228.35,102.65 228.35,99.75 229,99.1 v1(229,94)
TEMP_S2_GaN_N: TP17_N.1 U27_N.49 | length 13.5
  Top Layer w0.2: v1(99.5,30) 99.5,31 TP17_N.1@100,31.5
  Bottom Layer w0.2: U27_N.49@88.2,28.79 90.29,28.79 90.85,29.35 93.067,29.35 93.271,29.554 94.754,29.554 95.2,30 v1(99.5,30)
TEMP_S3_GaN_ISO_L1: C173.2 R74.2 R302_L1.1 | length 151.5
  Top Layer w0.2: v1(73.6,110) 74.411,110.811 74.411,111.066 R302_L1.1@74.5,111.155 ; v1(178,73) 185,66 188,66 195.2,58.8 195.2,54.28 195.5,53.98 195.5,53.2 R74.2@195.7,53 ; R74.2@195.541,52.859 R74.2@195.7,52.7
  Bottom Layer w0.2: v1@73.6,110.108 v1(73.6,110) 82.621,110 83.466,109.155 100.345,109.155 135.546,73.954 159.954,73.954 160.917,74.917 176.083,74.917 v1(178,73)
TEMP_S3_GaN_ISO_L2: C174.2 R75.2 R302_L2.1 | length 72.9
  Top Layer w0.2: v1(157.1,95) 157.911,95.811 157.911,96.066 R302_L2.1@158,96.155 ; v1(172,92.5) 172,85.5 195.6,61.9 195.6,56.9 v1(197.5,55) ; C174.2@200.7,52 v1(201.5,52) 202.6,52 R75.2@202.7,51.9
  Bottom Layer w0.2: v1@157.1,95.108 v1(157.1,95) 159.6,92.5 v1(172,92.5) ; v1(197.5,55) 200.5,52 v1(201.5,52)
TEMP_S3_GaN_ISO_L3: C175.2 R76.2 R302_L3.1 | length 62.9
  Top Layer w0.2: C175.2@192.2,51.5 v1(194,51.5) ; v1(212.5,60.5) 214.5,60.5 215,60 232.934,60 233.334,60.4 238.9,60.4 v1(243,64.5) ; v1(243.1,67) 243.911,67.811 243.911,68.066 R302_L3.1@244,68.155
  Top Layer w0.4: v1(194,51.5) 194.671,50.829 195.671,50.829 R76.2@195.8,50.7
  Layer 2 w0.2: v1(194,51.5) 199.283,51.5 204.837,57.054 209.054,57.054 v1(212.5,60.5)
  Bottom Layer w0.2: v1(243,64.5) 243.1,64.6 v1(243.1,67) v1@243.1,67.108
TEMP_S3_GaN_ISO_N: C176.2 R77.2 R302_N.1 | length 73.8
  Top Layer w0.2: R302_N.1@125.345,45 125.434,44.911 126.089,44.911 126.5,44.5 v1(126.5,44.1) ; C176.2@189.5,52.3 189.5,51.217 v1(190.6,50.117) 191.983,50.117 R77.2@192.2,49.9
  Bottom Layer w0.2: v1@126.392,44.1 v1(126.5,44.1) 126.5,45.823 128.177,47.5 129.5,47.5 187.983,47.5 v1(190.6,50.117)
TEMP_S3_GaN_L1: R232_L1.2 U31_L1.49 | length 3.5
  Bottom Layer w0.2: R232_L1.2@74.5,144.8 74.515,144.815 U31_L1.49@74.515,148.275
TEMP_S3_GaN_L2: R232_L2.2 U31_L2.49 | length 3.5
  Bottom Layer w0.2: R232_L2.2@158,129.8 158.015,129.815 U31_L2.49@158.015,133.275
TEMP_S3_GaN_L3: R232_L3.2 U31_L3.49 | length 3.5
  Bottom Layer w0.2: R232_L3.2@244,101.8 244.015,101.815 U31_L3.49@244.015,105.275
TEMP_S3_GaN_N: R232_N.2 U31_N.49 | length 3.5
  Bottom Layer w0.2: U31_N.49@88.225,45.015 91.685,45.015 R232_N.2@91.7,45
TEMP_S4_GaN_L1: TP20_L1.1 U36_L1.49 | length 40.7
  Top Layer w0.2: v1(79,167) 79.017,166.983 79.017,166.634 81.047,164.604 87.113,164.604 89,162.717 89,145 92,142 TP20_L1.1@92,136.5
  Bottom Layer w0.2: v1(79,167) 79.008,167.007 79.008,168.267 U36_L1.49@79.015,168.275
TEMP_S4_GaN_L2: TP20_L2.1 U36_L2.49 | length 40.7
  Top Layer w0.2: v1(162.5,152) 162.518,151.982 162.518,151.635 163.046,151.107 163.046,151.105 164.547,149.604 170.613,149.604 172.5,147.717 172.5,130 175.5,127 TP20_L2.1@175.5,121.5
  Bottom Layer w0.2: v1(162.5,152) 162.508,152.008 162.508,153.268 U36_L2.49@162.515,153.275
TEMP_S4_GaN_L3: TP20_L3.1 U36_L3.49 | length 40.7
  Top Layer w0.2: v1(248.5,124) 248.517,123.983 248.517,123.634 250.547,121.604 256.613,121.604 258.5,119.717 258.5,102 261.5,99 TP20_L3.1@261.5,93.5
  Bottom Layer w0.2: v1(248.5,124) 248.507,124.008 248.507,125.268 U36_L3.49@248.515,125.275
TEMP_S4_GaN_N: TP20_N.1 U36_N.49 | length 40.7
  Top Layer w0.2: v1(69.5,49.5) 69.517,49.517 69.866,49.517 71.896,51.547 71.896,57.613 73.783,59.5 91.5,59.5 94.5,62.5 TP20_N.1@100,62.5
  Bottom Layer w0.2: U36_N.49@68.225,49.515 68.233,49.508 69.493,49.508 v1(69.5,49.5)
V_FC_L1: C96.1 R31.2 R146.2 TP32.1 | length 159
  Top Layer w0.2: TP32.1@149,43.5 149,34.858 149.134,34.724 149.134,33.617 149.251,33.5 149.934,33.5 150.084,33.35 R146.2@150.084,33.3 150.084,32.9 150.484,32.5 156.5,32.5 157.1,31.9 157.166,31.9 159.566,29.5 176.066,29.5 183.1,22.466 183.1,20.234 188.334,15 240,15 245.117,20.117 245.117,20.617 245.9,21.4 v1(245.9,22.6)
  Top Layer w0.4: R31.2@239.9,55 v1(239.9,55.9) C96.1@239.9,56.6 C96.1@239.9,56.7
  Bottom Layer w0.2: v1(239.9,55.9) 239.9,49 244.795,44.105 244.795,39.205 247.6,36.4 247.6,28.9 245.9,27.2 v1(245.9,22.6)
V_FC_L2: C99.1 R22.2 R151.2 TP33.1 | length 135.9
  Top Layer w0.2: TP33.1@145.5,38 147,38 147.5,37.5 147.5,33.5 147.7,33.3 R151.2@148.584,33.3 148.584,32.584 148.583,32.583 149.666,31.5 157,31.5 159.5,29 176,29 182.7,22.3 182.7,20.069 188.269,14.5 243,14.5 248.5,20 248.5,21.6 v1(247.5,22.6) ; C99.1@248.4,33.3 v1(248.4,34.1) R22.2@248.4,35.2
  Bottom Layer w0.2: v1(247.5,22.6) 247.5,25.505 248.4,26.405 v1(248.4,34.1)
V_FC_L3: C102.1 R27.2 R156.2 TP34.1 | length 119.3
  Top Layer w0.2: R156.2@151.64,33.275 157.225,33.275 160.5,30 162.5,30 ; TP34.1@162.5,31 162.5,30 ; v1(243,22.6) 243,20.4 238.4,15.8 188.1,15.8 183.5,20.4 183.5,22.631 176.131,30 162.5,30 ; C102.1@245.1,33.3 v1(245.1,34.1) R27.2@245.1,35.2
  Bottom Layer w0.2: v1(243,22.6) 243,24.8 245.1,26.9 v1(245.1,34.1)
V_FC_N: C105.1 R24.2 R161.2 TP35.1 | length 110.6
  Top Layer w0.2: TP35.1@165.5,34.5 165.484,34.5 164.884,35.1 R161.2@164.884,36.4 166.6,36.4 172.6,30.4 176.297,30.4 183.9,22.797 183.9,20.9 188.4,16.4 236.4,16.4 241.7,21.7 v1(241.7,22.6) ; C105.1@246.7,33.3 246.8,33.4 v1(246.8,34.1) 246.8,35.1 R24.2@246.7,35.2
  Bottom Layer w0.2: v1(241.7,22.6) 241.7,23.505 240.3,24.905 240.3,29.4 244.105,33.205 244.105,34.405 244.5,34.8 246.1,34.8 v1(246.8,34.1)
V_FC_NEG_L1: R147.2 U41_L1.6 | length 167.5
  Top Layer w0.2: R147.2@162.774,49.609 162.774,52.774 163.5,53.5 178,53.5 180.5,56 180.5,67 174.5,73 v1(163,73)
  Top Layer w0.254: v1(67.534,113.791) U41_L1.6@67.534,115.208
  Bottom Layer w0.2: v1(67.534,113.791) 68.404,112.921 68.404,111.982 72.386,108 100.131,108 135.131,73 v1(163,73)
V_FC_NEG_L2: R152.2 U41_L2.6 | length 69.8
  Top Layer w0.2: v1(135,80) 135,60 144.337,50.663 R152.2@152.004,50.663
  Top Layer w0.254: v1(151.034,98.791) U41_L2.6@151.034,100.208
  Bottom Layer w0.2: v1(135,80) 135.054,80.054 135.575,80.054 135.921,80.4 138.9,80.4 151.034,92.534 v1(151.034,98.791)
V_FC_NEG_L3: R157.2 U41_L3.6 | length 94.6
  Top Layer w0.2: R157.2@165.184,42.6 165.783,42.6 165.9,42.717 165.9,52.883 166.017,53 180,53 189.5,62.5 v1(190,62.5) ; v1(196,65) 196.5,65.5 v1(230,65.5)
  Top Layer w0.254: v1(237.034,70.791) U41_L3.6@237.034,72.208
  Bottom Layer w0.2: v1(190,62.5) 191.5,62.5 194,65 v1(196,65) ; v1(230,65.5) 230.554,66.054 231.446,66.054 232.5,65 236.1,65 237.034,65.934 v1(237.034,70.791)
V_FC_NEG_N: R162.2 U41_N.6 | length 44.8
  Top Layer w0.2: v1(162.5,33) 163.084,33 R162.2@163.184,32.9 163.184,32.85 R162.2@163.034,32.7
  Top Layer w0.254: U41_N.6@121.292,38.034 v1(122.709,38.034)
  Bottom Layer w0.254: v1(122.709,38.034) 127.95,38.034 132,33.984 157.516,33.984 159.081,32.419 161.305,32.419 161.865,32.979 162.479,32.979 v1(162.5,33)
V_FC_POS_L1: R145.2 U41_L1.7 | length 167.4
  Top Layer w0.2: R145.2@161.611,49.604 161.611,52.177 163.334,53.9 177.834,53.9 180,56.066 180,66.934 174.488,72.446 162.771,72.446 162,73.217 v1(162,74)
  Top Layer w0.254: v1(68.804,113.782) 68.804,114.746 68.678,114.872 68.678,115.082 U41_L1.7@68.804,115.208
  Bottom Layer w0.2: v1(68.804,113.782) 68.804,112.148 72.552,108.4 100.297,108.4 135.143,73.554 161.554,73.554 v1(162,74)
V_FC_POS_L2: R150.2 U41_L2.7 | length 69.7
  Top Layer w0.2: v1(135.587,79.5) 135.587,79.417 135.4,79.23 135.4,60.166 144.503,51.063 151.067,51.063 R150.2@152.004,52
  Top Layer w0.254: v1(152.304,98.782) 152.304,99.746 152.178,99.872 152.178,100.082 U41_L2.7@152.304,100.208
  Bottom Layer w0.2: v1(135.587,79.5) 136.087,80 139.066,80 152.304,93.238 v1(152.304,98.782)
V_FC_POS_L3: R155.2 U41_L3.7 | length 97.7
  Top Layer w0.2: R155.2@165.184,41.6 165.288,41.704 166.204,41.704 166.5,42 166.5,52.383 166.617,52.5 180.066,52.5 189.066,61.5 v1(190,61.5) ; v1(196.5,64) 197.446,64.946 230.828,64.946 230.999,65.117 v1@230.999,65.499
  Top Layer w0.254: v1(238.304,70.782) 238.304,71.746 238.178,71.872 238.178,72.082 U41_L3.7@238.304,72.208
  Bottom Layer w0.2: v1(190,61.5) 192,61.5 194.5,64 v1(196.5,64) ; v1(231,65.5) 232.5,64 237,64 238.5,65.5 238.5,70.517
  Bottom Layer w0.254: v1(238.304,70.782) 238.304,70.713 238.5,70.517
V_FC_POS_N: R160.2 U41_N.7 | length 43.5
  Top Layer w0.2: R160.2@159.949,32.975 159.974,33 v1(161,33)
  Top Layer w0.254: U41_N.7@121.292,39.304 121.418,39.178 121.628,39.178 121.754,39.304 v1(122.718,39.304)
  Bottom Layer w0.254: v1(122.718,39.304) 127.696,39.304 131.581,35.419 158.581,35.419 v1(161,33)
V_PCC_IN1: C58.1 R239.1 R240.1 U7.2 | length 30.1
  Top Layer w0.2: U7.2@133.64,261.05 133.64,262.83 C58.1@133.62,262.85 133.645,262.875 134.375,262.875 v1(134.4,262.9)
  Bottom Layer w0.2: R239.1@135.5,278.2 134.949,277.649 134.149,277.649 130.5,274 130.5,266 133.6,262.9 v1(134.4,262.9) 134.854,262.446 138.429,262.446 138.754,262.771 138.754,263.817 138.492,264.079 138.492,265.452 R240.1@138.54,265.5
V_PCC_IN2: C65.1 R244.1 R245.1 U8.2 | length 18.5
  Top Layer w0.2: U8.2@119.77,261 119.77,262.499 119.77,262.549 119.62,262.699 C65.1@119.57,262.699 119.679,262.808 120.035,262.808 120.346,263.118 v1@120.351,263.118
  Bottom Layer w0.2: R244.1@119.5,277.7 119.5,274 121,272.5 121,265.7 R245.1@121.2,265.5 ; v1(120.357,263.118) 121.54,264.301 R245.1@121.54,265.5
V_PCC_IN3: C72.1 R249.1 R250.1 U9.2 | length 18.7
  Top Layer w0.2: v1(108.269,263.508) 108.269,262.801 C72.1@108.27,262.799 108.405,262.664 U9.2@108.405,261.05
  Bottom Layer w0.2: R249.1@103.5,277.7 103.5,276 107.7,271.8 R250.1@107.7,265.5 ; R250.1@107.73,265.5 107.73,263.97 108.192,263.508 v1(108.269,263.508)
V_PCC_L1: C20.2 L12.1 L19.1 R236.2 | length 4.7
  Bottom Layer w0.2: R236.2@132,292.3 C20.2@132,297
V_PCC_L2: C21.2 L12.3 L19.3 R241.2 | length 4.7
  Bottom Layer w0.2: R241.2@116,292.3 C21.2@116,297
V_PCC_L3: C22.2 L12.5 L19.5 R246.2 | length 4.7
  Bottom Layer w0.2: R246.2@100,292.3 C22.2@100,297
V_PCC_N: C20.1 C21.1 C22.1 C25.2 C54.2 C55.1 C58.2 C61.2 C62.1 C65.2 C68.2 C69.1 C72.2 C75.2 C76.2 L12.7 L19.7 R240.2 R245.2 R250.2 U7.3 U7.4 U8.3 U8.4 U9.3 U9.4 U10.12 U10.13 U10.14 U10.15 U10.16 | length 23.6
  Top Layer w0.2: U9.4@105.865,261.05 U9.3@107.135,261.05 107.135,262.664 C72.2@107.27,262.799 107.32,262.799 107.47,262.949 107.47,263.565 108.205,264.3 v1(108.9,264.3) ; U8.4@117.23,261 U8.3@118.5,261 118.5,262.629 C65.2@118.57,262.699 118.62,262.699 118.97,263.049 118.97,263.073 119.997,264.1 v1(122.5,264.1) ; C58.2@132.62,262.85 132.67,262.85 132.82,263 132.82,263.05 133.77,264 v1(137.7,264)
  Bottom Layer w0.2: v1(108.9,264.3) 109,264.4 R250.2@109,265.5 ; v1(122.5,264.1) 122.81,264.41 R245.2@122.81,265.5 ; R240.2@136.94,265.5 136.94,264.36 137.3,264 v1(137.7,264)
  other v1: 96.7,262.6 102,268.5 103,268.5 104,268.5 105,268.5 106,268.5 107,268.5 108.5,268.5 109.5,268.5 110.5,268.5 111.5,268.5 112.5,268.5 113.5,268.5 123,268.5 124,268.5 125,268.5 126,268.5 127,268.5 128,268.5 134,268.5 135,268.5 136,268.5 137,268.5 138,268.5 139,268.5 102.5,269 103.5,269 104.5,269 105.5,269 106.5,269 109,269 110,269 111,269 112,269 113,269 123.5,269 124.5,269 125.5,269 126.5,269 127.5,269 134.5,269 135.5,269 136.5,269 137.5,269 138.5,269 102,269.5 103,269.5 104,269.5 105,269.5 106,269.5 107,269.5 108.5,269.5 109.5,269.5 110.5,269.5 111.5,269.5 112.5,269.5 113.5,269.5 123,269.5 124,269.5 125,269.5 126,269.5 127,269.5 128,269.5 134,269.5 135,269.5 136,269.5 137,269.5 138,269.5 139,269.5 102.5,270 103.5,270 104.5,270 105.5,270 106.5,270 109,270 110,270 111,270 112,270 113,270 123.5,270 124.5,270 125.5,270 126.5,270 127.5,270 134.5,270 135.5,270 136.5,270 137.5,270 138.5,270 102,270.5 103,270.5 104,270.5 105,270.5 106,270.5 107,270.5 108.5,270.5 109.5,270.5 110.5,270.5 111.5,270.5 112.5,270.5 113.5,270.5 123,270.5 124,270.5 125,270.5 126,270.5 127,270.5 128,270.5 134,270.5 135,270.5 136,270.5 137,270.5 138,270.5 139,270.5 102.5,271 103.5,271 104.5,271 105.5,271 106.5,271 109,271 110,271 111,271 112,271 113,271 123.5,271 124.5,271 125.5,271 126.5,271 127.5,271 134.5,271 135.5,271 136.5,271 137.5,271 138.5,271
V_SENSE_1: R36.2
V_SENSE_2: R37.2
V_SENSE_3: R41.1
V_SENSE_DC: C84.1 R35.1 R140.2 TP31.1 | length 81
  Top Layer w0.2: R140.2@171.383,36.513 171.5,36.63 171.5,37.5 172,38 173,38 ; TP31.1@173,40.5 173,38 ; v1(177,38) 173,38 ; C84.1@237.5,33.3 v1(237.5,34.2) R35.1@237.5,35.2
  Bottom Layer w0.2: v1(177,38) 178,38 179.5,36.5 188.588,36.5 188.642,36.446 203.446,36.446 207.5,40.5 214,40.5 216,38.5 220.5,38.5 222.5,40.5 227.9,40.5 231,37.4 231,35 233.454,32.546 234.617,32.546 236.271,34.2 v1(237.5,34.2)
V_SENSE_PCC_L1: C59.2 R28.2 R130.2 TP36.1 | length 383.6
  Top Layer w0.2: C59.2@243.5,33.3 v1(243.5,34.1) R28.2@243.5,35.2 ; TP36.1@272,33 272,34.9
  Top Layer w0.3: R130.2@133.6,247.3 133.6,246.4 149.746,230.254 193.646,230.254 216,207.9 271.807,207.9 287.504,192.203 287.504,147.196 291.2,143.5 292.4,142.3 292.4,45.7 289.704,43.004 287.504,43.004 279.4,34.9 272,34.9 261.745,34.9 v1(261.248,34.403)
  Layer 2 w0.2: v1@261.24,34.395 v1(261.248,34.403)
  Layer 2 w0.3: v1(243.5,34.1) 244.2,34.8 257.623,34.8 258.028,34.395 v1@261.24,34.395
V_SENSE_PCC_L2: C66.2 R33.2 R132.2 TP37.1 | length 414.8
  Top Layer w0.2: TP37.1@261.5,40 264.3,40 264.9,39.4
  Top Layer w0.3: R132.2@119.705,246.994 119.705,244.895 123.2,241.4 136.4,241.4 148.709,229.091 192.109,229.091 214.9,206.3 271.7,206.3 286,192 286,146.3 287.9,144.4 290.4,141.9 290.4,46.3 288.4,44.3 287.2,44.3 286,43.1 279.6,36.7 267.6,36.7 264.9,39.4 ; v1(253,57.5) 253,55.6 260.7,47.9 260.7,43.6 264.3,40
  Top Layer w0.4: C66.2@238.2,56.6 238.2,51.7 R33.2@238.3,51.6
  Bottom Layer w0.2: v1(238.188,55.896) 239.392,57.1 243.2,57.1 243.6,57.5 v1(253,57.5)
V_SENSE_PCC_L3: C73.2 R34.1 R134.2 TP38.1 | length 417.8
  Top Layer w0.2: R134.2@108.405,247.445 108.452,247.397 108.452,244.048 v1(108.5,244) ; C73.2@239.2,33.3 v1(239.2,34.2) ; R34.1@239.2,35.2 v1(239.2,34.2) ; v1(249.32,30.4) 244.8,30.4 243.8,29.4 241.2,29.4 240.1,30.5 240.1,33.3 v1(239.2,34.2) ; 263,35.6 TP38.1@263,37.5
  Top Layer w0.3: v1(124.2,242.3) 136.7,242.3 149.351,229.649 193.251,229.649 215.5,207.4 271.6,207.4 287.004,191.996 287.004,146.496 291.4,142.1 291.4,46.1 288.9,43.6 287.393,43.6 279.393,35.6 263,35.6 260.5,35.6 v1(259.9,35)
  Bottom Layer w0.2: v1(108.5,244) 110.2,242.3 v1(124.2,242.3) ; v1(249.32,30.4) 255,30.4 259.522,34.922 259.822,34.922 v1(259.9,35)
VDC+: C1.2 C2.2 C3.2 C10.2 C11.2 C12.2 C217_L1.2 C217_L2.2 C217_L3.2 C217_N.2 D7_L1.1 D7_L2.1 D7_L3.1 D7_N.1 J2.1 R1.2 R2.2 R3.2 TP39.1 U11.1 U26_L1.2 U26_L1.3 U26_L1.4 U26_L1.5 U26_L1.6 U26_L1.7 U26_L1.8 U26_L1.9 U26_L1.10 U26_L1.11 U26_L1.12 U26_L1.13 U26_L1.14 U26_L1.15 U26_L2.2 U26_L2.3 U26_L2.4 U26_L2.5 U26_L2.6 U26_L2.7 U26_L2.8 U26_L2.9 U26_L2.10 U26_L2.11 U26_L2.12 U26_L2.13 U26_L2.14 U26_L2.15 U26_L3.2 U26_L3.3 U26_L3.4 U26_L3.5 U26_L3.6 U26_L3.7 U26_L3.8 U26_L3.9 U26_L3.10 U26_L3.11 U26_L3.12 U26_L3.13 U26_L3.14 U26_L3.15 U26_N.2 U26_N.3 U26_N.4 U26_N.5 U26_N.6 U26_N.7 U26_N.8 U26_N.9 U26_N.10 U26_N.11 U26_N.12 U26_N.13 U26_N.14 U26_N.15 | length 25.8
  Top Layer w0.2: TP39.1@74,91 78.329,91
  Top Layer w0.3: C10.2@66.779,79.135 71.135,79.135 78.329,86.329 78.329,91 U11.1@78.329,92.954
  Bottom Layer w0.5: R1.2@28.373,23.55 R1.2@28.648,23.55
  other v1: 70.5,6.5 70,7 71,7 70.5,7.5 70,8 71,8 70.5,8.5 70,9 71,9 51,15 52,15 53,15 54,15 55,15 56,15 57,15 51.5,15.5 52.5,15.5 53.5,15.5 54.5,15.5 55.5,15.5 56.5,15.5 51,16 52,16 53,16 54,16 55,16 56,16 57,16 51.5,16.5 52.5,16.5 53.5,16.5 54.5,16.5 55.5,16.5 56.5,16.5 57.5,16.5 58.5,16.5 59.5,16.5 51,17 52,17 53,17 54,17 55,17 56,17 57,17 58,17 59,17 51.5,17.5 52.5,17.5 53.5,17.5 54.5,17.5 55.5,17.5 51,18 52,18 53,18 54,18 55,18 206,122.5 207,122.5 208,122.5 205.5,123 206.5,123 207.5,123 206,123.5 207,123.5 208,123.5 215.5,134 216.5,134 216,134.5 215.5,135 216.5,135 216,135.5 215.5,136 214,136.5 215,136.5 216,136.5 214.5,137 215.5,137 214,137.5 215,137.5 216,137.5 214.5,138 215.5,138 216.5,138 214,138.5 215,138.5 216,138.5 217,138.5 214.5,139 215.5,139 216.5,139 214,139.5 215,139.5 216,139.5 217,139.5 214.5,140 215.5,140 216.5,140 214,140.5 215,140.5 216,140.5 217,140.5 214.5,141 215.5,141 216.5,141 214,141.5 215,141.5 216,141.5 217,141.5 214.5,142 215.5,142 216.5,142 214,142.5 215,142.5 216,142.5 217,142.5 120,150.5 121,150.5 122,150.5 119.5,151 120.5,151 121.5,151 120,151.5 121,151.5 122,151.5 129.5,162 130.5,162 130,162.5 129.5,163 130.5,163 130,163.5 129.5,164 128,164.5 129,164.5 130,164.5 128.5,165 129.5,165 36.5,165.5 37.5,165.5 38.5,165.5 128,165.5 129,165.5 130,165.5 36,166 37,166 38,166 128.5,166 129.5,166 130.5,166 36.5,166.5 37.5,166.5 38.5,166.5 128,166.5 129,166.5 130,166.5 131,166.5 128.5,167 129.5,167 130.5,167 128,167.5 129,167.5 130,167.5 131,167.5 128.5,168 129.5,168 130.5,168 128,168.5 129,168.5 130,168.5 131,168.5 128.5,169 129.5,169 130.5,169 128,169.5 129,169.5 130,169.5 131,169.5 128.5,170 129.5,170 130.5,170 128,170.5 129,170.5 130,170.5 131,170.5 46,177 47,177 46.5,177.5 46,178 47,178 46.5,178.5 46,179 44.5,179.5 45.5,179.5 46.5,179.5 45,180 46,180 44.5,180.5 45.5,180.5 46.5,180.5 45,181 46,181 47,181 44.5,181.5 45.5,181.5 46.5,181.5 47.5,181.5 45,182 46,182 47,182 44.5,182.5 45.5,182.5 46.5,182.5 47.5,182.5 45,183 46,183 47,183 44.5,183.5 45.5,183.5 46.5,183.5 47.5,183.5 45,184 46,184 47,184 44.5,184.5 45.5,184.5 46.5,184.5 47.5,184.5 45,185 46,185 47,185 44.5,185.5 45.5,185.5 46.5,185.5 47.5,185.5
VIN_PWR: C131.1 C132.1 J14.2 R204.2 U19.5 U20.1 U20.2 U20.3 U20.4 | length 9.6
  Top Layer w0.2: R204.2@179.391,5.446 179.594,5.649 180.049,5.649 182.733,8.333 182.733,10.351 J14.2@183.268,10.886
  Top Layer w0.3: C132.1@176.159,13.186 176.159,12.513 176.229,12.444 U19.5@176.229,10.925
VIN_PWR_CAN: J1.4
VINP_DC-_HAVOK: C91.1 C92.1 L9.1 R143.1 U13.2 U13.3 | length 10.8
  Top Layer w0.2: U13.3@96.413,102.854 U13.2@97.063,102.854 97.063,104.437 R143.1@97,104.5 97,105.7 C91.1@96.7,106 96.7,107.2 97.016,107.516 C92.1@100.5,107.516 102.184,107.516 L9.1@102.2,107.5
VISOOUT: C153.1 C154.1 C155.1 FB17.1 U23.12 U23.13 | length 14.1
  Top Layer w0.4: C155.1@278.25,17.7 278.404,17.854 280.354,17.854 280.4,17.9 281.2,17.9 281.55,18.25 281.65,18.25 C153.1@281.75,18.35 ; C153.1@281.75,18.45 281.833,18.533 282.233,18.533 283.25,19.55 U23.12@283.25,22.05 ; U23.13@284.52,22.05 284.541,22.029 284.541,20.703 285.694,19.55 FB17.1@287.35,19.55
  Top Layer w0.6: U23.12@283.25,22.05 U23.13@284.52,22.05
VP_CAN: C149.1 C150.1 C151.1 D18.2 FB17.2 J11.2 U23.20 | length 69.6
  Top Layer w0.2: D18.2@286.25,16.35 288.15,18.25 FB17.2@288.15,19.55
  Top Layer w0.4: FB17.2@288.15,19.55 289.275,19.55 289.925,18.9 C151.1@290.25,18.9 292.1,18.9 C150.1@292.25,19.05 C149.1@293.65,19.05 ; U23.20@293.41,22.05 293.41,19.59 293.75,19.25 C149.1@293.75,19.15
  Top Layer w0.5: J11.2@250.94,10.43 250.94,9.061 255,5 285.695,5 295.1,14.405 295.1,18.4 294.35,19.15 C149.1@293.75,19.15
VP_CAN_SUBD: J1.9 J11.1 | length 18.6
  Top Layer w0.5: J11.1@253.861,12.97 253.861,10.981 257.823,7.018 267.211,7.018 268.273,8.08 J1.9@268.345,8.08
pads on no net: FID1.1 FID2.1 FID3.1 J1.1 J1.8 J2.2 J2.3 J2.4 J2.5 J3.2 J3.3 J3.4 J3.5 J4.3 J5.2 J5.3 J5.4 J5.5 J6.3 J7.2 J7.3 J7.4 J7.5 J8.2 J8.3 J8.4 J8.5 J9.2 J9.3 J9.4 J9.5 J10.2 J10.3 J10.4 J10.5 J12.1 J12.2 J12.3 J12.4 J12.5 J12.6 J12.8 J12.23 J12.32 J12.34 J12.41 J12.43 J12.44 J12.45 J12.66 J12.76 J12.85 J12.103 J12.105 J12.113 J12.114 J12.115 J12.116 J12.117 J12.118 J12.119 J12.120 J12.181 J12.182 J12.185 J12.186 J16.MH1 J16.MH2 J21.3 LBL1.0 MP1. MP1.1 MP2. MP2.1 MP3. MP3.1 MP4. MP5. MP5.1 MP6. MP7. MP7.1 MP8. MP8.1 MP9. MP9.1 MP10. MP10.1 MP11. MP11.1 MP12. MP13. MP13.1 MP14. MP14.1 MP15. MP15.1 Q1.0 Q2.0 Q3.0 R86.1 U1.2 U2.8 U2.10 U4.8 U4.10 U5.8 U5.10 U6.8 U6.10 U11.7 U11.8 U11.12 U11.13 U11.15 U20.9 U21.2 U22.7@149.05,16.376 U22.7@149.05,17.276 U23.2 U23.7 U23.14 U24.3 U25.3 U26_L1.1 U26_L1.16 U26_L1.17 U26_L1.27 U26_L1.43 U26_L1.47 U26_L1.48 U26_L1.51 U26_L1.52 U26_L2.1 U26_L2.16 U26_L2.17 U26_L2.27 U26_L2.43 U26_L2.47 U26_L2.48 U26_L2.51 U26_L2.52 U26_L3.1 U26_L3.16 U26_L3.17 U26_L3.27 U26_L3.43 U26_L3.47 U26_L3.48 U26_L3.51 U26_L3.52 U26_N.1 U26_N.16 U26_N.17 U26_N.27 U26_N.43 U26_N.47 U26_N.48 U26_N.51 U26_N.52 U27_L1.1 U27_L1.16 U27_L1.17 U27_L1.27 U27_L1.43 U27_L1.47 U27_L1.48 U27_L1.51 U27_L1.52 U27_L2.1 U27_L2.16 U27_L2.17 U27_L2.27 U27_L2.43 U27_L2.47 U27_L2.48 U27_L2.51 U27_L2.52 U27_L3.1 U27_L3.16 U27_L3.17 U27_L3.27 U27_L3.43 U27_L3.47 U27_L3.48 U27_L3.51 U27_L3.52 U27_N.1 U27_N.16 U27_N.17 U27_N.27 U27_N.43 U27_N.47 U27_N.48 U27_N.51 U27_N.52 U31_L1.1 U31_L1.16 U31_L1.17 U31_L1.27 U31_L1.43 U31_L1.47 U31_L1.48 U31_L1.51 U31_L1.52 U31_L2.1 U31_L2.16 U31_L2.17 U31_L2.27 U31_L2.43 U31_L2.47 U31_L2.48 U31_L2.51 U31_L2.52 U31_L3.1 U31_L3.16 U31_L3.17 U31_L3.27 U31_L3.43 U31_L3.47 U31_L3.48 U31_L3.51 U31_L3.52 U31_N.1 U31_N.16 U31_N.17 U31_N.27 U31_N.43 U31_N.47 U31_N.48 U31_N.51 U31_N.52 U36_L1.1 U36_L1.16 U36_L1.17 U36_L1.27 U36_L1.43 U36_L1.47 U36_L1.48 U36_L1.51 U36_L1.52 U36_L2.1 U36_L2.16 U36_L2.17 U36_L2.27 U36_L2.43 U36_L2.47 U36_L2.48 U36_L2.51 U36_L2.52 U36_L3.1 U36_L3.16 U36_L3.17 U36_L3.27 U36_L3.43 U36_L3.47 U36_L3.48 U36_L3.51 U36_L3.52 U36_N.1 U36_N.16 U36_N.17 U36_N.27 U36_N.43 U36_N.47 U36_N.48 U36_N.51 U36_N.52
copper on no net:
  other v1: 171.7,7.7 171.7,8.6 180.729,14.35 180.104,14.85 181.354,14.85 180.729,15.35 166.283,26.069 167.283,26.069 166.283,26.569 167.283,26.569 166.283,27.069 167.283,27.069 210,85

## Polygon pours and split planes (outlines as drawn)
V_PCC_L2 on Layer 2 "Layer 2-V_PCC_L2" (solid, remove dead copper, pour order 789): 29 vertices, not listed, extent 78,252 200,299
NetL12_8 on Layer 2 "LAYER_2_NETL12_8_P759" (solid, remove dead copper, pour order 759): 26 vertices, not listed, extent 159,237 288,270
I_PCC_L2+ on Layer 2 "LAYER_2_I_PCC_L2+_P746" (solid, remove dead copper, pour order 746): 17 vertices, not listed, extent 28.5,267.5 73,286
GND_S4_GaN_L1 on Layer 2 "Layer 2-VDC-_REF" (solid, pour order 848): 79 vertices, not listed, extent 1,7 270,297
GND on Layer 2 "Layer 2-GND" (solid, pour order 1021): 60 vertices, not listed, extent 34,0.6 299.9,275.5
5V on Layer 2 "NONET_L-01_P-001" (solid, pour order 828): 154.4,29.4 170,29.4 172.1,27.3 172.1,18.191 170.009,16.1 154.2,16.1 151.6,18.7 151.6,26.6
GRID_GND_1 on Layer 2 "LAYER_2_GRID_GND_1_P791" (solid, remove dead copper, pour order 791): 82,296 82,300 31,300 31,296 35,292 44,292 48,296
GND_S1_GaN_L1 on Layer 2 "LAYER_2_GND_S1_GAN_L1_P1070" (solid, remove dead copper, pour order 1070): 33,137 33,126 33.5,125.5 48,125.5 48,138 34,138
GND_S1_GaN_L2 on Layer 2 "LAYER_2_GND_S1_GAN_L2_P1067" (solid, remove dead copper, pour order 1067): 116.5,122 116.5,111 117,110.5 131.5,110.5 131.5,123 117.5,123
GND_S1_GaN_N on Layer 2 "LAYER_2_GND_S1_GAN_N_P977" (solid, remove dead copper, pour order 977): 99.5,3.5 110.5,3.5 111,4 111,18.5 98.5,18.5 98.5,4.5
GND_S3_GaN_N on Layer 2 "LAYER_2_GND_S3_GAN_N_P957" (solid, remove dead copper, pour order 957): 23 vertices, not listed, extent 84.5,36 112.5,57
GND_S3_GaN_L1 on Layer 2 "LAYER_2_GND_S3_GAN_L1_P1069" (solid, remove dead copper, pour order 1069): 23 vertices, not listed, extent 65.5,124 86.5,152
GND_S2_GaN_L1 on Layer 2 "LAYER_2_GND_S2_GAN_L1_P1068" (solid, remove dead copper, pour order 1068): 21 vertices, not listed, extent 49.5,125.5 67.5,150.5
GND_S3_GaN_L2 on Layer 2 "LAYER_2_GND_S3_GAN_L2_P1066" (solid, remove dead copper, pour order 1066): 23 vertices, not listed, extent 149,109 170,137
GND_S2_GaN_L2 on Layer 2 "LAYER_2_GND_S2_GAN_L2_P1065" (solid, remove dead copper, pour order 1065): 21 vertices, not listed, extent 133,110.5 151,135.5
GND_S1_GaN_L3 on Layer 2 "LAYER_2_GND_S1_GAN_L3_P1064" (solid, remove dead copper, pour order 1064): 202.5,94 202.5,83 203,82.5 217.5,82.5 217.5,95 203.5,95
GND_S3_GaN_L3 on Layer 2 "LAYER_2_GND_S3_GAN_L3_P1063" (solid, remove dead copper, pour order 1063): 23 vertices, not listed, extent 235,81 256,109
GND_S2_GaN_L3 on Layer 2 "LAYER_2_GND_S2_GAN_L3_P1062" (solid, remove dead copper, pour order 1062): 21 vertices, not listed, extent 219,82.5 237,107.5
GND_S4_GaN_L1 on Layer 2 "LAYER_2_GND_S4_GAN_L1_P1061" (solid, remove dead copper, pour order 1061): 23 vertices, not listed, extent 246.5,81 271,127
GND_S4_GaN_L1 on Layer 2 "LAYER_2_GND_S4_GAN_L1_P1060" (solid, remove dead copper, pour order 1060): 23 vertices, not listed, extent 160.5,109 185,155
GND_S4_GaN_L1 on Layer 2 "LAYER_2_GND_S4_GAN_L1_P1059" (solid, remove dead copper, pour order 1059): 23 vertices, not listed, extent 77,124 101.5,170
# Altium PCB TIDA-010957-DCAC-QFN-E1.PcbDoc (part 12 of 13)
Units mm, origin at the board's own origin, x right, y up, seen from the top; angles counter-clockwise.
Board outline 300 x 300 mm, 4 copper layers (Top Layer, Layer 1, Layer 2, Bottom Layer), stack 1.787 mm thick; 1286 components, 677 nets, 4169 pads, 3428 vias.

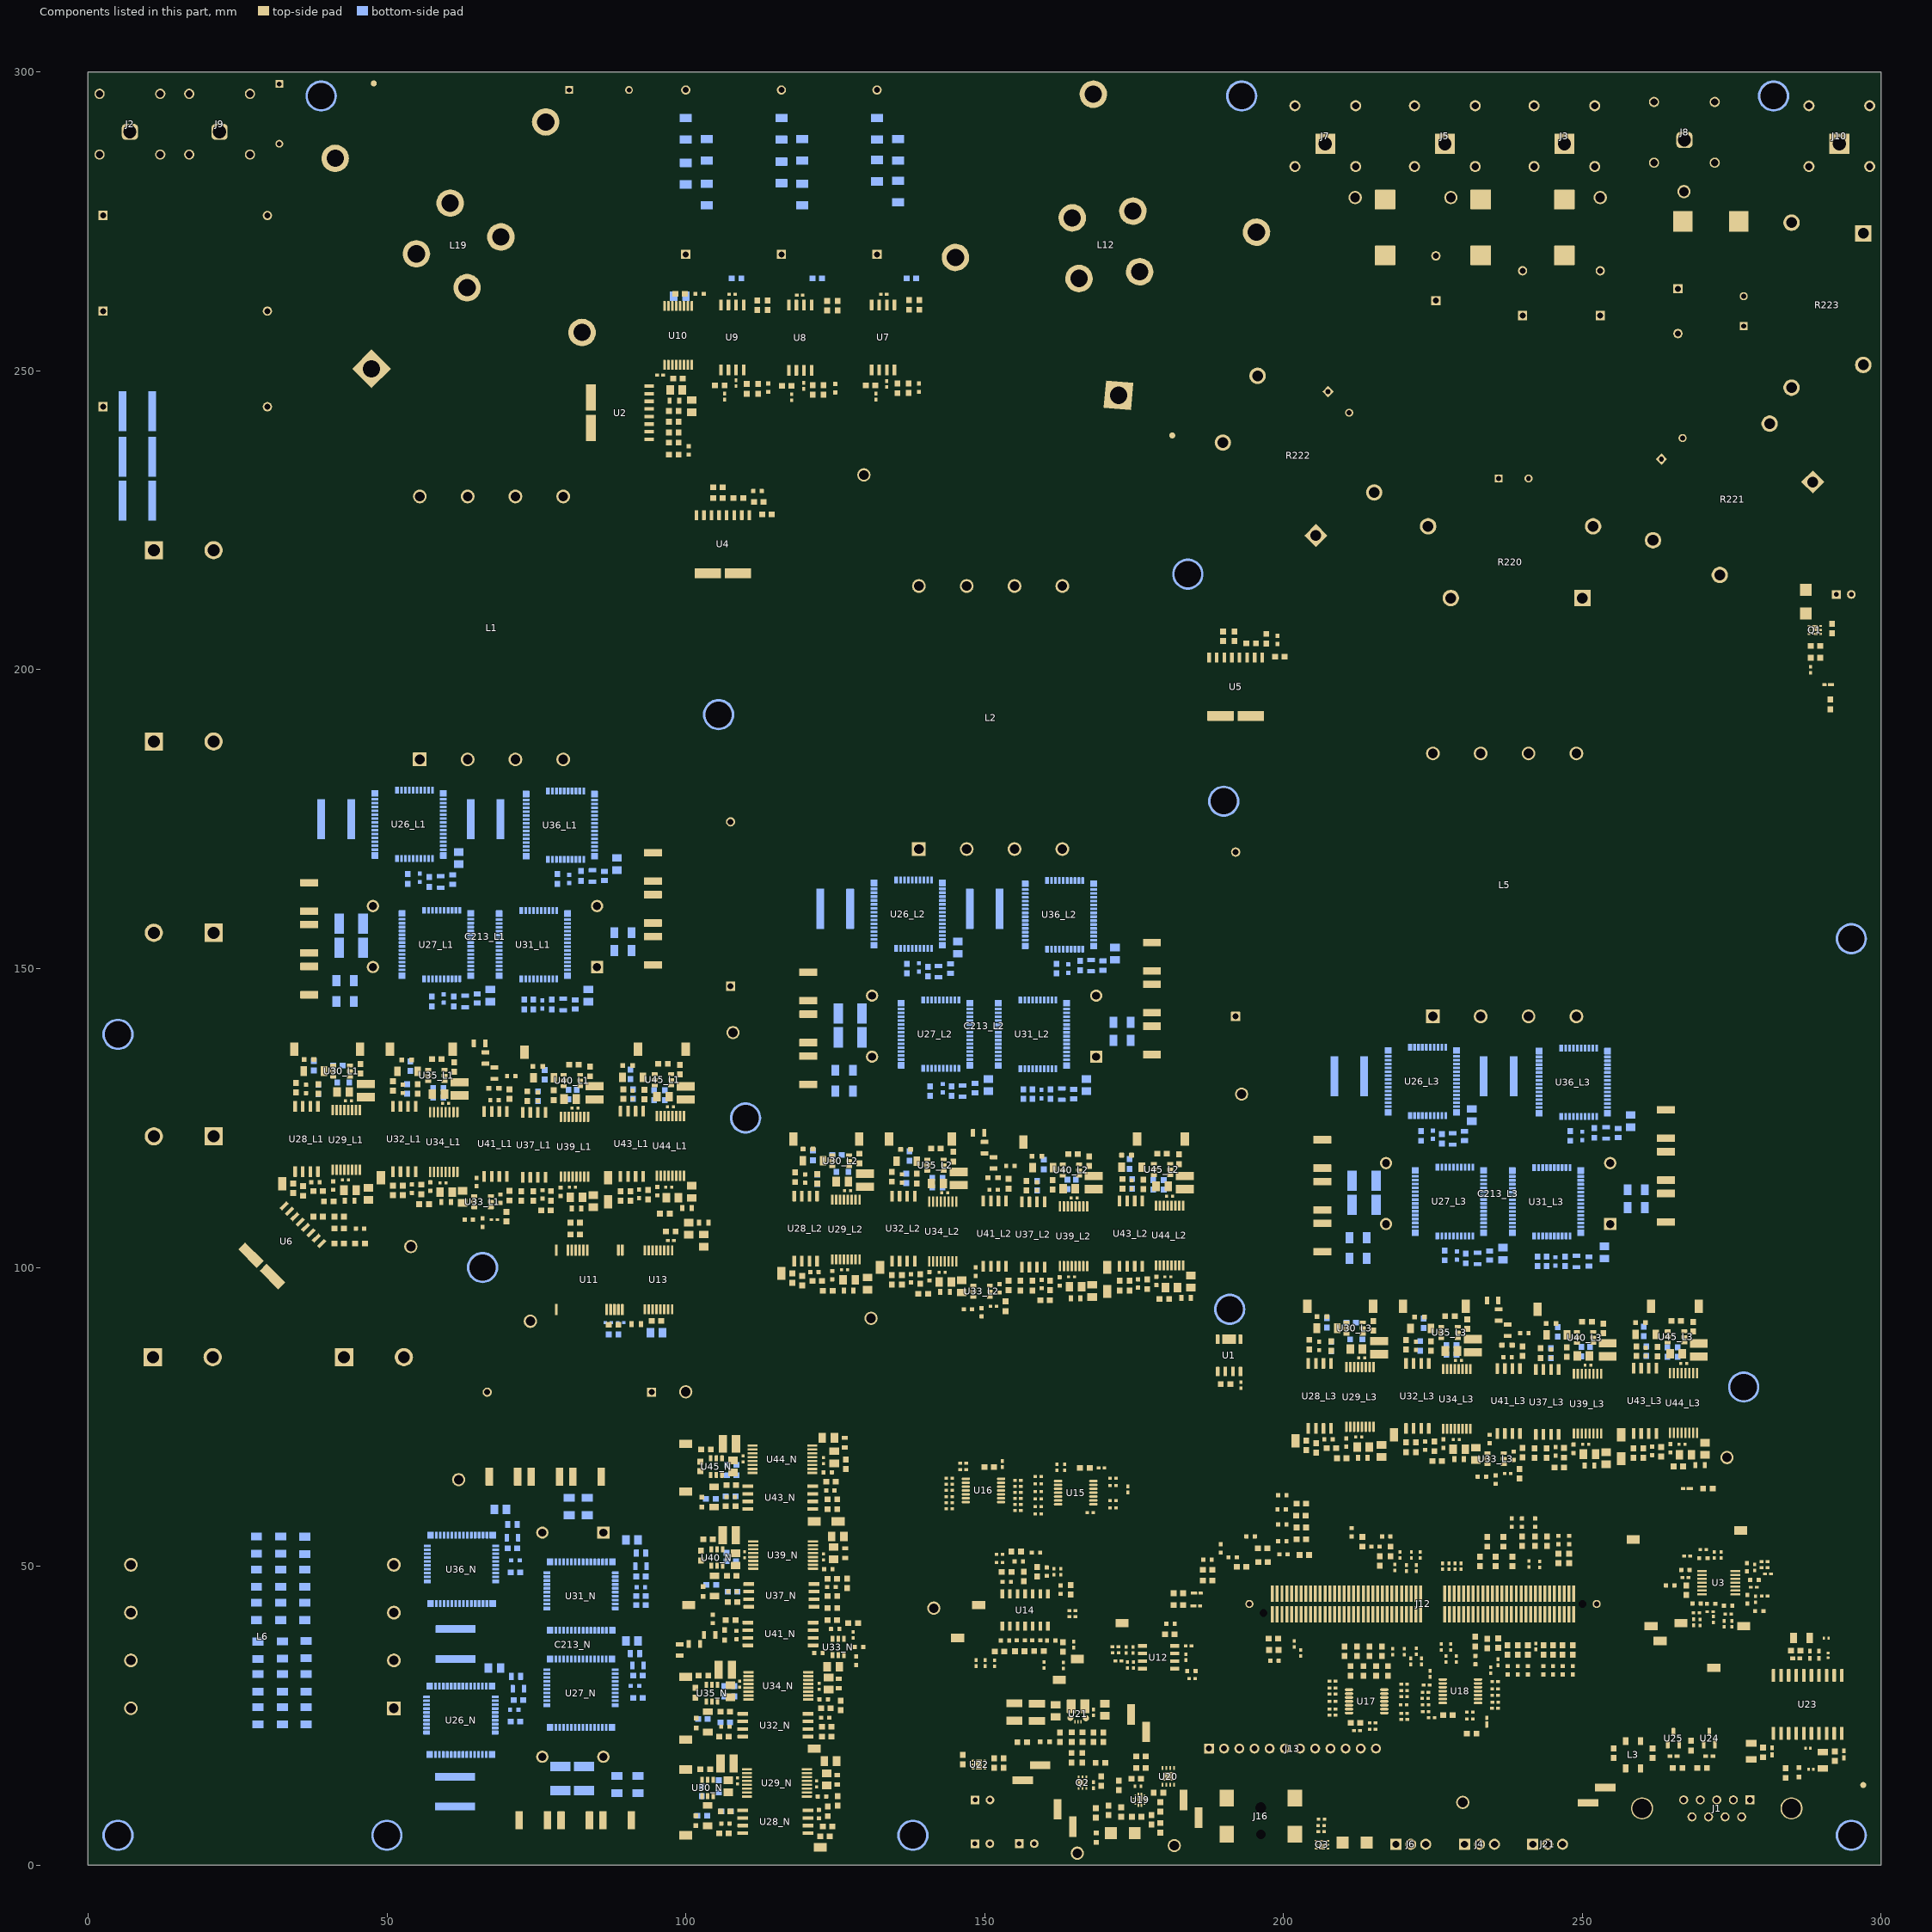
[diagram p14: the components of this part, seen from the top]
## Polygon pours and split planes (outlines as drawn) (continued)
GND_S3_GaN_L1 on Layer 2 "LAYER_2_GND_S3_GAN_L1_P926" (solid, remove dead copper, pour order 926): 17 vertices, not listed, extent 40,151.5 81,158.5
no net on Layer 2 "LAYER_2_NONET_P962" (solid, remove dead copper, pour order 962): 22 vertices, not listed, extent 77,124 101.5,169.5
no net on Layer 2 "LAYER_2_NONET_P966" (solid, remove dead copper, pour order 966): 53,159.5 53,160 55.5,162.5 61,162.5 63,164.5 63,170.5 59,170.5 57.5,169 54,169 51.5,166.5 51.5,162.5 50.5,161.5 50.5,159.5
GND_S1_GaN_L1 on Layer 2 "LAYER_2_GND_S1_GAN_L1_P974" (solid, remove dead copper, pour order 974): 51,171.5 45.5,166 45.5,158.5 49.5,158.5 49.5,166 52.5,169 57,169 58.5,170.5 58.5,171.5
GND_S3_GaN_L3 on Layer 2 "LAYER_2_GND_S3_GAN_L3_P928" (solid, remove dead copper, pour order 928): 213.5,115.5 215,114 219,114 220.5,115.5 225,115.5 226,114.5 243,114.5 244,115.5 250.5,115.5 250.5,108.5 243,108.5 242,109.5 209.5,109.5 209.5,115.5
no net on Layer 2 "LAYER_2_NONET_P968" (solid, remove dead copper, pour order 968): 222.5,116.5 222.5,117 225,119.5 230.5,119.5 232.5,121.5 232.5,127.5 228.5,127.5 227,126 223.5,126 221,123.5 221,119.5 220,118.5 220,116.5
GND_S1_GaN_L3 on Layer 2 "LAYER_2_GND_S1_GAN_L3_P976" (solid, remove dead copper, pour order 976): 220.5,128.5 215,123 215,116.5 216,115.5 218.5,115.5 219,116 219,123 222,126 226.5,126 228,127.5 228,128.5
GND_S1_GaN_L2 on Layer 2 "LAYER_2_GND_S1_GAN_L2_P975" (solid, remove dead copper, pour order 975): 134.5,156.5 129,151 129,143.5 133,143.5 133,151 136,154 140.5,154 142,155.5 142,156.5
no net on Layer 2 "LAYER_2_NONET_P967" (solid, remove dead copper, pour order 967): 136.5,144.5 136.5,145 139,147.5 144.5,147.5 146.5,149.5 146.5,155.5 142.5,155.5 141,154 137.5,154 135,151.5 135,147.5 134,146.5 134,144.5
GND_S3_GaN_L2 on Layer 2 "LAYER_2_GND_S3_GAN_L2_P927" (solid, remove dead copper, pour order 927): 17 vertices, not listed, extent 123.5,136.5 164.5,143.5
GND_S3_GaN_N on Layer 2 "LAYER_2_GND_S3_GAN_N_P925" (solid, remove dead copper, pour order 925): 17 vertices, not listed, extent 78,10.5 85,51.5
GND_S1_GaN_N on Layer 2 "LAYER_2_GND_S1_GAN_N_P973" (solid, remove dead copper, pour order 973): 65,21.5 70.5,16 78,16 78,20 70.5,20 67.5,23 67.5,27.5 66,29 65,29
no net on Layer 2 "LAYER_2_NONET_P965" (solid, remove dead copper, pour order 965): 77,23.5 76.5,23.5 74,26 74,31.5 72,33.5 66,33.5 66,29.5 67.5,28 67.5,24.5 70,22 74,22 75,21 77,21
GND_S4_GaN_L1 on Layer 2 "LAYER_2_GND_S4_GAN_L1_P961" (solid, remove dead copper, pour order 961): 23 vertices, not listed, extent 66,47.5 112.5,72
GND_S2_GaN_N on Layer 2 "LAYER_2_GND_S2_GAN_N_P953" (solid, remove dead copper, pour order 953): 21 vertices, not listed, extent 86,20 111,38
PCC_N on Layer 2 "LAYER_2_PCC_N_P864" (solid, remove dead copper, pour order 864): 263,273 263,293 270,293 270,273
PCC_L1 on Layer 2 "LAYER_2_PCC_L1_P863" (solid, remove dead copper, pour order 863): 243,277 243,293 251,293 251,282 256,282 256,277
PCC_L2 on Layer 2 "LAYER_2_PCC_L2_P862" (solid, remove dead copper, pour order 862): 224,277 224,293 231,293 231,280 231,277 225,277
PCC_L3 on Layer 2 "LAYER_2_PCC_L3_P860" (solid, remove dead copper, pour order 860): 211,277 204,284 204,292 211,292 211,283 214,280 214,277
12V on Layer 2 "NONET_L-01_P-001" (solid, pour order 825): 146.786,13.043 161.857,13.043 163.3,11.6 163.3,3.6 161.1,1.4 147.1,1.4 145.8,2.7 145.8,12.056
+12V_OUT on Layer 2 "NONET_L-01_P-001" (solid, pour order 823): 168,12.7 180.9,12.7 180.9,5.3 177.9,2.3 165.6,2.3 163.5,4.4 163.5,8.2
+12V_OUT on Layer 2 "NONET_L-01_P-001" (solid, pour order 824): 180.9,7.4 183.8,4.5 183.8,2.6 183.5,2.3 177.7,2.3 177.7,7.4
+5VISO_PCC on Layer 2 "NONET_L-01_P-001" (solid, pour order 811): 103.009,266.3 139.6,266.3 140.1,265.8 140.1,259.826 139.774,259.5 103.5,259.5 102.6,260.4 102.6,265.891
I_PCC_N+ on Bottom Layer "Bottom Layer-I_PCC_N+" (solid, pour order 847): 33 vertices, not listed, extent 0.5,94.5 59,289
V_PCC_N on Bottom Layer "Bottom Layer-V_PCC_N" (solid, remove dead copper, pour order 790): 27 vertices, not listed, extent 38,263 149,299
NetL12_4 on Bottom Layer "BOTTOM_LAYER_NETL12_4_P752" (solid, remove dead copper, pour order 752): 257,224 257,220 260.5,216.5 272,228 249,251 232,251 198,285 177,285 172,280 172,273 188.9,273 193.5,277.6 198.8,277.6 235.4,241 240,241
NetL12_2 on Bottom Layer "BOTTOM_LAYER_NETL12_2_P751" (solid, remove dead copper, pour order 751): 172.5,263 172.5,270 201,270 237,234 237,221.5 220.5,221.5 220.5,241.5 199,263
NetL12_6 on Bottom Layer "BOTTOM_LAYER_NETL12_6_P750" (solid, remove dead copper, pour order 750): 18 vertices, not listed, extent 153.5,245 201,280
I_PCC_L1+ on Bottom Layer "BOTTOM_LAYER_I_PCC_L1+_P747" (solid, remove dead copper, pour order 747): 60.5,265.5 62,267 64.7,267 66.9,264.8 66.9,262.4 62.5,258 27.5,258 27.5,261 56,261
I_PCC_L2+ on Bottom Layer "BOTTOM_LAYER_I_PCC_L2+_P743" (solid, remove dead copper, pour order 743): 23 vertices, not listed, extent 65.5,210 106,276
I_PCC_L3- on Bottom Layer "BOTTOM_LAYER_I_PCC_L3-_P842" (solid, remove dead copper, pour order 842): 194.1,187 193.7,187.4 192.6,187.4 192.6,192.4 194.1,192.4 254,192.4 254,183.9 194.1,183.9
I_PCC_L2- on Bottom Layer "BOTTOM_LAYER_I_PCC_L2-_P840" (solid, remove dead copper, pour order 840): 106.6,216.5 118,216.5 119,217.5 166,217.5 166,211 106.6,211
I_PCC_N- on Bottom Layer "BOTTOM_LAYER_I_PCC_N-_P739" (solid, remove dead copper, pour order 739): 1.5,22 7.5,22 9.5,24 9.5,52 7.5,54 7.5,80.5 1.5,80.5
GND on Bottom Layer "Bottom Layer-GND" (solid, pour order 1018): 62 vertices, not listed, extent 31.871,0.621 299.671,275.521
GND_S3_GaN_L3 on Bottom Layer "Bottom Layer-NetC213_N_1" (solid, remove dead copper, pour order 920): 24 vertices, not listed, extent 238,105 258,135.5
GRID_GND on Bottom Layer "NONET_L-01_P-001" (solid, pour order 841): 277.5,299.8 295.9,299.8 299.2,296.5 299.2,281 298.5,280.3 278.4,280.3 276.4,282.3 276.4,298.7
NetMP12_1 on Bottom Layer "BOTTOM_LAYER_NETMP12_1_P796" (solid, remove dead copper, pour order 796): 187.9,88.4 187.9,97.3 193.9,97.3 193.9,88.4
GRID_GND_1 on Bottom Layer "BOTTOM_LAYER_GRID_GND_1_P792" (solid, remove dead copper, pour order 792): 31.2,296.1 31.2,299.6 43.6,299.6 43.6,292 35.3,292
VDC+ on Bottom Layer "NONET_L-01_P-001" (solid, pour order 1055): 214.772,136.357 214.772,128.299 212.972,128.299 212.972,136.357
VDC+ on Bottom Layer "NONET_L-01_P-001" (solid, pour order 1051): 129.186,164 129.186,155.941 127.386,155.941 127.386,164
VDC+ on Bottom Layer "NONET_L-01_P-001" (solid, pour order 1048): 45.224,179.056 45.224,170.997 43.424,170.997 43.424,179.056
VDC+ on Bottom Layer "NONET_L-01_P-001" (solid, pour order 1045): 57.444,15.724 65.503,15.724 65.503,13.924 57.444,13.924
VDC+ on Bottom Layer "BOTTOM_LAYER_VDC+_P936" (solid, remove dead copper, pour order 936): 218,143.5 218,137.5 216.5,136 216.5,133 213.5,133 213,133.5 213,143.5
VDC+ on Bottom Layer "BOTTOM_LAYER_VDC+_P935" (solid, remove dead copper, pour order 935): 130.5,164 133,164 133,171.5 127,171.5 127,161.5 127.5,161 130.5,161
VDC+ on Bottom Layer "BOTTOM_LAYER_VDC+_P934" (solid, remove dead copper, pour order 934): 48.5,179.5 49.5,179.5 49.5,180.5 49.5,186.5 43.5,186.5 43.5,176.5 44,176 47,176 47,178
VDC+ on Bottom Layer "BOTTOM_LAYER_VDC+_P933" (solid, remove dead copper, pour order 933): 26,24 45,24 49.5,19.5 57.5,19.5 59.5,17.5 60.5,17.5 60.5,14.5 60,14 32,14 26,20
GND_S4_GaN_L1 on Bottom Layer "BOTTOM_LAYER_GND_S4_GAN_L1_P932" (solid, remove dead copper, pour order 932): 206,136.5 206,128 210.5,128 210.5,136.5
GND_S4_GaN_L1 on Bottom Layer "BOTTOM_LAYER_GND_S4_GAN_L1_P931" (solid, remove dead copper, pour order 931): 120,164.5 120,156 124.5,156 124.5,164.5
GND_S4_GaN_L1 on Bottom Layer "BOTTOM_LAYER_GND_S4_GAN_L1_P930" (solid, remove dead copper, pour order 930): 36.5,179.5 36.5,171 41,171 41,179.5
GND_S4_GaN_L1 on Bottom Layer "BOTTOM_LAYER_GND_S4_GAN_L1_P929" (solid, remove dead copper, pour order 929): 57,7 65.5,7 65.5,11.5 57,11.5
VDC+ on Bottom Layer "BOTTOM_LAYER_VDC+_P916" (solid, remove dead copper, pour order 916): 212.5,122.5 211.5,122.5 210.5,121.5 204,121.5 204,124 210.5,124 213,126.5 213,143.5 219,143.5 219,126.5 216.5,126.5 215.5,125.5
VDC+ on Bottom Layer "BOTTOM_LAYER_VDC+_P915" (solid, remove dead copper, pour order 915): 126.5,150.5 125.5,150.5 124.5,149.5 118,149.5 118,152 124.5,152 127,154.5 127,165 133,165 133,154.5 130.5,154.5 129.5,153.5
VDC+ on Bottom Layer "BOTTOM_LAYER_VDC+_P914" (solid, remove dead copper, pour order 914): 43,165.5 42,165.5 41,164.5 34.5,164.5 34.5,167 41,167 43.5,169.5 43.5,180 49.5,180 49.5,169.5 47,169.5 46,168.5
VDC+ on Bottom Layer "BOTTOM_LAYER_VDC+_P913" (solid, remove dead copper, pour order 913): 71,13.5 71,12.5 72,11.5 72,5 69.5,5 69.5,11.5 67,14 55.5,14 55.5,19.5 67,19.5 67,17.5 68,16.5
GND_S3_GaN_L1 on Bottom Layer "Bottom Layer-NetC213_N_1" (solid, remove dead copper, pour order 918): 21 vertices, not listed, extent 68.5,148 88.5,178.5
GND_S2_GaN_L1 on Bottom Layer "BOTTOM_LAYER_GND_S2_GAN_L1_P1073" (solid, remove dead copper, pour order 1073): 24 vertices, not listed, extent 56.5,149 70,168
GND_S2_GaN_L2 on Bottom Layer "BOTTOM_LAYER_GND_S2_GAN_L2_P1072" (solid, remove dead copper, pour order 1072): 24 vertices, not listed, extent 140,134 153.5,153
GND_S2_GaN_L3 on Bottom Layer "BOTTOM_LAYER_GND_S2_GAN_L3_P1071" (solid, remove dead copper, pour order 1071): 25 vertices, not listed, extent 226,106 239.5,125
GND_S4_GaN_L1 on Bottom Layer "Bottom Layer-VDC-_REF" (solid, remove dead copper, pour order 1017): 18 vertices, not listed, extent 26.5,47.5 67.2,60.5
GND_S3_GaN_L3 on Bottom Layer "NONET_L-01_P-001" (solid, pour order 1058): 239.897,135.941 239.897,127.882 238.097,127.882 238.097,135.941
GND_S1_GaN_L3 on Bottom Layer "NONET_L-01_P-001" (solid, pour order 1057): 234,136.029 234,127.971 232.2,127.971 232.2,136.029
GND_S1_GaN_L3 on Bottom Layer "NONET_L-01_P-001" (solid, pour order 1056): 216.5,116.529 216.5,108.471 214.7,108.471 214.7,116.529
GND_S1_GaN_L2 on Bottom Layer "NONET_L-01_P-001" (solid, pour order 1054): 130.7,144.529 130.7,136.471 128.9,136.471 128.9,144.529
GND_S3_GaN_L2 on Bottom Layer "NONET_L-01_P-001" (solid, pour order 1053): 154.186,164 154.186,155.941 152.386,155.941 152.386,164
GND_S1_GaN_L2 on Bottom Layer "NONET_L-01_P-001" (solid, pour order 1052): 148.186,164 148.186,155.941 146.386,155.941 146.386,164
GND_S3_GaN_L1 on Bottom Layer "NONET_L-01_P-001" (solid, pour order 1050): 70.686,179 70.686,170.941 68.886,170.941 68.886,179
GND_S1_GaN_L1 on Bottom Layer "NONET_L-01_P-001" (solid, pour order 1049): 64.4,179 64.4,170.941 62.6,170.941 62.6,179
GND_S1_GaN_L1 on Bottom Layer "NONET_L-01_P-001" (solid, pour order 1047): 47.186,159.5 47.186,151.441 45.386,151.441 45.386,159.5
GND_S3_GaN_N on Bottom Layer "Bottom Layer-NetC213_N_1" (solid, remove dead copper, pour order 917): 28 vertices, not listed, extent 58,39 88.5,59
GND_S1_GaN_N on Bottom Layer "BOTTOM_LAYER_GND_S1_GAN_N_P905" (solid, remove dead copper, pour order 905): 58.5,23.5 58.5,27.5 59,28 64,28 64.5,27.5 64.5,24 65.5,23 67,23 67,27.5 65.5,29 65.5,35 57.5,35 55.5,33 55.5,22.5 57.5,22.5
GND_S1_GaN_N on Bottom Layer "NONET_L-01_P-001" (solid, pour order 1044): 77,17.686 85.059,17.686 85.059,15.886 77,15.886
GND_S3_GaN_N on Bottom Layer "NONET_L-01_P-001" (solid, pour order 1043): 58.1,40.8 65.5,40.8 65.5,39 58.1,39
GND_S1_GaN_N on Bottom Layer "NONET_L-01_P-001" (solid, pour order 1042): 57.65,35 65.55,35 65.55,33.2 57.65,33.2
GND_S4_GaN_L1 on Bottom Layer "Bottom Layer-VDC-_REF" (solid, remove dead copper, pour order 1041): 252,127.5 247.5,127.5 247.5,126 253.5,126 253.5,127 259.5,127 259.5,138 246,138 246,135 252,135
GND_S4_GaN_L1 on Bottom Layer "Bottom Layer-VDC-_REF" (solid, remove dead copper, pour order 1039): 166,155.5 161.5,155.5 161.5,154 167.5,154 167.5,155 173.5,155 173.5,166 160,166 160,163 166,163
GND_S4_GaN_L1 on Bottom Layer "Bottom Layer-VDC-_REF" (solid, remove dead copper, pour order 1038): 82.5,170.5 78,170.5 78,169 84,169 84,170 90,170 90,181 76.5,181 76.5,178 82.5,178
NetD8_L1_2 on Bottom Layer "NONET_L-01_P-001" (solid, pour order 844): 38.5,145 35,145 35,142.5 40,142.5 41.9,142.5 41.9,149.166 40.031,149.166 40,149.134 40,146.5
GND_S1_GaN_L1 on Bottom Layer "BOTTOM_LAYER_GND_S1_GAN_L1_P906" (solid, remove dead copper, pour order 906): 53.5,177.5 57,177.5 58,176.5 58,172.5 57,171.5 53.5,171.5 52,170 52.5,169.5 57,169.5 58,170.5 64.5,170.5 64.5,179 63,180.5 52,180.5 52,179
GND_S1_GaN_L1 on Bottom Layer "BOTTOM_LAYER_GND_S1_GAN_L1_P910" (solid, remove dead copper, pour order 910): 45.5,150 44,150 44,143.5 46,143.5 53.5,143.5 53.5,158 51,160.5 51,165.5 50,166.5 48,166.5 45.5,164
GND_S3_GaN_L1 on Bottom Layer "BOTTOM_LAYER_GND_S3_GAN_L1_P922" (solid, remove dead copper, pour order 922): 43.5,158.5 40,158.5 40,153 43.5,153
NetD13_L1_1 on Bottom Layer "BOTTOM_LAYER_NETD13_L1_1_P990" (solid, remove dead copper, pour order 990): 90.5,157.5 92,157.5 92,150.5 96,150.5 96,148.5 91,148.5 90.5,149
V_PCC_IN1 on Bottom Layer "BOTTOM_LAYER_V_PCC_IN1_P1037" (solid, remove dead copper, pour order 1037): 132,279 132,277.5 139,277.5 139,279
V_PCC_IN2 on Bottom Layer "BOTTOM_LAYER_V_PCC_IN2_P1036" (solid, remove dead copper, pour order 1036): 116,278.5 116,277 123,277 123,278.5
V_PCC_IN3 on Bottom Layer "BOTTOM_LAYER_V_PCC_IN3_P1035" (solid, remove dead copper, pour order 1035): 100,278.5 100,277 107,277 107,278.5
V_PCC_L1 on Bottom Layer "BOTTOM_LAYER_V_PCC_L1_P1034" (solid, remove dead copper, pour order 1034): 128.5,293 128.5,291.5 135.5,291.5 135.5,293
V_PCC_L2 on Bottom Layer "BOTTOM_LAYER_V_PCC_L2_P1033" (solid, remove dead copper, pour order 1033): 112.5,293 112.5,291.5 119.5,291.5 119.5,293
V_PCC_L3 on Bottom Layer "BOTTOM_LAYER_V_PCC_L3_P1032" (solid, remove dead copper, pour order 1032): 96.5,293 96.5,291.5 103.5,291.5 103.5,293
NetR238_1 on Bottom Layer "BOTTOM_LAYER_NETR238_1_P1031" (solid, remove dead copper, pour order 1031): 130,282.5 130,281 137,281 137,282.5
NetR237_1 on Bottom Layer "BOTTOM_LAYER_NETR237_1_P1030" (solid, remove dead copper, pour order 1030): 130,286 130,284.5 137,284.5 137,286
NetR236_1 on Bottom Layer "BOTTOM_LAYER_NETR236_1_P1029" (solid, remove dead copper, pour order 1029): 130,289.5 130,288 137,288 137,289.5
NetR243_1 on Bottom Layer "BOTTOM_LAYER_NETR243_1_P1028" (solid, remove dead copper, pour order 1028): 114,282 114,280.5 121,280.5 121,282
NetR242_1 on Bottom Layer "BOTTOM_LAYER_NETR242_1_P1027" (solid, remove dead copper, pour order 1027): 114,286 114,284.5 121,284.5 121,286
NetR241_1 on Bottom Layer "BOTTOM_LAYER_NETR241_1_P1026" (solid, remove dead copper, pour order 1026): 114,289.5 114,288 121,288 121,289.5
NetR248_1 on Bottom Layer "BOTTOM_LAYER_NETR248_1_P1025" (solid, remove dead copper, pour order 1025): 98,282 98,280.5 105,280.5 105,282
NetR247_1 on Bottom Layer "BOTTOM_LAYER_NETR247_1_P1024" (solid, remove dead copper, pour order 1024): 98,286 98,284.5 105,284.5 105,286
NetR246_1 on Bottom Layer "BOTTOM_LAYER_NETR246_1_P1023" (solid, remove dead copper, pour order 1023): 98,289.5 98,288 105,288 105,289.5
+12V_OUT on Bottom Layer "NONET_L-01_P-001" (solid, pour order 831): 178.3,24.4 179.8,22.9 179.8,16.5 182,14.3 182,11.5 178.594,8.094 168.8,8.094 168.8,24.4
NetD8_L3_2 on Bottom Layer "NONET_L-01_P-001" (solid, pour order 846): 208,102 204.5,102 204.5,99.5 209.5,99.5 210.831,99.5 210.831,106.166 209.531,106.166 209.5,106.134 209.5,103.5
GND_S1_GaN_L3 on Bottom Layer "BOTTOM_LAYER_GND_S1_GAN_L3_P908" (solid, remove dead copper, pour order 908): 223,134.5 226,134.5 227,133.5 227,129.5 226,128.5 223,128.5 221.5,127 222,126.5 226.5,126.5 227.5,127.5 234,127.5 234,136 232.5,137.5 221.5,137.5 221.5,136
GND_S1_GaN_L3 on Bottom Layer "BOTTOM_LAYER_GND_S1_GAN_L3_P912" (solid, remove dead copper, pour order 912): 215,107 213.5,107 213.5,100.5 215.5,100.5 223.2,100.5 223.2,114.8 220.5,117.5 220.5,122.5 219.5,123.5 217.5,123.5 215,121
GND_S3_GaN_L3 on Bottom Layer "BOTTOM_LAYER_GND_S3_GAN_L3_P924" (solid, remove dead copper, pour order 924): 213,115.5 209.5,115.5 209.5,110 213,110
NetD13_L3_1 on Bottom Layer "BOTTOM_LAYER_NETD13_L3_1_P992" (solid, remove dead copper, pour order 992): 260,114.5 261.5,114.5 261.5,107.5 265.5,107.5 265.5,105.5 260.5,105.5 260,106
NetD13_L2_1 on Bottom Layer "BOTTOM_LAYER_NETD13_L2_1_P991" (solid, remove dead copper, pour order 991): 174,142.5 175.5,142.5 175.5,135.5 179.5,135.5 179.5,133.5 174.5,133.5 174,134
GND_S3_GaN_L2 on Bottom Layer "BOTTOM_LAYER_GND_S3_GAN_L2_P923" (solid, remove dead copper, pour order 923): 127,143.5 123.5,143.5 123.5,138 127,138
GND_S3_GaN_L2 on Bottom Layer "Bottom Layer-NetC213_N_1" (solid, remove dead copper, pour order 919): 23 vertices, not listed, extent 152,133 172,163.5
GND_S1_GaN_L2 on Bottom Layer "BOTTOM_LAYER_GND_S1_GAN_L2_P911" (solid, remove dead copper, pour order 911): 129,135 127.5,135 127.5,128.5 129.5,128.5 137,128.5 137,143 134.5,145.5 134.5,150.5 133.5,151.5 131.5,151.5 129,149
GND_S1_GaN_L2 on Bottom Layer "BOTTOM_LAYER_GND_S1_GAN_L2_P907" (solid, remove dead copper, pour order 907): 137,162.5 140,162.5 141,161.5 141,157.5 140,156.5 137,156.5 135.5,155 136,154.5 140.5,154.5 141.5,155.5 148,155.5 148,164 146.5,165.5 135.5,165.5 135.5,164
NetD8_L2_2 on Bottom Layer "NONET_L-01_P-001" (solid, pour order 845): 122,130 118.5,130 118.5,127.5 123.5,127.5 124.831,127.5 124.831,134.166 123.531,134.166 123.5,134.134 123.5,131.5
GND_S3_GaN_N on Bottom Layer "BOTTOM_LAYER_GND_S3_GAN_N_P921" (solid, remove dead copper, pour order 921): 78,14 78,10.5 83.5,10.5 83.5,14
GND_S1_GaN_N on Bottom Layer "BOTTOM_LAYER_GND_S1_GAN_N_P909" (solid, remove dead copper, pour order 909): 86.5,16 86.5,14.5 93,14.5 93,16.5 93,24.5 79,24.5 76,21.5 71,21.5 70,20.5 70,18.5 72.5,16
NetD13_N_1 on Bottom Layer "BOTTOM_LAYER_NETD13_N_1_P989" (solid, remove dead copper, pour order 989): 79,61 79,62.5 86,62.5 86,66.5 88,66.5 88,61.5 87.5,61
NetR13_1 on Bottom Layer "BOTTOM_LAYER_NETR13_1_P735" (solid, remove dead copper, pour order 735): 38,52.7 38,48.8 26.5,48.8 26.5,52.7
NetR10_1 on Bottom Layer "BOTTOM_LAYER_NETR10_1_P736" (solid, remove dead copper, pour order 736): 38,47.192 38,43.272 26.5,43.272 26.5,47.192
GND_S2_GaN_N on Bottom Layer "BOTTOM_LAYER_GND_S2_GAN_N_P893" (solid, remove dead copper, pour order 893): 24 vertices, not listed, extent 68.5,27 87.5,40.5
12V on Bottom Layer "NONET_L-01_P-001" (solid, pour order 826): 161,13.1 166.6,7.5 249.9,7.5 250.6,6.8 250.6,1.2 249.8,0.4 147,0.4 145.4,2 145.4,11.8 146.7,13.1
GND_S4_GaN_L1 on Bottom Layer "BOTTOM_LAYER_GND_S4_GAN_L1_P865" (solid, remove dead copper, pour order 865): 197,127 197,145 188,145 188,127
PCC_L3 on Bottom Layer "BOTTOM_LAYER_PCC_L3_P856" (solid, remove dead copper, pour order 856): 204.082,291.109 204.082,284.082 204,284 211,277 214,277 214,281 213,281 211,283 211,290 210,291 204,291
PCC_L2 on Bottom Layer "BOTTOM_LAYER_PCC_L2_P855" (solid, remove dead copper, pour order 855): 231,283 234.5,283 234.5,276 225,276 224,277 224,292 230,292 230,284
PCC_L1 on Bottom Layer "BOTTOM_LAYER_PCC_L1_P854" (solid, remove dead copper, pour order 854): 244,292 250,292 250,282 251,281 256,281 256,277 246,277 244,279
PCC_N on Bottom Layer "BOTTOM_LAYER_PCC_N_P853" (solid, remove dead copper, pour order 853): 264,276 270,276 270,292 264,292
NetD8_N_2 on Bottom Layer "NONET_L-01_P-001" (solid, pour order 843): 91.5,9 91.5,5.5 94,5.5 94,10.5 94,12.3 87.334,12.3 87.334,10.531 87.366,10.5 90,10.5
I_PCC_L3+ on Bottom Layer "BOTTOM_LAYER_I_PCC_L3+_P744" (solid, remove dead copper, pour order 744): 19 vertices, not listed, extent 34,184.5 192,243
NetC75_1 on Bottom Layer "NONET_L-01_P-001" (solid, pour order 808): 99.608,263.371 101.829,263.371 101.971,263.229 101.971,261.721 99.421,261.721 99.4,261.7 99.4,263.371
V_PCC_N on Bottom Layer "NONET_L-01_P-001" (solid, pour order 805): 96,263.8 98.7,263.8 98.8,263.7 98.8,261.8 98.6,261.6 96,261.6
Middle_Point on Bottom Layer "Bottom Layer-Middle_Point" (solid, remove dead copper, pour order 788): 24 vertices, not listed, extent 8.6,36.85 45,246
NetF2_1 on Bottom Layer "BOTTOM_LAYER_NETF2_1_P757" (solid, remove dead copper, pour order 757): 230.5,271 244,271 244,265 257,252 274,252 283.5,242.5 283.5,239.5 273,239.5 272,240.5 268.5,244 258.5,244 238.5,264 230.5,264
NetR1_1 on Bottom Layer "BOTTOM_LAYER_NETR1_1_P738" (solid, remove dead copper, pour order 738): 38.248,29.7 38.248,25.8 26.748,25.8 26.748,29.7
NetR4_1 on Bottom Layer "BOTTOM_LAYER_NETR4_1_P737" (solid, remove dead copper, pour order 737): 38.248,35.2 38.248,31.3 26.748,31.3 26.748,35.2
NetL12_2 on Top Layer "TOP_LAYER_NETL12_2_P869" (solid, remove dead copper, pour order 869): 172,270 172,263 181,263 181,270
NetL12_4 on Top Layer "TOP_LAYER_NETL12_4_P868" (solid, remove dead copper, pour order 868): 171,273 171,279 174,282 180,282 180,273
I_PCC_L3+ on Top Layer "Top Layer-I_PCC_L3+" (solid, remove dead copper, pour order 850): 23 vertices, not listed, extent 27.5,235.5 65,285
NetL12_6 on Top Layer "TOP_LAYER_NETL12_6_P793" (solid, remove dead copper, pour order 793): 19 vertices, not listed, extent 154,246 200,280
V_PCC_L3 on Top Layer "TOP_LAYER_V_PCC_L3_P748" (solid, remove dead copper, pour order 748): 20 vertices, not listed, extent 73,275 173,299.5
I_PCC_L1+ on Top Layer "TOP_LAYER_I_PCC_L1+_P741" (solid, remove dead copper, pour order 741): 67,265 70,265 70,254 76,248 84.9,248 84.9,243.4 64.6,243.4 60,248 60,265 62,267 65,267
GND_S2_GaN_L3 on Top Layer "TOP_LAYER_GND_S2_GAN_L3_P900" (solid, remove dead copper, pour order 900): 18 vertices, not listed, extent 222.5,117.5 252,145
GND_S2_GaN_L2 on Top Layer "TOP_LAYER_GND_S2_GAN_L2_P899" (solid, remove dead copper, pour order 899): 18 vertices, not listed, extent 136.5,145.5 166,173
GND_S2_GaN_L1 on Top Layer "TOP_LAYER_GND_S2_GAN_L1_P898" (solid, remove dead copper, pour order 898): 18 vertices, not listed, extent 53,160.5 82.5,188
GND_S2_GaN_N on Top Layer "TOP_LAYER_GND_S2_GAN_N_P897" (solid, remove dead copper, pour order 897): 18 vertices, not listed, extent 48.5,23.5 76,53
I_PCC_L2- on Top Layer "Top Layer-I_PCC_L2-" (solid, remove dead copper, pour order 852): 106.5,211 115,211 116,212 165,212 165,218 124.5,218 123,216.5 106.5,216.5
I_PCC_L3- on Top Layer "TOP_LAYER_I_PCC_L3-_P745" (solid, remove dead copper, pour order 745): 210,184 252,184 252,191 208,191 206,193 192.5,193 192.5,191.5 192.5,193.5 192.5,185.5 194,184
I_PCC_L1- on Top Layer "TOP_LAYER_I_PCC_L1-_P740" (solid, remove dead copper, pour order 740): 50,227 82,227 82,238 84.9,238 84.9,242.6 61.6,242.6 50,231
I_PCC_N- on Top Layer "TOP_LAYER_I_PCC_N-_P733" (solid, remove dead copper, pour order 733): 19 vertices, not listed, extent 1.5,22 33,100.25
GND on Top Layer "Top Layer-GND" (solid, remove dead copper, pour order 1019): 69 vertices, not listed, extent 33.5,0.6 299.9,275.5
GRID_GND on Top Layer "TOP_LAYER_GRID_GND_P866" (solid, remove dead copper, pour order 866): 277,299 277,286 296,286 296,299
GRID_GND_1 on Top Layer "TOP_LAYER_GRID_GND_1_P851" (solid, remove dead copper, pour order 851): 30.5,299.5 30.5,296.6 35.1,292 42,292 44.5,294.5 44.5,299.5
NetMP12_1 on Top Layer "TOP_LAYER_NETMP12_1_P797" (solid, remove dead copper, pour order 797): 187.9,87.3 187.9,97.3 193.9,97.3 193.9,87.3
I_PCC_L3+ on Top Layer "TOP_LAYER_I_PCC_L3+_P839" (solid, remove dead copper, pour order 839): 191.791,193 191.791,185.165 184.791,185.165 184.791,193
GND_S1_GaN_L1 on Top Layer "TOP_LAYER_GND_S1_GAN_L1_P882" (solid, remove dead copper, pour order 882): 43.275,127.6 44.275,127.6 44.275,125.6 41.275,125.6 40.775,126.1 40.775,130.1 42.775,130.1 42.775,128.1
GND_S1_GaN_L3 on Top Layer "TOP_LAYER_GND_S1_GAN_L3_P884" (solid, remove dead copper, pour order 884): 212.775,84.6 213.775,84.6 213.775,82.6 210.775,82.6 210.275,83.1 210.275,87.1 212.275,87.1 212.275,85.1
no net on Top Layer "NONET_L-01_P-001" (solid, pour order 821): 24 vertices, not listed, extent 166.852,12.886 175.9,16.725
no net on Top Layer "TOP_LAYER_NONET_P1007" (solid, remove dead copper, pour order 1007): 164.238,111.558 165.238,111.558 165.238,109.558 162.238,109.558 161.738,110.058 161.738,114.058 163.738,114.058 163.738,112.058
GND_S1_GaN_L2 on Top Layer "TOP_LAYER_GND_S1_GAN_L2_P883" (solid, remove dead copper, pour order 883): 126.775,112.6 127.775,112.6 127.775,110.6 124.775,110.6 124.275,111.1 124.275,115.1 126.275,115.1 126.275,113.1
GND_S3_GaN_N on Top Layer "TOP_LAYER_GND_S3_GAN_N_P1005" (solid, remove dead copper, pour order 1005): 109.942,51.238 109.942,52.238 111.942,52.238 111.942,49.238 111.442,48.738 107.442,48.738 107.442,50.738 109.442,50.738
GND_S1_GaN_N on Top Layer "TOP_LAYER_GND_S1_GAN_N_P881" (solid, remove dead copper, pour order 881): 108.9,13.775 108.9,14.775 110.9,14.775 110.9,11.775 110.4,11.275 106.4,11.275 106.4,13.275 108.4,13.275
GND_S3_GaN_L1 on Top Layer "TOP_LAYER_GND_S3_GAN_L1_P1006" (solid, remove dead copper, pour order 1006): 80.738,126.558 81.738,126.558 81.738,124.558 78.738,124.558 78.238,125.058 78.238,129.058 80.238,129.058 80.238,127.058
GND_S4_GaN_L1 on Top Layer "TOP_LAYER_GND_S4_GAN_L1_P1011" (solid, remove dead copper, pour order 1011): 180.282,111.688 181.282,111.688 181.282,109.688 178.282,109.688 177.782,110.188 177.782,114.188 179.782,114.188 179.782,112.188
no net on Top Layer "TOP_LAYER_NONET_P767" (solid, remove dead copper, pour order 767): 178,112.5 176,112.5 176,115.5 178,115.5 178,116 179.5,116 179.5,114.5 181,113 181.5,113 181.5,111.5 178,111.5
GND_S4_GaN_L1 on Top Layer "TOP_LAYER_GND_S4_GAN_L1_P1010" (solid, remove dead copper, pour order 1010): 96.782,126.688 97.782,126.688 97.782,124.688 94.782,124.688 94.282,125.188 94.282,129.188 96.282,129.188 96.282,127.188
no net on Top Layer "TOP_LAYER_NONET_P766" (solid, remove dead copper, pour order 766): 94.5,127.5 92.5,127.5 92.5,130.5 94.5,130.5 94.5,131 96,131 96,129.5 97.5,128 98,128 98,126.5 94.5,126.5
5V_S4_GaN_L1 on Top Layer "TOP_LAYER_5V_S4_GAN_L1_P770" (solid, remove dead copper, pour order 770): 97.5,130.5 101.5,130.5 101.5,126.5 98.5,126.5 98.5,128 98,128.5 97.5,128.5
no net on Top Layer "TOP_LAYER_NONET_P774" (solid, remove dead copper, pour order 774): 80,128 81,128 81,126.5 77.5,126.5 77.5,128.5 76,128.5 76,130.5 77.5,130.5 78,131 79,131 79,129 80,129
5V_S3_GaN_L1 on Top Layer "TOP_LAYER_5V_S3_GAN_L1_P778" (solid, remove dead copper, pour order 778): 81.5,126.5 81.5,128 81,128.5 81,130.5 83.5,130.5 83.5,126.5
GND on Top Layer "TOP_LAYER_GND_P784" (solid, remove dead copper, pour order 784): 96.938,116.474 101.938,116.474 101.938,113.674 101.038,112.774 97.438,112.774 97.138,113.074 97.138,114.274 96.938,114.474
GND_S1_GaN_L1 on Top Layer "TOP_LAYER_GND_S1_GAN_L1_P902" (solid, remove dead copper, pour order 902): 48.5,158 45,158 45,163.5 49.5,168 51,169.5 51,171.5 61,171.5 61,169 55.5,169 50,163.5 50,159.5
NetD8_L1_2 on Top Layer "TOP_LAYER_NETD8_L1_2_P938" (solid, remove dead copper, pour order 938): 33.975,146 39.005,146 39.005,142.5 33.975,142.5
NetD8_L1_1 on Top Layer "TOP_LAYER_NETD8_L1_1_P942" (solid, remove dead copper, pour order 942): 39.025,150 33.995,150 33.995,153.5 39.025,153.5
NetD7_L1_2 on Top Layer "TOP_LAYER_NETD7_L1_2_P946" (solid, remove dead copper, pour order 946): 39.025,157 33.995,157 33.995,160.5 39.025,160.5
VDC+ on Top Layer "TOP_LAYER_VDC+_P950" (solid, remove dead copper, pour order 950): 39.025,163.5 33.995,163.5 33.995,167 39.025,167
GND_S4_GaN_L1 on Top Layer "TOP_LAYER_GND_S4_GAN_L1_P982" (solid, remove dead copper, pour order 982): 85.5,181 85.5,170 91,170 92,169 96.5,169 96.5,180 95.5,181 88.5,181
NetD13_L1_1 on Top Layer "TOP_LAYER_NETD13_L1_1_P986" (solid, remove dead copper, pour order 986): 92.5,151 96.5,151 96.5,148.5 92.5,148.5
NetD14_L1_1 on Top Layer "TOP_LAYER_NETD14_L1_1_P994" (solid, remove dead copper, pour order 994): 92.475,165.625 96.5,165.625 96.5,162.125 92.475,162.125
NetD13_L1_2 on Top Layer "TOP_LAYER_NETD13_L1_2_P998" (solid, remove dead copper, pour order 998): 92.475,158.125 96.5,158.125 96.5,154.625 92.475,154.625
GND_S2_GaN_L1 on Top Layer "TOP_LAYER_GND_S2_GAN_L1_P1014" (solid, remove dead copper, pour order 1014): 58.853,127.35 59.853,127.35 59.853,125.35 56.853,125.35 56.353,125.85 56.353,129.85 58.353,129.85 58.353,127.85
no net on Top Layer "TOP_LAYER_NONET_P768" (solid, remove dead copper, pour order 768): 264,84.5 262,84.5 262,87.5 264,87.5 264,88 265.5,88 265.5,86.5 267,85 267.5,85 267.5,83.5 264,83.5
5V_S4_GaN_L3 on Top Layer "TOP_LAYER_5V_S4_GAN_L3_P772" (solid, remove dead copper, pour order 772): 267,87.5 271,87.5 271,83.5 268,83.5 268,85 267.5,85.5 267,85.5
no net on Top Layer "TOP_LAYER_NONET_P776" (solid, remove dead copper, pour order 776): 249.5,85 250.5,85 250.5,83.5 247,83.5 247,85.5 245.5,85.5 245.5,87.5 247,87.5 247.5,88 248.5,88 248.5,86 249.5,86
5V_S3_GaN_L3 on Top Layer "TOP_LAYER_5V_S3_GAN_L3_P780" (solid, remove dead copper, pour order 780): 251,83.5 251,85 250.5,85.5 250.5,87.5 253,87.5 253,83.5
GND on Top Layer "TOP_LAYER_GND_P786" (solid, remove dead copper, pour order 786): 266.5,75.3 271.5,75.3 271.5,72.5 270.6,71.6 267,71.6 266.7,71.9 266.7,73.1 266.5,73.3
GND_S1_GaN_L3 on Top Layer "TOP_LAYER_GND_S1_GAN_L3_P904" (solid, remove dead copper, pour order 904): 218,115 214.5,115 214.5,120.5 219,125 220.5,126.5 220.5,128.5 230.5,128.5 230.5,126 225,126 219.5,120.5 219.5,116.5
NetD8_L3_2 on Top Layer "TOP_LAYER_NETD8_L3_2_P940" (solid, remove dead copper, pour order 940): 203.475,103 208.505,103 208.505,99.5 203.475,99.5
NetD8_L3_1 on Top Layer "TOP_LAYER_NETD8_L3_1_P944" (solid, remove dead copper, pour order 944): 208.525,107 203.495,107 203.495,110.5 208.525,110.5
NetD7_L3_2 on Top Layer "TOP_LAYER_NETD7_L3_2_P948" (solid, remove dead copper, pour order 948): 208.525,114 203.495,114 203.495,117.5 208.525,117.5
VDC+ on Top Layer "TOP_LAYER_VDC+_P952" (solid, remove dead copper, pour order 952): 208.525,120.5 203.495,120.5 203.495,124 208.525,124
GND_S4_GaN_L1 on Top Layer "TOP_LAYER_GND_S4_GAN_L1_P984" (solid, remove dead copper, pour order 984): 255,138 255,127 260.5,127 261.5,126 266,126 266,137 265,138 258,138
NetD13_L3_1 on Top Layer "TOP_LAYER_NETD13_L3_1_P988" (solid, remove dead copper, pour order 988): 262,108 266,108 266,105.5 262,105.5
NetD14_L3_1 on Top Layer "TOP_LAYER_NETD14_L3_1_P996" (solid, remove dead copper, pour order 996): 261.975,122.625 266,122.625 266,119.125 261.975,119.125
NetD13_L3_2 on Top Layer "TOP_LAYER_NETD13_L3_2_P1000" (solid, remove dead copper, pour order 1000): 261.975,115.125 266,115.125 266,111.625 261.975,111.625
GND_S3_GaN_L3 on Top Layer "TOP_LAYER_GND_S3_GAN_L3_P1008" (solid, remove dead copper, pour order 1008): 250.238,83.558 251.238,83.558 251.238,81.558 248.238,81.558 247.738,82.058 247.738,86.058 249.738,86.058 249.738,84.058
GND_S4_GaN_L1 on Top Layer "TOP_LAYER_GND_S4_GAN_L1_P1012" (solid, remove dead copper, pour order 1012): 266.282,83.688 267.282,83.688 267.282,81.688 264.282,81.688 263.782,82.188 263.782,86.188 265.782,86.188 265.782,84.188
GND_S2_GaN_L3 on Top Layer "TOP_LAYER_GND_S2_GAN_L3_P1016" (solid, remove dead copper, pour order 1016): 228.353,84.35 229.353,84.35 229.353,82.35 226.353,82.35 225.853,82.85 225.853,86.85 227.853,86.85 227.853,84.85
GND_S2_GaN_L2 on Top Layer "TOP_LAYER_GND_S2_GAN_L2_P1015" (solid, remove dead copper, pour order 1015): 142.353,112.35 143.353,112.35 143.353,110.35 140.353,110.35 139.853,110.85 139.853,114.85 141.853,114.85 141.853,112.85
NetD13_L2_2 on Top Layer "TOP_LAYER_NETD13_L2_2_P999" (solid, remove dead copper, pour order 999): 175.975,143.125 180,143.125 180,139.625 175.975,139.625
NetD14_L2_1 on Top Layer "TOP_LAYER_NETD14_L2_1_P995" (solid, remove dead copper, pour order 995): 175.975,150.625 180,150.625 180,147.125 175.975,147.125
NetD13_L2_1 on Top Layer "TOP_LAYER_NETD13_L2_1_P987" (solid, remove dead copper, pour order 987): 176,136 180,136 180,133.5 176,133.5
GND_S4_GaN_L1 on Top Layer "TOP_LAYER_GND_S4_GAN_L1_P983" (solid, remove dead copper, pour order 983): 169,166 169,155 174.5,155 175.5,154 180,154 180,165 179,166 172,166
VDC+ on Top Layer "TOP_LAYER_VDC+_P951" (solid, remove dead copper, pour order 951): 122.525,148.5 117.495,148.5 117.495,152 122.525,152
NetD7_L2_2 on Top Layer "TOP_LAYER_NETD7_L2_2_P947" (solid, remove dead copper, pour order 947): 122.525,142 117.495,142 117.495,145.5 122.525,145.5
NetD8_L2_1 on Top Layer "TOP_LAYER_NETD8_L2_1_P943" (solid, remove dead copper, pour order 943): 122.525,135 117.495,135 117.495,138.5 122.525,138.5
NetD8_L2_2 on Top Layer "TOP_LAYER_NETD8_L2_2_P939" (solid, remove dead copper, pour order 939): 117.475,131 122.505,131 122.505,127.5 117.475,127.5
GND_S1_GaN_L2 on Top Layer "TOP_LAYER_GND_S1_GAN_L2_P903" (solid, remove dead copper, pour order 903): 132,143 128.5,143 128.5,148.5 133,153 134.5,154.5 134.5,156.5 144.7,156.5 144.7,154 139,154 133.5,148.5 133.5,144.5
GND on Top Layer "TOP_LAYER_GND_P785" (solid, remove dead copper, pour order 785): 180.5,103.3 185.5,103.3 185.5,100.5 184.6,99.6 181,99.6 180.7,99.9 180.7,101.1 180.5,101.3
5V_S3_GaN_L2 on Top Layer "TOP_LAYER_5V_S3_GAN_L2_P779" (solid, remove dead copper, pour order 779): 165,111.5 165,113 164.5,113.5 164.5,115.5 167,115.5 167,111.5
GND_S3_GaN_L2 on Top Layer "TOP_LAYER_GND_S3_GAN_L2_P775" (solid, remove dead copper, pour order 775): 164.75,111 165.75,111 165.75,109.5 162.25,109.5 162.25,111.5 160.75,111.5 160.75,113.5 162.25,113.5 162.75,114 163.75,114 163.75,112 164.75,112
5V_S4_GaN_L2 on Top Layer "TOP_LAYER_5V_S4_GAN_L2_P771" (solid, remove dead copper, pour order 771): 181,115.5 185,115.5 185,111.5 182,111.5 182,113 181.5,113.5 181,113.5
+5VISO_PCC on Top Layer "NONET_L-01_P-001" (solid, pour order 812): 103.009,266.3 139.6,266.3 140.1,265.8 140.1,259.826 139.774,259.5 103.5,259.5 102.6,260.4 102.6,265.891
GND on Top Layer "NONET_L-01_P-001" (solid, pour order 834): 145.8,17.4 147,17.4 147.4,17 148.3,17 148.7,17.4 149.4,17.4 150,16.8 153.425,16.8 153.7,16.525 153.7,15.9 145.912,15.9 145.6,16.212 145.6,17.2
GND_S2_GaN_N on Top Layer "TOP_LAYER_GND_S2_GAN_N_P1013" (solid, remove dead copper, pour order 1013): 109.15,29.353 109.15,30.353 111.15,30.353 111.15,27.353 110.65,26.853 106.65,26.853 106.65,28.853 108.65,28.853
GND_S4_GaN_L1 on Top Layer "TOP_LAYER_GND_S4_GAN_L1_P1009" (solid, remove dead copper, pour order 1009): 109.812,67.282 109.812,68.282 111.812,68.282 111.812,65.282 111.312,64.782 107.312,64.782 107.312,66.782 109.312,66.782
NetD13_N_2 on Top Layer "TOP_LAYER_NETD13_N_2_P997" (solid, remove dead copper, pour order 997): 78.375,62.975 78.375,67 81.875,67 81.875,62.975
NetD14_N_1 on Top Layer "TOP_LAYER_NETD14_N_1_P993" (solid, remove dead copper, pour order 993): 70.875,62.975 70.875,67 74.375,67 74.375,62.975
NetD13_N_1 on Top Layer "TOP_LAYER_NETD13_N_1_P985" (solid, remove dead copper, pour order 985): 85.5,63 85.5,67 88,67 88,63
GND_S4_GaN_L1 on Top Layer "TOP_LAYER_GND_S4_GAN_L1_P981" (solid, remove dead copper, pour order 981): 55.5,56 66.5,56 66.5,61.5 67.5,62.5 67.5,67 56.5,67 55.5,66 55.5,59
VDC+ on Top Layer "TOP_LAYER_VDC+_P949" (solid, remove dead copper, pour order 949): 73,9.525 73,4.495 69.5,4.495 69.5,9.525
NetD7_N_2 on Top Layer "TOP_LAYER_NETD7_N_2_P945" (solid, remove dead copper, pour order 945): 79.5,9.525 79.5,4.495 76,4.495 76,9.525
NetD8_N_1 on Top Layer "TOP_LAYER_NETD8_N_1_P941" (solid, remove dead copper, pour order 941): 86.5,9.525 86.5,4.495 83,4.495 83,9.525
NetD8_N_2 on Top Layer "TOP_LAYER_NETD8_N_2_P937" (solid, remove dead copper, pour order 937): 90.5,4.475 90.5,9.505 94,9.505 94,4.475
GND_S1_GaN_N on Top Layer "TOP_LAYER_GND_S1_GAN_N_P901" (solid, remove dead copper, pour order 901): 78.5,19 78.5,15.5 73,15.5 68.5,20 65,23.5 65,31.4 67.5,31.4 67.5,26 73,20.5 77,20.5
no net on Top Layer "TOP_LAYER_NONET_P765" (solid, remove dead copper, pour order 765): 109,65 109,63 106,63 106,65 105.5,65 105.5,66.5 107,66.5 108.5,68 108.5,68.5 110,68.5 110,65
5V_S4_GaN_N on Top Layer "TOP_LAYER_5V_S4_GAN_N_P769" (solid, remove dead copper, pour order 769): 106,68 106,72 110,72 110,69 108.5,69 108,68.5 108,68
GND on Top Layer "TOP_LAYER_GND_P783" (solid, remove dead copper, pour order 783): 120.335,67.806 120.335,72.806 123.135,72.806 124.035,71.906 124.035,68.306 123.735,68.006 122.535,68.006 122.335,67.806
NetF3_1 on Top Layer "TOP_LAYER_NETF3_1_P755" (solid, remove dead copper, pour order 755): 218.5,227.5 222.5,231.5 225,231.5 226.5,233 226.5,251 223,254.5 223,268 221,270 210.5,270 208,267.5 208,254.5 210.5,252 210.5,227.5
NetL12_2 on Top Layer "TOP_LAYER_NETL12_2_P871" (solid, remove dead copper, pour order 871): 221,226.5 232,226.5 232,234 237,234 237,222 221,222
NetL12_4 on Top Layer "TOP_LAYER_NETL12_4_P870" (solid, remove dead copper, pour order 870): 263,233 259,237 261,239 264,236 267,233 271,229 271,227 264,220 260,220 260,224 263,227
GND_S4_GaN_L1 on Top Layer "NONET_L-01_P-001" (solid, pour order 838): 95.1,93.9 97.7,93.9 97.9,93.7 97.9,90.6 97.642,90.342 95.658,90.342 95.4,90.6 95.4,91.8 94.9,92.3 94.9,93.7
GND on Top Layer "NONET_L-01_P-001" (solid, pour order 837): 92.3,105.9 93.8,105.9 94.2,106.3 94.2,107.7 95.243,107.7 95.5,107.443 95.5,104.2 96,103.7 96,102.2 95.8,102 92.2,102 91.7,102.5 91.7,105.3
GND on Top Layer "NONET_L-01_P-001" (solid, pour order 836): 204.9,6.2 204.943,6.243 206.187,6.243 206.187,4.856 206.7,4.343 206.7,4 206.6,3.9 205,3.9 204.9,4
GND on Top Layer "NONET_L-01_P-001" (solid, pour order 835): 153.6,25.4 163.4,25.4 163.8,25 164.8,25 164.8,23.8 164.5,23.5 153.6,23.5
5V on Top Layer "NONET_L-01_P-001" (solid, pour order 830): 160.708,21.1 163.2,21.1 163.3,21 163.3,16.6 162.8,16.1 157.6,16.1 157.3,16.4 157.3,17.8 158,18.5 160.1,18.5 160.4,18.8 160.4,20.792
5V on Top Layer "NONET_L-01_P-001" (solid, pour order 829): 153.9,28.4 164.6,28.4 165.2,27.8 165.2,25.8 165,25.6 164.1,25.6 164.1,25.952 163.852,26.2 153.4,26.2 153.2,26.4 153.2,27.7
3V3 on Top Layer "NONET_L-01_P-001" (solid, pour order 827): 149.3,22 149.6,21.7 149.6,18.649 148.273,17.322 147.738,17.322 147.152,17.908 145.144,17.908 144.909,18.143 144.909,21.009 145.9,22
no net on Top Layer "NONET_L-01_P-001" (solid, pour order 822): 179.8,17 181.721,17 182.2,16.521 182.2,16 182.1,15.9 179.4,15.9 179.3,16 179.3,16.5
no net on Top Layer "NONET_L-01_P-001" (solid, pour order 820): 174.8,8.9 175.1,8.6 175.1,7.6 174.9,7.4 170.6,7.4 170.2,7.8 170.2,8.9
no net on Top Layer "NONET_L-01_P-001" (solid, pour order 819): 200.2,12.8 200.3,12.9 203,12.9 203.4,12.5 203.4,1.7 202.4,0.7 200.9,0.7 200.2,1.4 200.2,12.8
FAN_SN on Top Layer "NONET_L-01_P-001" (solid, pour order 817): 41 vertices, not listed, extent 205,0.2 247.8,4.7
DCDC_VIN on Top Layer "NONET_L-01_P-001" (solid, pour order 816): 166.9,25.1 171.8,25.1 173.8,27.1 175.1,27.1 175.2,27 175.2,23.7 175,23.5 171.764,23.5 171.064,24.2 166.9,24.2
12V_FET_DRAIN on Top Layer "NONET_L-01_P-001" (solid, pour order 815): 166.5,15.1 166.5,12.2 168.5,10.2 169.1,10.2 169.1,9.65 169.087,9.636 169.087,9.187 169,9.1 168.2,9.1 165.5,11.8 165.5,15.1
VIN_PWR on Top Layer "NONET_L-01_P-001" (solid, pour order 814): 18 vertices, not listed, extent 175.7,8.9 184,15
AUX_IN_PWR on Top Layer "NONET_L-01_P-001" (solid, pour order 813): 191.3,12.6 191.7,12.2 191.7,3.6 191.3,3.2 186.3,3.2 185.2,4.3 185.2,11.4 186.4,12.6 185.2,11.4 186.4,12.6
V_PCC_N on Top Layer "NONET_L-01_P-001" (solid, pour order 810): 136.925,260.734 139.35,260.734 139.564,260.52 139.564,259.183 131.276,259.183 130.825,259.634 130.825,260.734 130.927,260.837 132.978,260.837 132.978,259.881 133.111,259.748 136.488,259.748 136.9,260.159 136.897,260.161 136.897,260.73
V_PCC_N on Top Layer "NONET_L-01_P-001" (solid, pour order 809): 122.863,260.603 125.288,260.603 125.876,260.015 125.876,259.051 117.214,259.051 116.763,259.503 116.763,260.603 116.866,260.705 118.917,260.705 118.917,259.749 119.05,259.616 122.427,259.616 122.838,260.028 122.836,260.03 122.836,260.599
NetC75_1 on Top Layer "NONET_L-01_P-001" (solid, pour order 807): 99.608,263.371 101.821,263.371 101.977,263.215 101.977,260.277 101.7,260 99.5,260 99.397,260.103 99.397,263.371
V_PCC_N on Top Layer "NONET_L-01_P-001" (solid, pour order 806): 17 vertices, not listed, extent 105.4,259.149 114.175,260.803
V_PCC_N on Top Layer "NONET_L-01_P-001" (solid, pour order 804): 131.121,263.162 132.84,263.162 132.981,263.021 132.981,260.422 132.721,260.162 131.021,260.162 130.821,260.362 130.821,262.862
V_PCC_N on Top Layer "NONET_L-01_P-001" (solid, pour order 803): 117.059,263.098 118.778,263.098 118.919,262.957 118.919,260.358 118.659,260.098 116.959,260.098 116.759,260.298 116.759,262.798
V_PCC_N on Top Layer "NONET_L-01_P-001" (solid, pour order 802): 105.7,263.2 107.419,263.2 107.56,263.059 107.56,260.46 107.3,260.2 105.6,260.2 105.4,260.4 105.4,262.9
V_PCC_N on Top Layer "NONET_L-01_P-001" (solid, pour order 801): 95.4,263.8 98.7,263.8 98.8,263.7 98.8,262 99.2,261.6 99.2,260.1 99.1,260 95.5,260 95.4,260.1
CAN_GND2 on Top Layer "NONET_L-01_P-001" (solid, pour order 798): 277.8,22.9 278,23.1 282.2,23.1 282.5,22.8 282.5,19.5 282.1,19.1 277.8,19.1 277.2,19.7 277.2,22.3
GND on Top Layer "TOP_LAYER_GND_P795" (solid, remove dead copper, pour order 795): 98,252 101.5,252 101.5,246 99,246 99,249 98,250
NetF2_1 on Top Layer "TOP_LAYER_NETF2_1_P794" (solid, remove dead copper, pour order 794): 230.5,264 230.5,271 241,271 241,264
5V_S3_GaN_N on Top Layer "TOP_LAYER_5V_S3_GAN_N_P777" (solid, remove dead copper, pour order 777): 110,52 108.5,52 108,51.5 106,51.5 106,54 110,54
PCC_N on Top Layer "TOP_LAYER_PCC_N_P764" (solid, remove dead copper, pour order 764): 263.5,293 271,293 271,270.5 263.5,270.5
PCC_L1 on Top Layer "TOP_LAYER_PCC_L1_P763" (solid, remove dead copper, pour order 763): 243.5,292.5 255,292.5 255,276.5 243.5,276.5
PCC_L2 on Top Layer "TOP_LAYER_PCC_L2_P762" (solid, remove dead copper, pour order 762): 223.5,292.5 230.5,292.5 230.5,284 232,282.5 235.5,282.5 235.5,277 225.5,277 223.5,279
PCC_L3 on Top Layer "TOP_LAYER_PCC_L3_P761" (solid, remove dead copper, pour order 761): 219,283 219,277 204.5,277 203,278.5 203,292.5 211,292.5 211,283
NetF4_1 on Top Layer "TOP_LAYER_NETF4_1_P760" (solid, remove dead copper, pour order 760): 286.5,278 287,277.5 287,271.5 283,267.5 283,263.5 281,261.5 274,261.5 274,278
NetF1_1 on Top Layer "TOP_LAYER_NETF1_1_P756" (solid, remove dead copper, pour order 756): 17 vertices, not listed, extent 240,221 256.5,270.5
I_PCC_L2+ on Top Layer "TOP_LAYER_I_PCC_L2+_P742" (solid, remove dead copper, pour order 742): 106,217 106,209 99,209 99,217
I_PCC_N+ on Top Layer "TOP_LAYER_I_PCC_N+_P734" (solid, remove dead copper, pour order 734): 21 vertices, not listed, extent 0,95.039 29.5,278
I_PCC_L3+ on Layer 1 "LAYER_1_I_PCC_L3+_P872" (solid, remove dead copper, pour order 872): 63.5,275 63.5,281.5 44.5,281.5 33,270 33,235 49.5,235 50.5,236 50.5,241 50,241.5 39.5,241.5 38.5,242.5 38.5,261.5 52,275
NetL12_2 on Layer 1 "LAYER_1_NETL12_2_P754" (solid, remove dead copper, pour order 754): 190,270 191,269 202,269 237,234 237,221.5 220.5,221.5 220.5,240.1 206.05,254.55 198,254.5 189.5,263 172.5,263 172.412,263.165 172.412,269.912 172.5,270
NetL12_4 on Layer 1 "LAYER_1_NETL12_4_P753" (solid, remove dead copper, pour order 753): 18 vertices, not listed, extent 172,216.5 272.25,285
V_PCC_L1 on Layer 1 "Layer 1-V_PCC_L1" (solid, remove dead copper, pour order 749): 31 vertices, not listed, extent 41,239 179,299
VDC+ on Layer 1 "Layer 1-VDC+" (solid, pour order 849): 59 vertices, not listed, extent 1,9 270,297
GND on Layer 1 "Layer 1-GND" (solid, pour order 1022): 62 vertices, not listed, extent 33.85,0.6 299.9,275.5
GND_S1_GaN_L1 on Layer 1 "LAYER_1_GND_S1_GAN_L1_P874" (solid, remove dead copper, pour order 874): 26 vertices, not listed, extent 33,125.5 63,171.5
GND_S1_GaN_L2 on Layer 1 "LAYER_1_GND_S1_GAN_L2_P875" (solid, remove dead copper, pour order 875): 26 vertices, not listed, extent 116.5,110.5 146.5,156.5
GND_S1_GaN_N on Layer 1 "LAYER_1_GND_S1_GAN_N_P873" (solid, remove dead copper, pour order 873): 26 vertices, not listed, extent 65,3.5 111,33.5
GND_S2_GaN_L3 on Layer 1 "LAYER_1_GND_S2_GAN_L3_P1085" (solid, remove dead copper, pour order 1085): 21 vertices, not listed, extent 219.019,82.519 237.019,107.519
GND_S2_GaN_L2 on Layer 1 "LAYER_1_GND_S2_GAN_L2_P1084" (solid, remove dead copper, pour order 1084): 21 vertices, not listed, extent 133,110.5 151,135.5
GND_S2_GaN_L1 on Layer 1 "LAYER_1_GND_S2_GAN_L1_P1083" (solid, remove dead copper, pour order 1083): 21 vertices, not listed, extent 49.5,125.5 67.5,150.5
GND_S3_GaN_L1 on Layer 1 "LAYER_1_GND_S3_GAN_L1_P1081" (solid, remove dead copper, pour order 1081): 25 vertices, not listed, extent 65.5,124 86.5,150.5
GND_S3_GaN_L2 on Layer 1 "LAYER_1_GND_S3_GAN_L2_P1080" (solid, remove dead copper, pour order 1080): 25 vertices, not listed, extent 149,108.966 170,135.466
GND_S3_GaN_L3 on Layer 1 "LAYER_1_GND_S3_GAN_L3_P1079" (solid, remove dead copper, pour order 1079): 25 vertices, not listed, extent 235,80.931 256,107.431
GND_S4_GaN_L1 on Layer 1 "LAYER_1_GND_S4_GAN_L1_P1076" (solid, remove dead copper, pour order 1076): 25 vertices, not listed, extent 77,124 101.5,170.5
GND_S4_GaN_L1 on Layer 1 "LAYER_1_GND_S4_GAN_L1_P1075" (solid, remove dead copper, pour order 1075): 25 vertices, not listed, extent 160.5,109 185,155.5
GND_S4_GaN_L1 on Layer 1 "LAYER_1_GND_S4_GAN_L1_P1074" (solid, remove dead copper, pour order 1074): 25 vertices, not listed, extent 246.5,81 271,127.5
GND_S4_GaN_L1 on Layer 1 "LAYER_1_GND_S4_GAN_L1_P889" (solid, remove dead copper, pour order 889): 25 vertices, not listed, extent 66,47.5 112.5,72
GND_S1_GaN_L3 on Layer 1 "LAYER_1_GND_S1_GAN_L3_P876" (solid, remove dead copper, pour order 876): 26 vertices, not listed, extent 202.5,82.5 232.5,128.5
GND_S1_GaN_L1 on Layer 1 "LAYER_1_GND_S1_GAN_L1_P970" (solid, remove dead copper, pour order 970): 46,159.5 46,168 50,172 58.5,172 59,171.5 59,169.5 58,168.5 51.5,168.5 49.5,166.5 49.5,159.5
GND_S3_GaN_L1 on Layer 1 "LAYER_1_GND_S3_GAN_L1_P1002" (solid, remove dead copper, pour order 1002): 72.5,162 87,162 87,148 84.5,148 81,151.5 77.5,151.5 77.5,155 76,155 73,158 72.5,158
GND_S1_GaN_L3 on Layer 1 "LAYER_1_GND_S1_GAN_L3_P972" (solid, remove dead copper, pour order 972): 215.5,116.5 215.5,125 219.5,129 228,129 228.5,128.5 228.5,126.5 227.5,125.5 221,125.5 219,123.5 219,116.5
GND_S3_GaN_L3 on Layer 1 "LAYER_1_GND_S3_GAN_L3_P1004" (solid, remove dead copper, pour order 1004): 242,119 256.5,119 256.5,105 254,105 250.5,108.5 247,108.5 247,112 245.5,112 242.5,115 242,115
GND on Layer 1 "NONET_L-01_P-001" (solid, pour order 818): 168.6,28.1 173.945,28.1 188.745,13.3 202.6,13.3 203.4,12.5 203.4,1.7 202.3,0.6 163.9,0.6 163.1,1.4 163.1,18.6 163.994,19.494 167.136,19.494 167.7,20.058 167.7,27.2
GND_S3_GaN_L2 on Layer 1 "LAYER_1_GND_S3_GAN_L2_P1003" (solid, remove dead copper, pour order 1003): 156,147 170.5,147 170.5,133 168,133 164.5,136.5 161,136.5 161,140 159.5,140 156.5,143 156,143
GND_S1_GaN_L2 on Layer 1 "LAYER_1_GND_S1_GAN_L2_P971" (solid, remove dead copper, pour order 971): 129.5,144.5 129.5,153 133.5,157 142,157 142.5,156.5 142.5,154.5 141.5,153.5 135,153.5 133,151.5 133,144.5
GND_S3_GaN_N on Layer 1 "LAYER_1_GND_S3_GAN_N_P1001" (solid, remove dead copper, pour order 1001): 74.5,43 74.5,57.5 88.5,57.5 88.5,55 85,51.5 85,48 81.5,48 81.5,46.5 78.5,43.5 78.5,43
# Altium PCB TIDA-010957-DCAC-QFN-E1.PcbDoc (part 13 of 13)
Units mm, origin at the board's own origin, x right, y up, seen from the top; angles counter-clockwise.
Board outline 300 x 300 mm, 4 copper layers (Top Layer, Layer 1, Layer 2, Bottom Layer), stack 1.787 mm thick; 1286 components, 677 nets, 4169 pads, 3428 vias.

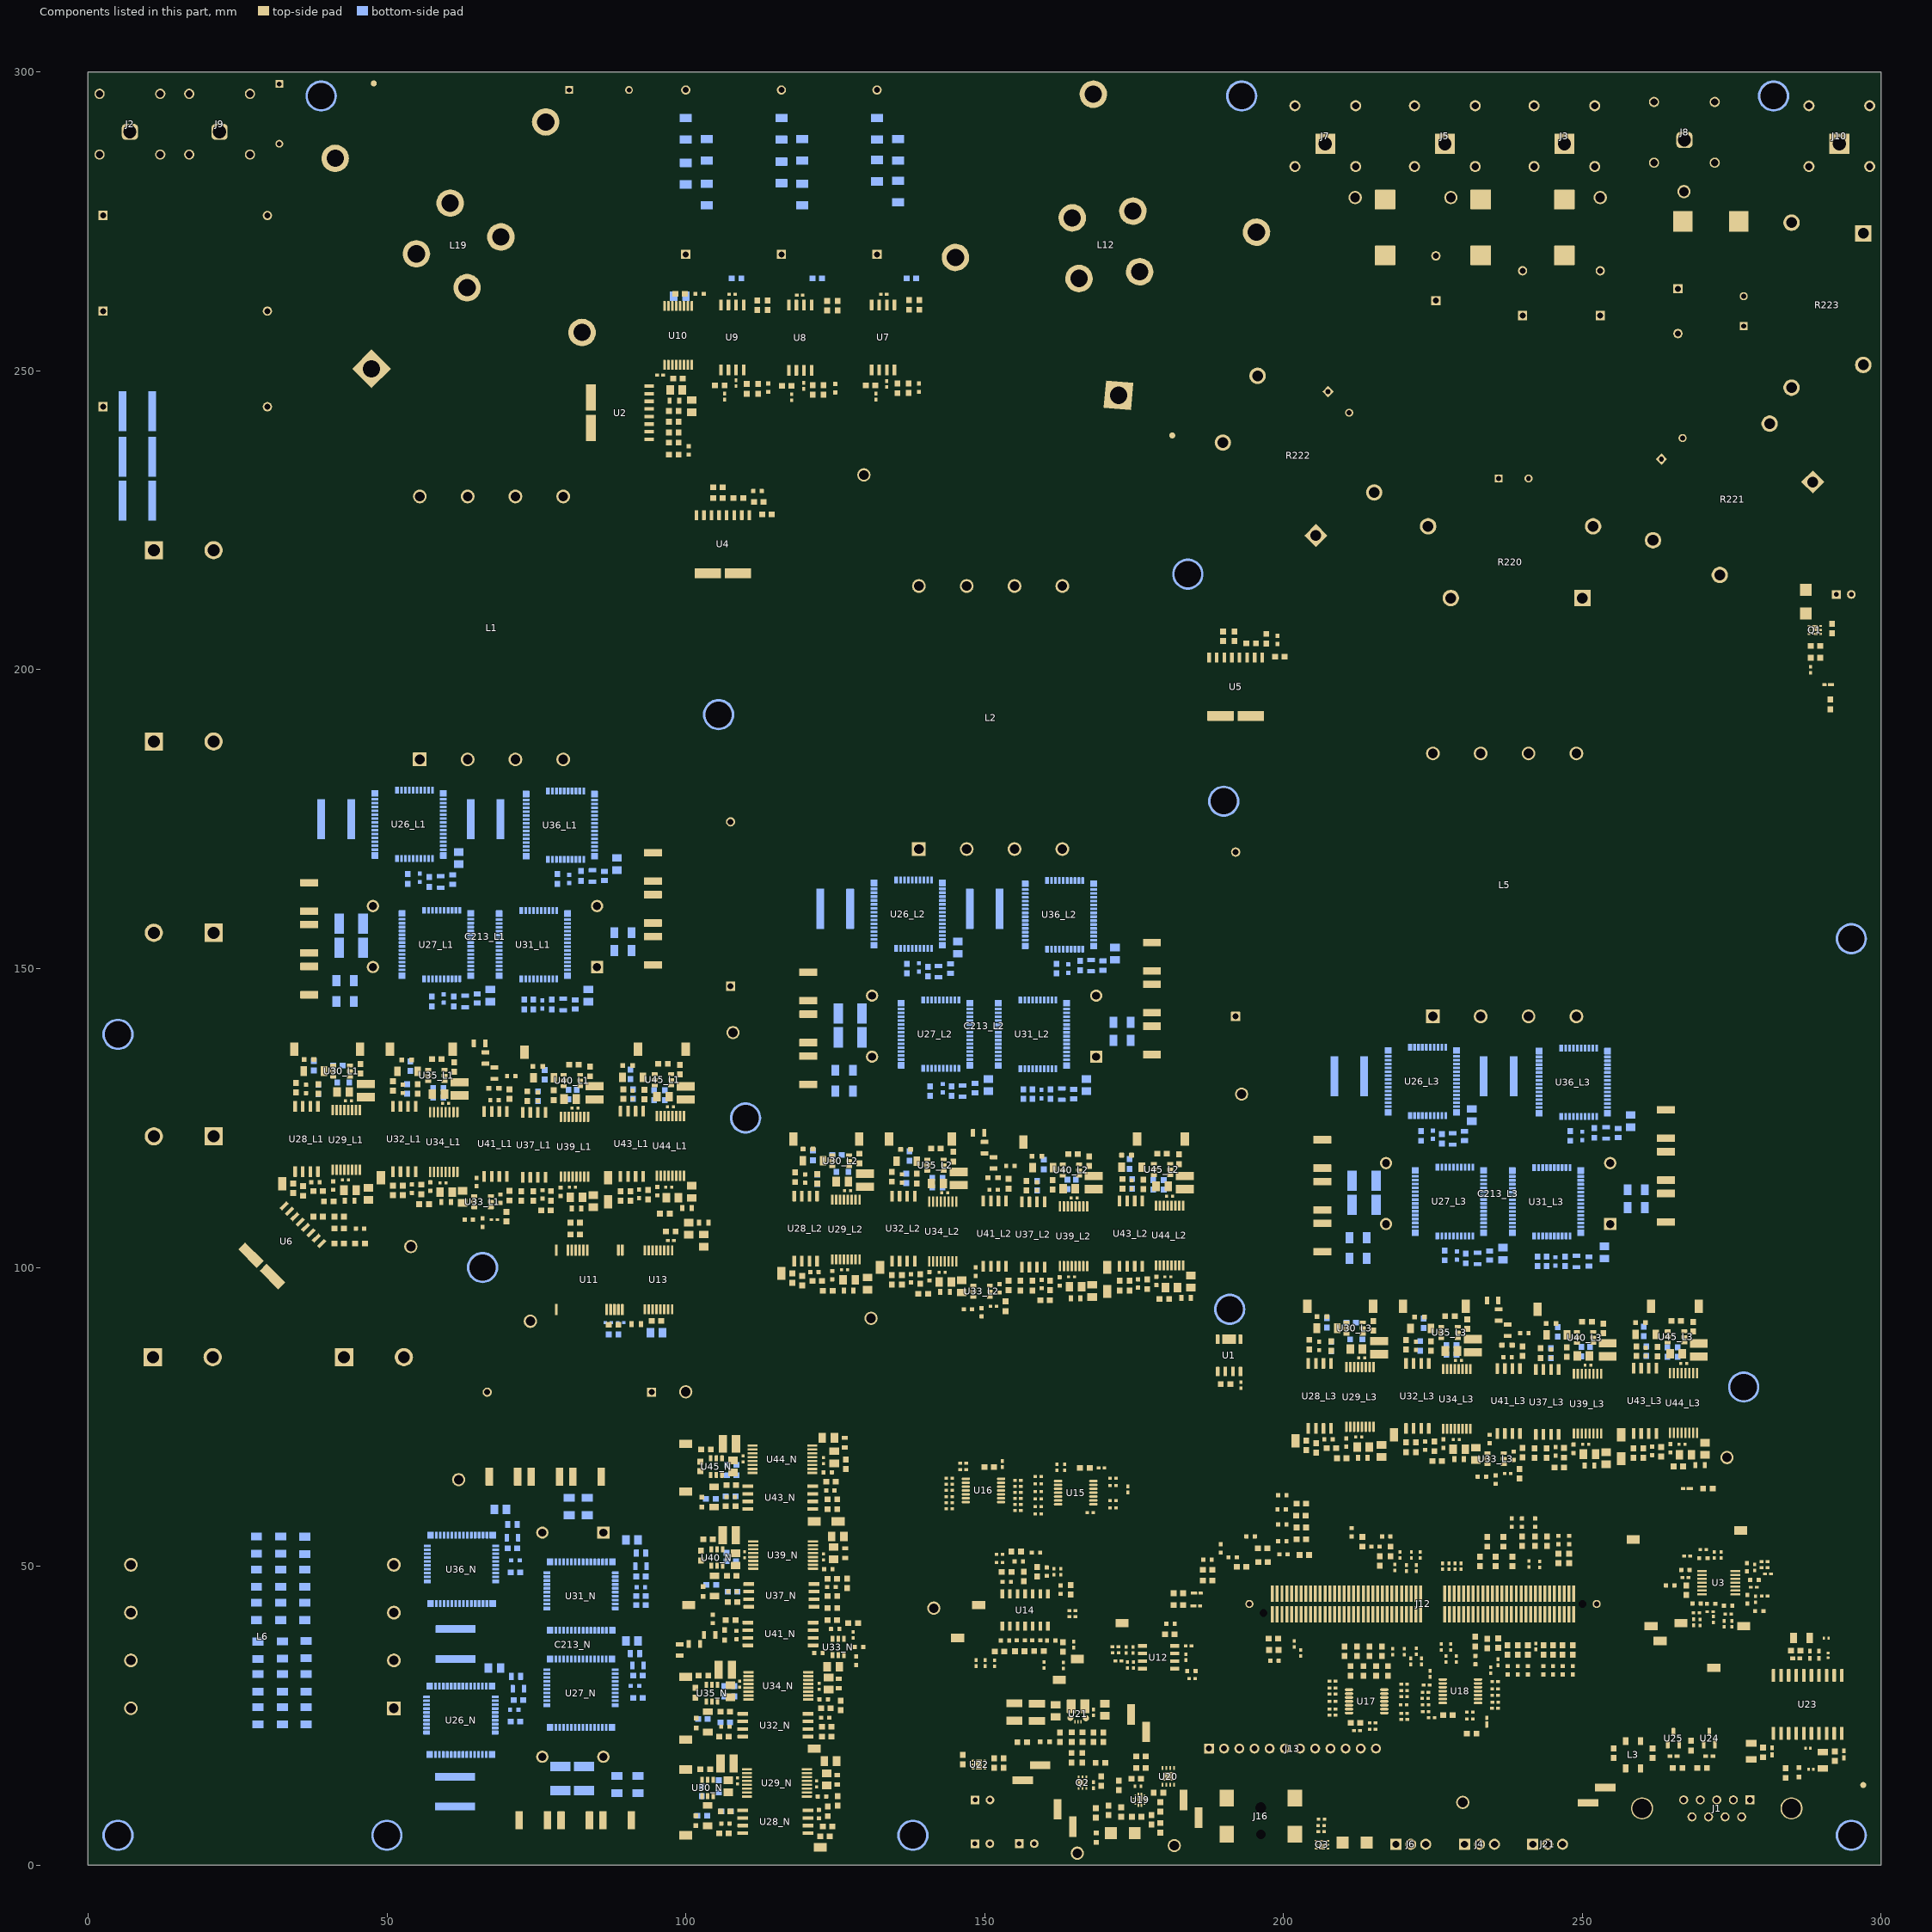
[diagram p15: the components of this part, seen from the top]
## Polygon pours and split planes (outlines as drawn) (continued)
GND_S1_GaN_N on Layer 1 "LAYER_1_GND_S1_GAN_N_P969" (solid, remove dead copper, pour order 969): 77,16.5 68.5,16.5 64.5,20.5 64.5,29 65,29.5 67,29.5 68,28.5 68,22 70,20 77,20
GND_S3_GaN_N on Layer 1 "LAYER_1_GND_S3_GAN_N_P885" (solid, remove dead copper, pour order 885): 25 vertices, not listed, extent 86,36 112.5,57
GND_S2_GaN_N on Layer 1 "LAYER_1_GND_S2_GAN_N_P877" (solid, remove dead copper, pour order 877): 21 vertices, not listed, extent 86,20 111,38
GND_S4_GaN_L1 on Layer 1 "LAYER_1_GND_S4_GAN_L1_P867" (solid, remove dead copper, pour order 867): 84,93 84,80 86,78 98,78 98,94 85,94
PCC_L3 on Layer 1 "LAYER_1_PCC_L3_P861" (solid, remove dead copper, pour order 861): 211,277 204,284 204,292 211,292 211,283 214,280 214,277
PCC_L2 on Layer 1 "LAYER_1_PCC_L2_P859" (solid, remove dead copper, pour order 859): 224,277 224,293 231,293 231,280 231,277 225,277
PCC_L1 on Layer 1 "LAYER_1_PCC_L1_P858" (solid, remove dead copper, pour order 858): 243,277 243,293 251,293 251,282 256,282 256,277
PCC_N on Layer 1 "LAYER_1_PCC_N_P857" (solid, remove dead copper, pour order 857): 263,273 263,293 270,293 270,273
GND_ISO_CAN on Layer 1 "NONET_L-01_P-001" (solid, pour order 833): 293.1,24.2 295.6,21.7 295.6,14.2 286,4.6 254.7,4.6 250.7,8.6 250.7,16.3 258.6,24.2
V_PCC_N on Layer 1 "NONET_L-01_P-001" (solid, pour order 800): 96.8,271.8 139.4,271.8 140.2,271 140.2,259.926 139.674,259.4 95.4,259.4 94.5,260.3 94.5,269.5
CAN_GND2 on Layer 1 "NONET_L-01_P-001" (solid, pour order 799): 278,23.1 282.2,23.1 282.7,22.6 282.7,20.3 285.3,17.7 287.225,17.7 288.2,16.725 288.2,15.7 288.1,15.6 279.1,15.6 277.2,17.5 277.2,22.3
NetF2_1 on Layer 1 "LAYER_1_NETF2_1_P758" (solid, remove dead copper, pour order 758): 230.5,271 249.3,271 249.3,263.2 260.5,252 274,252 283.5,242.5 283.5,238.5 274,238.5 272,240.5 268.5,244 258.5,244 240.9,261.6 230.5,261.6

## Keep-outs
Top Layer:
  region: 36.5,227 94.5,227 94.5,188 36.5,188
  region: 206,184 264,184 264,145 206,145
  region: 120,212 178,212 178,173 120,173
  region: 10,10 10,68 49,68 49,10
Keep-Out Layer:
  text ".Layer_Name" at -20.344,-20.806 h1.52

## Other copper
Top Layer:
  region net GRID_GND_1: 34.965,295.864 ccw(c38.965,295.864) 38.965,291.864 ccw(c38.965,295.864) 42.965,295.864 ccw(c38.965,295.864) 38.965,299.864 ccw(c38.965,295.864)
  region net GRID_GND: 277.965,295.864 ccw(c281.965,295.864) 281.965,291.864 ccw(c281.965,295.864) 285.965,295.864 ccw(c281.965,295.864) 281.965,299.864 ccw(c281.965,295.864)
  region net NetMP12_1: 186.965,92.864 ccw(c190.965,92.864) 190.965,88.864 ccw(c190.965,92.864) 194.965,92.864 ccw(c190.965,92.864) 190.965,96.864 ccw(c190.965,92.864)
  pour cut-out: 102.484,125.265 ccw(c109.784,125.265) 109.784,117.965 ccw(c109.784,125.265) 117.084,125.265 ccw(c109.784,125.265) 109.784,132.565 ccw(c109.784,125.265)
  pour cut-out: 269.787,79.826 ccw(c277.087,79.826) 277.087,72.526 ccw(c277.087,79.826) 284.387,79.826 ccw(c277.087,79.826) 277.087,87.126 ccw(c277.087,79.826)
  pour cut-out: 287.687,154.526 ccw(c294.987,154.526) 294.987,147.226 ccw(c294.987,154.526) 302.287,154.526 ccw(c294.987,154.526) 294.987,161.826 ccw(c294.987,154.526)
  pour cut-out: 185.787,295.826 ccw(c193.087,295.826) 193.087,288.526 ccw(c193.087,295.826) 200.387,295.826 ccw(c193.087,295.826) 193.087,303.126 ccw(c193.087,295.826)
  pour cut-out: 176.787,215.826 ccw(c184.087,215.826) 184.087,208.526 ccw(c184.087,215.826) 191.387,215.826 ccw(c184.087,215.826) 184.087,223.126 ccw(c184.087,215.826)
  pour cut-out: 98.287,192.326 ccw(c105.587,192.326) 105.587,185.026 ccw(c105.587,192.326) 112.887,192.326 ccw(c105.587,192.326) 105.587,199.626 ccw(c105.587,192.326)
  pour cut-out: 182.762,177.641 ccw(c190.062,177.641) 190.062,170.341 ccw(c190.062,177.641) 197.362,177.641 ccw(c190.062,177.641) 190.062,184.941 ccw(c190.062,177.641)
  pour cut-out: 287.787,4.826 ccw(c295.087,4.826) 295.087,-2.474 ccw(c295.087,4.826) 302.387,4.826 ccw(c295.087,4.826) 295.087,12.126 ccw(c295.087,4.826)
  pour cut-out: 58.787,99.826 ccw(c66.087,99.826) 66.087,92.526 ccw(c66.087,99.826) 73.387,99.826 ccw(c66.087,99.826) 66.087,107.126 ccw(c66.087,99.826)
  pour cut-out: -2.213,4.826 ccw(c5.087,4.826) 5.087,-2.474 ccw(c5.087,4.826) 12.387,4.826 ccw(c5.087,4.826) 5.087,12.126 ccw(c5.087,4.826)
  pour cut-out: 42.484,5.265 ccw(c49.784,5.265) 49.784,-2.035 ccw(c49.784,5.265) 57.084,5.265 ccw(c49.784,5.265) 49.784,12.565 ccw(c49.784,5.265)
  pour cut-out: 130.687,4.526 ccw(c137.987,4.526) 137.987,-2.774 ccw(c137.987,4.526) 145.287,4.526 ccw(c137.987,4.526) 137.987,11.826 ccw(c137.987,4.526)
  pour cut-out: -2.994,139.199 ccw(c4.306,139.199) 4.306,131.899 ccw(c4.306,139.199) 11.606,139.199 ccw(c4.306,139.199) 4.306,146.499 ccw(c4.306,139.199)
  pour cut-out: 187.246,190.135 186.958,190.135 186.958,193.081 187.246,193.081
  pour cut-out: 101.456,213.97 101.168,213.97 101.168,217.1 101.456,217.1
  pour cut-out: 188.1,101.5 183.7,101.5 183.7,87.5 187.7,83.5 188.1,83.5
  pour cut-out: 31.444,95.548 31.241,95.752 33.324,97.835 33.527,97.631
  pour cut-out: 24.174,102.083 23.971,102.286 26.342,104.658 26.546,104.454
  pour cut-out: 19,82 22.5,82 24.096,83.596 24.096,86.404 22.5,88 19,88 17.596,86.596 17.596,83.404
  pour cut-out: 81.97,247.754 81.97,248.042 84.916,248.042 84.916,247.754
  pour cut-out: 81.983,237.968 81.983,238.256 84.929,238.256 84.929,237.968
  pour cut-out: 111.232,214.033 110.944,214.033 110.944,216.979 111.232,216.979
  pour cut-out: 197.032,190.158 196.744,190.158 196.744,193.104 197.032,193.104
  pour cut-out: 7.75,217 14.25,217 14.25,223 7.75,223
  pour cut-out: 7.75,185 14.25,185 14.25,191 7.75,191
  pour cut-out: 7.75,153 14.25,153 14.25,159 7.75,159
  pour cut-out: 7.75,118.936 14.25,118.936 14.25,124.936 7.75,124.936
  pour cut-out: 48.334,80.5 57.834,80.5 57.834,89.463 48.334,89.463
  pour cut-out: 16.5,117.436 26,117.436 26,126.399 16.5,126.399
  pour cut-out: 16.5,215.5 26,215.5 26,224.463 16.5,224.463
  pour cut-out: 16.5,183.5 26,183.5 26,192.463 16.5,192.463
  pour cut-out: 18.5,151.5 24,151.5 26,153.5 26,158.5 24.037,160.463 18.463,160.463 16.5,158.5 16.5,153.5
  text ".Layer_Name" at 169.75,-14.25 h1.52
Layer 1:
  pour cut-out: 269.772,79.87 ccw(c277.072,79.87) 277.072,72.57 ccw(c277.072,79.87) 284.372,79.87 ccw(c277.072,79.87) 277.072,87.17 ccw(c277.072,79.87)
  pour cut-out: -3.016,139.284 ccw(c4.284,139.284) 4.284,131.984 ccw(c4.284,139.284) 11.584,139.284 ccw(c4.284,139.284) 4.284,146.584 ccw(c4.284,139.284)
  pour cut-out: 287.74,154.548 ccw(c295.04,154.548) 295.04,147.248 ccw(c295.04,154.548) 302.34,154.548 ccw(c295.04,154.548) 295.04,161.848 ccw(c295.04,154.548)
  pour cut-out: 274.84,295.848 ccw(c282.14,295.848) 282.14,288.548 ccw(c282.14,295.848) 289.44,295.848 ccw(c282.14,295.848) 282.14,303.148 ccw(c282.14,295.848)
  pour cut-out: 185.84,295.848 ccw(c193.14,295.848) 193.14,288.548 ccw(c193.14,295.848) 200.44,295.848 ccw(c193.14,295.848) 193.14,303.148 ccw(c193.14,295.848)
  pour cut-out: 31.884,296.035 ccw(c39.184,296.035) 39.184,288.735 ccw(c39.184,296.035) 46.484,296.035 ccw(c39.184,296.035) 39.184,303.335 ccw(c39.184,296.035)
  pour cut-out: 176.84,215.848 ccw(c184.14,215.848) 184.14,208.548 ccw(c184.14,215.848) 191.44,215.848 ccw(c184.14,215.848) 184.14,223.148 ccw(c184.14,215.848)
  pour cut-out: 287.84,4.848 ccw(c295.14,4.848) 295.14,-2.452 ccw(c295.14,4.848) 302.44,4.848 ccw(c295.14,4.848) 295.14,12.148 ccw(c295.14,4.848)
  pour cut-out: 183.74,93.148 ccw(c191.04,93.148) 191.04,85.848 ccw(c191.04,93.148) 198.34,93.148 ccw(c191.04,93.148) 191.04,100.448 ccw(c191.04,93.148)
  pour cut-out: 58.84,99.848 ccw(c66.14,99.848) 66.14,92.548 ccw(c66.14,99.848) 73.44,99.848 ccw(c66.14,99.848) 66.14,107.148 ccw(c66.14,99.848)
  pour cut-out: -2.16,4.848 ccw(c5.14,4.848) 5.14,-2.452 ccw(c5.14,4.848) 12.44,4.848 ccw(c5.14,4.848) 5.14,12.148 ccw(c5.14,4.848)
  pour cut-out: 42.628,4.73 ccw(c49.928,4.73) 49.928,-2.57 ccw(c49.928,4.73) 57.228,4.73 ccw(c49.928,4.73) 49.928,12.03 ccw(c49.928,4.73)
  pour cut-out: 130.74,4.548 ccw(c138.04,4.548) 138.04,-2.752 ccw(c138.04,4.548) 145.34,4.548 ccw(c138.04,4.548) 138.04,11.848 ccw(c138.04,4.548)
  pour cut-out: 17,283.5 28.5,283.5 28.5,297.5 14.5,297.5 14.5,286
  pour cut-out: 185,175 185,181.5 187,183.5 193.5,183.5 195,182 195,175 193,173 187,173
  pour cut-out: 100.5,189 100.5,196.5 102,198 109,198 110.5,196.5 110.5,189 109,187.5 102,187.5
  pour cut-out: 249.7,260.2 249.7,259.3 252.7,256.3 256.4,256.3 256.5,256.4 249.7,263.2
Layer 2:
  pour cut-out: 269.794,79.856 ccw(c277.094,79.856) 277.094,72.556 ccw(c277.094,79.856) 284.394,79.856 ccw(c277.094,79.856) 277.094,87.156 ccw(c277.094,79.856)
  pour cut-out: -2.99,139.283 ccw(c4.31,139.283) 4.31,131.983 ccw(c4.31,139.283) 11.61,139.283 ccw(c4.31,139.283) 4.31,146.583 ccw(c4.31,139.283)
  pour cut-out: 287.761,154.533 ccw(c295.061,154.533) 295.061,147.233 ccw(c295.061,154.533) 302.361,154.533 ccw(c295.061,154.533) 295.061,161.833 ccw(c295.061,154.533)
  pour cut-out: 274.861,295.833 ccw(c282.161,295.833) 282.161,288.533 ccw(c282.161,295.833) 289.461,295.833 ccw(c282.161,295.833) 282.161,303.133 ccw(c282.161,295.833)
  pour cut-out: 185.861,295.833 ccw(c193.161,295.833) 193.161,288.533 ccw(c193.161,295.833) 200.461,295.833 ccw(c193.161,295.833) 193.161,303.133 ccw(c193.161,295.833)
  pour cut-out: 176.861,215.833 ccw(c184.161,215.833) 184.161,208.533 ccw(c184.161,215.833) 191.461,215.833 ccw(c184.161,215.833) 184.161,223.133 ccw(c184.161,215.833)
  pour cut-out: 287.861,4.833 ccw(c295.161,4.833) 295.161,-2.467 ccw(c295.161,4.833) 302.461,4.833 ccw(c295.161,4.833) 295.161,12.133 ccw(c295.161,4.833)
  pour cut-out: 183.761,93.133 ccw(c191.061,93.133) 191.061,85.833 ccw(c191.061,93.133) 198.361,93.133 ccw(c191.061,93.133) 191.061,100.433 ccw(c191.061,93.133)
  pour cut-out: 58.861,99.833 ccw(c66.161,99.833) 66.161,92.533 ccw(c66.161,99.833) 73.461,99.833 ccw(c66.161,99.833) 66.161,107.133 ccw(c66.161,99.833)
  pour cut-out: -2.139,4.833 ccw(c5.161,4.833) 5.161,-2.467 ccw(c5.161,4.833) 12.461,4.833 ccw(c5.161,4.833) 5.161,12.133 ccw(c5.161,4.833)
  pour cut-out: 42.581,4.986 ccw(c49.881,4.986) 49.881,-2.314 ccw(c49.881,4.986) 57.181,4.986 ccw(c49.881,4.986) 49.881,12.286 ccw(c49.881,4.986)
  pour cut-out: 130.761,4.533 ccw(c138.061,4.533) 138.061,-2.767 ccw(c138.061,4.533) 145.361,4.533 ccw(c138.061,4.533) 138.061,11.833 ccw(c138.061,4.533)
  pour cut-out: 0.5,283.5 11.5,283.5 14,286 14,297.5 0.5,297.5
  pour cut-out: 100.5,189 100.5,196.5 102,198 109,198 110.5,196.5 110.5,189 109,187.5 102,187.5
  pour cut-out: 185,175 185,187.5 205,187.5 205,182.5 195.5,173 187,173
Bottom Layer:
  pour cut-out: 269.787,79.826 ccw(c277.087,79.826) 277.087,72.526 ccw(c277.087,79.826) 284.387,79.826 ccw(c277.087,79.826) 277.087,87.126 ccw(c277.087,79.826)
  pour cut-out: 287.687,154.526 ccw(c294.987,154.526) 294.987,147.226 ccw(c294.987,154.526) 302.287,154.526 ccw(c294.987,154.526) 294.987,161.826 ccw(c294.987,154.526)
  pour cut-out: 185.787,295.826 ccw(c193.087,295.826) 193.087,288.526 ccw(c193.087,295.826) 200.387,295.826 ccw(c193.087,295.826) 193.087,303.126 ccw(c193.087,295.826)
  pour cut-out: 176.787,215.826 ccw(c184.087,215.826) 184.087,208.526 ccw(c184.087,215.826) 191.387,215.826 ccw(c184.087,215.826) 184.087,223.126 ccw(c184.087,215.826)
  pour cut-out: 98.287,192.326 ccw(c105.587,192.326) 105.587,185.026 ccw(c105.587,192.326) 112.887,192.326 ccw(c105.587,192.326) 105.587,199.626 ccw(c105.587,192.326)
  pour cut-out: 182.731,177.657 ccw(c190.031,177.657) 190.031,170.357 ccw(c190.031,177.657) 197.331,177.657 ccw(c190.031,177.657) 190.031,184.957 ccw(c190.031,177.657)
  pour cut-out: 287.787,4.826 ccw(c295.087,4.826) 295.087,-2.474 ccw(c295.087,4.826) 302.387,4.826 ccw(c295.087,4.826) 295.087,12.126 ccw(c295.087,4.826)
  pour cut-out: 58.787,99.826 ccw(c66.087,99.826) 66.087,92.526 ccw(c66.087,99.826) 73.387,99.826 ccw(c66.087,99.826) 66.087,107.126 ccw(c66.087,99.826)
  pour cut-out: -2.213,4.826 ccw(c5.087,4.826) 5.087,-2.474 ccw(c5.087,4.826) 12.387,4.826 ccw(c5.087,4.826) 5.087,12.126 ccw(c5.087,4.826)
  pour cut-out: 43.081,4.986 ccw(c50.381,4.986) 50.381,-2.314 ccw(c50.381,4.986) 57.681,4.986 ccw(c50.381,4.986) 50.381,12.286 ccw(c50.381,4.986)
  pour cut-out: 130.687,4.526 ccw(c137.987,4.526) 137.987,-2.774 ccw(c137.987,4.526) 145.287,4.526 ccw(c137.987,4.526) 137.987,11.826 ccw(c137.987,4.526)
  pour cut-out: 27.5,273.4 27.5,278 32.5,278 32.5,273.4
  pour cut-out: 188.1,99.1 185.7,99.1 183.7,97.1 183.7,87.5 186.1,85.1 188.1,85.1
  pour cut-out: 16.579,215.497 26.079,215.497 26.079,224.46 16.579,224.46
  pour cut-out: 16.579,183.497 26.079,183.497 26.079,192.46 16.579,192.46
  pour cut-out: 19.003,151.497 23.497,151.497 26,154 26,158 23.54,160.46 18.96,160.46 16.5,158 16.5,154
  pour cut-out: 16.579,117.434 26.079,117.434 26.079,126.397 16.579,126.397
  pour cut-out: 6.346,80.5 15.846,80.5 15.846,89.463 6.346,89.463
  text ".Layer_Name" at -20.344,-20.806 h1.52

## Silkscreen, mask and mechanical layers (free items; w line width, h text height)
Top Overlay:
  circle w0.254: c200,192.5 r0.5
  circle w0.254: c207.25,192.45 r0.5
  circle w0.254: c37.75,235.45 r0.5
  circle w0.254: c121.25,220.45 r0.5
  circle w0.254: c30.5,235.5 r0.5
  circle w0.254: c1,1 r0.5
  circle w0.254: c114,220.5 r0.5
  lines w0.254: 146.8,67.9 146.8,69.6 ; 153.5,68.05 153.5,69.75 ; 38.7,187.1 38.7,226.1 96.7,226.1 96.7,187.1 38.7,187.1 ; 122.2,172.1 122.2,211.1 180.2,211.1 180.2,172.1 122.2,172.1 ; 207.5,144 207.5,183 265.5,183 265.5,144 207.5,144
  text "L1" at 254.752,284.052 h3
  text "N" at 275.852,284.052 h3
  text "L3" at 214.452,283.952 h3
  text "L2" at 234.352,283.952 h3
  text "22 A, 480 VAC" at 222.2,246.2 h3
  text "L1" at 73.852,237.352 h3
  text "900 VDC, 24 A" at 33.7,237.2 h3
  text "GND" at 132.395,232.359 h0.76
  text "Danger High Temperature" at 121.235,222.737 h3
  text "L2" at 114.352,212.752 h3
  text "L3" at 201.252,188.852 h3
  text "TEMP_S4_PWM" at 89.779,143.848 h0.76 r270
  text "TEMP_S1_PWM" at 32.779,142.848 h0.76 r270
  text "GND_S2" at 51.779,140.848 h0.76 r270
  text "TEMP_S2_PWM" at 62.279,140.848 h0.76 r270
  text "GND_S3" at 74.279,140.348 h0.76 r270
  text "GND_S4" at 97.279,139.848 h0.76 r270
  text "GND_S1" at 46.779,139.348 h0.76 r270
  text "+10V" at 54.769,137.545 h0.76 r270
  text "+10V" at 38.652,136.848 h0.76 r270
  text "Danger High Voltage" at 276.3,136.7 h3 r90
  text "DC (-)" at 105.852,135.852 h0.76
  text "+10V" at 77.887,135.697 h0.76 r270
  text "TEMP_S4_PWM" at 173.279,128.848 h0.76 r270
  text "TEMP_S1_PWM" at 116.279,127.848 h0.76 r270
  text "+5V" at 47.152,126.848 h0.76 r270
  text "+5V" at 63.152,126.848 h0.76 r270
  text "+5V" at 84.652,126.348 h0.76 r270
  text "+5V" at 100.652,126.348 h0.76 r270
  text "GND_S2" at 135.279,125.848 h0.76 r270
  text "TEMP_S2_PWM" at 145.779,125.848 h0.76 r270
  text "DC (-)" at 190.952,125.852 h0.76
  text "GND_S3" at 157.779,125.348 h0.76 r270
  text "GND_S4" at 180.779,124.848 h0.76 r270
  text "GND_S1" at 130.279,124.348 h0.76 r270
  text "+10V" at 138.269,122.545 h0.76 r270
  text "+10V" at 122.152,121.848 h0.76 r270
  text "S3_PWM" at 86.317,121.01 h0.76 r270
  text "+10V" at 161.387,120.697 h0.76 r270
  text "S1_PWM" at 31.279,120.348 h0.76 r270
  text "L1" at 102.252,117.052 h3
  text "S2_PWM" at 48.817,113.01 h0.76 r270
  text "+5V" at 130.652,111.848 h0.76 r270
  text "+5V" at 146.652,111.848 h0.76 r270
  text "+5V" at 168.152,111.348 h0.76 r270
  text "+5V" at 184.152,111.348 h0.76 r270
  text "S4_PWM" at 86.817,109.51 h0.76 r270
  text "+5V" at 99.152,108.848 h0.76 r270
  text "S3_PWM" at 169.817,106.01 h0.76 r270
  text "S1_PWM" at 114.779,105.348 h0.76 r270
  text "GND" at 49.795,103.159 h0.76
  text "L2" at 185.652,102.952 h3
  text "N" at 17.852,102.052 h3
  text "TEMP_S4_PWM" at 259.279,100.848 h0.76 r270
  text "TEMP_S1_PWM" at 202.279,99.848 h0.76 r270
  text "S2_PWM" at 132.317,98.01 h0.76 r270
  text "GND_S2" at 221.279,97.848 h0.76 r270
  text "TEMP_S2_PWM" at 231.779,97.848 h0.76 r270
  text "GND_S3" at 243.779,97.348 h0.76 r270
  text "GND_S4" at 266.779,96.848 h0.76 r270
  text "GND_S1" at 216.279,96.348 h0.76 r270
  text "+10V" at 224.269,94.545 h0.76 r270
  text "S4_PWM" at 170.317,94.51 h0.76 r270
  text "+5V" at 182.652,93.848 h0.76 r270
  text "+10V" at 208.152,93.848 h0.76 r270
  text "+10V" at 247.387,92.697 h0.76 r270
  text "GND" at 133.295,91.159 h0.76
  text "DC (+)" at 66.752,90.552 h0.76
  text "+5V" at 216.652,83.848 h0.76 r270
  text "+5V" at 232.652,83.848 h0.76 r270
  text "+5V" at 254.152,83.348 h0.76 r270
  text "+5V" at 270.152,83.348 h0.76 r270
  text "S3_PWM" at 255.817,78.01 h0.76 r270
  text "-" at 9.652,77.767 h3
  text "+" at 51.752,77.652 h3
  text "S1_PWM" at 200.779,77.348 h0.76 r270
  text "DC (-)" at 98.052,75.952 h0.76
  text "N" at 116.773,73.724 h3
  text "'.PRJ_Number'-.PCB_Rev" at 138.7,72.8 h5
  text "+5V" at 110.152,71.152 h0.76
  text "+3V3" at 151.552,70.152 h0.76
  text "BUFF_EN" at 142.852,70.079 h0.76
  text "S2_PWM" at 218.317,70.01 h0.76 r270
  text "+5V" at 127.652,69.652 h0.76
  text "L3" at 276.552,69.252 h3
  text "GND_S4" at 96.652,67.779 h0.76
  text "VDC_-" at 60.652,67.279 h0.76
  text "S4_PWM" at 256.317,66.51 h0.76 r270
  text "+5V" at 269.152,64.652 h0.76
  text "+10V" at 100.955,63.769 h0.76
  text "TEMP_S4_PWM" at 92.652,60.279 h0.76
  text "EN_AUX_ISO_DCAC" at 265.28,59.692 h0.76
  text "S4_PWM" at 126.99,57.317 h0.76
  text "I_L3" at 275.152,57.279 h0.76
  text "S3_PWM" at 115.49,56.817 h0.76
  text "+5V" at 110.152,55.152 h0.76
  text "IL_N" at 260.652,54.279 h0.76
  text "+10V" at 100.803,48.387 h0.76
  text "GND_S3" at 96.152,44.779 h0.76
  text "GND" at 136.652,42.652 h0.76
  text "IL_1" at 265.152,42.279 h0.76
  text "V_FC_L1" at 144.652,41.279 h0.76
  text "V_L2" at 260.152,41.279 h0.76
  text "V_DC" at 174.652,40.279 h0.76
  text "V_FC_L2" at 138.652,37.779 h0.76
  text "I_L2" at 277.221,36.152 h0.76 r90
  text "V_L3" at 263.152,35.779 h0.76
  text "+5V" at 109.652,33.652 h0.76
  text "TEMP_S2_PWM" at 95.652,32.779 h0.76
  text "V_FC_N" at 166.152,32.779 h0.76
  text "V_L1" at 270.652,31.279 h0.76
  text "V_FC_L3" at 164.152,30.279 h0.76
  text "+10V" at 98.955,25.269 h0.76
  text "Buffer_Enable" at 235.152,23.279 h0.76
  text "GND_S2" at 95.652,22.279 h0.76
  text "GND" at 186.652,21.652 h0.76
  text "S2_PWM" at 123.49,19.317 h0.76
  text "+5V" at 109.652,17.652 h0.76
  text "GND_S1" at 97.152,17.279 h0.76
  text "GND" at 215.256,16.783 h0.76
  text "GND" at 232.174,9.807 h0.76
  text "+10V" at 99.652,9.152 h0.76
  text "FAN_SW" at 219.952,8.979 h0.76
  text "+12V" at 216.186,8.832 h0.76
  text "VDC_+" at 69.652,3.279 h0.76
  text "TEMP_S1_PWM" at 93.652,3.279 h0.76
  text "S1_PWM" at 116.152,1.779 h0.76
  text "+12V" at 177.052,1.352 h0.76
  text ".Layer_Name" at -20.344,-20.806 h1.52
Bottom Overlay:
  text ".Layer_Name" at -20.344,-20.806 h1.52
Top Paste:
  text ".Layer_Name" at 169.75,-14.25 h1.52
Bottom Paste:
  text ".Layer_Name" at -20.344,-20.806 h1.52
Top Solder:
  region: 35,296 ccw(c39,296) 39,292 ccw(c39,296) 43,296 ccw(c39,296) 39,300 ccw(c39,296)
  region: 278,296 ccw(c282,296) 282,292 ccw(c282,296) 286,296 ccw(c282,296) 282,300 ccw(c282,296)
  region: 187,93 ccw(c191,93) 191,89 ccw(c191,93) 195,93 ccw(c191,93) 191,97 ccw(c191,93)
  text ".Layer_Name" at 169.75,-14.25 h1.52
  text ".Layer_Name" at 169.75,-14.25 h1.52
Bottom Solder:
  text ".Layer_Name" at -20.344,-20.806 h1.52
Drill Guide:
  text ".Layer_Name" at 169.75,-14.25 h1.52
M1 Board Outline:
  lines w1: 0,0 0,300 300,300 300,0 0,0 ; 105,77 115,77 115,87 105,87 105,77
  text ".Layer_Name" at -20.344,-20.806 h1.52
M2 Board Dimensions:
  rectangle: -31.825,-9.16 -22.3,-5.985
  rectangle: -35,-5.985 -31.825,-2.81
  lines w0.178: -35,-5.985 -9.6,-5.985 ; -31.825,-9.16 -31.825,-2.81 ; -28.65,-9.16 -28.65,-2.81 ; -22.3,-9.16 -22.3,-2.81 ; -15.95,-9.16 -15.95,-2.81 ; -35,-9.16 -35,-2.81 -9.6,-2.81 -9.6,-9.16 -35,-9.16
  text ".Layer_Name" at -20.344,-20.806 h1.52
M3 3D STEP Top:
  text ".Layer_Name" at -20.344,-20.806 h1.52
M4 3D STEP Bottom:
  text ".Layer_Name" at -20.344,-20.806 h1.52
M5 Assembly Top:
  lines w0.254: -42.417,-22.626 125.223,-22.626 ; -42.417,-17.462 125.274,-17.462 ; -42.417,-12.297 -42.417,-27.791 59.31,-27.791 125.274,-27.791 125.274,-12.297 -42.404,-12.297 -42.404,-27.791 -2.386,-27.791 ; 20.194,-27.791 20.194,-12.297 ; 52.376,-17.462 52.376,-12.297 ; 73.712,-17.462 73.712,-12.297 ; 89.511,-27.956 89.511,-22.804
  text "PLOT NAME =" at 504.785,211.707 h1.52 r180
  text "COMPONENTS MARKED 'DNP' SHOULD NOT BE POPULATED." at -5.701,-7.09 h1.52
  text "ASSEMBLY VARIANT:" at -5.714,-10.024 h1.52
  text ".VariantName" at 20.601,-10.024 h1.52
  text "PCB VIEWED FROM TOP SIDE" at -40.804,-15.654 h1.52
  text "BOARD #:" at 22.099,-15.654 h1.52
  text ".PRJ_Number" at 35.955,-15.654 h1.52
  text "REV:" at 57.405,-15.654 h1.52
  text ".PCB_Rev" at 64.809,-15.654 h1.52
  text "SVN REV:" at 78.69,-15.654 h1.52
  text ".VersionControl_RevNumber" at 91.543,-15.654 h1.52
  text ".plot_File_Name" at -20.344,-26.034 h1.52
  text "GENERATED    :" at 22.15,-26.034 h1.52
  text ".Print_Date" at 44.235,-26.034 h1.52
  text ".Print_Time" at 62.752,-26.034 h1.52
  text "TEXAS INSTRUMENTS" at 94.87,-26.034 h1.52
M6 Assembly Bottom:
  lines w0.254: -42.43,-17.474 125.261,-17.474 ; -42.379,-22.639 125.261,-22.639 ; 9.132,-17.474 9.132,-12.31 ; 30.468,-17.474 30.468,-12.31 ; 62.65,-27.804 62.65,-12.31 ; 85.231,-27.804 125.249,-27.804 125.249,-12.31 -42.43,-12.31 -42.43,-27.804 23.534,-27.804 125.261,-27.804 125.261,-12.31 ; 470.647,208.49 470.647,213.642
  text "TEXAS INSTRUMENTS" at 476.007,211.72 h1.52 r180
  text "COMPONENTS MARKED 'DNP' SHOULD NOT BE POPULATED." at 119.991,-7.077 h1.52
  text ".VariantName" at 93.473,-10.024 h1.52
  text "ASSEMBLY VARIANT:" at 119.864,-10.024 h1.52
  text ".VersionControl_RevNumber" at -8.698,-15.667 h1.52
  text "SVN REV:" at 4.154,-15.667 h1.52
  text ".PCB_Rev" at 18.035,-15.667 h1.52
  text "REV:" at 25.439,-15.667 h1.52
  text ".PRJ_Number" at 46.89,-15.667 h1.52
  text "BOARD #:" at 60.745,-15.667 h1.52
  text "PCB VIEWED FROM BOTTOM SIDE" at 123.648,-15.667 h1.52
  text ".Print_Time" at 20.093,-26.047 h1.52
  text ".Print_Date" at 38.609,-26.047 h1.52
  text "GENERATED    :" at 60.694,-26.047 h1.52
  text ".plot_File_Name" at 103.189,-26.047 h1.52
  text "PLOT NAME =" at 123.648,-26.047 h1.52
M9 Title Sheet:
  drawing of 63 lines, arcs and shapes, not listed
  text "1" at 0.293,467.75 h1.78
  text "2" at 101.766,467.75 h1.78
  text "3" at 203.239,467.75 h1.78
  text "4" at 304.865,467.75 h1.78
  text "5" at 406.423,467.75 h1.78
  text "6" at 507.98,467.75 h1.78
  text "7" at 609.623,467.75 h1.78
  text "8" at 711.096,467.75 h1.78
  text "A" at -46.875,406.841 h1.78
  text "A" at 758.305,406.841 h1.78
  text "B" at -46.875,279.841 h1.78
  text "B" at 758.305,279.841 h1.78
  text "C" at -46.875,152.841 h1.78
  text "C" at 758.305,152.841 h1.78
  text "D" at -46.875,25.841 h1.78
  text "D" at 758.305,25.841 h1.78
  text "PROJECT TITLE:" at 679.946,7.823 h1.14
  text ".PRJ_Title" at 681.216,4.436 h1.78
  text "DESIGNED FOR:" at 679.946,0.177 h1.14
  text ".PRJ_Customer" at 681.216,-3.379 h1.78
  text "FILE NAME:" at 679.946,-7.443 h1.14
  text ".PCB_File_Name_No_Path" at 681.216,-10.491 h1.78
  text "Texas Instruments (TI) and/or its licensors do not warrant the accuracy or completeness of this specification" at 553.721,-14.601 h1.14
  text "ENGINEER:" at 679.946,-14.809 h1.14
  text "LAYOUT BY:" at 718.173,-14.809 h1.14
  text "or any information contained therein. TI and/or its licensors do not warrant that this design will meet" at 552.579,-17.463 h1.14
  text ".PRJ_Engineer" at 681.216,-18.746 h1.78
  text ".PCB_Layout" at 719.456,-18.746 h1.78
  text "the specifications, will be suitable for your application or fit for any particular purpose, or will operate in" at 552.579,-20.325 h1.14
  text ".Layer_Name" at -20.344,-20.806 h1.52
  text "ALTIUM DESIGNER VERSION:" at 718.173,-22.683 h1.14
  text "an implementation. TI and/or its licensors do not warrant that the design is production worthy. You should" at 552.579,-23.187 h1.14
  text "completely validate and test your design implementation to confirm the system functionality for your application." at 553.721,-26.048 h1.14
  text ".print_Scale" at 681.216,-26.069 h1.78
  text ".Application_BuildNumber" at 719.456,-26.069 h1.78
  text "1" at 0.293,-32.503 h1.78
  text "2" at 101.766,-32.503 h1.78
  text "3" at 203.239,-32.503 h1.78
  text "4" at 304.865,-32.503 h1.78
  text "5" at 406.423,-32.503 h1.78
  text "6" at 507.98,-32.503 h1.78
  text "7" at 609.623,-32.503 h1.78
  text "8" at 711.096,-32.503 h1.78
M10 Fab Notes:
  drawing of 189 lines, arcs and shapes, not listed
  text "DESIGN INFORMATION" at 706.376,162.675 h1.52
  text "MIN. TRACK WIDTH:" at 690.004,159.319 h1.52
  text "8" at 717.848,159.32 h1.52
  text "MIL" at 721.779,159.319 h1.52
  text "MIN. CLEARANCE:" at 690.004,156.167 h1.52
  text "7.874" at 713.5,156.167 h1.52
  text "MIL" at 721.779,156.167 h1.52
  text "MIN. VIA PAD SIZE:" at 690.004,153.014 h1.52
  text "24" at 717.087,153.014 h1.52
  text "MIL" at 721.779,153.014 h1.52
  text "0.05mm (2MIL)" at 707.657,149.714 h1.52
  text "MINIMUM ANNULAR RING" at 681.641,149.506 h1.52
  text "EXTERNAL" at 725.64,149.506 h1.52
  text "PER" at 686.721,146.708 h1.52
  text "IPC-D-275 CLASS 2 LEVEL C" at 692.309,146.708 h1.52
  text "MIL, HOLES" at 730.11,144.156 h1.52
  text "+/-" at 720.142,143.938 h1.52
  text "+/-" at 741.834,143.938 h1.52
  text "REGISTRATION TOLERANCES:" at 681.641,143.911 h1.52
  text "METAL" at 712.116,143.911 h1.52
  text "5" at 726.751,143.911 h1.52
  text "3" at 747.909,143.911 h1.52
  text "MIL" at 750.862,143.911 h1.52
  text "HOLE SIZE TOLERANCE (UNLESS OTHERWISE SPECIFIED):" at 681.641,141.414 h1.52
  text "+/-" at 741.834,141.341 h1.52
  text "3" at 747.909,141.314 h1.52
  text "MIL" at 750.862,141.314 h1.52
  text "MATERIAL:" at 679.742,137.818 h1.52
  text "FR-4 High Tg" at 704.798,134.553 h1.52
  text "X" at 701.129,134.35 h1.52
  text "FR-4" at 690.436,134.235 h1.52
  text "OTHER" at 728.231,134.235 h1.52
  text "62 MIL (1.6mm) +/-10%" at 698.566,130.602 h1.52
  text "X" at 728.1,130.6 h1.52
  text "2mm" at 742.287,130.414 h1.52
  text "THICKNESS:" at 681.641,130.394 h1.52
  text "OTHER" at 731.203,130.394 h1.52
  text "TOLERANCE:" at 681.641,126.88 h1.52
  text "X" at 703.187,126.88 h1.52
  text "ANSI IPC-6012 TYPE 3 CLASS 2" at 707.708,126.88 h1.52
  text "OTHER +/-" at 707.708,123.218 h1.52
  text "BOW & TWIST:" at 681.641,119.53 h1.52
  text "X" at 703.187,119.53 h1.52
  text "ANSI IPC-6012 TYPE 3 CLASS 2" at 707.708,119.53 h1.52
  text "OTHER +/-" at 707.708,115.804 h1.52
  text "DRILLING:" at 679.742,112.486 h1.52
  text "NC_DRILL FILES" at 724.472,109.815 h1.52
  text "REFERENCE:" at 681.641,109.715 h1.52
  text "X" at 698.335,109.712 h1.52
  text "AS SHOWN" at 702.856,109.715 h1.52
  text "X" at 721.221,109.715 h1.52
  text "OTHER" at 732.041,106.101 h1.52
  text "PTH COPPER THICKNESS:" at 681.633,106.012 h1.52
  text "X" at 710.57,106.012 h1.52
  text "20-30 um" at 713.821,106.012 h1.52
  text "BOARD FINISH:" at 679.742,102.263 h1.52
  text "SILKSCREEN:" at 683.685,99.466 h1.52
  text "X" at 708.013,99.466 h1.52
  text "TOP" at 710.984,99.466 h1.52
  text "X" at 720.967,99.466 h1.52
  text "BOTTOM" at 723.964,99.466 h1.52
  text "SILKSCREEN COLOR:" at 683.685,95.524 h1.52
  text "X" at 707.987,95.524 h1.52
  text "WHITE" at 710.984,95.524 h1.52
  text "OTHER" at 723.964,95.524 h1.52
  text "X" at 711.315,91.88 h1.52
  text "GREEN" at 714.312,91.88 h1.52
  text "OTHER" at 730.009,91.88 h1.52
  text "SOLDER RESIST COLOR:" at 683.685,91.706 h1.52
  text "X" at 711.315,87.962 h1.52
  text "MATTE" at 714.312,87.962 h1.52
  text "SEMI-GLOSS" at 729.997,87.946 h1.52
  text "IMMERSION GOLD (ENIG)" at 706.692,83.574 h1.52
  text "ENEPIG" at 740.665,83.39 h1.52
  text "SURFACE FINISH:" at 679.742,83.365 h1.52
  text "X" at 702.171,83.365 h1.52
  text "IMM. TIN/SILVER OR EQUIV" at 688.113,79.877 h1.52
  text "OTHER" at 724.472,79.777 h1.52
  text "ARRAY/PANEL:" at 679.742,75.831 h1.52
  text "CUT AND TRIM PER M1 BOARD OUTLINE" at 706.692,75.622 h1.52
  text "N.C. ROUTE" at 706.692,72.168 h1.52
  text "X" at 724.167,72.168 h1.52
  text "V. SCORE" at 728.688,72.168 h1.52
  text "CERTIFICATION:" at 679.742,68.888 h1.52
  text "MATERIALS AND WORKMANSHIP FOR ALL PCBS" at 698.157,68.888 h1.52
  text "TO MEET OR EXCEED THE REQUIREMENTS OF:" at 698.157,66.499 h1.52
  text "X" at 688.95,63.232 h1.52
  text "ANSI IPC-A-600F CLASS ->" at 692.201,63.232 h1.52
  text "X" at 734.06,63.232 h1.52
  text "2" at 736.854,63.232 h1.52
  text "1" at 728.853,63.194 h1.52
  text "3" at 745.846,63.194 h1.52
  text "X" at 709.575,59.481 h1.52
  text "RoHS" at 712.826,59.481 h1.52
  text "OTHER" at 729.194,59.481 h1.52
  text "PER ORDER" at 739.279,59.481 h1.52
  text "ALL BOARDS MUST MEET OR EXCEED UL94-V0 REQUIREMENTS." at 680.442,55.574 h1.52
  text "PCB MUST BEAR THE UL94V-0 UL REGISTERED MATERIAL ID NUMBER" at 680.442,52.626 h1.52
  text "ADDITIONAL REQUIREMENTS:" at 679.742,48.322 h1.52
  text "MICROSECTION:" at 681.641,45.601 h1.52
  text "YES" at 704.647,45.601 h1.52
  text "REQUIRED" at 726.529,41.935 h1.52
  text "BARE BOARD ELEC. TEST:" at 681.641,41.863 h1.52
  text "NONE" at 714.807,41.863 h1.52
  text "X" at 723.532,41.863 h1.52
  text "PER ORDER" at 741.566,41.863 h1.52
  text "XX MIL VIAS REQUIRE NON-CONDUCTIVE FILL AND PLANARIZE" at 685.912,36.657 h1.5
  text "XX MIL VIAS REQUIRE CONDUCTIVE FILL AND PLANARIZE" at 686.116,34.016 h1.52
  text "OUTER XX MIL TRACES REQUIRE 50 OHM SINGLE-ENDED IMPEDANCE" at 686.091,29.866 h1.47
  text "LAYER 2 & 3 (INNER LAYERS) XX MIL WIDE, XX MIL SPACE / TRACES REQUIRE 100 OHM DIFFERENTIAL IMPEDANCE" at 685.887,23.879 h1.52
  text ".Layer_Name" at -20.344,-20.806 h1.52
M11 Gerber Information:
  lines w0.254: -42.417,-22.626 125.223,-22.626 ; -42.417,-17.462 125.274,-17.462 ; -42.417,-12.297 -42.417,-27.791 59.31,-27.791 125.274,-27.791 125.274,-12.297 -42.404,-12.297 -42.404,-27.791 -2.386,-27.791 ; 20.194,-27.791 20.194,-12.297 ; 52.376,-17.462 52.376,-12.297 ; 73.712,-17.462 73.712,-12.297 ; 89.511,-27.956 89.511,-22.804
  text "LAYER NAME =" at 149.29,-14.25 h1.52
  text "ALL ARTWORK VIEWED FROM TOP SIDE" at -40.804,-15.654 h1.52
  text "BOARD #:" at 22.099,-15.654 h1.52
  text ".PRJ_Number" at 35.955,-15.654 h1.52
  text "REV:" at 57.405,-15.654 h1.52
  text ".PCB_Rev" at 64.809,-15.654 h1.52
  text "SVN REV:" at 78.69,-15.654 h1.52
  text ".VersionControl_RevNumber" at 91.543,-15.654 h1.52
  text "PLOT NAME =" at 149.29,-19.478 h1.52
  text ".plot_File_Name" at -20.344,-26.034 h1.52
  text "GENERATED    :" at 22.15,-26.034 h1.52
  text ".Print_Date" at 44.235,-26.034 h1.52
  text ".Print_Time" at 62.752,-26.034 h1.52
  text "TEXAS INSTRUMENTS" at 94.87,-26.034 h1.52
M12 Stackup:
  drawing of 295 lines, arcs and shapes, not listed
  text "Layer" at 639.469,458.524 h1.52
  text "Name" at 649.88,458.524 h1.52
  text "Material" at 673.496,458.524 h1.52
  text "Thickness" at 695.334,458.524 h1.52
  text "Constant" at 711.84,458.524 h1.52
  text "Board Layer Stack" at 726.314,458.524 h1.52
  text "Top Overlay" at 649.88,455.476 h1.52
  text "Top Solder" at 649.88,452.428 h1.52
  text "Solder Resist" at 673.496,452.428 h1.52
  text "0,40mil" at 695.334,452.428 h1.52
  text "3.5" at 711.84,452.428 h1.52
  text "1" at 639.469,449.38 h1.52
  text "Top Layer" at 649.88,449.38 h1.52
  text "1,40mil" at 695.334,449.38 h1.52
  text "Dielectric 1" at 649.88,446.332 h1.52
  text "PP-006" at 673.496,446.332 h1.52
  text "2,80mil" at 695.334,446.332 h1.52
  text "4.1" at 711.84,446.332 h1.52
  text "2" at 639.469,443.284 h1.52
  text "Layer 1" at 649.88,443.284 h1.52
  text "CF-004" at 673.496,443.284 h1.52
  text "1,38mil" at 695.334,443.284 h1.52
  text "Dielectric1" at 649.88,440.236 h1.52
  text "FR-4 High Tg" at 673.496,440.236 h1.52
  text "59,20mil" at 695.334,440.236 h1.52
  text "4.8" at 711.84,440.236 h1.52
  text "3" at 639.469,437.188 h1.52
  text "Layer 2" at 649.88,437.188 h1.52
  text "CF-004" at 673.496,437.188 h1.52
  text "1,38mil" at 695.334,437.188 h1.52
  text "Dielectric 2" at 649.88,434.14 h1.52
  text "PP-006" at 673.496,434.14 h1.52
  text "2,80mil" at 695.334,434.14 h1.52
  text "4.1" at 711.84,434.14 h1.52
  text "4" at 639.469,431.092 h1.52
  text "Bottom Layer" at 649.88,431.092 h1.52
  text "1,40mil" at 695.334,431.092 h1.52
  text "Bottom Solder" at 649.88,428.044 h1.52
  text "Solder Resist" at 673.496,428.044 h1.52
  text "0,40mil" at 695.334,428.044 h1.52
  text "3.5" at 711.84,428.044 h1.52
  text "Bottom Overlay" at 649.88,424.996 h1.52
  text ".Layer_Name" at 169.75,-14.25 h1.52
M13 Component Bodies Top:
  text ".Layer_Name" at -20.344,-20.806 h1.52
M14 Component Bodies Bottom:
  text ".Layer_Name" at -20.344,-20.806 h1.52
M15 Courtyards Top:
  text ".Layer_Name" at -20.344,-20.806 h1.52
M16 Courtyards Bottom:
  text ".Layer_Name" at -20.344,-20.806 h1.52
Drill Drawing:
  text ".Layer_Name" at -20.344,-20.806 h1.52
M17 Embedded Cavity:
  text ".Layer_Name" at -20.344,-20.806 h1.52
M18 Embedded Assembly:
  text ".Layer_Name" at -20.344,-20.806 h1.52
M19 Embedded Keepout:
  text ".Layer_Name" at -20.09,-20.552 h1.52
Mechanical Drilling Heatsink:
  circle w0.25: c110,125 r1.414
  circle w0.25: c79,222 r1.414
  circle w0.25: c79.025,222 r0.025
  circle w0.25: c276.975,80 r0.025
  circle w0.25: c277,80 r1.414
  circle w0.25: c38.975,296 r0.025
  circle w0.25: c281.975,296 r0.025
  circle w0.25: c192.975,296 r0.025
  circle w0.25: c294.975,155 r0.025
  circle w0.25: c184,216 r0.025
  circle w0.25: c189.975,178 r0.025
  circle w0.25: c105.475,192.5 r0.025
  circle w0.25: c190.975,93 r0.025
  circle w0.25: c4.975,139 r0.025
  circle w0.25: c65.975,100 r0.025
  circle w0.25: c294.975,5 r0.025
  circle w0.25: c137.975,5 r0.025
  circle w0.25: c49.975,5 r0.025
  circle w0.25: c4.975,5 r0.025
  circle w0.25: c191,93 r1.414
  circle w0.25: c105.5,192.5 r1.414
  circle w0.25: c190,178 r1.414
  circle w0.25: c184,216 r1.414
  circle w0.25: c282,296 r1.414
  circle w0.25: c193,296 r1.414
  circle w0.25: c39,296 r1.414
  circle w0.25: c5,139 r1.414
  circle w0.25: c66,100 r1.414
  circle w0.25: c295,155 r1.414
  circle w0.25: c295,5 r1.414
  circle w0.25: c138,5 r1.414
  circle w0.25: c50,5 r1.414
  circle w0.25: c5,5 r1.414
  lines w0.254: 0,0 304.5,0 304.5,324.5 0,324.5 0,0
Mechanical Isolation Sheet:
  circle w0.254: c0,0 r1.118
  lines w0.254: 47,168 47,180.5 60,180.5 60,168 47,168 ; 51.55,147.9 51.55,160.4 64.55,160.4 64.55,147.9 51.55,147.9 ; 56,17.5 68.5,17.5 68.5,30.5 56,30.5 56,17.5 ; 56.125,42.775 68.625,42.775 68.625,55.775 56.125,55.775 56.125,42.775 ; 67.775,147.875 67.775,160.375 80.775,160.375 80.775,147.875 67.775,147.875 ; 72.275,167.875 72.275,180.375 85.275,180.375 85.275,167.875 72.275,167.875 ; 76.1,22.05 88.6,22.05 88.6,35.05 76.1,35.05 76.1,22.05 ; 76.125,38.275 88.625,38.275 88.625,51.275 76.125,51.275 76.125,38.275 ; 130.5,153 130.5,165.5 143.5,165.5 143.5,153 130.5,153 ; 135.05,132.9 135.05,145.4 148.05,145.4 148.05,132.9 135.05,132.9 ; 151.275,132.875 151.275,145.375 164.275,145.375 164.275,132.875 151.275,132.875 ; 155.775,152.875 155.775,165.375 168.775,165.375 168.775,152.875 155.775,152.875 ; 216.5,125 216.5,137.5 229.5,137.5 229.5,125 216.5,125 ; 221.05,104.9 221.05,117.4 234.05,117.4 234.05,104.9 221.05,104.9 ; 237.275,104.875 237.275,117.375 250.275,117.375 250.275,104.875 237.275,104.875 ; 241.775,124.875 241.775,137.375 254.775,137.375 254.775,124.875 241.775,124.875

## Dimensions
0,0 to 110,125.5 on M16 Courtyards Bottom
0,0 to 110.5,125 on M16 Courtyards Bottom
281.957,295.982 to 304.5,0 on M16 Courtyards Bottom
192.957,296.018 to 304.5,0 on M16 Courtyards Bottom
38.957,296.018 to 0,0 on M16 Courtyards Bottom
183.982,216.018 to 304.5,0 on M16 Courtyards Bottom
294.957,154.982 to 304.5,0 on M16 Courtyards Bottom
189.949,178 to 304.5,0 on M16 Courtyards Bottom
105.5,192.5 to 0,0 on M16 Courtyards Bottom
5,139 to 0,0 on M16 Courtyards Bottom
79,222 to 0,0 on M16 Courtyards Bottom
65.993,99.982 to 0,0 on M16 Courtyards Bottom
190.975,92.975 to 304.5,0 on M16 Courtyards Bottom
276.957,79.982 to 304.5,0 on M16 Courtyards Bottom
294.949,5 to 304.5,0 on M16 Courtyards Bottom
137.949,5 to 0,0 on M16 Courtyards Bottom
48.586,5 to 0,0 on M16 Courtyards Bottom
4.993,5.018 to 0,0 on M16 Courtyards Bottom
281.957,295.982 to 0,324.5 on M16 Courtyards Bottom
0,324.5 to 193,296 on M16 Courtyards Bottom
38.975,295.975 to 0,324.5 on M16 Courtyards Bottom
184.018,216.018 to 0,324.5 on M16 Courtyards Bottom
105.449,192.5 to 0,324.5 on M16 Courtyards Bottom
189.949,178 to 0,324.5 on M16 Courtyards Bottom
294.949,155 to 0,0 on M16 Courtyards Bottom
79,222 to 0,0 on M16 Courtyards Bottom
4.993,139.018 to 0,0 on M16 Courtyards Bottom
276.949,80 to 0,0 on M16 Courtyards Bottom
0,0 to 190.957,92.982 on M16 Courtyards Bottom
0,0 to 65.949,100 on M16 Courtyards Bottom
295,5 to 0,0 on M16 Courtyards Bottom
138,5 to 0,0 on M16 Courtyards Bottom
0,0 to 50,5 on M16 Courtyards Bottom
5,5 to 0,0 on M16 Courtyards Bottom
304.5,324.5 to 304.5,0 on M16 Courtyards Bottom
0,324.5 to 304.5,324.5 on M16 Courtyards Bottom
-35,-9.16 to -9.6,-9.16 on M2 Board Dimensions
